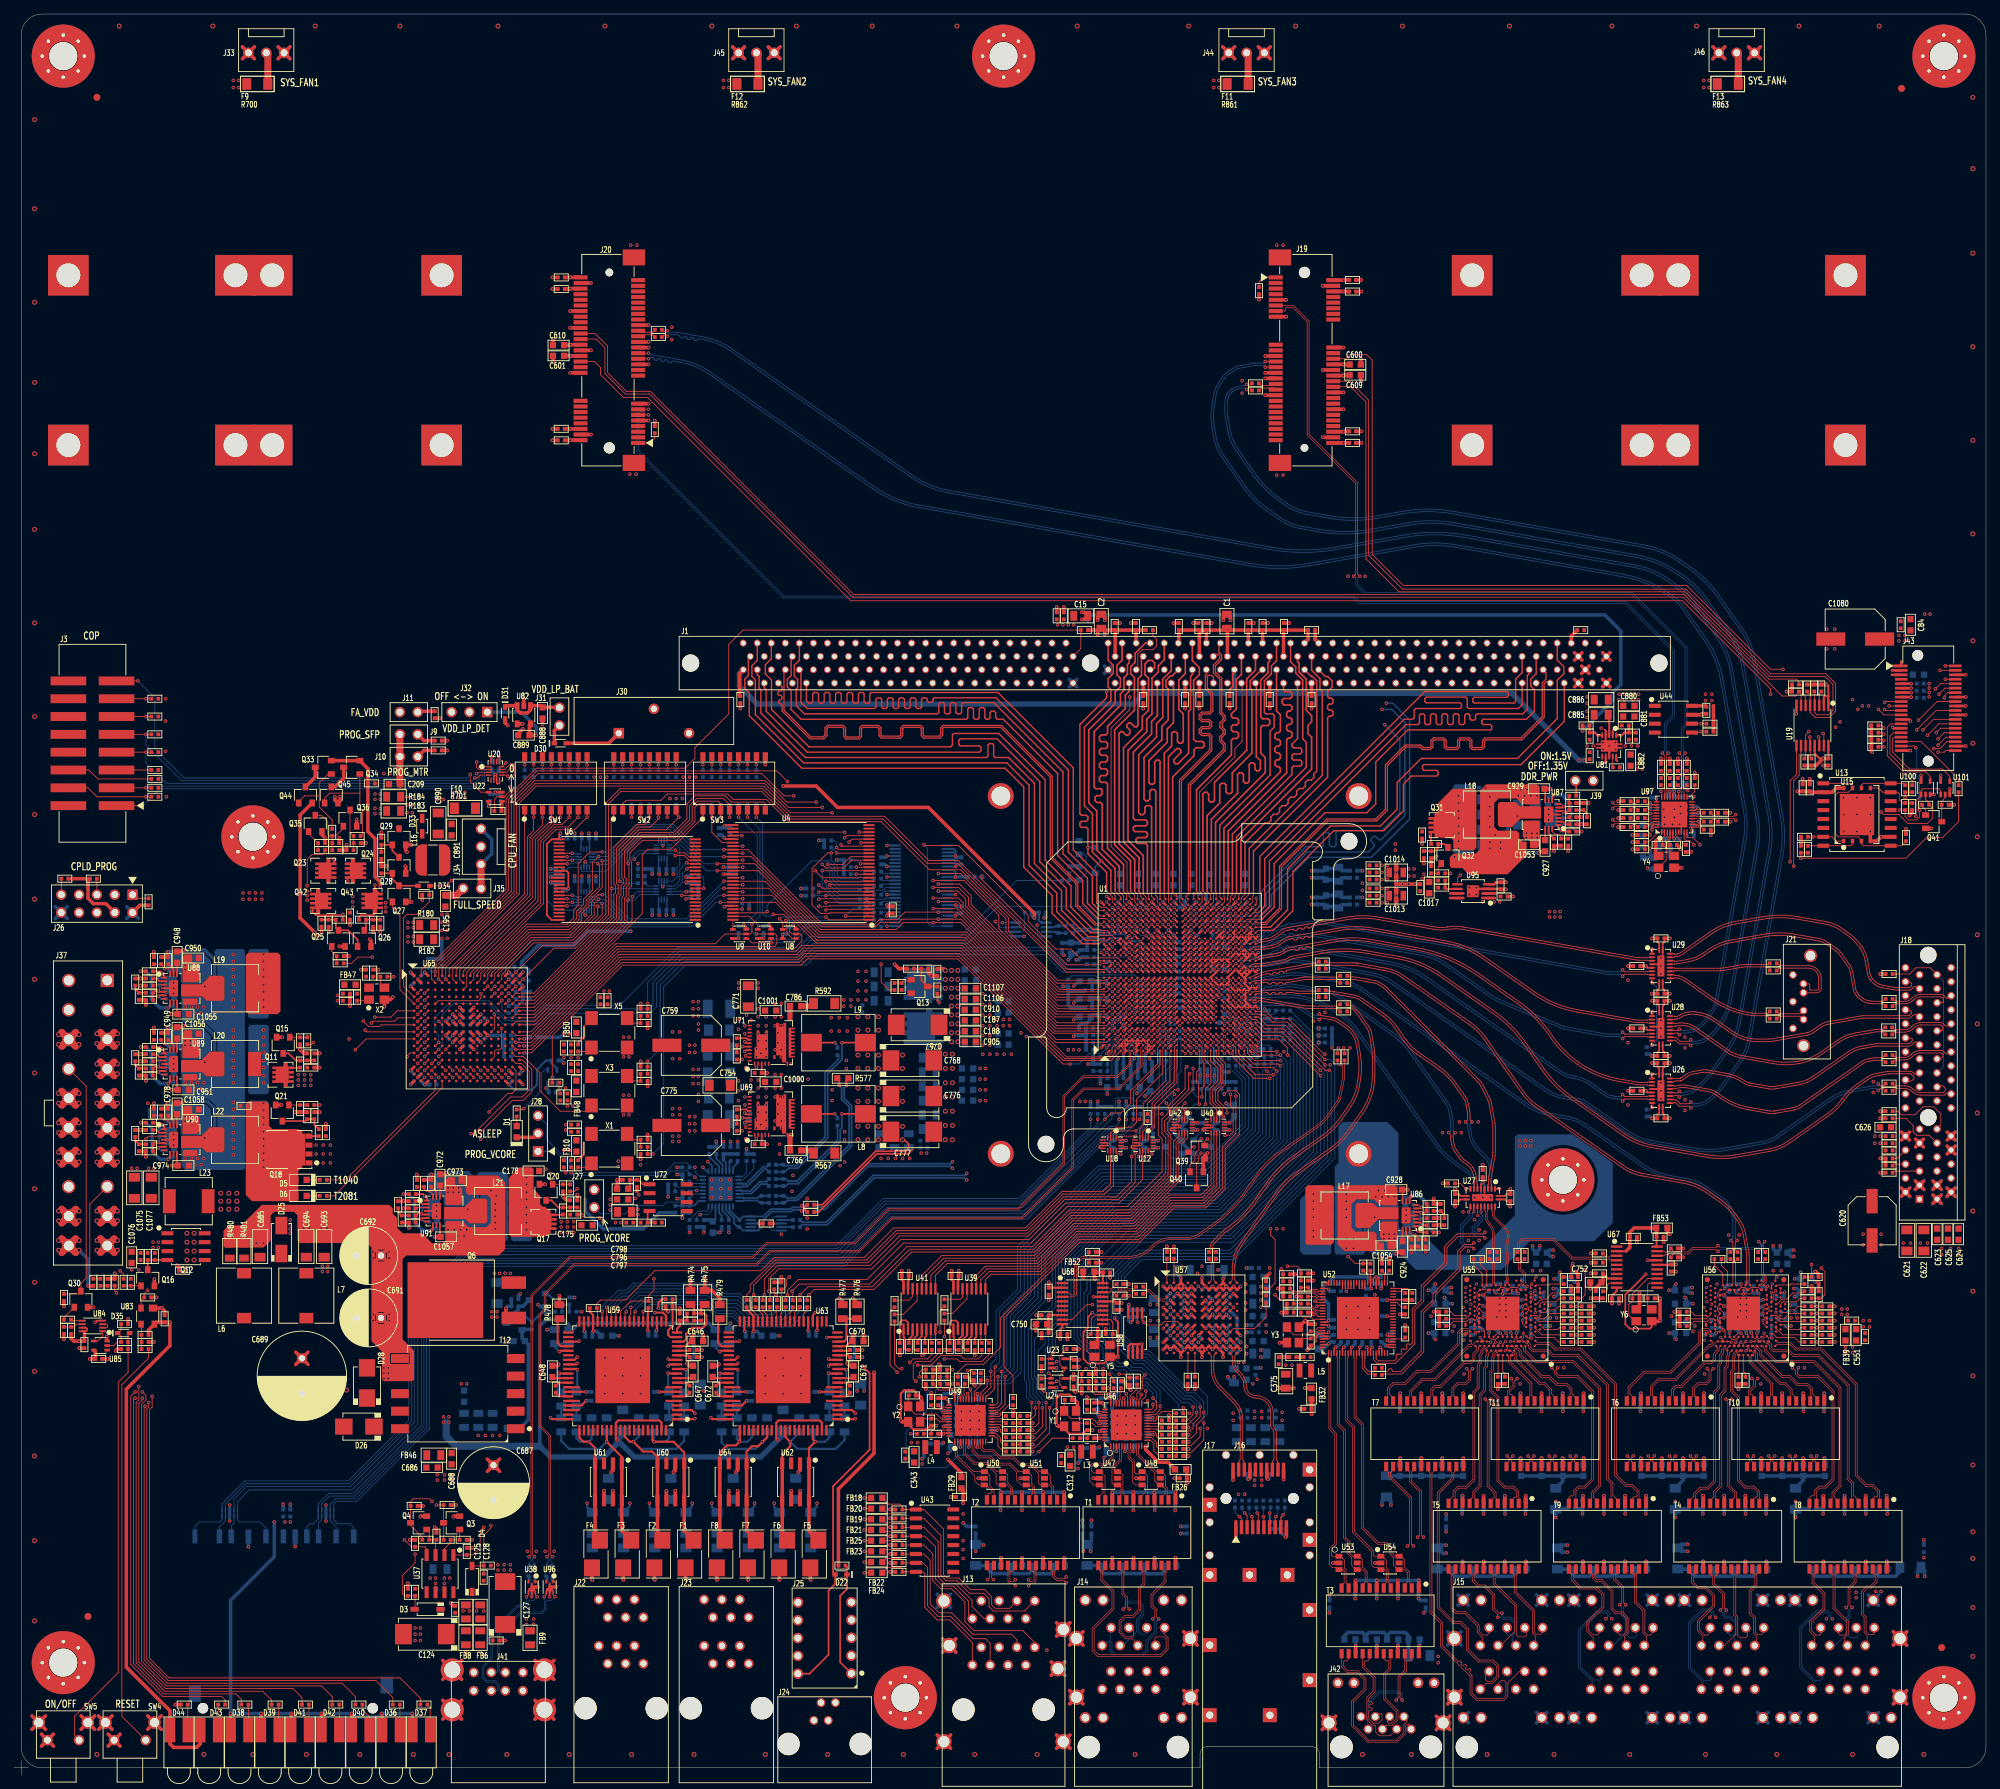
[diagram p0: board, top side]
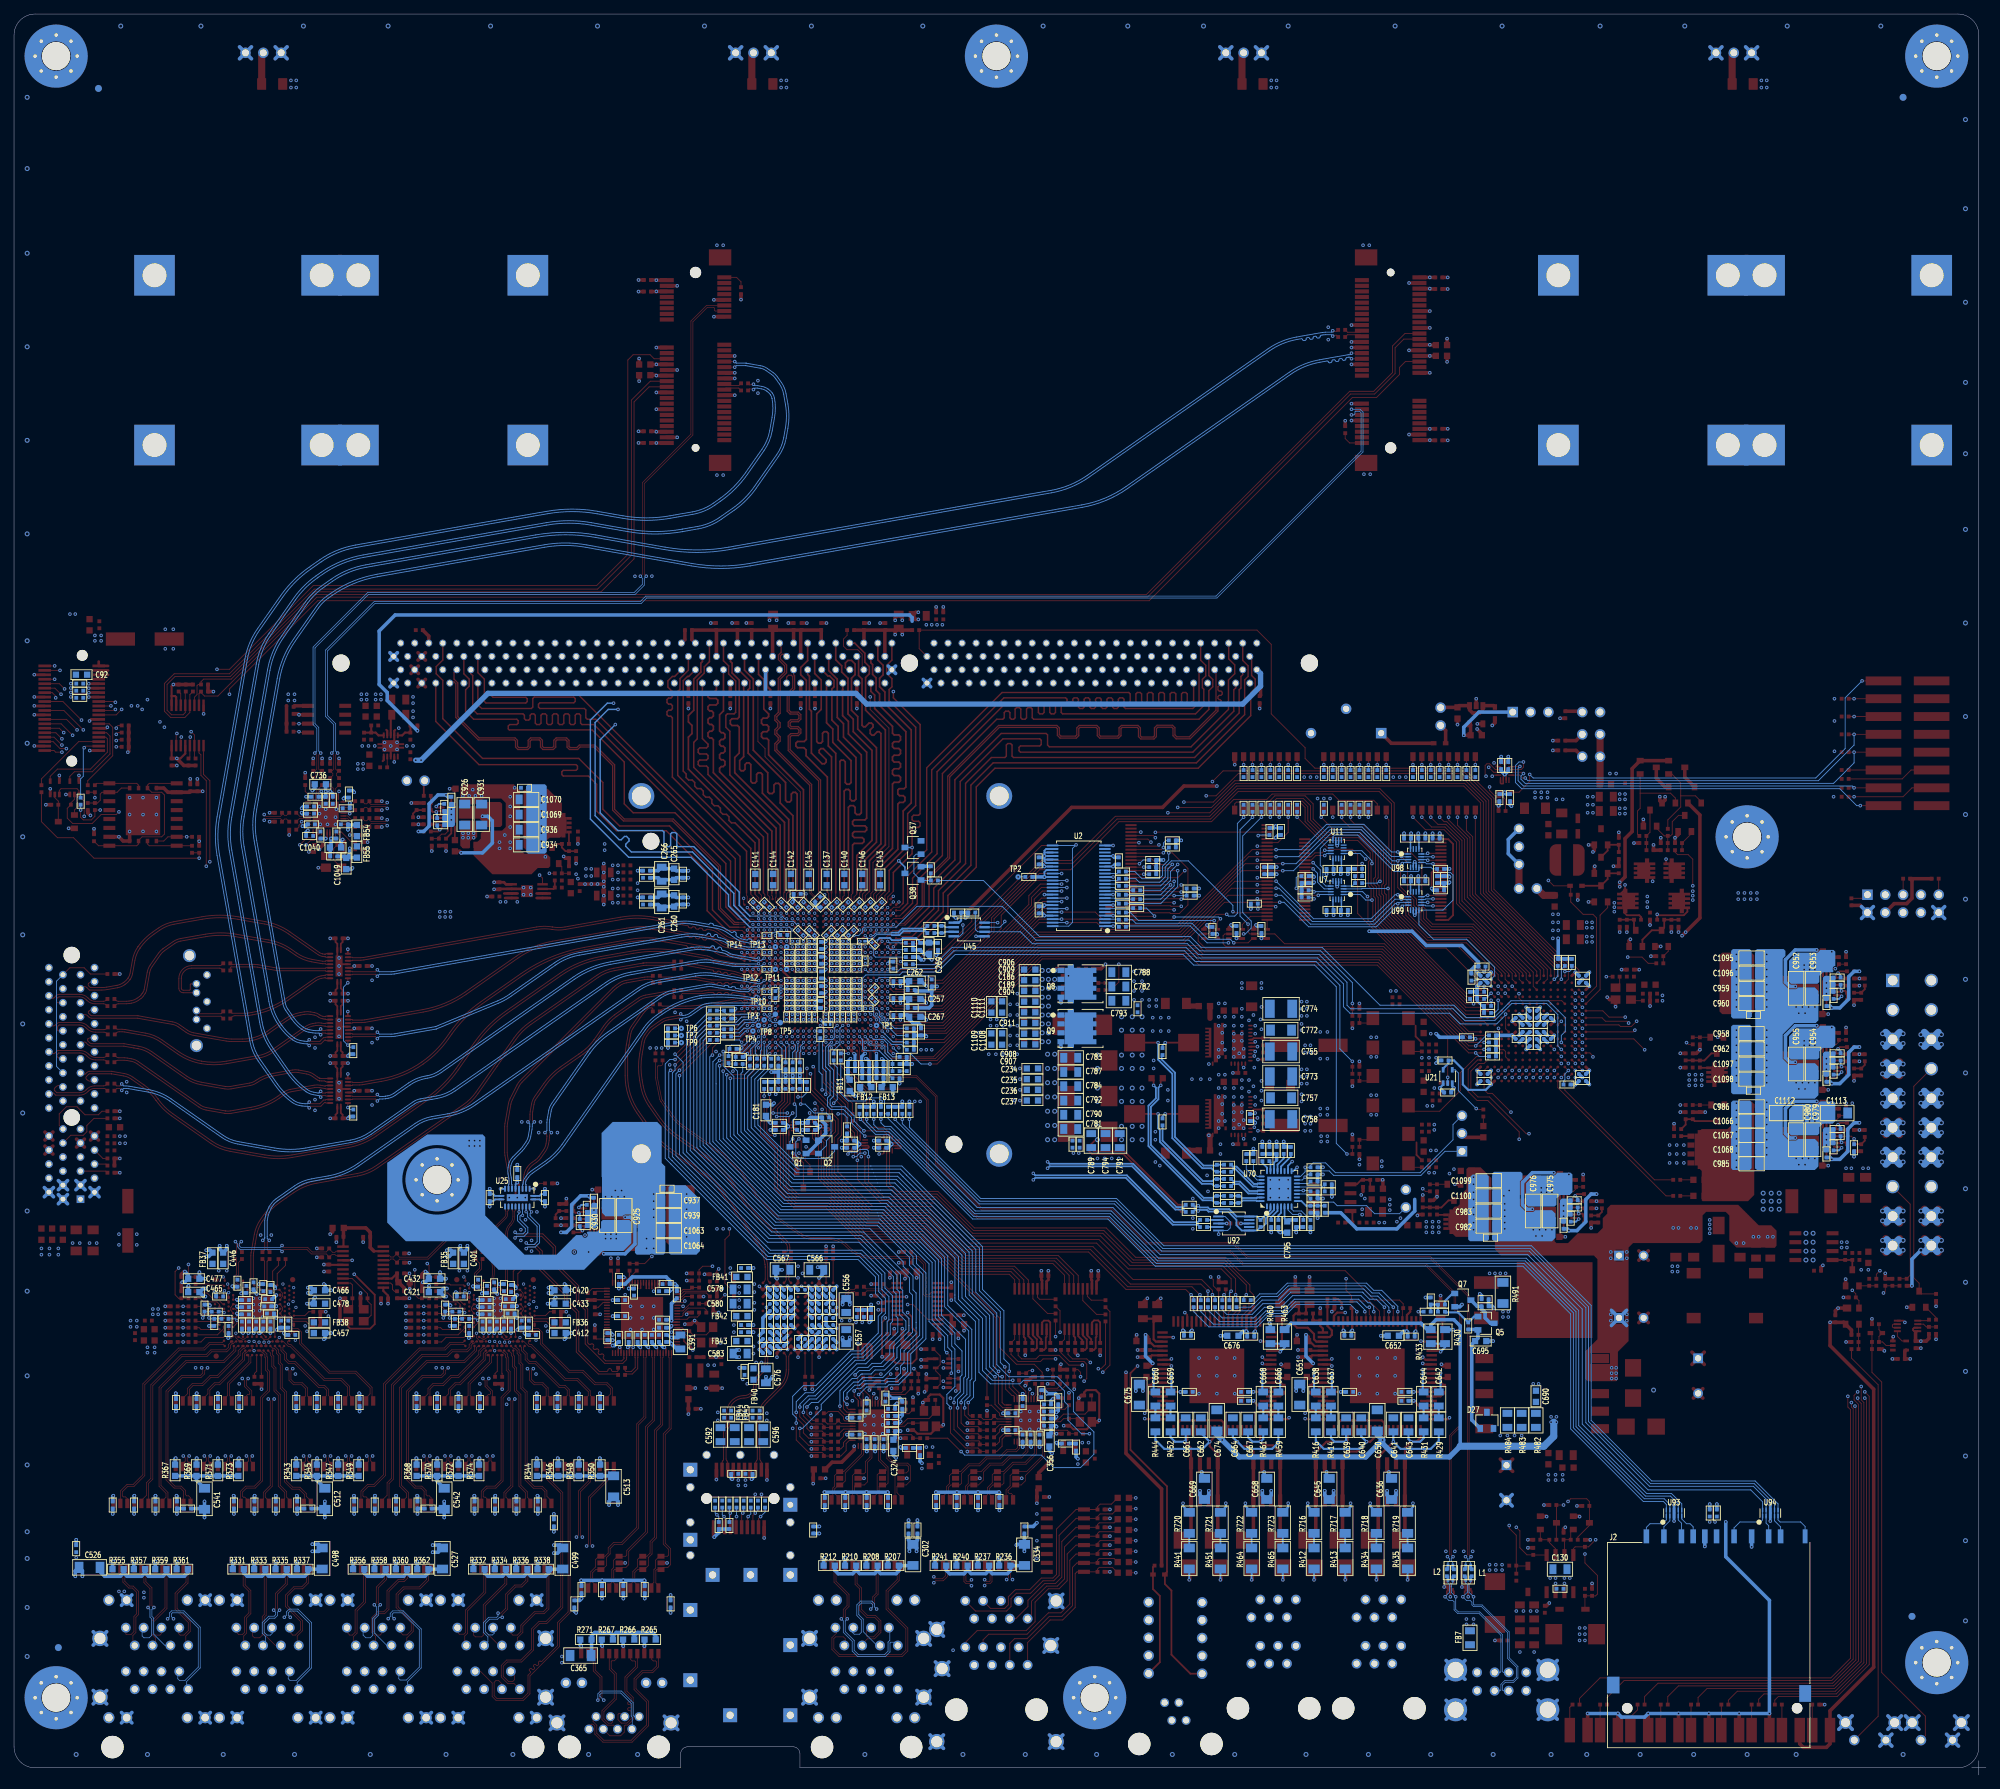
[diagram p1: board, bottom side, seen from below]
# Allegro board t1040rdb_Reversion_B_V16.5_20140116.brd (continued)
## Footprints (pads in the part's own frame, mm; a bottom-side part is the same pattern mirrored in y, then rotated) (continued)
QFN_P040_D040_B260X180_16
  custom 0.05x0.05 smd: 1(-0.9,0.6) 2(-0.9,0.2) 3(-0.9,-0.2) 4(-0.9,-0.6) 5(-0.6,-1.3) 6(-0.2,-1.3) 7(0.2,-1.3) 8(0.6,-1.3) 9(0.9,-0.6) 10(0.9,-0.2) 11(0.9,0.2) 12(0.9,0.6) 13(0.6,1.3) 14(0.2,1.3) 15(-0.2,1.3) 16(-0.6,1.3)
QFN_P040_D040_B500_40_E370
  custom 0.05x0.05 smd: 1(-2.5,1.8) 2(-2.5,1.4) 3(-2.5,1) 4(-2.5,0.6) 5(-2.5,0.2) 6(-2.5,-0.2) 7(-2.5,-0.6) 8(-2.5,-1) 9(-2.5,-1.4) 10(-2.5,-1.8) 11(-1.8,-2.5) 12(-1.4,-2.5) 13(-1,-2.5) 14(-0.6,-2.5) 15(-0.2,-2.5) 16(0.2,-2.5) 17(0.6,-2.5) 18(1,-2.5) 19(1.4,-2.5) 20(1.8,-2.5) 21(2.5,-1.8) 22(2.5,-1.4) 23(2.5,-1) 24(2.5,-0.6) 25(2.5,-0.2) 26(2.5,0.2) 27(2.5,0.6) 28(2.5,1) 29(2.5,1.4) 30(2.5,1.8) 31(1.8,2.5) 32(1.4,2.5) 33(1,2.5) 34(0.6,2.5) 35(0.2,2.5) 36(-0.2,2.5) 37(-0.6,2.5) 38(-1,2.5) 39(-1.4,2.5) 40(-1.8,2.5)
  rect 3.7x3.7 smd: 41(0,0)
QFN_P040_D040_B600_48_E440
  custom 0.05x0.05 smd: 1(-3,2.2) 2(-3,1.8) 3(-3,1.4) 4(-3,1) 5(-3,0.6) 6(-3,0.2) 7(-3,-0.2) 8(-3,-0.6) 9(-3,-1) 10(-3,-1.4) 11(-3,-1.8) 12(-3,-2.2) 13(-2.2,-3) 14(-1.8,-3) 15(-1.4,-3) 16(-1,-3) 17(-0.6,-3) 18(-0.2,-3) 19(0.2,-3) 20(0.6,-3) 21(1,-3) 22(1.4,-3) 23(1.8,-3) 24(2.2,-3) 25(3,-2.2) 26(3,-1.8) 27(3,-1.4) 28(3,-1) 29(3,-0.6) 30(3,-0.2) 31(3,0.2) 32(3,0.6) 33(3,1) 34(3,1.4) 35(3,1.8) 36(3,2.2) 37(2.2,3) 38(1.8,3) 39(1.4,3) 40(1,3) 41(0.6,3) 42(0.2,3) 43(-0.2,3) 44(-0.6,3) 45(-1,3) 46(-1.4,3) 47(-1.8,3) 48(-2.2,3)
  rect 4.4x4.4 smd: 49(0,0)
QFN_P040_D040_B1000_88_E600
  custom 0.05x0.05 smd: 1(-5,4.2) 2(-5,3.8) 3(-5,3.4) 4(-5,3) 5(-5,2.6) 6(-5,2.2) 7(-5,1.8) 8(-5,1.4) 9(-5,1) 10(-5,0.6) 11(-5,0.2) 12(-5,-0.2) 13(-5,-0.6) 14(-5,-1) 15(-5,-1.4) 16(-5,-1.8) 17(-5,-2.2) 18(-5,-2.6) 19(-5,-3) 20(-5,-3.4) 21(-5,-3.8) 22(-5,-4.2) 23(-4.2,-5) 24(-3.8,-5) 25(-3.4,-5) 26(-3,-5) 27(-2.6,-5) 28(-2.2,-5) 29(-1.8,-5) 30(-1.4,-5) 31(-1,-5) 32(-0.6,-5) 33(-0.2,-5) 34(0.2,-5) 35(0.6,-5) 36(1,-5) 37(1.4,-5) 38(1.8,-5) 39(2.2,-5) 40(2.6,-5) 41(3,-5) 42(3.4,-5) 43(3.8,-5) 44(4.2,-5) 45(5,-4.2) 46(5,-3.8) 47(5,-3.4) 48(5,-3) 49(5,-2.6) 50(5,-2.2) 51(5,-1.8) 52(5,-1.4) 53(5,-1) 54(5,-0.6) 55(5,-0.2) 56(5,0.2) 57(5,0.6) 58(5,1) 59(5,1.4) 60(5,1.8) 61(5,2.2) 62(5,2.6) 63(5,3) 64(5,3.4) 65(5,3.8) 66(5,4.2) 67(4.2,5) 68(3.8,5) 69(3.4,5) 70(3,5) 71(2.6,5) 72(2.2,5) 73(1.8,5) 74(1.4,5) 75(1,5) 76(0.6,5) 77(0.2,5) 78(-0.2,5) 79(-0.6,5) 80(-1,5) 81(-1.4,5) 82(-1.8,5) 83(-2.2,5) 84(-2.6,5) 85(-3,5) 86(-3.4,5) 87(-3.8,5) 88(-4.2,5)
  rect 6x6 smd: 89(0,0)
QFN_P050_D040_B450X250_20_E3X1
  custom 0.07x0.07 smd: 1(-0.25,2.25) 2(-1.25,1.75) 3(-1.25,1.25) 4(-1.25,0.75) 5(-1.25,0.25) 6(-1.25,-0.25) 7(-1.25,-0.75) 8(-1.25,-1.25) 9(-1.25,-1.75) 10(-0.25,-2.25) 11(0.25,-2.25) 12(1.25,-1.75) 13(1.25,-1.25) 14(1.25,-0.75) 15(1.25,-0.25) 16(1.25,0.25) 17(1.25,0.75) 18(1.25,1.25) 19(1.25,1.75) 20(0.25,2.25)
  rect 1x3 smd: 21(0,0)
QFN_P050_D040_B500_32_E345
  custom 0.07x0.07 smd: 1(-2.5,1.75) 2(-2.5,1.25) 3(-2.5,0.75) 4(-2.5,0.25) 5(-2.5,-0.25) 6(-2.5,-0.75) 7(-2.5,-1.25) 8(-2.5,-1.75) 9(-1.75,-2.5) 10(-1.25,-2.5) 11(-0.75,-2.5) 12(-0.25,-2.5) 13(0.25,-2.5) 14(0.75,-2.5) 15(1.25,-2.5) 16(1.75,-2.5) 17(2.5,-1.75) 18(2.5,-1.25) 19(2.5,-0.75) 20(2.5,-0.25) 21(2.5,0.25) 22(2.5,0.75) 23(2.5,1.25) 24(2.5,1.75) 25(1.75,2.5) 26(1.25,2.5) 27(0.75,2.5) 28(0.25,2.5) 29(-0.25,2.5) 30(-0.75,2.5) 31(-1.25,2.5) 32(-1.75,2.5)
  rect 3.45x3.45 smd: 33(0,0)
QFN_SUPIRBUCK_4X5
  custom 0.07x0.07 smd: 1(-1.5,-2.5) 2(-1,-2.5) 3(-0.5,-2.5) 4(0,-2.5) 5(0.5,-2.5) 6(1,-2.5) 7(1.5,-2.5) 8(2,-1.65) 9(2,-1.15) 10(2,-0.65) 14(-2,-0.65) 15(-2,-1.15) 16(-2,-1.65)
  rect 0.92x2.07 smd: 11(1.9,1.205)
  rect 1.74x2.94 smd: 12(0.29,1.39)
  rect 1.49x2.07 smd: 13(-1.615,1.205)
  custom 0.33x0.33 smd: 17(0,-1.15)
QFN_VSC8514
  rect 4.8x4.8 smd: 139(0.325,-0.65)
  round 0.76 smd: A1(-5.45,5.45) A4(-5.45,-5.45) A5(5.45,-5.45) A6(5.45,5.45)
  round 0.35 smd: A2(-5.626,-1.3) A3(-5.626,-1.95) A8(0.325,5.301) A9(-0.325,5.301) B1(-4.976,1.625) B2(-4.976,0.975) B3(-4.976,-0.325) B4(-4.976,-0.975) B5(-4.976,-1.625) B6(-4.976,-2.925) B8(-4.976,-4.225) B9(5.626,-3.575) B10(5.626,-2.925) B11(5.627,-0.975) B12(5.627,-0.325) B15(2.6,4.651) B16(1.95,4.651) B17(1.3,4.651) B20(-1.3,4.651) C1(-4.326,3.25) C2(-4.326,1.95) C4(-4.326,0.65) C5(-4.326,0) C6(-4.326,-1.3) C7(-4.326,-1.95) C8(-4.326,-2.6) C9(-4.326,-3.25) C10(-4.327,-4.55) C11(-4.225,-5.302) C12(-2.275,-5.302) C13(-1.625,-5.302) C14(4.976,-4.55) C15(4.976,-3.9) C16(4.976,-3.25) C17(4.976,-2.6) C18(4.976,-1.3) C19(4.976,-0.65) C20(4.976,0.65) C21(4.976,1.95) C22(4.976,2.6) C23(4.976,3.25) C24(4.225,4.001) C25(3.575,4.001) C26(2.925,4.001) C27(2.275,4.001) C30(0.325,4.001) C34(-2.275,4.001) C35(-2.925,4.001) C36(-4.225,4.001) D1(-3.676,2.275) D2(-3.676,1.625) D3(-3.676,0.975) D4(-3.676,0.325) D5(-3.676,-0.325) D6(-3.676,-0.975) D7(-3.676,-1.625) D10(-3.676,-4.225) D11(-2.6,-4.652) D12(-1.95,-4.652) D13(-0.65,-4.652) D14(0,-4.652) D15(1.3,-4.652) D16(1.95,-4.652) D17(2.6,-4.652) D18(3.25,-4.652) D19(4.327,-4.225) D20(4.327,-3.575) D22(4.327,-2.275) D23(4.327,-1.625) D24(4.327,-0.975) D25(4.327,-0.325) D26(4.327,0.325) D28(4.327,1.625) D29(3.9,3.351) D31(2.6,3.351) D32(-1.3,3.351) D34(-2.6,3.351) E1(-3.027,2.6) E2(-3.027,1.3) E5(-3.026,-0.65) E6(-3.026,-1.3) E7(-3.026,-1.95) E8(-3.026,-2.6) E9(-3.026,-3.25) E10(-2.925,-4.002) E12(-1.625,-4.002) E13(-0.975,-4.002) E15(0.325,-4.002) E17(1.625,-4.002) E19(3.575,-4.002) E21(3.676,-2.6) E22(3.676,-1.95) E23(3.676,-1.3) E24(3.676,-0.65) E25(3.676,0) E27(3.676,1.3) E28(3.676,1.95) E29(2.925,2.702) E30(2.275,2.702) E31(1.625,2.702) E32(0.975,2.702) E33(0.325,2.702) E34(-0.325,2.702) E35(-0.975,2.702) E36(-1.625,2.702) E37(-2.275,2.702)
  oval 0.5x0.35 smd: A7(0.975,5.301) A10(-0.975,5.301) B19(-0.65,4.651) C28(1.625,4.001) C29(0.975,4.001) C31(-0.325,4.001) C32(-0.975,4.001) C33(-1.625,4.001) D35(-3.25,3.351) E11(-2.275,-4.002) E14(-0.325,-4.002) E16(0.975,-4.002)
  oval 0.35x0.5 smd: B7(-4.976,-3.575) C3(-4.326,1.3) D8(-3.676,-2.275) D9(-3.676,-2.925) D21(4.327,-2.925) E3(-3.027,0.65) E4(-3.027,0) E20(3.676,-3.25)
  oval 0.35x0.65 smd: B13(5.627,0.975) B14(5.627,2.275) D27(4.327,0.975) E26(3.676,0.65)
  oval 0.65x0.35 smd: B18(0.65,4.651) D30(3.25,3.351) D33(-1.95,3.351) E18(2.275,-4.002)
QFP_P065_80_E780
  rect 1.5x0.35 smd: 1(-7.75,6.175) 2(-7.75,5.525) 3(-7.75,4.875) 4(-7.75,4.225) 5(-7.75,3.575) 6(-7.75,2.925) 7(-7.75,2.275) 8(-7.75,1.625) 9(-7.75,0.975) 10(-7.75,0.325) 11(-7.75,-0.325) 12(-7.75,-0.975) 13(-7.75,-1.625) 14(-7.75,-2.275) 15(-7.75,-2.925) 16(-7.75,-3.575) 17(-7.75,-4.225) 18(-7.75,-4.875) 19(-7.75,-5.525) 20(-7.75,-6.175) 41(7.75,-6.175) 42(7.75,-5.525) 43(7.75,-4.875) 44(7.75,-4.225) 45(7.75,-3.575) 46(7.75,-2.925) 47(7.75,-2.275) 48(7.75,-1.625) 49(7.75,-0.975) 50(7.75,-0.325) 51(7.75,0.325) 52(7.75,0.975) 53(7.75,1.625) 54(7.75,2.275) 55(7.75,2.925) 56(7.75,3.575) 57(7.75,4.225) 58(7.75,4.875) 59(7.75,5.525) 60(7.75,6.175)
  rect 0.35x1.5 smd: 21(-6.175,-7.75) 22(-5.525,-7.75) 23(-4.875,-7.75) 24(-4.225,-7.75) 25(-3.575,-7.75) 26(-2.925,-7.75) 27(-2.275,-7.75) 28(-1.625,-7.75) 29(-0.975,-7.75) 30(-0.325,-7.75) 31(0.325,-7.75) 32(0.975,-7.75) 33(1.625,-7.75) 34(2.275,-7.75) 35(2.925,-7.75) 36(3.575,-7.75) 37(4.225,-7.75) 38(4.875,-7.75) 39(5.525,-7.75) 40(6.175,-7.75) 61(6.175,7.75) 62(5.525,7.75) 63(4.875,7.75) 64(4.225,7.75) 65(3.575,7.75) 66(2.925,7.75) 67(2.275,7.75) 68(1.625,7.75) 69(0.975,7.75) 70(0.325,7.75) 71(-0.325,7.75) 72(-0.975,7.75) 73(-1.625,7.75) 74(-2.275,7.75) 75(-2.925,7.75) 76(-3.575,7.75) 77(-4.225,7.75) 78(-4.875,7.75) 79(-5.525,7.75) 80(-6.175,7.75)
  rect 7.8x7.8 smd: 81(0,0)
RELAY_TQ2
  round 1.5 hole 1: 1(-3.81,5.04) 2(-3.81,2.5) 3(-3.81,-0.04) 4(-3.81,-2.58) 5(-3.81,-5.12) 6(3.81,-5.08) 7(3.81,-2.54) 8(3.81,0) 9(3.81,2.54) 10(3.81,5.08)
SC70_5
  rect 0.4x0.8 smd: 1(-0.65,-0.95) 2(0,-0.95) 3(0.65,-0.95) 4(0.65,0.95) 5(-0.65,0.95)
SMA
  rect 2.5x1.7 smd: 1(-2,0) 2(2,0)
SMB
  rect 2.5x2.3 smd: 1(-2.15,0) 2(2.15,0)
SO_8
  rect 1.7x0.6 smd: 1(-2.65,1.905) 2(-2.65,0.635) 3(-2.65,-0.635) 4(-2.65,-1.905) 5(2.65,-1.905) 6(2.65,-0.635) 7(2.65,0.635) 8(2.65,1.905)
SO_8_FL
  rect 0.75x1 smd: 1(-1.905,-2.795) 2(-0.635,-2.795) 3(0.635,-2.795) 4(1.905,-2.795)
  custom 1.132x1.132 smd: 5(0,0)
SO_16
  rect 1.7x0.6 smd: 1(-2.65,4.445) 2(-2.65,3.175) 3(-2.65,1.905) 4(-2.65,0.635) 5(-2.65,-0.635) 6(-2.65,-1.905) 7(-2.65,-3.175) 8(-2.65,-4.445) 9(2.65,-4.445) 10(2.65,-3.175) 11(2.65,-1.905) 12(2.65,-0.635) 13(2.65,0.635) 14(2.65,1.905) 15(2.65,3.175) 16(2.65,4.445)
SO_16L
  rect 1.7x0.6 smd: 1(-4.8,4.445) 2(-4.8,3.175) 3(-4.8,1.905) 4(-4.8,0.635) 5(-4.8,-0.635) 6(-4.8,-1.905) 7(-4.8,-3.175) 8(-4.8,-4.445) 9(4.8,-4.445) 10(4.8,-3.175) 11(4.8,-1.905) 12(4.8,-0.635) 13(4.8,0.635) 14(4.8,1.905) 15(4.8,3.175) 16(4.8,4.445)
SOD123
  rect 1.2x0.7 smd: 1(-1.85,0) 2(1.85,0)
SOD323
  rect 1.35x0.65 smd: 1(-1.1,0) 2(1.1,0)
SOD523
  rect 0.8x0.6 smd: 1(-0.85,0) 2(0.85,0)
SOT23
  rect 0.8x1 smd: 1(-0.95,-1.15) 2(0.95,-1.15) 3(0,1.15)
SOT23_5
  rect 0.7x1 smd: 1(-0.95,-1.3) 2(0,-1.3) 3(0.95,-1.3) 4(0.95,1.3) 5(-0.95,1.3)
SOT23_6
  rect 0.7x1 smd: 1(-0.95,-1.3) 2(0,-1.3) 3(0.95,-1.3) 4(0.95,1.3) 5(0,1.3) 6(-0.95,1.3)
SOT143
  rect 1.2x1 smd: 1(-0.75,-1.15)
  rect 0.8x1 smd: 2(0.95,-1.15) 3(0.95,1.15) 4(-0.95,1.15)
TO263
  rect 1.8x3.5 smd: 1(-2.54,-6.7) 2(2.5,-6.7)
  rect 10.8x10.8 smd: 3(0,3.05)
TP
  round 0.8 smd: 1(0,0)
TSOP1_48
  rect 1.6x0.28 smd: 1(-9.7,5.75) 2(-9.7,5.25) 3(-9.7,4.75) 4(-9.7,4.25) 5(-9.7,3.75) 6(-9.7,3.25) 7(-9.7,2.75) 8(-9.7,2.25) 9(-9.7,1.75) 10(-9.7,1.25) 11(-9.7,0.75) 12(-9.7,0.25) 13(-9.7,-0.25) 14(-9.7,-0.75) 15(-9.7,-1.25) 16(-9.7,-1.75) 17(-9.7,-2.25) 18(-9.7,-2.75) 19(-9.7,-3.25) 20(-9.7,-3.75) 21(-9.7,-4.25) 22(-9.7,-4.75) 23(-9.7,-5.25) 24(-9.7,-5.75) 25(9.7,-5.75) 26(9.7,-5.25) 27(9.7,-4.75) 28(9.7,-4.25) 29(9.7,-3.75) 30(9.7,-3.25) 31(9.7,-2.75) 32(9.7,-2.25) 33(9.7,-1.75) 34(9.7,-1.25) 35(9.7,-0.75) 36(9.7,-0.25) 37(9.7,0.25) 38(9.7,0.75) 39(9.7,1.25) 40(9.7,1.75) 41(9.7,2.25) 42(9.7,2.75) 43(9.7,3.25) 44(9.7,3.75) 45(9.7,4.25) 46(9.7,4.75) 47(9.7,5.25) 48(9.7,5.75)
TSOP1_56
  rect 1.6x0.28 smd: 1(-9.7,6.75) 2(-9.7,6.25) 3(-9.7,5.75) 4(-9.7,5.25) 5(-9.7,4.75) 6(-9.7,4.25) 7(-9.7,3.75) 8(-9.7,3.25) 9(-9.7,2.75) 10(-9.7,2.25) 11(-9.7,1.75) 12(-9.7,1.25) 13(-9.7,0.75) 14(-9.7,0.25) 15(-9.7,-0.25) 16(-9.7,-0.75) 17(-9.7,-1.25) 18(-9.7,-1.75) 19(-9.7,-2.25) 20(-9.7,-2.75) 21(-9.7,-3.25) 22(-9.7,-3.75) 23(-9.7,-4.25) 24(-9.7,-4.75) 25(-9.7,-5.25) 26(-9.7,-5.75) 27(-9.7,-6.25) 28(-9.7,-6.75) 29(9.7,-6.75) 30(9.7,-6.25) 31(9.7,-5.75) 32(9.7,-5.25) 33(9.7,-4.75) 34(9.7,-4.25) 35(9.7,-3.75) 36(9.7,-3.25) 37(9.7,-2.75) 38(9.7,-2.25) 39(9.7,-1.75) 40(9.7,-1.25) 41(9.7,-0.75) 42(9.7,-0.25) 43(9.7,0.25) 44(9.7,0.75) 45(9.7,1.25) 46(9.7,1.75) 47(9.7,2.25) 48(9.7,2.75) 49(9.7,3.25) 50(9.7,3.75) 51(9.7,4.25) 52(9.7,4.75) 53(9.7,5.25) 54(9.7,5.75) 55(9.7,6.25) 56(9.7,6.75)
TSSOP_8
  rect 1.65x0.35 smd: 1(-2.875,0.975) 2(-2.875,0.325) 3(-2.875,-0.325) 4(-2.875,-0.975) 5(2.875,-0.975) 6(2.875,-0.325) 7(2.875,0.325) 8(2.875,0.975)
TSSOP_16
  rect 1.65x0.35 smd: 1(-2.875,2.275) 2(-2.875,1.625) 3(-2.875,0.975) 4(-2.875,0.325) 5(-2.875,-0.325) 6(-2.875,-0.975) 7(-2.875,-1.625) 8(-2.875,-2.275) 9(2.875,-2.275) 10(2.875,-1.625) 11(2.875,-0.975) 12(2.875,-0.325) 13(2.875,0.325) 14(2.875,0.975) 15(2.875,1.625) 16(2.875,2.275)
TSSOP_20
  rect 1.65x0.35 smd: 1(-2.875,2.925) 2(-2.875,2.275) 3(-2.875,1.625) 4(-2.875,0.975) 5(-2.875,0.325) 6(-2.875,-0.325) 7(-2.875,-0.975) 8(-2.875,-1.625) 9(-2.875,-2.275) 10(-2.875,-2.925) 11(2.875,-2.925) 12(2.875,-2.275) 13(2.875,-1.625) 14(2.875,-0.975) 15(2.875,-0.325) 16(2.875,0.325) 17(2.875,0.975) 18(2.875,1.625) 19(2.875,2.275) 20(2.875,2.925)
TSSOP_48W
  rect 1.65x0.28 smd: 1(-3.725,5.75) 2(-3.725,5.25) 3(-3.725,4.75) 4(-3.725,4.25) 5(-3.725,3.75) 6(-3.725,3.25) 7(-3.725,2.75) 8(-3.725,2.25) 9(-3.725,1.75) 10(-3.725,1.25) 11(-3.725,0.75) 12(-3.725,0.25) 13(-3.725,-0.25) 14(-3.725,-0.75) 15(-3.725,-1.25) 16(-3.725,-1.75) 17(-3.725,-2.25) 18(-3.725,-2.75) 19(-3.725,-3.25) 20(-3.725,-3.75) 21(-3.725,-4.25) 22(-3.725,-4.75) 23(-3.725,-5.25) 24(-3.725,-5.75) 25(3.725,-5.75) 26(3.725,-5.25) 27(3.725,-4.75) 28(3.725,-4.25) 29(3.725,-3.75) 30(3.725,-3.25) 31(3.725,-2.75) 32(3.725,-2.25) 33(3.725,-1.75) 34(3.725,-1.25) 35(3.725,-0.75) 36(3.725,-0.25) 37(3.725,0.25) 38(3.725,0.75) 39(3.725,1.25) 40(3.725,1.75) 41(3.725,2.25) 42(3.725,2.75) 43(3.725,3.25) 44(3.725,3.75) 45(3.725,4.25) 46(3.725,4.75) 47(3.725,5.25) 48(3.725,5.75)
TVS_LLP75_6L
  rect 0.55x0.25 smd: 1(-0.775,0.5) 3(-0.775,-0.5) 4(0.775,-0.5) 5(0.775,0) 6(0.775,0.5)
  custom 0.25x0.25 smd: 2(0,0)
TVS_SLP2710P8
  rect 0.2x0.675 smd: 1(-1.1,-0.438) 2(-0.6,-0.438) 3(0.6,-0.438) 4(1.1,-0.438) 5(1.1,0.438) 6(0.6,0.438) 7(-0.6,0.438) 8(-1.1,0.438)
  rect 0.4x1.55 smd: 9(0,0)
U8
  rect 1x0.28 smd: 1(-1.45,0.75) 2(-1.45,0.25) 3(-1.45,-0.25) 4(-1.45,-0.75) 5(1.45,-0.75) 6(1.45,-0.25) 7(1.45,0.25) 8(1.45,0.75)
U8_FL
  rect 0.4x0.76 smd: 1(-0.975,-1.52) 2(-0.325,-1.52) 3(0.325,-1.52) 4(0.975,-1.52)
  custom 0.588x0.588 smd: 5(0,0)
unnamed
  round 2.4 hole 2.4 unplated: (-19.05,24.13) (24.13,-19.05)
WSON_8
  rect 0.65x0.5 smd: 1(-3.775,1.905) 2(-3.775,0.635) 3(-3.775,-0.635) 4(-3.775,-1.905) 5(3.775,-1.905) 6(3.775,-0.635) 7(3.775,0.635) 8(3.775,1.905)
  rect 5.9x4.9 smd: 9(0,0)
XFMR_C8140
  rect 2.54x1.3 smd: 1(-8.25,5) 2(-8.25,2.5) 3(-8.25,0) 4(-8.25,-2.5) 5(-8.25,-5) 6(8.25,-5) 7(8.25,-2.5) 8(8.25,0) 9(8.25,2.5) 10(8.25,5)

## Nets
1V0: C420.1 C421.1 C422.1 C423.1 C424.1 C425.1 C465.1 C466.1 C467.1 C468.1 C469.1 C470.1 C556.1 C557.1 C558.1 C559.1 C560.1 C561.1 C562.1 C563.1 C903.1 C933.1 C935.1 C937.1 C939.1 C1020.1 C1021.1 C1063.1 C1064.1 C1083.1 C1086.1 C1088.1 C1089.1 C1090.1 C1091.1 FB35.1 FB37.1 FB42.1 FB43.1 L17.2 R738.2 U55.E5(VDD1#E5) U55.E7(VDD1#E7) U55.E10(VDD1#E10) U55.E13(VDD1#E13) U55.E15(VDD1#E15) U55.E17(VDD1#E17) U55.E19(VDD1#E19) U55.E21(VDD1#E21) U55.E23(VDD1#E23) U55.E25(VDD1#E25) U56.E5(VDD1#E5) U56.E7(VDD1#E7) U56.E10(VDD1#E10) U56.E13(VDD1#E13) U56.E15(VDD1#E15) U56.E17(VDD1#E17) U56.E19(VDD1#E19) U56.E21(VDD1#E21) U56.E23(VDD1#E23) U56.E25(VDD1#E25) U57.C3(RX2VDD#C3) U57.D6(DIGVDD#D6) U57.E4(TX2VDD#E4) U57.E5(TX2VDD#E5) U57.F6(DIGVDD#F6) U57.F7(DIGVDD#F7) U57.G4(RX2VDD#G4) U57.G8(RX2VDD#G8) U57.H6(RX2VDD#H6) U57.J1(TX2VDD#J1) U57.K3(RX2VDD#K3)
1V0_FA_VL: C222.1 J11.1 R179.2 U1.G18(FA_VL)
1V0_LP: C256.1 C889.1 J32.1 U1.P6(VDD_LP) U82.5(VOUT)
1V0_USB_SVDD: C138.1 C147.1 C148.1 C149.1 FB11.1 U1.K9(USB_SVDD1) U1.K10(USB_SVDD2)
1V0_XG_RX: C583.1 C584.1 C585.1 C587.1 C588.1 C589.1 C902.1 FB43.2 U57.C11(RX1VDD#C11) U57.G5(RX1VDD#G5) U57.G9(RX1VDD#G9) U57.H7(RX1VDD#H7) U57.J10(RX1VDD#J10) U57.K9(RX1VDD#K9)
1V0_XG_TX: C580.1 C581.1 C582.1 C901.1 FB42.2 U57.E8(TX1VDD#E8) U57.E9(TX1VDD#E9) U57.J7(TX1VDD#J7)
1V0A_QSG1: C401.1 C402.1 C403.1 C404.1 C406.1 C407.1 C1082.1 FB35.2 U55.E1(VDD1A#E1) U55.E11(VDD1A#E11) U55.E14(VDD1A#E14) U55.E16(VDD1A#E16) U55.E28(VDD1A#E28) U55.E30(VDD1A#E30) U55.E32(VDD1A#E32) U55.E34(VDD1A#E34) U55.E36(VDD1A#E36)
1V0A_QSG2: C446.1 C447.1 C448.1 C449.1 C450.1 C451.1 C1085.1 FB37.2 U56.E1(VDD1A#E1) U56.E11(VDD1A#E11) U56.E14(VDD1A#E14) U56.E16(VDD1A#E16) U56.E28(VDD1A#E28) U56.E30(VDD1A#E30) U56.E32(VDD1A#E32) U56.E34(VDD1A#E34) U56.E36(VDD1A#E36)
1V0S: C1013.2 C1017.1 C1079.1 R806.2 U95.7(OUT#7) U95.8(OUT#8)
1V5: C609.1 C610.1 C611.1 C612.1 C613.1 C614.1 C959.1 C960.1 C961.1 C964.1 C1095.1 C1096.1 J19.6(1.5V#6) J19.28(1.5V#28) J19.48(1.5V#48) J20.6(1.5V#6) J20.28(1.5V#28) J20.48(1.5V#48) L19.2 R753.2
1V05_EC1_AVDD: C343.1 C344.1 C353.1 C354.1 C355.1 L4.2 R826.2 U49.3(AVDD10#3) U49.9(AVDD10#9) U49.40(AVDD10#40)
1V05_EC1_DVDD: C348.1 C349.1 R826.1 U49.28(DVDD10#28) U49.36(DVDD10#36)
1V05_EC2_AVDD: C312.1 C313.1 C321.1 C322.1 C323.1 L3.2 R824.2 U46.3(AVDD10#3) U46.9(AVDD10#9) U46.40(AVDD10#40)
1V05_EC2_DVDD: C316.1 C317.1 R824.1 U46.28(DVDD10#28) U46.36(DVDD10#36)
1V05_SG_AVDD: C375.1 C376.1 C384.1 C385.1 C386.1 C388.1 C389.1 C390.1 L5.2 R828.2 U52.3(AVDD10#3) U52.9(AVDD10#9) U52.12(AVDD10#12) U52.16(AVDD10#16) U52.23(AVDD10#23) U52.24(REGV15) U52.79(AVDD10#79)
1V05_SG_DVDD: C377.1 C378.1 R828.1 U52.47(DVDD10#47) U52.66(DVDD10#66)
1V8: C566.1 C567.1 C568.1 C569.1 C570.1 C571.1 C586.1 C1018.1 C1019.1 C1092.1 C1093.1 C1094.1 FB40.1 FB41.1 Q11.1 Q11.2 Q11.3 Q44.2(S) R133.1 R134.1 R182.1 R380.2 R381.2 R382.1 R385.1 R387.2 R388.1 R389.2 R656.2 U57.C4(BV1P8RX#C4) U57.C5(BV1P8RX#C5) U57.D7(V2P5#D7) U57.G2(V2P5#G2) U57.H11(V2P5#H11) U57.J4(BV1P8#J4) U57.J5(BV1P8#J5) U58.8(VCC)
1V8_0641_VDD: C1049.1 C1050.1 C1051.1 FB55.2 R839.1 R841.1 U97.16(VDD1.8#16) U97.31(VDD1.8#31)
1V8_0641_VDDA: C736.1 C737.1 R841.2 U97.26(VDDA1.8)
1V8_0641_VDDIO: C1044.1 C1045.1 C1046.1 C1047.1 C1048.1 C1052.1 FB54.1 U97.5(VDDREF1.8) U97.12(VDDIO#12) U97.17(VDDIO#17) U97.27(VDDIO#27) U97.32(VDDIO#32) U97.39(VDDIO#39)
1V8_0641_VDDXTAL: C1040.1 C1041.1 R839.2 U97.4(VDDXTAL1.8)
1V8_MTR: C208.1 J10.1 R178.2 U1.F11(PROG_MTR)
1V8_SFP: C192.1 J9.1 R177.2 U1.F12(PROG_SFP)
1V8_SLP: C698.1 C699.1 C700.1 C735.1 C958.1 C962.1 C963.1 C965.1 C1015.1 C1097.1 C1098.1 C1101.1 FB54.2 FB55.1 L20.2 Q11.5 R184.1 R533.1 R757.2 R829.1 R834.1 R843.1 R844.1 U65.H8(VCCINT#H8) U65.H10(VCCINT#H10) U65.J7(VCCINT#J7) U65.J9(VCCINT#J9) U95.1(IN#1) U95.2(IN#2) U97.11(VDDDIG1.8)
1V8_USB_OVDD: C170.1 C171.1 C172.1 C173.1 C174.1 FB13.1 U1.J9(USB_OVDD1) U1.J10(USB_OVDD2)
1V8_XG_AV: C576.1 C577.1 C899.1 FB40.2 U57.J8(AV1P8#J8) U57.J9(AV1P8#J9)
1V8_XG_RX: C578.1 C579.1 C900.1 FB41.2 U57.C8(AV1P8RX#C8) U57.C9(AV1P8RX#C9)
1V35: C1014.1 Q31.1 Q31.2 Q31.3 R189.2 R192.2 R782.2
1V35_SLP: C1.1 C2.1 C3.1 C4.1 C5.1 C6.1 C7.1 C8.1 C9.1 C10.1 C11.1 C12.1 C13.1 C14.1 C137.1 C139.1 C140.1 C141.1 C142.1 C143.1 C144.1 C145.1 C146.1 C150.1 C151.1 C152.1 C153.1 C154.1 C155.1 C156.1 C157.1 C163.1 C164.1 C165.1 C166.1 C167.1 C168.1 C169.1 C880.1 C881.1 C934.1 C936.1 C940.1 C941.1 C998.1 C999.1 C1069.1 C1070.1 J1.51(VDD#51) J1.54(VDD#54) J1.57(VDD#57) J1.60(VDD#60) J1.62(VDD#62) J1.65(VDD#65) J1.66(VDD#66) J1.69(VDD#69) J1.72(VDD#72) J1.75(VDD#75) J1.78(VDD#78) J1.170(VDD#170) J1.173(VDD#173) J1.176(VDD#176) J1.179(VDD#179) J1.182(VDD#182) J1.183(VDD#183) J1.186(VDD#186) J1.189(VDD#189) J1.191(VDD#191) J1.194(VDD#194) J1.197(VDD#197) L18.2 Q31.5 R1.1 R2.1 R4.1 R695.2 R736.2 U1.AA27(G1VDD17) U1.AD27(G1VDD18) U1.AF27(G1VDD19) U1.D27(G1VDD01) U1.F27(G1VDD02) U1.H27(G1VDD03) U1.K21(G1VDD04) U1.K27(G1VDD05) U1.L21(G1VDD06) U1.M21(G1VDD07) U1.M27(G1VDD08) U1.N21(G1VDD09) U1.P21(G1VDD10) U1.P27(G1VDD11) U1.R21(G1VDD12) U1.T21(G1VDD13) U1.U21(G1VDD14) U1.U27(G1VDD15) U1.W27(G1VDD16) U81.2(VLDOIN)
2V5: C175.1 C176.1 C177.1 C314.1 C315.1 C398.1 C399.1 C432.1 C433.1 C434.1 C435.1 C436.1 C437.1 C477.1 C478.1 C479.1 C480.1 C481.1 C482.1 C549.1 C1084.1 C1087.1 FB36.2 FB38.2 FB39.1 Q17.1 Q17.2 Q17.3 Q43.1 Q43.2 Q43.3 R138.2 R229.2 R230.2 R231.2 R269.1 R270.1 R272.1 R293.2 R294.2 R295.2 R296.1 R314.2 R315.2 R316.2 R317.1 R672.2 R855.2 R856.2 U1.V8(LVDD1) U1.W8(LVDD2) U46.15(DVDD33#15) U46.21(DVDD33#21) U52.34(DVDD33#34) U52.40(DVDD33#40) U55.E3(VDD25#E3) U55.E4(VDD25#E4) U55.E6(VDD25#E6) U55.E8(VDD25#E8) U55.E9(VDDMDIO) U55.E12(VDD25#E12) U55.E18(VDD25#E18) U55.E20(VDD25#E20) U55.E22(VDD25#E22) U55.E24(VDD25#E24) U55.E26(VDD25#E26) U56.E3(VDD25#E3) U56.E4(VDD25#E4) U56.E6(VDD25#E6) U56.E8(VDD25#E8) U56.E9(VDDMDIO) U56.E12(VDD25#E12) U56.E18(VDD25#E18) U56.E20(VDD25#E20) U56.E22(VDD25#E22) U56.E24(VDD25#E24) U56.E26(VDD25#E26)
2V5_LED: C551.1 C552.1 FB39.2 J15.A9 J15.A11 J15.B9 J15.B11 J15.C9 J15.C11 J15.D9 J15.D11 J15.E9 J15.E11 J15.F9 J15.F11 J15.G9 J15.G11 J15.H9(G9) J15.H11(G11)
2V5_SLP: C57.1 C58.1 C178.1 C179.1 C180.1 C346.1 C347.1 C982.1 C983.1 C984.1 C988.1 C1099.1 C1100.1 L21.2 Q17.5 R75.2 R76.2 R77.2 R78.2 R131.1 R132.1 R258.2 R259.2 R260.2 R774.2 U1.T8(L1VDD1) U1.U8(L1VDD2) U23.5(VCC) U24.5(VCC) U49.15(DVDD33#15) U49.21(DVDD33#21)
2V5A_QSG1: C412.1 C413.1 C414.1 C415.1 C416.1 FB36.1 U55.E27(VDD25A#E27) U55.E29(VDD25A#E29) U55.E31(VDD25A#E31) U55.E33(VDD25A#E33) U55.E35(VDD25A#E35) U55.E37(VDD25A#E37)
2V5A_QSG2: C457.1 C458.1 C459.1 C461.1 C462.1 FB38.1 U56.E27(VDD25A#E27) U56.E29(VDD25A#E29) U56.E31(VDD25A#E31) U56.E33(VDD25A#E33) U56.E35(VDD25A#E35) U56.E37(VDD25A#E37)
3V3: C20.1 C27.1 C28.1 C29.1 C33.1 C34.1 C36.1 C37.1 C38.1 C39.1 C41.1 C43.1 C48.1 C49.1 C51.1 C69.1 C70.1 C71.1 C72.1 C73.1 C74.1 C75.1 C76.1 C77.1 C78.1 C79.1 C80.1 C81.1 C82.1 C83.1 C92.1 C93.1 C94.1 C272.1 C281.1 C283.1 C286.1 C293.1 C295.1 C319.1 C320.1 C324.1 C325.1 C326.1 C381.1 C382.1 C383.1 C391.1 C392.1 C393.1 C590.1 C591.1 C594.1 C595.1 C600.1 C601.1 C602.1 C603.1 C604.1 C605.1 C626.1 C627.1 C628.1 C629.1 C652.1 C653.1 C654.1 C655.1 C656.1 C657.1 C676.1 C677.1 C678.1 C679.1 C680.1 C681.1 C742.1 C743.1 C744.1 C745.1 C1025.1 C1060.1 C1062.1 C1072.1 C1074.1 C1081.1 D31.2 D36.2 D37.2 D38.2 D39.2 D40.2 D41.2 D42.2 FB26.1 FB32.1 FB44.1 FB45.1 FB52.1 FB53.1 J1.117(SA0) J1.236(VDDSPD) J2.4(VDD) J18.A9(+3V3#A9) J18.A10(+3V3#A10) J18.B8(+3V3#B8) J18.B10(+3V3AUX) J19.2(3.3V#2) J19.24(3.3VAUX) J19.52(3.3V#52) J20.2(3.3V#2) J20.24(3.3VAUX) J20.52(3.3V#52) J43.10 J43.12 J43.14 J43.16 Q18.1 Q18.2 Q18.3 Q39.1(G) Q40.1(G) Q42.1 Q42.2 Q42.3 Q45.2(S) R45.2 R46.2 R48.2 R51.2 R54.2 R55.2 R56.2 R57.2 R90.2 R91.2 R99.1 R107.1 R108.2 R109.2 R110.1 R111.1 R112.1 R113.1 R114.1 R142.1 R143.1 R180.1 R204.2 R234.2 R235.2 R276.2 R277.1 R279.1 R282.1 R390.2 R391.2 R392.2 R393.2 R396.2 R397.2 R398.2 R399.2 R402.2 R403.2 R404.2 R405.2 R406.2 R407.2 R408.2 R409.2 R410.2 R411.2 R420.2 R428.2 R442.2 R468.2 R540.1 R549.1 R550.1 R673.2 R822.1 R823.1 R827.1 R845.1 R847.1 R849.1 R850.1 R851.1 R852.1 R853.2 R854.1 R857.2 R858.2 R859.1 U4.43(VCC) U6.12(VCC#12) U6.37(VCC#37) U7.13(VCCB) U11.13(VCCB) U12.13(VCCB) U13.2(VCC) U15.8(VCC) U18.13(VCCB) U19.1(A0) U19.2(A1) U19.13(A2) U19.16(VDD) U20.16(VCCA) U22.5(VCC) U25.1(VDD#1) U25.6(VDD#6) U25.10(VDD#10) U26.1(VDD#1) U26.6(VDD#6) U26.10(VDD#10) U27.1(VDD#1) U27.6(VDD#6) U27.10(VDD#10) U28.1(VDD#1) U28.6(VDD#6) U28.10(VDD#10) U29.1(VDD#1) U29.6(VDD#6) U29.10(VDD#10) U39.16(VCC) U40.13(VCCB) U41.16(VCC) U42.13(VCCB) U44.8(VCC) U45.1(VDD) U46.6(AVDD33#6) U46.37(DVDD33#37) U46.41(AVDD33#41) U46.44(VDDREG#44) U46.45(VDDREG#45) U52.6(AVDD33#6) U52.25(AVDD33#25) U52.51(DVDD33#51) U52.67(DVDD33#67) U52.80(AVDD33#80) U52.84(VDDREG#84) U52.85(VDDREG#85) U59.7(AVDD#7) U59.25(DVDD#25) U59.37(DVDD#37) U59.54(AVDD#54) U59.57(AVDD#57) U63.7(AVDD#7) U63.25(DVDD#25) U63.37(DVDD#37) U63.54(AVDD#54) U63.57(AVDD#57) U67.10(VCC#10) U67.16(VCC#16) U68.10(VCC#10) U68.16(VCC#16) U98.13(VCCB) U99.13(VCCB) U100.5(VCC) U101.5(VCC)
3V3_OSC_CPLD: C703.1 C704.1 FB47.2 R494.1 X2.4(VDD)
3V3_PGOOD: R771.2 U65.K1(IO_B1_K1) U90.3(PGOOD)
3V3_SFPP_VDDR: C592.1 C593.1 FB44.2 J16.15(VDDR)
3V3_SFPP_VDDT: C596.1 C597.1 FB45.2 J16.16(VDDT)
3V3_SLP: C54.1 C350.1 C351.1 C356.1 C357.1 C358.1 C701.1 C702.1 C705.1 C706.1 C707.1 C708.1 C709.1 C710.1 C882.1 C985.1 C986.1 C987.1 C989.1 C997.1 C1002.1 C1016.1 C1066.1 C1067.1 C1068.1 C1102.1 C1103.1 D5.2 D6.2 D43.2 D44.2 FB12.2 FB29.1 FB47.1 J26.4 L22.2 Q18.5 R155.2 R156.2 R158.2 R159.2 R183.1 R185.2 R252.1 R262.2 R264.2 R497.1 R498.1 R559.2 R563.1 R564.1 R569.1 R570.1 R573.1 R574.1 R595.2 R697.2 R703.2 R704.2 R705.2 R771.1 R772.2 R825.1 U21.5(VCC) U49.6(AVDD33#6) U49.37(DVDD33#37) U49.41(AVDD33#41) U49.44(VDDREG#44) U49.45(VDDREG#45) U65.C1(VCCIO1#C1) U65.H6(VCCIO1#H6) U65.J6(VCCIO1#J6) U65.L8(VCCIO1#L8) U65.L9(VCCIO1#L9) U65.P1(VCCIO1#P1) U65.T3(VCCIO1#T3) U65.T14(VCCIO1#T14) U81.7(EN) U81.10(VIN) U83.4(VCC) U92.8(VDD) U95.4(BIAS)
3V3_USB_HVDD: C158.1 C159.1 C160.1 C161.1 C162.1 FB12.1 U1.J8(USB_HVDD1) U1.K8(USB_HVDD2)
3V3A_843002A: C750.1 C751.1 R549.2 U68.8(VCCA)
3V3A_843002B: C752.1 C753.1 R550.2 U67.8(VCCA)
3V3O_843002A: C746.1 C747.1 FB52.2 U68.2(VCCO#2) U68.20(VCCO#20)
3V3O_843002B: C748.1 C749.1 FB53.2 U67.2(VCCO#2) U67.20(VCCO#20)
5V0_SB: C897.1 C898.1 J37.9(+5VSB) R710.2 R711.2 R715.1 U84.7(P\R\E\) U84.8(VCC) U85.5(VCC)
5V0_SLP: C130.1 C131.1 C925.1 C926.1 C928.2 C929.2 C930.1 C931.1 C950.2 C951.2 C952.1 C953.1 C954.1 C955.1 C973.2 C974.2 C975.1 C976.1 C979.1 C980.1 C1053.2 C1054.2 C1055.2 C1056.2 C1057.2 C1058.2 C1112.1 C1113.1 J37.4(+5VDC#4) J37.6(+5VDC#6) J37.19(+5VDC#19) J37.20(+5VDC#20) R706.2 R727.1 R728.1 R730.1 R732.1 R734.1 R737.1 R739.1 R746.1 R747.1 R750.1 R752.1 R754.1 R756.1 R764.1 R765.1 R768.1 R770.1 R773.1 U37.7(IN) U86.10(VCC) U86.13(VIN) U87.10(VCC) U87.13(VIN) U88.10(VCC) U88.13(VIN) U89.10(VCC) U89.13(VIN) U90.10(VCC) U90.13(VIN) U91.10(VCC) U91.13(VIN)
5V0_USB1: C127.1 C128.1 C129.1 D4.1 FB6.2 R164.2 U37.8(OUTA)
5V0_USB2: C124.1 C125.1 C126.1 D3.1 FB8.2 R163.2 U37.5(OUTB)
7V0_DRV: C756.2 C769.2 C797.1 R558.1 R598.2 R727.2 U69.3(VCC) U69.27(B\B\R\K\) U71.3(VCC) U71.27(B\B\R\K\) U72.3(OUT)
12V: C84.1 C85.1 C620.1 C621.1 C622.1 C623.1 C624.1 C625.1 C686.1 C1080.1 F9.1 F11.1 F12.1 F13.1 FB46.1 J18.A2(+12V#A2) J18.A3(+12V#A3) J18.B1(+12V#B1) J18.B2(+12V#B2) J18.B3(+12V#B3) J43.2 J43.4 J43.6 Q12.5 Q12.6 Q12.7 Q12.8 R700.1 R861.1 R862.1 R863.1 R870.2
12V_POTS: C687.1 C688.1 C695.1 D27.1 D27.2 FB46.2 Q5.2(E) R482.2 R483.2 R484.2 R485.2 T12.1
12V_SLP: C796.1 C874.1 C1075.1 C1076.1 C1077.1 C1078.1 F10.1 J37.10(+12VDC) L23.2 Q12.1 Q12.2 Q12.3 R557.2 R597.1 R660.1 R662.1 R663.1 R678.1 R679.1 R690.1 R691.2 R701.1 R784.1 R818.1 R819.2 U72.2(IN)
12VF_SLP: C754.1 C755.1 C757.1 C758.1 C759.1 C771.1 C772.1 C773.1 C774.1 C775.1 C1000.1 C1001.1 L23.1 U69.18(VIN#18) U69.20(VIN#20) U69.21(VIN#21) U69.22(VIN#22) U69.23(VIN#23) U71.18(VIN#18) U71.20(VIN#20) U71.21(VIN#21) U71.22(VIN#22) U71.23(VIN#23)
-5VDC: J37.18(-5VDC)
-12VDC: J37.12(-12VDC)
AGND_SD1_PLL1: C259.2 C260.2 C261.2 R190.1 U1.AA16(AGND_SD1_PLL1)
AGND_SD1_PLL2: C264.2 C265.2 C266.2 R193.1 U1.AA20(AGND_SD1_PLL2)
AVDD_CGA1: C257.1 C258.1 R188.2 U1.G11(AVDD_CGA1)
AVDD_CGA2: C262.1 C263.1 R191.2 U1.G12(AVDD_CGA2)
AVDD_DDR1: C269.1 C270.1 R195.2 U1.E20(AVDD_D1)
AVDD_PLAT: C267.1 C268.1 R194.2 U1.G10(AVDD_PLAT)
AVDD_SD1_PLL1: C259.1 C260.1 C261.1 R189.1 U1.AB16(AVDD_SD1_PLL1)
AVDD_SD1_PLL2: C264.1 C265.1 C266.1 R192.1 U1.AB20(AVDD_SD1_PLL2)
DVDD: C181.1 C182.1 C183.1 C280.1 C282.1 C1028.1 Q1.1(G) Q2.1(G) Q23.1 Q23.2 Q23.3 Q24.1 Q24.2 Q24.3 R80.2 R86.2 R87.2 R88.2 R89.2 R92.2 R93.2 R95.2 R97.2 R687.2 U1.N8(DVDD1) U1.P8(DVDD2) U1.R8(DVDD3) U40.16(VCCA) U42.16(VCCA)
GND: C1.2 C2.2 C3.2 C4.2 C5.2 C6.2 C7.2 C8.2 C9.2 C10.2 C11.2 C12.2 C13.2 C14.2 C15.2 C16.2 C17.2 C18.2 C19.2 C20.2 C21.2 C22.2 C23.2 C24.2 C25.2 C26.2 C27.2 C28.2 C29.2 C30.2 C31.2 C32.2 C33.2 C34.2 C35.2 C36.2 C37.2 C38.2 C39.2 C40.2 C41.2 C42.2 C43.2 C48.2 C49.2 C50.2 C51.2 C52.2 C53.2 C54.2 C55.1 C56.2 C57.2 C58.2 C69.2 C70.2 C71.2 C72.2 C73.2 C74.2 C75.2 C76.2 C77.2 C78.2 C79.2 C80.2 C81.2 C82.2 C83.2 C84.2 C85.2 C92.2 C93.2 C94.2 C124.2 C125.2 C126.2 C127.2 C128.2 C129.2 C130.2 C131.2 C132.2 C133.2 C134.2 C135.2 C136.2 C137.2 C138.2 C139.2 C140.2 C141.2 C142.2 C143.2 C144.2 C145.2 C146.2 C147.2 C148.2 C149.2 C150.2 C151.2 C152.2 C153.2 C154.2 C155.2 C156.2 C157.2 C158.2 C159.2 C160.2 C161.2 C162.2 C163.2 C164.2 C165.2 C166.2 C167.2 C168.2 C169.2 C170.2 C171.2 C172.2 C173.2 C174.2 C175.2 C176.2 C177.2 C178.2 C179.2 C180.2 C181.2 C182.2 C183.2 C184.2 C185.2 C186.2 C187.2 C188.2 C189.2 C192.2 C195.2 C196.2 C197.2 C198.2 C199.2 C200.2 C201.2 C202.2 C203.2 C204.2 C205.2 C206.2 C207.2 C208.2 C209.2 C210.2 C211.2 C212.2 C213.2 C214.2 C215.2 C216.2 C217.2 C218.2 C219.2 C220.2 C222.2 C223.2 C224.2 C225.2 C226.2 C227.2 C228.2 C229.2 C230.2 C232.2 C234.2 C235.2 C236.2 C237.2 C238.2 C239.2 C240.2 C241.2 C242.2 C243.2 C244.2 C245.2 C246.2 C247.2 C248.2 C249.2 C250.2 C251.2 C252.2 C253.2 C254.2 C255.2 C256.2 C257.2 C258.2 C262.2 C263.2 C267.2 C268.2 C269.2 C270.2 C272.2 C273.2 C275.2 C276.2 C277.2 C278.2 C279.2 C280.2 C281.2 C282.2 C283.2 C286.2 C287.2 C288.2 C289.2 C290.2 C291.2 C292.2 C293.2 C295.2 C296.1 C297.2 C298.1 C299.1 C300.1 C301.1 C303.2 C304.2 C305.2 C306.1 C307.2 C308.2 C309.2 C310.1 C312.2 C313.2 C314.2 C315.2 C316.2 C317.2 C319.2 C320.2 C321.2 C322.2 C323.2 C324.2 C325.2 C326.2 C328.1 C329.2 C330.1 C331.1 C332.1 C333.1 C335.2 C336.1 C337.2 C338.2 C339.2 C340.2 C341.2 C342.1 C343.2 C344.2 C346.2 C347.2 C348.2 C349.2 C350.2 C351.2 C353.2 C354.2 C355.2 C356.2 C357.2 C358.2 C360.1 C361.2 C362.1 C363.1 C364.1 C368.1 C369.2 C370.2 C371.1 C372.2 C373.2 C374.2 C375.2 C376.2 C377.2 C378.2 C381.2 C382.2 C383.2 C384.2 C385.2 C386.2 C388.2 C389.2 C390.2 C391.2 C392.2 C393.2 C398.2 C399.2 C401.2 C402.2 C403.2 C404.2 C406.2 C407.2 C412.2 C413.2 C414.2 C415.2 C416.2 C420.2 C421.2 C422.2 C423.2 C424.2 C425.2 C432.2 C433.2 C434.2 C435.2 C436.2 C437.2 C440.2 C446.2 C447.2 C448.2 C449.2 C450.2 C451.2 C457.2 C458.2 C459.2 C461.2 C462.2 C465.2 C466.2 C467.2 C468.2 C469.2 C470.2 C477.2 C478.2 C479.2 C480.2 C481.2 C482.2 C485.2 C490.1 C491.1 C492.1 C493.1 C494.1 C495.1 C496.1 C497.1 C500.1 C501.1 C502.1 C503.1 C504.1 C505.1 C506.1 C507.1 C508.1 C509.1 C510.1 C511.1 C514.1 C515.1 C516.1 C517.1 C518.1 C519.1 C520.1 C521.1 C522.1 C523.1 C524.1 C525.1 C528.1 C529.1 C530.1 C531.1 C532.1 C533.1 C534.1 C535.1 C536.1 C537.1 C538.1 C539.1 C540.1 C543.1 C544.1 C545.1 C546.1 C547.1 C548.1 C549.2 C550.1 C551.2 C552.2 C553.1 C556.2 C557.2 C558.2 C559.2 C560.2 C561.2 C562.2 C563.2 C564.1 C565.1 C566.2 C567.2 C568.2 C569.2 C570.2 C571.2 C572.2 C573.2 C576.2 C577.2 C578.2 C579.2 C580.2 C581.2 C582.2 C583.2 C584.2 C585.2 C586.2 C587.2 C588.2 C589.2 C590.2 C591.2 C592.2 C593.2 C594.2 C595.2 C596.2 C597.2 C600.2 C601.2 C602.2 C603.2 C604.2 C605.2 C609.2 C610.2 C611.2 C612.2 C613.2 C614.2 C620.2 C621.2 C622.2 C623.2 C624.2 C625.2 C626.2 C627.2 C628.2 C629.2 C636.2 C639.2 C640.1 C641.2 C643.1 C645.2 C646.1 C649.2 C650.2 C651.2 C652.2 C653.2 C654.2 C655.2 C656.2 C657.2 C658.2 C661.2 C662.1 C664.2 C667.1 C669.2 C670.1 C673.2 C674.2 C675.2 C676.2 C677.2 C678.2 C679.2 C680.2 C681.2 C684.2 C685.2 C686.2 C687.2 C688.2 C691.1 C692.1 C693.2 C694.2 C695.2 C697.2 C698.2 C699.2 C700.2 C701.2 C702.2 C703.2 C704.2 C705.2 C706.2 C707.2 C708.2 C709.2 C710.2 C711.2 C712.2 C713.2 C714.2 C715.2 C716.2 C718.2 C720.2 C721.2 C722.2 C723.2 C728.2 C729.2 C730.2 C731.2 C732.2 C733.2 C734.2 C735.2 C736.2 C737.2 C738.2 C739.2 C740.2 C741.2 C742.2 C743.2 C744.2 C745.2 C746.2 C747.2 C748.2 C749.2 C750.2 C751.2 C752.2 C753.2 C754.2 C755.2 C756.1 C757.2 C758.2 C759.2 C760.2 C761.2 C762.2 C767.2 C768.2 C769.1 C770.1 C771.2 C772.2 C773.2 C774.2 C775.2 C776.2 C777.2 C781.2 C782.2 C783.2 C784.2 C787.2 C788.2 C789.2 C790.2 C791.2 C792.2 C793.2 C794.2 C795.2 C796.2 C797.2 C798.1 C871.1 C873.1 C875.1 C876.1 C878.1 C879.2 C880.2 C881.2 C882.2 C883.2 C884.2 C885.2 C886.2 C887.2 C888.2 C889.2 C892.2 C893.2 C894.2 C895.2 C896.2 C897.2 C898.2 C899.2 C900.2 C901.2 C902.2 C903.2 C904.2 C905.2 C906.2 C907.2 C908.2 C909.2 C910.2 C911.2 C912.2 C913.2 C914.2 C915.2 C916.2 C917.2 C918.2 C919.2 C920.2 C921.2 C922.2 C923.2 C925.2 C926.2 C928.1 C929.1 C930.2 C931.2 C932.1 C933.2 C934.2 C936.2 C937.2 C938.1 C939.2 C940.2 C944.2 C945.2 C946.2 C947.2 C950.1 C951.1 C952.2 C953.2 C954.2 C955.2 C956.1 C957.1 C958.2 C959.2 C960.2 C961.2 C962.2 C963.2 C968.2 C969.2 C970.2 C971.2 C973.1 C974.1 C975.2 C976.2 C977.1 C979.2 C980.2 C981.1 C982.2 C983.2 C984.2 C985.2 C986.2 C987.2 C992.2 C993.2 C994.2 C995.2 C996.1 C997.2 C998.2 C999.2 C1000.2 C1001.2 C1002.2 C1003.2 C1004.2 C1005.2 C1006.2 C1007.2 C1008.2 C1009.2 C1010.2 C1011.2 C1012.2 C1013.3 C1013.4 C1014.3 C1014.4 C1015.2 C1016.2 C1017.2 C1018.2 C1019.2 C1020.2 C1021.2 C1023.1 C1024.2 C1025.2 C1026.2 C1027.2 C1028.2 C1029.2 C1030.2 C1031.2 C1032.2 C1033.2 C1034.2 C1035.2 C1036.2 C1037.2 C1038.2 C1039.2 C1040.2 C1041.2 C1044.2 C1045.2 C1046.2 C1047.2 C1048.2 C1049.2 C1050.2 C1051.2 C1052.2 C1053.1 C1054.1 C1055.1 C1056.1 C1057.1 C1058.1 C1059.2 C1060.2 C1061.2 C1062.2 C1063.2 C1064.2 C1066.2 C1067.2 C1068.2 C1069.2 C1070.2 C1071.2 C1072.2 C1073.2 C1074.2 C1075.2 C1076.2 C1077.2 C1078.2 C1079.2 C1080.2 C1081.2 C1082.2 C1083.2 C1084.2 C1085.2 C1086.2 C1087.2 C1088.2 C1089.2 C1090.2 C1091.2 C1092.2 C1093.2 C1094.2 C1095.2 C1096.2 C1097.2 C1098.2 C1099.2 C1100.2 C1101.2 C1102.2 C1103.2 C1104.2 C1105.2 C1106.2 C1107.2 C1108.2 C1109.2 C1110.2 C1111.2 C1112.2 C1113.2 D1.1 FB7.2 FB9.2 J1.2(VSS#2) J1.5(VSS#5) J1.8(VSS#8) J1.11(VSS#11) J1.14(VSS#14) J1.17(VSS#17) J1.20(VSS#20) J1.23(VSS#23) J1.26(VSS#26) J1.29(VSS#29) J1.32(VSS#32) J1.35(VSS#35) J1.38(VSS#38) J1.41(VSS#41) J1.44(VSS#44) J1.47(VSS#47) J1.80(VSS#80) J1.83(VSS#83) J1.86(VSS#86) J1.89(VSS#89) J1.92(VSS#92) J1.95(VSS#95) J1.98(VSS#98) J1.101(VSS#101) J1.104(VSS#104) J1.107(VSS#107) J1.110(VSS#110) J1.113(VSS#113) J1.116(VSS#116) J1.119(SA2) J1.121(VSS#121) J1.124(VSS#124) J1.127(VSS#127) J1.130(VSS#130) J1.133(VSS#133) J1.136(VSS#136) J1.139(VSS#139) J1.142(VSS#142) J1.145(VSS#145) J1.148(VSS#148) J1.151(VSS#151) J1.154(VSS#154) J1.157(VSS#157) J1.160(VSS#160) J1.163(VSS#163) J1.166(VSS#166) J1.199(VSS#199) J1.202(VSS#202) J1.205(VSS#205) J1.208(VSS#208) J1.211(VSS#211) J1.214(VSS#214) J1.217(VSS#217) J1.220(VSS#220) J1.223(VSS#223) J1.226(VSS#226) J1.229(VSS#229) J1.232(VSS#232) J1.235(VSS#235) J1.237(SA1) J1.239(VSS#239) J2.3(VSS#3) J2.6(VSS#6) J2.12(COM1) J2.13(COM2) J3.12 J3.16 J13.A4 J13.A5 J13.B4 J13.B5 J14.A10 J14.B12 J16.1(TGND#1) J16.10(RGND#10) J16.11(RGND#11) J16.14(RGND#14) J16.17(TGND#17) J16.20(TGND#20) J18.A1(P\R\S\N\T\1\) J18.A4(GND#A4) J18.A12(GND#A12) J18.A15(GND#A15) J18.A18(GND#A18) J18.A20(GND#A20) J18.A23(GND#A23) J18.A24(GND#A24) J18.A27(GND#A27) J18.A28(GND#A28) J18.A31(GND#A31) J18.B4(GND#B4) J18.B7(GND#B7) J18.B13(GND#B13) J18.B16(GND#B16) J18.B18(GND#B18) J18.B21(GND#B21) J18.B22(GND#B22) J18.B25(GND#B25) J18.B26(GND#B26) J18.B29(GND#B29) J18.B32(GND#B32) J19.4(GND#4) J19.9(GND#9) J19.15(GND#15) J19.18(GND#18) J19.21(GND#21) J19.26(GND#26) J19.27(GND#27) J19.29(GND#29) J19.34(GND#34) J19.35(GND#35) J19.40(GND#40) J19.50(GND#50) J19.53(MS1) J19.54(MS2) J20.4(GND#4) J20.9(GND#9) J20.15(GND#15) J20.18(GND#18) J20.21(GND#21) J20.26(GND#26) J20.27(GND#27) J20.29(GND#29) J20.34(GND#34) J20.35(GND#35) J20.40(GND#40) J20.50(GND#50) J20.53(MS1) J20.54(MS2) J21.1(GND#1) J21.4(GND#4) J21.7(GND#7) J21.8(MH1) J21.9(MH2) J26.2 J26.10 J27.2 J28.2 J30.2 J32.3 J33.1 J33.3 J35.2 J37.3(COM#3) J37.5(COM#5) J37.7(COM#7) J37.13(COM#13) J37.15(COM#15) J37.16(COM#16) J37.17(COM#17) J39.2 J43.5 J43.15 J43.19 J43.23 J43.26 J43.30 J43.37 J43.40 J44.1 J44.3 J45.1 J45.3 J46.1 J46.3 M2.1 M2.2 M2.3 M2.4 M3.1 M4.1 M5.1 M6.1 M7.1 M8.1 M9.1 M10.1 M11.1 M12.1 M13.1 M14.1 M15.1 M16.1 M17.1 M18.1 Q3.2(S) Q4.2(S) Q7.2(S) Q13.2(S) Q15.2(S) Q16.2(S) Q20.2(S) Q21.2(S) Q25.2(S) Q26.2(S) Q27.2(S) Q28.2(S) Q29.2(S) Q30.2(E) Q32.2(S) Q35.2(S) Q36.2(S) Q37.2(S) Q38.2(S) Q41.2(S) R3.1 R13.1 R17.2 R19.2 R21.2 R23.2 R25.2 R27.2 R29.2 R31.2 R33.2 R34.2 R35.2 R36.2 R37.2 R38.2 R39.2 R40.2 R52.2 R104.1 R105.1 R106.1 R123.1 R124.2 R135.1 R136.1 R137.1 R141.1 R161.1 R162.1 R165.1 R166.1 R171.1 R172.1 R173.1 R176.1 R177.1 R178.1 R179.1 R190.2 R193.2 R227.1 R228.2 R232.2 R233.2 R256.1 R257.2 R261.2 R263.2 R268.1 R273.1 R278.2 R285.1 R286.1 R297.1 R302.1 R303.1 R320.1 R323.1 R324.1 R379.2 R383.2 R384.2 R400.2 R401.2 R438.1 R469.1 R480.1 R481.1 R487.1 R491.1 R493.1 R496.1 R499.2 R500.2 R501.2 R503.2 R505.2 R507.2 R509.2 R513.1 R518.1 R519.2 R523.2 R524.1 R527.2 R528.1 R534.2 R535.1 R538.1 R541.1 R542.1 R543.1 R544.1 R545.1 R546.1 R547.1 R548.1 R556.1 R560.1 R567.1 R568.1 R575.1 R581.2 R582.2 R588.2 R589.2 R592.1 R593.1 R594.1 R596.1 R599.1 R654.1 R656.1 R667.1 R669.1 R671.1 R672.1 R673.1 R684.1 R685.1 R687.1 R693.1 R696.1 R699.1 R708.1 R712.1 R742.1 R743.1 R744.1 R745.1 R760.1 R761.1 R762.1 R763.1 R778.1 R779.1 R780.1 R781.1 R782.1 R786.1 R807.1 R809.1 R810.1 R811.2 R812.2 R814.1 R815.1 R821.1 R831.1 R835.2 R838.2 R842.1 R846.2 R848.2 R870.1 SW3.9 SW4.1 SW4.3 SW4.4 SW5.1 SW5.3 SW5.4 T12.7 U1.A2(GND001) U1.A20(GND002) U1.A27(GND003) U1.AA11(GND148) U1.AA13(S1GND05) U1.AA15(S1GND06) U1.AA17(S1GND07) U1.AA19(S1GND08) U1.AA21(S1GND09) U1.AA24(GND149) U1.AB2(GND150) U1.AB5(GND151) U1.AB7(GND152) U1.AB13(S1GND10) U1.AB17(S1GND11) U1.AB21(S1GND12) U1.AB22(GND153) U1.AB26(GND154) U1.AC1(EC1_COL) U1.AC2(EC1_RX_ER) U1.AC10(X1GND01) U1.AC11(X1GND02) U1.AC13(X1GND03) U1.AC14(X1GND04) U1.AC16(X1GND05) U1.AC17(X1GND06) U1.AC19(X1GND07) U1.AC20(X1GND08) U1.AC24(GND155) U1.AC26(GND156) U1.AD4(GND157) U1.AD6(GND158) U1.AD9(X1GND09) U1.AD12(X1GND10) U1.AD15(X1GND11) U1.AD18(X1GND12) U1.AD21(X1GND13) U1.AD22(GND159) U1.AE2(GND160) U1.AE9(X1GND14) U1.AE12(X1GND15) U1.AE15(X1GND16) U1.AE18(X1GND17) U1.AE21(X1GND18) U1.AE24(GND161) U1.AE26(GND162) U1.AF9(GND163) U1.AF10(S1GND13) U1.AF11(S1GND14) U1.AF12(S1GND15) U1.AF13(S1GND16) U1.AF14(S1GND17) U1.AF15(S1GND18) U1.AF16(S1GND19) U1.AF17(S1GND20) U1.AF18(S1GND21) U1.AF19(S1GND22) U1.AF20(S1GND23) U1.AF21(GND164) U1.AG1(GND165) U1.AG4(GND166) U1.AG6(GND167) U1.AG9(S1GND24) U1.AG12(S1GND25) U1.AG15(S1GND26) U1.AG18(S1GND27) U1.AG21(S1GND28) U1.AG22(GND168) U1.AG23(GND169) U1.AG26(GND170) U1.AH2(GND171) U1.AH9(S1GND29) U1.AH12(S1GND30) U1.AH15(S1GND31) U1.AH18(S1GND32) U1.AH21(S1GND33) U1.B1(GND004) U1.B4(GND005) U1.B7(GND006) U1.B10(GND007) U1.B13(GND008) U1.B16(GND009) U1.B19(GND010) U1.B23(GND011) U1.B25(GND012) U1.B28(GND013) U1.C22(GND014) U1.C26(GND015) U1.D2(GND016) U1.D20(GND017) U1.D21(GND018) U1.D24(GND019) U1.E1(USB_AGND01) U1.E2(USB_AGND02) U1.E3(USB_AGND03) U1.E5(GND020) U1.E7(GND021) U1.E10(GND022) U1.E13(GND023) U1.E16(GND024) U1.E19(GND025) U1.E22(GND026) U1.E26(GND027) U1.F3(USB_AGND04) U1.F15(GND028) U1.F24(GND029) U1.G1(USB_AGND05) U1.G2(USB_AGND06) U1.G3(USB_AGND07) U1.G5(USB_AGND08) U1.G7(GND030) U1.G13(GND031) U1.G16(GND032) U1.G22(GND033) U1.G26(GND034) U1.H3(USB_AGND09) U1.H7(GND035) U1.H8(GND036) U1.H9(GND037) U1.H10(GND038) U1.H11(GND039) U1.H12(GND040) U1.H13(GND041) U1.H14(GND042) U1.H15(GND043) U1.H16(GND044) U1.H17(GND045) U1.H18(GND046) U1.H19(GND047) U1.H20(GND048) U1.H24(GND049) U1.J1(USB_AGND10) U1.J2(USB_AGND11) U1.J3(USB_AGND12) U1.J7(GND050) U1.J22(GND051) U1.J26(GND052) U1.K2(GND053) U1.K5(GND054) U1.K6(GND055) U1.K7(GND056) U1.K12(GND057) U1.K14(GND058) U1.K16(GND059) U1.K18(GND060) U1.K20(GND061) U1.K24(GND062) U1.L7(GND063) U1.L9(GND064) U1.L11(GND065) U1.L13(GND066) U1.L15(GND067) U1.L17(GND068) U1.L19(GND069) U1.L22(GND070) U1.L26(GND071) U1.M7(GND072) U1.M10(GND073) U1.M12(GND074) U1.M14(GND075) U1.M16(GND076) U1.M18(GND077) U1.M20(GND078) U1.M24(GND079) U1.N2(GND080) U1.N5(GND081) U1.N7(GND082) U1.N9(GND083) U1.N11(GND084) U1.N13(GND085) U1.N15(GND086) U1.N17(GND087) U1.N19(GND088) U1.N22(GND089) U1.N26(GND090) U1.P7(GND091) U1.P10(GND092) U1.P12(GND093) U1.P14(GND094) U1.P16(GND095) U1.P18(GND096) U1.P20(GND097) U1.P24(GND098) U1.R7(GND099) U1.R9(GND100) U1.R11(GND101) U1.R13(GND102) U1.R15(GND103) U1.R17(GND104) U1.R19(GND105) U1.R22(GND106) U1.R26(GND107) U1.T2(GND108) U1.T5(GND109) U1.T7(GND110) U1.T10(GND111) U1.T12(GND112) U1.T14(GND113) U1.T16(GND114) U1.T18(GND115) U1.T20(GND116) U1.T22(GND117) U1.T26(GND118) U1.U7(GND119) U1.U9(GND120) U1.U11(GND121) U1.U13(GND122) U1.U15(GND123) U1.U17(GND124) U1.U19(GND125) U1.U24(GND126) U1.V7(GND127) U1.V10(GND128) U1.V12(GND129) U1.V14(GND130) U1.V16(GND131) U1.V18(GND132) U1.V20(GND133) U1.V22(GND134) U1.V26(GND135) U1.W2(GND136) U1.W5(GND137) U1.W7(GND138) U1.W9(GND139) U1.W11(GND140) U1.W13(GND141) U1.W24(GND142) U1.Y7(GND143) U1.Y10(GND144) U1.Y12(GND145) U1.Y14(S1GND01) U1.Y16(S1GND02) U1.Y17(S1GND03) U1.Y18(S1GND04) U1.Y22(GND146) U1.Y26(GND147) U2.1(O\E\1\) U2.4(GND#4) U2.10(GND#10) U2.15(GND#15) U2.21(GND#21) U2.24(O\E\2\) U2.26(2D8) U2.27(2D7) U2.28(GND#28) U2.29(2D6) U2.30(2D5) U2.32(2D4) U2.34(GND#34) U2.39(GND#39) U2.45(GND#45) U4.33(GND#33) U4.52(GND#52) U6.13(GND#13) U6.36(GND#36) U7.6(GND#6) U7.7(GND#7) U8.3(GND) U9.3(GND) U10.3(GND) U11.6(GND#6) U11.7(GND#7) U12.6(GND#6) U12.7(GND#7) U12.8(O\E\) U13.10(GND) U15.4(GND) U15.9(EPAD) U18.6(GND#6) U18.7(GND#7) U18.8(O\E\) U19.8(VSS) U20.6(GND#6) U20.7(GND#7) U20.8(O\E\) U21.3(GND) U22.3(GND) U23.3(GND) U24.3(GND) U25.5(GND#5) U25.9(SEL) U25.11(GND#11) U25.20(GND#20) U25.21(EPAD) U26.2(PD) U26.5(GND#5) U26.11(GND#11) U26.20(GND#20) U26.21(EPAD) U27.2(PD) U27.5(GND#5) U27.11(GND#11) U27.20(GND#20) U27.21(EPAD) U28.2(PD) U28.5(GND#5) U28.11(GND#11) U28.20(GND#20) U28.21(EPAD) U29.2(PD) U29.5(GND#5) U29.11(GND#11) U29.20(GND#20) U29.21(EPAD) U37.6(GND) U38.1 U38.2 U39.15(GND) U40.6(GND#6) U40.7(GND#7) U40.8(O\E\) U41.15(GND) U42.6(GND#6) U42.7(GND#7) U42.8(O\E\) U43.9 U43.10 U43.11 U43.12 U43.13 U43.14 U43.15 U43.16 U44.1(A0) U44.2(A1) U44.3(A2) U44.4(GND) U44.7(WP) U45.5(GND) U46.47(GND) U46.49(EPAD) U47.2 U48.2 U49.47(GND) U49.49(EPAD) U50.2 U51.2 U52.15(AGND#15) U52.19(AGND#19) U52.20(AGND#20) U52.27(AGND#27) U52.48(GTX_CLK) U52.49(TXEN/TXCTL) U52.50(TXD0) U52.53(TXD1) U52.54(TXD2) U52.55(TXD3) U52.57(TXD4) U52.58(TXD5) U52.59(TXD6) U52.60(TXD7) U52.61(TXER) U52.83(GND#83) U52.87(GND#87) U52.89(EPAD) U53.2 U54.2 U55.139(VSS_CASE) U55.B7(REFCLK_SEL1) U55.B8(REFCLK_SEL0) U55.D9(VSS/EFUSE) U56.139(VSS_CASE) U56.B7(REFCLK_SEL1) U56.B8(REFCLK_SEL0) U56.D9(VSS/EFUSE) U57.A3(DIGVSS#A3) U57.A6(DIGVSS#A6) U57.A9(DIGVSS#A9) U57.B1(TX2VSS#B1) U57.B2(TX2VSS#B2) U57.B3(RX2VSS#B3) U57.B4(RX2VSS#B4) U57.B5(RX2VSS#B5) U57.B7(TX1VSS#B7) U57.B8(TX1VSS#B8) U57.B9(RX1VSS#B9) U57.B10(RX1VSS#B10) U57.B11(RX1VSS#B11) U57.D2(TX2VSS#D2) U57.D4(RX2VSS#D4) U57.D5(RX2VSS#D5) U57.D8(RX1VSS#D8) U57.D9(RX1VSS#D9) U57.E1(TX2VSS#E1) U57.E6(DIGVSS#E6) U57.E7(DIGVSS#E7) U57.F4(RX2VSS#F4) U57.F5(RX2VSS#F5) U57.F8(RX1VSS#F8) U57.F9(RX1VSS#F9) U57.G6(RX2VSS#G6) U57.G7(TX1VSS#G7) U57.H4(TX2VSS#H4) U57.H5(TX2VSS#H5) U57.H8(TX1VSS#H8) U57.H9(RX1VSS#H9) U57.K1(TX2VSS#K1) U57.K2(TX2VSS#K2) U57.K4(RX2VSS#K4) U57.K5(RX2VSS#K5) U57.K6(TX1VSS#K6) U57.K7(TX1VSS#K7) U57.K8(TX1VSS#K8) U57.K10(RX1VSS#K10) U57.K11(RX1VSS#K11) U57.L3(RX2VSS#L3) U57.L6(TX1VSS#L6) U57.L9(RX1VSS#L9) U58.1(A0) U58.2(A1) U58.3(A2) U58.4(GND) U58.7(WP) U59.5(BGND1) U59.8(AGND#8) U59.23(DGND#23) U59.39(DGND#39) U59.43(SWISZ) U59.53(AGND#53) U59.56(AGND#56) U59.58(BGND2) U59.81(EPAD) U60.6 U60.7 U61.6 U61.7 U62.6 U62.7 U63.5(BGND1) U63.8(AGND#8) U63.19(SWISY) U63.23(DGND#23) U63.39(DGND#39) U63.43(SWISZ) U63.53(AGND#53) U63.56(AGND#56) U63.58(BGND2) U63.81(EPAD) U64.6 U64.7 U65.A1(GNDIO#A1) U65.A16(GNDIO#A16) U65.B2(GNDIO#B2) U65.B15(GNDIO#B15) U65.G7(GNDIO#G7) U65.G8(GNDIO#G8) U65.G9(GNDIO#G9) U65.G10(GNDIO#G10) U65.H7(GNDINT#H7) U65.H9(GNDINT#H9) U65.J8(GNDINT#J8) U65.J10(GNDINT#J10) U65.K7(GNDIO#K7) U65.K8(GNDIO#K8) U65.K9(GNDIO#K9) U65.K10(GNDIO#K10) U65.R2(GNDIO#R2) U65.R15(GNDIO#R15) U65.T1(GNDIO#T1) U65.T16(GNDIO#T16) U67.17(VEE) U68.17(VEE) U69.1(CSIN-) U69.2(CSIN+) U69.4(PGND#4) U69.16(PGND#16) U69.28(LGND) U69.29(REFIN) U69.31(TGND) U70.33(EPAD) U71.1(CSIN-) U71.2(CSIN+) U71.4(PGND#4) U71.16(PGND#16) U71.28(LGND) U71.29(REFIN) U71.31(TGND) U72.5(GND#5) U72.6(GND#6) U72.7(GND#7) U72.8(GND#8) U81.4(PGND) U81.8(GND) U81.11(PAD) U82.2(GND) U82.4(NC) U83.1(GND) U84.4(GND) U85.3(GND) U86.4(GND#4) U86.11(PGND) U86.17(GND#17) U87.4(GND#4) U87.11(PGND) U87.17(GND#17) U88.4(GND#4) U88.11(PGND) U88.17(GND#17) U89.4(GND#4) U89.11(PGND) U89.17(GND#17) U90.4(GND#4) U90.11(PGND) U90.17(GND#17) U91.4(GND#4) U91.11(PGND) U91.17(GND#17) U92.3(GND) U93.9 U94.9 U95.3(GND) U95.9(EPAD) U96.1 U96.2 U97.8(GNDDIG) U97.41(EPAD) U98.6(GND#6) U98.7(GND#7) U99.6(GND#6) U99.7(GND#7) U100.3(GND) U101.3(GND) X1.2(GND) X2.2(GND) X3.2(GND) X5.2(GND) Y1.2 Y1.4 Y2.2 Y2.4 Y3.2 Y3.4 Y4.2 Y4.4 Y5.2 Y5.4 Y6.2 Y6.4 Z105.1 Z105.2 Z105.3 Z105.4 Z105.5 Z105.6 Z105.7 Z105.8 Z106.1 Z106.2 Z106.3 Z106.4 Z106.5 Z106.6 Z106.7 Z106.8 Z109.1 Z109.2 Z109.3 Z109.4 Z109.5 Z109.6 Z109.7 Z109.8 Z110.1 Z110.2 Z110.3 Z110.4 Z110.5 Z110.6 Z110.7 Z110.8 Z111.1 Z111.2 Z111.3 Z111.4 Z111.5 Z111.6 Z111.7 Z111.8 Z112.1 Z112.2 Z112.3 Z112.4 Z112.5 Z112.6 Z112.7 Z112.8
SVDD: C242.1 C243.1 C244.1 C245.1 C246.1 C247.1 C248.1 C1013.1 C1027.1 R139.1 U1.W15(S1VDD1) U1.W16(S1VDD2) U1.W17(S1VDD3) U1.W18(S1VDD4) U1.W19(S1VDD5) U1.W20(S1VDD6) U1.Y13(S1VDD7)
VBATH: C636.1 C645.1 C651.1 C658.1 C669.1 C675.1 D25.2 R430.1 R460.1 U59.1(VBM1) U59.3(VBH) U59.60(VBM2) U60.2 U61.2 U62.2 U63.1(VBM1) U63.3(VBH) U63.60(VBM2) U64.2
VBATL: C650.1 C674.1 C693.1 C694.1 L7.2 R433.1 R463.1 U59.69(VBL2) U59.79(VBL1) U63.69(VBL2) U63.79(VBL1)
VDD_EN: U65.N5(IO_B1_N5) U95.5(EN)
VDD_EN_N: R665.1 U65.N12(IO_B1_N12)
ASLEEP: R101.1 U1.B2(ASLEEP) U21.2(A)
BOOT_FLASH_SEL: R502.2 SW3.4 U65.F15(IO_B2_F15)
CFG_VBANK0: R504.2 SW3.5 U10.2(I1) U65.J16(IO_B2_J16)
CFG_VBANK1: R506.2 SW3.6 U9.2(I1) U65.H16(IO_B2_H16)
CFG_VBANK2: R508.2 SW3.7 U8.2(I1) U65.J15(IO_B2_J15)
CKE_ISO_EN: R830.1 U65.L4(IO_B1_L4)
CKSTP_OUT_N: R102.1 U1.F18(CKSTP_OUT_B) U22.2(A)
COP_CKSTP_OUT_N: J3.15 U22.4(O)
COP_HRESET_N: J3.13 R107.2 U65.G1(IO_B1_G1)
COP_SRESET_N: J3.11 R110.2 U65.H1(IO_B1_H1)
COP_TCK: J3.7 R113.2 U20.3(A3)
COP_TDI: J3.3 R111.2 U20.1(A1)
COP_TDO: J3.1 U20.2(A2)
COP_TMS: J3.9 R114.2 U20.4(A4)
COP_TRST_N: J3.4 R109.1 U65.J1(IO_B1_J1)
CPLD_INT1_N: R69.1 U1.F7(IRQ00) U65.E13(IO_B2_E13)
CPLD_INT2_N: R70.1 U1.D3(IRQ01) U65.E14(IO_B2_E14)
CPLD_REFCLK: R495.2 U65.H5(GCLK0P)
CPLD_TCK: J26.1 R496.2 U65.P3(TCK)
CPLD_TDI: J26.9 R498.2 U65.L6(TDI)
CPLD_TDO: J26.3 U65.M5(TDO)
CPLD_TMS: J26.5 R497.2 U65.N4(TMS)
DDR_DQ0: J1.3(DQ0) U1.C21(D1_MDQ00)
DDR_DQ1: J1.4(DQ1) U1.A22(D1_MDQ01)
DDR_DQ2: J1.9(DQ2) U1.A26(D1_MDQ02)
DDR_DQ3: J1.10(DQ3) U1.B26(D1_MDQ03)
DDR_DQ4: J1.122(DQ4) U1.B21(D1_MDQ04)
DDR_DQ5: J1.123(DQ5) U1.A21(D1_MDQ05)
DDR_DQ6: J1.128(DQ6) U1.B24(D1_MDQ06)
DDR_DQ7: J1.129(DQ7) U1.A25(D1_MDQ07)
DDR_DQ8: J1.12(DQ8) U1.C23(D1_MDQ08)
DDR_DQ9: J1.13(DQ9) U1.C24(D1_MDQ09)
DDR_DQ10: J1.18(DQ10) U1.F25(D1_MDQ10)
DDR_DQ11: J1.19(DQ11) U1.F26(D1_MDQ11)
DDR_DQ12: J1.131(DQ12) U1.D22(D1_MDQ12)
DDR_DQ13: J1.132(DQ13) U1.D23(D1_MDQ13)
DDR_DQ14: J1.137(DQ14) U1.B27(D1_MDQ14)
DDR_DQ15: J1.138(DQ15) U1.E25(D1_MDQ15)
DDR_DQ16: J1.21(DQ16) U1.E23(D1_MDQ16)
DDR_DQ17: J1.22(DQ17) U1.E24(D1_MDQ17)
DDR_DQ18: J1.27(DQ18) U1.J23(D1_MDQ18)
DDR_DQ19: J1.28(DQ19) U1.K23(D1_MDQ19)
DDR_DQ20: J1.140(DQ20) U1.F22(D1_MDQ20)
DDR_DQ21: J1.141(DQ21) U1.H22(D1_MDQ21)
DDR_DQ22: J1.146(DQ22) U1.H23(D1_MDQ22)
DDR_DQ23: J1.147(DQ23) U1.J24(D1_MDQ23)
DDR_DQ24: J1.30(DQ24) U1.H26(D1_MDQ24)
DDR_DQ25: J1.31(DQ25) U1.J25(D1_MDQ25)
DDR_DQ26: J1.36(DQ26) U1.P26(D1_MDQ26)
DDR_DQ27: J1.37(DQ27) U1.N25(D1_MDQ27)
DDR_DQ28: J1.149(DQ28) U1.G25(D1_MDQ28)
DDR_DQ29: J1.150(DQ29) U1.H25(D1_MDQ29)
DDR_DQ30: J1.155(DQ30) U1.M26(D1_MDQ30)
DDR_DQ31: J1.156(DQ31) U1.M25(D1_MDQ31)
DDR_DQ32: J1.81(DQ32) U1.T25(D1_MDQ32)
DDR_DQ33: J1.82(DQ33) U1.U25(D1_MDQ33)
DDR_DQ34: J1.87(DQ34) U1.AA26(D1_MDQ34)
DDR_DQ35: J1.88(DQ35) U1.AA25(D1_MDQ35)
DDR_DQ36: J1.200(DQ36) U1.P25(D1_MDQ36)
DDR_DQ37: J1.201(DQ37) U1.R25(D1_MDQ37)
DDR_DQ38: J1.206(DQ38) U1.W26(D1_MDQ38)
DDR_DQ39: J1.207(DQ39) U1.Y25(D1_MDQ39)
DDR_DQ40: J1.90(DQ40) U1.V24(D1_MDQ40)
DDR_DQ41: J1.91(DQ41) U1.W23(D1_MDQ41)
DDR_DQ42: J1.96(DQ42) U1.AA22(D1_MDQ42)
DDR_DQ43: J1.97(DQ43) U1.AC22(D1_MDQ43)
DDR_DQ44: J1.209(DQ44) U1.W22(D1_MDQ44)
DDR_DQ45: J1.210(DQ45) U1.V23(D1_MDQ45)
DDR_DQ46: J1.215(DQ46) U1.AB24(D1_MDQ46)
DDR_DQ47: J1.216(DQ47) U1.AB23(D1_MDQ47)
DDR_DQ48: J1.99(DQ48) U1.AD26(D1_MDQ48)
DDR_DQ49: J1.100(DQ49) U1.AD25(D1_MDQ49)
DDR_DQ50: J1.105(DQ50) U1.AD23(D1_MDQ50)
DDR_DQ51: J1.106(DQ51) U1.AE22(D1_MDQ51)
DDR_DQ52: J1.218(DQ52) U1.AB25(D1_MDQ52)
DDR_DQ53: J1.219(DQ53) U1.AC25(D1_MDQ53)
DDR_DQ54: J1.224(DQ54) U1.AC23(D1_MDQ54)
DDR_DQ55: J1.225(DQ55) U1.AE23(D1_MDQ55)
DDR_DQ56: J1.108(DQ56) U1.AG25(D1_MDQ56)
DDR_DQ57: J1.109(DQ57) U1.AH25(D1_MDQ57)
DDR_DQ58: J1.114(DQ58) U1.AH22(D1_MDQ58)
DDR_DQ59: J1.115(DQ59) U1.AF22(D1_MDQ59)
DDR_DQ60: J1.227(DQ60) U1.AF26(D1_MDQ60)
DDR_DQ61: J1.228(DQ61) U1.AH26(D1_MDQ61)
DDR_DQ62: J1.233(DQ62) U1.AH23(D1_MDQ62)
DDR_DQ63: J1.234(DQ63) U1.AF23(D1_MDQ63)
DDR_ECC0: J1.39(CB0) U1.L24(D1_MECC0)
DDR_ECC1: J1.40(CB1) U1.N23(D1_MECC1)
DDR_ECC2: J1.45(CB2) U1.T23(D1_MECC2)
DDR_ECC3: J1.46(CB3) U1.U23(D1_MECC3)
DDR_ECC4: J1.158(CB4) U1.L23(D1_MECC4)
DDR_ECC5: J1.159(CB5) U1.M23(D1_MECC5)
DDR_ECC6: J1.164(CB6) U1.R24(D1_MECC6)
DDR_ECC7: J1.165(CB7) U1.T24(D1_MECC7)
DDR_MA0: J1.188(A0) U1.V28(D1_MA00)
DDR_MA1: J1.181(A1) U1.N28(D1_MA01)
DDR_MA2: J1.61(A2) U1.N27(D1_MA02)
DDR_MA3: J1.180(A3) U1.M28(D1_MA03)
DDR_MA4: J1.59(A4) U1.L27(D1_MA04)
DDR_MA5: J1.58(A5) U1.L28(D1_MA05)
DDR_MA6: J1.178(A6) U1.K28(D1_MA06)
DDR_MA7: J1.56(A7) U1.J28(D1_MA07)
DDR_MA8: J1.177(A8) U1.J27(D1_MA08)
DDR_MA9: J1.175(A9) U1.G27(D1_MA09)
DDR_MA10: J1.70(A10/AP) U1.Y27(D1_MA10)
DDR_MA11: J1.55(A11) U1.H28(D1_MA11)
DDR_MA12: J1.174(A12/B\C\) U1.G28(D1_MA12)
DDR_MA13: J1.196(A13) U1.AE28(D1_MA13)
DDR_MA14: J1.172(A14) U1.E27(D1_MA14)
DDR_MA15: J1.171(A15) U1.D28(D1_MA15)
DDR_MAPAR_ERR: J1.53(E\R\R\O\U\T\/NC) R4.2 U1.F28(D1_MAPAR_ERR_B)
DDR_MAPAR_OUT: J1.68(PARIN/NC) U1.V27(D1_MAPAR_OUT)
DDR_MBA0: J1.71(BA0) U1.Y28(D1_MBA0)
DDR_MBA1: J1.190(BA1) U1.W28(D1_MBA1)
DDR_MBA2: J1.52(BA2) U1.E28(D1_MBA2)
DDR_MCAS_N: J1.74(C\A\S\) U1.AC28(D1_MCAS_B)
DDR_MCK0_N: J1.185(C\K\0\) U1.T28(D1_MCK0_B)
DDR_MCK0_P: J1.184(CK0) U1.T27(D1_MCK0)
DDR_MCK1_N: J1.64(C\K\1\) U1.R28(D1_MCK1_B)
DDR_MCK1_P: J1.63(CK1) U1.R27(D1_MCK1)
DDR_MCKE0: J1.50(CKE0) Q37.3(D) U1.C27(D1_MCKE0)
DDR_MCKE1: J1.169(CKE1) Q38.3(D) U1.C28(D1_MCKE1)
DDR_MCS0_N: J1.193(S\0\) U1.AB28(D1_MCS0_B)
DDR_MCS1_N: J1.76(S\1\) U1.AC27(D1_MCS1_B)
DDR_MCS2_N: J1.79(S\2\/NC) U1.AG27(D1_MCS2_B)
DDR_MCS3_N: J1.198(S\3\/NC) U1.AF28(D1_MCS3_B)
DDR_MDM0: J1.125(DM0/DQS9) U1.B22(D1_MDM0)
DDR_MDM1: J1.134(DM1/DQS10) U1.C25(D1_MDM1)
DDR_MDM2: J1.143(DM2/DQS11) U1.F23(D1_MDM2)
DDR_MDM3: J1.152(DM3/DQS12) U1.K26(D1_MDM3)
DDR_MDM4: J1.203(DM4/DQS13) U1.U26(D1_MDM4)
DDR_MDM5: J1.212(DM5/DQS14) U1.Y24(D1_MDM5)
DDR_MDM6: J1.221(DM6/DQS15) U1.AD24(D1_MDM6)
DDR_MDM7: J1.230(DM7/DQS16) U1.AF24(D1_MDM7)
DDR_MDM8: J1.161(DM8/DQS17) U1.N24(D1_MDM8)
DDR_MDQS0_N: J1.6(D\Q\S\0\) U1.A23(D1_MDQS0_B)
DDR_MDQS0_P: J1.7(DQS0) U1.A24(D1_MDQS0)
DDR_MDQS1_N: J1.15(D\Q\S\1\) U1.D25(D1_MDQS1_B)
DDR_MDQS1_P: J1.16(DQS1) U1.D26(D1_MDQS1)
DDR_MDQS2_N: J1.24(D\Q\S\2\) U1.G23(D1_MDQS2_B)
DDR_MDQS2_P: J1.25(DQS2) U1.G24(D1_MDQS2)
DDR_MDQS3_N: J1.33(D\Q\S\3\) U1.K25(D1_MDQS3_B)
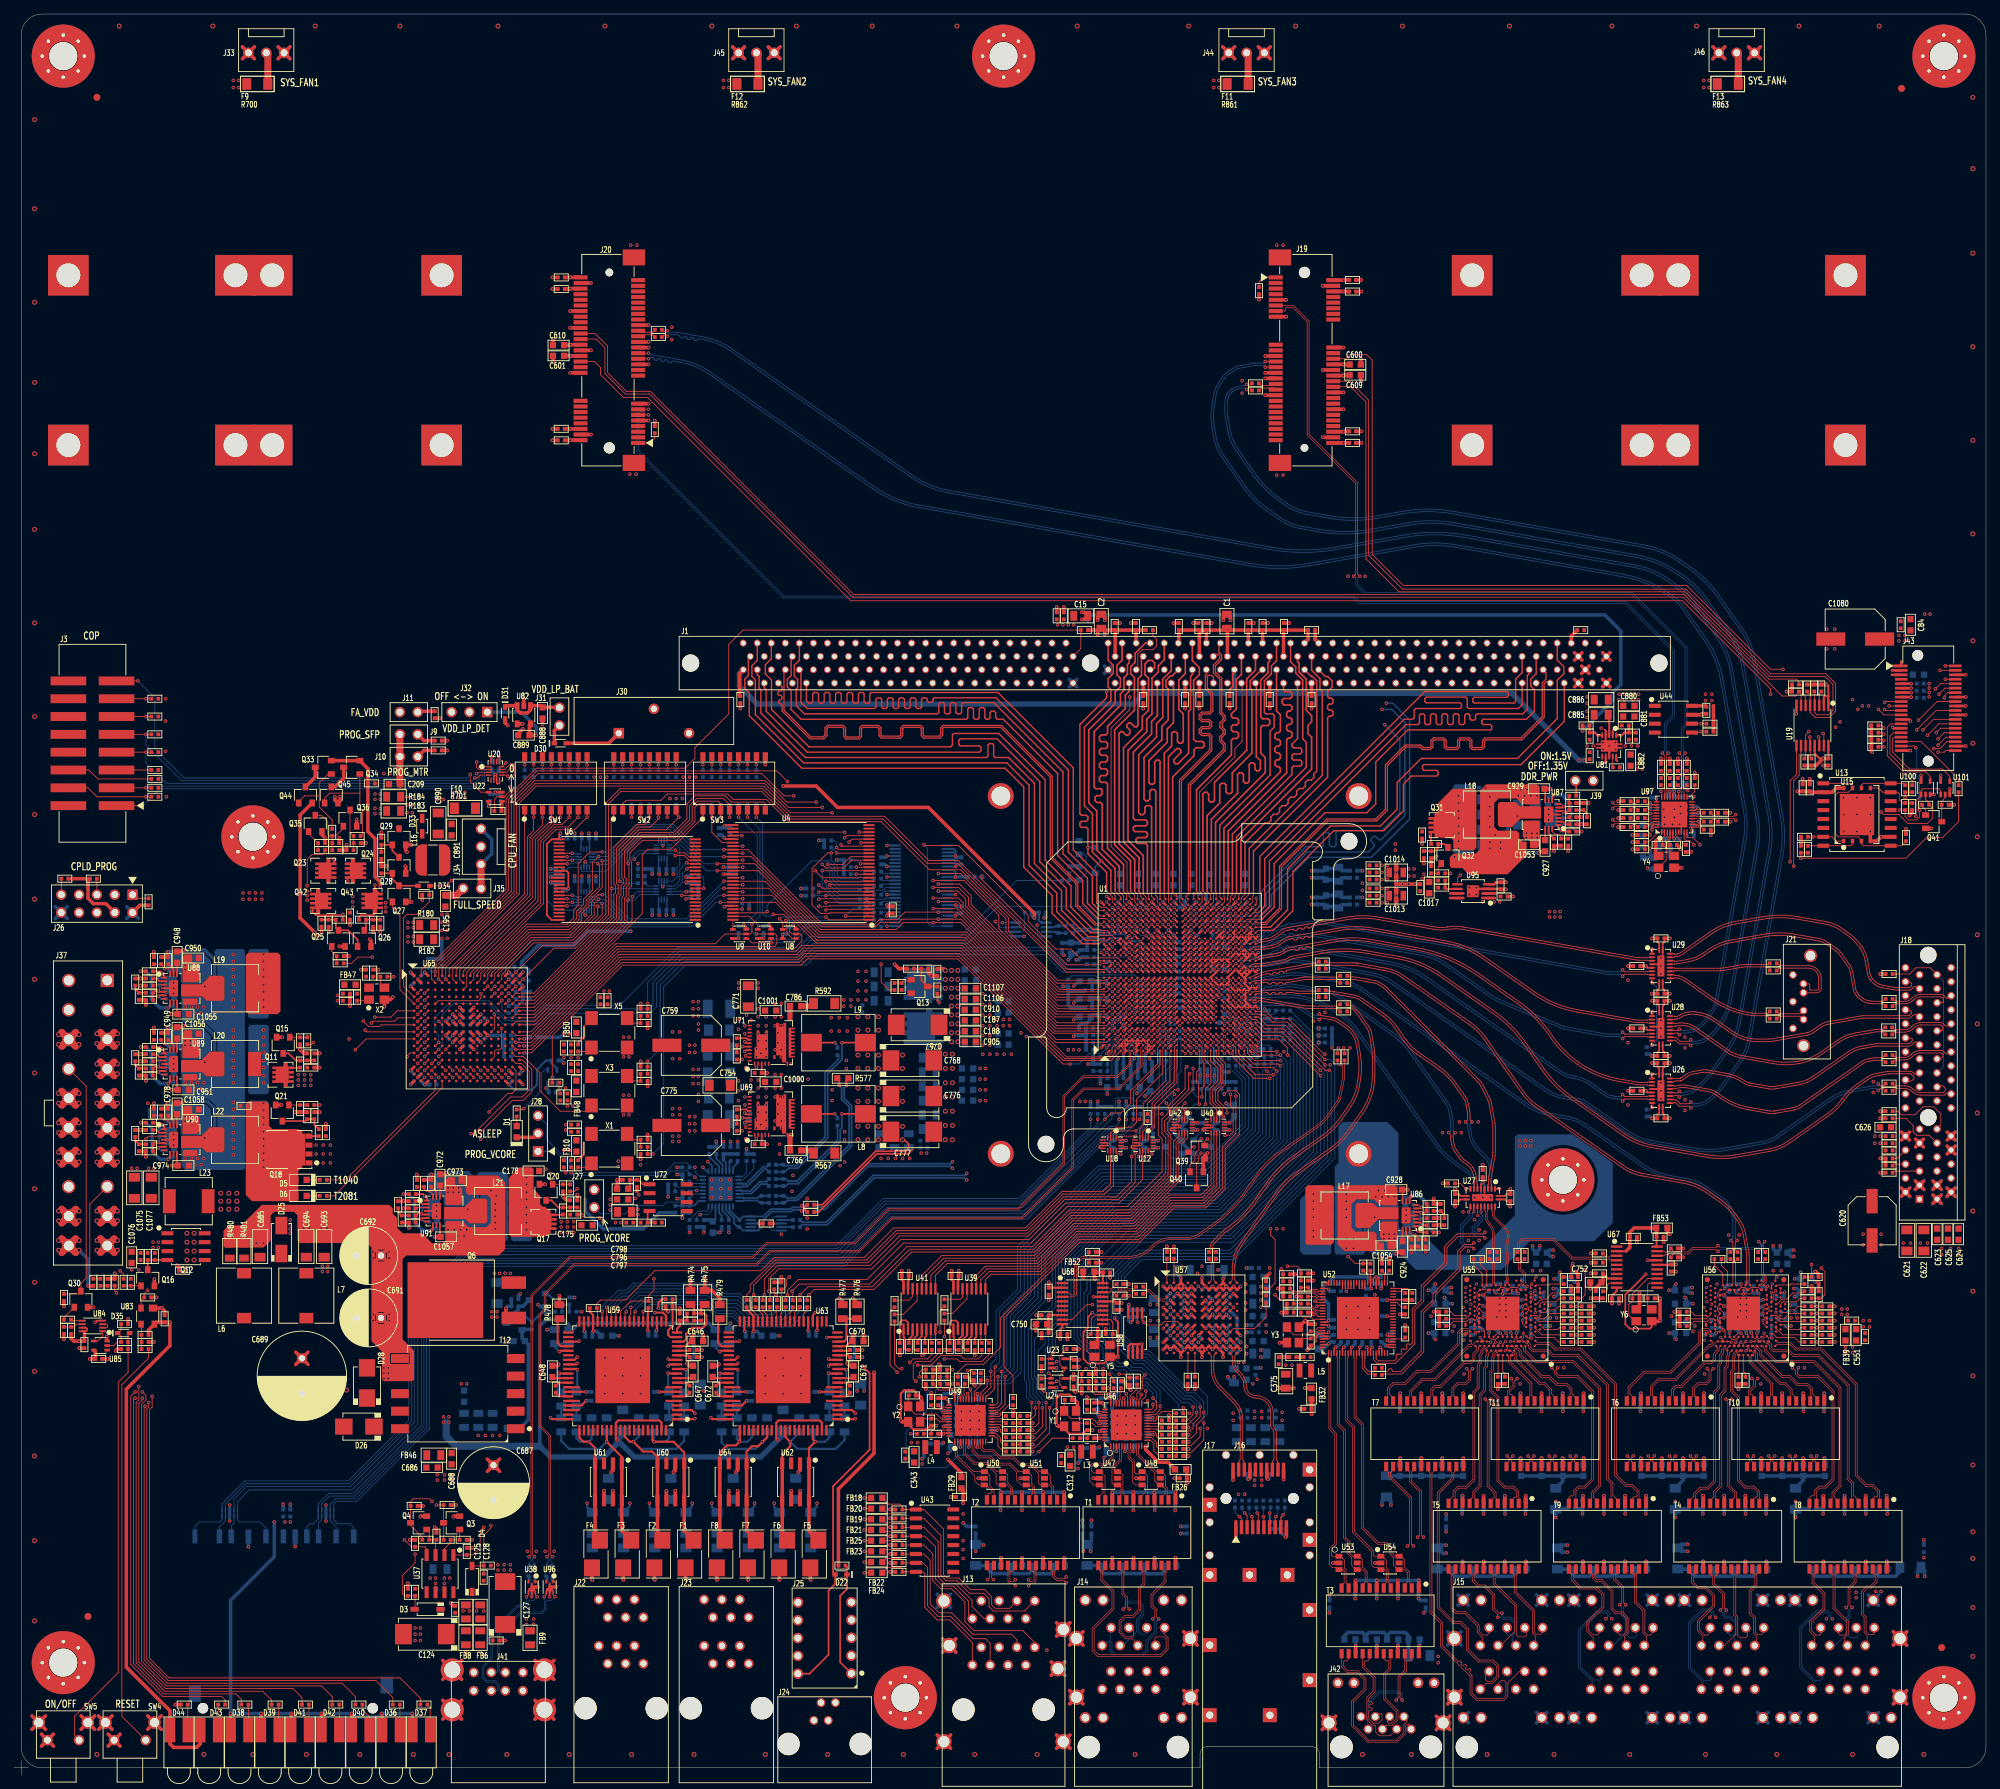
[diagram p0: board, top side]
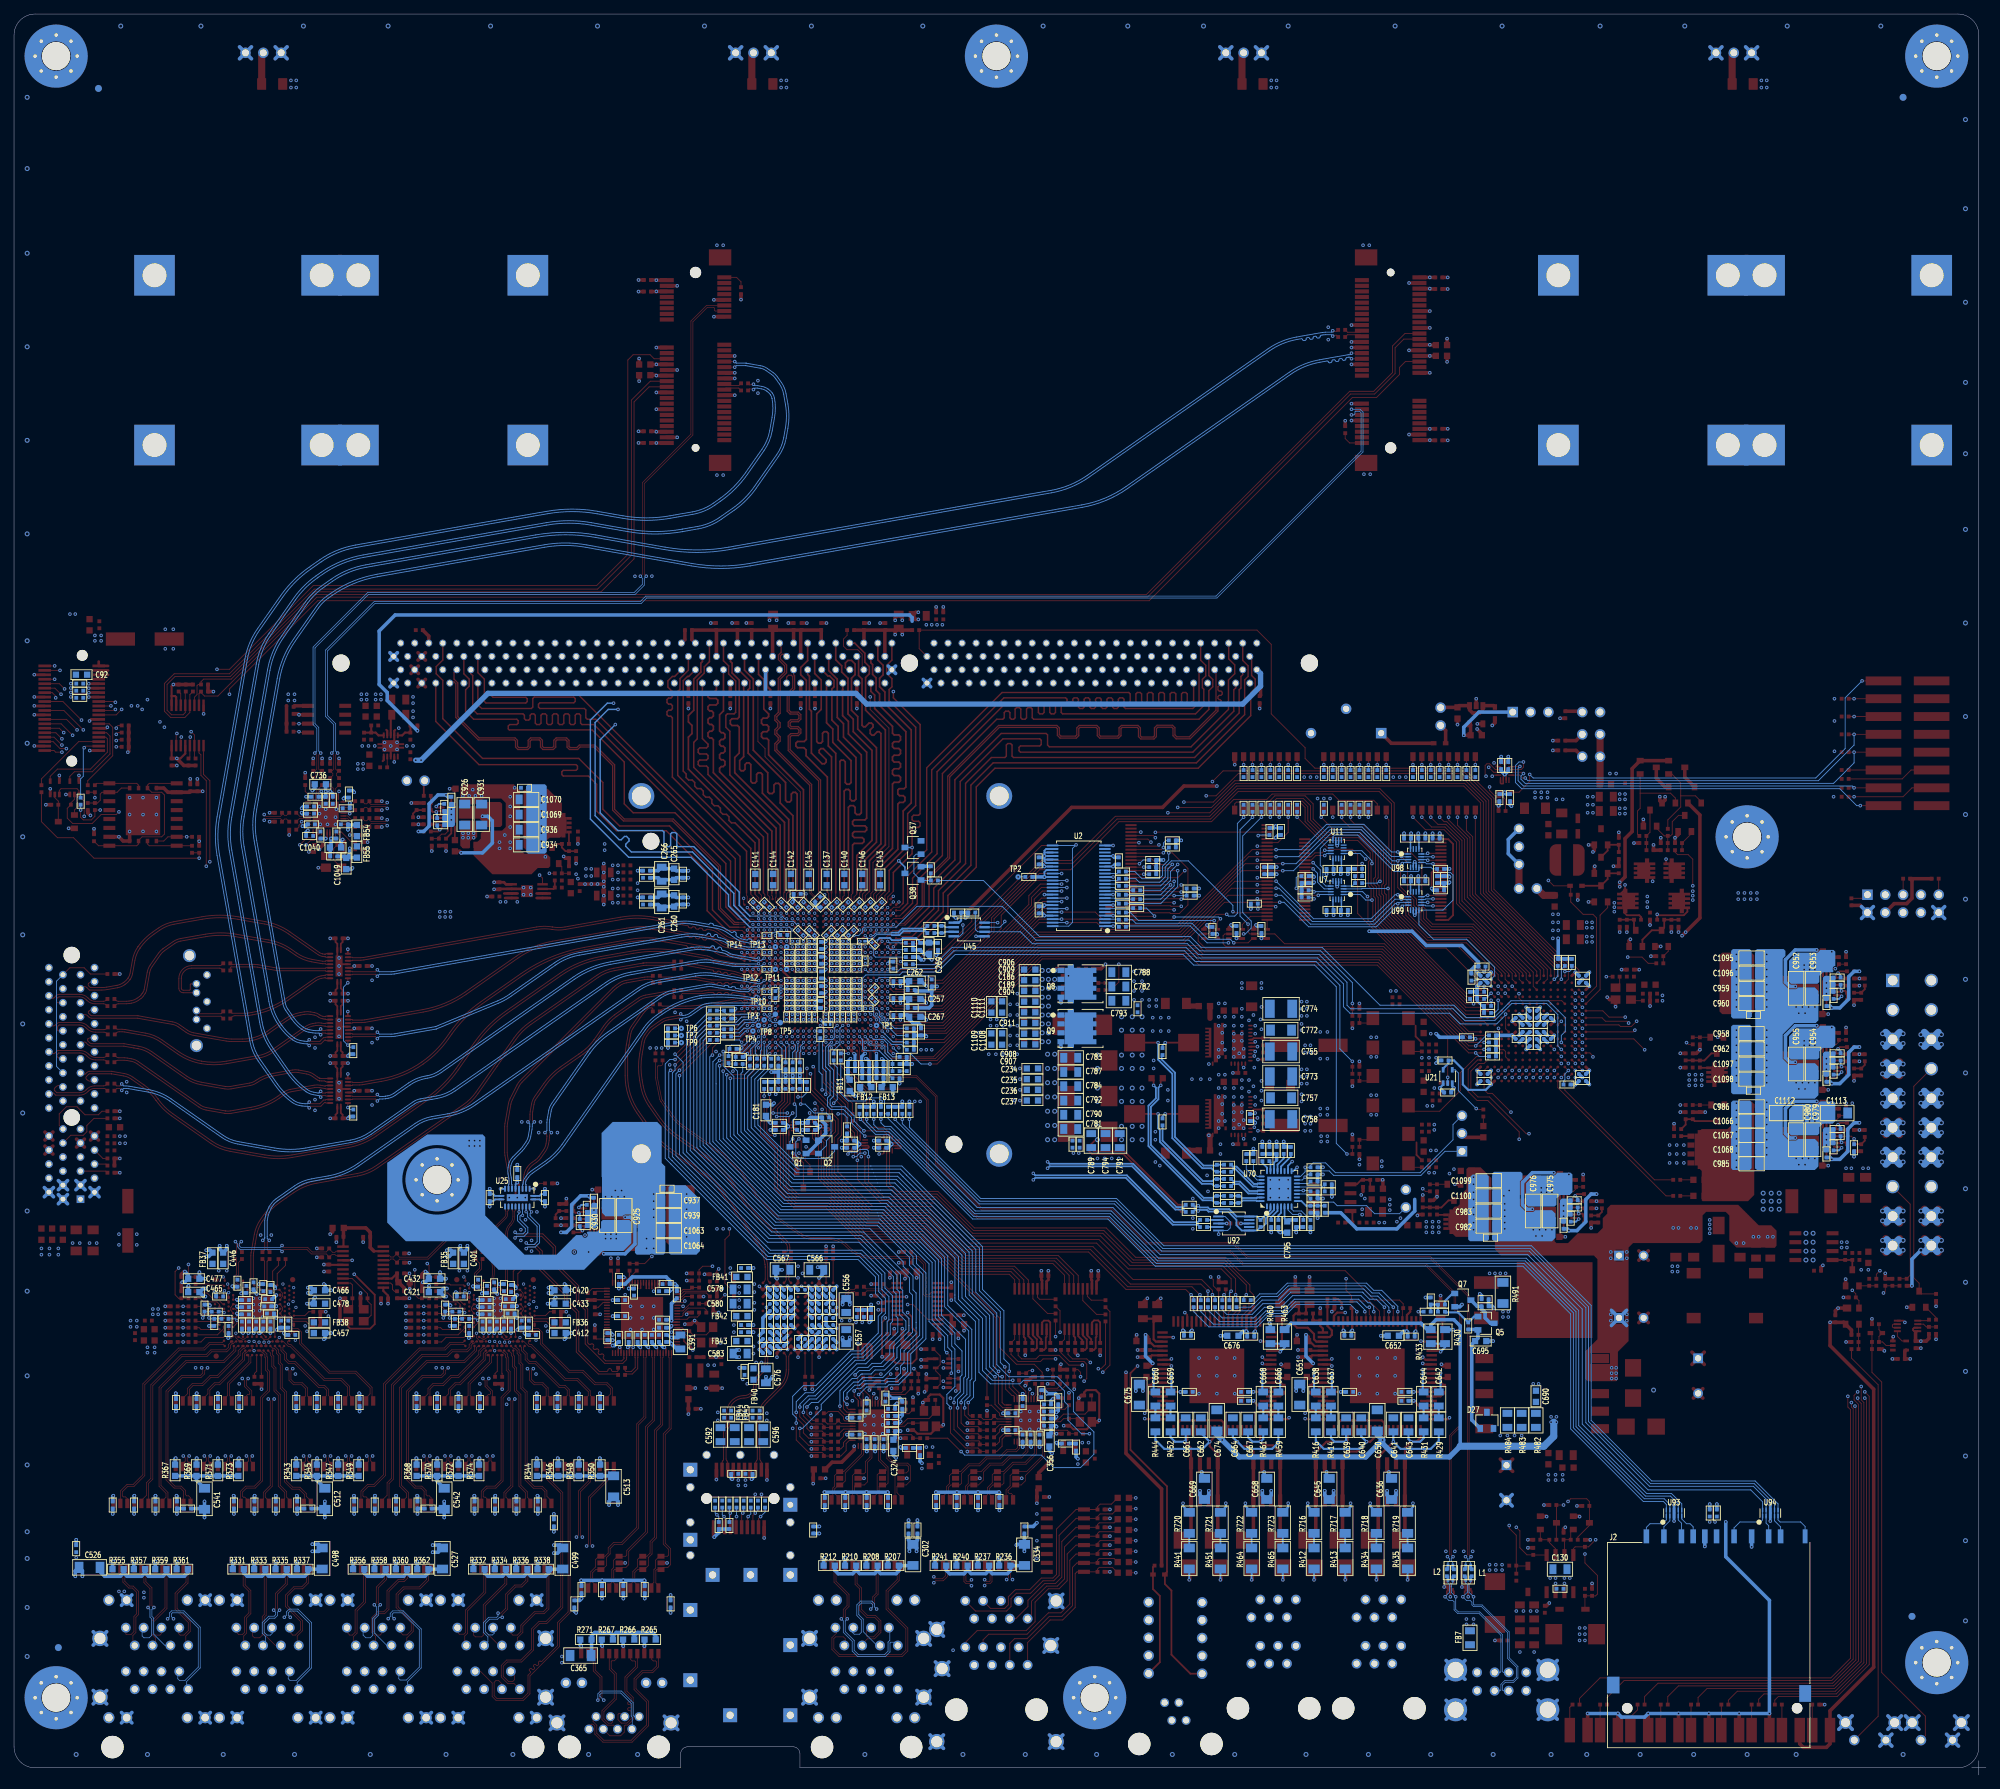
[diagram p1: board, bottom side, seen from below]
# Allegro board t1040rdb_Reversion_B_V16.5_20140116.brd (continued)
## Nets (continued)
DDR_MDQS3_P: J1.34(DQS3) U1.L25(D1_MDQS3)
DDR_MDQS4_N: J1.84(D\Q\S\4\) U1.V25(D1_MDQS4_B)
DDR_MDQS4_P: J1.85(DQS4) U1.W25(D1_MDQS4)
DDR_MDQS5_N: J1.93(D\Q\S\5\) U1.Y23(D1_MDQS5_B)
DDR_MDQS5_P: J1.94(DQS5) U1.AA23(D1_MDQS5)
DDR_MDQS6_N: J1.102(D\Q\S\6\) U1.AF25(D1_MDQS6_B)
DDR_MDQS6_P: J1.103(DQS6) U1.AE25(D1_MDQS6)
DDR_MDQS7_N: J1.111(D\Q\S\7\) U1.AH24(D1_MDQS7_B)
DDR_MDQS7_P: J1.112(DQS7) U1.AG24(D1_MDQS7)
DDR_MDQS8_N: J1.42(D\Q\S\8\) U1.P23(D1_MDQS8_B)
DDR_MDQS8_P: J1.43(DQS8) U1.R23(D1_MDQS8)
DDR_MODT0: J1.195(ODT0) U1.AD28(D1_MODT0)
DDR_MODT1: J1.77(ODT1) U1.AE27(D1_MODT1)
DDR_MRAS_N: J1.192(R\A\S\) U1.AA28(D1_MRAS_B)
DDR_MWE_N: J1.73(W\E\) U1.AB27(D1_MWE_B)
DDR_REFCLK: R517.2 R518.2 U1.J21(DDRCLK)
DDR_RST_N: J1.168(R\E\S\E\T\) R2.2 U65.A2(IO_B2_A2)
DDRPWR_EN_N: R785.1 U65.R4(IO_B1_R4)
DIFSYSCLK_OE_N: R844.2 U65.N15(IO_B2_N15) U97.38(O\E\5\)
EARTH: C302.2 C306.2 C310.2 C334.2 C336.2 C342.2 C365.2 C368.2 C371.2 C498.1 C499.1 C512.1 C513.1 C526.1 C527.1 C541.1 C542.1 C544.2 C545.2 C548.2 C550.2 C553.2 J13.17 J13.18 J13.19 J13.20 J13.21 J13.22 J14.25 J14.26 J14.27 J14.28 J15.97 J15.98 J15.99 J15.100 J17.1(MH1) J17.2(MH2) J17.3(MH3) J17.4(MH4) J17.5(MH5) J17.6(MH6) J17.7(MH7) J17.8(MH8) J17.9(MH9) J17.10(MH10) J17.11(MH11) J17.12(MH12) J17.13(MH13) J17.14(MH14) J17.15(MH15) J17.16(MH16) J17.17(MH17) J17.18(MH18) J17.20(MH20) J41.9 J41.10 J41.11 J41.12 J42.13 J42.14 Z107.1 Z107.2 Z107.3 Z107.4 Z107.5 Z107.6 Z107.7 Z107.8 Z108.1 Z108.2 Z108.3 Z108.4 Z108.5 Z108.6 Z108.7 Z108.8
EC1_GTXCLK: R127.1 U49.22(TXC)
EC1_INT_N: R75.1 R250.2 U1.AB4(IRQ06)
EC1_LED0: R247.1 R262.1 U49.34(LED0/PHY_AD0)
EC1_LED1: R248.1 R263.1 U49.35(LED1/PHY_AD1)
EC1_MDI0_N: T2.11 U49.2(MDI-[0]) U50.1
EC1_MDI0_P: T2.12 U49.1(MDI+[0]) U50.3
EC1_MDI1_N: T2.8 U49.5(MDI-[1]) U50.6
EC1_MDI1_P: T2.9 U49.4(MDI+[1]) U50.4
EC1_MDI2_N: T2.5 U49.8(MDI-[2]) U51.1
EC1_MDI2_P: T2.6 U49.7(MDI+[2]) U51.3
EC1_MDI3_N: T2.2 U49.11(MDI-[3]) U51.6
EC1_MDI3_P: T2.3 U49.10(MDI+[3]) U51.4
EC1_MDX0_N: J14.B2 T2.14
EC1_MDX0_P: J14.B1 T2.13
EC1_MDX1_N: J14.B6 T2.17
EC1_MDX1_P: J14.B3 T2.16
EC1_MDX2_N: J14.B5 T2.20
EC1_MDX2_P: J14.B4 T2.19
EC1_MDX3_N: J14.B8 T2.23
EC1_MDX3_P: J14.B7 T2.22
EC1_PME_N: R76.1 R251.2 U1.AD5(IRQ07)
EC1_REFCLK: R246.2 U1.AG3(EC1_GTX_CLK125)
EC1_RST_N: R249.1 R252.2 U65.H3(IO_B1_H3)
EC1_RXCLK: R238.1 U1.AD1(EC1_RX_CLK)
EC1_RXCTL: R245.1 R261.1 U1.AG2(EC1_RX_CTL)
EC1_RXD0: R239.1 R257.1 U1.AF2(EC1_RXD0)
EC1_RXD1: R242.1 R258.1 U1.AF1(EC1_RXD1)
EC1_RXD2: R243.1 R259.1 U1.AE1(EC1_RXD2)
EC1_RXD3: R244.1 R260.1 U1.AD2(EC1_RXD3)
EC1_RXDLY: R264.1 U49.32(LED2/RXDLY)
EC1_TXCTL: R125.1 U49.27(TXCTL)
EC1_TXD0: R115.1 U49.23(TXD0)
EC1_TXD1: R116.1 U49.24(TXD1)
EC1_TXD2: R119.1 U49.25(TXD2)
EC1_TXD3: R121.1 U49.26(TXD3)
EC2_GTXCLK: R128.2 U46.22(TXC)
EC2_INT_N: R79.1 R221.2 U1.L4(IRQ10)
EC2_LED0: R218.1 R233.1 U46.34(LED0/PHY_AD0)
EC2_LED1: R219.1 R234.1 U46.35(LED1/PHY_AD1)
EC2_MDI0_N: T1.11 U46.2(MDI-[0]) U47.1
EC2_MDI0_P: T1.12 U46.1(MDI+[0]) U47.3
EC2_MDI1_N: T1.8 U46.5(MDI-[1]) U47.6
EC2_MDI1_P: T1.9 U46.4(MDI+[1]) U47.4
EC2_MDI2_N: T1.5 U46.8(MDI-[2]) U48.1
EC2_MDI2_P: T1.6 U46.7(MDI+[2]) U48.3
EC2_MDI3_N: T1.2 U46.11(MDI-[3]) U48.6
EC2_MDI3_P: T1.3 U46.10(MDI+[3]) U48.4
EC2_MDX0_N: J14.A2 T1.14
EC2_MDX0_P: J14.A1 T1.13
EC2_MDX1_N: J14.A6 T1.17
EC2_MDX1_P: J14.A3 T1.16
EC2_MDX2_N: J14.A5 T1.20
EC2_MDX2_P: J14.A4 T1.19
EC2_MDX3_N: J14.A8 T1.23
EC2_MDX3_P: J14.A7 T1.22
EC2_PME_N: R80.1 R222.2 U1.U3(IRQ11)
EC2_REFCLK: R217.2 U1.AC6(EC2_GTX_CLK125)
EC2_RST_N: R220.1 R823.2 U65.J2(IO_B1_J2)
EC2_RXCLK: R211.1 U1.AH5(EC2_RX_CLK)
EC2_RXCTL: R216.1 R232.1 U1.AG8(EC2_RX_CTL)
EC2_RXD0: R209.1 R228.1 U1.AH8(EC2_RXD0)
EC2_RXD1: R213.1 R229.1 U1.AG7(EC2_RXD1)
EC2_RXD2: R214.1 R230.1 U1.AH7(EC2_RXD2)
EC2_RXD3: R215.1 R231.1 U1.AH6(EC2_RXD3)
EC2_RXDLY: R235.1 U46.32(LED2/RXDLY)
EC2_TXCTL: R126.2 U46.27(TXCTL)
EC2_TXD0: R117.2 U46.23(TXD0)
EC2_TXD1: R118.2 U46.24(TXD1)
EC2_TXD2: R120.2 U46.25(TXD2)
EC2_TXD3: R122.2 U46.26(TXD3)
EMI1_MDC: U23.2(B) U46.30(MDC) U52.72(MDC) U55.C11(MDC) U56.C11(MDC)
EMI1_MDC_SLP: R129.1 R132.2 U23.1(A) U49.30(MDC)
EMI1_MDIO: U24.2(B) U46.31(MDIO) U52.73(MDIO) U55.D10(MDIO) U56.D10(MDIO)
EMI1_MDIO_SLP: R131.2 U1.AH4(EMI1_MDIO) U24.1(A) U49.31(MDIO)
EMI2_MDC: R130.2 R134.2 U57.G1(MDC)
EMI2_MDIO: R133.2 U1.M6(EMI2_MDIO) U57.F1(MDIO)
EVDD: C185.1 Q33.2(S) Q34.2(S) R60.2 R62.2 R63.2 R64.2 R67.2 R68.2 R815.2 U1.L8(EVDD1)
EVDD_SEL: R820.1 U65.F1(IO_B1_F1)
EVT_BRD_ISO: R81.1 U1.A3(IRQ_OUT_B) U65.K16(IO_B2_K16)
EVT_PWR_EN: R85.1 U1.C1(EVT2_B) U65.L15(IO_B2_L15)
EVT_PWR_OK: R813.1 U1.C2(EVT3_B) U65.L16(IO_B2_L16)
FAN_PWM: Q27.1(G) U65.E1(IO_B1_E1)
FXO_LED: R470.1 U65.F3(IO_B1_F3)
FXO_RING: J24.2 J25.2
FXO_TIP: J24.3 J25.9
FXS1_LED: R439.1 U65.E2(IO_B1_E2)
FXS2_LED: R440.1 U65.D3(IO_B1_D3)
FXS3_LED: R471.1 U65.F2(IO_B1_F2)
FXS4_LED: R472.1 U65.E3(IO_B1_E3)
FXS_RING: J23.A3 J25.3
FXS_TIP: J23.A4 J25.8
GPIO_CKE_ISO: R78.1 U1.AC5(IRQ09) U65.P13(IO_B1_P13)
HRESET_N: R96.2 U1.E8(HRESET_B) U65.D14(IO_B2_D14)
I2C1_SCL: J1.118(SCL) Q1.3(D) Q39.2(S) R91.1 U44.6(SCL) U45.8(SCLK)
I2C1_SCL_SLP: J28.3 Q39.3(D) R570.2 U70.16(SM_CLK) U97.9(SCLK_3.3)
I2C1_SDA: J1.238(SDA) Q2.3(D) Q40.2(S) R90.1 U44.5(SDA) U45.7(SDATA)
I2C1_SDA_SLP: J28.1 Q40.3(D) R569.2 U70.15(SM_DIO) U97.10(SDATA_3.3)
I2C2_MPEX1_SCL: J19.30(SMB_CLK) R398.1 U19.5(SC0)
I2C2_MPEX1_SDA: J19.32(SMB_DATA) R404.1 U19.4(SD0)
I2C2_MPEX2_SCL: J20.30(SMB_CLK) R409.1 U19.7(SC1)
I2C2_MPEX2_SDA: J20.32(SMB_DATA) R410.1 U19.6(SD1)
I2C2_PEX_SCL: J18.B5(SMCLK) R406.1 U19.12(SC3)
I2C2_PEX_SDA: J18.B6(SMDAT) R407.1 U19.11(SD3)
I2C2_SFPP_SCL: J16.5(MOD_DEF(1)/SCL) R392.1 U19.10(SC2)
I2C2_SFPP_SDA: J16.4(MOD_DEF(2)/SDA) R391.1 U19.9(SD2)
IFC_A5: R14.2 U10.1(I0)
IFC_A6: R15.2 U9.1(I0)
IFC_A7: R16.2 U8.1(I0)
IFC_A8: R18.2 U4.2(A22)
IFC_A9: R20.2 U4.15(A21)
IFC_A10: R22.2 U4.12(A20)
IFC_A11: R24.2 U4.11(A19)
IFC_A12: R26.2 U4.18(A18)
IFC_A13: R28.2 U4.19(A17)
IFC_A14: R30.2 U4.54(A16)
IFC_A15: R32.2 U4.3(A15)
IFC_A16: R797.2 SW2.5 U1.C5(IFC_A16) U4.4(A14) U65.D16(IO_B2_D16)
IFC_A17: R798.2 SW2.6 U1.C6(IFC_A17) U4.5(A13) U65.E15(IO_B2_E15)
IFC_A18: R799.2 SW2.3 U1.D7(IFC_A18) U4.6(A12)
IFC_A19: R800.2 SW2.4 U1.C7(IFC_A19) U4.7(A11)
IFC_A20: R13.2 R864.2 U1.D8(IFC_A20) U4.8(A10)
IFC_A21: SW2.7 U1.C8(IFC_A21) U4.9(A9)
IFC_A22: U1.D9(IFC_A22) U4.10(A8)
IFC_A23: R810.2 U1.C9(IFC_A23) U4.20(A7)
IFC_A24: R809.2 U1.D10(IFC_A24) U4.21(A6)
IFC_A25: U1.C10(IFC_A25) U4.22(A5)
IFC_A26: U1.E11(IFC_A26) U4.23(A4)
IFC_A27: U1.C11(IFC_A27) U4.24(A3) U65.C13(IO_B2_C13)
IFC_A28: U1.D11(IFC_A28) U4.25(A2) U65.C12(IO_B2_C12)
IFC_A29: U1.C12(IFC_A29) U4.26(A1) U65.C11(IO_B2_C11)
IFC_A30: U1.D12(IFC_A30) U4.31(A0) U65.D12(IO_B2_D12)
IFC_A31: U1.E12(IFC_A31) U65.A5(IO_B2_A5)
IFC_AD0: U1.A4(IFC_AD00) U4.51(DQ15/A-1) U65.A13(IO_B2_A13) U99.4(A4)
IFC_AD1: U1.B5(IFC_AD01) U4.49(DQ14) U65.B13(IO_B2_B13) U99.3(A3)
IFC_AD2: U1.A5(IFC_AD02) U4.47(DQ13) U65.B12(IO_B2_B12) U99.2(A2)
IFC_AD3: U1.B6(IFC_AD03) U4.45(DQ12) U65.A12(IO_B2_A12) U99.1(A1)
IFC_AD4: U1.A6(IFC_AD04) U4.42(DQ11) U65.A11(IO_B2_A11) U98.4(A4)
IFC_AD5: U1.A7(IFC_AD05) U2.47(1D1) U4.40(DQ10) U65.B11(IO_B2_B11) U98.3(A3)
IFC_AD6: U1.B8(IFC_AD06) U2.46(1D2) U4.38(DQ9) U65.B10(IO_B2_B10) U98.2(A2)
IFC_AD7: U1.A8(IFC_AD07) U2.44(1D3) U4.36(DQ8) U65.A10(IO_B2_A10) U98.1(A1)
IFC_AD8: SW1.1 U1.B9(IFC_AD08) U2.43(1D4) U4.50(DQ7) U65.A6(IO_B2_A6)
IFC_AD9: SW1.2 U1.A9(IFC_AD09) U2.41(1D5) U4.48(DQ6) U65.B7(IO_B2_B7)
IFC_AD10: SW1.3 U1.A10(IFC_AD10) U2.40(1D6) U4.46(DQ5) U65.A7(IO_B2_A7)
IFC_AD11: SW1.4 U1.B11(IFC_AD11) U2.38(1D7) U4.44(DQ4) U65.B8(IO_B2_B8)
IFC_AD12: SW1.5 U1.A11(IFC_AD12) U2.37(1D8) U4.41(DQ3) U65.A8(IO_B2_A8)
IFC_AD13: SW1.6 U1.B12(IFC_AD13) U2.36(2D1) U4.39(DQ2) U65.C8(IO_B2_C8)
IFC_AD14: SW1.7 U1.A12(IFC_AD14) U2.35(2D2) U4.37(DQ1) U65.A9(IO_B2_A9)
IFC_AD15: SW1.8 U1.A13(IFC_AD15) U2.33(2D3) U4.35(DQ0) U65.B9(IO_B2_B9)
IFC_AVD: R49.1 R801.1 SW2.8 U1.D17(IFC_AVD) U2.25(LE2) U2.48(LE1)
IFC_CLE: SW2.1 U1.F16(IFC_CLE) U7.3(A3) U65.D15(IO_B2_D15)
IFC_CLK: R12.2 U65.J12(GCLK2P)
IFC_CS0_N: R11.1 U1.C13(IFC_CS0_B) U65.B6(IO_B2_B6)
IFC_CS1_N: R10.1 U1.E15(IFC_CS1_B) U65.B5(IO_B2_B5)
IFC_CS2_N: R9.1 U1.D16(IFC_CS2_B) U65.A4(IO_B2_A4)
IFC_LATCH_N: R808.2 U7.8(O\E\) U11.8(O\E\) U65.B14(IO_B2_B14) U98.8(O\E\) U99.8(O\E\)
IFC_NDWE_N: U1.D14(IFC_NDDDR_CLK) U11.1(A1)
IFC_OE_N: R803.1 SW3.2 U1.D15(IFC_OE_B) U4.34(O\E\) U7.1(A1) U65.G15(IO_B2_G15)
IFC_PAR1: R50.1 R812.1 U1.C14(IFC_PAR1)
IFC_RB0_N: R7.1 U1.B15(IFC_RB0_B) U65.A15(IO_B2_A15)
IFC_RB1_N: R6.1 U1.A15(IFC_RB1_B) U65.B16(IO_B2_B16)
IFC_TE: SW2.2 U1.B14(IFC_TE)
IFC_VA5: U4.55(A25) U10.4(O)
IFC_VA6: U4.56(A24) U9.4(O)
IFC_VA7: U4.1(A23) U8.4(O)
IFC_WE_N: R804.1 SW3.1 U1.D13(IFC_WE0_B) U4.13(W\E\) U65.H15(IO_B2_H15)
IFC_WP_N: R802.1 SW3.3 U1.F17(IFC_WP0_B) U11.2(A2) U65.F16(IO_B2_F16)
IO_B1: U65.B1(IO_B2_B1)
IO_B3: U65.B3(IO_B2_B3)
IO_C4: U65.C4(IO_B2_C4)
IO_C5: U65.C5(IO_B2_C5)
IO_C6: U65.C6(IO_B2_C6)
IO_C7: U65.C7(IO_B2_C7)
IO_C9: U65.C9(IO_B2_C9)
IO_C10: U65.C10(IO_B2_C10)
IO_D4: U65.D4(IO_B2_D4)
IO_D5: U65.D5(IO_B2_D5)
IO_D11: U65.D11(IO_B2_D11)
IO_F13: U65.F13(IO_B2_F13)
IO_F14: U65.F14(IO_B2_F14)
IO_G14: U65.G14(IO_B2_G14)
IO_H14: U65.H14(IO_B2_H14)
IO_J14: U65.J14(IO_B2_J14)
IO_K14: U65.K14(IO_B2_K14)
IO_L1: U65.L1(IO_B1_L1)
IO_L13: U65.L13(IO_B2_L13)
IO_L14: U65.L14(IO_B2_L14)
IO_M13: U65.M13(IO_B2_M13)
IO_M14: U65.M14(IO_B2_M14)
IO_N1: U65.N1(IO_B1_N1)
IO_N13: U65.N13(IO_B2_N13)
IO_N14: U65.N14(IO_B2_N14)
IO_P14: U65.P14(IO_B2_P14)
IO_R1: U65.R1(IO_B1_R1)
IO_R16: U65.R16(IO_B1_R16)
IO_T6: U65.T6(IO_B1_T6)
IO_T7: U65.T7(IO_B1_T7)
IO_T8: U65.T8(IO_B1_T8)
IO_T9: U65.T9(IO_B1_T9)
IO_T10: U65.T10(IO_B1_T10)
IO_T11: U65.T11(IO_B1_T11)
IO_T12: U65.T12(IO_B1_T12)
IO_T13: U65.T13(IO_B1_T13)
IO_T15: U65.T15(IO_B1_T15)
IOPWR_EN: C938.2 C956.2 R670.1 R732.2 R750.2 U65.R8(IO_B1_R8) U86.16(EN) U88.16(EN)
IOPWR_EN_N: R666.1 R681.1 R682.1 U65.P10(IO_B1_P10)
JTAG_TCK: U1.E18(TCK) U20.10(B3)
JTAG_TDI: U1.A18(TDI) U20.12(B1)
JTAG_TDO: U1.C18(TDO) U20.11(B2)
JTAG_TMS: U1.B18(TMS) U20.9(B4)
JTAG_TRST_N: U1.D19(TRST_B) U65.B4(IO_B2_B4)
LED_STATUS: R702.1 U65.D2(IO_B1_D2)
LED_T1040_DET: R186.1 U65.T4(IO_B1_T4)
LED_T2081_DET: R187.1 U65.T5(IO_B1_T5)
LIFELINE: D22.2 J25.10 U63.24(I/O11)
LP_TMPDET_N: J32.2 U1.R6(LP_TMP_DETECT_B)
MPEX1_REFCLK_N: J19.13(REFCLK+) R526.2 R528.2
MPEX1_REFCLK_P: J19.11(REFCLK-) R524.2 R525.2
MPEX1_RST_N: J19.22(P\E\R\S\T\) U65.T2(IO_B1_T2)
MPEX1_RX_N: J19.23(PERN0) U26.15(C0+)
MPEX1_RX_P: J19.25(PERP0) U26.14(C0-)
MPEX1_TX_N: C599.2 U26.13(C1+)
MPEX1_TX_P: C598.2 U26.12(C1-)
MPEX2_REFCLK_N: J20.13(REFCLK+) R532.2 R534.1
MPEX2_REFCLK_P: J20.11(REFCLK-) R527.1 R530.2
MPEX2_RST_N: J20.22(P\E\R\S\T\) U65.R3(IO_B1_R3)
MPEX2_RX_N: J20.23(PERN0) U28.15(C0+)
MPEX2_RX_P: J20.25(PERP0) U28.14(C0-)
MPEX2_TX_N: C631.2 U28.13(C1+)
MPEX2_TX_P: C630.2 U28.12(C1-)
MVREF: C18.1 C19.1 C21.1 C22.1 C883.1 J1.1(VREFDQ) J1.67(VREFCA) U1.F20(D1_MVREF) U81.6(REFOUT)
NAND_CS_N: U7.2(A2) U65.G16(IO_B2_G16)
NAND_IO0: U6.29(IO0) U98.12(B1)
NAND_IO1: U6.30(IO1) U98.11(B2)
NAND_IO2: U6.31(IO2) U98.10(B3)
NAND_IO3: U6.32(IO3) U98.9(B4)
NAND_IO4: U6.41(IO4) U99.12(B1)
NAND_IO5: U6.42(IO5) U99.11(B2)
NAND_IO6: U6.43(IO6) U99.10(B3)
NAND_IO7: U6.44(IO7) U99.9(B4)
NAND_RB_N: R48.1 U6.7(R/B\1\) U65.E4(IO_B1_E4)
NOR_CS_N: R43.1 U4.32(C\E\) U65.D13(IO_B2_D13)
NOR_RST_N: R47.1 U4.14(R\E\S\E\T\) U65.C14(IO_B2_C14)
OVDD: C23.1 C24.1 C25.1 C26.1 C30.1 C31.1 C32.1 C35.1 C40.1 C42.1 C50.1 C53.1 C184.1 C195.1 C196.1 C197.1 C198.1 C199.1 C232.1 C729.1 C730.1 C1011.1 C1012.1 C1059.1 C1061.1 C1071.1 C1073.1 FB50.1 R5.2 R6.2 R7.2 R9.2 R10.2 R11.2 R41.2 R42.2 R43.2 R44.2 R47.2 R65.2 R66.2 R79.2 R81.2 R82.2 R102.2 R180.2 R182.2 R188.1 R191.1 R502.1 R504.1 R506.1 R508.1 R797.1 R798.1 R799.1 R800.1 R801.2 R802.2 R803.2 R804.2 R808.1 R864.1 U1.G9(TH_VDD) U1.J14(OVDD1) U1.J15(OVDD2) U1.J16(OVDD3) U1.J17(OVDD4) U1.J18(OVDD5) U1.J19(OVDD6) U1.M8(CVDD1) U2.7(VCC#7) U2.18(VCC#18) U2.31(VCC#31) U2.42(VCC#42) U4.29(VIO) U7.16(VCCA) U8.5(VCC) U9.5(VCC) U10.5(VCC) U11.16(VCCA) U12.16(VCCA) U18.16(VCCA) U20.13(VCCB) U22.1(VCC1) U98.16(VCCA) U99.16(VCCA)
OVDD_OSC_DDR: C731.1 C732.1 FB50.2 R516.1 X5.4(VDD)
OVDD_OSC_SYS: C722.1 C723.1 FB48.2 X3.4(VDD)
OVDD_OSC_USB: C135.1 C136.1 FB10.2 R174.1 X1.4(VDD)
OVDD_SLP: C52.1 C133.1 C134.1 C209.1 C210.1 C211.1 C220.1 C711.1 C712.1 C713.1 C714.1 C715.1 C716.1 C720.1 C721.1 C1104.1 C1105.1 FB10.1 FB13.2 FB48.1 J9.2 J10.2 R69.2 R70.2 R71.2 R72.2 R73.2 R74.2 R83.2 R84.2 R85.2 R94.1 R96.1 R98.1 R101.2 R183.2 R184.2 R194.1 R195.1 R813.2 U1.J11(O1VDD1) U1.J12(O1VDD2) U1.J13(O1VDD3) U21.1(VCC1) U65.A3(VCCIO2#A3) U65.A14(VCCIO2#A14) U65.C16(VCCIO2#C16) U65.F8(VCCIO2#F8) U65.F9(VCCIO2#F9) U65.H11(VCCIO2#H11) U65.J11(VCCIO2#J11) U65.P16(VCCIO2#P16)
PEX2_SEL_N: R142.2 U26.9(SEL) U65.P6(IO_B1_P6)
PEX4_SEL_N: R143.2 U28.9(SEL) U29.9(SEL) U65.R6(IO_B1_R6)
PEX_PRS_N: J18.B17(P\R\S\N\T\2\_X1) J18.B31(P\R\S\N\T\2\_X4) R405.1 U65.P5(IO_B1_P5)
PEX_REFCLK_N: J18.A14(REFCLK-) R521.2 R523.1
PEX_REFCLK_P: J18.A13(REFCLK+) R519.1 R520.2
PEX_RST_N: J18.A11(P\E\R\S\T\) U65.R5(IO_B1_R5)
PEX_RX0_N: J18.A17(PERN0) U1.AG16(SD1_RX4_N)
PEX_RX0_P: J18.A16(PERP0) U1.AH16(SD1_RX4_P)
PEX_RX1_N: J18.A22(PERN1) U26.19(B0+)
PEX_RX1_P: J18.A21(PERP1) U26.18(B0-)
PEX_RX2_N: J18.A26(PERN2) U28.19(B0+)
PEX_RX2_P: J18.A25(PERP2) U28.18(B0-)
PEX_RX3_N: J18.A30(PERN3) U29.19(B0+)
PEX_RX3_P: J18.A29(PERP3) U29.18(B0-)
PEX_TX0_N: C607.2 U1.AE16(SD1_TX4_N)
PEX_TX0_P: C606.2 U1.AD16(SD1_TX4_P)
PEX_TX1_N: C615.2 U26.17(B1+)
PEX_TX1_P: C608.2 U26.16(B1-)
PEX_TX2_N: C617.2 U28.17(B1+)
PEX_TX2_P: C616.2 U28.16(B1-)
PEX_TX3_N: C619.2 U29.17(B1+)
PEX_TX3_P: C618.2 U29.16(B1-)
PEXCLK_OE_N: R843.2 U65.N16(IO_B2_N16) U97.13(O\E\0\) U97.24(O\E\2\) U97.30(O\E\3\) U97.35(O\E\4\)
PORESET_N: R94.2 U1.F13(PORESET_B) U65.C15(IO_B2_C15)
POTS1_RING: F2.2 J22.A3 R413.2
POTS1_TIP: F1.2 J22.A4 R412.2
POTS2_RING: F4.2 J22.B3 R435.2
POTS2_TIP: F3.2 J22.B4 R434.2
POTS3_RING: F6.2 J25.4 R451.2
POTS3_TIP: F5.2 J25.7 R441.2
POTS4_RING: F8.2 J23.B3 R465.2
POTS4_TIP: F7.2 J23.B4 R464.2
POTS_RST_N: R426.1 R455.1 R857.1
POTS_SWCMP: C683.1 C684.1 R473.1 U59.20(SWCMPY)
POTS_SWIS: C697.1 R488.2 U59.19(SWISY)
POTS_SWOUT: R489.1 U59.21(SWOUTY)
POTS_TDM_CLK: R100.1 R417.1 R445.1
POTS_TDM_FS: R418.1 R446.1 U1.U5(DMA1_DACK0_B)
POTS_TDM_RXD: R422.1 R448.1 U1.V5(DMA2_DREQ0_B)
POTS_TDM_TXD: R421.1 R447.1 U1.P5(DMA1_DREQ0_B)
POTSA_INT_N: R428.1 U59.31(I\N\T\/S2) U65.H2(IO_B1_H2)
POTSA_SPI_CS_N: R420.1 U18.10(B3) U59.36(C\S\/PG)
POTSA_SWVSY: C682.2 C683.2 R474.1 R475.1 U59.18(SWVSY)
POTSA_SWVSZ: R478.1 U59.44(SWVSZ)
POTSB_INT_N: R858.1 U63.31(I\N\T\/S2) U65.K3(IO_B1_K3)
POTSB_SPI_CS_N: R442.1 U18.11(B2) U63.36(C\S\/PG)
POTSB_SWVSY: R476.1 R477.1 U63.18(SWVSY)
POTSB_SWVSZ: R479.1 U63.44(SWVSZ)
PROC_SPI_CLK: R59.2 U12.3(A3)
PROC_SPI_CS0_N: U1.M1(SPI_CS0_B) U12.4(A4)
PROC_SPI_CS1_N: U1.M2(SPI_CS1_B) U18.3(A3)
PROC_SPI_CS2_N: U1.M3(SPI_CS2_B) U18.2(A2)
PROC_SPI_CS3_N: U1.N3(SPI_CS3_B) U18.1(A1)
PROC_SPI_MISO: U1.P1(SPI_MISO) U12.1(A1)
PROC_SPI_MOSI: U1.P2(SPI_MOSI) U12.2(A2)
PROC_UART1_CTS_N: U1.Y2(UART1_CTS_B) U40.1(A1)
PROC_UART1_RTS_N: U1.Y1(UART1_RTS_B) U40.2(A2)
PROC_UART1_RXD: U1.AA1(UART1_SIN) U40.4(A4)
PROC_UART1_TXD: U1.AA2(UART1_SOUT) U40.3(A3)
PROC_UART2_CTS_N: U1.Y4(UART2_CTS_B) U42.1(A1)
PROC_UART2_RTS_N: U1.V4(UART2_RTS_B) U42.2(A2)
PROC_UART2_RXD: U1.W4(UART2_SIN) U42.4(A4)
PROC_UART2_TXD: U1.AA4(UART2_SOUT) U42.3(A3)
PWR_EN_N: J37.14(P\S\_\O\N\) Q30.3(C) R710.1
PWR_GOOD: C894.1 R709.1 R712.2 U65.C2(IO_B1_C2)
PWR_RST_N: R708.2 U65.C3(IO_B1_C3) U83.2(R\E\S\E\T\)
QSG1_INT_N: R291.2 R855.1 U65.N2(IO_B1_N2)
QSG1_LED0: R340.1 U55.C3(LED0_PHY1)
QSG1_LED1: R342.1 U55.B2(LED1_PHY1)
QSG1_MDI0_N: T5.3 U55.B17(P1_D0N)
QSG1_MDI0_P: T5.2 U55.B18(P1_D0P)
QSG1_MDI1_N: T5.6 U55.C28(P1_D1N)
QSG1_MDI1_P: T5.5 U55.C29(P1_D1P)
QSG1_MDI2_N: T5.9 U55.B15(P1_D2N)
QSG1_MDI2_P: T5.8 U55.B16(P1_D2P)
QSG1_MDI3_N: T5.12 U55.C26(P1_D3N)
QSG1_MDI3_P: T5.11 U55.C27(P1_D3P)
QSG1_MDX0_N: J15.A2 T5.22
QSG1_MDX0_P: J15.A1 T5.23
QSG1_MDX1_N: J15.A6 T5.19
QSG1_MDX1_P: J15.A3 T5.20
QSG1_MDX2_N: J15.A5 T5.16
QSG1_MDX2_P: J15.A4 T5.17
QSG1_MDX3_N: J15.A8 T5.13
QSG1_MDX3_P: J15.A7 T5.14
QSG1_REFCLK_N: C411.1 R548.2 U67.3(Q0)
QSG1_REFCLK_P: C410.1 R547.2 U67.4(Q\0\)
QSG1_RST_N: R292.1 R296.2 U65.M3(IO_B1_M3)
QSG2_INT_N: R312.2 R856.1 U65.P2(IO_B1_P2)
QSG2_LED0: R352.1 U55.E2(LED0_PHY0)
QSG2_LED1: R354.1 U55.D1(LED1_PHY0)
QSG2_MDI0_N: T7.3 U55.D30(P0_D0N)
QSG2_MDI0_P: T7.2 U55.D31(P0_D0P)
QSG2_MDI1_N: T7.6 U55.C24(P0_D1N)
QSG2_MDI1_P: T7.5 U55.C25(P0_D1P)
QSG2_MDI2_N: T7.9 U55.C23(P0_D2N)
QSG2_MDI2_P: T7.8 U55.D29(P0_D2P)
QSG2_MDI3_N: T7.12 U55.C21(P0_D3N)
QSG2_MDI3_P: T7.11 U55.C22(P0_D3P)
QSG2_MDX0_N: J15.B2 T7.22
QSG2_MDX0_P: J15.B1 T7.23
QSG2_MDX1_N: J15.B6 T7.19
QSG2_MDX1_P: J15.B3 T7.20
QSG2_MDX2_N: J15.B5 T7.16
QSG2_MDX2_P: J15.B4 T7.17
QSG2_MDX3_N: J15.B8 T7.13
QSG2_MDX3_P: J15.B7 T7.14
QSG2_REFCLK_N: C456.1 R546.2 U67.19(Q1)
QSG2_REFCLK_P: C455.1 R545.2 U67.18(Q\1\)
QSG2_RST_N: R313.1 R317.2 U65.N3(IO_B1_N3)
QSG3_LED0: R364.1 U55.B4(LED0_PHY3)
QSG3_LED1: R366.1 U55.C6(LED1_PHY3)
QSG3_MDI0_N: T9.3 U55.C36(P3_D0N)
QSG3_MDI0_P: T9.2 U55.C1(P3_D0P)
QSG3_MDI1_N: T9.6 U55.D34(P3_D1N)
QSG3_MDI1_P: T9.5 U55.D35(P3_D1P)
QSG3_MDI2_N: T9.9 U55.C34(P3_D2N)
QSG3_MDI2_P: T9.8 U55.C35(P3_D2P)
QSG3_MDI3_N: T9.12 U55.D32(P3_D3N)
QSG3_MDI3_P: T9.11 U55.D33(P3_D3P)
QSG3_MDX0_N: J15.C2 T9.22
QSG3_MDX0_P: J15.C1 T9.23
QSG3_MDX1_N: J15.C6 T9.19
QSG3_MDX1_P: J15.C3 T9.20
QSG3_MDX2_N: J15.C5 T9.16
QSG3_MDX2_P: J15.C4 T9.17
QSG3_MDX3_N: J15.C8 T9.13
QSG3_MDX3_P: J15.C7 T9.14
QSG4_LED0: R375.1 U55.C5(LED0_PHY2)
QSG4_LED1: R376.1 U55.D5(LED1_PHY2)
QSG4_MDI0_N: T11.3 U55.C32(P2_D0N)
QSG4_MDI0_P: T11.2 U55.C33(P2_D0P)
QSG4_MDI1_N: T11.6 U55.B19(P2_D1N)
QSG4_MDI1_P: T11.5 U55.B20(P2_D1P)
QSG4_MDI2_N: T11.9 U55.A9(P2_D2N)
QSG4_MDI2_P: T11.8 U55.A10(P2_D2P)
QSG4_MDI3_N: T11.12 U55.C30(P2_D3N)
QSG4_MDI3_P: T11.11 U55.C31(P2_D3P)
QSG4_MDX0_N: J15.D2 T11.22
QSG4_MDX0_P: J15.D1 T11.23
QSG4_MDX1_N: J15.D6 T11.19
QSG4_MDX1_P: J15.D3 T11.20
QSG4_MDX2_N: J15.D5 T11.16
QSG4_MDX2_P: J15.D4 T11.17
QSG4_MDX3_N: J15.D8 T11.13
QSG4_MDX3_P: J15.D7 T11.14
QSG5_LED0: R339.1 U56.C3(LED0_PHY1)
QSG5_LED1: R341.1 U56.B2(LED1_PHY1)
QSG5_MDI0_N: T4.3 U56.B17(P1_D0N)
QSG5_MDI0_P: T4.2 U56.B18(P1_D0P)
QSG5_MDI1_N: T4.6 U56.C28(P1_D1N)
QSG5_MDI1_P: T4.5 U56.C29(P1_D1P)
QSG5_MDI2_N: T4.9 U56.B15(P1_D2N)
QSG5_MDI2_P: T4.8 U56.B16(P1_D2P)
QSG5_MDI3_N: T4.12 U56.C26(P1_D3N)
QSG5_MDI3_P: T4.11 U56.C27(P1_D3P)
QSG5_MDX0_N: J15.E2 T4.22
QSG5_MDX0_P: J15.E1 T4.23
QSG5_MDX1_N: J15.E6 T4.19
QSG5_MDX1_P: J15.E3 T4.20
QSG5_MDX2_N: J15.E5 T4.16
QSG5_MDX2_P: J15.E4 T4.17
QSG5_MDX3_N: J15.E8 T4.13
QSG5_MDX3_P: J15.E7 T4.14
QSG6_LED0: R351.1 U56.E2(LED0_PHY0)
QSG6_LED1: R353.1 U56.D1(LED1_PHY0)
QSG6_MDI0_N: T6.3 U56.D30(P0_D0N)
QSG6_MDI0_P: T6.2 U56.D31(P0_D0P)
QSG6_MDI1_N: T6.6 U56.C24(P0_D1N)
QSG6_MDI1_P: T6.5 U56.C25(P0_D1P)
QSG6_MDI2_N: T6.9 U56.C23(P0_D2N)
QSG6_MDI2_P: T6.8 U56.D29(P0_D2P)
QSG6_MDI3_N: T6.12 U56.C21(P0_D3N)
QSG6_MDI3_P: T6.11 U56.C22(P0_D3P)
QSG6_MDX0_N: J15.F2 T6.22
QSG6_MDX0_P: J15.F1 T6.23
QSG6_MDX1_N: J15.F6 T6.19
QSG6_MDX1_P: J15.F3 T6.20
QSG6_MDX2_N: J15.F5 T6.16
QSG6_MDX2_P: J15.F4 T6.17
QSG6_MDX3_N: J15.F8 T6.13
QSG6_MDX3_P: J15.F7 T6.14
QSG7_LED0: R363.1 U56.B4(LED0_PHY3)
QSG7_LED1: R365.1 U56.C6(LED1_PHY3)
QSG7_MDI0_N: T8.3 U56.C36(P3_D0N)
QSG7_MDI0_P: T8.2 U56.C1(P3_D0P)
QSG7_MDI1_N: T8.6 U56.D34(P3_D1N)
QSG7_MDI1_P: T8.5 U56.D35(P3_D1P)
QSG7_MDI2_N: T8.9 U56.C34(P3_D2N)
QSG7_MDI2_P: T8.8 U56.C35(P3_D2P)
QSG7_MDI3_N: T8.12 U56.D32(P3_D3N)
QSG7_MDI3_P: T8.11 U56.D33(P3_D3P)
QSG7_MDX0_N: J15.G2 T8.22
QSG7_MDX0_P: J15.G1 T8.23
QSG7_MDX1_N: J15.G6 T8.19
QSG7_MDX1_P: J15.G3 T8.20
QSG7_MDX2_N: J15.G5 T8.16
QSG7_MDX2_P: J15.G4 T8.17
QSG7_MDX3_N: J15.G8 T8.13
QSG7_MDX3_P: J15.G7 T8.14
QSG8_LED0: R377.1 U56.C5(LED0_PHY2)
QSG8_LED1: R378.1 U56.D5(LED1_PHY2)
QSG8_MDI0_N: T10.3 U56.C32(P2_D0N)
QSG8_MDI0_P: T10.2 U56.C33(P2_D0P)
QSG8_MDI1_N: T10.6 U56.B19(P2_D1N)
QSG8_MDI1_P: T10.5 U56.B20(P2_D1P)
QSG8_MDI2_N: T10.9 U56.A9(P2_D2N)
QSG8_MDI2_P: T10.8 U56.A10(P2_D2P)
QSG8_MDI3_N: T10.12 U56.C30(P2_D3N)
QSG8_MDI3_P: T10.11 U56.C31(P2_D3P)
QSG8_MDX0_N: J15.H2(G2) T10.22
QSG8_MDX0_P: J15.H1(G1) T10.23
QSG8_MDX1_N: J15.H6(G6) T10.19
QSG8_MDX1_P: J15.H3(G3) T10.20
QSG8_MDX2_N: J15.H5(G5) T10.16
QSG8_MDX2_P: J15.H4(G4) T10.17
QSG8_MDX3_N: J15.H8(G8) T10.13
QSG8_MDX3_P: J15.H7(G7) T10.14
QSGMII1_RX_N: U27.19(B0+) U55.D13(QSGMII0_RXN)
QSGMII1_RX_P: U27.18(B0-) U55.D14(QSGMII0_RXP)
QSGMII1_TX_N: C405.1 U27.17(B1+)
QSGMII1_TX_P: C400.1 U27.16(B1-)
QSGMII2_RX_N: C66.1 U56.D13(QSGMII0_RXN)
QSGMII2_RX_P: C62.1 U56.D14(QSGMII0_RXP)
QSGMII2_TX_N: C454.1 U1.AE14(SD1_TX3_N)
QSGMII2_TX_P: C445.1 U1.AD14(SD1_TX3_P)
RESET_REQ_N: R98.2 U1.B3(RESET_REQ_B) U65.K15(IO_B2_K15)
RS232_CTS1: C276.1 FB21.2 J13.A8 U43.4
RS232_CTS2: C289.1 FB25.2 J13.B8 U43.5
RS232_RTS1: C277.1 FB20.2 J13.A1 U43.2
RS232_RTS2: C290.1 FB24.2 J13.B1 U43.8
RS232_RXD1: C278.1 FB19.2 J13.A6 U43.3
RS232_RXD2: C291.1 FB23.2 J13.B6 U43.6
RS232_TXD1: C279.1 FB18.2 J13.A3 U43.1
RS232_TXD2: C292.1 FB22.2 J13.B3 U43.7
SATA_RX_N: C634.1 U29.15(C0+)
SATA_RX_P: C635.1 U29.14(C0-)
SATA_TX_N: C633.1 U29.13(C1+)
SATA_TX_P: C632.1 U29.12(C1-)
SD_REFCLK1_N: C68.1 R543.2 U68.4(Q\0\)
SD_REFCLK1_P: C67.1 R544.2 U68.3(Q0)
SD_REFCLK1_SEL: U65.M1(IO_B1_M1) U68.9(F_SEL0)
SD_REFCLK2_N: R537.2 R538.2 U1.AA18(SD1_REF_CLK2_N)
SD_REFCLK2_P: R535.2 R536.2 U1.AB18(SD1_REF_CLK2_P)
SD_RX1_N: C64.1 U25.8(A1-)
SD_RX1_P: C63.1 U25.7(A1+)
SD_RX2_N: C61.1 U27.3(A0+)
SD_RX2_P: C65.1 U27.4(A0-)
SD_RX5_N: U1.AG17(SD1_RX5_N) U26.3(A0+)
SD_RX5_P: U1.AH17(SD1_RX5_P) U26.4(A0-)
SD_RX6_N: U1.AG19(SD1_RX6_N) U28.3(A0+)
SD_RX6_P: U1.AH19(SD1_RX6_P) U28.4(A0-)
SD_RX7_N: U1.AG20(SD1_RX7_N) U29.3(A0+)
SD_RX7_P: U1.AH20(SD1_RX7_P) U29.4(A0-)
SD_TX1_N: U1.AE11(SD1_TX1_N) U25.4(A0-)
SD_TX1_P: U1.AD11(SD1_TX1_P) U25.3(A0+)
SD_TX2_N: U1.AE13(SD1_TX2_N) U27.7(A1+)
SD_TX2_P: U1.AD13(SD1_TX2_P) U27.8(A1-)
SD_TX5_N: U1.AE17(SD1_TX5_N) U26.7(A1+)
SD_TX5_P: U1.AD17(SD1_TX5_P) U26.8(A1-)
SD_TX6_N: U1.AE19(SD1_TX6_N) U28.7(A1+)
SD_TX6_P: U1.AD19(SD1_TX6_P) U28.8(A1-)
SD_TX7_N: U1.AE20(SD1_TX7_N) U29.7(A1+)
SD_TX7_P: U1.AD20(SD1_TX7_P) U29.8(A1-)
SDHC_CD_N: J2.10(I\N\S\E\R\T\) R66.1 U1.L5(SDHC_CD_B) U93.4 U93.5
SDHC_CLK: J2.5(CLK/SCLK) R61.2 R68.1 U94.1 U94.8
SDHC_CMD: J2.2(CMD/DIN) R67.1 U1.K3(SDHC_CMD) U93.3 U93.6
SDHC_DAT0: J2.7(D0/DOUT) R60.1 U1.L2(SDHC_DAT0) U94.2 U94.7
SDHC_DAT1: J2.8(D1/RSV) R62.1 U1.K4(SDHC_DAT1) U94.3 U94.6
SDHC_DAT2: J2.9(D2/RSV) R63.1 U1.L3(SDHC_DAT2) U93.1 U93.8
SDHC_DAT3: J2.1(D3/C\S\) R64.1 U1.L1(SDHC_DAT3) U93.2 U93.7
SDHC_VS: R72.1 U1.D1(IRQ03) U65.M16(IO_B2_M16)
SDHC_WP: J2.11(P\R\O\T\E\C\T\) R65.1 U1.M5(SDHC_WP) U94.4 U94.5
SENSEGND: R554.2 U1.G20(SENSEGND)
SENSEGNDC: R555.1 U1.AB10(SENSEGNDC)
SENSEVDD: R552.2 U1.G19(SENSEVDD)
SENSEVDD_EN: U65.P7(IO_B1_P7) U92.1(IN1) U92.5(IN2)
SENSEVDDC: R553.1 U1.AB9(SENSEVDDC)
SFPP_DET_N: J16.6(MOD_DEF(0)/DET) R393.1 U65.L2(IO_B1_L2)
SFPP_RX_N: J16.12(RX_DAT-) U57.L11(RX1_DINN)
SFPP_RX_P: J16.13(RX_DAT+) U57.L10(RX1_DINP)
SFPP_RXLOS: J16.8(RX_LOS) R390.1 U65.L3(IO_B1_L3)
SFPP_TX_N: J16.19(TX_DAT-) U57.L7(TX1_DOUTN)
SFPP_TX_P: J16.18(TX_DAT+) U57.L8(TX1_DOUTP)
SFPP_TXDIS: J16.3(TX_DIS) R396.1 U65.K2(IO_B1_K2)
SFPP_TXFAIL: J16.2(TX_FAULT) R397.1 U65.J3(IO_B1_J3)
SG_INT_N: R281.2 R854.2 U65.M2(IO_B1_M2)
SG_LED0: R274.1 R279.2 U52.68(LED0/PHY_AD0)
SG_LED1: R275.1 R277.2 U52.69(LED1/PHY_AD1)
SG_MDI0_N: T3.11 U52.2(MDIN0) U53.1
SG_MDI0_P: T3.12 U52.1(MDIP0) U53.3
SG_MDI1_N: T3.8 U52.5(MDIN1) U53.6
SG_MDI1_P: T3.9 U52.4(MDIP1) U53.4
SG_MDI2_N: T3.5 U52.8(MDIN2) U54.1
SG_MDI2_P: T3.6 U52.7(MDIP2) U54.3
SG_MDI3_N: T3.2 U52.11(MDIN3) U54.6
SG_MDI3_P: T3.3 U52.10(MDIP3) U54.4
SG_MDX0_N: J42.2 T3.14
SG_MDX0_P: J42.1 T3.13
SG_MDX1_N: J42.6 T3.17
SG_MDX1_P: J42.3 T3.16
SG_MDX2_N: J42.5 T3.20
SG_MDX2_P: J42.4 T3.19
SG_MDX3_N: J42.8 T3.23
SG_MDX3_P: J42.7 T3.22
SG_RST_N: R280.1 R282.2 U65.R7(IO_B1_R7)
SGMII_RX_N: U25.16(B1-) U27.15(C0+) U52.18(HSON)
SGMII_RX_P: U25.17(B1+) U27.14(C0-) U52.17(HSOP)
SGMII_TX_N: C367.2 U25.18(B0-) U27.13(C1+)
SGMII_TX_P: C366.2 U25.19(B0+) U27.12(C1-)
SPI_CLK: R425.1 R450.1 R865.1 R867.2 U12.10(B3)
SPI_CS3_N: U18.12(B1) U100.1(I0) U101.1(I0)
SPI_CS3_SEL: R860.1 U65.P9(IO_B1_P9) U100.2(I1)
SPI_MISO: R54.1 R58.1 R419.1 R449.1 R868.2 U12.12(B1)
SPI_MOSI: R423.1 R453.1 R866.1 R869.2 U12.11(B2)
SYS_REFCLK: R511.2 R513.2 U1.G15(SYSCLK)
SYS_REFCLK_N: R837.2 R838.1 U1.F14(DIFF_SYSCLK_B)
SYS_REFCLK_P: R835.1 R836.2 U1.G14(DIFF_SYSCLK)
SYSCLK_OE: U65.M15(IO_B2_M15) X3.1(OE)
T2081_DET_N: R185.1 U1.AH27(DEV_DET) U65.P4(IO_B1_P4)
T2081_EN: R141.2 R692.1 U25.2(PD) U27.9(SEL) U65.R9(IO_B1_R9)
TDMA_RCK_CLK8_12: J43.21 U1.M4(CLK12)
TDMA_RQ: J43.3 U1.R2(TDMA_RQ)
TDMA_RSYNC: J43.11 U1.U1(TDMA_RSYNC)
TDMA_RXD: J43.13 U1.U2(TDMA_RXD)
TDMA_TCK_CLK9: J43.17 U1.P4(CLK09)
TDMA_TSYNC: J43.9 U1.R1(TDMA_TSYNC)
TDMA_TXD: J43.7 U1.T1(TDMA_TXD)
TDMB_RCK_CLK10: J43.29 U1.P3(CLK10)
TDMB_RQ: J43.24 U1.R4(TDMB_RQ)
TDMB_RSYNC: J43.18 U1.T3(TDMB_RSYNC)
TDMB_RXD: J43.1 U1.U4(TDMB_RXD)
TDMB_TCK_CLK11: J43.39 U1.N4(CLK11)
TDMB_TSYNC: J43.22 U1.R3(TDMB_TSYNC)
TDMB_TXD: J43.20 U1.T4(TDMB_TXD)
TDMR1_INT_N: J43.31 R850.2 U65.R12(IO_B1_R12)
TDMR2_INT_N: J43.33 R851.2 U65.P11(IO_B1_P11)
TDMR_PRS_N: J43.27 R849.2 U65.P12(IO_B1_P12)
TDMR_RST_N: J43.35 R852.2 U65.R11(IO_B1_R11)
TDMR_SLP_N: J43.25 U65.R13(IO_B1_R13)
TDMR_SPI_CS0_N: J43.32 U100.4(O)
TDMR_SPI_CS1_N: J43.34 U101.4(O)
TEMP_DIODE_N: R206.1 U1.G21(TD1_CATHODE)
TEMP_DIODE_P: R205.1 U1.E21(TD1_ANODE)
TEST_SEL_N: R83.1 SW3.8 U1.G8(TEST_SEL_B) U65.E16(IO_B2_E16)
THERM_ALERT_N: R853.1 U45.6(A\L\E\R\T\/T\H\E\R\M\2\) U65.M4(IO_B1_M4)
THERM_FAULT_N: D34.1 R204.1 U45.4(T\H\E\R\M\) U65.D1(IO_B1_D1)
UART1_CTS_N: U39.9(R2-OUT) U40.12(B1)
UART1_RTS_N: U39.10(T2-IN) U40.11(B2)
UART1_RXD: U39.12(R1-OUT) U40.9(B4)
UART1_TXD: U39.11(T1-IN) U40.10(B3)
UART2_CTS_N: U41.9(R2-OUT) U42.12(B1)
UART2_RTS_N: U41.10(T2-IN) U42.11(B2)
UART2_RXD: U41.12(R1-OUT) U42.9(B4)
UART2_TXD: U41.11(T1-IN) U42.10(B3)
USB1_DM: J41.6 L1.3 R168.2 U38.4
USB1_DP: J41.7 L1.2 R167.2 U38.6
USB1_FLG_N: Q3.1(G) R157.2 R159.1 U37.2(FLGA)
USB1_PWREN: R162.2 U1.F6(USB1_DRVVBUS) U37.1(CTLA)
USB1_VBUS: FB6.1 J41.5 U38.5
USB1_VBUSCLMP: D4.2 R164.1 R166.2 U1.E4(USB1_VBUSCLMP)
USB2_DM: J41.2 L2.3 R170.2 U96.4
USB2_DP: J41.3 L2.2 R169.2 U96.6
USB2_FLG_N: Q4.1(G) R158.1 R160.2 U37.3(FLGB)
USB2_PWREN: R161.2 U1.J5(USB2_DRVVBUS) U37.4(CTLB)
USB2_VBUS: FB8.1 J41.1 U96.5
USB2_VBUSCLMP: D3.2 R163.1 R165.2 U1.J4(USB2_VBUSCLMP)
USB_REFCLK: R175.2 R176.2 U1.F8(USBCLK)
VBH: C685.1 D25.1 L6.2 R480.2 R481.2
VBH1: D26.1 T12.10
VBH2: C689.2 D26.2 L6.1 R475.2 R477.2 R478.2 R479.2
VBL1: D28.1 T12.8
VBL2: C689.1 C691.2 C692.2 D28.2 L7.1 R474.2 R476.2
VCORE: C186.1 C187.1 C188.1 C189.1 C200.1 C201.1 C202.1 C203.1 C204.1 C205.1 C206.1 C207.1 C212.1 C213.1 C214.1 C215.1 C216.1 C217.1 C218.1 C219.1 C223.1 C224.1 C225.1 C226.1 C227.1 C228.1 C229.1 C230.1 C767.1 C904.1 C905.1 C906.1 C907.1 C908.1 C909.1 C910.1 C911.1 C912.1 C913.1 C914.1 C915.1 C1003.1 C1004.1 C1005.1 C1006.1 C1007.1 C1008.1 C1009.1 C1010.1 C1029.1 C1030.1 C1031.1 C1032.1 C1033.1 C1034.1 C1035.1 C1036.1 C1106.1 C1107.1 C1108.1 C1109.1 C1110.1 C1111.1 J11.2 Q8.1 Q8.2 Q8.3 Q9.1 Q9.2 Q9.3 R654.2 U1.K15(VDD01) U1.K17(VDD02) U1.K19(VDD03) U1.L12(VDD04) U1.L14(VDD05) U1.L16(VDD06) U1.L18(VDD07) U1.L20(VDD08) U1.M9(VDD09) U1.M13(VDD10) U1.M15(VDD11) U1.M17(VDD12) U1.M19(VDD13) U1.N12(VDD14) U1.N14(VDD15) U1.N16(VDD16) U1.N18(VDD17) U1.N20(VDD18) U1.P9(VDD19) U1.P11(VDD20) U1.P13(VDD21) U1.P15(VDD22) U1.P17(VDD23) U1.P19(VDD24) U1.R12(VDD25) U1.R14(VDD26) U1.R16(VDD27) U1.R18(VDD28) U1.R20(VDD29) U1.T9(VDD30) U1.T13(VDD31) U1.T15(VDD32) U1.T17(VDD33) U1.T19(VDD34) U1.U14(VDD35) U1.U16(VDD36) U1.U18(VDD37) U1.U20(VDD38) U1.V9(VDD39) U1.V13(VDD40) U1.V15(VDD41) U1.V17(VDD42) U1.V19(VDD43) U1.W14(VDD44) U1.Y8(VDD45) U1.Y9(VDD46) U1.Y11(VDD47)
VCORE_EN: R564.2 U65.R14(IO_B1_R14) U70.12(EN1)
VCORE_HOT_N: J27.1 R574.2 U65.P8(IO_B1_P8) U70.11(V\R\H\O\T\_\I\C\R\I\T\)
VCORE_IRTN1A: R566.1 U70.30(IRTN1A)
VCORE_IRTN1B: R591.1 U70.28(IRTN1B)
VCORE_ISEN1A: R565.1 U70.29(ISEN1A)
VCORE_ISEN1B: R590.1 U70.27(ISEN1B)
VCORE_PGOOD: R563.2 U65.R10(IO_B1_R10) U70.7(PGOOD1)
VCORE_PWM1A: U69.26(PWM) U70.17(PWM1A)
VCORE_PWM1B: U70.18(PWM1B) U71.26(PWM)
VCORE_SLP: C234.1 C235.1 C236.1 C237.1 C238.1 C239.1 C240.1 C241.1 C765.2 C768.1 C776.1 C777.1 C781.1 C782.1 C783.1 C784.1 C785.2 C787.1 C788.1 C789.1 C790.1 C791.1 C792.1 C793.1 C794.1 C916.1 C917.1 C918.1 C919.1 C920.1 C921.1 C922.1 C923.1 C1037.1 C1038.1 C1039.1 FB11.2 L8.2 L9.2 Q8.5 Q9.5 R551.1 R566.2 R591.2 U1.K11(VDDC01) U1.K13(VDDC02) U1.L10(VDDC03) U1.M11(VDDC04) U1.N10(VDDC05) U1.R10(VDDC06) U1.T11(VDDC07) U1.U10(VDDC08) U1.U12(VDDC09) U1.V11(VDDC10) U1.W10(VDDC11) U1.W12(VDDC12)
VCORE_SW1: C763.1 C766.1 L8.1 R562.1 U69.6(SW#6) U69.7(SW#7)
VCORE_SW2: C779.1 C786.1 L9.1 R586.1 U71.6(SW#6) U71.7(SW#7)
VCORE_VCC: C760.1 C762.1 R559.1 U70.22(VCC)
VCORE_VRTN1: C764.2 R555.2 R556.2 U70.3(VRTN1) U92.6(D2)
VCORE_VSEN1: C764.1 R551.2 R553.2 U70.2(VSEN1) U92.10(D1)
VTT: C15.1 C16.1 C17.1 C885.1 C886.1 J1.48(VTT/NC#48) J1.49(VTT/NC#49) J1.120(VTT#120) J1.240(VTT#240) R694.2 U81.3(VO)
XFI_RX_N: C60.1 U57.A11(XRX1_DOUTN)
XFI_RX_P: C59.1 U57.A10(XRX1_DOUTP)
XFI_TX_N: C555.1 U1.AE10(SD1_TX0_N)
XFI_TX_P: C554.1 U1.AD10(SD1_TX0_P)
XG_LED0: R394.1 U65.G3(IO_B1_G3)
XG_LED1: R395.1 U65.G2(IO_B1_G2)
XG_REFCLK_N: C575.1 R541.2 U68.18(Q\1\)
XG_REFCLK_P: C574.1 R542.2 U68.19(Q1)
XG_RST_N: R386.1 R388.2 U65.P15(IO_B2_P15)
XVDD: C249.1 C250.1 C251.1 C252.1 C253.1 C254.1 C255.1 C1014.2 C1026.1 R140.1 U1.AC9(X1VDD1) U1.AC12(X1VDD2) U1.AC15(X1VDD3) U1.AC18(X1VDD4) U1.AC21(X1VDD5)
N16747459: R1.2 U1.U28(D1_MDIC1)
N16747463: R3.2 U1.P28(D1_MDIC0)
N16800565: R42.1 U4.53(B\Y\T\E\)
N16800570: R41.1 U4.16(W\P\/ACC)
N16800621: R44.1 U4.17(RDY/B\U\S\Y\)
N16807910: R51.1 U6.34(DNU34/VCCQ) U6.39(DNU39/VCCQ)
N16808071: R52.1 U6.25(DNU25/VSSQ) U6.48(DNU48/VSSQ)
N16809639: R46.1 U6.10(C\E\2\)
N16810401: R45.1 U6.9(C\E\1\) U7.11(B2)
N16811518: U6.17(ALE) U7.9(B4)
N16821274: R12.1 U1.A17(IFC_CLK0)
N16821816: R5.1 U1.E14(IFC_PERR_B)
N16848026: R422.2 U59.28(DXA/DU)
N16848521: R423.2 U59.34(DIN/S1)
N16848537: R426.2 U59.32(R\S\T\)
N16848601: R419.2 U59.35(DOUT)
N16849665: R436.2 U59.9(RTV1)
N16849667: R436.1 U59.6(RSN1)
N16849681: C648.2 U59.51(IHL2)
N16849691: C646.2 C647.1 C648.1 U59.17(VREF)
N16849695: C647.2 U59.10(IHL1)
N16849815: R437.1 U59.52(RTV2)
N16849817: R437.2 U59.55(RSN2)
N16849836: R438.2 U59.16(IREF)
N16849860: C649.1 U59.15(LFC1)
N16850380: C639.1 F1.1 R414.2 U59.77(TIPD1) U60.1 U60.8
N16850382: C640.2 F2.1 R416.2 U59.71(RINGD1) U60.4 U60.5
N16850384: R716.1 U59.13(TDC1)
N16850386: R717.1 U59.14(RDC1)
N16850446: C637.2 R414.1
N16850448: C637.1 U59.11(TAC1)
N16850461: C638.1 U59.12(RAC1)
N16850463: C638.2 R416.1
N16850577: C641.1 F3.1 R429.2 U59.67(TIPD2) U61.1 U61.8
N16850645: C643.2 F4.1 R431.2 U59.61(RINGD2) U61.4 U61.5
N16850749: C642.1 U59.50(TAC2)
N16850755: C644.1 U59.49(RAC2)
N16850778: R718.1 U59.47(RDC2)
N16850798: R719.1 U59.48(TDC2)
N16851731: C696.2 R489.2 R490.1 R493.2
N16851789: C690.2 Q6.3(D) T12.4
N16851797: Q6.2(S) R488.1 R491.2
N16852263: C690.1 D27.3 R482.1 R483.1 R484.1
N16859448: R430.2 R433.2 U59.45(XB)
N16861709: R421.2 U59.29(DRA/DD)
N16861730: R418.2 U59.26(FS/FSC)
N16862179: Q7.1(G) R490.2
N16862407: Q5.3(C) Q7.3(D) R486.1
N16862426: C696.1 Q5.1(B) R485.1
N16862837: Q6.1(G) R486.2 R487.2
N16864329: R58.2 U13.8(SO) U15.2(SO)
N16864338: R55.1 R866.2 U13.15(SI) U15.5(SI)
N16864354: R865.2 U13.16(SCK) U15.6(SCK)
N16864366: R56.1 U12.9(B4) U13.7(C\S\) U15.1(C\S\)
N16864378: R57.1 U13.1(H\O\L\D\) U13.9(W\P\) U15.3(W\P\) U15.7(H\O\L\D\)
N16869850: C300.2 R211.2 U46.19(RXC)
N16869910: R209.2 U46.14(RXD0/SELRGV)
N16869938: R213.2 U46.16(RXD1/TXDLY)
N16869959: R214.2 U46.17(RXD2/AN0)
N16869976: R215.2 U46.18(RXD3/AN1)
N16869978: R216.2 U46.13(RXCTL/PHY_AD2)
N16870294: R207.1 T1.15
N16870296: C302.1 R207.2 R208.2 R210.2 R212.2
N16870306: R208.1 T1.18
N16870310: R210.1 T1.21
N16870330: R212.1 T1.24
N16870380: C296.2 C298.2 C299.2 C301.2 T1.1 T1.4 T1.7 T1.10
N16870828: C297.1 FB26.2 J14.A11
N16870844: C307.1 J14.A12 R219.2
N16870890: C308.1 J14.A9 R218.2
N16871038: R221.1 U46.20(I\N\T\)
N16873302: C304.1 U46.42(CKXTAL1) Y1.1
N16873318: C305.1 U46.43(CKXTAL2) Y1.3
N16873350: R220.2 U46.29(P\H\Y\R\S\T\)
N16874872: C303.1 R217.1 U46.46(CLK125)
N16877780: R222.1 U46.33(P\M\E\)
N16879465: L3.1 R224.1 U46.48(REG_OUT)
N16880733: R822.2 U46.38(ENSWREG)
N16880820: C309.1 R224.2
N16890207: R227.2 U46.39(RSET)
N16891950: R265.1 T3.15
N16891952: C365.1 R265.2 R266.2 R267.2 R271.2
N16891962: R266.1 T3.18
N16891966: R267.1 T3.21
N16891978: R271.1 T3.24
N16892036: C360.2 C362.2 C363.2 C364.2 T3.1 T3.4 T3.7 T3.10
N16892171: C361.1 FB32.2 J42.9 J42.11
N16892215: C370.1 J42.10 R274.2
N16892219: C369.1 J42.12 R275.2
N16892768: R269.2 U52.43(RXD7/AN0)
N16892846: R270.2 U52.44(RXER/AN1)
N16894213: R272.2 U52.46(CRS/MII1)
N16894217: R273.2 U52.45(COL/MII0)
N16894418: R281.1 U52.75(I\N\T\)
N16899326: C366.1 U52.13(HSIP)
N16899338: C367.1 U52.14(HSIN)
N16900249: R276.1 U52.70(LED2/MDI0)
N16900569: R278.1 U52.71(LED3/MDI1)
N16900702: C372.1 U52.81(CKXTAL1) Y3.1
N16900720: C373.1 U52.82(CKXTAL2) Y3.3
N16900769: R280.2 U52.52(P\H\Y\R\S\T\)
N16902304: R827.2 U52.77(ENSWREG)
N16902556: R286.2 U52.26(REXT)
N16903120: R285.2 U52.78(RSET)
N16909680: L5.1 R284.1 U52.88(REG_OUT)
N16909742: C374.1 R284.2
N16927443: R268.2 U52.39(RXD4/SELRGV)
N16930193: C555.2 U57.A8(XTX1_DINN)
N16930196: C554.2 U57.A7(XTX1_DINP)
N16936676: C574.2 U57.C1(REFCLKP)
N16936678: C575.2 U57.D1(REFCLKN)
N16941914: R379.1 U57.F2(MADDR1)
N16941931: R380.1 U57.E2(MADDR2)
N16941947: R381.1 U57.H2(MADDR3)
N16941963: R383.1 U57.F3(MADDR4)
N16943000: R384.1 U57.B6(MICROSEL)
N16943224: R387.1 U57.E10(MDIOSEL)
N16943474: R382.2 U57.H3(SCL) U58.6(SCL)
N16943477: R385.2 U57.G3(SDA) U58.5(SDA)
N16948831: R386.2 U57.H10(R\E\S\E\T\)
N16948977: R389.1 U57.J6(IO_VDD_SEL)
N16949711: C572.1 U57.L4(RX2_DINP)
N16949714: C573.1 U57.L5(RX2_DINN)
N16950393: C564.2 U57.A1(XTX2_DINP)
N16950396: C565.2 U57.A2(XTX2_DINN)
N16956674: J16.7(RS0) R845.2 R846.1
N16956686: J16.9(RS1) R847.2 R848.1
N16973728: L4.1 R253.1 U49.48(REG_OUT)
N16973810: R825.2 U49.38(ENSWREG)
N16973842: C341.1 R253.2
N16974061: C331.2 R238.2 U49.19(RXC)
N16974094: R239.2 U49.14(RXD0/SELRGV)
N16974110: R242.2 U49.16(RXD1/TXDLY)
N16974123: R243.2 U49.17(RXD2/AN0)
N16974136: R244.2 U49.18(RXD3/AN1)
N16974138: R245.2 U49.13(RXCTL/PHY_AD2)
N16974225: R236.1 T2.15
N16974227: C334.1 R236.2 R237.2 R240.2 R241.2
N16974244: R237.1 T2.18
N16974248: R240.1 T2.21
N16974260: R241.1 T2.24
N16974322: C328.2 C330.2 C332.2 C333.2 T2.1 T2.4 T2.7 T2.10
N16974528: C329.1 FB29.2 J14.B9
N16974538: C337.1 J14.B11 R248.2
N16974572: C338.1 J14.B10 R247.2
N16974631: R250.1 U49.20(I\N\T\)
N16974829: C339.1 U49.42(CKXTAL1) Y2.1
N16974847: C340.1 U49.43(CKXTAL2) Y2.3
N16974885: R249.2 U49.29(P\H\Y\R\S\T\)
N16975047: C335.1 R246.1 U49.46(CLK125)
N16975158: R251.1 U49.33(P\M\E\)
N16975193: R256.2 U49.39(RSET)
N16980127: J18.B11(W\A\K\E\) R408.1
N16980167: J18.A8(JTAG5_TMS) R403.1
N16980179: J18.B9(JTAG1_T\R\S\T\) R400.1
N16980191: J18.A5(JTAG2_TCK) R401.1
N16980203: J18.A6(JTAG3_TDI) R402.1
N16980532: C607.1 J18.B15(PETN0)
N16980534: C606.1 J18.B14(PETP0)
N16981083: C608.1 J18.B19(PETP1)
N16981085: C615.1 J18.B20(PETN1)
N16981142: C616.1 J18.B23(PETP2)
N16981144: C617.1 J18.B24(PETN2)
N16981213: C618.1 J18.B27(PETP3)
N16981215: C619.1 J18.B28(PETN3)
N16984231: C598.1 J19.33(PETP0)
N16984233: C599.1 J19.31(PETN0)
N16985354: C630.1 J20.33(PETP0)
N16985356: C631.1 J20.31(PETN0)
N17013042: L1.1 R167.1 U1.F1(USB1_UDP)
N17013078: L1.4 R168.1 U1.F2(USB1_UDM)
N17013302: R172.2 U1.H4(USB2_UID)
N17013307: R173.2 U1.F4(USB1_UID)
N17013374: C1022.1 R171.2 U1.G4(USB_IBIAS_REXT)
N17020476: L2.1 R169.1 U1.H1(USB2_UDP)
N17020482: L2.4 R170.1 U1.H2(USB2_UDM)
N17021052: FB9.1 J41.4
N17021059: FB7.1 J41.8
N17021121: Q3.3(D) R156.1 R157.1 U1.F5(USB1_PWRFAULT)
N17021131: Q4.3(D) R155.1 R160.1 U1.H5(USB2_PWRFAULT)
N17033690: C132.1 R175.1 X1.3(OUT)
N17033815: R174.2 X1.1(OE)
N17040696: R59.1 U1.N1(SPI_CLK)
N17040868: R61.1 U1.K1(SDHC_CLK)
N17055310: C273.1 U39.2(V+)
N17055339: C275.1 U39.6(V-)
N17055373: C271.2 U39.1(C1+)
N17055376: C271.1 U39.3(C1-)
N17055394: C274.2 U39.4(C2+)
N17055396: C274.1 U39.5(C2-)
N17055419: R196.1 U39.14(T1-OUT)
N17055422: R197.1 U39.13(R1-IN)
N17055459: R199.1 U39.8(R2-IN)
N17055461: R198.1 U39.7(T2-OUT)
N17055495: FB18.1 R196.2
N17055507: FB19.1 R197.2
N17055527: FB20.1 R198.2
N17055529: FB21.1 R199.2
N17056698: C287.1 U41.2(V+)
N17056714: C288.1 U41.6(V-)
N17056740: C285.2 U41.1(C1+)
N17056750: C285.1 U41.3(C1-)
N17056764: C284.2 U41.4(C2+)
N17056766: C284.1 U41.5(C2-)
N17056776: R200.1 U41.14(T1-OUT)
N17056778: R201.1 U41.13(R1-IN)
N17056796: R203.1 U41.8(R2-IN)
N17056798: R202.1 U41.7(T2-OUT)
N17056816: FB22.1 R200.2
N17056834: FB23.1 R201.2
N17056844: FB24.1 R202.2
N17056846: FB25.1 R203.2
N17059126: R117.1 U1.AE7(EC2_TXD0)
N17059132: R118.1 U1.AF7(EC2_TXD1)
N17059135: R120.1 U1.AF6(EC2_TXD2)
N17059138: R122.1 U1.AG5(EC2_TXD3)
N17059149: R124.1 R126.1 U1.AF8(EC2_TX_CTL)
N17059152: C56.1 R128.1 U1.AE8(EC2_GTX_CLK)
N17059643: R130.1 U1.L6(EMI2_MDC)
N17059732: R121.2 U1.AC3(EC1_TXD3)
N17059733: R116.2 U1.AE4(EC1_TXD1)
N17059734: R119.2 U1.AD3(EC1_TXD2)
N17059735: R115.2 U1.AE3(EC1_TXD0)
N17059985: R123.2 R125.2 U1.AF4(EC1_TX_CTL)
N17060054: C55.2 R127.2 U1.AF3(EC1_GTX_CLK)
N17060498: R129.2 U1.AH3(EMI1_MDC)
N17072443: R106.2 TP2.1(TP) U1.B17(RTC)
N17081807: C59.2 U1.AH10(SD1_RX0_P)
N17081810: C60.2 U1.AG10(SD1_RX0_N)
N17081955: C63.2 U1.AH11(SD1_RX1_P)
N17081957: C64.2 U1.AG11(SD1_RX1_N)
N17082045: C61.2 U1.AG13(SD1_RX2_N)
N17082047: C65.2 U1.AH13(SD1_RX2_P)
N17082121: C62.2 U1.AH14(SD1_RX3_P)
N17082123: C66.2 U1.AG14(SD1_RX3_N)
N17082319: R140.2 U1.Y20(SD1_IMP_CAL_TX)
N17082346: R139.2 U1.AA12(SD1_IMP_CAL_RX)
N17093364: R137.2 TP9.1(TP) U1.AE5(TSEC_1588_TRIG_IN2)
N17093369: R136.2 TP7.1(TP) U1.AB6(TSEC_1588_TRIG_IN1)
N17093378: R135.2 TP6.1(TP) U1.AC8(TSEC_1588_CLK_IN)
N17109189: R92.1 U1.V2(IIC3_SCL)
N17109201: R93.1 U1.W3(IIC3_SDA)
N17109221: R95.1 U1.AA3(IIC4_SCL)
N17109223: R97.1 U1.AB3(IIC4_SDA)
N17109289: Q1.2(S) R89.1 U1.W1(IIC1_SCL)
N17109292: Q2.2(S) R88.1 U1.V1(IIC1_SDA)
N17109295: R87.1 U1.V3(IIC2_SCL) U19.14(SCL)
N17109336: R86.1 U1.Y3(IIC2_SDA) U19.15(SDA)
N17111815: J19.1(W\A\K\E\) R399.1
N17112169: J20.1(W\A\K\E\) R411.1
N17112712: R99.2 U19.3(R\E\S\E\T\)
N17112758: R104.2 U1.C20(FA_ANALOG_G_V)
N17112821: R105.2 U1.B20(FA_ANALOG_PIN)
N17112937: R84.1 U1.F9(SCAN_MODE_B)
N17170143: C718.1 R511.1 X3.3(OUT)
N17232338: C728.1 R517.1 X5.3(OUT)
N17232433: R516.2 X5.1(OE)
N17233442: R71.1 U1.E9(IRQ02)
N17233455: R73.1 U1.D4(IRQ04)
N17257020: T12.2 T12.3
N17259940: C682.1 R473.2
N17270978: R74.1 U1.D5(IRQ05)
N17271002: R77.1 U1.AB1(IRQ08)
N17271631: R82.1 U1.F19(TMP_DETECT_B)
N17285538: C733.1 U97.2(X1_25) Y4.1
N17285647: C734.1 U97.3(X2) Y4.3
N17321001: R103.1 U21.4(O)
N17321019: D1.2 R103.2
N17399246: C893.1 R705.1 R707.2 U83.3(M\R\)
N17399288: R707.1 SW4.2
N17400346: D35.2 R711.1 R714.1 SW5.2
N17401317: U84.1(CLK) U85.4(O)
N17401544: C895.1 D35.1 R714.2 U85.2(I)
N17403382: C890.2 C891.2 J34.1 J34.3 J35.1 L16.2
N17403388: C890.1 C891.1 D33.1 F10.2 J34.2 R701.2
N17423481: J3.5 R112.2
N17423546: J3.6 R108.1
N17447445: C642.2 R429.1
N17447447: C644.2 R431.1
N17448817: R448.2 U63.28(DXA/DU)
N17448821: R453.2 U63.34(DIN/S1)
N17448825: R455.2 U63.32(R\S\T\)
N17448833: R449.2 U63.35(DOUT)
N17448841: R466.2 U63.9(RTV1)
N17448842: R466.1 U63.6(RSN1)
N17448845: C672.2 U63.51(IHL2)
N17448846: C670.2 C671.1 C672.1 U63.17(VREF)
N17448848: C671.2 U63.10(IHL1)
N17448854: R467.1 U63.52(RTV2)
N17448855: R467.2 U63.55(RSN2)
N17448859: R469.2 U63.16(IREF)
N17448862: C673.1 U63.15(LFC1)
N17448864: C661.1 F5.1 R452.2 U62.1 U62.8 U63.77(TIPD1)
N17448865: C662.2 F6.1 R444.2 U62.4 U62.5 U63.71(RINGD1)
N17448866: R720.1 U63.13(TDC1)
N17448867: R721.1 U63.14(RDC1)
N17448868: C659.2 R452.1
N17448869: C659.1 U63.11(TAC1)
N17448871: C660.1 U63.12(RAC1)
N17448872: C660.2 R444.1
N17448897: C664.1 F7.1 R459.2 U63.67(TIPD2) U64.1 U64.8
N17448901: C667.2 F8.1 R461.2 U63.61(RINGD2) U64.4 U64.5
N17448912: C666.1 U63.50(TAC2)
N17448913: C668.1 U63.49(RAC2)
N17448914: R722.1 U63.47(RDC2)
N17448915: R723.1 U63.48(TDC2)
N17449042: R460.2 R463.2 U63.45(XB)
N17449050: R447.2 U63.29(DRA/DD)
N17449051: R446.2 U63.26(FS/FSC)
N17449052: C666.2 R459.1
N17449053: C668.2 R461.1
N17451420: D22.1 J25.1 R468.1
N17481068: R100.2 U1.R5(DMA1_DDONE0_B)
N17523688: U84.2(D) U84.3(Q\)
N17523697: R713.1 U84.5(Q)
N17523706: C896.1 R715.2 U84.6(C\L\R\)
N17523733: D33.2 L16.1 Q29.3(D)
N17524661: C892.1 Q28.3(D) Q29.1(G) R704.1
N17525004: D34.2 Q27.3(D) Q28.1(G) R703.1
N17540556: R417.2 U59.30(PCLK/DCL)
N17540577: R425.2 U59.33(DCLK/S0)
N17540598: R445.2 U63.30(PCLK/DCL)
N17540619: R450.2 U63.33(DCLK/S0)
N17582904: R332.1 T5.24
N17582906: C499.2 R332.2 R334.2 R336.2 R338.2
N17582916: R334.1 T5.21
N17582920: R336.1 T5.18
N17582932: R338.1 T5.15
N17584869: R291.1 U55.C10(MDINT)
N17602850: C490.2 T5.1
N17602860: C493.2 T5.4
N17602866: C495.2 T5.7
N17602896: C497.2 T5.10
N17604579: R302.2 U55.C7(J\T\A\G\_\T\R\S\T\)
N17629033: R294.1 U55.B12(PHYADD3)
N17629034: R295.1 U55.D26(PHYADD4)
N17629035: R293.1 U55.C19(PHYADD2)
N17629369: R292.2 U55.B5(R\E\S\E\T\)
N17629454: R297.2 U55.D8(COMA_MODE)
N17629729: C440.1 U55.A7(REF_FILT)
N17629871: R303.2 U55.A8(REF_REXT)
N17632317: R344.1 T7.24
N17632319: C513.2 R344.2 R346.2 R348.2 R350.2
N17632321: R346.1 T7.21
N17632325: R348.1 T7.18
N17632337: R350.1 T7.15
N17632390: C505.2 T7.1
N17632398: C507.2 T7.4
N17632406: C509.2 T7.7
N17632436: C511.2 T7.10
N17632726: C527.2 R356.2 R358.2 R360.2 R362.2
N17632728: R356.1 T9.24
N17632740: R360.1 T9.18
N17632744: R358.1 T9.21
N17632760: R362.1 T9.15
N17632797: C521.2 T9.4
N17632805: C519.2 T9.1
N17632821: C523.2 T9.7
N17632853: C525.2 T9.10
N17633242: R368.1 T11.24
N17633244: C542.2 R368.2 R370.2 R372.2 R374.2
N17633254: R370.1 T11.21
N17633258: R372.1 T11.18
N17633270: R374.1 T11.15
N17633303: C535.2 T11.4
N17633315: C533.2 T11.1
N17633335: C537.2 T11.7
N17633357: C539.2 T11.10
N17639917: C485.1 U56.A7(REF_FILT)
N17639934: R324.2 U56.A8(REF_REXT)
N17639958: R725.2 U56.D18(SEDES_REXT_1)
N17639964: R725.1 U56.D17(SEDES_REXT_0)
N17639984: R323.2 U56.C7(J\T\A\G\_\T\R\S\T\)
N17640717: R312.1 U56.C10(MDINT)
N17640929: R315.1 U56.B12(PHYADD3)
N17640931: R316.1 U56.D26(PHYADD4)
N17640933: R314.1 U56.C19(PHYADD2)
N17640965: R313.2 U56.B5(R\E\S\E\T\)
N17640979: R320.2 U56.D8(COMA_MODE)
N17694594: U6.16(CLE) U7.10(B3)
N17694666: U6.8(R\E\) U7.12(B1)
N17694695: U6.18(W\E\) U11.12(B1)
N17694723: U6.19(W\P\) U11.11(B2)
N17736577: R17.1 SW1.16
N17736598: R19.1 SW1.15
N17736619: R21.1 SW1.14
N17736629: R23.1 SW1.13
N17736659: R25.1 SW1.12
N17736669: R27.1 SW1.11
N17736681: R29.1 SW1.10
N17736695: R31.1 SW1.9
N17736739: R33.1 SW2.16
N17736751: R34.1 SW2.15
N17736763: R35.1 SW2.14
N17736781: R36.1 SW2.13
N17736801: R39.1 SW2.11
N17736803: R37.1 SW2.12
N17736817: R38.1 SW2.10
N17736835: R40.1 SW2.9
N17775417: C501.2 J15.A12 R342.2
N17775429: C503.2 J15.A10 R340.2
N17779755: C515.2 J15.B12 R354.2
N17779761: C517.2 J15.B10 R352.2
N17780053: C529.2 J15.C12 R366.2
N17780059: C531.2 J15.C10 R364.2
N17780366: C540.2 J15.D12 R376.2
N17780372: C543.2 J15.D10 R375.2
N17787749: C546.2 J15.H12(G12) R378.2
N17787773: C547.2 J15.H10(G10) R377.2
N17787818: C498.2 R331.2 R333.2 R335.2 R337.2
N17787822: C512.2 R343.2 R345.2 R347.2 R349.2
N17787848: C526.2 R355.2 R357.2 R359.2 R361.2
N17787852: C541.2 R367.2 R369.2 R371.2 R373.2
N17787943: R331.1 T4.24
N17787947: R333.1 T4.21
N17787951: R335.1 T4.18
N17787955: R337.1 T4.15
N17787993: C491.2 T4.1
N17788013: C492.2 T4.4
N17788019: C494.2 T4.7
N17788035: C496.2 T4.10
N17788175: R343.1 T6.24
N17788179: R345.1 T6.21
N17788183: R347.1 T6.18
N17788187: R349.1 T6.15
N17788233: C504.2 T6.1
N17788241: C506.2 T6.4
N17788251: C508.2 T6.7
N17788275: C510.2 T6.10
N17788409: R357.1 T8.21
N17788413: R355.1 T8.24
N17788425: R361.1 T8.15
N17788429: R359.1 T8.18
N17788459: C520.2 T8.4
N17788477: C518.2 T8.1
N17788487: C522.2 T8.7
N17788519: C524.2 T8.10
N17788647: R367.1 T10.24
N17788651: R369.1 T10.21
N17788663: R371.1 T10.18
N17788667: R373.1 T10.15
N17788695: C534.2 T10.4
N17788701: C532.2 T10.1
N17788725: C536.2 T10.7
N17788759: C538.2 T10.10
N17788879: C500.2 J15.E12 R341.2
N17788889: C502.2 J15.E10 R339.2
N17788969: C514.2 J15.F12 R353.2
N17788975: C516.2 J15.F10 R351.2
N17789051: C528.2 J15.G12 R365.2
N17789057: C530.2 J15.G10 R363.2
N17823659: C411.2 U55.D12(REFCLK_N)
N17823662: C410.2 U55.D11(REFCLK_P)
N17824163: C456.2 U56.D12(REFCLK_N)
N17824166: C455.2 U56.D11(REFCLK_P)
N18271716: Q15.1(G) R666.2 R669.2
N18271718: C873.2 Q15.3(D) R659.2 R662.2
N18271794: Q11.4 R659.1
N18272048: Q13.1(G) R665.2 R667.2
N18272050: C871.2 Q13.3(D) R657.2 R660.2
N18272126: Q8.4 Q9.4 R657.1
N18272820: C875.2 Q20.3(D) R675.2 R678.2
N18272822: Q20.1(G) R681.2 R684.2
N18272905: Q17.4 R675.1
N18273179: Q21.1(G) R682.2 R685.2
N18273181: C876.2 Q21.3(D) R676.2 R679.2
N18273262: Q18.4 R676.1
N18273767: Q16.1(G) R670.2 R671.2
N18273907: C874.2 Q12.4 Q16.3(D) R663.2
N18275087: C887.1 R695.1 R696.2 U81.1(REFIN)
N18275123: C884.1 R694.1 U81.5(VOSNS)
N18275169: R697.1 U81.9(PGOOD)
N18287015: R138.1 U23.4(C) U24.4(C)
N18382428: R499.1 SW3.16
N18382505: R500.1 SW3.15
N18382570: R501.1 SW3.14
N18382580: R503.1 SW3.13
N18382664: R507.1 SW3.11
N18382676: R509.1 SW3.10
N18562864: Q30.1(B) R713.2
N18563122: J37.8(PWR_OK) R706.1 R709.2
N18564716: C878.2 Q25.3(D) Q26.1(G) R688.2 R690.2
N18564718: Q25.1(G) R692.2 R693.2
N18564801: Q23.4 Q42.4 R688.1
N18564847: Q23.5 Q42.5
N18565254: C888.1 D31.1 J31.2 U82.1(VIN) U82.3(EN)
N18565311: D30.1 J31.1
N18565323: D30.2 J30.1
N18566414: C879.1 Q26.3(D) R689.1 R691.1
N18566880: Q24.4 Q43.4 R689.2
N18586245: C294.2 R205.2 U45.2(D+)
N18586247: C294.1 R206.2 U45.3(D-)
N18629376: C405.2 U55.D15(QSGMII0_TXN)
N18629379: C400.2 U55.D16(QSGMII0_TXP)
N18629428: C454.2 U56.D15(QSGMII0_TXN)
N18629431: C445.2 U56.D16(QSGMII0_TXP)
N18629823: C633.2 J21.3(TX_N)
N18629826: C632.2 J21.2(TX_P)
N18629885: C634.2 J21.5(RX_N)
N18629888: C635.2 J21.6(RX_P)
N18635664: D40.1 R470.2
N18636077: D41.1 R471.2
N18636082: D42.1 R472.2
N18636371: D38.1 R439.2
N18636375: D39.1 R440.2
N18648944: D36.1 R394.2
N18648948: D37.1 R395.2
N18669250: C761.1 R557.1 R560.2 U70.9(VINSEN)
N18669461: R568.2 U70.8(EN2)
N18669908: R573.2 U70.14(SM_ALERT)
N18671161: C770.2 R575.2 U70.13(ADDR_PROT)
N18671661: C778.1 R576.2 U70.31(RCSP1)
N18671664: C778.2 R580.2 U70.32(RCSM1)
N18671728: R577.1 R578.1 R580.1
N18671731: R576.1 R577.2 R578.2
N18672102: R594.2 U70.4(RRES)
N18672710: C795.1 R595.1 U70.6(V18A)
N18673934: R581.1 U70.25(ISEN2)
N18674032: R582.1 U70.26(IRTN2)
N18675394: R561.1 U69.24(BOOST)
N18676216: C763.2 R561.2
N18677032: C765.1 R562.2 R565.2
N18677238: R558.2 U69.25(P\H\S\F\L\T\) U71.25(P\H\S\F\L\T\)
N18679447: R579.1 U71.24(BOOST)
N18679579: C779.2 R579.2
N18679604: C785.1 R586.2 R590.2
N18708218: R588.1 U70.21(VSEN2)
N18708230: R589.1 U70.20(VRTN2)
N18709569: R593.2 U70.5(TSEN)
N18711479: R598.1 R599.2 U72.4(ADJ)
N19126530: R505.1 SW3.12
N19163046: R495.1 X2.3(OUT)
N19163064: R494.2 X2.1(OE)
N19211889: C766.2 R567.2
N19212054: C786.2 R592.2
N19214297: C798.2 R596.2 R597.2 U72.1(EN)
N19293526: D5.1 R186.2
N19295120: D6.1 R187.2
N19535162: R441.1 R720.2
N19535165: R451.1 R721.2
N19535242: R465.1 R723.2
N19535245: R464.1 R722.2
N19535322: R412.1 R716.2
N19535325: R413.1 R717.2
N19535364: R435.1 R719.2
N19535367: R434.1 R718.2
N19620774: C68.2 U1.AA14(SD1_REF_CLK1_N)
N19620777: C67.2 U1.AB14(SD1_REF_CLK1_P)
N19623883: C996.2 Q32.3(D) R783.2 R784.2
N19623885: Q32.1(G) R785.2 R786.2
N19623968: Q31.4 R783.1
N19644915: C927.2 L18.1 R731.2 R735.1 U87.12(PHASE)
N19644936: C941.2 C943.2 R735.2
N19644956: C943.1 R736.1 R745.2 R787.2 U87.5(FB)
N19644972: R739.2 U87.3(PGOOD)
N19644986: C932.2 R734.2 U87.16(EN)
N19645019: C946.1 R741.1 U87.8(3VCBP)
N19645035: R741.2 R743.2 U87.1(FCCM)
N19645080: C947.1 U87.6(SS)
N19645160: R728.2 U87.15(FF)
N19645192: C927.1 U87.14(BOOT)
N19645200: R731.1 U87.2(ISET)
N19646811: C949.2 L20.1 R749.2 R755.1 U89.12(PHASE)
N19646830: C965.2 C967.2 R755.2
N19646848: C967.1 R757.1 R763.2 U89.5(FB)
N19646866: R749.1 U89.2(ISET)
N19646870: R756.2 U89.3(PGOOD)
N19646891: C957.2 R754.2 U89.16(EN)
N19646930: C970.1 R759.1 U89.8(3VCBP)
N19646940: R759.2 R761.2 U89.1(FCCM)
N19646995: C971.1 U89.6(SS)
N19647070: R747.2 U89.15(FF)
N19647102: C949.1 U89.14(BOOT)
N19648273: C978.2 L22.1 R767.2 R775.1 U90.12(PHASE)
N19648275: C989.2 C991.2 R775.2
N19648310: C991.1 R772.1 R781.2 U90.5(FB)
N19648328: R767.1 U90.2(ISET)
N19648366: C981.2 R770.2 U90.16(EN)
N19648414: C994.1 R777.1 U90.8(3VCBP)
N19648420: R777.2 R779.2 U90.1(FCCM)
N19648465: C995.1 U90.6(SS)
N19648544: R765.2 U90.15(FF)
N19648572: C978.1 U90.14(BOOT)
N19650144: C972.2 L21.1 R766.2 R769.1 U91.12(PHASE)
N19650163: C988.2 C990.2 R769.2
N19650181: C990.1 R774.1 R780.2 U91.5(FB)
N19650199: R766.1 U91.2(ISET)
N19650212: R773.2 U91.3(PGOOD)
N19650233: C977.2 R768.2 U91.16(EN)
N19650272: C992.1 R776.1 U91.8(3VCBP)
N19650282: R776.2 R778.2 U91.1(FCCM)
N19650331: C993.1 U91.6(SS)
N19650402: R764.2 U91.15(FF)
N19650430: C972.1 U91.14(BOOT)
N19651609: C948.2 L19.1 R748.2 R751.1 U88.12(PHASE)
N19651628: C964.2 C966.2 R751.2
N19651646: C966.1 R753.1 R762.2 U88.5(FB)
N19651664: R748.1 U88.2(ISET)
N19651683: R752.2 U88.3(PGOOD)
N19651731: C968.1 R758.1 U88.8(3VCBP)
N19651747: R758.2 R760.2 U88.1(FCCM)
N19651788: C969.1 U88.6(SS)
N19651863: R746.2 U88.15(FF)
N19651895: C948.1 U88.14(BOOT)
N19653096: C924.2 L17.1 R729.2 R733.1 U86.12(PHASE)
N19653107: C935.2 C942.2 R733.2
N19653133: C942.1 R738.1 R744.2 U86.5(FB)
N19653151: R729.1 U86.2(ISET)
N19653170: R737.2 U86.3(PGOOD)
N19653218: C944.1 R740.1 U86.8(3VCBP)
N19653234: R740.2 R742.2 U86.1(FCCM)
N19653275: C945.1 U86.6(SS)
N19653350: R730.2 U86.15(FF)
N19653382: C924.1 U86.14(BOOT)
N19673378: R726.1 U70.24(RCSP2)
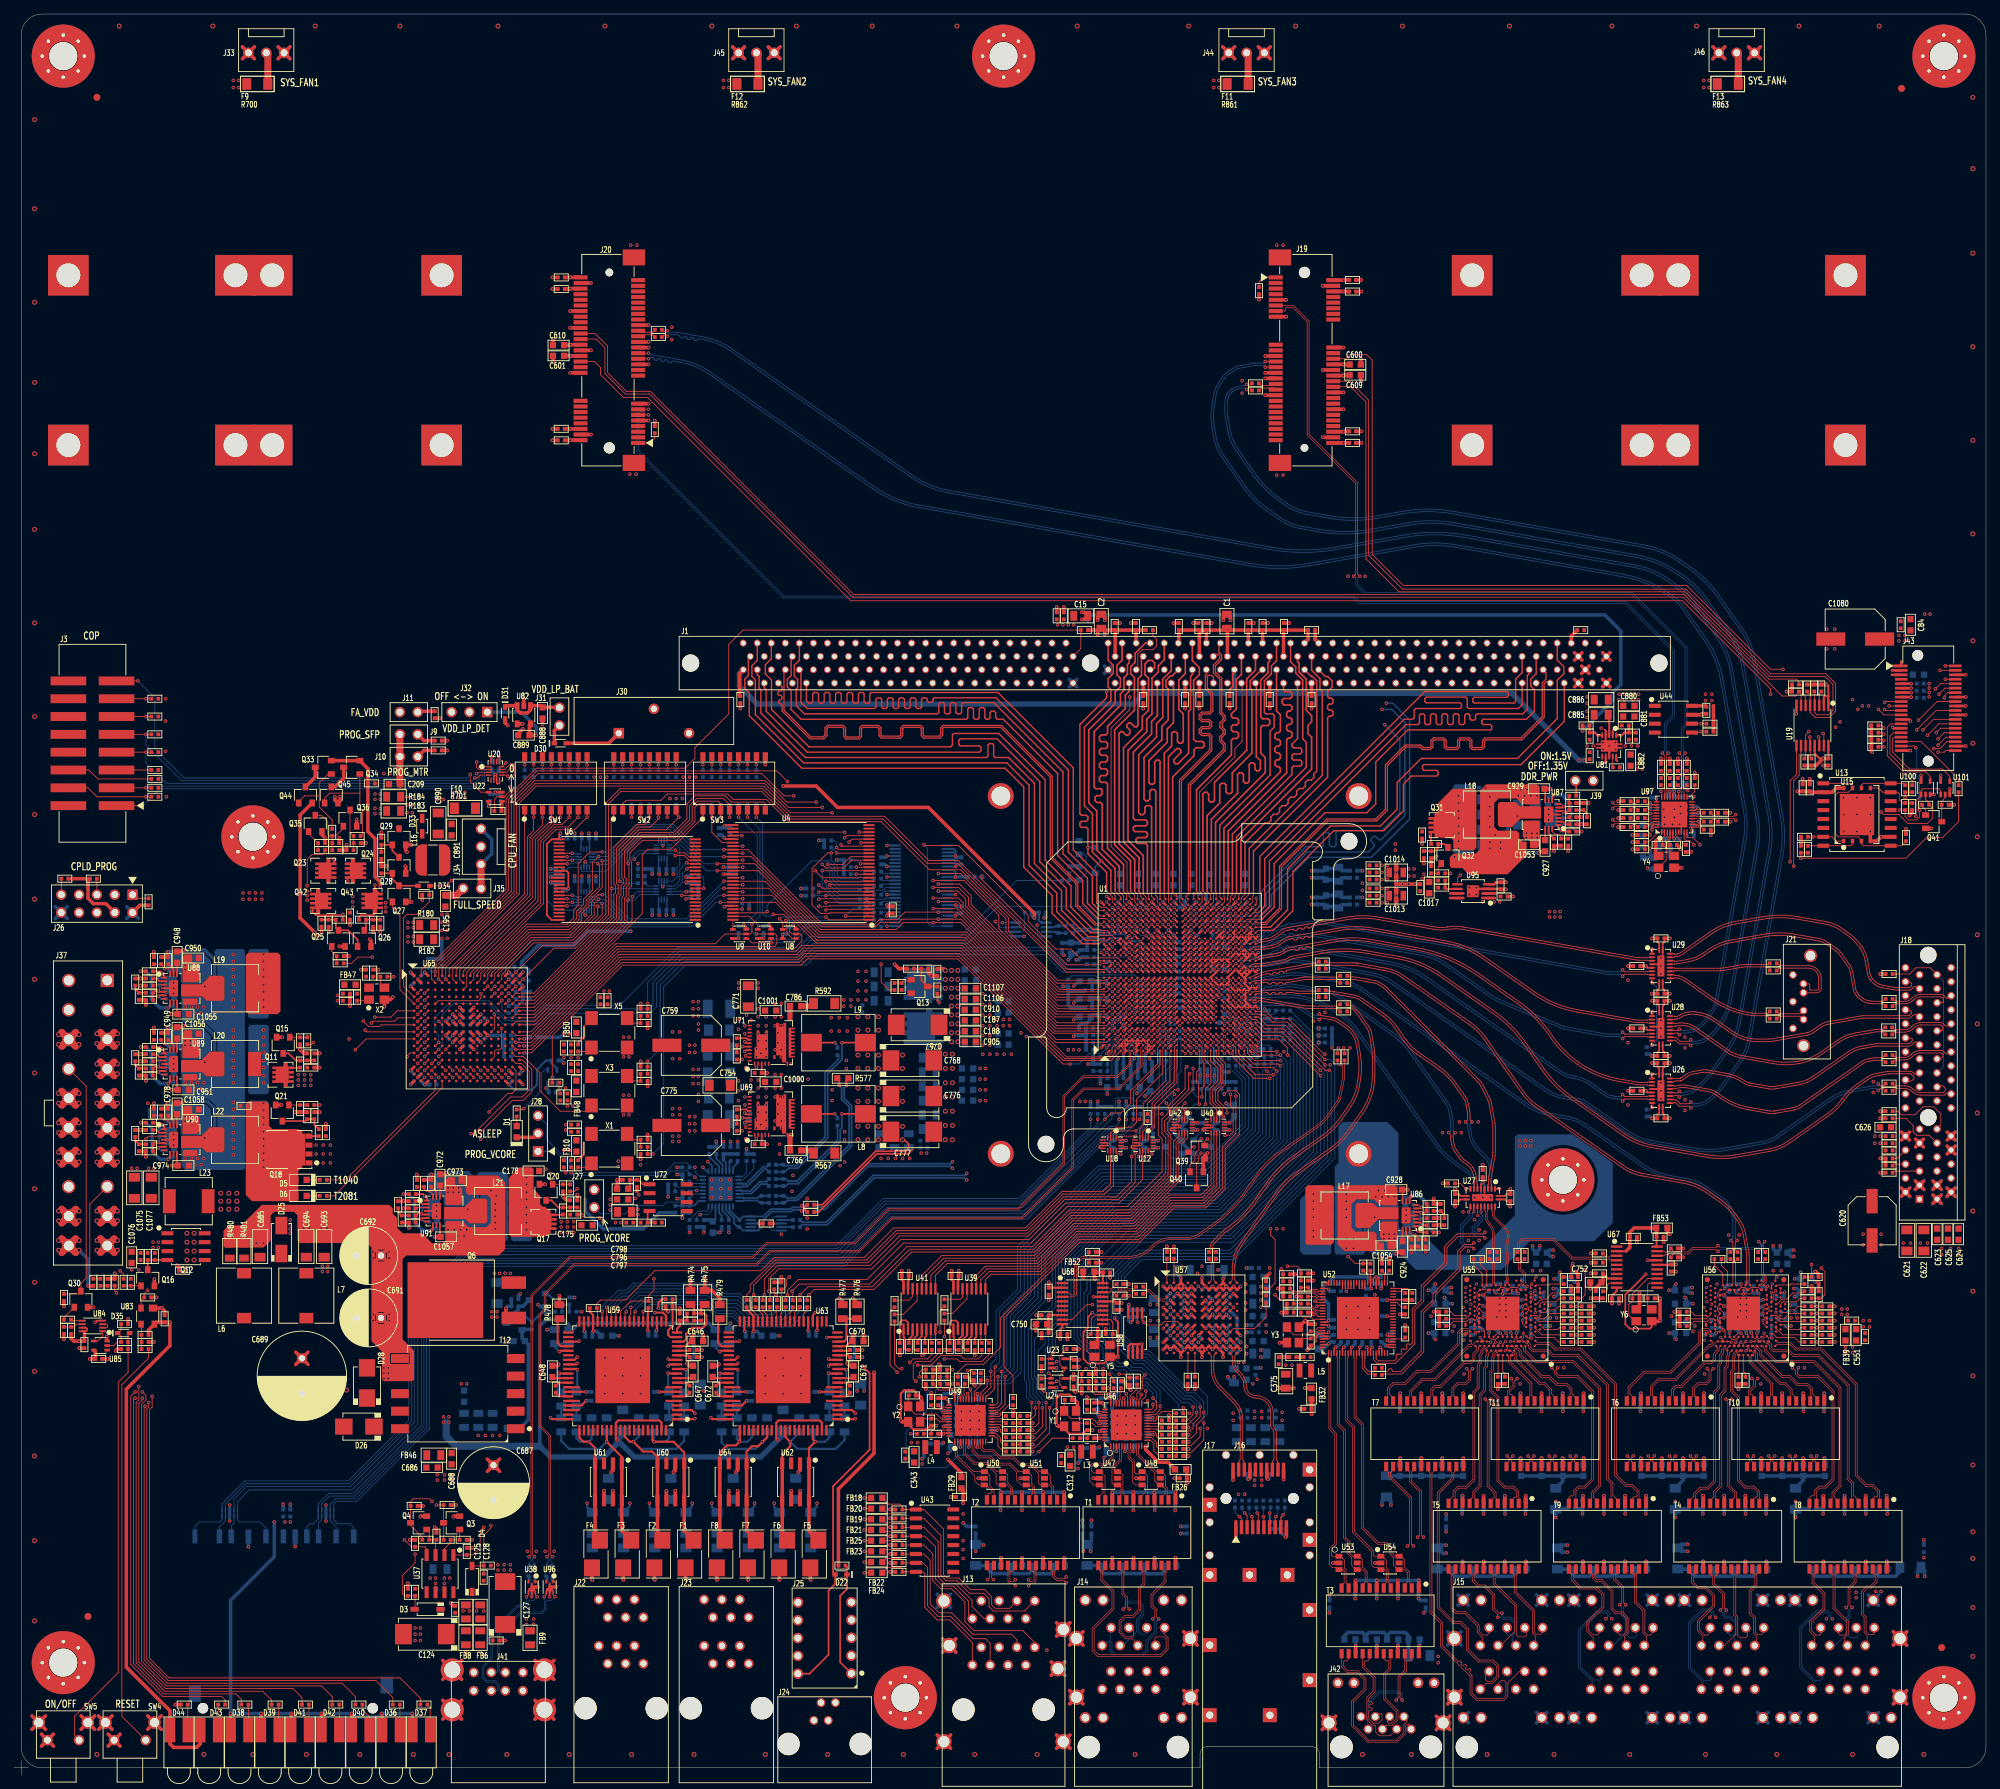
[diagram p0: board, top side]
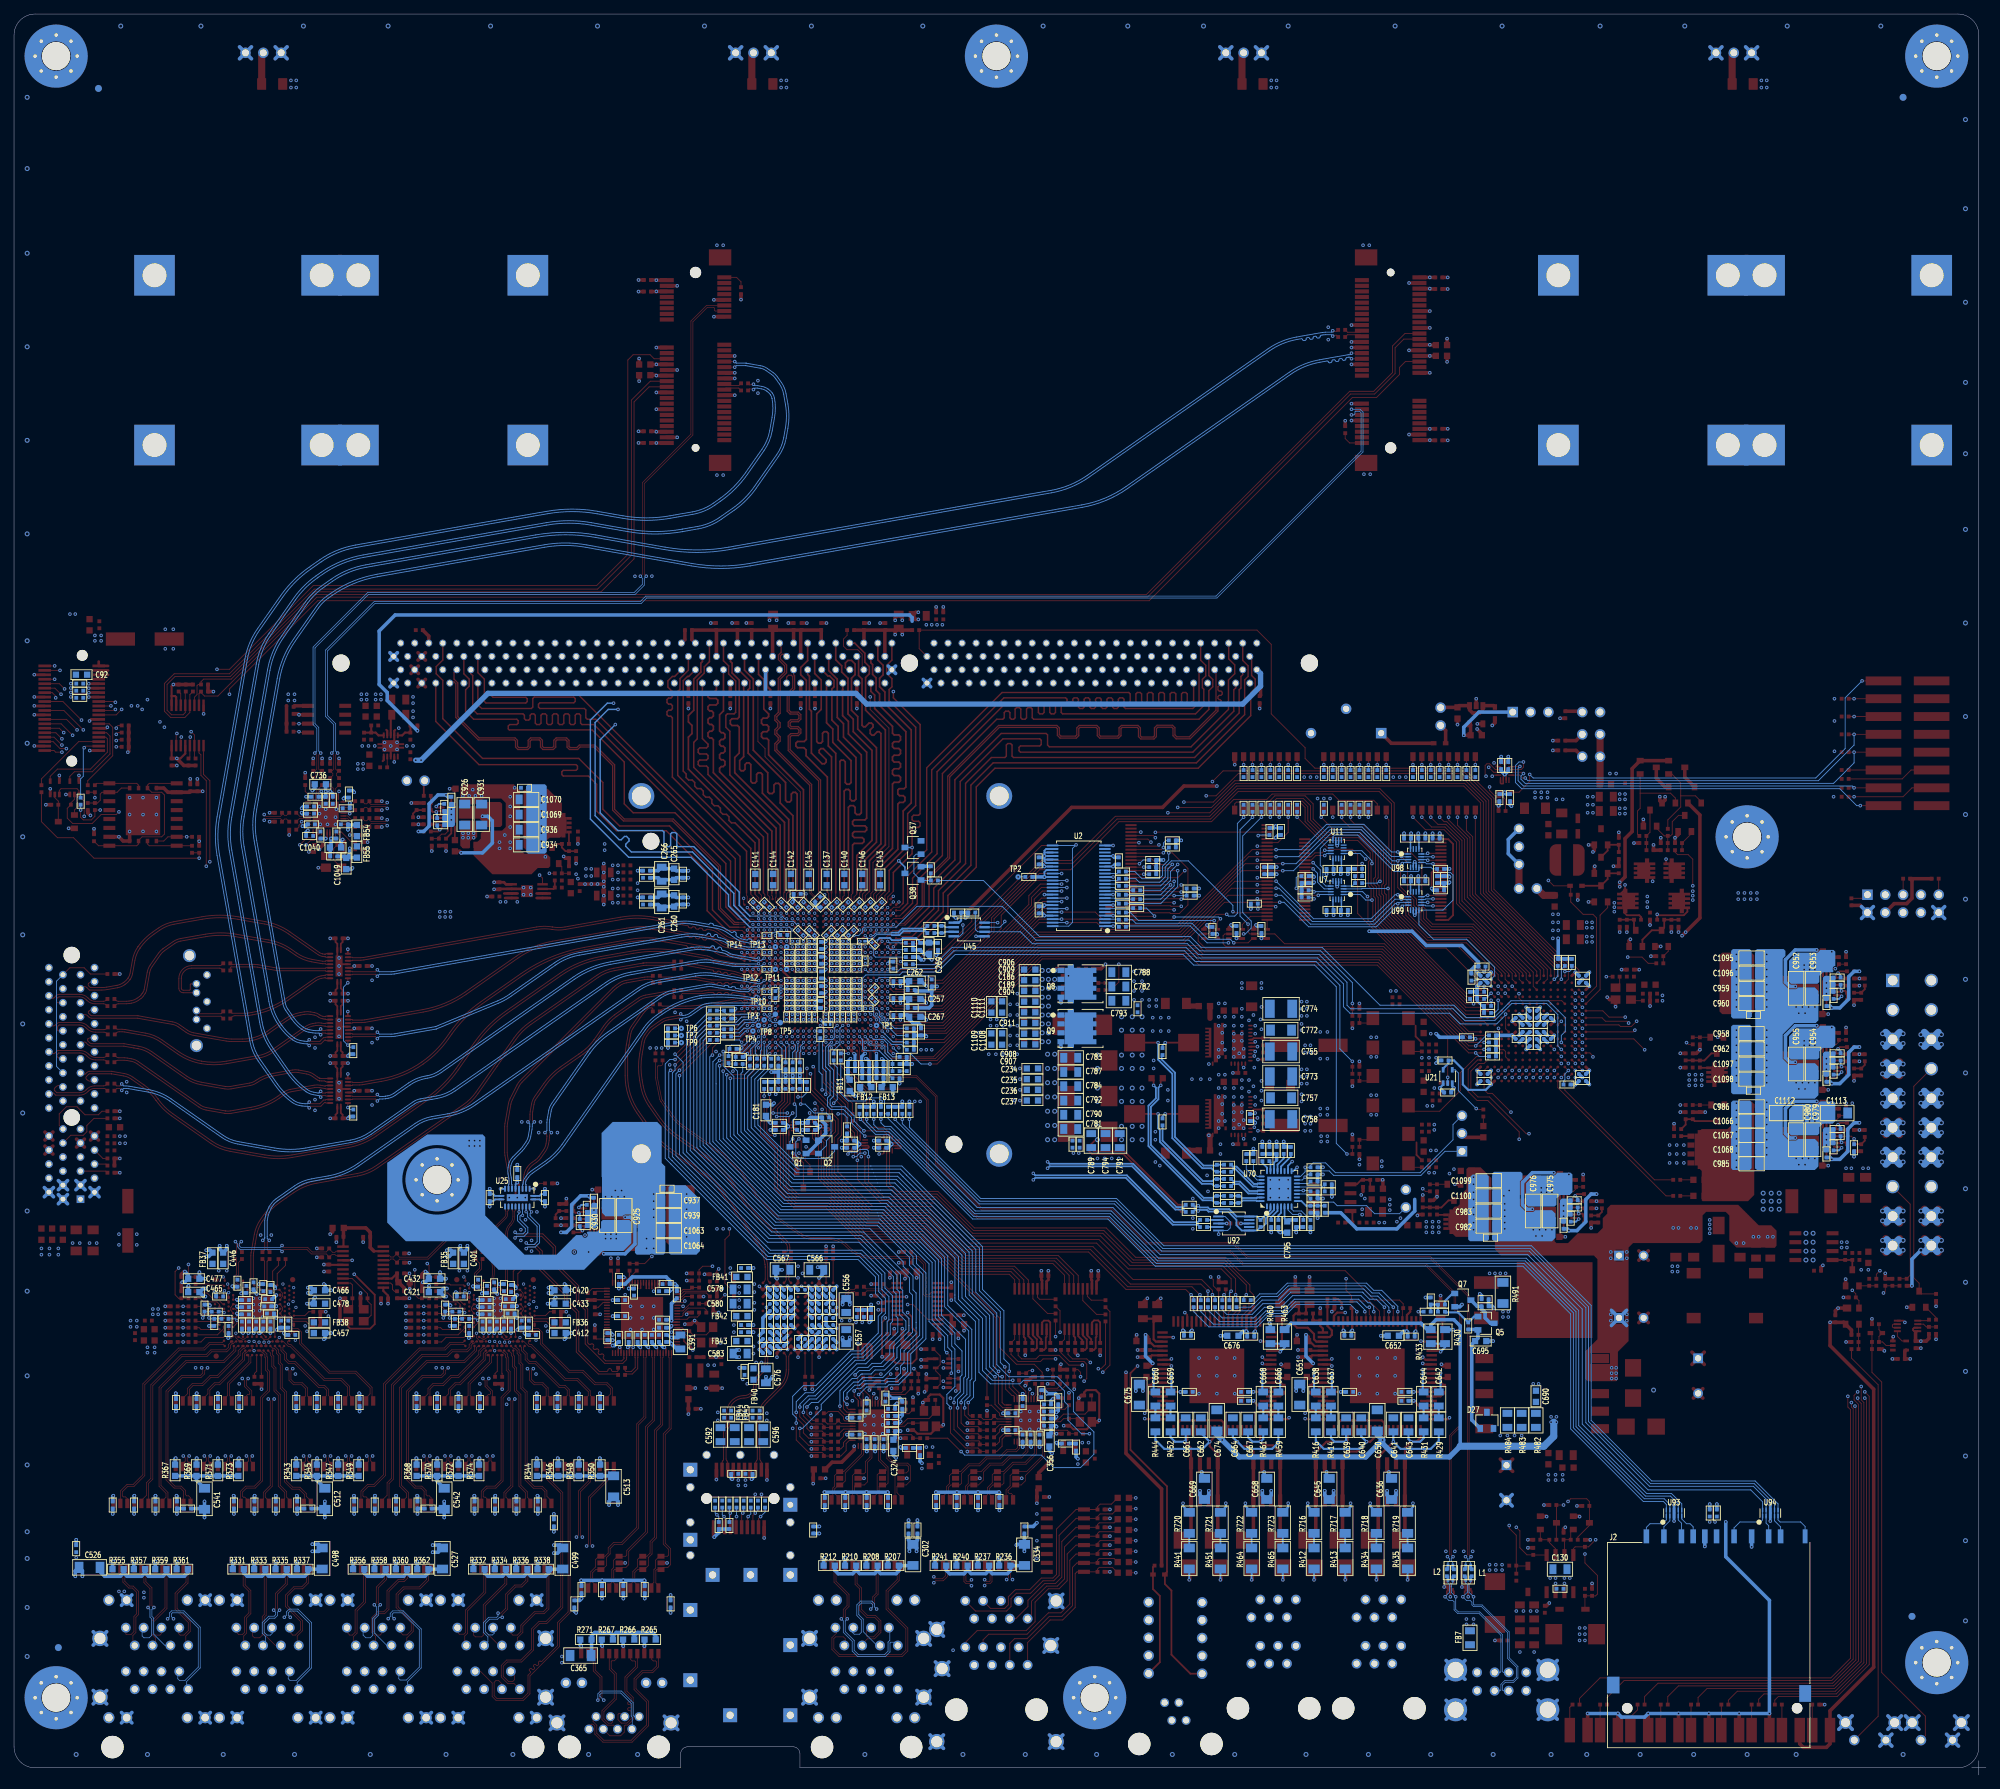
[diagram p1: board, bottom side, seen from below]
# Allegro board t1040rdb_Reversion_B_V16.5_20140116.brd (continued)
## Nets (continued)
N19673381: R726.2 U70.23(RCSM2)
N19675149: R724.2 U55.D18(SEDES_REXT_1)
N19675151: R724.1 U55.D17(SEDES_REXT_0)
N19825990: J39.1 R787.1
N20075552: R552.1 U92.2(S1A)
N20075564: R554.1 U92.4(S2A)
N20366563: R806.1 R807.2 U95.6(FB/ADJ)
N20473911: R811.1 U1.C15(IFC_PAR0)
N20516568: TP1.1(TP) U1.E6(CLK_OUT)
N20517420: TP3.1(TP) U1.AD7(TSEC_1588_CLK_OUT)
N20517422: TP4.1(TP) U1.AF5(TSEC_1588_ALARM_OUT1)
N20517434: TP5.1(TP) U1.AC7(TSEC_1588_ALARM_OUT2)
N20517436: TP8.1(TP) U1.AE6(TSEC_1588_PULSE_OUT1)
N20517448: TP10.1(TP) U1.AD8(TSEC_1588_PULSE_OUT2)
N20553507: Q37.1(G) Q38.1(G) R830.2 R831.2
N20559490: Q35.1(G) R820.2 R821.2
N20559492: C1023.2 Q35.3(D) Q36.1(G) R816.2 R818.2
N20559589: Q33.1(G) Q44.1(G) R816.1
N20559634: Q33.3(D) Q44.3(D)
N20559669: C1024.1 Q36.3(D) R817.1 R819.1
N20559724: Q34.1(G) Q45.1(G) R817.2
N20562248: TP11.1(TP) U1.Y15(SD1_PLL1_TPA)
N20562257: TP12.1(TP) U1.AB15(SD1_PLL1_TPD)
N20562271: TP13.1(TP) U1.Y19(SD1_PLL2_TPA)
N20562273: TP14.1(TP) U1.AB19(SD1_PLL2_TPD)
N20562350: C1022.2 R814.2
N20977401: C739.1 U68.13(XTAL_IN) Y5.1
N20977407: C738.1 U68.12(XTAL_OUT) Y5.3
N20978279: C740.1 U67.13(XTAL_IN) Y6.1
N20978303: C741.1 U67.12(XTAL_OUT) Y6.3
N20978493: R540.2 U67.9(F_SEL0)
N20980151: R829.2 R842.2 U97.1(SS_EN_TRI)
N20982998: R834.2 U97.6(SADR/REF1.8)
N21105612: R525.1 U97.22(DIF2)
N21105614: R526.1 U97.23(D\I\F\2\)
N21105620: R530.1 U97.28(DIF3)
N21105622: R532.1 U97.29(D\I\F\3\)
N21105628: R536.1 U97.33(DIF4)
N21105630: R537.1 U97.34(D\I\F\4\)
N21105856: R837.1 U97.37(D\I\F\5\)
N21105862: R836.1 U97.36(DIF5)
N21227087: J37.1(+3.3VDC#1)
N21227093: J37.2(+3.3VDC#2)
N21227121: J37.11(+3.3VDC#11)
N21754633: J43.28 R867.1
N21754692: J43.36 R868.1
N21754708: J43.38 R869.1
N21824193: Q41.1(G) R860.2
N21824406: Q41.3(D) R859.2 U101.2(I1)
N22254280: R520.1 U97.14(DIF0)
N22254282: R521.1 U97.15(D\I\F\0\)
N22255501: R533.2 U97.21(O\E\1\)
N22257590: R14.1 U2.2(1Q1)
N22257592: R15.1 U2.3(1Q2)
N22257594: R16.1 U2.5(1Q3)
N22258098: R20.1 U2.8(1Q5)
N22258100: R22.1 U2.9(1Q6)
N22258102: R24.1 U2.11(1Q7)
N22258104: R26.1 U2.12(1Q8)
N22258216: R18.1 U2.6(1Q4)
N22258634: R28.1 U2.13(2Q1)
N22258636: R30.1 U2.14(2Q2)
N22258638: R32.1 U2.16(2Q3)
N22360230: F9.2 J33.2 R700.2
N22360382: F11.2 J44.2 R861.2
N22360534: F12.2 J45.2 R862.2
N22361017: F13.2 J46.2 R863.2
N22361656: D43.1 R702.2
N22361689: D44.1 R699.2
N22440478: Q34.3(D) Q45.3(D)
N22476599: R49.2 R50.2 U7.4(A4)
N22787926: Q24.5 Q43.5

Pads without a net: J1 126 135 144 153 162 167 187 204 213 222 231; J3 2 8 10 14; J13 A2 A7 B2 B7; J17 19; J18 A7 A19 A32 B12 B30; J19 3 5 7 8 10 12 14 16 17 19 20 36 37 38 39 41 42 43 44 45 46 47 49 51; J20 3 5 7 8 10 12 14 16 17 19 20 36 37 38 39 41 42 43 44 45 46 47 49 51; J22 A1 A2 A5 A6 B1 B2 B5 B6; J23 A1 A2 A5 A6 B1 B2 B5 B6; J24 1 4; J25 5 6; J26 6 7 8; J43 8; T12 5 6 9; U1 A14 A16 A19 AA5 AA6 AA7 AA8 AA9 AA10 AB8 AB11 AB12 AC4 AG28 C3 C4 C16 C17 C19 D6 D18 E17 F10 F21 G6 G17 H6 H21 J6 J20 K22 M22 N6 P22 T6 U6 U22 V6 V21 W6 W21 Y5 Y6 Y21; U2 17 19 20 22 23; U4 27 28 30; U6 1 2 3 4 5 6 11 14 15 20 21 22 23 24 26 27 28 33 35 38 40 45 46 47; U7 5 14 15; U11 3 4 5 9 10 14 15; U12 5 14 15; U13 3 4 5 6 11 12 13 14; U18 4 5 9 14 15; U20 5 14 15; U25 12 13 14 15; U38 3; U40 5 14 15; U42 5 14 15; U46 12; U47 5; U48 5; U49 12; U50 5; U51 5; U52 21 22 28 29 30 31 32 33 35 36 37 38 41 42 56 62 63 64 65 74 76 86; U53 5; U54 5; U55 A1 A2 A3 A4 A5 A6 B1 B3 B6 B9 B10 B11 B13 B14 C2 C4 C8 C9 C12 C13 C14 C15 C16 C17 C18 C20 D2 D3 D4 D6 D7 D19 D20 D21 D22 D23 D24 D25 D27 D28; U56 A1 A2 A3 A4 A5 A6 B1 B3 B6 B9 B10 B11 B13 B14 C2 C4 C8 C9 C12 C13 C14 C15 C16 C17 C18 C20 D2 D3 D4 D6 D7 D19 D20 D21 D22 D23 D24 D25 D27 D28; U57 A4 A5 C2 C6 C7 C10 D3 D10 D11 E3 E11 F10 F11 G10 G11 H1 J2 J3 J11 L1 L2; U59 2 4 22 24 27 38 40 41 42 46 59 62 63 64 65 66 68 70 72 73 74 75 76 78 80; U60 3; U61 3; U62 3; U63 2 4 20 21 22 27 38 40 41 42 46 59 62 63 64 65 66 68 70 72 73 74 75 76 78 80; U64 3; U65 D6 D7 D8 D9 D10 E5 E6 E7 E8 E9 E10 E11 E12 F4 F5 F6 F7 F10 F11 F12 G4 G5 G6 G11 G12 G13 H4 H12 H13 J4 J5 J13 K4 K5 K6 K11 K12 K13 L5 L7 L10 L11 L12 M6 M7 M8 M9 M10 M11 M12 N6 N7 N8 N9 N10 N11; U67 1 5 6 7 11 14 15; U68 1 5 6 7 11 14 15; U69 5 30 32; U70 1 10 19; U71 5 30 32; U85 1; U86 7 9; U87 7 9; U88 7 9; U89 7 9; U90 7 9; U91 7 9; U92 7 9; U96 3; U97 7 18 19 20 25 40; U98 5 14 15; U99 5 14 15; Z97 1; Z98 1; Z99 1; Z100 1; Z101 1; Z102 1; Z103 1; Z104 1

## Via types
v1: diameter 0.508, hole 0.254, TOP to BOTTOM, 2856 vias
v2: diameter 0.457, hole 0.254, TOP to BOTTOM, 703 vias
v3: diameter 0.711, hole 0.406, TOP to BOTTOM, 218 vias

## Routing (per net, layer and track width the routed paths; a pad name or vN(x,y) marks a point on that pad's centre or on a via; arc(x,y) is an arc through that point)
1V0: length 61.1
  TOP w0.102: U55.E21 208.49,68.2 208.47,68.28 208.46,68.38 208.48,68.68 U55.E19 ; U56.E19 242.77,68.68 242.75,68.38 242.76,68.28 242.78,68.2 U56.E21
  TOP w0.127: v1(246.43,68.58) 247.47,68.58 247.74,68.84 U56.E13 ; v1(246.43,68.58) 246.44,68.59 U56.E15 ; v1(246.43,68.58) 245.39,68.58 245.14,68.83 U56.E17 ; v2(249.25,66.8) 249.55,67.1 U56.E7 250.13,66.61 250.13,66.28 U56.E5 ; U55.E10 215.4,69.45 v2(215.62,69.67) ; v2(249.91,69.67) 249.69,69.45 U56.E10 ; v1(212.14,68.58) 213.18,68.58 213.45,68.84 U55.E13 ; v1(212.14,68.58) 212.15,68.59 U55.E15 ; v1(212.14,68.58) 211.1,68.58 210.85,68.83 U55.E17 ; v2(209.52,69.34) 209.34,69.15 U55.E19 ; U55.E23 209.35,65.9 v2(209.35,65.15) U55.E25 ; v2(214.96,66.8) 215.26,67.1 U55.E7 215.84,66.61 215.84,66.28 U55.E5 ; U56.E25 v2(243.64,65.15) 243.64,65.9 U56.E23 ; v2(243.81,69.34) 243.63,69.15 U56.E19
  TOP w0.381: U57.E4 v1(166.79,66.65) ; U57.D6 v1(169.79,67.65) ; U57.C3 v1(165.79,68.65) ; U57.E5 v1(167.79,66.65) ; U57.F7 v1(170.79,65.65) ; U57.G4 v1(166.79,63.65) ; U57.H6 v1(168.79,62.65) ; U57.K3 165.79,61.65 v1(165.79,61.65) ; U57.F6 v1(169.79,65.65) ; U57.J1 v1(163.79,61.65) ; U57.G8 v1(171.79,63.65)
  TOP w0.508: C935.1 202.31,81.4 R738.2 v1(202.3,82.16)
  BOTTOM w0.508: v1(171.79,63.65) 172.29,64.15 C562.1 ; v2(243.81,69.34) 243.81,69.54 244.12,69.84 C467.1 ; v2(243.64,65.15) 243.97,65.49 C468.1 ; v1(212.14,68.58) 212.6,69.04 C422.1 ; v1(165.79,68.65) 165.29,68.15 C1091.1 ; C423.1 209.68,65.49 v2(209.35,65.15) ; C558.1 171.29,65.15 v1(170.79,65.65) ; v1(219.33,69.34) 219.8,69.34 C421.1 220.31,68.8 219.71,68.2 v1(219.46,68.2) ; v1(166.79,66.65) 166.29,66.15 C1089.1 ; C1090.1 167.29,66.15 v1(167.79,66.65) ; v1(253.62,74.8) 253.07,74.8 FB37.1 253.28,73.91 v1(253.62,73.91) ; C560.1 v1(165.79,61.65) ; v1(239.14,68.71) 238.67,68.71 C466.1 238.67,69.47 v1(239.14,69.47) ; v1(253.75,68.2) 254,68.2 254.6,68.8 C465.1 254.09,69.34 v1(253.62,69.34) ; C559.1 v1(163.79,61.65) ; v1(169.79,65.65) 170.29,65.15 C903.1 ; v2(249.25,66.8) 249.12,66.68 C1086.1 ; v1(219.33,73.91) 218.99,73.91 FB35.1 218.78,74.8 v1(219.33,74.8) ; C469.1 246.89,69.04 v1(246.43,68.58) ; C563.1 v1(168.79,62.65) ; C424.1 209.83,69.84 209.52,69.54 v2(209.52,69.34) ; v2(249.91,69.67) 249.84,69.6 C470.1 ; C561.1 170.29,67.15 v1(169.79,67.65) ; C1083.1 215.55,69.6 v2(215.62,69.67) ; v1(204.85,68.71) 204.38,68.71 C420.1 204.38,69.47 v1(204.85,69.47) ; C1088.1 v1(166.79,63.65) ; C425.1 214.83,66.68 v2(214.96,66.8)
  vias: v1(161.92,64.77) v1(163.07,64.77) v1(178.44,64.14) v1(178.44,63.12) v1(185.17,82.8) v1(185.17,81.79) v1(185.17,80.65) v1(185.17,79.5) v1(185.17,77.6) v1(185.17,76.71)
1V0_FA_VL: length 119.3
  TOP w0.305: U1.G18 v2(159.72,116.45)
  TOP w0.508: R179.2 57.65,151.63 J11.1
  L3SIG w0.508: J11.1 59.31,149.73 68.96,149.73 71.5,147.19 112.65,147.19 124.08,135.76 133.48,135.76 137.92,131.32 141.73,131.32 154.3,118.75 154.3,117.03 154.75,116.59 158.33,116.59
1V0_LP: length 118.2
  TOP w0.305: U1.P6 166.11,107.64 v2(166.12,107.64)
  TOP w0.508: v1(74.42,148.21) C889.1 73.44,149.68 U82.5
  L6SIG w0.457: v2(166.12,107.64) 166.12,118.85
  L6SIG w0.508: 155.91,118.95 151.18,118.95 138.43,131.7 135.89,131.7 122.68,144.91 77.72,144.91 v1(74.42,148.21)
  BOTTOM w0.305: C256.1 165.42,106.94 v2(166.12,107.64)
  BOTTOM w0.508: v1(74.42,148.21) 74.42,149.35 72.26,151.51 J32.1
1V0_USB_SVDD: length 4.4
  TOP w0.305: U1.K10 v2(162.12,110.05) ; U1.K9 v2(162.12,109.25)
  BOTTOM w0.457: C149.1 162.17,101.73 v2(161.8,102.11)
  BOTTOM w0.508: C149.1 C138.1 162.17,99.34 FB11.1
1V0_XG_RX: length 8.5
  TOP w0.381: U57.K9 v1(172.79,60.65) ; U57.G5 v1(167.79,63.65) ; U57.G9 v1(172.79,63.65) ; U57.J10 v1(173.79,61.65) ; U57.H7 v1(170.79,62.65) ; U57.C11 v1(173.79,68.65)
  BOTTOM w0.508: C589.1 173.29,64.15 v1(172.79,63.65) ; C587.1 v1(173.79,61.65) ; v1(172.79,60.65) 173.29,61.15 C584.1 ; C588.1 v1(167.79,63.65) ; C902.1 171.29,62.15 v1(170.79,62.65) ; C585.1 v1(173.79,68.65)
  vias: v1(175.64,61.09) v1(175.64,60.07)
1V0_XG_TX: length 4.2
  TOP w0.381: U57.E8 v1(171.79,66.65) ; U57.E9 v1(172.79,66.65) ; U57.J7 v1(170.79,61.65)
  BOTTOM w0.508: v1(170.79,61.65) 171.29,61.15 C901.1 ; C581.1 172.29,66.15 v1(172.79,66.65) ; C582.1 v1(171.79,66.65)
  vias: v1(175.51,67.31) v1(175.51,66.29)
1V0A_QSG1: length 13.2
  TOP w0.127: U55.E11 214.27,69.49 213.28,69.49 U55.E14 212.32,69.49 211.84,69.49 ; U55.E32 211.15,62.1 210.54,62.1 U55.E30 v2(210.2,63) ; v2(214.1,62.99) 214.1,62.97 U55.E36 ; v2(208.28,62.99) 208.49,63.2 U55.E28 ; U55.E1 215.77,62.28 v2(216.2,62.28) ; U55.E34 212.8,62.77 v2(212.57,62.99) ; v2(211.84,69.98) 211.84,69.49 ; 211.84,69.49 U55.E16
  BOTTOM w0.508: v2(210.2,63) 210.19,63.01 C404.1 ; v2(216.2,62.28) 216.15,62.33 C406.1 ; C1082.1 208.03,62.74 v2(208.28,62.99) ; C403.1 214.25,63.14 v2(214.1,62.99) ; v2(211.84,69.98) 211.83,69.97 C402.1 ; v2(212.57,62.99) 212.57,63.28 C407.1
  vias: v1(216.41,71.88) v1(217.55,71.88)
1V0A_QSG2: length 13.2
  TOP w0.127: v2(244.49,63) U56.E30 244.83,62.1 245.44,62.1 U56.E32 ; U56.E28 242.78,63.2 v2(242.57,62.99) ; v2(246.13,69.98) 246.13,69.49 ; 246.13,69.49 246.61,69.49 U56.E14 247.57,69.49 248.56,69.49 U56.E11 ; 246.13,69.49 U56.E16 ; v2(250.49,62.28) 250.06,62.28 U56.E1 ; U56.E34 247.09,62.77 v2(246.86,62.99) ; v2(248.39,62.99) 248.39,62.97 U56.E36
  BOTTOM w0.508: v2(248.39,62.99) 248.54,63.14 C448.1 ; C451.1 244.47,63.01 v2(244.49,63) ; v2(242.57,62.99) 242.32,62.74 C1085.1 ; v2(246.13,69.98) 246.12,69.97 C447.1 ; v2(250.49,62.28) 250.44,62.33 C449.1 ; C450.1 246.86,63.28 v2(246.86,62.99)
  vias: v1(250.7,71.88) v1(251.84,71.88)
1V0S: length 3.8
  TOP w0.381: 204.64,125.01 U95.8 206.54,125.01 ; 204.65,125.66 U95.7 206.55,125.66
1V5: length 33.7
  TOP w0.508: C611.1 189.5,211.45 v1(189.48,211.48) J19.6 ; C964.1 18.8,110.5 R753.2 v1(18.8,109.74) ; C609.1 189.54,199.53 v1(189.48,199.48) J19.28 ; J20.28 v1(79.25,203.88) 79.2,203.82 C610.1 ; C614.1 79.23,191.9 v1(79.25,191.88) J20.6 ; J19.48 v1(189.48,191.48) 189.53,191.53 C612.1 ; C613.1 79.2,211.82 v1(79.25,211.88) J20.48
  L3SIG w0.508: v1(35.56,109.47) 34.8,108.71 30.23,108.71 28.45,110.49 21.72,110.49 20.96,109.74 v1(18.8,109.74)
  vias: v1(35.56,116.97) v1(35.56,115.95) v1(35.56,114.81) v1(35.56,113.79) v1(35.56,112.65) v1(35.56,111.63) v1(35.56,110.49)
1V05_EC1_AVDD: length 6.1
  TOP w0.203: v1(132.46,51.69) 132.6,51.55 U49.40 ; U49.9 v1(137.27,46.75) ; U49.3 v1(134.87,46.75)
  BOTTOM w0.508: v1(134.87,46.75) 134.87,46.76 C354.1 ; C355.1 132.59,51.82 v1(132.46,51.69) 132.21,51.94 R826.2 ; v1(137.27,46.75) 137.29,46.77 C353.1
  vias: v1(127.89,47.37) v1(128.78,47.37)
1V05_EC1_DVDD: length 9.5
  TOP w0.203: v1(133.86,54.36) 134.07,54.14 U49.36 ; U49.28 v1(137.27,54.34)
  L3SIG w0.508: v1(133.86,54.36) 134.62,53.59 136.52,53.59 v1(137.27,54.34)
  BOTTOM w0.508: v1(137.27,54.34) 137.29,54.32 C348.1 ; C349.1 134.23,54.86 133.86,54.48 v1(133.86,54.36) 132.57,54.36 132.21,54 R826.1
1V05_EC2_AVDD: length 6.1
  TOP w0.203: U46.40 154.83,50.91 v1(154.69,51.05) ; U46.9 v1(159.5,46.12) ; U46.3 v1(157.1,46.12)
  BOTTOM w0.508: C322.1 154.81,51.18 v1(154.69,51.05) 154.43,51.31 R824.2 ; C323.1 157.1,46.12 v1(157.1,46.12) ; C321.1 159.51,46.13 v1(159.5,46.12)
  vias: v1(150.11,46.74) v1(151,46.74)
1V05_EC2_DVDD: length 9.5
  TOP w0.203: U46.36 156.3,53.51 v1(156.08,53.72) ; U46.28 v1(159.5,53.7)
  L3SIG w0.508: v1(156.08,53.72) 156.84,52.96 158.75,52.96 v1(159.5,53.7)
  BOTTOM w0.508: C317.1 159.51,53.69 v1(159.5,53.7) ; C316.1 156.49,54.22 156.08,53.82 v1(156.08,53.72) 154.79,53.72 154.43,53.36 R824.1
1V05_SG_AVDD: length 15.5
  TOP w0.203: v1(187.32,64.77) 187.11,64.55 U52.79 ; v1(190.63,60.96) 190.52,60.85 U52.9 ; U52.24 195.84,61.35 v1(195.71,61.21) 195.97,60.95 U52.23 ; U52.16 193.32,60.73 v1(193.55,60.96) ; v1(188.34,60.96) 188.12,60.73 U52.3 ; v1(191.77,60.96) 191.72,60.91 U52.12
  BOTTOM w0.508: v1(195.71,61.21) 195.45,61.21 194.94,61.73 C388.1 ; C390.1 193.42,61.09 v1(193.55,60.96) ; v1(191.77,60.96) 192.15,61.34 C389.1 ; C385.1 191.13,61.47 v1(190.63,60.96) ; v1(188.34,60.96) 188.47,60.96 189.1,61.59 C384.1 ; R828.2 187.32,67.19 v1(187.32,64.77) 187.45,64.9 C386.1
  vias: v1(181.23,58.42) v1(182.12,58.42)
1V05_SG_DVDD: length 12.3
  TOP w0.203: U52.47 194.92,69.44 v1(194.82,69.34) ; v1(186.82,69.98) 186.99,70.15 U52.66
  BOTTOM w0.508: R828.1 186.56,69.72 v1(186.82,69.98) C377.1 187.59,70.49 188.09,70.99 192.91,70.99 193.92,69.98 C378.1 v1(194.82,69.34)
1V8: length 58
  TOP w0.305: v1(158.88,67.06) 158.79,66.97 U58.8
  TOP w0.381: U57.H11 v1(174.79,62.65) ; U57.J5 v1(167.79,61.65) ; U57.D7 v1(170.79,67.65) ; U57.C4 v1(166.79,68.65) ; U57.C5 v1(167.79,68.65) ; U57.J4 v1(166.79,61.65) ; U57.G2 v1(164.79,63.65)
  TOP w0.508: Q44.2 40.77,136.84 40.77,122.17 v1(42.8,120.14) v1(43.31,119.63) ; v1(178.94,71.5) 178.44,70.99 R388.1
  L6SIG w0.508: v1(42.8,120.14) v1(43.31,119.63) 43.81,119.13 48.77,119.13 49.78,118.11 55.5,118.11 v1(56.13,118.75)
  BOTTOM w0.203: R380.2 C568.1
  BOTTOM w0.508: v1(170.79,67.65) 170.29,68.15 C1094.1 ; R133.1 R134.1 165.29,64.15 v1(164.79,63.65) 164.29,63.15 R381.2 ; v1(167.79,68.65) 167.29,68.15 C1093.1 ; v1(166.79,61.65) 166.29,62.15 C569.1 ; C568.1 v1(164.79,68.65) ; C1092.1 166.29,68.15 v1(166.79,68.65) ; R387.2 174.29,65.15 C570.1 174.29,63.15 v1(174.79,62.65) ; R385.1 R382.1 C586.1 v1(158.88,67.06) ; C571.1 167.29,62.15 v1(167.79,61.65) 168.29,61.15 R389.2
  vias: v1(40.51,99.82) v1(40.51,99.06) v1(40.51,98.3) v1(41.4,99.82) v1(41.4,99.06) v1(41.4,98.3) v1(42.29,99.82) v1(42.29,99.06) v1(42.29,98.3) v1(56.13,119.51) v1(56.9,119.51) v1(56.9,118.75) v1(168.66,71.5) v1(169.29,72.52) v1(176.53,55.75) v1(177.16,56.39) v1(178.94,72.26)
1V8_0641_VDD: length 8.3
  TOP w0.203: U97.31 234.1,139.12 234.06,139.16 v1(234.06,139.19) ; U97.16 239.98,137.11 v1(240.03,137.16)
  BOTTOM w0.508: R839.1 233.9,130.94 C1049.1 233.63,130.77 ; 233.63,130.77 233.17,131.23 v1(233.17,132.08) ; 233.63,130.77 FB55.2 ; v1(234.06,139.19) 233.93,139.33 C1051.1 ; C1050.1 239.9,137.03 v1(240.03,137.16) ; R841.1 v1(239.39,139.45)
1V8_0641_VDDA: length 3.7
  TOP w0.203: v1(236.6,140.21) 236.6,140.08 236.4,139.88 U97.26
  BOTTOM w0.508: R841.2 236.61,139.45 C737.1 v1(236.6,140.21) 236.6,141.19 C736.1
1V8_0641_VDDIO: length 12.4
  TOP w0.203: v1(235.97,140.21) 236,140.17 U97.27 ; v1(239.9,135.25) 239.65,135.51 U97.12 ; v1(240.03,137.79) 239.9,137.79 239.61,137.51 U97.17 ; v1(233.43,134.74) 233.43,135.25 233.68,135.51 U97.39 ; U97.32 233.42,138.31 v1(233.17,138.56) ; U97.5 236.4,133.68 v1(236.6,133.48)
  BOTTOM w0.508: C1048.1 239.27,135.51 239.52,135.25 v1(239.9,135.25) ; v1(236.6,133.48) 236.61,133.48 C1052.1 ; C1044.1 239.78,138.05 v1(240.03,137.79) ; C1045.1 235.58,139.83 v1(235.97,140.21) ; v1(233.43,134.74) 233.43,134.75 C1047.1 233.34,135.42 FB54.1 ; v1(233.17,138.56) 233.18,138.55 C1046.1
1V8_0641_VDDXTAL: length 4.4
  TOP w0.203: v1(235.84,133.48) 236,133.64 U97.4
  BOTTOM w0.508: C1041.1 235.83,133.48 v1(235.84,133.48) 235.84,132.37 C1040.1 235.96,132.16 R839.2
1V8_MTR: length 119.2
  TOP w0.305: U1.F11 v2(158.92,110.85)
  TOP w0.508: R178.2 58.42,146.05 J10.1
  L3SIG w0.508: J10.1 59.18,146.81 68.83,146.81 70.74,144.91 111.89,144.91 123.32,133.48 132.72,133.48 137.16,129.03 140.97,129.03 152.02,117.98 152.02,115.57 154.05,113.54 154.05,112.01 154.94,111.12 155.32,111.12
  BOTTOM w0.305: v2(158.92,110.85) 158.74,110.67 C208.1
1V8_SFP: length 117.6
  TOP w0.305: U1.F12 v2(158.92,111.65)
  TOP w0.508: J9.1 58.42,147.45 R177.2
  L3SIG w0.508: 155.32,113.03 155.32,113.28 152.78,115.82 152.78,118.24 141.22,129.79 137.41,129.79 132.97,134.24 123.57,134.24 112.14,145.67 70.99,145.67 68.45,148.21 57.66,148.21 J9.1
  BOTTOM w0.305: v2(158.92,111.65) 158.74,111.82 C192.1
1V8_SLP: length 34.3
  TOP w0.203: U97.11 239.1,134.66 v1(239.14,134.62)
  TOP w0.381: 209.26,125.01 U95.1 211.03,125.01 ; U65.H10 v1(66.52,107.43) ; U65.J9 v1(65.52,105.43) ; 209.25,125.66 U95.2 211.15,125.66 ; U65.J7 v1(62.52,105.43) ; U65.H8 v1(63.52,107.43)
  TOP w0.508: R844.1 v1(230.63,133.98) ; v1(18.8,98.94) R757.2 18.8,99.7 C965.1 ; R533.1 v1(239.52,142.88) ; R834.1 v1(239.01,131.58) ; R843.1 v1(241.8,133.99) ; R829.1 v1(230.63,132.97)
  L3SIG w0.508: v1(35.56,98.68) 34.8,97.92 29.84,97.92 28.19,99.57 21.46,99.57 20.84,98.94 v1(18.8,98.94)
  BOTTOM w0.508: C735.1 239.39,134.37 v1(239.14,134.62) ; U65.J9 v1(65.52,105.43) ; U65.H10 v1(66.52,107.43) ; U65.J7 v1(62.52,105.43) ; U65.H8 v1(63.52,107.43)
  vias: v1(35.56,106.17) v1(35.56,105.16) v1(35.56,104.01) v1(35.56,103) v1(35.56,101.85) v1(35.56,100.84) v1(35.56,99.7) v1(51.43,139.83) v1(51.43,139.06) v1(52.2,139.83) v1(52.2,139.06) v1(209.3,124.46) v1(210.95,124.46) v1(211.71,124.46)
1V8_USB_OVDD: length 5.4
  TOP w0.305: U1.J10 v2(161.32,110.05) ; U1.J9 v2(161.32,109.25)
  BOTTOM w0.457: v2(157.35,102.11) 157.11,101.86 C172.1
  BOTTOM w0.508: FB13.1 157.11,98.33 C174.1 C173.1 C172.1
1V8_XG_AV: length 2.8
  TOP w0.381: U57.J9 v1(172.79,61.65) ; U57.J8 v1(171.79,61.65)
  BOTTOM w0.508: C899.1 173.29,62.15 v1(172.79,61.65) ; C577.1 172.29,62.15 v1(171.79,61.65)
  vias: v1(174.5,58.8) v1(175.26,58.8)
1V8_XG_RX: length 2.8
  TOP w0.381: U57.C9 v1(172.79,68.65) ; U57.C8 v1(171.79,68.65)
  BOTTOM w0.508: C579.1 v1(172.79,68.65) ; C900.1 171.29,68.15 v1(171.79,68.65)
  vias: v1(175.51,69.98) v1(175.51,68.83)
1V35:
  vias: v1(198.75,129.16) v1(198.75,128.14) v1(199.52,129.16) v1(199.52,128.14)
1V35_SLP: length 211.3
  TOP w0.305: U1.T21 v2(167.72,119.65) ; U1.N21 v2(164.52,119.65) ; U1.F27 v2(158.92,124.45) ; U1.D27 v2(157.32,124.45) ; U1.L21 v2(162.92,119.65) ; U1.W27 v2(170.12,124.45) ; U1.U27 v2(168.52,124.45) ; U1.H27 v2(160.52,124.45) ; U81.2 227.83,148.84 227.97,148.97 ; U1.K21 v2(162.12,119.65) ; U1.AD27 v2(174.12,124.45) ; U1.M21 v2(163.72,119.65) ; U1.R21 v2(166.92,119.65) ; U1.U21 v2(168.52,119.65) ; U1.AF27 v2(175.72,124.45) ; U1.P27 v2(165.32,124.45) ; U1.P21 v2(165.32,119.65) ; U1.K27 v2(162.12,124.45) ; U1.M27 v2(163.72,124.45) ; U1.AA27 v2(171.72,124.45)
  TOP w0.508: C7.1 159.9,163.19 R4.1 ; C7.1 C12.1 ; C7.1 159.89,161.37 J1.173 ; 172.92,163.4 J1.186 ; 172.92,163.4 173.11,163.2 C998.1 ; 172.92,163.4 C1.1 172.58,163.2 C8.1 ; C13.1 184.91,155.64 J1.78 ; R2.1 154.67,163.19 ; 154.67,163.19 154.43,162.96 v1(154.43,162.56) ; 154.67,163.19 C2.1 155.2,163.2 ; C12.1 156.92,163.13 J1.170 ; C12.1 155.2,163.2 ; J1.191 177.93,161.36 C4.1 ; J1.62 168.91,155.64 C10.1 ; C14.1 178.94,155.62 J1.72 ; 155.2,163.2 155.45,162.96 v1(155.45,162.56) ; C8.1 C5.1 ; C8.1 169.93,161.36 J1.183 ; J1.197 184.41,161.84 C999.1 180.98,163.19 C6.1 ; J1.194 180.92,163.14 C6.1 ; C5.1 168.92,163.07 J1.182 ; C5.1 C11.1 165.99,161.42 J1.179 ; R736.2 222.63,138.55 C941.1 v1(224.4,138.55) ; J1.60 166.88,155.61 C9.1 ; C3.1 160.91,155.64 J1.54 ; C998.1 C4.1 ; C998.1 175.89,161.37 J1.189 ; C4.1 C6.1
  L4PWR w0.508: 163.39,157.02 J1.57 ; J1.57 163.39,158.08 ; J1.57 164.45,157.02 ; J1.57 164.45,158.08 ; J1.60 167.45,155.12 ; J1.60 166.39,155.12 ; J1.60 166.39,156.18 ; J1.60 167.45,156.18 ; J1.186 173.45,159.98 ; J1.186 172.39,159.98 ; J1.186 173.45,158.92 ; J1.186 172.39,158.92 ; J1.66 173.45,156.18 ; J1.66 172.39,155.12 ; J1.66 173.45,155.12 ; J1.66 172.39,156.18 ; J1.62 169.45,155.12 ; J1.62 169.45,156.18 ; J1.62 168.39,156.18 ; J1.62 168.39,155.12 ; 156.39,159.98 J1.170 ; J1.170 157.45,158.92 ; J1.170 156.39,158.92 ; J1.170 157.45,159.98 ; J1.194 181.45,158.92 ; J1.194 180.39,158.92 ; J1.194 181.45,159.98 ; J1.194 180.39,159.98 ; J1.197 184.45,161.88 ; J1.197 183.39,161.88 ; J1.197 183.39,160.82 ; J1.197 184.45,160.82 ; 160.39,156.18 J1.54 ; J1.54 161.45,155.12 ; J1.54 161.45,156.18 ; J1.54 160.39,155.12 ; J1.51 158.45,158.08 ; J1.51 158.45,157.02 ; J1.51 157.39,158.08 ; J1.51 157.39,157.02 ; 159.39,161.88 J1.173 ; J1.173 159.39,160.82 ; J1.173 160.45,161.88 ; J1.173 160.45,160.82 ; J1.176 163.45,158.92 ; J1.176 163.45,159.98 ; J1.176 162.39,158.92 ; J1.176 162.39,159.98 ; 169.39,161.88 J1.183 ; J1.183 169.39,160.82 ; J1.183 170.45,161.88 ; J1.183 170.45,160.82 ; 181.39,157.02 J1.75 ; J1.75 182.45,158.08 ; J1.75 181.39,158.08 ; J1.75 182.45,157.02 ; 171.39,158.08 J1.65 ; J1.65 171.39,157.02 ; J1.65 172.45,158.08 ; J1.65 172.45,157.02 ; 178.39,155.12 J1.72 ; J1.72 179.45,155.12 ; J1.72 179.45,156.18 ; J1.72 178.39,156.18 ; 168.39,158.92 J1.182 ; J1.182 168.39,159.98 ; J1.182 169.45,159.98 ; J1.182 169.45,158.92 ; J1.179 166.45,161.88 ; J1.179 165.39,161.88 ; J1.179 166.45,160.82 ; J1.179 165.39,160.82 ; J1.189 176.45,160.82 ; J1.189 175.39,161.88 ; J1.189 176.45,161.88 ; J1.189 175.39,160.82 ; 177.39,160.82 J1.191 ; J1.191 178.45,160.82 ; J1.191 177.39,161.88 ; J1.191 178.45,161.88 ; J1.78 185.45,156.18 ; J1.78 184.39,155.12 ; J1.78 184.39,156.18 ; J1.78 185.45,155.12 ; 175.39,158.08 J1.69 ; J1.69 176.45,157.02 ; J1.69 176.45,158.08 ; J1.69 175.39,157.02
  L5PWR w0.508: 162.39,159.98 J1.176 ; J1.176 162.39,158.92 ; J1.176 163.45,159.98 ; J1.176 163.45,158.92 ; J1.179 166.45,161.88 ; J1.179 166.45,160.82 ; J1.179 165.39,160.82 ; J1.179 165.39,161.88 ; J1.62 169.45,155.12 ; J1.62 168.39,156.18 ; J1.62 168.39,155.12 ; J1.62 169.45,156.18 ; J1.72 179.45,155.12 ; J1.72 179.45,156.18 ; J1.72 178.39,155.12 ; J1.72 178.39,156.18 ; 172.39,156.18 J1.66 ; J1.66 173.45,155.12 ; J1.66 173.45,156.18 ; J1.66 172.39,155.12 ; J1.189 176.45,161.88 ; J1.189 175.39,161.88 ; J1.189 175.39,160.82 ; J1.189 176.45,160.82 ; 157.39,158.08 J1.51 ; J1.51 157.39,157.02 ; J1.51 158.45,158.08 ; J1.51 158.45,157.02 ; 177.39,161.88 J1.191 ; J1.191 177.39,160.82 ; J1.191 178.45,160.82 ; J1.191 178.45,161.88 ; J1.183 170.45,161.88 ; J1.183 169.39,161.88 ; J1.183 170.45,160.82 ; J1.183 169.39,160.82 ; 181.39,157.02 J1.75 ; J1.75 182.45,158.08 ; J1.75 181.39,158.08 ; J1.75 182.45,157.02 ; J1.197 184.45,161.88 ; J1.197 184.45,160.82 ; J1.197 183.39,160.82 ; J1.197 183.39,161.88 ; 175.39,158.08 J1.69 ; J1.69 176.45,157.02 ; J1.69 175.39,157.02 ; J1.69 176.45,158.08 ; 168.39,159.98 J1.182 ; J1.182 169.45,158.92 ; J1.182 168.39,158.92 ; J1.182 169.45,159.98 ; 166.39,156.18 J1.60 ; J1.60 167.45,156.18 ; J1.60 166.39,155.12 ; J1.60 167.45,155.12 ; 171.39,158.08 J1.65 ; J1.65 172.45,158.08 ; J1.65 172.45,157.02 ; J1.65 171.39,157.02 ; 180.39,159.98 J1.194 ; J1.194 181.45,158.92 ; J1.194 181.45,159.98 ; J1.194 180.39,158.92 ; 159.39,160.82 J1.173 ; J1.173 159.39,161.88 ; J1.173 160.45,161.88 ; J1.173 160.45,160.82 ; 160.39,156.18 J1.54 ; J1.54 160.39,155.12 ; J1.54 161.45,155.12 ; J1.54 161.45,156.18 ; 172.39,159.98 J1.186 ; J1.186 173.45,158.92 ; J1.186 173.45,159.98 ; J1.186 172.39,158.92 ; J1.57 164.45,157.02 ; J1.57 163.39,158.08 ; J1.57 164.45,158.08 ; J1.57 163.39,157.02 ; 156.39,159.98 J1.170 ; J1.170 157.45,159.98 ; J1.170 157.45,158.92 ; J1.170 156.39,158.92 ; J1.78 185.45,155.12 ; J1.78 184.39,156.18 ; J1.78 184.39,155.12 ; J1.78 185.45,156.18
  BOTTOM w0.457: v2(170.12,124.45) 169.92,124.64 R1.1
  vias: v1(205.87,139.57) v1(205.87,138.56) v1(205.87,137.41) v1(205.87,136.4) v1(205.87,135.25) v1(205.87,134.24) v1(205.87,133.1) v1(205.87,132.08) v1(228.73,154.05) v1(228.73,153.29) v1(229.49,154.05) v1(229.49,153.29)
2V5: length 56.5
  TOP w0.127: U56.E3 U56.E4 249.53,65.15 249.25,65.43 v2(249.25,65.79) 249.25,66.17 249.53,66.45 U56.E6 ; U55.E6 215.24,66.45 214.96,66.17 v2(214.96,65.79) 214.96,65.43 215.24,65.15 U55.E4 U55.E3 ; v2(248.64,68.63) 248.39,68.89 U56.E12 ; v2(214.96,67.77) 214.98,67.75 U55.E8 U55.E9 ; U56.E9 U56.E8 249.27,67.75 v2(249.25,67.77) ; U55.E26 208.46,65.01 208.46,65.29 U55.E24 208.46,66.31 208.46,66.59 U55.E22 209.07,67.1 v2(209.35,66.83) ; v2(214.35,68.63) 214.1,68.89 U55.E12 ; v2(243.64,66.83) 243.36,67.1 U56.E22 242.75,66.59 242.75,66.31 U56.E24 242.75,65.29 242.75,65.01 U56.E26 ; U56.E18 244.39,69.15 v1(243.64,68.4) 243.64,68.4 U56.E20 ; U55.E18 210.1,69.15 v1(209.35,68.4) 209.35,68.4 U55.E20
  TOP w0.203: v1(195.71,67.69) 195.77,67.75 U52.40 198.19,67.75 R269.1 ; v1(195.71,65.41) 195.76,65.35 U52.34 ; v1(162.31,48.51) 162.3,48.51 U46.15 ; U46.21 v1(162.29,50.91)
  TOP w0.305: U1.V8 v2(169.32,108.45) ; U1.W8 v2(170.12,108.45)
  TOP w0.508: v1(236.6,66.04) R315.2 R314.2 R316.2 ; v1(222.76,70.23) 222.88,70.1 R296.1 ; R231.2 v1(167.39,49.53) ; R295.2 R293.2 R294.2 v1(202.31,66.04) ; R138.2 v1(151.76,60.71) ; R317.1 257.18,70.1 v1(257.05,70.23) ; R856.2 257.17,71.36 256.78,71.76 v1(256.67,71.76) ; R230.2 v1(167.39,48.51) ; v1(222.38,71.76) 222.49,71.76 222.88,71.36 R855.2 ; R270.1 R269.1 ; R229.2 v1(167.39,47.5) ; R272.1 v1(194.94,73.66)
  BOTTOM w0.508: C1087.1 249.17,67.69 v2(249.25,67.77) ; C479.1 244.23,67.82 v1(243.64,68.4) ; C314.1 v1(162.31,48.51) ; v1(209.35,68.4) 209.94,67.82 C435.1 ; C398.1 v1(195.71,67.69) ; C315.1 162.27,50.93 v1(162.29,50.91) ; v2(214.96,67.77) 214.88,67.69 C436.1 ; v2(243.64,66.83) 243.66,66.8 C480.1 ; v2(214.96,65.79) 214.83,65.66 C434.1 ; C482.1 248.56,68.71 v2(248.64,68.63) ; C399.1 v1(195.71,65.41) ; C481.1 249.12,65.66 v2(249.25,65.79) ; v1(222.38,71.76) 221.91,71.29 C432.1 222.42,70.23 v1(222.76,70.23) ; v1(256.67,71.76) 256.2,71.29 C477.1 256.71,70.23 v1(257.05,70.23) ; v2(209.35,66.83) 209.37,66.8 C437.1 ; v2(214.35,68.63) 214.27,68.71 C1084.1
  vias: v1(52.96,124.33) v1(52.96,123.7) v1(52.96,123.06) v1(77.98,78.87) v1(77.98,78.11) v1(77.98,77.34) v1(78.87,78.87) v1(78.87,78.11) v1(78.87,77.34) v1(79.76,78.87) v1(79.76,78.11) v1(79.76,77.34) v1(179.96,77.85) v1(180.85,77.85) v1(201.93,65.41) v1(236.22,65.41) v1(260.48,66.42) v1(260.48,65.66) v1(261.24,66.42) v1(261.24,65.66)
2V5_LED: length 69.3
  L3SIG w0.508: J15.G11 265.7,24.18 ; J15.G11 264.22,25.67 ; J15.G11 264.22,24.18 ; J15.G11 265.7,25.67
  BOTTOM w0.508: J15.A9 207.27,25.67 ; J15.A9 205.79,24.18 ; J15.A9 205.79,25.67 ; J15.A9 207.27,24.18 ; J15.F9 238.77,8.91 ; J15.F9 237.29,7.42 ; J15.F9 238.77,7.42 ; J15.F9 237.29,8.91 ; J15.H11 265.7,8.91 ; J15.H11 264.22,8.91 ; J15.H11 265.7,7.42 ; J15.H11 264.22,7.42 ; 221.54,8.91 J15.D9 ; J15.D9 223.02,7.42 ; J15.D9 221.54,7.42 ; J15.D9 223.02,8.91 ; 237.29,25.67 J15.E9 ; J15.E9 237.29,24.18 ; J15.E9 238.77,25.67 ; J15.E9 238.77,24.18 ; J15.G11 265.7,24.18 ; J15.G11 264.22,25.67 ; J15.G11 265.7,25.67 ; J15.G11 264.22,24.18 ; 248.47,25.67 J15.E11 ; J15.E11 249.95,25.67 ; J15.E11 248.47,24.18 ; J15.E11 249.95,24.18 ; 216.97,25.67 J15.A11 ; J15.A11 218.45,25.67 ; J15.A11 216.97,24.18 ; J15.A11 218.45,24.18 ; 221.54,24.18 J15.C9 ; J15.C9 223.02,24.18 ; J15.C9 221.54,25.67 ; J15.C9 223.02,25.67 ; J15.H9 254.52,8.91 ; J15.H9 253.04,7.42 ; J15.H9 253.04,8.91 ; J15.H9 254.52,7.42 ; 232.72,24.18 J15.C11 ; J15.C11 234.2,24.18 ; J15.C11 234.2,25.67 ; J15.C11 232.72,25.67 ; 253.04,24.18 J15.G9 ; J15.G9 253.04,25.67 ; J15.G9 254.52,24.18 ; J15.G9 254.52,25.67 ; J15.B11 218.45,8.91 ; J15.B11 218.45,7.42 ; J15.B11 216.97,7.42 ; J15.B11 216.97,8.91 ; 248.47,8.91 J15.F11 ; J15.F11 249.95,7.42 ; J15.F11 248.47,7.42 ; J15.F11 249.95,8.91 ; J15.D11 234.2,8.91 ; J15.D11 232.72,8.91 ; J15.D11 232.72,7.42 ; J15.D11 234.2,7.42 ; 207.27,7.42 J15.B9 207.27,8.91
  vias: v1(260.99,60.96) v1(260.99,60.2) v1(262,60.96) v1(262,60.2) v1(262.51,26.03) v1(262.51,25.27) v1(265.3,26.16) v1(266.06,26.16)
2V5_SLP: length 38.1
  TOP w0.203: U49.21 v1(140.06,51.55) ; v1(140.08,49.15) 140.08,49.15 U49.15
  TOP w0.305: U1.T8 v2(167.72,108.45) ; U1.U8 v2(168.52,108.45)
  TOP w0.381: U24.5 150.85,56.53 C57.1 ; U23.5 150.85,59.32 C58.1
  TOP w0.508: v1(56.27,77.99) R774.2 56.26,78.75 C988.1 ; C58.1 v1(151.76,59.17) ; R131.1 146.43,55.12 v1(146.81,54.74) ; R132.1 v1(146.43,57.53) ; R258.2 v1(145.16,48.13) ; R259.2 v1(145.16,49.15) ; C57.1 v1(151,57.15) ; R260.2 v1(145.16,50.16)
  L3SIG w0.508: v1(73.03,77.72) 71.25,75.95 58.31,75.95 v1(56.27,77.99)
  BOTTOM w0.508: R77.2 172.08,100.2 ; 172.08,100.2 v1(173.1,100.2) ; 172.08,100.2 R75.2 R78.2 R76.2 ; C346.1 140.05,51.56 v1(140.06,51.55) ; C347.1 v1(140.08,49.15)
  vias: v1(73.03,85.22) v1(73.03,84.2) v1(73.03,83.06) v1(73.03,82.04) v1(73.03,80.9) v1(73.03,79.88) v1(73.03,78.74)
2V5A_QSG1: length 9.1
  TOP w0.102: U55.E35 213.96,62.12 214.11,62.12 214.2,62.13 U55.E37
  TOP w0.127: U55.E35 213.45,62.88 v2(213.33,62.99) ; U55.E33 212.15,62.66 v2(211.81,62.99) 211.39,62.99 U55.E31 ; U55.E27 208.89,63.85 v2(209.3,63.45) 209.55,63.2 U55.E29
  BOTTOM w0.508: v2(209.3,63.45) 208.98,63.76 C416.1 C413.1 ; v2(213.33,62.99) 213.23,63.09 C414.1 ; v2(211.81,62.99) 211.71,62.99 211.2,63.5 C415.1
  vias: v1(204.98,63.25) v1(205.23,64.01)
2V5A_QSG2: length 9.1
  TOP w0.102: U56.E35 248.25,62.12 248.4,62.12 248.49,62.13 U56.E37
  TOP w0.127: U56.E35 247.74,62.88 v2(247.62,62.99) ; U56.E33 246.44,62.66 v2(246.1,62.99) 245.68,62.99 U56.E31 ; U56.E27 243.18,63.85 v2(243.59,63.45) 243.84,63.2 U56.E29
  BOTTOM w0.508: C459.1 247.52,63.09 v2(247.62,62.99) ; C458.1 245.49,63.5 246,62.99 v2(246.1,62.99) ; C462.1 C461.1 243.27,63.76 v2(243.59,63.45)
  vias: v1(239.27,63.25) v1(239.52,64.01)
3V3: length 420
  TOP w0.203: U20.16 67.98,145.07 v1(68.07,145.16) ; U52.25 195.93,61.75 v1(195.71,61.98) ; v1(187.32,64.01) 187.18,64.15 U52.80 ; U18.13 158.4,89.32 v1(158.5,89.41) ; U52.6 189.32,60.79 v1(189.48,60.96) ; U42.13 168.56,91.86 v1(168.66,91.95) ; v1(155.19,52.96) 155.5,52.66 U46.37 ; v1(154.69,50.42) 154.78,50.51 U46.41 ; U40.13 173.14,91.86 v1(173.23,91.95) ; v1(187.32,69.22) 187.19,69.35 U52.67 ; v1(193.42,69.34) 193.32,69.45 U52.51 193.32,71.87 R282.1 ; v1(163.07,89.41) 162.98,89.32 U12.13 ; U52.85 187.12,62.15 v1(187.32,62.36) 187.13,62.55 U52.84 ; U46.6 v1(158.3,46.12) ; U46.45 154.8,48.91 v1(154.69,49.02) 154.98,49.31 U46.44
  TOP w0.254: U26.1 234.45,100.71 234.2,100.96 C72.1 ; C81.1 234.2,118.74 234.45,118.49 U29.1 ; U29.10 234.45,112.15 234.2,111.89 C82.1 ; U29.6 232.79,115.07 v1(232.54,115.32) ; U26.6 232.79,97.29 v1(232.54,97.54) ; C76.1 212.72,82.8 212.47,82.55 U27.1 ; C75.1 205.87,82.8 206.13,82.55 U27.10 ; U6.12 95.89,127.39 v1(95.76,127.25) ; v1(209.3,84.45) 209.05,84.21 U27.6 ; C78.1 234.2,103 234.45,103.26 U28.10 ; v1(232.54,106.43) 232.79,106.18 U28.6 ; U4.43 101.25,128.4 101.24,128.4 v1(101.09,128.4) ; U6.37 76.59,127.39 v1(76.45,127.25) ; C74.1 234.2,94.11 234.45,94.37 U26.10 ; U28.1 234.45,109.6 234.2,109.85 C80.1
  TOP w0.305: U68.10 149.4,63.8 149.11,63.51 C743.1 ; U19.16 258.56,144.91 C48.1 ; U19.1 258.56,153.8 ; 258.56,153.8 258.06,153.8 257.91,153.64 U19.2 ; 258.56,153.8 258.56,155.19 v1(258.31,155.44) ; v1(104.39,53.34) 103.72,52.67 U63.57 ; U59.7 91.96,54.62 v1(91.95,54.61) ; C744.1 227.72,68.33 228.39,69.01 U67.10 ; C745.1 236.04,72.72 U67.16 ; v1(82.55,63.25) 82.52,63.28 U59.37 82.52,65.57 82.05,66.03 R420.2 ; U59.57 80.86,52.67 v1(81.53,53.34) ; U63.25 113.18,63.39 v1(113.16,63.37) ; U59.54 81.52,54.62 v1(81.53,54.61) ; U19.13 256.61,145.6 257.31,144.9 v1(257.82,144.9) ; v1(90.3,63.37) 90.32,63.39 U59.25 90.32,66.45 R428.2 ; v1(114.81,54.61) 114.82,54.62 U63.7 ; R442.2 104.39,66.42 105.38,65.44 U63.37 105.38,63.28 v1(105.41,63.25) ; v1(104.39,54.61) 104.38,54.62 U63.54 ; U68.16 156.89,67.51 C742.1
  TOP w0.381: U100.5 v1(271.77,142.48) ; U101.5 v1(274.56,142.48) ; U41.16 126.76,70.35 126.5,70.6 C286.1 ; J43.12 v1(270.36,154.92) ; C272.1 133.6,71.11 133.6,70.61 133.87,70.35 U39.16 ; J43.10 v1(270.36,155.55) ; J43.16 v1(270.36,153.65) ; J43.14 v1(270.36,154.28) ; U22.5 v1(67.63,138.11)
  TOP w0.508: R402.2 R403.2 v1(265.94,87.88) ; 242.19,152.4 242.18,152.39 R91.2 R90.2 ; C743.1 v1(149.11,62.11) ; FB53.1 235.62,77.43 v1(235.97,77.09) ; J20.2 v1(79.25,190.28) 79.22,190.25 C604.1 ; v1(264.8,145.8) 264.68,145.92 R852.1 R851.1 R850.1 R849.1 ; R56.2 254.64,133.1 v1(254.63,133.1) R54.2 ; Q40.1 169.48,87.62 Q39.1 169.68,88.27 v1(170.05,88.65) ; 270.98,90.64 J18.A9 ; J18.A9 272.11,90.64 ; J18.A9 270.98,89.51 ; J18.A9 272.11,89.51 ; C745.1 v1(236.86,72.76) ; R411.2 v1(91.31,193.04) ; D39.2 v1(35.18,8.76) ; J18.B8 276.61,88.51 ; J18.B8 275.48,88.51 ; J18.B8 276.61,89.64 ; J18.B8 275.48,89.64 ; 268.98,91.64 J18.A10 ; J18.A10 270.11,90.51 ; J18.A10 268.98,90.51 ; J18.A10 270.11,91.64 ; v1(122.56,57.4) 122.56,45.85 117.48,40.77 R468.2 ; R408.2 v1(265.94,94.62) ; v1(258.31,155.44) R99.1 R404.2 R398.2 ; v1(161.29,46.86) 161.29,46.35 163.07,44.58 164.43,44.58 FB26.1 ; J19.24 v1(189.48,201.08) 189.5,201.06 C600.1 ; R57.2 v1(269.62,134.87) ; v1(270.13,136.78) 270.51,137.16 R55.2 ; v1(46.47,139.45) 46.47,138.86 Q45.2 45.72,138.99 v1(45.72,139.45) ; J19.2 v1(189.48,213.08) 189.51,213.11 C603.1 ; J20.24 v1(79.25,202.28) 79.23,202.29 C601.1 ; D40.2 v1(48.13,8.76) ; v1(252.6,154.43) R409.2 R410.2 ; C79.1 v1(232.54,106.43) ; FB32.1 v1(183.93,55.16) ; R549.1 v1(146.44,62.24) ; C48.1 v1(257.82,144.9) 256.82,143.9 R406.2 R407.2 ; C293.1 241.04,152.4 U44.8 ; R235.2 158.12,56.13 158.62,55.63 159,55.63 R823.1 159,54.99 v1(159.13,54.86) ; C72.1 v1(233.43,101.47) ; 52.45,6.39 v1(52.45,8.76) ; R859.1 v1(276.48,138.3) ; 223.39,158.08 J1.117 ; J1.117 223.39,157.02 ; J1.117 224.45,157.02 ; J1.117 224.45,158.08 ; R854.1 R827.1 v1(180.59,65.91) ; D42.2 v1(43.81,8.76) ; D38.2 v1(30.86,8.76) ; FB52.1 152.36,70.9 v1(152.4,70.87) ; J18.B10 276.61,91.64 ; J18.B10 275.48,90.51 ; J18.B10 276.61,90.51 ; J18.B10 275.48,91.64 ; v1(155.19,52.96) 155.07,53.08 R822.1 ; 260.73,140.68 259.68,140.68 259.08,140.08 U13.2 256.04,140.08 C36.1 C37.1 v1(254.13,140.22) ; v1(109.6,140.97) 114.3,140.97 117.35,137.92 130.3,137.92 145.41,122.81 v1(145.41,122.17) ; R204.2 v1(58.17,124.72) ; R276.2 R277.1 v1(180.09,69.34) ; C77.1 v1(209.3,84.45) ; C76.1 v1(213.23,83.57) ; 222.39,158.92 J1.236 ; J1.236 223.45,158.92 ; J1.236 222.39,159.98 ; J1.236 223.45,159.98 ; J20.52 v1(79.25,213.48) 79.25,213.47 C605.1 ; C74.1 v1(233.43,93.6) ; C73.1 v1(232.54,97.54) ; D37.2 v1(56.77,8.76) ; C272.1 v1(133.61,71.87) ; R279.1 v1(185.16,70.48) ; v1(70.36,149.61) 69.98,149.99 D31.2 ; R857.2 R858.2 v1(109.35,70.99) ; C75.1 v1(205.36,83.57) ; R540.1 R550.1 v1(224.67,67.95) ; D41.2 v1(39.5,8.76) ; C83.1 v1(232.54,115.32) ; R234.2 v1(152.15,54.36) ; C81.1 v1(233.43,119.25) ; C286.1 v1(126.5,71.87) ; C742.1 v1(157.85,67.3) ; C80.1 v1(233.43,110.36) ; C602.1 189.48,189.88 v1(189.48,189.88) J19.52 ; C744.1 v1(227.72,67.19) ; R399.2 v1(177.42,210.31) ; C78.1 v1(233.43,102.49) ; R405.2 v1(265.94,114.17) ; C82.1 v1(233.43,111.38)
  L4PWR w0.508: J18.A10 270.11,91.64 ; J18.A10 268.98,90.51 ; J18.A10 268.98,91.64 ; J18.A10 270.11,90.51 ; J18.B10 276.61,91.64 ; J18.B10 275.48,91.64 ; J18.B10 276.61,90.51 ; J18.B10 275.48,90.51 ; J18.A9 272.11,89.51 ; J18.A9 270.98,90.64 ; J18.A9 272.11,90.64 ; J18.A9 270.98,89.51 ; 275.48,89.64 J18.B8 ; J18.B8 276.61,88.51 ; J18.B8 275.48,88.51 ; J18.B8 276.61,89.64
  BOTTOM w0.203: U7.13 93.06,123.4 C1062.1 ; U98.13 80.81,133.39 C1074.1 ; U11.13 93.06,129.24 C1060.1 ; U99.13 80.81,127.3 C1072.1
  BOTTOM w0.254: U27.1 212.47,82.55 212.72,82.8 C76.1 ; U27.10 206.13,82.55 205.87,82.8 C75.1 ; U25.6 209.55,84.21 v1(209.3,84.45)
  BOTTOM w0.305: U45.1 146.35,121.5 146.06,121.79 C295.1
  BOTTOM w0.381: C393.1 187.82,62.73 187.44,62.36 v1(187.32,62.36)
  BOTTOM w0.508: v1(67.63,138.11) 67.82,138.3 C51.1 ; C27.1 76.57,127.13 v1(76.45,127.25) ; C27.1 C29.1 ; C27.1 77.22,127.13 R51.2 ; C319.1 154.94,50.16 v1(154.69,50.42) ; C381.1 187.58,63.75 v1(187.32,64.01) ; C652.1 83.02,63.25 v1(82.55,63.25) 82.42,63.11 C654.1 ; C656.1 v1(81.53,54.61) ; v1(158.3,46.12) 158.37,46.19 C326.1 ; C677.1 113.29,63.24 v1(113.16,63.37) ; C391.1 186.42,62.36 v1(187.32,62.36) ; C43.1 v1(158.5,89.41) ; R143.1 233.16,102.75 v1(233.43,102.49) ; C49.1 v1(68.07,145.16) ; C320.1 155.46,52.7 v1(155.19,52.96) ; C679.1 v1(114.81,54.61) ; C655.1 v1(81.53,53.34) ; C681.1 v1(104.39,54.61) ; C392.1 190.12,61.59 v1(189.48,60.96) ; v1(193.42,69.34) 193.41,69.33 C383.1 ; C281.1 v1(173.23,91.95) ; C382.1 187.58,68.96 v1(187.32,69.22) ; C680.1 v1(104.39,53.34) ; C1060.1 v1(92.97,128.4) ; v1(145.41,122.17) 145.03,122.56 R853.2 C295.1 ; R48.2 R45.2 97.53,127.13 R46.2 C28.1 95.88,127.13 v1(95.76,127.25) ; v1(154.69,49.02) C325.1 155.46,48.04 C324.1 ; C653.1 90.43,63.24 v1(90.3,63.37) ; v1(101.09,128.4) 101.1,128.4 C34.1 C33.1 ; C1074.1 v1(80.89,134.23) ; C1072.1 v1(80.89,128.14) ; C77.1 v1(209.3,84.45) ; C283.1 v1(168.66,91.95) ; v1(56.77,8.76) v1(52.45,8.76) 51.94,8.25 48.64,8.25 v1(48.13,8.76) v1(43.81,8.76) v1(39.5,8.76) v1(35.18,8.76) v1(30.86,8.76) 30.86,24.89 37.08,31.12 v1(37.08,36.07) ; C41.1 v1(163.07,89.41) ; C1062.1 v1(92.97,122.56) ; C678.1 105.28,63.11 v1(105.41,63.25) 105.88,63.25 C676.1 ; C76.1 v1(213.23,83.57) ; v1(195.71,61.98) 195.71,61.98 C1025.1 ; R142.1 233.16,93.86 v1(233.43,93.6) ; C657.1 v1(91.95,54.61) ; C75.1 v1(205.36,83.57)
  vias: v1(21.59,153.42) v1(21.59,150.24) v1(21.59,145.92) v1(21.72,139.45) v1(32.64,125.73) v1(32.64,124.84) v1(33.53,125.73) v1(33.53,124.84) v1(34.42,125.73) v1(34.42,124.84) v1(35.31,125.73) v1(35.31,124.84) v1(38.61,36.07) v1(39.37,36.07) v1(41.78,125.98) v1(41.78,125.35) v1(41.78,124.71) v1(43.05,89.79) v1(43.05,88.52) v1(43.05,87.25) v1(44.07,89.79) v1(44.07,88.52) v1(44.07,87.25) v1(45.09,89.79) v1(45.09,88.52) v1(45.09,87.25) v1(56.13,121.54) v1(56.13,120.78) v1(56.9,121.54) v1(56.9,120.78) v1(62.48,140.08) v1(62.48,139.32) v1(63.37,140.08) v1(63.37,139.32) v1(64.26,140.08) v1(64.26,139.32) v1(174.5,40) v1(175.39,40) v1(176.78,51.82) v1(176.78,50.93) v1(177.8,51.82) v1(177.8,50.93) v1(241.05,154.05) v1(241.05,153.16) v1(241.94,154.05) v1(241.94,153.16)
3V3_PGOOD: length 52
  TOP w0.127: U65.K1 50.19,104.93 v1(48.64,103.38) ; U90.3 19.17,91.05 v1(18.8,90.68)
  L3SIG w0.102: v1(18.8,90.68) 20.83,90.68 22.23,89.28 27.43,89.28 30.35,92.2 36.7,92.2 39.37,94.87 39.37,100.33 41.27,102.23 44.51,102.23 45.66,103.38 v1(48.64,103.38)
  BOTTOM w0.127: R771.2 v1(18.8,90.68)
3V3_SFPP_VDDR:
  vias: v1(177.8,42.04) v1(177.8,41.27)
3V3_SFPP_VDDT:
  vias: v1(176.78,42.04) v1(176.78,41.27)
3V3_SLP: length 176.4
  TOP w0.203: v1(132.46,51.05) 132.55,51.15 U49.41 ; U49.6 v1(136.07,46.75) ; U49.44 132.75,49.95 v1(132.46,49.66) 132.57,49.55 U49.45 ; U49.37 133.27,53.29 v1(132.97,53.59)
  TOP w0.305: 228.47,144.53 228.33,144.67 U81.10 ; U81.7 v1(226.83,144.41)
  TOP w0.381: U65.H6 v1(61.52,107.43) ; U65.L8 v1(63.52,103.43) ; U65.L9 v1(65.52,103.43) ; U65.P1 v1(56.52,100.43) ; U65.T14 v1(70.52,98.43) ; U65.C1 v1(56.52,112.43) ; C1016.1 211.83,127.25 211.2,127.25 210.91,126.96 U95.4 ; U65.T3 v1(58.52,98.43) ; U65.J6 v1(61.52,105.43)
  TOP w0.508: v1(18.8,88.14) 18.8,88.15 R772.2 R771.1 C989.1 ; v1(59.94,35.31) 60.2,35.05 R158.2 ; D43.2 26.54,4.44 26.04,3.94 22.73,3.94 22.23,4.45 D44.2 22.23,9.14 16,15.37 16,54.99 22.22,61.21 v1(22.22,64.52) C1002.1 20.27,64.52 U83.4 19.17,63.42 R705.2 ; R155.2 v1(58.29,38.35) ; v1(53.09,129.54) 53.08,129.53 R703.2 R704.2 ; R264.2 135.9,56.76 136.4,56.26 136.77,56.26 R252.1 136.78,55.63 v1(136.91,55.5) ; R156.2 v1(62.99,38.48) ; v1(133.1,44.96) 135,43.05 FB29.1 ; R498.1 R497.1 10.54,127.5 10.54,124.97 11.3,124.21 13.08,124.21 J26.4 ; v1(132.97,53.59) 132.85,53.71 R825.1 ; C1016.1 212.59,127.25 v1(212.6,127.25) ; D6.2 D5.2 40.09,88.3 Q18.5 ; C997.1 v1(106.17,78.61) ; R159.2 v1(65.28,33.53) ; R262.2 v1(133.73,55.75)
  L3SIG w0.508: v1(18.8,88.14) 20.83,88.14 21.34,88.65 29.08,88.65 30.1,87.63 v1(35.56,87.63)
  L4PWR w0.508: 13.64,122.23 J26.4 ; J26.4 13.64,123.64 ; J26.4 15.06,122.23 ; J26.4 15.06,123.64
  BOTTOM w0.254: U92.8 v1(106.17,78.61)
  BOTTOM w0.305: U21.5 77.36,100.7 76.59,101.46 C54.1 75.82,101.85 74.55,100.58 74.55,98.43 73.79,97.66 71.28,97.66 v1(70.52,98.43)
  BOTTOM w0.508: C1102.1 64.01,103.92 v1(63.52,103.43) ; C350.1 132.72,50.8 v1(132.46,51.05) ; v1(136.07,46.75) 136.14,46.82 C358.1 ; v1(98.3,77.34) R595.2 R563.1 ; R564.1 R574.1 v1(94.49,82.17) ; R559.2 v1(103.12,90.3) ; R570.1 v1(94.49,86.61) ; v1(56.52,100.43) 57.01,99.93 C707.1 ; v1(132.46,49.66) 132.59,49.78 C357.1 133.23,48.67 C356.1 ; v1(70.52,98.43) 71.01,98.92 C710.1 ; R771.1 v1(18.8,88.14) ; FB12.2 160.44,97.57 v1(160.02,97.16) ; v1(56.52,112.43) 57.01,112.92 C705.1 ; R185.2 58.52,98.42 v1(58.52,98.43) 58.02,98.92 C708.1 ; C1103.1 65.02,103.92 v1(65.52,103.43) ; C351.1 133.23,53.33 v1(132.97,53.59) ; v1(61.52,105.43) 62.01,104.93 C709.1 ; v1(94.49,85.6) R569.1 R573.1 ; C706.1 62.01,107.92 v1(61.52,107.43)
  vias: v1(35.56,95.76) v1(35.56,94.74) v1(35.56,93.73) v1(35.56,92.71) v1(35.56,91.69) v1(35.56,90.68) v1(35.56,89.66) v1(35.56,88.65) v1(35.56,86.61) v1(46.1,111.12) v1(46.1,110.36) v1(51.43,137.79) v1(51.43,137.03) v1(52.2,137.79) v1(52.2,137.03) v1(231.27,144.14) v1(231.27,143.38) v1(232.03,144.14) v1(232.03,143.38)
3V3_USB_HVDD: length 5.6
  TOP w0.305: U1.K8 v2(162.12,108.45) ; U1.J8 v2(161.32,108.45)
  BOTTOM w0.457: v2(159.64,102.11) 159.51,102.11 159.14,101.73 C160.1
  BOTTOM w0.508: FB12.1 159.14,98.34 C161.1 C162.1 C160.1
3V3A_843002A: length 4.7
  TOP w0.305: U68.8 147.47,65.56 C751.1
  TOP w0.508: R549.2 147.44,64.05 C750.1 147.44,64.47 C751.1
3V3A_843002B: length 5.2
  TOP w0.305: U67.8 227.17,70.76 C753.1
  TOP w0.508: R550.2 225.42,69.43 C752.1 226.43,70.44 C753.1
3V3O_843002A: length 13.7
  TOP w0.305: C746.1 155.15,71.57 U68.20 ; U68.2 147.45,69.46 C747.1
  TOP w0.508: C747.1 v1(147.45,70.23) ; C746.1 154.09,71.63 FB52.2 153.96,70.83 v1(154.05,70.74)
  L6SIG w0.508: v1(147.45,70.23) 147.72,69.95 153.27,69.95 v1(154.05,70.74)
3V3O_843002B: length 11
  TOP w0.305: U67.2 229.73,74.67 229.74,74.68 ; U67.20 234.07,75.39 C748.1
  TOP w0.508: 229.74,74.68 230.26,75.19 C749.1 230.26,77.35 230.89,77.98 FB53.2 234.07,77.93 C748.1
5V0_SB: length 20
  TOP w0.254: U84.8 9.78,63.26 ; 9.78,63.26 10.23,63.26 10.39,63.41 10.39,63.6 10.23,63.76 U84.7 ; 9.78,63.26 10.03,63
  TOP w0.508: R710.2 v1(7.11,66.8) ; 10.03,63 C898.1 v1(9.28,61.84) 8.52,61.84 8.13,62.23 R715.1 ; v1(10.79,59.31) C897.1 11.56,60.37 U85.5 ; R711.2 14.73,60.71 v1(14.48,60.45)
  TOP w1.016: 12.3,80.65 J37.9 ; J37.9 12.3,78.67 ; J37.9 14.28,80.65 ; J37.9 14.28,78.67
  BOTTOM w1.016: J37.9 14.14,78.81 ; J37.9 12.44,80.51 ; J37.9 14.14,80.51 ; J37.9 12.44,78.81
  vias: v3(11.81,80.39) v3(11.81,78.99) v3(14.73,80.39) v3(14.73,78.99)
5V0_SLP: length 116.4
  TOP w0.254: C974.2 23.23,86.97 U90.10 ; U88.10 23.23,108.56 C1055.2 ; C1057.2 60.69,76.81 U91.10 ; U86.10 197.88,83.34 C928.2 ; C951.2 23.23,97.77 U89.10 ; C929.2 218.2,140.49 U87.10
  TOP w0.508: v1(219.46,131.7) R728.1 R734.1 ; v1(59.94,76.71) C1057.2 ; R756.1 v1(18.03,101.73) ; R770.1 R765.1 v1(21.97,95.76) ; R737.1 v1(203.07,79.38) ; v1(199.14,74.55) R730.1 R732.1 ; R706.2 v1(10.55,69.73) ; R754.1 R747.1 v1(21.97,106.55) ; R773.1 v1(55.5,80.77) ; v1(218.95,140.59) C929.2 ; R768.1 R764.1 v1(59.44,85.6) ; R752.1 v1(18.03,112.52) ; v1(21.97,117.35) R746.1 R750.1 ; v1(22.48,97.66) C951.2 ; R739.1 v1(223.39,136.52) ; v1(198.63,83.44) C928.2 ; v1(22.48,108.46) C1055.2 ; v1(22.48,86.87) C974.2
  TOP w1.016: 12.3,93.25 J37.6 ; J37.6 14.28,91.27 ; J37.6 14.28,93.25 ; J37.6 12.3,91.27 ; J37.20 8.78,76.45 ; J37.20 8.78,74.47 ; J37.20 6.8,76.45 ; J37.20 6.8,74.47 ; 6.8,78.67 J37.19 ; J37.19 8.78,78.67 ; J37.19 8.78,80.65 ; J37.19 6.8,80.65 ; 12.3,99.67 J37.4 ; J37.4 14.28,99.67 ; J37.4 12.3,101.65 ; J37.4 14.28,101.65
  L5PWR w1.016: 6.94,78.81 J37.19 ; J37.19 6.94,80.51 ; J37.19 8.64,78.81 ; J37.19 8.64,80.51 ; J37.6 14.14,91.41 ; J37.6 12.44,91.41 ; J37.6 12.44,93.11 ; J37.6 14.14,93.11 ; 12.44,101.51 J37.4 ; J37.4 14.14,99.81 ; J37.4 12.44,99.81 ; J37.4 14.14,101.51 ; 6.94,74.61 J37.20 ; J37.20 6.94,76.31 ; J37.20 8.64,74.61 ; J37.20 8.64,76.31
  L6SIG w1.016: J37.20 8.64,76.31 ; J37.20 6.94,74.61 ; J37.20 8.64,74.61 ; J37.20 6.94,76.31 ; J37.6 14.14,93.11 ; J37.6 12.44,93.11 ; J37.6 14.14,91.41 ; J37.6 12.44,91.41 ; J37.4 14.14,101.51 ; J37.4 12.44,101.51 ; J37.4 14.14,99.81 ; J37.4 12.44,99.81 ; 6.94,80.51 J37.19 ; J37.19 8.64,78.81 ; J37.19 8.64,80.51 ; J37.19 6.94,78.81
  BOTTOM w0.508: v1(10.55,69.73) 10.55,73.53 v3(9.27,74.8)
  BOTTOM w1.016: J37.4 14.14,99.81 ; J37.4 12.44,99.81 ; J37.4 14.14,101.51 ; J37.4 12.44,101.51 ; J37.20 8.64,74.61 ; J37.20 6.94,74.61 ; J37.20 8.64,76.31 ; J37.20 6.94,76.31 ; 6.94,80.51 J37.19 ; J37.19 8.64,80.51 ; J37.19 6.94,78.81 ; J37.19 8.64,78.81 ; 12.44,93.11 J37.6 ; J37.6 14.14,91.41 ; J37.6 14.14,93.11 ; J37.6 12.44,91.41
  vias: v1(24.38,115.44) v1(24.38,114.81) v1(24.38,104.65) v1(24.38,104.01) v1(24.38,93.85) v1(24.38,93.22) v1(25.15,115.44) v1(25.15,114.81) v1(25.15,104.65) v1(25.15,104.01) v1(25.15,93.85) v1(25.15,93.22) v1(25.91,115.44) v1(25.91,114.81) v1(25.91,104.65) v1(25.91,104.01) v1(25.91,93.85) v1(25.91,93.22) v1(61.34,28.07) v1(61.34,27.3) v1(61.85,83.69) v1(61.85,83.06) v1(62.1,28.07) v1(62.61,83.69) v1(62.61,83.06) v1(63.37,83.69) v1(63.37,83.06) v1(85.73,78.74) v1(86.49,78.74) v1(195.2,77.09) v1(195.2,76.45) v1(195.96,77.09) v1(195.96,76.45) v1(196.72,77.09) v1(196.72,76.45) v1(214.63,90.42) v1(214.63,89.66) v1(215.39,90.42) v1(215.39,89.66) v1(215.52,134.24) v1(215.52,133.6) v1(216.15,90.42) v1(216.15,89.66) v1(216.28,134.24) v1(216.28,133.6) v1(217.04,134.24) v1(217.04,133.6) v1(218.82,123.06) v1(218.82,122.3) v1(219.58,123.06) v1(219.58,122.3) v1(220.34,123.06) v1(220.34,122.3) v3(6.35,80.39) v3(6.35,78.99) v3(6.35,76.2) v3(6.35,74.8) v3(9.27,80.39) v3(9.27,78.99) v3(9.27,76.2) v3(11.81,101.35) v3(11.81,99.95) v3(11.81,92.96) v3(11.81,91.57) v3(14.73,101.35) v3(14.73,99.95) v3(14.73,92.96) v3(14.73,91.57)
7V0_DRV: length 6.6
  TOP w0.254: U69.27 104.34,93.16 v1(104.14,92.96) ; U71.27 104.34,103.32 v1(104.14,103.12) ; C769.2 106.55,89.92 U69.3 ; U71.3 106.55,100.08 C756.2
  TOP w0.508: C756.2 v1(107.32,100.08) ; C769.2 v1(107.32,89.92)
  BOTTOM w0.508: v1(104.14,92.96) 104.4,93.23 R558.1
  vias: v1(88.9,80.65) v1(88.9,79.88)
12V: length 39.2
  TOP w0.381: J43.6 267.61,156.82 ; 267.61,158.09 J43.2 268.95,158.71 ; J43.4 267.61,157.46
  TOP w0.508: 275.48,82.51 J18.B2 ; J18.B2 276.61,83.64 ; J18.B2 275.48,83.64 ; J18.B2 276.61,82.51 ; 273.48,81.51 J18.B1 ; J18.B1 274.61,81.51 ; J18.B1 273.48,82.64 ; J18.B1 274.61,82.64 ; J18.A2 270.11,82.51 ; J18.A2 268.98,83.64 ; J18.A2 270.11,83.64 ; J18.A2 268.98,82.51 ; J18.A3 272.11,83.51 ; J18.A3 270.98,83.51 ; J18.A3 272.11,84.64 ; J18.A3 270.98,84.64 ; 273.48,84.64 J18.B3 ; J18.B3 273.48,83.51 ; J18.B3 274.61,84.64 ; J18.B3 274.61,83.51
  BOTTOM w0.508: J18.B1 274.7,81.42 ; J18.B1 273.39,81.42 ; J18.B1 273.39,82.73 ; J18.B1 274.7,82.73 ; 273.39,83.42 J18.B3 ; J18.B3 274.7,83.42 ; J18.B3 274.7,84.73 ; J18.B3 273.39,84.73 ; J18.A2 270.2,82.42 ; J18.A2 268.89,83.73 ; J18.A2 270.2,83.73 ; J18.A2 268.89,82.42 ; 275.39,83.73 J18.B2 ; J18.B2 275.39,82.42 ; J18.B2 276.7,82.42 ; J18.B2 276.7,83.73 ; J18.A3 272.2,84.73 ; J18.A3 270.89,84.73 ; J18.A3 272.2,83.42 ; J18.A3 270.89,83.42
  vias: v1(31.24,241.55) v1(31.24,240.54) v1(32,241.55) v1(32,240.54) v1(101.09,241.55) v1(101.09,240.54) v1(101.85,241.55) v1(101.85,240.54) v1(170.94,241.55) v1(170.94,240.54) v1(171.7,241.55) v1(171.7,240.54) v1(240.79,241.55) v1(240.79,240.54) v1(241.55,241.55) v1(241.55,240.54) v1(268.61,162.43) v1(268.61,161.67) v1(269.49,162.43) v1(269.49,161.67) v3(24.64,77.22) v3(24.64,75.95) v3(24.64,74.68) v3(24.64,73.41) v3(25.65,77.22) v3(25.65,75.95) v3(25.65,74.68) v3(25.65,73.41)
12V_POTS: length 21.3
  TOP w0.508: C687.1 69.2,45.03 ; C687.1 67.45,45.03 ; C687.1 67.45,43.28 ; C687.1 69.2,43.28
  BOTTOM w0.508: D27.1 73.28,50.6 73.28,61.38 C695.1 72.4,62.26 Q5.2 72.47,63.51 R485.2
  vias: v1(66.17,48.39) v1(67.18,48.39) v1(68.2,48.39) v1(69.22,48.39)
12V_SLP: length 390.9
  TOP w0.508: R662.1 43.55,102.86 v1(43.56,102.87) ; R678.1 v1(80.26,82.68) ; v1(125.48,115.57) 126.11,114.94 R660.1 ; v1(47.38,132.58) R819.2 R818.1 ; R691.2 v1(52.2,120.14) ; R690.1 v1(43.81,120.14) ; R679.1 43.55,94.48 v1(43.56,94.49) ; R784.1 v1(200.91,129.92) ; R597.1 88.77,83.19
  TOP w1.016: J37.10 14.28,74.47 ; J37.10 12.3,76.45 ; J37.10 12.3,74.47 ; J37.10 14.28,76.45
  L6SIG w0.508: v1(125.48,115.57) 123.83,113.92 79.76,113.92 71.5,105.66 68.96,105.66 68.2,106.43 64.9,106.43 64.39,106.93 64.39,113.03 58.93,118.49 58.93,121.92 57.66,123.19 55.5,123.19 53.21,125.48 50.93,125.48 47.38,129.02 v1(47.38,132.58) 47.38,149.74 60.71,163.07 153.54,163.07 153.92,163.45 225.93,163.45 227.97,161.42 227.97,153.42 224.54,149.99 217.42,149.99 208.41,140.97 208.41,132.72 205.61,129.92 v1(200.91,129.92)
  BOTTOM w0.508: R557.2 91.96,80.14 89.66,77.85 83.95,77.85 81.41,80.39 81.41,82.04
  BOTTOM w1.016: J37.10 14.14,74.61 ; J37.10 12.44,74.61 ; J37.10 12.44,76.31 ; J37.10 14.14,76.31
  vias: v1(19.81,75.95) v1(19.81,75.18) v1(20.57,75.95) v1(20.57,75.18) v1(60.32,139.06) v1(61.21,139.06) v1(88.52,82.17) v1(89.03,82.68) v3(11.81,76.2) v3(11.81,74.8) v3(14.73,76.2) v3(14.73,74.8)
12VF_SLP:
  vias: v1(103.25,109.47) v1(103.25,106.3) v1(103.25,98.93) v1(103.25,97.54) v1(103.25,96.14) v1(103.38,107.7) v1(104.14,106.81) v1(104.14,105.66) v1(104.14,96.65) v1(104.14,95.5) v1(104.39,108.33) v1(104.39,98.17) v1(105.03,107.57) v1(105.03,99.06) v1(105.03,97.41) v1(106.05,109.22) v1(106.05,108.08) v1(106.05,106.81) v1(106.05,105.66) v1(106.05,104.65) v1(106.05,99.06) v1(106.05,97.92) v1(106.05,96.65) v1(106.05,95.5) v1(106.05,94.49) v1(107.19,108.08) v1(107.19,106.81) v1(107.19,105.66) v1(107.19,104.65) v1(107.19,97.92) v1(107.19,96.65) v1(107.19,95.5) v1(107.19,94.49) v3(29.46,82.93) v3(29.46,81.79) v3(29.46,80.65) v3(30.61,82.93) v3(30.61,81.79) v3(30.61,80.65) v3(31.75,82.93) v3(31.75,81.79) v3(31.75,80.65)
AGND_SD1_PLL1: length 6.4
  TOP w0.305: U1.AA16 v2(171.72,115.65)
  BOTTOM w0.508: v1(184.92,125.09) C259.2 186.64,125.09 C260.2 188.52,125.39 C261.2 189.21,125.09 R190.1
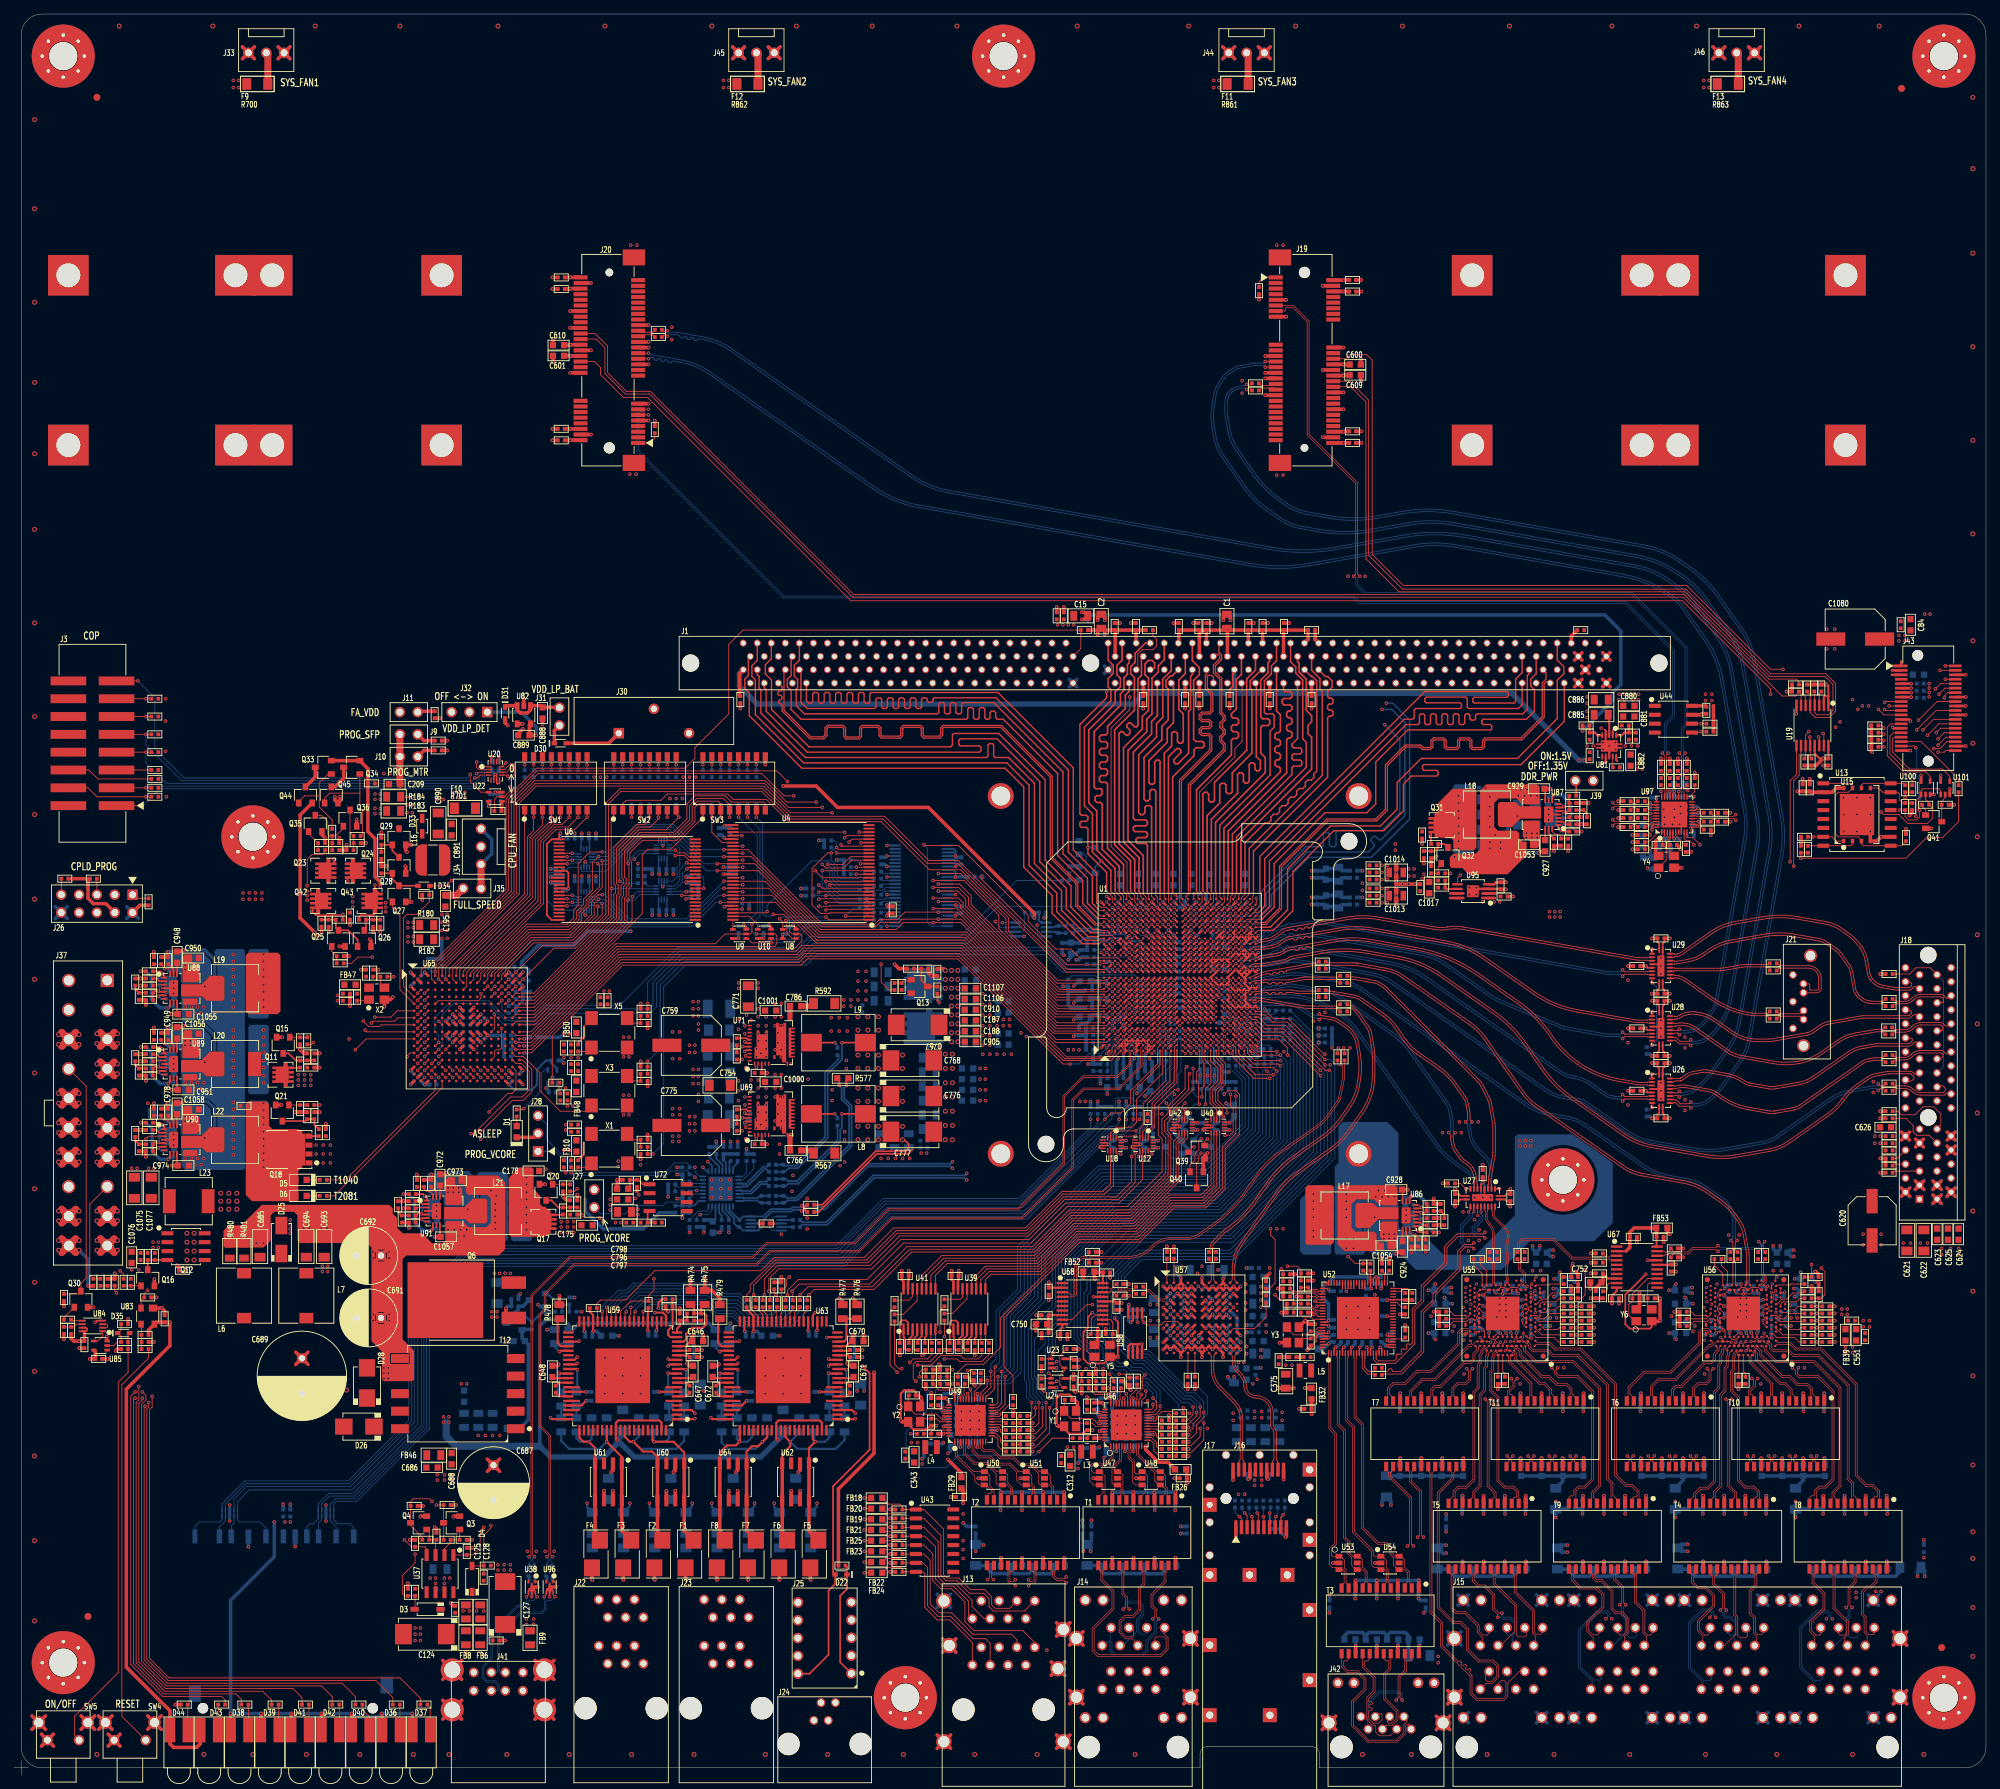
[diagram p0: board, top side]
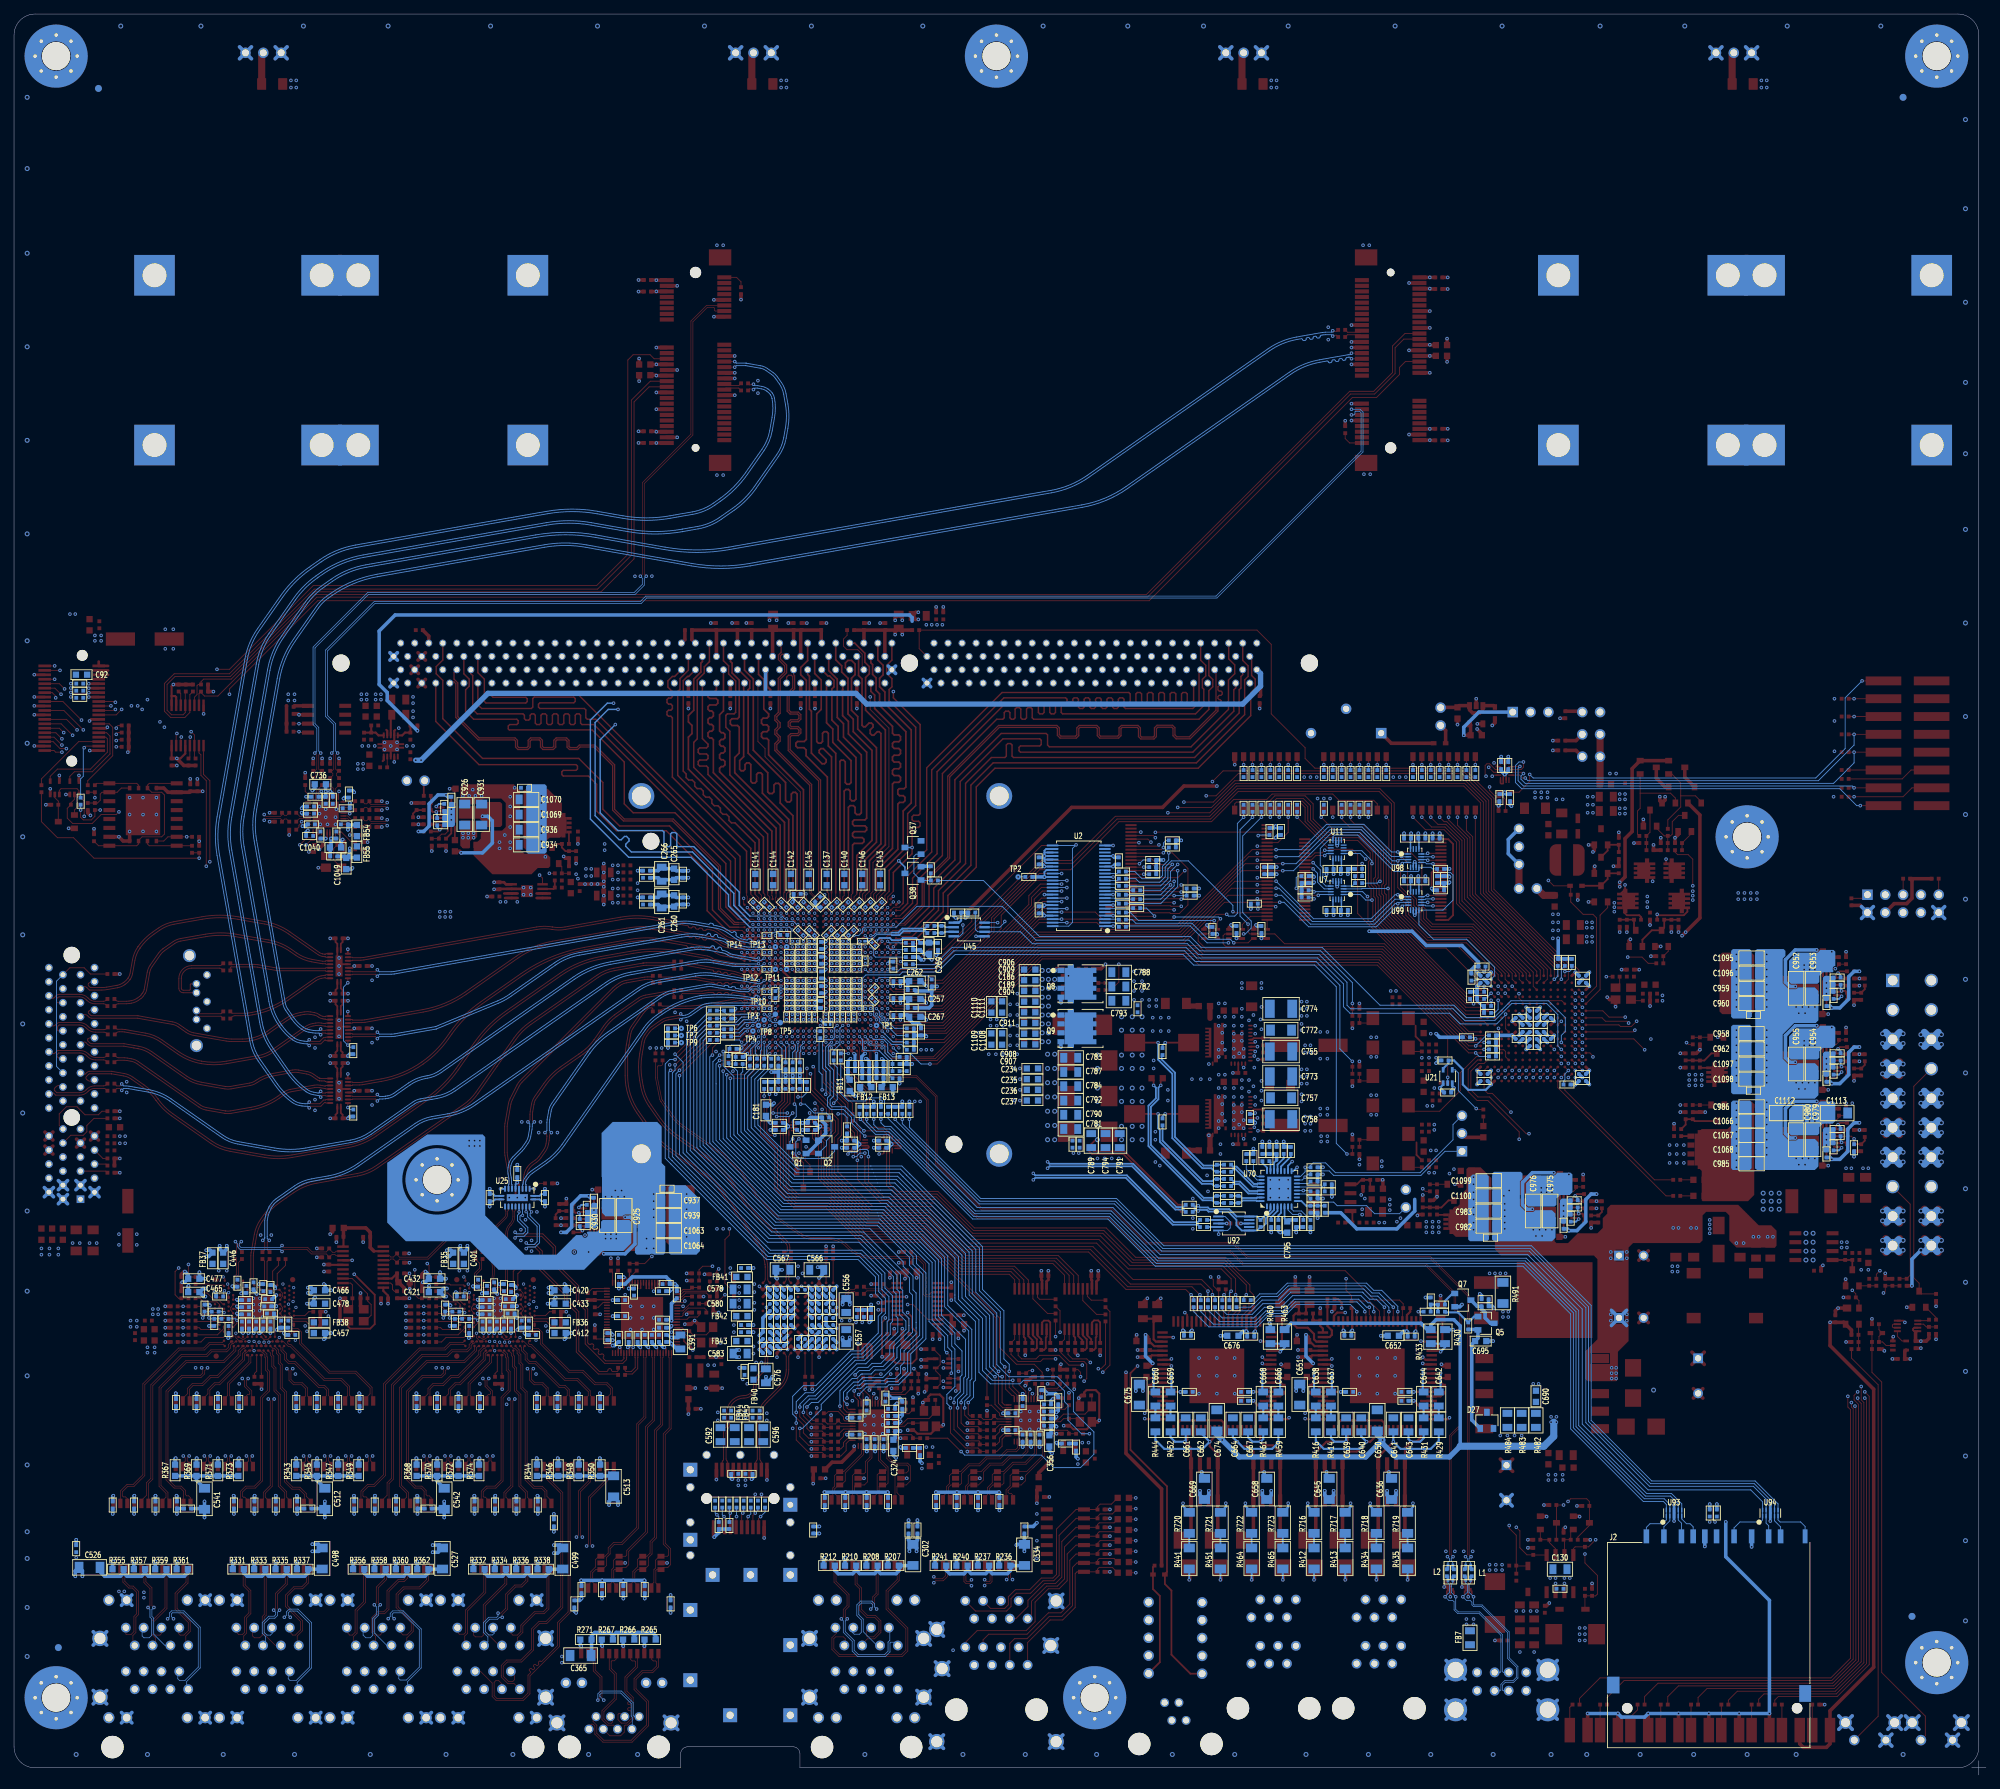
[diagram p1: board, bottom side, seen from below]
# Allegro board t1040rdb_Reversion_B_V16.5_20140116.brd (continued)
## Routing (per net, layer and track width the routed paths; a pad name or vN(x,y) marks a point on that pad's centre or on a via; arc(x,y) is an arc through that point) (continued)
AGND_SD1_PLL2: length 6.4
  TOP w0.305: U1.AA20 v2(171.72,118.85)
  BOTTOM w0.508: R193.1 189.21,128.91 C266.2 188.52,129.2 C265.2 186.64,128.9 C264.2 v1(184.92,128.9)
AVDD_CGA1: length 3.9
  TOP w0.305: U1.G11 v2(159.72,110.85)
  BOTTOM w0.457: C258.1 154.69,110.06 v2(154.71,110.04)
  BOTTOM w0.508: C258.1 153.58,110.74 C257.1 153.66,110.41 R188.2
AVDD_CGA2: length 3.9
  TOP w0.305: U1.G12 v2(159.72,111.65)
  BOTTOM w0.457: v2(154.71,112.44) 154.69,112.46 C263.1
  BOTTOM w0.508: R191.2 153.66,112.95 C262.1 C263.1
AVDD_DDR1: length 10.2
  TOP w0.305: U1.E20 v2(158.12,118.85)
  BOTTOM w0.254: v2(158.12,118.85) 157.66,119.3 156.21,119.3 155.91,119 154.69,119 154.38,119.3 152.45,119.3 151.89,118.75 C270.1
  BOTTOM w0.508: C270.1 150.67,118.61 C269.1 150.58,118.61 R195.2
AVDD_PLAT: length 5.4
  TOP w0.305: U1.G10 v2(159.72,110.05)
  BOTTOM w0.457: C268.1 154.69,107.65 v2(154.71,107.64)
  BOTTOM w0.508: C268.1 153.71,108.33 C267.1 153.45,107.73 152.91,107.19 152.15,107.19 151.76,106.81 R194.2
AVDD_SD1_PLL1: length 6.4
  TOP w0.305: U1.AB16 v2(172.52,115.65)
  BOTTOM w0.508: v1(184.92,124.09) C259.1 186.64,124.09 C260.1 188.52,123.79 C261.1 189.21,124.08 R189.1
AVDD_SD1_PLL2: length 6.4
  TOP w0.305: U1.AB20 v2(172.52,118.85)
  BOTTOM w0.508: v1(184.92,127.9) C264.1 186.64,127.9 C265.1 188.52,127.6 C266.1 189.21,127.89 R192.1
DVDD: length 22.4
  TOP w0.203: U40.16 173.14,93.06 v1(173.23,92.96) ; v1(168.66,92.96) 168.56,93.06 U42.16
  TOP w0.305: U1.P8 v2(165.32,108.45) ; U1.N8 v2(164.52,108.45) ; U1.R8 v2(166.92,108.45)
  BOTTOM w0.508: R92.2 R87.2 v1(169.04,99.7) R80.2 ; R97.2 v1(171.07,99.7) R95.2 ; C280.1 v1(173.23,92.96) 173.86,93.6 C181.1 ; R86.2 v1(170.05,99.7) R93.2 ; R89.2 168.66,92.96 v1(168.66,92.96) C282.1 167.89,93.35 167.51,93.73 R88.2 165.83,93.7 165.83,93.19 165.35,92.71 165.35,91.44 166.31,90.48 Q2.1 166.38,90.16 167.95,88.59 Q1.1
  vias: v1(48.26,125.22) v1(48.26,124.46) v1(48.26,123.7)
GND: length 2583.3
  TOP w0.127: v2(252.35,68.83) 252.24,68.73 U56.B7 U56.B8 ; U56.D9 v2(250.44,68.76) ; U55.D9 v2(216.15,68.76) ; v2(218.06,68.83) 217.95,68.73 U55.B7 U55.B8
  TOP w0.203: U18.8 154.76,89.32 154.64,89.43 154.64,89.6 154.76,89.72 U18.7 155.76,89.72 v1(155.96,89.92) 155.76,90.12 U18.6 ; U52.27 195.89,62.55 v1(195.71,62.74) ; U12.6 160.33,90.12 v1(160.53,89.92) 160.33,89.72 U12.7 159.33,89.72 159.21,89.6 159.21,89.43 159.33,89.32 U12.8 ; U52.48 194.52,70.79 194.37,70.93 v1(194.12,70.93) ; U42.8 164.92,91.86 164.8,91.97 164.8,92.14 164.92,92.26 U42.7 165.92,92.26 v1(166.12,92.46) 165.92,92.66 U42.6 ; 190.5,69.34 190.52,69.36 U52.58 ; v1(187.32,63.12) 187.16,62.95 U52.83 186.01,62.95 185.55,62.48 185.55,61.84 184.93,61.22 C373.2 ; U40.6 170.49,92.66 v1(170.69,92.46) 170.49,92.26 U40.7 169.49,92.26 169.37,92.14 169.37,91.97 169.49,91.86 U40.8 ; U52.53 192.52,69.36 192.53,69.34 ; v1(194.12,70.93) U52.49 194.12,69.41 194.18,69.34 ; v1(194.12,70.93) 193.87,70.93 193.72,70.78 U52.50 ; U52.54 192.12,69.38 192.15,69.34 ; v1(187.32,61.47) 187.21,61.35 U52.87 ; U52.60 189.72,69.36 189.74,69.34 ; U49.47 132.57,48.75 v1(132.46,48.64) ; 191.77,69.34 191.72,69.4 U52.55 ; U52.15 192.92,60.83 v1(192.79,60.96) ; 189.36,69.34 189.32,69.38 U52.61 ; 190.12,69.34 190.12,69.35 U52.59 ; U52.57 190.92,69.38 190.88,69.34 ; U46.47 154.79,48.11 v1(154.69,48.01) ; U52.20 194.92,60.73 v1(194.69,60.96) 194.52,60.78 U52.19 ; U97.41 237.6,135.91 U97.8 ; U20.6 68.38,142.42 v1(68.58,142.62) 68.78,142.42 U20.7 68.78,141.35 68.83,141.3 69.09,141.3 69.18,141.39 U20.8
  TOP w0.254: U27.11 206.13,82.05 205.87,81.8 C75.2 ; v1(234.7,115.32) 234.45,115.57 U29.5 ; C74.2 235.2,94.11 234.95,94.37 U26.11 ; U29.11 234.95,112.15 235.2,111.89 C82.2 ; U27.20 212.47,82.05 212.72,81.8 C76.2 ; v1(11.56,64.52) 11.8,64.76 U84.4 ; U89.4 U89.17 ; v1(234.7,107.57) 234.95,107.82 U28.20 234.95,109.6 235.2,109.85 C80.2 ; U96.1 77.04,27.57 77.22,27.39 v1(77.22,26.8) ; U27.2 v1(211.69,83.55) ; Y5.2 156.17,59.52 155.32,58.67 153.03,58.67 152.4,59.31 152.4,63.12 153.03,63.75 153.03,65.28 v1(153.67,65.91) ; C72.2 235.2,100.96 234.95,100.71 U26.20 234.95,98.93 v1(234.7,98.68) ; U28.11 234.95,103.26 235.2,103 C78.2 ; U28.2 v1(233.45,108.82) ; R556.1 114.68,80.26 122.94,88.52 127.38,88.52 128.02,89.15 ; v1(232.54,71.37) 229.62,68.45 229.62,64.26 230.25,63.63 233.13,63.63 233.38,63.88 Y6.2 ; U28.5 234.45,106.68 v1(234.7,106.43) ; C81.2 235.2,118.74 234.95,118.49 U29.20 234.95,116.71 v1(234.7,116.46) ; v1(157.31,59.6) 157.31,64.56 156.84,65.02 v1(156.84,65.15) ; U87.4 U87.17 ; U27.5 209.55,82.55 v1(209.3,82.3) ; v1(76.45,128.02) 76.59,127.88 U6.36 ; U4.33 101.42,133.4 v1(101.22,133.6) ; U90.4 U90.17 ; U29.2 v1(233.45,117.71) ; U38.1 74.5,27.57 74.68,27.39 v1(74.68,26.8) ; U4.52 101.36,123.9 v1(101.22,123.77) ; v1(95.76,128.02) 95.89,127.88 U6.13 ; U91.4 U91.17 ; U86.4 U86.17 ; v1(234.7,97.54) 234.45,97.79 U26.5 ; U88.4 U88.17 ; U26.2 v1(233.45,99.93)
  TOP w0.305: U1.AH2 v2(177.32,103.65) ; U59.53 80.49,55.27 80.52,55.24 ; 175.71,110.05 U1.AF10 175.51,110.64 175.51,111.05 U1.AF11 v2(175.72,111.65) ; 175.71,110.05 U1.AG9 ; 175.71,110.05 175.32,109.66 U1.AF9 ; U1.K7 v2(162.12,107.65) ; U1.M18 v2(163.72,117.25) ; U63.23 114.48,63.42 v1(114.43,63.37) ; U1.J2 v2(162.12,103.65) ; U1.J2 v2(161.32,104.45) ; U1.J2 v2(161.32,103.65) U1.J1 ; v2(162.12,103.65) U1.J1 ; v2(162.12,103.65) U1.K2 ; 174.9,114.06 174.93,114.06 U1.AF15 ; 174.9,114.06 U1.AE15 ; 174.9,114.06 U1.AF14 ; U1.H7 v2(160.52,107.65) ; U63.43 103.3,61.77 v1(103.38,61.85) ; U81.8 v1(227.33,146.69) 226.83,147.19 U81.4 226.83,148.84 226.69,148.97 ; U1.T14 v2(167.72,113.25) ; v1(81.28,63.25) 81.22,63.31 U59.39 ; U1.AG12 U1.AF13 175.5,113.03 175.5,113.46 U1.AF14 ; U1.AG12 v2(176.52,112.45) U1.AH12 v2(177.32,112.45) ; U1.AG12 v2(175.72,111.65) ; U1.J26 v2(161.32,123.65) ; U1.AF9 v2(174.92,109.25) U1.AE9 v2(174.12,109.25) U1.AD9 v2(173.32,110.05) U1.AC10 v2(173.32,110.85) U1.AC11 ; U1.AF9 v2(175.72,109.25) U1.AG9 ; U1.N22 v2(164.52,120.45) ; U1.K5 v2(162.12,106.05) ; U1.AC17 v2(172.52,116.45) U1.AB17 v2(171.72,116.45) U1.AA17 ; U1.AC17 v2(173.32,115.65) U1.AC16 ; U1.AC17 v2(173.32,116.45) U1.AD18 v2(174.12,117.25) U1.AE18 v2(174.92,117.25) ; U1.AC1 v2(173.32,102.85) ; U1.G2 v2(159.72,103.65) U1.G1 v2(159.72,102.85) ; U1.G2 v2(160.52,104.45) ; U1.G2 v2(159.72,104.45) ; U1.V18 v2(169.32,117.25) ; v2(174.12,119.65) U1.AE21 v2(174.92,119.65) U1.AF21 ; v2(174.12,119.65) U1.AD22 v2(174.12,120.45) ; v2(174.12,119.65) U1.AD21 v2(173.32,118.85) U1.AC20 ; U1.C26 v2(156.52,123.65) ; v2(161.32,104.45) U1.J3 ; v2(161.32,104.45) U1.H3 v2(160.52,104.45) ; U1.U7 v2(168.52,107.65) ; U1.B10 v2(155.72,110.05) ; v2(172.52,120.45) U1.AB22 171.7,119.63 ; U1.E19 v2(158.12,118.05) ; U1.U24 v2(168.52,122.05) ; U63.56 103.36,53.32 103.38,53.34 ; U1.D24 v2(157.32,122.05) ; U1.B28 v2(155.72,125.25) ; U1.N17 v2(164.52,116.45) ; U1.AA17 v2(170.92,115.65) ; U1.AA17 v2(170.92,116.45) U1.Y17 v2(170.92,115.65) ; U1.V26 v2(169.32,123.65) ; U1.U11 v2(168.52,110.85) ; U1.G13 v2(159.72,112.45) ; v2(159.72,104.45) U1.G3 v2(160.52,104.45) ; v2(159.72,104.45) U1.F3 v2(158.92,104.45) ; U1.E13 v2(158.12,112.45) ; U63.5 115.84,53.32 115.82,53.34 ; v2(170.92,115.65) U1.Y16 ; U59.23 91.62,63.42 v1(91.57,63.37) ; C305.2 152.79,49.16 152.27,48.64 150.37,48.64 149.65,49.36 Y1.2 ; U1.AC2 v2(173.32,103.65) ; U1.E26 v2(158.12,123.65) ; U1.AE15 v2(174.92,114.85) U1.AF16 v2(175.72,114.85) ; U1.AE15 v2(174.12,114.85) U1.AD15 U1.AC14 v2(173.32,113.25) U1.AC13 ; U1.AG4 v2(176.52,105.25) ; U1.AF15 175.69,114.07 175.74,114.07 ; U1.AF15 v2(175.72,114.85) ; U1.L26 v2(162.92,123.65) ; U1.J22 v2(161.32,120.45) ; U1.L7 v2(162.92,107.65) ; v2(175.72,111.65) U1.AF12 v2(174.92,111.65) U1.AE12 v2(174.12,111.65) U1.AD12 v2(173.32,112.45) U1.AC13 ; v2(158.92,104.45) U1.E3 v2(158.12,104.45) ; v2(158.92,104.45) U1.E2 ; U1.AE2 v2(174.92,103.65) ; U1.E16 v2(158.12,115.65) ; U1.AC19 v2(173.32,118.05) ; U1.L9 v2(162.92,109.25) ; U1.AG9 v2(176.52,109.25) U1.AH9 v2(177.32,109.25) ; U1.B13 v2(155.72,112.45) ; U1.L15 v2(162.92,114.85) ; v1(159.13,64.52) 159.44,64.83 U58.7 ; U1.B19 v2(155.72,118.05) U1.A20 ; U1.K16 v2(162.12,115.65) ; U1.H10 v2(160.52,110.05) ; U1.J1 v2(161.32,102.85) ; U1.R15 v2(166.92,114.85) ; U1.AF21 v2(175.72,119.65) ; U1.AF21 175.69,118.87 175.69,118.82 ; v2(175.72,119.65) U1.AG22 ; v2(175.72,119.65) U1.AG21 ; U1.AA19 v2(171.72,118.05) ; U1.AC13 v2(172.52,112.45) U1.AB13 v2(171.72,112.45) U1.AA13 v2(170.92,113.25) U1.Y14 U1.AA15 v2(171.72,114.85) ; U1.P24 v2(165.32,122.05) ; U1.AA24 v2(171.72,122.05) ; U1.T7 v2(167.72,107.65) ; U1.Y10 v2(170.92,110.05) ; C339.2 128.52,54.53 128.19,54.86 126.87,54.86 126.37,54.36 v1(126.37,50.55) ; U1.AG22 v2(176.52,120.45) U1.AG23 ; U1.AG22 v2(176.52,119.65) ; U1.D2 v2(158.12,104.45) ; U1.D2 v2(157.32,103.65) ; U1.D2 v2(158.12,103.65) ; v2(158.12,104.45) U1.E2 ; U1.E22 v2(158.12,120.45) ; 159.47,61.43 159.44,61.4 U58.2 ; 159.47,61.43 160.12,61.43 ; 159.47,61.43 159.09,61.43 158.79,61.13 U58.1 ; 175.75,116.48 175.68,116.48 U1.AF18 ; 175.75,116.48 U1.AG18 ; 175.75,116.48 U1.AF17 ; Y2.2 127.42,50 128.14,49.28 130.05,49.28 130.56,49.79 C340.2 ; C304.2 150.74,53.9 150.41,54.23 149.1,54.23 148.59,53.72 v1(148.59,49.91) ; U1.AG15 v2(175.72,114.85) ; U1.AG15 175.74,114.07 ; U1.AG15 v2(176.52,114.85) U1.AH15 v2(177.32,114.85) ; v1(115.82,62.36) 115.89,62.42 U63.19 ; U1.K18 v2(162.12,117.25) ; U1.W2 v2(170.12,103.65) ; U1.K20 v2(162.12,118.85) ; U1.B1 v2(155.72,102.85) ; U1.AG21 v2(176.52,119.65) ; U1.AG21 175.69,118.82 ; v2(176.52,119.65) U1.AH21 v2(177.32,119.65) ; U63.8 115.85,55.27 115.82,55.24 ; v1(104.14,63.25) 104.08,63.31 U63.39 ; U1.L19 v2(162.92,118.05) ; U1.W7 v2(170.12,107.65) ; U1.AG18 v2(175.72,117.25) ; U1.AG18 v2(176.52,117.25) U1.AH18 v2(177.32,117.25) ; v2(175.72,117.25) U1.AF19 v2(174.92,117.25) ; v2(175.72,117.25) U1.AF18 ; U1.N7 v2(164.52,107.65) ; U1.U9 v2(168.52,109.25) ; U1.C22 v2(156.52,120.45) ; U1.P14 v2(165.32,113.25) ; U59.56 80.5,53.32 80.52,53.34 ; U1.AD6 v2(174.12,106.85) ; U1.R22 v2(166.92,120.45) ; U1.G16 v2(159.72,115.65) ; U1.T16 v2(167.72,115.65) ; U1.F15 v2(158.92,114.85) ; 171.7,119.63 171.73,119.63 U1.AB21 v2(172.52,119.65) ; 171.7,119.63 U1.AA21 ; U1.AE24 v2(174.92,122.05) ; U1.N11 v2(164.52,110.85) ; U1.E2 v2(158.12,103.65) ; v2(158.12,103.65) U1.E1 v2(158.12,102.85) ; U1.AB26 v2(172.52,123.65) ; U1.N26 v2(164.52,123.65) ; U1.P16 v2(165.32,115.65) ; U1.B7 v2(155.72,107.65) ; U1.R19 v2(166.92,118.05) ; U1.W13 v2(170.12,112.45) ; U1.B16 v2(156.52,115.65) ; U1.H16 v2(160.52,115.65) ; U1.K14 v2(162.12,113.25) ; U1.R7 v2(166.92,107.65) ; U1.V10 v2(169.32,110.05) ; U1.Y12 v2(170.92,111.65) ; U58.4 v1(160.74,61.43) 160.12,61.43 ; U1.AF20 175.69,118.82 ; U1.U17 v2(168.52,116.45) ; U1.L22 v2(162.92,120.45) ; U1.V7 v2(169.32,107.65) ; U19.8 254.01,151.27 v1(254,151.26) ; U1.H19 v2(160.52,118.05) ; 175.74,114.07 U1.AF14 ; U1.M10 v2(163.72,110.05) ; U1.G5 v2(159.72,106.05) ; U1.N15 v2(164.52,114.85) ; U1.M7 v2(163.72,107.65) ; U1.E5 v2(158.12,106.05) ; U1.W9 v2(170.12,109.25) ; U1.H14 v2(160.52,113.25) ; U1.M20 v2(163.72,118.85) ; U1.AG6 v2(176.52,106.85) ; 92.96,55.24 92.99,55.27 U59.8 ; U1.K12 v2(162.12,111.65) ; U1.AF18 v2(174.92,117.25) ; U1.H17 v2(160.52,116.45) ; v1(80.52,61.85) 80.44,61.77 U59.43 ; U1.U13 v2(168.52,112.45) ; U1.L17 v2(162.92,116.45) ; 103.38,55.24 103.35,55.27 U63.53 ; 80.52,52.07 80.47,52.02 U59.58 ; U1.G26 v2(159.72,123.65) ; U1.B4 v2(155.72,105.25) ; U67.17 v1(232.83,73.37) ; U1.H15 v2(160.52,114.85) ; U1.P18 v2(165.32,117.25) ; U1.M12 v2(163.72,111.65) ; U1.E10 v2(158.12,110.05) ; U1.AG26 v2(176.52,123.65) ; U1.M14 v2(163.72,113.25) ; U1.A2 v2(154.92,103.65) ; U1.H20 v2(160.52,118.85) ; U1.H13 v2(160.52,112.45) ; U68.17 v1(153.84,68.16) ; U1.AA11 v2(171.72,110.85) ; U1.N13 v2(164.52,112.45) ; U1.W5 v2(170.12,106.05) ; U1.AC26 v2(173.32,123.65) ; 160.12,61.43 160.09,61.4 U58.3 ; U1.V14 v2(169.32,113.25) ; U1.E7 v2(158.12,107.65) ; U1.Y18 v2(170.92,117.25) ; U1.P10 v2(165.32,110.05) ; U1.Y26 v2(170.92,123.65) ; U1.L11 v2(162.92,110.85) ; U1.T22 v2(167.72,120.45) ; U1.D20 v2(157.32,118.85) U1.D21 ; U1.V20 v2(169.32,118.85) ; U1.R26 v2(166.92,123.65) ; U1.A27 v2(154.92,124.45) ; 103.38,52.07 103.33,52.02 U63.58 ; U1.Y7 v2(170.92,107.65) ; U1.L13 v2(162.92,112.45) ; U1.H9 v2(160.52,109.25) ; U1.AD4 v2(174.12,105.25) ; U1.J7 v2(161.32,107.65) ; 92.96,53.34 92.98,53.32 U59.5 ; U1.B25 v2(155.72,122.85) ; U1.U15 v2(168.52,114.85) ; U1.T20 v2(167.72,118.85) ; U1.P12 v2(165.32,111.65) ; U1.W24 v2(170.12,122.05) ; U1.T5 v2(167.72,106.05) ; U1.N2 v2(164.52,103.65) ; U1.N5 v2(164.52,106.05) ; U1.M16 v2(163.72,115.65) ; U1.R11 v2(166.92,110.85) ; U1.T12 v2(167.72,111.65) ; U1.M24 v2(163.72,122.05) ; U1.H12 v2(160.52,111.65) ; U1.AC24 v2(173.32,122.05) ; U1.V22 v2(169.32,120.45) ; U1.U19 v2(168.52,118.05) ; U1.R9 v2(166.92,109.25) ; U1.V16 v2(169.32,115.65) ; U1.H24 v2(160.52,122.05) ; U1.V12 v2(169.32,111.65) ; U1.H8 v2(160.52,108.45) ; U1.H11 v2(160.52,110.85) ; U1.AB5 v2(172.52,106.05) ; U1.R13 v2(166.92,112.45) ; U1.T10 v2(167.72,110.05) ; U1.N19 v2(164.52,118.05) ; U1.AE26 v2(174.92,123.65) ; U1.AB2 v2(172.52,103.65) ; U1.P7 v2(165.32,107.65) ; U1.B23 v2(155.72,121.25) ; U1.T26 v2(167.72,123.65) ; U1.T18 v2(167.72,117.25) ; U1.F24 v2(158.92,122.05) ; U1.G22 v2(159.72,120.45) ; U1.H18 v2(160.52,117.25) ; U1.K24 v2(162.12,122.05) ; U1.Y22 v2(170.92,120.45) ; U1.P20 v2(165.32,118.85) ; U1.AB7 v2(172.52,107.65) ; U1.T2 v2(167.72,103.65) ; U1.G7 v2(159.72,107.65) ; U1.R17 v2(166.92,116.45) ; U1.AG1 v2(176.52,102.85) ; U1.W11 v2(170.12,110.85) ; U1.N9 v2(164.52,109.25) ; U1.K6 v2(162.12,106.85)
  TOP w0.381: U65.K8 v1(63.52,104.43) ; v1(165.79,69.65) U57.B3 v1(166.79,69.65) ; v1(165.79,69.65) U57.A3 ; v1(165.79,69.65) U57.B2 v1(164.79,69.65) U57.B1 v1(163.79,69.65) ; v1(172.29,59.55) 172.29,60.15 U57.L9 v1(171.79,60.65) U57.K8 v1(170.79,60.65) U57.K7 v1(169.79,60.65) ; U65.K9 v1(65.52,104.43) ; U65.B2 v1(57.52,113.43) ; U57.H4 v1(166.79,62.65) ; U57.D2 v1(164.79,67.65) ; U57.H5 v1(167.79,62.65) ; U57.L3 v1(165.79,60.65) U57.K2 v1(164.79,60.65) U57.K1 v1(163.79,60.65) ; U57.L3 v1(166.79,60.65) U57.K4 v1(167.79,60.65) U57.K5 v1(168.79,60.65) ; U57.L3 166.29,60.15 v1(166.29,59.55) ; U57.A3 v1(166.79,69.65) ; U57.A3 166.29,70.15 v1(166.29,70.86) ; U65.T1 v1(56.52,98.43) ; U65.K10 v1(66.52,104.43) ; v1(13.21,62.48) 13.27,62.42 U85.3 ; v1(171.79,69.65) U57.B8 v1(170.79,69.65) U57.B7 v1(169.79,69.65) U57.A6 v1(169.29,70.86) ; v1(171.79,69.65) U57.A9 ; v1(171.79,69.65) U57.B9 v1(172.79,69.65) ; v1(68.58,140.08) 68.59,140.1 U22.3 ; v1(174.79,60.65) U57.K11 v1(173.79,60.65) U57.K10 ; C1016.2 211.77,126.31 U95.3 208.59,126.31 v1(208.41,126.49) ; U57.L6 v1(168.79,60.65) ; U57.L6 v1(169.29,59.55) ; U57.L6 v1(169.79,60.65) ; v1(168.79,60.65) U57.K6 v1(169.79,60.65) ; v1(172.79,69.65) U57.A9 ; v1(172.79,69.65) U57.B10 v1(173.79,69.65) U57.B11 v1(174.79,69.65) ; U57.D9 v1(172.79,67.65) ; J43.37 278.11,146.66 v1(278.13,146.69) ; U65.A1 v1(56.52,114.43) ; U57.E6 v1(169.79,66.65) ; U10.3 107.88,120.84 v1(107.57,121.16) ; U57.H9 v1(172.79,62.65) ; U57.E1 v1(163.79,66.65) ; J43.40 v1(270.23,146.03) ; U57.A9 172.29,70.15 v1(172.29,70.76) ; v1(278.13,151.13) 278.11,151.11 J43.23 ; U57.D4 v1(166.79,67.65) ; v1(104.01,121.16) 104.33,120.84 U9.3 ; U23.3 v1(148.58,58.02) ; C272.2 134.61,70.6 134.52,70.51 U39.15 ; v1(278.13,156.84) 278.11,156.82 J43.5 ; v1(166.79,69.65) U57.B4 v1(167.79,69.65) U57.B5 ; U57.G7 v1(170.79,63.65) ; U57.F9 v1(172.79,65.65) ; v1(270.26,150.24) 270.02,150.47 J43.26 ; U57.G6 v1(169.79,63.65) ; U57.H8 v1(171.79,62.65) ; U65.A16 v1(72.52,114.43) ; U65.G7 v1(62.52,108.43) ; U24.3 v1(148.58,55.23) ; U65.K7 v1(62.52,104.43) ; U65.J10 v1(66.52,105.43) ; C286.2 127.5,70.6 127.41,70.51 U41.15 ; U57.E7 v1(170.79,66.65) ; J43.30 267.86,149.2 v1(267.72,149.35) ; U65.G10 v1(66.52,108.43) ; U65.R15 v1(70.52,100.42) ; U57.D8 v1(171.79,67.65) ; U101.3 v1(275.86,140.57) ; v1(278.13,152.4) 278.11,152.38 J43.19 ; U65.B15 v1(71.52,113.43) ; U65.R2 v1(57.52,99.43) ; U65.G8 v1(63.52,108.43) ; v1(111,121.16) 111.44,120.72 U8.3 ; U65.H9 v1(65.52,107.43) ; U65.T16 v1(72.52,98.43) ; U57.D5 v1(167.79,67.65) ; U65.H7 v1(62.52,107.43) ; U57.F8 v1(171.79,65.65) ; U65.J8 v1(63.52,105.43) ; U65.G9 v1(65.52,108.43) ; U100.3 v1(273.62,139.77) ; U57.F4 v1(166.79,65.65) ; U57.F5 v1(167.79,65.65) ; J43.15 278.11,153.65 v1(278.13,153.67)
  TOP w0.508: v1(56.64,124.46) 56.63,124.45 Q27.2 ; J1.116 223.45,155.12 ; J1.116 223.45,156.18 ; J1.116 222.39,155.12 ; J1.116 222.39,156.18 ; SW5.4 11.47,6.51 ; SW5.4 11.47,8.42 ; SW5.4 9.56,8.42 ; SW5.4 9.56,6.51 ; Q36.2 v1(48.83,136.21) ; v1(46.35,118.11) 46.36,118.1 Q25.2 ; J44.3 173.95,244.64 ; J44.3 172.25,244.64 ; J44.3 172.25,246.34 ; J44.3 173.95,246.34 ; C565.1 v1(165.29,75.36) ; R669.1 v1(40.77,103.38) 41.28,102.86 C873.1 ; v1(152.15,164.72) 152.51,164.72 C15.2 152.51,165.73 v1(152.15,165.73) ; C19.2 v1(103.51,152.02) ; Q3.2 62.67,36.89 v1(62.61,36.83) ; Q20.2 v1(75.68,84.21) ; v1(178.69,42.16) 178.52,42.33 J16.14 ; R821.1 v1(44.32,133.6) 43.88,134.04 Q35.2 ; R273.1 v1(195.96,73.66) ; 13.42,5.82 SW4.1 ; SW4.1 15.12,4.12 ; SW4.1 15.12,5.82 ; SW4.1 13.42,4.12 ; R672.1 80.9,79.88 v1(81.03,79.76) ; C999.2 185.41,161.85 J1.199 ; C744.2 v1(228.72,67.19) ; J20.34 v1(79.25,206.28) ; C876.1 40.78,94.48 R685.1 40.01,94.5 v1(40,94.49) ; J44.1 179.03,244.64 ; J44.1 179.03,246.34 ; J44.1 177.33,246.34 ; J44.1 177.33,244.64 ; 107.48,244.64 J45.1 ; J45.1 109.18,244.64 ; J45.1 109.18,246.34 ; J45.1 107.48,246.34 ; C23.2 124.71,122.82 v1(124.39,122.5) ; C502.1 v1(259.46,62.74) ; R547.1 v1(224.66,73.03) ; C293.2 240.55,151.26 v1(240.41,151.13) U44.7 ; R535.1 v1(228.6,138.81) ; C337.2 C338.2 131.96,58.41 v1(131.83,58.55) ; R496.1 17.91,123.96 J26.2 ; J20.27 v1(90.42,203.48) ; 12.06,6.51 SW4.3 ; SW4.3 13.97,8.42 ; SW4.3 13.97,6.51 ; SW4.3 12.06,8.42 ; R842.1 v1(230.63,131.95) ; R178.1 v1(61.72,146.05) ; C752.2 v1(224.62,69.3) ; v1(14.35,71.5) C894.2 R712.1 ; J20.35 v1(90.42,206.68) ; U62.6 v1(110.74,40.51) ; U48.2 v1(159.89,42.29) ; J33.3 34.25,246.34 ; J33.3 34.25,244.64 ; J33.3 32.55,244.64 ; J33.3 32.55,246.34 ; 37.63,244.64 J33.1 ; J33.1 37.63,246.34 ; J33.1 39.33,246.34 ; J33.1 39.33,244.64 ; C335.2 v1(132.46,48.64) ; v1(56.63,132.58) Q29.2 55.81,131.77 v1(56.01,131.57) ; v1(154.19,57.9) C308.2 C307.2 ; C742.2 v1(157.85,66.3) ; R870.1 23.5,72.38 v1(23.24,72.64) ; C80.2 v1(235.97,110.36) ; C746.2 v1(156.2,70.87) ; C530.1 v1(259.46,66.8) ; C272.2 v1(134.61,71.87) ; C72.2 v1(235.97,101.47) ; C704.2 v1(51.94,114.8) ; Q16.2 v1(20,70.68) ; C892.2 v1(52.32,134.37) ; C277.2 v1(124.84,36.58) ; C1024.2 v1(50.16,132.84) ; C702.2 C701.2 v1(47.87,109.61) ; C691.1 53.17,64.27 ; C691.1 53.17,66.03 ; C691.1 51.42,64.27 ; C691.1 51.42,66.03 ; R165.1 v1(56.13,27.3) ; C340.2 v1(131.44,49.79) ; SW4.4 20.97,6.51 ; SW4.4 19.06,6.51 ; SW4.4 19.06,8.42 ; SW4.4 20.97,8.42 ; 102.4,246.34 J45.3 ; J45.3 102.4,244.64 ; J45.3 104.1,244.64 ; J45.3 104.1,246.34 ; C75.2 v1(205.36,81.03) ; v1(50.67,119.13) 50.86,118.94 Q26.2 ; J46.1 248.88,244.64 ; J46.1 247.18,246.34 ; J46.1 248.88,246.34 ; J46.1 247.18,244.64 ; R179.1 v1(60.7,150.63) ; C692.1 53.17,73.16 ; C692.1 53.17,74.92 ; C692.1 51.42,74.92 ; C692.1 51.42,73.16 ; J19.29 v1(178.31,199.08) ; v1(55.75,129.54) 55.81,129.48 Q28.2 ; C613.2 v1(76.71,211.82) ; J19.50 v1(186.51,190.68) ; C10.2 v1(168.91,152.02) ; C741.2 v1(234.57,67.95) v1(234.57,64.77) 234.48,64.68 Y6.2 ; C76.2 v1(213.23,81.03) ; R233.2 v1(155.96,55.12) ; Y4.4 233.93,131.45 233.93,132.58 C733.2 233.94,133.1 v1(234.19,133.35) ; C73.2 v1(230,97.54) ; C36.2 v1(255.91,141.99) ; 242.1,246.34 J46.3 ; J46.3 242.1,244.64 ; J46.3 243.8,246.34 ; J46.3 243.8,244.64 ; C572.2 v1(167.26,54.99) ; C82.2 v1(235.97,111.38) ; J16.20 v1(173.72,42.05) ; v1(173.35,164.59) 173.35,164.96 C1.2 172.34,164.96 v1(172.34,164.59) ; Y2.2 126.58,50.33 v1(126.37,50.55) ; C747.2 v1(147.45,67.69) ; SW5.3 4.47,8.42 ; SW5.3 2.56,8.42 ; SW5.3 4.47,6.51 ; SW5.3 2.56,6.51 ; R541.1 v1(158.88,68.33) ; v1(182.39,55.13) C375.2 v1(180.1,55.13) ; C1002.2 21.46,66.17 v1(21.08,66.55) 21.07,66.56 U83.1 ; SW5.1 5.62,4.12 ; SW5.1 5.62,5.82 ; SW5.1 3.92,4.12 ; SW5.1 3.92,5.82 ; v1(98.17,62.74) 98.21,62.7 C646.1 ; C276.2 v1(124.84,34.04) ; R303.1 C440.2 v1(211.45,54.99) ; R286.1 v1(198.25,64.14) ; R513.1 v1(89.29,101.72) ; C292.2 v1(124.84,30.23) ; C612.2 v1(192.02,191.53) ; R161.1 v1(56.4,33.52) ; C500.1 v1(259.46,63.75) ; C893.2 v1(19.94,61.72) ; v1(151.26,54.61) 151,54.86 C57.2 ; v1(176.66,164.21) 176.65,164.2 C998.2 ; R323.1 v1(256.15,69.72) ; C604.2 v1(76.71,190.25) ; C291.2 v1(124.84,31.5) ; C600.2 v1(191.94,201.91) ; R699.1 v1(22.99,10.03) ; C609.2 v1(191.94,198.68) ; C515.1 v1(225.17,61.72) ; R177.1 v1(61.72,147.45) ; Y2.4 129.29,52.7 v1(129.29,53.72) 128.91,54.1 C339.2 ; Y1.2 148.8,49.7 v1(148.59,49.91) ; C540.1 v1(225.17,65.79) ; C305.2 v1(153.66,49.16) ; C132.2 v1(90.29,91.31) ; C370.2 v1(185.17,71.5) ; J16.10 181.32,34 v1(181.23,33.91) ; v1(235.08,75.95) 235.07,75.95 C748.2 ; R438.1 v1(98.04,60.58) ; C895.2 v1(16.25,65.02) ; R684.1 v1(78.23,82.42) 78.75,81.91 C875.1 ; C1079.2 v1(199.64,126.99) 196.98,126.99 196.98,127 ; v1(245.75,54.99) C485.2 R324.1 ; J20.40 v1(79.25,208.68) ; v1(52.79,109.52) X2.2 53.63,110.53 v1(53.98,110.87) ; C20.2 221.92,162.35 J1.235 ; R538.1 v1(228.6,137.54) ; U38.2 v1(74.68,26.8) ; v1(196.98,129.92) C1014.4 v1(196.98,128.65) C1014.3 v1(196.98,127.38) 196.98,127 ; v1(89.28,87.76) 89.29,87.76 R176.1 ; C11.2 v1(165.23,164.2) ; C878.1 v1(44.83,120.14) ; 67.65,39.83 C687.2 ; C687.2 69,39.83 ; C687.2 67.65,38.48 ; C687.2 69,38.48 ; C8.2 v1(170.68,164.2) ; C81.2 v1(235.97,119.25) ; C997.2 v1(108.2,78.61) ; v1(231.64,68.7) C740.2 231.64,66.84 Y6.4 ; C304.2 151.13,53.47 v1(151.51,53.09) 151.51,52.07 Y1.4 ; C14.2 v1(178.94,152.02) ; v1(184.28,60.58) 184.78,61.09 C373.2 ; v1(121.03,62.74) 121.07,62.7 C670.1 ; C718.2 v1(90.29,98.18) ; C1016.2 v1(212.61,126.25) ; J19.21 v1(178.31,202.28) ; U96.2 v1(77.22,26.8) ; J19.4 v1(186.51,212.28) ; C750.2 v1(145.63,63.33) ; v1(185.42,64.26) 185.41,64.25 C372.2 184.54,64.25 v1(184.02,64.77) 184.02,64.77 Y3.4 ; R524.1 v1(238.38,144.91) ; U53.2 v1(187.96,30.23) ; C48.2 v1(257.82,143.9) ; C602.2 v1(192.02,189.88) ; v1(185.17,65.66) 184.91,65.91 R285.1 ; R141.1 v1(203.58,84.33) ; v1(129.41,59.82) 129.79,60.2 C288.2 ; C601.2 v1(76.8,201.44) ; J20.18 v1(79.25,199.88) ; C753.2 v1(224.66,71.5) ; C16.2 v1(149.61,166.5) ; C898.2 v1(9.28,60.84) ; C673.2 v1(120.9,59.56) ; Y4.2 v1(237.66,129.33) ; C297.2 v1(165.35,42.29) ; C531.1 v1(225.17,66.8) ; C5.2 v1(168.03,164.2) ; C879.2 v1(51.18,120.14) ; C376.2 180.97,59.56 v1(180.97,59.56) C374.2 ; J19.34 v1(189.48,197.08) ; C300.1 v1(164.58,51.3) ; R786.1 C996.1 202.45,130.69 v1(202.69,130.94) ; 130.75,113.93 v1(130.74,113.92) ; 130.75,113.93 R654.1 ; 130.75,113.93 130.29,114.38 C871.1 ; C514.1 v1(259.46,61.72) ; J20.4 v1(82.22,191.08) ; J19.40 v1(189.48,194.68) ; C956.1 v1(19.94,117.35) ; SW3.9 v1(107.06,144.02) ; R546.1 v1(237.87,75.06) ; R596.1 v1(85.98,84.84) 85.94,84.8 C798.1 ; J28.2 74.13,90.89 D1.1 ; R708.1 v1(20.32,68.07) ; R542.1 v1(158.88,69.98) ; R548.1 v1(224.71,74.35) ; C684.2 v1(94.87,66.55) ; C977.1 v1(57.4,85.6) ; C331.1 v1(142.36,51.94) ; U82.4 v1(72.49,149.83) ; C603.2 v1(192.02,213.11) ; 196.98,127 v1(196.98,126.62) C1013.3 v1(196.98,125.35) C1013.4 v1(196.98,124.08) ; U64.6 v1(101.85,40.51) ; C74.2 v1(235.97,93.6) ; C18.2 v1(173.23,152.02) ; J19.9 v1(181.28,210.28) ; v1(174.12,33.78) 174.12,33.79 J16.1 ; J20.29 v1(90.42,204.28) ; C77.2 v1(209.3,87) ; Q4.2 57.97,36.89 v1(57.91,36.83) ; R232.2 v1(167.39,45.47) ; U64.7 v1(103.12,40.51) ; v1(65.28,32.38) 65.27,32.38 R162.1 ; R228.2 v1(167.39,46.48) ; C78.2 v1(235.97,102.49) ; U82.2 v1(72.64,153.42) ; U47.2 v1(153.8,42.29) ; C932.1 v1(221.49,131.7) ; R527.2 v1(235.97,144.91) ; U50.2 v1(137.41,42.29) ; Q41.2 v1(273.24,134.94) ; C697.2 92.84,66.41 v1(93.22,66.04) ; C546.1 v1(259.46,65.79) ; R693.1 v1(47.75,116.71) ; C896.2 v1(7.11,62.1) ; C369.2 v1(182.63,71.37) ; C3.2 v1(160.91,152.02) ; U62.7 v1(112.01,40.51) ; R534.2 v1(234.7,144.91) ; R544.1 v1(154.94,74.55) ; U60.7 v1(94.23,40.51) ; J19.18 v1(189.48,203.48) ; C889.2 71.84,148.42 v1(72.52,149.1) ; R302.1 v1(221.86,69.72) ; R268.1 v1(197.49,65.67) ; C745.2 v1(236.85,71.76) ; C938.1 v1(201.17,74.55) ; J19.35 v1(178.31,196.68) ; C83.2 v1(230,115.32) ; R256.1 v1(130.68,54.48) ; J20.21 v1(90.42,201.08) ; C610.2 v1(76.8,204.75) ; J19.26 v1(186.51,200.28) ; C273.2 132.6,60.59 v1(132.59,60.58) ; R673.1 v1(44.45,92.84) ; C611.2 v1(192.02,211.45) ; Q32.2 v1(205.29,130.88) ; C503.1 v1(225.17,62.74) ; R528.1 v1(237.11,144.91) ; R401.2 v1(265.94,85.85) ; J20.15 v1(90.42,195.48) ; R523.2 v1(244.6,137.16) ; C7.2 v1(159.14,164.2) ; J20.50 v1(82.22,212.68) ; C6.2 v1(181.73,164.2) ; C543.1 v1(225.17,64.77) ; C547.1 v1(259.46,64.77) ; U60.6 v1(92.96,40.51) ; C303.2 v1(154.69,48.01) ; C751.2 v1(145.67,65.53) ; J19.15 v1(181.28,207.88) ; R257.2 v1(145.16,47.12) ; C1023.1 v1(46.35,133.6) ; U61.7 v1(85.34,40.51) ; J20.26 v1(82.22,203.08) ; J20.9 v1(90.42,193.08) ; C290.2 v1(124.84,28.96) ; R261.2 v1(145.16,46.1) ; Y5.4 154.42,61.76 C739.2 v1(154.42,63.62) ; C129.2 v1(69.98,19.18) ; R545.1 v1(237.87,73.79) ; C888.2 v1(75.31,149.73) ; C126.2 62.62,24.12 v1(62.23,24.51) ; J19.27 v1(178.31,199.88) ; R782.1 v1(200.66,132.72) ; C605.2 v1(76.71,213.47) ; C501.1 v1(225.17,63.75) ; C58.2 v1(151.76,58.17) ; C286.2 v1(127.5,71.87) ; Y5.2 v1(157.31,59.6) ; U54.2 v1(193.93,30.23) ; v1(155.45,164.59) 155.45,164.96 C2.2 154.43,164.96 v1(154.43,164.59) ; 267.44,133.73 v1(266.06,133.73) 265.47,133.13 U15.4 v1(264.54,134.49) ; C728.2 v1(90.29,106.43) ; R838.2 v1(228.6,135.13) ; C79.2 v1(230,106.43) ; C329.2 v1(133.48,39.62) ; R835.2 v1(228.6,136.4) ; v1(180.34,61.59) 180.38,61.64 Y3.2 ; C573.2 v1(168.27,54.99) ; R469.1 v1(120.9,60.58) ; C734.2 237.49,132.07 v1(237.49,131.95) ; C278.2 v1(124.84,35.31) ; R263.2 v1(129.93,55) ; C738.2 v1(155.58,63.62) ; R656.1 v1(43.56,100.84) ; R400.2 v1(265.94,93.6) ; C1015.2 v1(213.61,125.22) ; Q15.2 v1(38.22,105.16) ; C37.2 v1(254.89,141.99) ; C564.1 v1(164.29,75.36) ; R278.2 v1(182.75,68.2) ; R543.1 v1(154.94,73.03) ; v1(178.69,164.21) 178.68,164.2 C4.2 ; R519.2 v1(244.6,135.89) ; C743.2 v1(150.11,62.11) ; R227.1 v1(152.91,53.85) ; C981.1 v1(19.94,95.76) ; Q21.2 v1(38.09,95.51) ; R687.1 v1(47.88,121.16) ; C897.2 v1(13.34,59.31) ; C9.2 v1(166.88,152.02) ; C749.2 v1(231.26,75.95) ; U61.6 v1(84.07,40.51) ; C275.2 v1(136.91,59.82) ; C614.2 v1(76.71,191.9) ; v1(175.89,42.16) 176.12,42.39 J16.17 ; U51.2 v1(143.38,42.29) ; C957.1 v1(19.94,106.55) ; C649.2 v1(98.04,59.56) ; C287.2 v1(126.24,59.82) ; C361.2 v1(183.13,52.2) ; C13.2 v1(184.91,152.02) ; Q30.2 v1(11.3,66.67) ; C17.2 v1(148.59,166.5) ; J16.11 v1(180.92,42.11) ; C289.2 v1(124.84,32.77) ; C703.2 v1(49.41,114.8) ; R518.1 v1(89.29,109.97) ; C279.2 v1(124.84,37.85) ; C12.2 v1(157.6,164.2)
  TOP w1.016: 12.3,97.45 J37.5 ; J37.5 14.28,95.47 ; J37.5 12.3,95.47 ; J37.5 14.28,97.45 ; 6.8,93.25 J37.16 ; J37.16 6.8,91.27 ; J37.16 8.78,93.25 ; J37.16 8.78,91.27 ; 12.3,105.85 J37.3 ; J37.3 12.3,103.87 ; J37.3 14.28,103.87 ; J37.3 14.28,105.85 ; 6.8,95.47 J37.15 ; J37.15 8.78,95.47 ; J37.15 8.78,97.45 ; J37.15 6.8,97.45 ; 6.8,103.87 J37.13 ; J37.13 6.8,105.85 ; J37.13 8.78,105.85 ; J37.13 8.78,103.87 ; J37.7 14.28,89.05 ; J37.7 12.3,87.07 ; J37.7 12.3,89.05 ; J37.7 14.28,87.07 ; 6.8,87.07 J37.17 ; J37.17 8.78,87.07 ; J37.17 8.78,89.05 ; J37.17 6.8,89.05 ; J35.2 63.03,125.39 C195.2
  L2GND w0.508: 219.39,158.08 J1.113 ; J1.113 220.45,157.02 ; J1.113 219.39,157.02 ; J1.113 220.45,158.08 ; 118.39,159.98 J1.136 ; J1.136 119.45,158.92 ; J1.136 119.45,159.98 ; J1.136 118.39,158.92 ; 136.39,159.98 J1.154 ; J1.154 136.39,158.92 ; J1.154 137.45,158.92 ; J1.154 137.45,159.98 ; J1.133 116.45,161.88 ; J1.133 115.39,161.88 ; J1.133 115.39,160.82 ; J1.133 116.45,160.82 ; 206.39,159.98 J1.220 ; J1.220 207.45,159.98 ; J1.220 206.39,158.92 ; J1.220 207.45,158.92 ; J30.2 91.89,151.27 ; J30.2 91.89,152.68 ; J30.2 90.48,152.68 ; J30.2 90.48,151.27 ; J1.157 140.45,160.82 ; J1.157 140.45,161.88 ; J1.157 139.39,161.88 ; J1.157 139.39,160.82 ; 275.48,109.64 J18.B26 ; J18.B26 275.48,108.51 ; J18.B26 276.61,109.64 ; J18.B26 276.61,108.51 ; 106.39,158.92 J1.124 ; J1.124 107.45,159.98 ; J1.124 106.39,159.98 ; J1.124 107.45,158.92 ; 6.02,122.23 J26.10 ; J26.10 6.02,123.64 ; J26.10 7.44,122.23 ; J26.10 7.44,123.64 ; 254.18,103.13 J21.8 ; J21.8 254.18,104.8 ; J21.8 255.85,104.8 ; J21.8 255.85,103.13 ; 275.48,85.64 J18.B4 ; J18.B4 275.48,84.51 ; J18.B4 276.61,85.64 ; J18.B4 276.61,84.51 ; J21.7 254.08,114.61 ; J21.7 252.95,113.48 ; J21.7 252.95,114.61 ; J21.7 254.08,113.48 ; SW4.4 20.83,6.65 ; SW4.4 19.2,6.65 ; SW4.4 20.83,8.28 ; SW4.4 19.2,8.28 ; 13.56,4.26 SW4.1 ; SW4.1 14.97,5.67 ; SW4.1 13.56,5.67 ; SW4.1 14.97,4.26 ; J45.3 103.96,246.2 ; J45.3 103.96,244.78 ; J45.3 102.54,246.2 ; J45.3 102.54,244.78 ; 222.39,156.18 J1.116 ; J1.116 222.39,155.12 ; J1.116 223.45,155.12 ; J1.116 223.45,156.18 ; J21.9 256.85,115.96 ; J21.9 256.85,117.63 ; J21.9 255.18,117.63 ; J21.9 255.18,115.96 ; 139.71,25.5 J13.A5 ; J13.A5 141.05,24.15 ; J13.A5 139.71,24.15 ; J13.A5 141.05,25.5 ; 127.39,160.82 J1.145 ; J1.145 128.45,161.88 ; J1.145 128.45,160.82 ; J1.145 127.39,161.88 ; 189.39,157.02 J1.83 ; J1.83 190.45,157.02 ; J1.83 189.39,158.08 ; J1.83 190.45,158.08 ; 273.48,96.64 J18.B13 ; J18.B13 273.48,95.51 ; J18.B13 274.61,95.51 ; J18.B13 274.61,96.64 ; 119.39,158.08 J1.17 ; J1.17 120.45,157.02 ; J1.17 119.39,157.02 ; J1.17 120.45,158.08 ; J1.205 192.45,160.82 ; J1.205 192.45,161.88 ; J1.205 191.39,160.82 ; J1.205 191.39,161.88 ; J33.1 39.19,246.2 ; J33.1 39.19,244.78 ; J33.1 37.77,244.78 ; J33.1 37.77,246.2 ; J13.A4 142.32,22.96 ; J13.A4 140.98,22.96 ; J13.A4 140.98,21.61 ; J13.A4 142.32,21.61 ; 116.39,156.18 J1.14 ; J1.14 116.39,155.12 ; J1.14 117.45,156.18 ; J1.14 117.45,155.12 ; J18.B7 274.61,88.64 ; J18.B7 274.61,87.51 ; J18.B7 273.48,88.64 ; J18.B7 273.48,87.51 ; J18.B25 274.61,107.51 ; J18.B25 274.61,108.64 ; J18.B25 273.48,107.51 ; J18.B25 273.48,108.64 ; C691.1 53.17,64.27 ; C691.1 51.42,66.03 ; C691.1 51.42,64.27 ; C691.1 53.17,66.03 ; J1.142 125.45,159.98 ; J1.142 124.39,159.98 ; J1.142 124.39,158.92 ; J1.142 125.45,158.92 ; 133.39,161.88 J1.151 ; J1.151 134.45,160.82 ; J1.151 134.45,161.88 ; J1.151 133.39,160.82 ; 107.62,246.2 J45.1 ; J45.1 107.62,244.78 ; J45.1 109.04,244.78 ; J45.1 109.04,246.2 ; J18.B21 274.61,103.51 ; J18.B21 273.48,104.64 ; J18.B21 274.61,104.64 ; J18.B21 273.48,103.51 ; 148.39,159.98 J1.166 ; J1.166 148.39,158.92 ; J1.166 149.45,158.92 ; J1.166 149.45,159.98 ; 268.98,100.51 J18.A18 ; J18.A18 270.11,101.64 ; J18.A18 268.98,101.64 ; J18.A18 270.11,100.51 ; J1.29 132.45,157.02 ; J1.29 132.45,158.08 ; J1.29 131.39,158.08 ; J1.29 131.39,157.02 ; 247.32,246.2 J46.1 ; J46.1 248.74,246.2 ; J46.1 247.32,244.78 ; J46.1 248.74,244.78 ; 103.39,160.82 J1.121 ; J1.121 104.45,161.88 ; J1.121 103.39,161.88 ; J1.121 104.45,160.82 ; J44.3 173.81,246.2 ; J44.3 173.81,244.78 ; J44.3 172.39,244.78 ; J44.3 172.39,246.2 ; J1.92 199.45,156.18 ; J1.92 199.45,155.12 ; J1.92 198.39,155.12 ; J1.92 198.39,156.18 ; 275.48,98.51 J18.B16 ; J18.B16 276.61,99.64 ; J18.B16 276.61,98.51 ; J18.B16 275.48,99.64 ; J18.B29 274.61,112.64 ; J18.B29 273.48,112.64 ; J18.B29 274.61,111.51 ; J18.B29 273.48,111.51 ; 130.39,158.92 J1.148 ; J1.148 131.45,158.92 ; J1.148 131.45,159.98 ; J1.148 130.39,159.98 ; 109.39,160.82 J1.127 ; J1.127 109.39,161.88 ; J1.127 110.45,161.88 ; J1.127 110.45,160.82 ; 107.39,158.08 J1.5 ; J1.5 108.45,157.02 ; J1.5 107.39,157.02 ; J1.5 108.45,158.08 ; J13.B5 142.32,14.99 ; J13.B5 140.98,14.99 ; J13.B5 142.32,16.34 ; J13.B5 140.98,16.34 ; 140.39,156.18 J1.38 ; J1.38 141.45,155.12 ; J1.38 141.45,156.18 ; J1.38 140.39,155.12 ; 268.98,85.64 J18.A4 ; J18.A4 270.11,85.64 ; J18.A4 268.98,84.51 ; J18.A4 270.11,84.51 ; 9.7,8.28 SW5.4 ; SW5.4 9.7,6.65 ; SW5.4 11.33,6.65 ; SW5.4 11.33,8.28 ; 270.98,105.51 J18.A23 ; J18.A23 270.98,106.64 ; J18.A23 272.11,105.51 ; J18.A23 272.11,106.64 ; J1.107 214.45,158.08 ; J1.107 213.39,158.08 ; J1.107 213.39,157.02 ; J1.107 214.45,157.02 ; 32.69,244.78 J33.3 ; J33.3 34.11,244.78 ; J33.3 34.11,246.2 ; J33.3 32.69,246.2 ; J1.208 195.45,159.98 ; J1.208 194.39,158.92 ; J1.208 194.39,159.98 ; J1.208 195.45,158.92 ; J1.26 129.45,155.12 ; J1.26 129.45,156.18 ; J1.26 128.39,155.12 ; J1.26 128.39,156.18 ; J44.1 178.89,244.78 ; J44.1 177.47,246.2 ; J44.1 177.47,244.78 ; J44.1 178.89,246.2 ; J18.A27 272.11,109.51 ; J18.A27 270.98,110.64 ; J18.A27 272.11,110.64 ; J18.A27 270.98,109.51 ; 121.39,161.88 J1.139 ; J1.139 121.39,160.82 ; J1.139 122.45,161.88 ; J1.139 122.45,160.82 ; 195.39,158.08 J1.89 ; J1.89 196.45,157.02 ; J1.89 195.39,157.02 ; J1.89 196.45,158.08 ; J18.A15 272.11,97.51 ; J18.A15 272.11,98.64 ; J18.A15 270.98,98.64 ; J18.A15 270.98,97.51 ; J1.202 189.45,158.92 ; J1.202 188.39,159.98 ; J1.202 189.45,159.98 ; J1.202 188.39,158.92 ; J21.1 254.08,105.86 ; J21.1 254.08,106.99 ; J21.1 252.95,105.86 ; J21.1 252.95,106.99 ; 252.95,109.67 J21.4 ; J21.4 254.08,110.8 ; J21.4 254.08,109.67 ; J21.4 252.95,110.8 ; 192.39,155.12 J1.86 ; J1.86 193.45,155.12 ; J1.86 193.45,156.18 ; J1.86 192.39,156.18 ; 112.39,158.92 J1.130 ; J1.130 113.45,159.98 ; J1.130 112.39,159.98 ; J1.130 113.45,158.92 ; 185.39,161.88 J1.199 ; J1.199 185.39,160.82 ; J1.199 186.45,161.88 ; J1.199 186.45,160.82 ; J46.3 243.66,246.2 ; J46.3 242.24,244.78 ; J46.3 243.66,244.78 ; J46.3 242.24,246.2 ; J1.2 105.45,156.18 ; J1.2 105.45,155.12 ; J1.2 104.39,155.12 ; J1.2 104.39,156.18 ; J1.104 211.45,156.18 ; J1.104 210.39,155.12 ; J1.104 210.39,156.18 ; J1.104 211.45,155.12 ; J1.101 208.45,157.02 ; J1.101 207.39,157.02 ; J1.101 207.39,158.08 ; J1.101 208.45,158.08 ; C692.1 53.17,74.92 ; C692.1 53.17,73.16 ; C692.1 51.42,73.16 ; C692.1 51.42,74.92 ; 218.39,158.92 J1.232 ; J1.232 218.39,159.98 ; J1.232 219.45,158.92 ; J1.232 219.45,159.98 ; J1.35 138.45,157.02 ; J1.35 137.39,157.02 ; J1.35 138.45,158.08 ; J1.35 137.39,158.08 ; 73.97,92.15 J28.2 ; J28.2 73.97,90.73 ; J28.2 75.38,92.15 ; J28.2 75.38,90.73 ; J1.237 224.45,161.88 ; J1.237 224.45,160.82 ; J1.237 223.39,161.88 ; J1.237 223.39,160.82 ; J13.B4 141.05,18.88 ; J13.B4 139.71,17.53 ; J13.B4 139.71,18.88 ; J13.B4 141.05,17.53 ; 149.39,158.08 J1.47 ; J1.47 150.45,158.08 ; J1.47 150.45,157.02 ; J1.47 149.39,157.02 ; J1.163 146.45,161.88 ; J1.163 145.39,160.82 ; J1.163 145.39,161.88 ; J1.163 146.45,160.82 ; J39.2 225.75,141.02 ; J39.2 224.34,142.44 ; J39.2 224.34,141.02 ; J39.2 225.75,142.44 ; J1.23 126.45,157.02 ; J1.23 125.39,157.02 ; J1.23 126.45,158.08 ; J1.23 125.39,158.08 ; 113.39,158.08 J1.11 ; J1.11 114.45,157.02 ; J1.11 113.39,157.02 ; J1.11 114.45,158.08 ; J1.8 111.45,156.18 ; J1.8 110.39,155.12 ; J1.8 110.39,156.18 ; J1.8 111.45,155.12 ; 268.98,95.64 J18.A12 ; J18.A12 270.11,94.51 ; J18.A12 268.98,94.51 ; J18.A12 270.11,95.64 ; J1.98 205.45,156.18 ; J1.98 205.45,155.12 ; J1.98 204.39,155.12 ; J1.98 204.39,156.18 ; 201.39,157.02 J1.95 ; J1.95 202.45,158.08 ; J1.95 201.39,158.08 ; J1.95 202.45,157.02 ; J18.B32 276.61,114.51 ; J18.B32 275.48,114.51 ; J18.B32 276.61,115.64 ; J18.B32 275.48,115.64 ; 275.48,101.64 J18.B18 ; J18.B18 276.61,101.64 ; J18.B18 276.61,100.51 ; J18.B18 275.48,100.51 ; 16.18,123.64 J26.2 ; J26.2 17.6,123.64 ; J26.2 16.18,122.23 ; J26.2 17.6,122.23 ; J1.44 147.45,155.12 ; J1.44 147.45,156.18 ; J1.44 146.39,155.12 ; J1.44 146.39,156.18 ; 142.39,159.98 J1.160 ; J1.160 142.39,158.92 ; J1.160 143.45,159.98 ; J1.160 143.45,158.92 ; 212.39,158.92 J1.226 ; J1.226 213.45,158.92 ; J1.226 212.39,159.98 ; J1.226 213.45,159.98 ; J1.229 216.45,160.82 ; J1.229 216.45,161.88 ; J1.229 215.39,161.88 ; J1.229 215.39,160.82 ; C687.2 69,39.83 ; C687.2 67.65,39.83 ; C687.2 67.65,38.48 ; C687.2 69,38.48 ; 134.39,155.12 J1.32 ; J1.32 135.45,156.18 ; J1.32 134.39,156.18 ; J1.32 135.45,155.12 ; J1.214 201.45,158.92 ; J1.214 200.39,158.92 ; J1.214 201.45,159.98 ; J1.214 200.39,159.98 ; SW5.1 5.47,4.26 ; SW5.1 5.47,5.67 ; SW5.1 4.06,4.26 ; SW5.1 4.06,5.67 ; J1.41 144.45,157.02 ; J1.41 143.39,157.02 ; J1.41 144.45,158.08 ; J1.41 143.39,158.08 ; J1.20 123.45,156.18 ; J1.20 123.45,155.12 ; J1.20 122.39,156.18 ; J1.20 122.39,155.12 ; J1.80 187.45,156.18 ; J1.80 186.39,155.12 ; J1.80 186.39,156.18 ; J1.80 187.45,155.12 ; 268.98,111.64 J18.A28 ; J18.A28 270.11,111.64 ; J18.A28 268.98,110.51 ; J18.A28 270.11,110.51 ; 197.39,161.88 J1.211 ; J1.211 198.45,161.88 ; J1.211 198.45,160.82 ; J1.211 197.39,160.82 ; J1.235 222.45,160.82 ; J1.235 222.45,161.88 ; J1.235 221.39,160.82 ; J1.235 221.39,161.88 ; 63.3,127.07 J35.2 ; J35.2 64.72,127.07 ; J35.2 63.3,125.66 ; J35.2 64.72,125.66 ; 81.97,82.73 J27.2 ; J27.2 83.38,82.73 ; J27.2 83.38,84.15 ; J27.2 81.97,84.15 ; 225.39,157.02 J1.119 ; J1.119 226.45,158.08 ; J1.119 226.45,157.02 ; J1.119 225.39,158.08 ; 268.98,107.64 J18.A24 ; J18.A24 270.11,107.64 ; J18.A24 270.11,106.51 ; J18.A24 268.98,106.51 ; 270.82,82.8 J18.A1 ; J18.A1 272.27,82.8 ; J18.A1 272.27,81.35 ; J18.A1 270.82,81.35 ; J1.239 226.45,161.88 ; J1.239 225.39,160.82 ; J1.239 226.45,160.82 ; J1.239 225.39,161.88 ; SW4.3 13.83,8.28 ; SW4.3 12.2,8.28 ; SW4.3 12.2,6.65 ; SW4.3 13.83,6.65 ; 62.36,151.51 63.06,150.8 ; 62.36,151.51 63.06,152.22 ; 62.36,151.51 61.65,152.22 ; 62.36,151.51 61.65,150.8 ; J1.223 210.45,160.82 ; J1.223 210.45,161.88 ; J1.223 209.39,160.82 ; J1.223 209.39,161.88 ; 275.48,104.51 J18.B22 ; J18.B22 276.61,105.64 ; J18.B22 275.48,105.64 ; J18.B22 276.61,104.51 ; 268.98,103.64 J18.A20 ; J18.A20 270.11,103.64 ; J18.A20 268.98,102.51 ; J18.A20 270.11,102.51 ; 216.39,155.12 J1.110 ; J1.110 216.39,156.18 ; J1.110 217.45,156.18 ; J1.110 217.45,155.12 ; 2.7,8.28 SW5.3 ; SW5.3 4.33,8.28 ; SW5.3 4.33,6.65 ; SW5.3 2.7,6.65 ; 270.98,114.64 J18.A31 ; J18.A31 270.98,113.51 ; J18.A31 272.11,113.51 ; J18.A31 272.11,114.64 ; J1.217 204.45,161.88 ; J1.217 203.39,161.88 ; J1.217 203.39,160.82 ; J1.217 204.45,160.82
  L2GND w1.016: J37.15 8.64,95.61 ; J37.15 6.94,95.61 ; J37.15 8.64,97.31 ; J37.15 6.94,97.31 ; 6.94,93.11 J37.16 ; J37.16 8.64,91.41 ; J37.16 6.94,91.41 ; J37.16 8.64,93.11 ; 6.94,87.21 J37.17 ; J37.17 8.64,87.21 ; J37.17 6.94,88.91 ; J37.17 8.64,88.91 ; 12.44,97.31 J37.5 ; J37.5 12.44,95.61 ; J37.5 14.14,97.31 ; J37.5 14.14,95.61 ; J37.7 14.14,87.21 ; J37.7 12.44,87.21 ; J37.7 12.44,88.91 ; J37.7 14.14,88.91 ; J37.3 14.14,104.01 ; J37.3 12.44,105.71 ; J37.3 12.44,104.01 ; J37.3 14.14,105.71 ; 6.94,105.71 J37.13 ; J37.13 8.64,104.01 ; J37.13 8.64,105.71 ; J37.13 6.94,104.01
  L3SIG w0.508: J33.3 34.11,244.78 ; J33.3 34.11,246.2 ; J33.3 32.69,244.78 ; J33.3 32.69,246.2 ; 177.47,246.2 J44.1 ; J44.1 178.89,246.2 ; J44.1 178.89,244.78 ; J44.1 177.47,244.78 ; J45.3 103.96,246.2 ; J45.3 102.54,244.78 ; J45.3 102.54,246.2 ; J45.3 103.96,244.78 ; 242.24,246.2 J46.3 ; J46.3 242.24,244.78 ; J46.3 243.66,244.78 ; J46.3 243.66,246.2 ; v1(147.19,17.78) 149.48,17.78 151,16.26 151,14.48 153.42,12.06 153.42,10.92 154.56,9.78 164.76,9.78 J14.B12 ; 247.32,246.2 J46.1 ; J46.1 248.74,246.2 ; J46.1 248.74,244.78 ; J46.1 247.32,244.78 ; J44.3 173.81,244.78 ; J44.3 172.39,246.2 ; J44.3 173.81,246.2 ; J44.3 172.39,244.78 ; 107.62,244.78 J45.1 ; J45.1 109.04,246.2 ; J45.1 109.04,244.78 ; J45.1 107.62,246.2 ; 37.77,244.78 J33.1 ; J33.1 39.19,246.2 ; J33.1 39.19,244.78 ; J33.1 37.77,246.2
  L4PWR w0.508: 140.98,22.96 J13.A4 ; J13.A4 142.32,22.96 ; J13.A4 140.98,21.61 ; J13.A4 142.32,21.61 ; SW5.1 5.47,4.26 ; SW5.1 4.06,5.67 ; SW5.1 4.06,4.26 ; SW5.1 5.47,5.67 ; J26.10 7.44,123.64 ; J26.10 6.02,122.23 ; J26.10 7.44,122.23 ; J26.10 6.02,123.64 ; 177.47,244.78 J44.1 ; J44.1 177.47,246.2 ; J44.1 178.89,246.2 ; J44.1 178.89,244.78 ; 140.98,16.34 J13.B5 ; J13.B5 142.32,14.99 ; J13.B5 140.98,14.99 ; J13.B5 142.32,16.34 ; 12.2,8.28 SW4.3 ; SW4.3 13.83,8.28 ; SW4.3 12.2,6.65 ; SW4.3 13.83,6.65 ; SW5.3 4.33,6.65 ; SW5.3 2.7,8.28 ; SW5.3 4.33,8.28 ; SW5.3 2.7,6.65 ; J33.1 39.19,244.78 ; J33.1 37.77,244.78 ; J33.1 37.77,246.2 ; J33.1 39.19,246.2 ; SW5.4 11.33,8.28 ; SW5.4 9.7,6.65 ; SW5.4 9.7,8.28 ; SW5.4 11.33,6.65 ; 141.05,24.15 J13.A5 139.71,24.15 ; 172.39,244.78 J44.3 ; J44.3 173.81,244.78 ; J44.3 173.81,246.2 ; J44.3 172.39,246.2 ; SW4.4 20.83,6.65 ; SW4.4 19.2,6.65 ; SW4.4 20.83,8.28 ; SW4.4 19.2,8.28 ; J45.1 109.04,246.2 ; J45.1 107.62,244.78 ; J45.1 109.04,244.78 ; J45.1 107.62,246.2 ; J46.3 243.66,246.2 ; J46.3 243.66,244.78 ; J46.3 242.24,244.78 ; J46.3 242.24,246.2 ; SW4.1 14.97,4.26 ; SW4.1 13.56,4.26 ; SW4.1 14.97,5.67 ; SW4.1 13.56,5.67 ; 32.69,244.78 J33.3 ; J33.3 32.69,246.2 ; J33.3 34.11,244.78 ; J33.3 34.11,246.2 ; 102.54,246.2 J45.3 ; J45.3 103.96,244.78 ; J45.3 102.54,244.78 ; J45.3 103.96,246.2 ; J46.1 248.74,246.2 ; J46.1 247.32,246.2 ; J46.1 247.32,244.78 ; J46.1 248.74,244.78 ; J13.B4 141.05,17.53 ; J13.B4 139.71,17.53 ; J13.B4 141.05,18.88 ; J13.B4 139.71,18.88
  L4PWR w1.016: 12.19,87.59 J37.7 12.16,88.06 ; J37.15 8.64,97.31 ; J37.15 6.94,97.31 ; J37.15 8.64,95.61 ; J37.15 6.94,95.61 ; 6.94,105.71 J37.13 ; J37.13 8.64,104.01 ; J37.13 8.64,105.71 ; J37.13 6.94,104.01 ; 6.94,91.41 J37.16 ; J37.16 8.64,93.11 ; J37.16 6.94,93.11 ; J37.16 8.64,91.41 ; J37.17 8.64,88.91 ; J37.17 8.64,87.21 ; J37.17 6.94,87.21 ; J37.17 6.94,88.91 ; 12.16,104.86 J37.3 12.19,104.39 ; 12.19,95.99 J37.5 12.16,96.46
  L5PWR w0.508: 16.18,122.23 J26.2 ; J26.2 17.6,123.64 ; J26.2 17.6,122.23 ; J26.2 16.18,123.64 ; J18.A18 270.11,101.64 ; J18.A18 270.11,100.51 ; J18.A18 268.98,100.51 ; J18.A18 268.98,101.64 ; 270.82,82.8 J18.A1 ; J18.A1 270.82,81.35 ; J18.A1 272.27,82.8 ; J18.A1 272.27,81.35 ; 2.7,6.65 SW5.3 ; SW5.3 2.7,8.28 ; SW5.3 4.33,8.28 ; SW5.3 4.33,6.65 ; J46.1 248.74,246.2 ; J46.1 247.32,246.2 ; J46.1 247.32,244.78 ; J46.1 248.74,244.78 ; J18.A12 270.11,95.64 ; J18.A12 268.98,94.51 ; J18.A12 268.98,95.64 ; J18.A12 270.11,94.51 ; 4.06,5.67 SW5.1 ; SW5.1 5.47,5.67 ; SW5.1 4.06,4.26 ; SW5.1 5.47,4.26 ; J13.A5 141.05,25.5 ; J13.A5 139.71,24.15 ; J13.A5 141.05,24.15 ; J13.A5 139.71,25.5 ; 12.2,8.28 SW4.3 ; SW4.3 12.2,6.65 ; SW4.3 13.83,6.65 ; SW4.3 13.83,8.28 ; 139.71,18.88 J13.B4 ; J13.B4 139.71,17.53 ; J13.B4 141.05,17.53 ; J13.B4 141.05,18.88 ; 270.98,105.51 J18.A23 ; J18.A23 272.11,105.51 ; J18.A23 272.11,106.64 ; J18.A23 270.98,106.64 ; J18.A28 270.11,111.64 ; J18.A28 268.98,110.51 ; J18.A28 268.98,111.64 ; J18.A28 270.11,110.51 ; J45.3 103.96,246.2 ; J45.3 102.54,246.2 ; J45.3 102.54,244.78 ; J45.3 103.96,244.78 ; 140.98,16.34 J13.B5 ; J13.B5 142.32,16.34 ; J13.B5 140.98,14.99 ; J13.B5 142.32,14.99 ; J18.B25 274.61,108.64 ; J18.B25 273.48,107.51 ; J18.B25 273.48,108.64 ; J18.B25 274.61,107.51 ; 275.48,115.64 J18.B32 ; J18.B32 276.61,115.64 ; J18.B32 275.48,114.51 ; J18.B32 276.61,114.51 ; J21.9 256.85,115.96 ; J21.9 255.18,115.96 ; J21.9 255.18,117.63 ; J21.9 256.85,117.63 ; J21.8 255.85,103.13 ; J21.8 255.85,104.8 ; J21.8 254.18,103.13 ; J21.8 254.18,104.8 ; J44.3 173.81,246.2 ; J44.3 172.39,246.2 ; J44.3 173.81,244.78 ; J44.3 172.39,244.78 ; SW4.4 20.83,6.65 ; SW4.4 19.2,8.28 ; SW4.4 19.2,6.65 ; SW4.4 20.83,8.28 ; SW5.4 11.33,6.65 ; SW5.4 9.7,6.65 ; SW5.4 9.7,8.28 ; SW5.4 11.33,8.28 ; 252.95,109.67 J21.4 ; J21.4 254.08,110.8 ; J21.4 254.08,109.67 ; J21.4 252.95,110.8 ; J26.10 7.44,122.23 ; J26.10 6.02,123.64 ; J26.10 7.44,123.64 ; J26.10 6.02,122.23 ; C687.2 69,38.48 ; C687.2 67.65,39.83 ; C687.2 67.65,38.48 ; 252.95,114.61 J21.7 ; J21.7 254.08,113.48 ; J21.7 252.95,113.48 ; J21.7 254.08,114.61 ; 140.98,22.96 J13.A4 ; J13.A4 140.98,21.61 ; J13.A4 142.32,22.96 ; J13.A4 142.32,21.61 ; 268.98,102.51 J18.A20 ; J18.A20 270.11,103.64 ; J18.A20 268.98,103.64 ; J18.A20 270.11,102.51 ; J18.B7 274.61,88.64 ; J18.B7 273.48,87.51 ; J18.B7 273.48,88.64 ; J18.B7 274.61,87.51 ; 275.48,85.64 J18.B4 ; J18.B4 276.61,84.51 ; J18.B4 276.61,85.64 ; J18.B4 275.48,84.51 ; J18.B22 276.61,104.51 ; J18.B22 275.48,105.64 ; J18.B22 276.61,105.64 ; J18.B22 275.48,104.51 ; 273.48,103.51 J18.B21 ; J18.B21 274.61,104.64 ; J18.B21 273.48,104.64 ; J18.B21 274.61,103.51 ; 252.95,106.99 J21.1 ; J21.1 254.08,105.86 ; J21.1 252.95,105.86 ; J21.1 254.08,106.99 ; 275.48,98.51 J18.B16 ; J18.B16 276.61,98.51 ; J18.B16 275.48,99.64 ; J18.B16 276.61,99.64 ; 37.77,244.78 J33.1 ; J33.1 39.19,244.78 ; J33.1 37.77,246.2 ; J33.1 39.19,246.2 ; 51.42,64.27 C691.1 53.17,64.27 ; 107.62,244.78 J45.1 ; J45.1 109.04,246.2 ; J45.1 109.04,244.78 ; J45.1 107.62,246.2 ; 270.98,109.51 J18.A27 ; J18.A27 272.11,110.64 ; J18.A27 270.98,110.64 ; J18.A27 272.11,109.51 ; J18.B18 276.61,100.51 ; J18.B18 275.48,100.51 ; J18.B18 275.48,101.64 ; J18.B18 276.61,101.64 ; 275.48,109.64 J18.B26 ; J18.B26 275.48,108.51 ; J18.B26 276.61,109.64 ; J18.B26 276.61,108.51 ; 13.56,5.67 SW4.1 ; SW4.1 14.97,5.67 ; SW4.1 14.97,4.26 ; SW4.1 13.56,4.26 ; 273.48,111.51 J18.B29 ; J18.B29 273.48,112.64 ; J18.B29 274.61,111.51 ; J18.B29 274.61,112.64 ; 32.69,244.78 J33.3 ; J33.3 34.11,244.78 ; J33.3 32.69,246.2 ; J33.3 34.11,246.2 ; J18.A4 270.11,85.64 ; J18.A4 270.11,84.51 ; J18.A4 268.98,84.51 ; J18.A4 268.98,85.64 ; 270.98,113.51 J18.A31 ; J18.A31 272.11,113.51 ; J18.A31 270.98,114.64 ; J18.A31 272.11,114.64 ; 242.24,246.2 J46.3 ; J46.3 242.24,244.78 ; J46.3 243.66,246.2 ; J46.3 243.66,244.78 ; 268.98,107.64 J18.A24 ; J18.A24 270.11,106.51 ; J18.A24 270.11,107.64 ; J18.A24 268.98,106.51 ; J18.B13 274.61,95.51 ; J18.B13 274.61,96.64 ; J18.B13 273.48,95.51 ; J18.B13 273.48,96.64 ; J44.1 178.89,246.2 ; J44.1 177.47,246.2 ; J44.1 178.89,244.78 ; J44.1 177.47,244.78 ; J18.A15 272.11,98.64 ; J18.A15 272.11,97.51 ; J18.A15 270.98,98.64 ; J18.A15 270.98,97.51
  L6SIG w0.508: J46.1 248.74,246.2 ; J46.1 247.32,246.2 ; J46.1 247.32,244.78 ; J46.1 248.74,244.78 ; 177.47,246.2 J44.1 ; J44.1 178.89,246.2 ; J44.1 177.47,244.78 ; J44.1 178.89,244.78 ; J33.1 39.19,246.2 ; J33.1 37.77,246.2 ; J33.1 39.19,244.78 ; J33.1 37.77,244.78 ; 107.62,246.2 J45.1 ; J45.1 107.62,244.78 ; J45.1 109.04,244.78 ; J45.1 109.04,246.2 ; J14.A10 153.92,26.2 153.92,29.59 154.3,29.97 154.3,35.56 v1(153.54,36.32) ; 102.54,246.2 J45.3 ; J45.3 102.54,244.78 ; J45.3 103.96,246.2 ; J45.3 103.96,244.78 ; 172.39,244.78 J44.3 ; J44.3 173.81,246.2 ; J44.3 172.39,246.2 ; J44.3 173.81,244.78 ; 32.69,246.2 J33.3 ; J33.3 32.69,244.78 ; J33.3 34.11,246.2 ; J33.3 34.11,244.78 ; J46.3 243.66,246.2 ; J46.3 242.24,244.78 ; J46.3 243.66,244.78 ; J46.3 242.24,246.2
  L7GND w0.508: J1.104 211.45,155.12 ; J1.104 210.39,155.12 ; J1.104 211.45,156.18 ; J1.104 210.39,156.18 ; 252.95,113.48 J21.7 ; J21.7 254.08,113.48 ; J21.7 252.95,114.61 ; J21.7 254.08,114.61 ; C691.1 53.17,64.27 ; C691.1 53.17,66.03 ; C691.1 51.42,64.27 ; C691.1 51.42,66.03 ; 252.95,105.86 J21.1 ; J21.1 254.08,105.86 ; J21.1 252.95,106.99 ; J21.1 254.08,106.99 ; J1.211 198.45,160.82 ; J1.211 197.39,160.82 ; J1.211 198.45,161.88 ; J1.211 197.39,161.88 ; 172.39,244.78 J44.3 ; J44.3 173.81,246.2 ; J44.3 172.39,246.2 ; J44.3 173.81,244.78 ; 149.39,157.02 J1.47 ; J1.47 149.39,158.08 ; J1.47 150.45,157.02 ; J1.47 150.45,158.08 ; J21.9 256.85,115.96 ; J21.9 255.18,117.63 ; J21.9 256.85,117.63 ; J21.9 255.18,115.96 ; 118.39,158.92 J1.136 ; J1.136 118.39,159.98 ; J1.136 119.45,158.92 ; J1.136 119.45,159.98 ; 200.39,158.92 J1.214 ; J1.214 200.39,159.98 ; J1.214 201.45,159.98 ; J1.214 201.45,158.92 ; 32.69,244.78 J33.3 ; J33.3 32.69,246.2 ; J33.3 34.11,246.2 ; J33.3 34.11,244.78 ; J18.A31 272.11,114.64 ; J18.A31 270.98,114.64 ; J18.A31 272.11,113.51 ; J18.A31 270.98,113.51 ; 62.36,151.51 63.06,150.8 ; 62.36,151.51 63.06,152.22 ; 62.36,151.51 61.65,150.8 ; 62.36,151.51 61.65,152.22 ; 268.98,110.51 J18.A28 ; J18.A28 270.11,110.51 ; J18.A28 268.98,111.64 ; J18.A28 270.11,111.64 ; J1.124 107.45,158.92 ; J1.124 107.45,159.98 ; J1.124 106.39,158.92 ; J1.124 106.39,159.98 ; J26.2 17.6,123.64 ; J26.2 17.6,122.23 ; J26.2 16.18,122.23 ; J26.2 16.18,123.64 ; 216.39,156.18 J1.110 ; J1.110 217.45,155.12 ; J1.110 217.45,156.18 ; J1.110 216.39,155.12 ; J1.139 122.45,160.82 ; J1.139 122.45,161.88 ; J1.139 121.39,160.82 ; J1.139 121.39,161.88 ; 139.39,160.82 J1.157 ; J1.157 140.45,160.82 ; J1.157 139.39,161.88 ; J1.157 140.45,161.88 ; 136.39,158.92 J1.154 ; J1.154 137.45,158.92 ; J1.154 136.39,159.98 ; J1.154 137.45,159.98 ; 186.39,155.12 J1.80 ; J1.80 186.39,156.18 ; J1.80 187.45,155.12 ; J1.80 187.45,156.18 ; J1.232 219.45,159.98 ; J1.232 219.45,158.92 ; J1.232 218.39,158.92 ; J1.232 218.39,159.98 ; 268.98,85.64 J18.A4 ; J18.A4 268.98,84.51 ; J18.A4 270.11,84.51 ; J18.A4 270.11,85.64 ; J1.2 105.45,155.12 ; J1.2 104.39,155.12 ; J1.2 104.39,156.18 ; J1.2 105.45,156.18 ; 109.39,160.82 J1.127 ; J1.127 109.39,161.88 ; J1.127 110.45,161.88 ; J1.127 110.45,160.82 ; J1.116 223.45,155.12 ; J1.116 222.39,155.12 ; J1.116 222.39,156.18 ; J1.116 223.45,156.18 ; J1.148 131.45,159.98 ; J1.148 130.39,158.92 ; J1.148 131.45,158.92 ; J1.148 130.39,159.98 ; J1.235 222.45,160.82 ; J1.235 221.39,161.88 ; J1.235 221.39,160.82 ; J1.235 222.45,161.88 ; J18.A23 272.11,106.64 ; J18.A23 270.98,105.51 ; J18.A23 272.11,105.51 ; J18.A23 270.98,106.64 ; J1.101 208.45,157.02 ; J1.101 208.45,158.08 ; J1.101 207.39,157.02 ; J1.101 207.39,158.08 ; J1.163 146.45,161.88 ; J1.163 145.39,160.82 ; J1.163 146.45,160.82 ; J1.163 145.39,161.88 ; J1.86 193.45,155.12 ; J1.86 193.45,156.18 ; J1.86 192.39,156.18 ; J1.86 192.39,155.12 ; 209.39,161.88 J1.223 ; J1.223 210.45,160.82 ; J1.223 210.45,161.88 ; J1.223 209.39,160.82 ; J18.A15 272.11,97.51 ; J18.A15 272.11,98.64 ; J18.A15 270.98,98.64 ; J18.A15 270.98,97.51 ; J1.95 202.45,158.08 ; J1.95 201.39,158.08 ; J1.95 202.45,157.02 ; J1.95 201.39,157.02 ; J1.35 138.45,157.02 ; J1.35 137.39,157.02 ; J1.35 138.45,158.08 ; J1.35 137.39,158.08 ; 116.39,155.12 J1.14 ; J1.14 117.45,156.18 ; J1.14 116.39,156.18 ; J1.14 117.45,155.12 ; 206.39,159.98 J1.220 ; J1.220 207.45,159.98 ; J1.220 207.45,158.92 ; J1.220 206.39,158.92 ; 140.98,16.34 J13.B5 ; J13.B5 142.32,14.99 ; J13.B5 142.32,16.34 ; J13.B5 140.98,14.99 ; 102.54,246.2 J45.3 ; J45.3 102.54,244.78 ; J45.3 103.96,244.78 ; J45.3 103.96,246.2 ; J18.A12 270.11,95.64 ; J18.A12 270.11,94.51 ; J18.A12 268.98,94.51 ; J18.A12 268.98,95.64 ; 103.39,160.82 J1.121 ; J1.121 103.39,161.88 ; J1.121 104.45,160.82 ; J1.121 104.45,161.88 ; J1.130 113.45,158.92 ; J1.130 113.45,159.98 ; J1.130 112.39,159.98 ; J1.130 112.39,158.92 ; J1.133 116.45,160.82 ; J1.133 116.45,161.88 ; J1.133 115.39,160.82 ; J1.133 115.39,161.88 ; J1.199 186.45,161.88 ; J1.199 185.39,160.82 ; J1.199 185.39,161.88 ; J1.199 186.45,160.82 ; J46.1 248.74,244.78 ; J46.1 248.74,246.2 ; J46.1 247.32,244.78 ; J46.1 247.32,246.2 ; J1.23 126.45,157.02 ; J1.23 125.39,158.08 ; J1.23 125.39,157.02 ; J1.23 126.45,158.08 ; 19.2,8.28 SW4.4 ; SW4.4 20.83,6.65 ; SW4.4 19.2,6.65 ; SW4.4 20.83,8.28 ; 275.48,85.64 J18.B4 ; J18.B4 275.48,84.51 ; J18.B4 276.61,85.64 ; J18.B4 276.61,84.51 ; J18.A24 270.11,106.51 ; J18.A24 268.98,107.64 ; J18.A24 270.11,107.64 ; J18.A24 268.98,106.51 ; 242.24,244.78 J46.3 ; J46.3 242.24,246.2 ; J46.3 243.66,246.2 ; J46.3 243.66,244.78 ; J28.2 75.38,92.15 ; J28.2 73.97,92.15 ; J28.2 75.38,90.73 ; J28.2 73.97,90.73 ; J18.A20 270.11,103.64 ; J18.A20 270.11,102.51 ; J18.A20 268.98,102.51 ; J18.A20 268.98,103.64 ; J1.20 123.45,156.18 ; J1.20 123.45,155.12 ; J1.20 122.39,156.18 ; J1.20 122.39,155.12 ; J21.4 254.08,110.8 ; J21.4 252.95,110.8 ; J21.4 254.08,109.67 ; J21.4 252.95,109.67 ; J18.B7 274.61,87.51 ; J18.B7 273.48,87.51 ; J18.B7 273.48,88.64 ; J18.B7 274.61,88.64 ; J1.113 220.45,157.02 ; J1.113 219.39,158.08 ; J1.113 219.39,157.02 ; J1.113 220.45,158.08 ; 275.48,105.64 J18.B22 ; J18.B22 275.48,104.51 ; J18.B22 276.61,105.64 ; J18.B22 276.61,104.51 ; 188.39,158.92 J1.202 ; J1.202 189.45,158.92 ; J1.202 188.39,159.98 ; J1.202 189.45,159.98 ; J1.89 196.45,157.02 ; J1.89 195.39,157.02 ; J1.89 195.39,158.08 ; J1.89 196.45,158.08 ; J1.166 149.45,158.92 ; J1.166 149.45,159.98 ; J1.166 148.39,158.92 ; J1.166 148.39,159.98 ; J1.205 192.45,161.88 ; J1.205 191.39,160.82 ; J1.205 192.45,160.82 ; J1.205 191.39,161.88 ; 189.39,157.02 J1.83 ; J1.83 189.39,158.08 ; J1.83 190.45,157.02 ; J1.83 190.45,158.08 ; 273.48,107.51 J18.B25 ; J18.B25 274.61,107.51 ; J18.B25 273.48,108.64 ; J18.B25 274.61,108.64 ; J18.B26 276.61,108.51 ; J18.B26 275.48,108.51 ; J18.B26 276.61,109.64 ; J18.B26 275.48,109.64 ; 204.39,156.18 J1.98 ; J1.98 204.39,155.12 ; J1.98 205.45,156.18 ; J1.98 205.45,155.12 ; 270.82,81.35 J18.A1 ; J18.A1 272.27,81.35 ; J18.A1 272.27,82.8 ; J18.A1 270.82,82.8 ; 140.39,155.12 J1.38 ; J1.38 140.39,156.18 ; J1.38 141.45,155.12 ; J1.38 141.45,156.18 ; J18.B29 274.61,111.51 ; J18.B29 273.48,112.64 ; J18.B29 273.48,111.51 ; J18.B29 274.61,112.64 ; 9.7,8.28 SW5.4 ; SW5.4 11.33,8.28 ; SW5.4 11.33,6.65 ; SW5.4 9.7,6.65 ; 177.47,246.2 J44.1 ; J44.1 178.89,244.78 ; J44.1 177.47,244.78 ; J44.1 178.89,246.2 ; 194.39,159.98 J1.208 ; J1.208 194.39,158.92 ; J1.208 195.45,159.98 ; J1.208 195.45,158.92 ; 119.39,158.08 J1.17 ; J1.17 120.45,157.02 ; J1.17 120.45,158.08 ; J1.17 119.39,157.02 ; 124.39,159.98 J1.142 ; J1.142 125.45,158.92 ; J1.142 124.39,158.92 ; J1.142 125.45,159.98 ; J33.1 39.19,246.2 ; J33.1 37.77,246.2 ; J33.1 37.77,244.78 ; J33.1 39.19,244.78 ; 224.34,141.02 J39.2 ; J39.2 225.75,142.44 ; J39.2 225.75,141.02 ; J39.2 224.34,142.44 ; 225.39,161.88 J1.239 ; J1.239 225.39,160.82 ; J1.239 226.45,160.82 ; J1.239 226.45,161.88 ; J1.92 199.45,155.12 ; J1.92 198.39,155.12 ; J1.92 199.45,156.18 ; J1.92 198.39,156.18 ; 128.39,155.12 J1.26 ; J1.26 128.39,156.18 ; J1.26 129.45,155.12 ; J1.26 129.45,156.18 ; 275.48,99.64 J18.B16 ; J18.B16 276.61,99.64 ; J18.B16 275.48,98.51 ; J18.B16 276.61,98.51 ; 273.48,104.64 J18.B21 ; J18.B21 273.48,103.51 ; J18.B21 274.61,104.64 ; J18.B21 274.61,103.51 ; 6.02,123.64 J26.10 ; J26.10 6.02,122.23 ; J26.10 7.44,122.23 ; J26.10 7.44,123.64 ; J30.2 91.89,151.27 ; J30.2 90.48,151.27 ; J30.2 90.48,152.68 ; J30.2 91.89,152.68 ; J1.119 226.45,157.02 ; J1.119 226.45,158.08 ; J1.119 225.39,157.02 ; J1.119 225.39,158.08 ; 2.7,6.65 SW5.3 ; SW5.3 4.33,8.28 ; SW5.3 2.7,8.28 ; SW5.3 4.33,6.65 ; 63.3,125.66 J35.2 ; J35.2 64.72,127.07 ; J35.2 63.3,127.07 ; J35.2 64.72,125.66 ; 81.97,84.15 J27.2 ; J27.2 83.38,84.15 ; J27.2 83.38,82.73 ; J27.2 81.97,82.73 ; 4.06,5.67 SW5.1 ; SW5.1 5.47,4.26 ; SW5.1 5.47,5.67 ; SW5.1 4.06,4.26 ; 51.42,74.92 C692.1 ; C692.1 53.17,74.92 ; C692.1 51.42,73.16 ; C692.1 53.17,73.16 ; J1.107 214.45,158.08 ; J1.107 213.39,158.08 ; J1.107 214.45,157.02 ; J1.107 213.39,157.02 ; C687.2 69,38.48 ; C687.2 69,39.83 ; C687.2 67.65,38.48 ; C687.2 67.65,39.83 ; J18.A18 270.11,100.51 ; J18.A18 270.11,101.64 ; J18.A18 268.98,100.51 ; J18.A18 268.98,101.64 ; J1.11 114.45,157.02 ; J1.11 113.39,158.08 ; J1.11 114.45,158.08 ; J1.11 113.39,157.02 ; 275.48,115.64 J18.B32 ; J18.B32 275.48,114.51 ; J18.B32 276.61,115.64 ; J18.B32 276.61,114.51 ; J1.32 135.45,156.18 ; J1.32 134.39,156.18 ; J1.32 134.39,155.12 ; J1.32 135.45,155.12 ; 131.39,157.02 J1.29 ; J1.29 131.39,158.08 ; J1.29 132.45,158.08 ; J1.29 132.45,157.02 ; J1.5 108.45,158.08 ; J1.5 108.45,157.02 ; J1.5 107.39,158.08 ; J1.5 107.39,157.02 ; 139.71,25.5 J13.A5 ; J13.A5 141.05,25.5 ; J13.A5 141.05,24.15 ; J13.A5 139.71,24.15 ; 133.39,160.82 J1.151 ; J1.151 133.39,161.88 ; J1.151 134.45,160.82 ; J1.151 134.45,161.88 ; J1.145 128.45,161.88 ; J1.145 127.39,160.82 ; J1.145 127.39,161.88 ; J1.145 128.45,160.82 ; 13.56,4.26 SW4.1 ; SW4.1 13.56,5.67 ; SW4.1 14.97,4.26 ; SW4.1 14.97,5.67 ; 146.39,155.12 J1.44 ; J1.44 147.45,155.12 ; J1.44 146.39,156.18 ; J1.44 147.45,156.18 ; 275.48,100.51 J18.B18 ; J18.B18 275.48,101.64 ; J18.B18 276.61,100.51 ; J18.B18 276.61,101.64 ; J13.A4 142.32,22.96 ; J13.A4 140.98,21.61 ; J13.A4 142.32,21.61 ; J13.A4 140.98,22.96 ; 270.98,110.64 J18.A27 ; J18.A27 272.11,110.64 ; J18.A27 270.98,109.51 ; J18.A27 272.11,109.51 ; J18.B13 274.61,96.64 ; J18.B13 273.48,96.64 ; J18.B13 273.48,95.51 ; J18.B13 274.61,95.51 ; 139.71,18.88 J13.B4 ; J13.B4 141.05,18.88 ; J13.B4 139.71,17.53 ; J13.B4 141.05,17.53 ; 110.39,156.18 J1.8 ; J1.8 110.39,155.12 ; J1.8 111.45,155.12 ; J1.8 111.45,156.18 ; 143.39,158.08 J1.41 ; J1.41 144.45,157.02 ; J1.41 144.45,158.08 ; J1.41 143.39,157.02 ; J1.229 216.45,161.88 ; J1.229 216.45,160.82 ; J1.229 215.39,160.82 ; J1.229 215.39,161.88 ; J1.217 204.45,160.82 ; J1.217 203.39,160.82 ; J1.217 204.45,161.88 ; J1.217 203.39,161.88 ; J45.1 109.04,244.78 ; J45.1 109.04,246.2 ; J45.1 107.62,246.2 ; J45.1 107.62,244.78 ; 212.39,158.92 J1.226 ; J1.226 213.45,158.92 ; J1.226 212.39,159.98 ; J1.226 213.45,159.98 ; 142.39,158.92 J1.160 ; J1.160 143.45,159.98 ; J1.160 143.45,158.92 ; J1.160 142.39,159.98 ; 254.18,104.8 J21.8 ; J21.8 254.18,103.13 ; J21.8 255.85,103.13 ; J21.8 255.85,104.8 ; SW4.3 13.83,8.28 ; SW4.3 12.2,8.28 ; SW4.3 12.2,6.65 ; SW4.3 13.83,6.65 ; 223.39,160.82 J1.237 ; J1.237 223.39,161.88 ; J1.237 224.45,161.88 ; J1.237 224.45,160.82
  L7GND w1.016: 12.44,97.31 J37.5 ; J37.5 12.44,95.61 ; J37.5 14.14,97.31 ; J37.5 14.14,95.61 ; 6.94,87.21 J37.17 ; J37.17 8.64,87.21 ; J37.17 8.64,88.91 ; J37.17 6.94,88.91 ; 6.94,93.11 J37.16 ; J37.16 8.64,91.41 ; J37.16 6.94,91.41 ; J37.16 8.64,93.11 ; J37.7 14.14,87.21 ; J37.7 14.14,88.91 ; J37.7 12.44,88.91 ; J37.7 12.44,87.21 ; 6.94,105.71 J37.13 ; J37.13 8.64,105.71 ; J37.13 6.94,104.01 ; J37.13 8.64,104.01 ; J37.3 14.14,104.01 ; J37.3 12.44,104.01 ; J37.3 14.14,105.71 ; J37.3 12.44,105.71 ; J37.15 8.64,95.61 ; J37.15 6.94,95.61 ; J37.15 6.94,97.31 ; J37.15 8.64,97.31
  BOTTOM w0.203: U11.6 92.26,132.66 v1(92.46,132.46) 92.66,132.66 U11.7 ; U7.6 92.26,126.82 v1(92.46,126.62) 92.66,126.82 U7.7 ; U99.7 81.21,122.75 v1(81.41,122.56) 81.61,122.75 U99.6 ; U98.7 81.21,129.98 v1(81.41,130.17) 81.61,129.98 U98.6
  BOTTOM w0.254: 134.18,131.44 v1(134.18,131) ; 134.18,131.44 134.13,131.5 U2.27 ; 134.18,131.44 134.18,131.76 133.94,132 U2.26 ; v1(134.18,131) U2.28 ; v1(134.18,131) 134.18,130.56 ; U27.2 v1(211.69,83.55) ; C75.2 205.87,81.8 206.13,82.05 U27.11 ; 134.18,130.56 134.18,130.24 133.93,130 U2.30 ; 134.18,130.56 134.12,130.5 U2.29 ; v1(209.3,82.3) 209.05,82.55 U25.5 ; U2.45 v1(134.18,122.5) ; U27.20 212.47,82.05 212.72,81.8 C76.2 ; U2.32 133.89,129 134.18,128.71 v1(134.18,128) U2.34 ; U2.10 v1(124.39,125.5) ; U2.1 v1(124.39,121) ; U2.24 v1(124.39,132.5) ; U2.4 v1(124.39,122.5) ; U2.21 v1(124.39,131) ; U2.39 v1(134.18,125.5) ; U92.3 v1(108.2,78.61) ; U2.15 v1(124.39,128)
  BOTTOM w0.305: C256.2 164.72,107.45 v2(164.52,107.65) ; U21.3 76.06,98.16 v1(75.82,97.92) ; v2(158.12,112.45) 158.3,112.26 C192.2 ; C208.2 158.3,110.23 v2(158.12,110.05) ; C22.2 158.3,118.23 v2(158.12,118.05) ; U45.5 v1(143.93,119.55)
  BOTTOM w0.381: v1(30.73,36.2) U94.9 v1(30.73,38.48) ; v1(44.45,38.48) U93.9 v1(44.45,36.2)
  BOTTOM w0.457: v2(151,112.44) 151.72,113.16 C262.2 ; C56.2 v2(178.18,107.82) ; C238.2 166.82,109.34 v2(166.92,109.25) ; C257.2 151.58,110.62 v2(151,110.04) ; C258.2 155.69,110.07 v2(155.72,110.05) ; C55.1 177,102.36 v2(176.52,102.85) ; C912.2 165.32,115.65 v2(165.32,115.65) ; C913.2 165.41,118.75 v2(165.32,118.85) ; R3.1 166.85,123.71 v2(166.92,123.65) 166.12,123.65 C169.2 ; C172.2 158.11,102.84 v2(158.12,102.85) ; v2(161.32,102.85) 161.17,102.7 C149.2 ; v2(165.32,113.25) 165.62,113.55 C915.2 ; R123.1 177.46,103.51 v2(177.32,103.65) ; C914.2 165.52,111.44 v2(165.32,111.65) ; C267.2 151.44,108.08 v2(151,107.64) ; R811.2 156.22,115.94 v2(156.52,115.65) ; v2(159.72,102.85) 159.74,102.82 159.82,102.82 160.22,102.41 160.22,101.43 C160.2 ; C263.2 155.69,112.47 v2(155.72,112.45) ; v2(155.72,107.65) 155.69,107.67 C268.2 ; R124.2 178.44,108.97 v2(178.18,109.22)
  BOTTOM w0.508: 51.21,66.23 C691.1 ; C691.1 53.38,66.23 ; C691.1 53.38,64.07 ; C691.1 51.21,64.07 ; C363.1 v1(200.15,25.15) 200.41,24.88 C371.1 ; C35.2 100.83,133.99 v1(101.22,133.6) ; C360.1 v1(197.23,25.15) ; 37.63,244.64 J33.1 ; J33.1 39.33,246.34 ; J33.1 37.63,246.34 ; J33.1 39.33,244.64 ; C544.1 v1(272.16,33.53) ; J46.1 248.88,244.64 ; J46.1 248.88,246.34 ; J46.1 247.18,244.64 ; J46.1 247.18,246.34 ; v1(161.92,62.36) 161.92,61.99 C557.2 162.94,61.99 v1(162.94,62.36) ; v1(71.52,113.43) 71.02,112.93 C1104.2 ; C172.2 C173.2 C174.2 ; C568.2 v1(163.79,69.65) ; C593.2 178.81,42.28 v1(178.69,42.16) ; v1(104.01,121.16) 103.88,121.02 C30.2 ; C902.2 v1(170.79,63.65) 171.29,64.15 C558.2 ; R172.1 v1(154.82,98.56) ; 19.06,8.42 SW4.4 ; SW4.4 20.97,8.42 ; SW4.4 20.97,6.51 ; SW4.4 19.06,6.51 ; C50.2 69.09,143.13 v1(68.58,142.62) 68.07,143.13 C49.2 ; v1(253.75,70.74) C477.2 v1(254.6,71.67) ; C654.2 81.41,63.11 v1(81.28,63.25) ; C1073.2 v1(82.92,134.23) ; C39.2 v1(39.37,38.61) ; C1062.2 v1(93.97,122.56) ; C368.1 v1(187.45,25.65) ; v1(78.36,101.47) 77.98,101.85 C54.2 ; C324.2 155.7,45.59 v1(155.32,45.21) ; 12.06,8.42 SW4.3 ; SW4.3 13.97,6.51 ; SW4.3 13.97,8.42 ; SW4.3 12.06,6.51 ; 102.4,244.64 J45.3 ; J45.3 104.1,244.64 ; J45.3 104.1,246.34 ; J45.3 102.4,246.34 ; C298.1 v1(159.51,37.72) ; J44.3 173.95,246.34 ; J44.3 172.25,244.64 ; J44.3 173.95,244.64 ; J44.3 172.25,246.34 ; v1(220.31,71.67) C432.2 v1(219.46,70.74) ; R846.2 R848.2 180.59,34.54 v1(181.23,33.91) ; v1(166.79,67.65) 166.29,67.15 C1089.2 ; C589.2 173.29,65.15 v1(172.79,65.65) ; 16.04,123.79 J26.2 ; J26.2 17.74,122.09 ; J26.2 16.04,122.09 ; J26.2 17.74,123.79 ; C711.2 64.01,107.93 v1(63.52,108.43) ; C1061.2 v1(90.94,122.56) ; v1(217.42,75.44) 217.42,74.97 C401.2 216.41,74.97 v1(216.41,75.44) ; C75.2 v1(205.36,81.03) ; v1(236.85,62.1) 236.69,62.27 C457.2 v1(235.84,62.99) ; v1(85.34,40.51) 85.34,39.9 C636.2 84.07,39.9 v1(84.07,40.51) ; v1(167.79,67.65) 167.29,67.15 C1090.2 ; C310.1 v1(166.25,35.43) ; C1091.2 165.29,69.15 v1(165.79,69.65) ; C521.1 v1(229.62,37.21) ; C760.2 v1(102.11,90.3) ; C520.1 v1(263.91,37.21) ; J2.6 v1(33.4,32.52) ; R831.1 151.7,129.53 Q38.2 ; v1(90.94,128.4) C1059.2 R812.2 ; C536.1 v1(251.97,51.82) ; v1(107.57,121.16) 107.43,121.02 C32.2 ; C38.2 v1(38.35,38.61) ; v1(159.13,64.52) 158.88,64.77 C586.2 ; v1(250.7,75.44) 250.7,74.97 C446.2 251.71,74.97 v1(251.71,75.44) ; C535.1 v1(220.73,51.82) ; 9.56,6.51 SW5.4 ; SW5.4 9.56,8.42 ; SW5.4 11.47,8.42 ; SW5.4 11.47,6.51 ; C53.2 68.84,139.82 v1(68.58,140.08) 68.32,139.82 C51.2 ; C1021.2 v1(175.64,63.12) ; v1(167.79,60.65) 167.29,61.15 C571.2 ; C494.1 v1(243.71,37.21) ; v1(172.72,95.76) 172.94,95.54 C181.2 ; C529.1 218.94,67.05 v1(218.82,66.93) ; v1(166.79,62.65) 166.29,63.15 C588.2 ; v1(134.18,128) 134.2,128.02 R106.1 ; C652.2 v1(86.23,62.61) ; C712.2 65.02,107.93 v1(65.52,108.43) ; 67.51,39.97 C687.2 ; C687.2 69.14,39.97 ; C687.2 67.51,38.34 ; C687.2 69.14,38.34 ; C330.1 v1(143.64,37.72) ; C328.1 v1(140.59,37.72) ; v1(110.74,40.51) 110.74,39.9 C669.2 112.01,39.9 v1(112.01,40.51) ; 242.1,244.64 J46.3 ; J46.3 242.1,246.34 ; J46.3 243.8,244.64 ; J46.3 243.8,246.34 ; v1(167.79,65.65) 167.29,65.15 C1088.2 ; C537.1 v1(217.68,51.82) ; v1(195.71,62.74) 195.95,62.98 C1025.2 ; C597.2 175.78,42.28 v1(175.89,42.16) ; v1(169.79,69.65) 169.29,69.15 R384.2 ; 3.92,5.82 SW5.1 ; SW5.1 3.92,4.12 ; SW5.1 5.62,5.82 ; SW5.1 5.62,4.12 ; C577.2 172.29,63.15 v1(171.79,62.65) ; C653.2 91.43,63.24 v1(91.57,63.37) ; R193.2 v1(192.15,128.91) ; R379.2 165.29,67.15 v1(164.79,67.65) ; v1(174.79,60.65) 174.29,60.16 C587.2 ; v1(240.66,37.21) C496.1 240.66,37.97 C553.1 ; C585.2 v1(173.79,69.65) ; C1020.2 v1(175.64,64.14) ; v1(202.56,69.98) 202.4,69.81 C420.2 v1(201.55,69.09) ; R589.2 R588.2 v1(100.08,90.3) ; C562.2 172.29,65.15 v1(171.79,65.65) ; 177.33,246.34 J44.1 ; J44.1 177.33,244.64 ; J44.1 179.03,244.64 ; J44.1 179.03,246.34 ; C1092.2 166.29,69.15 v1(166.79,69.65) ; C548.1 v1(204.09,37.21) ; C713.2 v1(70.52,100.42) ; J33.3 34.25,244.64 ; J33.3 32.55,244.64 ; J33.3 34.25,246.34 ; J33.3 32.55,246.34 ; C761.2 R560.1 v1(95.25,79.38) ; C362.1 v1(191.13,25.15) ; v1(104.39,89.28) R581.2 R582.2 ; C708.2 v1(56.52,98.43) ; C545.1 257.8,37.97 C524.1 v1(257.81,37.21) ; J2.3 v1(40.07,32.58) ; SW4.1 15.12,5.82 ; SW4.1 15.12,4.12 ; SW4.1 13.42,5.82 ; SW4.1 13.42,4.12 ; 5.88,123.79 J26.10 ; J26.10 7.58,122.09 ; J26.10 5.88,122.09 ; J26.10 7.58,123.79 ; 153.8,101.35 R814.1 153.04,101.34 v1(153.03,101.35) ; 153.8,101.35 R173.1 ; 153.8,101.35 R171.1 ; C296.1 v1(156.46,37.72) ; C518.1 v1(266.95,37.21) ; v1(166.79,60.65) 166.29,61.15 C569.2 ; C706.2 v1(62.52,108.43) ; v1(92.96,40.51) 92.96,39.9 C645.2 94.23,39.9 v1(94.23,40.51) ; C714.2 v1(66.52,108.43) ; 107.48,246.34 J45.1 ; J45.1 109.18,244.64 ; J45.1 107.48,244.64 ; J45.1 109.18,246.34 ; v1(202.56,62.1) 202.4,62.27 C412.2 v1(201.55,62.99) ; v1(134.18,131) 134.37,130.8 C25.2 ; v1(171.79,60.65) 172.29,61.15 C901.2 ; R493.1 v1(79.88,68.06) ; C1019.2 v1(175.64,72.26) ; v1(236.85,69.98) 236.69,69.81 C466.2 v1(235.84,69.09) ; SW5.3 4.47,6.51 ; SW5.3 2.56,6.51 ; SW5.3 2.56,8.42 ; SW5.3 4.47,8.42 ; v1(253.11,66.93) 253.23,67.05 C528.1 ; R568.1 v1(96.27,77.34) ; v1(232.79,129.29) 232.96,129.12 C1049.2 ; C33.2 C34.2 101.1,129.41 v1(101.09,129.41) ; v1(203.83,68.07) 204,67.91 C433.2 v1(204.98,67.18) ; C29.2 C27.2 76.57,128.14 v1(76.45,128.02) ; v1(194.12,70.93) 194.17,70.99 C378.2 ; C160.2 C162.2 C161.2 ; C1060.2 v1(93.97,128.4) ; C561.2 170.29,66.15 v1(169.79,66.65) ; C709.2 v1(62.52,104.43) ; v1(238.12,68.07) 238.29,67.91 C478.2 v1(239.27,67.18) ; C716.2 v1(66.52,104.43) ; C301.1 v1(165.48,37.72) ; C495.1 v1(209.42,37.21) ; v1(114.43,63.37) 114.29,63.24 C677.2 ; v1(256.15,69.72) 256.2,69.67 C465.2 ; C519.1 v1(232.54,37.21) ; v1(169.79,63.65) 170.29,64.15 C903.2 ; v1(170.79,69.65) 170.29,69.15 C1094.2 170.29,69.15 ; C1074.2 v1(79.89,134.23) ; C532.1 v1(257.94,51.82) ; C52.2 76.21,97.53 v1(75.82,97.92) ; C77.2 v1(209.3,87) ; R104.1 R105.1 151.9,117.6 C270.2 151.34,117.06 C269.2 150.62,116.59 v1(150.24,116.2) ; R594.1 v1(101.85,77.34) ; C342.1 v1(152.27,36.32) ; C533.1 v1(223.65,51.82) ; C336.1 135.77,35.43 v1(135.25,35.94) ; R383.2 v1(165.79,63.65) ; C491.1 v1(249.68,37.21) ; U65.H7 v1(62.52,107.43) ; U65.J8 v1(63.52,105.43) ; C364.1 v1(194.18,25.15) ; C504.1 v1(240.79,51.82) ; C306.1 v1(153.54,36.32) ; C507.1 v1(203.58,51.82) ; C281.2 171.2,91.95 v1(170.69,92.46) 171.2,92.96 C280.2 ; C391.2 186.58,60.72 v1(187.32,61.47) 187.59,61.73 C393.2 ; C76.2 v1(213.23,81.03) ; v1(177.67,60.58) 178.04,60.58 C583.2 178.04,59.56 v1(177.67,59.56) ; C695.2 v1(70.23,61.85) ; C332.1 v1(146.69,37.72) ; C523.1 v1(226.57,37.21) ; C299.1 v1(162.56,37.72) ; v1(165.79,60.65) 165.29,61.15 C560.2 ; R135.1 R136.1 R137.1 v1(187.83,103.64) ; R810.1 R809.1 v1(114.68,133.22) ; v1(63.52,104.43) 64.01,104.92 C1102.2 ; C24.2 124.2,130.8 v1(124.39,131) ; C1018.2 v1(177.67,58.03) ; v1(65.52,104.43) 65.02,104.92 C1103.2 ; C509.1 v1(200.53,51.82) ; C570.2 v1(174.8,61.65) ; v1(172.29,70.76) 172.45,70.91 C567.2 v1(171.58,72.01) ; v2(252.35,68.83) 252.21,68.7 R320.1 ; R297.1 217.92,68.7 v2(218.06,68.83) ; v1(171.79,69.65) 171.29,69.15 C900.2 ; v1(172.79,62.65) 173.29,63.15 C899.2 ; C41.2 161.04,89.41 v1(160.53,89.92) 161.04,90.42 C40.2 ; C1072.2 v1(79.89,128.14) ; C42.2 156.46,90.42 v1(155.96,89.92) 156.46,89.41 C43.2 ; R13.1 v1(112.14,125.35) ; C715.2 v1(56.52,114.43) ; R593.1 100.84,77.6 v1(100.58,77.34) 99.61,77.34 C795.2 ; v1(151.64,44.45) 151.89,44.7 C309.2 ; v1(172.97,56.77) 172.97,56.64 173.72,55.9 C576.2 v1(173.86,56.77) ; C676.2 v1(109.09,62.61) ; C505.1 v1(206.5,51.82) ; v1(134.18,122.5) 134.5,122.82 C26.2 ; v1(103.12,40.51) 103.12,39.9 C658.2 101.85,39.9 v1(101.85,40.51) ; C582.2 v1(171.79,67.65) ; C492.1 v1(246.76,37.21) ; v1(104.14,63.25) 104.27,63.11 C678.2 ; C28.2 95.88,128.14 v1(95.76,128.02) ; v1(98.3,54.74) 98.3,55.22 C651.2 97.28,55.22 v1(97.28,54.74) ; C138.2 C149.2 ; v1(223.52,37.21) C525.1 223.51,37.97 C550.1 ; C516.1 v1(253.23,64.02) ; C282.2 166.38,92.46 v1(166.12,92.46) 166.62,91.95 C283.2 ; C356.2 133.48,46.23 v1(133.1,45.85) ; v1(172.79,67.65) 172.29,67.15 C581.2 ; C579.2 v1(172.79,69.65) ; v1(238.51,140.33) 238.16,140.68 C736.2 ; v1(57.52,99.43) 58.01,99.92 C707.2 ; C584.2 173.29,60.15 v1(173.79,60.65) ; C510.1 v1(231.77,51.82) ; C559.2 v1(163.79,60.65) ; Q7.2 74.99,66.74 v1(74.68,67.06) ; v1(232.54,140.08) 232.78,140.33 C1051.2 ; C31.2 110.74,120.9 v1(111,121.16) ; R190.2 v1(192.15,125.09) ; C770.1 R575.1 93.23,82.43 v1(93.22,82.42) ; v1(161.92,67.06) 161.92,67.42 C556.2 162.94,67.42 v1(162.94,67.06) ; C1105.2 v1(72.52,114.43) ; R487.1 71.87,68.32 v1(72.14,68.58) ; v1(146.81,122.17) 147.06,122.42 C295.2 ; v1(121.16,54.74) 121.16,55.22 C675.2 120.14,55.22 v1(120.14,54.74) ; C534.1 v1(255.02,51.82) ; C506.1 v1(237.87,51.82) ; v1(166.5,72.39) 166.01,72.39 C566.2 165.62,71.52 v1(166.29,70.86) ; U65.J10 v1(66.52,105.43) ; v1(167.79,69.65) 167.29,69.15 C1093.2 ; C341.2 129.67,45.34 v1(129.41,45.09) ; C1040.2 234.4,133.13 v1(234.19,133.35) ; C511.1 v1(197.48,51.82) ; C762.2 v1(101.09,90.3) ; v1(221.86,69.72) 221.91,69.67 C421.2 ; C490.1 v1(215.39,37.21) ; C1071.2 v1(82.92,128.14) ; U65.H9 v1(65.52,107.43) ; C333.1 v1(149.61,37.72) ; v1(168.79,60.65) 169.29,61.15 C563.2 ; v1(57.52,113.43) 58.01,112.93 C705.2 ; C508.1 v1(234.82,51.82) ; R52.2 v1(78.86,134.23) ; C517.1 v1(218.94,64.02) ; C538.1 v1(248.92,51.82) ; C497.1 v1(206.38,37.21) ; C539.1 v1(214.63,51.82) ; C493.1 v1(212.47,37.21) ; C710.2 v1(72.52,98.43) ; C522.1 v1(260.86,37.21)
  BOTTOM w1.016: 12.3,89.05 J37.7 ; J37.7 12.3,87.07 ; J37.7 14.28,89.05 ; J37.7 14.28,87.07 ; J37.15 8.78,95.47 ; J37.15 8.78,97.45 ; J37.15 6.8,97.45 ; J37.15 6.8,95.47 ; J37.3 14.28,103.87 ; J37.3 12.3,103.87 ; J37.3 12.3,105.85 ; J37.3 14.28,105.85 ; 6.8,105.85 J37.13 ; J37.13 6.8,103.87 ; J37.13 8.78,103.87 ; J37.13 8.78,105.85 ; J37.5 14.28,95.47 ; J37.5 12.3,97.45 ; J37.5 14.28,97.45 ; J37.5 12.3,95.47 ; 6.8,87.07 J37.17 ; J37.17 6.8,89.05 ; J37.17 8.78,89.05 ; J37.17 8.78,87.07 ; J37.16 8.78,91.27 ; J37.16 8.78,93.25 ; J37.16 6.8,93.25 ; J37.16 6.8,91.27
  vias: v1(16.76,86.49) v1(16.76,72.01) v1(17.53,86.49) v1(17.78,72.01) v1(19.05,95.76) v1(19.18,86.49) v1(19.94,86.49) v1(22.73,112.9) v1(22.73,112.14) v1(22.73,111.38) v1(22.73,102.11) v1(22.73,101.35) v1(22.73,100.58) v1(22.73,91.31) v1(22.73,90.55) v1(22.73,89.79) v1(24.38,109.47) v1(24.38,98.68) v1(24.38,87.88) v1(25.27,109.47) v1(25.27,98.68) v1(25.27,87.88) v1(25.78,108.59) v1(25.78,97.79) v1(25.78,87) v1(26.16,109.47) v1(26.16,98.68) v1(26.16,87.88) v1(26.67,108.59) v1(26.67,97.79) v1(26.67,87) v1(27.05,109.47) v1(27.05,98.68) v1(27.05,87.88) v1(30.35,76.71) v1(31.12,76.71) v1(31.24,116.97) v1(31.24,115.95) v1(31.24,114.81) v1(31.24,113.79) v1(31.24,112.65) v1(31.24,111.63) v1(31.24,110.49) v1(31.24,109.47) v1(31.24,106.17) v1(31.24,105.16) v1(31.24,104.01) v1(31.24,103) v1(31.24,101.85) v1(31.24,100.84) v1(31.24,99.7) v1(31.24,98.68) v1(31.24,95.89) v1(31.24,94.87) v1(31.24,93.73) v1(31.24,92.71) v1(31.24,91.57) v1(31.24,90.55) v1(31.24,89.41) v1(31.24,88.39) v1(32.38,76.71) v1(33.15,76.71) v1(34.54,75.82) v1(35.56,75.82) v1(41.27,77.98) v1(42.04,77.98) v1(43.81,77.98) v1(44.58,77.98) v1(51.18,74.55) v1(51.18,73.66) v1(51.18,65.66) v1(51.18,64.77) v1(52.7,142.75) v1(52.7,58.04) v1(52.7,57.28) v1(52.7,56.52) v1(53.34,58.04) v1(53.34,57.28) v1(53.34,56.52) v1(53.47,74.55) v1(53.47,73.66) v1(53.47,65.66) v1(53.47,64.77) v1(53.59,142.75) v1(57.15,20.95) v1(57.15,20.07) v1(57.15,19.18) v1(57.91,20.95) v1(57.91,20.07) v1(57.91,19.18) v1(59.31,28.07) v1(60.07,28.07) v1(60.07,27.3) v1(60.2,81.15) v1(60.2,80.39) v1(60.2,79.63) v1(60.32,42.8) v1(60.32,42.04) v1(61.34,42.8) v1(61.34,42.04) v1(61.85,77.72) v1(62.36,42.8) v1(62.36,42.04) v1(62.74,77.72) v1(63.25,76.84) v1(63.63,77.72) v1(64.01,23.37) v1(64.14,76.84) v1(64.52,77.72) v1(64.9,23.37) v1(65.91,23.37) v1(66.93,23.37) v1(67.95,83.31) v1(68.07,66.04) v1(68.07,65.28) v1(68.58,81.41) v1(68.58,80.52) v1(68.58,79.63) v1(68.58,78.74) v1(68.58,77.85) v1(68.71,82.55) v1(68.83,66.04) v1(68.83,65.28) v1(68.96,29.97) v1(68.96,29.21) v1(69.85,29.97) v1(69.85,29.21) v1(70.74,29.97) v1(70.74,29.21) v1(73.03,22.23) v1(73.03,21.46) v1(73.15,31.88) v1(74.04,22.23) v1(74.04,21.46) v1(74.42,31.88) v1(75.69,31.88) v1(75.82,86.36) v1(76.45,85.73) v1(76.96,31.88) v1(78.36,102.23) v1(78.61,92.71) v1(78.61,91.95) v1(78.61,85.85) v1(78.87,95.38) v1(79.38,102.23) v1(79.38,85.85) v1(79.63,95.38) v1(80.39,102.23) v1(82.68,142.24) v1(83.44,79.38) v1(83.57,142.24) v1(83.95,78.87) v1(84.07,111.76) v1(84.2,59.44) v1(84.2,56.9) v1(84.2,54.36) v1(84.45,142.24) v1(84.84,111.76) v1(84.96,82.04) v1(84.96,81.28) v1(84.96,80.52) v1(86.11,87.5) v1(86.11,86.74) v1(86.74,59.44) v1(86.74,56.9) v1(86.74,54.36) v1(86.87,105.16) v1(86.87,102.36) v1(86.87,96.9) v1(86.87,94.11) v1(87.63,105.16) v1(87.63,102.36) v1(87.63,96.9) v1(87.63,94.11) v1(87.76,185.42) v1(87.88,218.06) v1(88.65,185.42) v1(88.77,218.06) v1(89.28,87) v1(89.28,59.44) v1(89.28,56.9) v1(89.28,54.36) v1(93.73,206.38) v1(93.73,204.6) v1(93.85,105.92) v1(93.85,102.11) v1(93.85,95) v1(93.85,94.11) v1(93.85,91.06) v1(93.85,90.3) v1(94.74,91.06) v1(94.74,90.3) v1(94.87,105.92) v1(94.87,102.11) v1(94.87,95) v1(94.87,94.11) v1(95.38,142.24) v1(96.27,142.24) v1(96.27,104.01) v1(96.27,103) v1(96.27,93.85) v1(96.27,92.84) v1(96.27,91.82) v1(96.77,110.24) v1(96.77,109.22) v1(96.77,108.2) v1(96.77,100.58) v1(96.77,99.57) v1(96.77,98.55) v1(97.03,104.01) v1(97.03,103) v1(97.03,93.85) v1(97.03,92.84) v1(97.03,91.82) v1(97.16,142.24) v1(97.54,110.24) v1(97.54,109.22) v1(97.54,108.2) v1(97.54,107.06) v1(97.54,106.17) v1(97.54,100.58) v1(97.54,99.57) v1(97.54,98.55) v1(97.54,97.03) v1(97.54,96.01) v1(99.44,84.84) v1(99.44,83.57) v1(99.44,82.3) v1(100.71,84.84) v1(100.71,83.57) v1(100.71,82.3) v1(101.98,84.84) v1(101.98,83.57) v1(101.98,82.3) v1(103.25,112.9) v1(103.25,112.14) v1(104.27,102.49) v1(104.27,100.84) v1(104.27,92.33) v1(104.27,90.68) v1(105.79,103.51) v1(105.79,102.36) v1(105.79,100.84) v1(105.79,93.34) v1(105.79,92.2) v1(105.79,90.68) v1(106.05,112.9) v1(106.05,112.14) v1(106.43,102.87) v1(106.43,92.71) v1(107.06,59.44) v1(107.06,56.9) v1(107.06,54.36) v1(107.19,103.51) v1(107.19,102.36) v1(107.19,93.34) v1(107.19,92.2) v1(108.46,109.98) v1(108.46,108.08) v1(108.46,106.81) v1(108.46,103.38) v1(108.46,99.82) v1(108.46,97.92) v1(108.46,96.65) v1(108.46,93.22) v1(108.84,105.79) v1(108.84,104.39) v1(108.84,95.63) v1(108.84,94.23) v1(109.09,89.92) v1(109.09,88.52) v1(109.35,109.98) v1(109.35,108.08) v1(109.35,106.81) v1(109.35,103.38) v1(109.35,102.36) v1(109.35,99.82) v1(109.35,97.92) v1(109.35,96.65) v1(109.35,93.22) v1(109.35,92.2) v1(109.6,59.44) v1(109.6,56.9) v1(109.6,54.36) v1(110.62,99.19) v1(110.87,83.19) v1(111,85.47) v1(111.89,99.19) v1(112.14,59.44) v1(112.14,56.9) v1(112.14,54.36) v1(113.03,82.17) v1(113.03,79.38) v1(113.03,77.85) v1(113.16,99.19) v1(116.46,107.95) v1(116.46,106.05) v1(116.59,97.66) v1(116.59,96.14) v1(117.6,107.95) v1(117.6,106.05) v1(117.73,86.87) v1(118.24,110.49) v1(118.24,109.6) v1(118.36,91.69) v1(118.36,90.55) v1(118.36,87.38) v1(118.62,101.85) v1(118.62,100.71) v1(118.75,107.95) v1(118.75,106.05) v1(119.25,110.49) v1(119.25,109.6) v1(120.27,114.55) v1(120.27,113.16) v1(120.27,111.76) v1(120.27,110.49) v1(121.41,114.55) v1(121.41,113.16) v1(121.41,111.76) v1(121.41,110.49) v1(123.57,87.88) v1(124.59,87.88) v1(125.6,87.88) v1(126.62,87.88) v1(127.64,87.88) v1(129.29,88.65) v1(129.41,44.32) v1(130.05,88.65) v1(135,51.82) v1(135,50.55) v1(135,49.28) v1(135.25,37.21) v1(135.25,33.4) v1(135.25,32.13) v1(135.25,30.86) v1(136.27,51.82) v1(136.27,50.55) v1(136.27,49.28) v1(137.54,51.82) v1(137.54,50.55) v1(137.54,49.28) v1(138.05,111.38) v1(138.05,109.86) v1(138.05,108.33) v1(138.05,106.81) v1(138.05,105.41) v1(138.05,104.01) v1(138.05,102.74) v1(139.06,109.86) v1(139.06,108.33) v1(139.06,106.81) v1(139.06,105.41) v1(139.06,104.01) v1(139.06,102.74) v1(140.08,102.74) v1(141.1,102.74) v1(142.11,102.74) v1(147.57,53.72) v1(151.64,43.69) v1(157.23,51.18) v1(157.23,49.91) v1(157.23,48.64) v1(158.5,51.18) v1(158.5,49.91) v1(158.5,48.64) v1(159.77,51.18) v1(159.77,49.91) v1(159.77,48.64) v1(161.54,53.34) v1(167.51,51.56) v1(170.05,49.4) v1(173.74,51.56) v1(173.74,50.55) v1(175.01,198.75) v1(175.01,196.98) v1(177.67,69.6) v1(177.67,68.71) v1(177.67,67.69) v1(177.67,66.68) v1(178.56,100.33) v1(179.96,218.06) v1(179.96,185.29) v1(180.72,51.69) v1(180.72,50.55) v1(180.85,218.06) v1(180.85,185.29) v1(180.97,103.12) v1(185.17,107.44) v1(186.82,108.71) v1(187.58,101.22) v1(189.86,82.8) v1(189.86,81.79) v1(189.86,80.65) v1(189.86,79.5) v1(189.86,76.45) v1(189.86,75.06) v1(189.86,68.96) v1(189.86,66.8) v1(189.86,65.15) v1(189.86,63.5) v1(190.12,170.89) v1(190.37,103.63) v1(190.88,76.45) v1(190.88,75.06) v1(191.52,66.8) v1(191.52,65.15) v1(191.52,63.5) v1(192.15,127.13) v1(192.15,126.11) v1(192.53,170.87) v1(193.17,66.8) v1(193.17,65.15) v1(193.17,63.5) v1(193.93,68.45) v1(194.06,82.42) v1(194.44,83.31) v1(194.94,82.42) v1(195.33,83.31) v1(195.83,82.42) v1(196.72,82.42) v1(196.85,132.72) v1(196.85,131.83) v1(197.87,127) v1(198.37,80.52) v1(198.37,79.76) v1(198.37,78.99) v1(198.75,127) v1(200.66,127.76) v1(200.91,128.4) v1(203.58,91.57) v1(205.99,93.09) v1(206.25,91.57) v1(206.5,80.26) v1(206.63,57.15) v1(207.26,76.2) v1(207.26,74.68) v1(207.39,126.49) v1(207.39,125.48) v1(208.15,82.3) v1(208.13,79.15) v1(208.41,125.48) v1(208.66,93.09) v1(208.79,77.72) v1(208.79,76.2) v1(209.68,140.72) v1(210.31,139.45) v1(210.31,138.05) v1(210.31,136.65) v1(210.31,135.13) v1(210.31,132.97) v1(210.31,132.08) v1(210.44,82.3) v1(210.82,52.83) v1(211.07,133.98) v1(211.84,132.97) v1(211.84,132.08) v1(214.38,139.57) v1(214.63,55.75) v1(214.76,140.46) v1(215.26,139.57) v1(215.65,140.46) v1(216.15,139.57) v1(217.04,139.57) v1(218.69,137.67) v1(218.69,136.91) v1(218.69,136.14) v1(220.85,58.04) v1(224.16,153.67) v1(224.16,152.78) v1(224.16,151.64) v1(224.16,150.75) v1(224.16,146.69) v1(225.04,146.69) v1(226.19,149.22) v1(226.44,147.19) v1(226.44,146.18) v1(228.22,147.19) v1(228.22,146.18) v1(229.62,146.69) v1(230,113.28) v1(230,104.39) v1(230,95.5) v1(230.5,146.69) v1(230.76,154.05) v1(230.76,153.29) v1(231.39,146.69) v1(231.52,154.05) v1(231.52,153.29) v1(234.7,114.17) v1(234.7,105.28) v1(234.7,96.39) v1(235.08,137.67) v1(235.2,136.52) v1(235.2,135.51) v1(236.35,135.51) v1(236.6,137.67) v1(236.6,136.52) v1(237.36,135.51) v1(237.49,138.05) v1(237.49,137.03) v1(238.12,105.16) v1(238.12,103.63) v1(238.12,96.27) v1(238.12,94.74) v1(240.92,57.15) v1(244.35,76.96) v1(245.87,76.96) v1(248.92,55.75) v1(255.14,58.04) v1(258.32,163.32) v1(258.32,160.53) v1(259.46,163.32) v1(259.46,160.53) v1(260.73,139.32) v1(260.73,136.91) v1(260.73,134.49) v1(262.64,139.32) v1(262.64,136.91) v1(262.64,134.49) v1(263.53,77.09) v1(263.53,75.57) v1(263.53,64.77) v1(263.53,63.88) v1(264.41,64.77) v1(264.41,63.88) v1(264.54,139.32) v1(264.54,136.91) v1(264.96,98.82) v1(264.96,97.29) v1(265.18,91.06) v1(265.18,90.04) v1(265.94,91.06) v1(265.94,90.04) v1(266.06,77.09) v1(266.06,75.57) v1(269.24,75.82) v1(270.26,75.82) v1(271.65,75.82) v1(272.29,165.48) v1(272.67,75.82) v1(272.92,155.57) v1(272.92,154.94) v1(272.92,154.3) v1(272.92,153.67) v1(273.05,165.48) v1(274.7,75.06) v1(274.7,74.17) v1(275.97,75.06) v1(275.97,74.17) v1(277.11,75.06) v1(277.11,74.17) v2(158.91,109.24) v2(162.91,110.04) v2(206.55,66.65) v2(206.63,61.98) v2(206.88,69.47) v2(206.96,67.49) v2(207.62,67.11) v2(208.41,69.98) v2(211.33,65.28) v2(211.71,67.95) v2(211.71,67.06) v2(211.71,66.17) v2(212.6,67.95) v2(212.6,67.06) v2(212.6,66.17) v2(212.6,65.28) v2(240.84,66.65) v2(240.92,61.98) v2(241.17,69.47) v2(241.25,67.49) v2(241.91,67.11) v2(242.7,69.98) v2(245.62,65.28) v2(246,67.95) v2(246,67.06) v2(246,66.17) v2(246.89,67.95) v2(246.89,67.06) v2(246.89,66.17) v2(246.89,65.28) v3(2.92,235.97) v3(2.92,223.27) v3(2.92,209.93) v3(2.92,198.5) v3(2.92,188.34) v3(2.92,177.55) v3(2.92,164.21) v3(2.92,150.88) v3(2.92,136.91) v3(2.92,124.84) v3(2.92,113.41) v3(2.92,100.08) v3(2.92,83.57) v3(2.92,70.23) v3(2.92,57.53) v3(2.92,45.47) v3(2.92,33.4) v3(2.92,21.97) v3(6.35,105.54) v3(6.35,104.14) v3(6.35,97.16) v3(6.35,95.76) v3(6.35,92.96) v3(6.35,91.57) v3(6.35,88.77) v3(6.35,87.38) v3(9.27,105.54) v3(9.27,104.14) v3(9.27,97.16) v3(9.27,95.76) v3(9.27,92.96) v3(9.27,91.57) v3(9.27,88.77) v3(9.27,87.38) v3(11.81,105.66) v3(11.81,104.27) v3(11.81,97.16) v3(11.81,95.76) v3(11.81,88.77) v3(11.81,87.38) v3(11.81,2.92) v3(14.73,105.66) v3(14.73,104.27) v3(14.73,97.16) v3(14.73,95.76) v3(14.73,88.77) v3(14.73,87.38) v3(14.99,249.3) v3(27.05,2.92) v3(28.32,249.3) v3(34.04,2.92) v3(41.66,2.92) v3(42.93,249.3) v3(49.28,2.92) v3(54.99,249.3) v3(56.9,2.92) v3(68.96,249.3) v3(84.2,249.3) v3(99.44,249.3) v3(111.51,249.3) v3(122.3,249.3) v3(132.72,102.74) v3(132.72,100.71) v3(132.72,98.68) v3(132.72,96.65) v3(132.72,94.62) v3(132.72,92.58) v3(132.72,90.55) v3(133.73,102.74) v3(133.73,100.71) v3(133.73,98.68) v3(133.73,96.65) v3(133.73,94.62) v3(133.73,92.58) v3(133.73,90.55) v3(134.37,249.3) v3(151.51,249.3) v3(167.39,249.3) v3(182.63,249.3) v3(197.87,249.3) v3(213.11,249.3) v3(227.71,249.3) v3(239.78,249.3) v3(254.38,249.3) v3(265.81,249.3) v3(279.15,239.14) v3(279.15,228.98) v3(279.15,216.92) v3(279.15,203.58) v3(279.15,190.25) v3(279.15,176.91) v3(279.15,161.67) v3(279.15,147.07) v3(279.15,80.39) v3(279.15,68.96) v3(279.15,56.9) v3(279.15,44.2) v3(279.15,34.67) v3(279.78,133.73) v3(279.78,119.76) v3(279.78,107.06) v3(279.78,94.36)
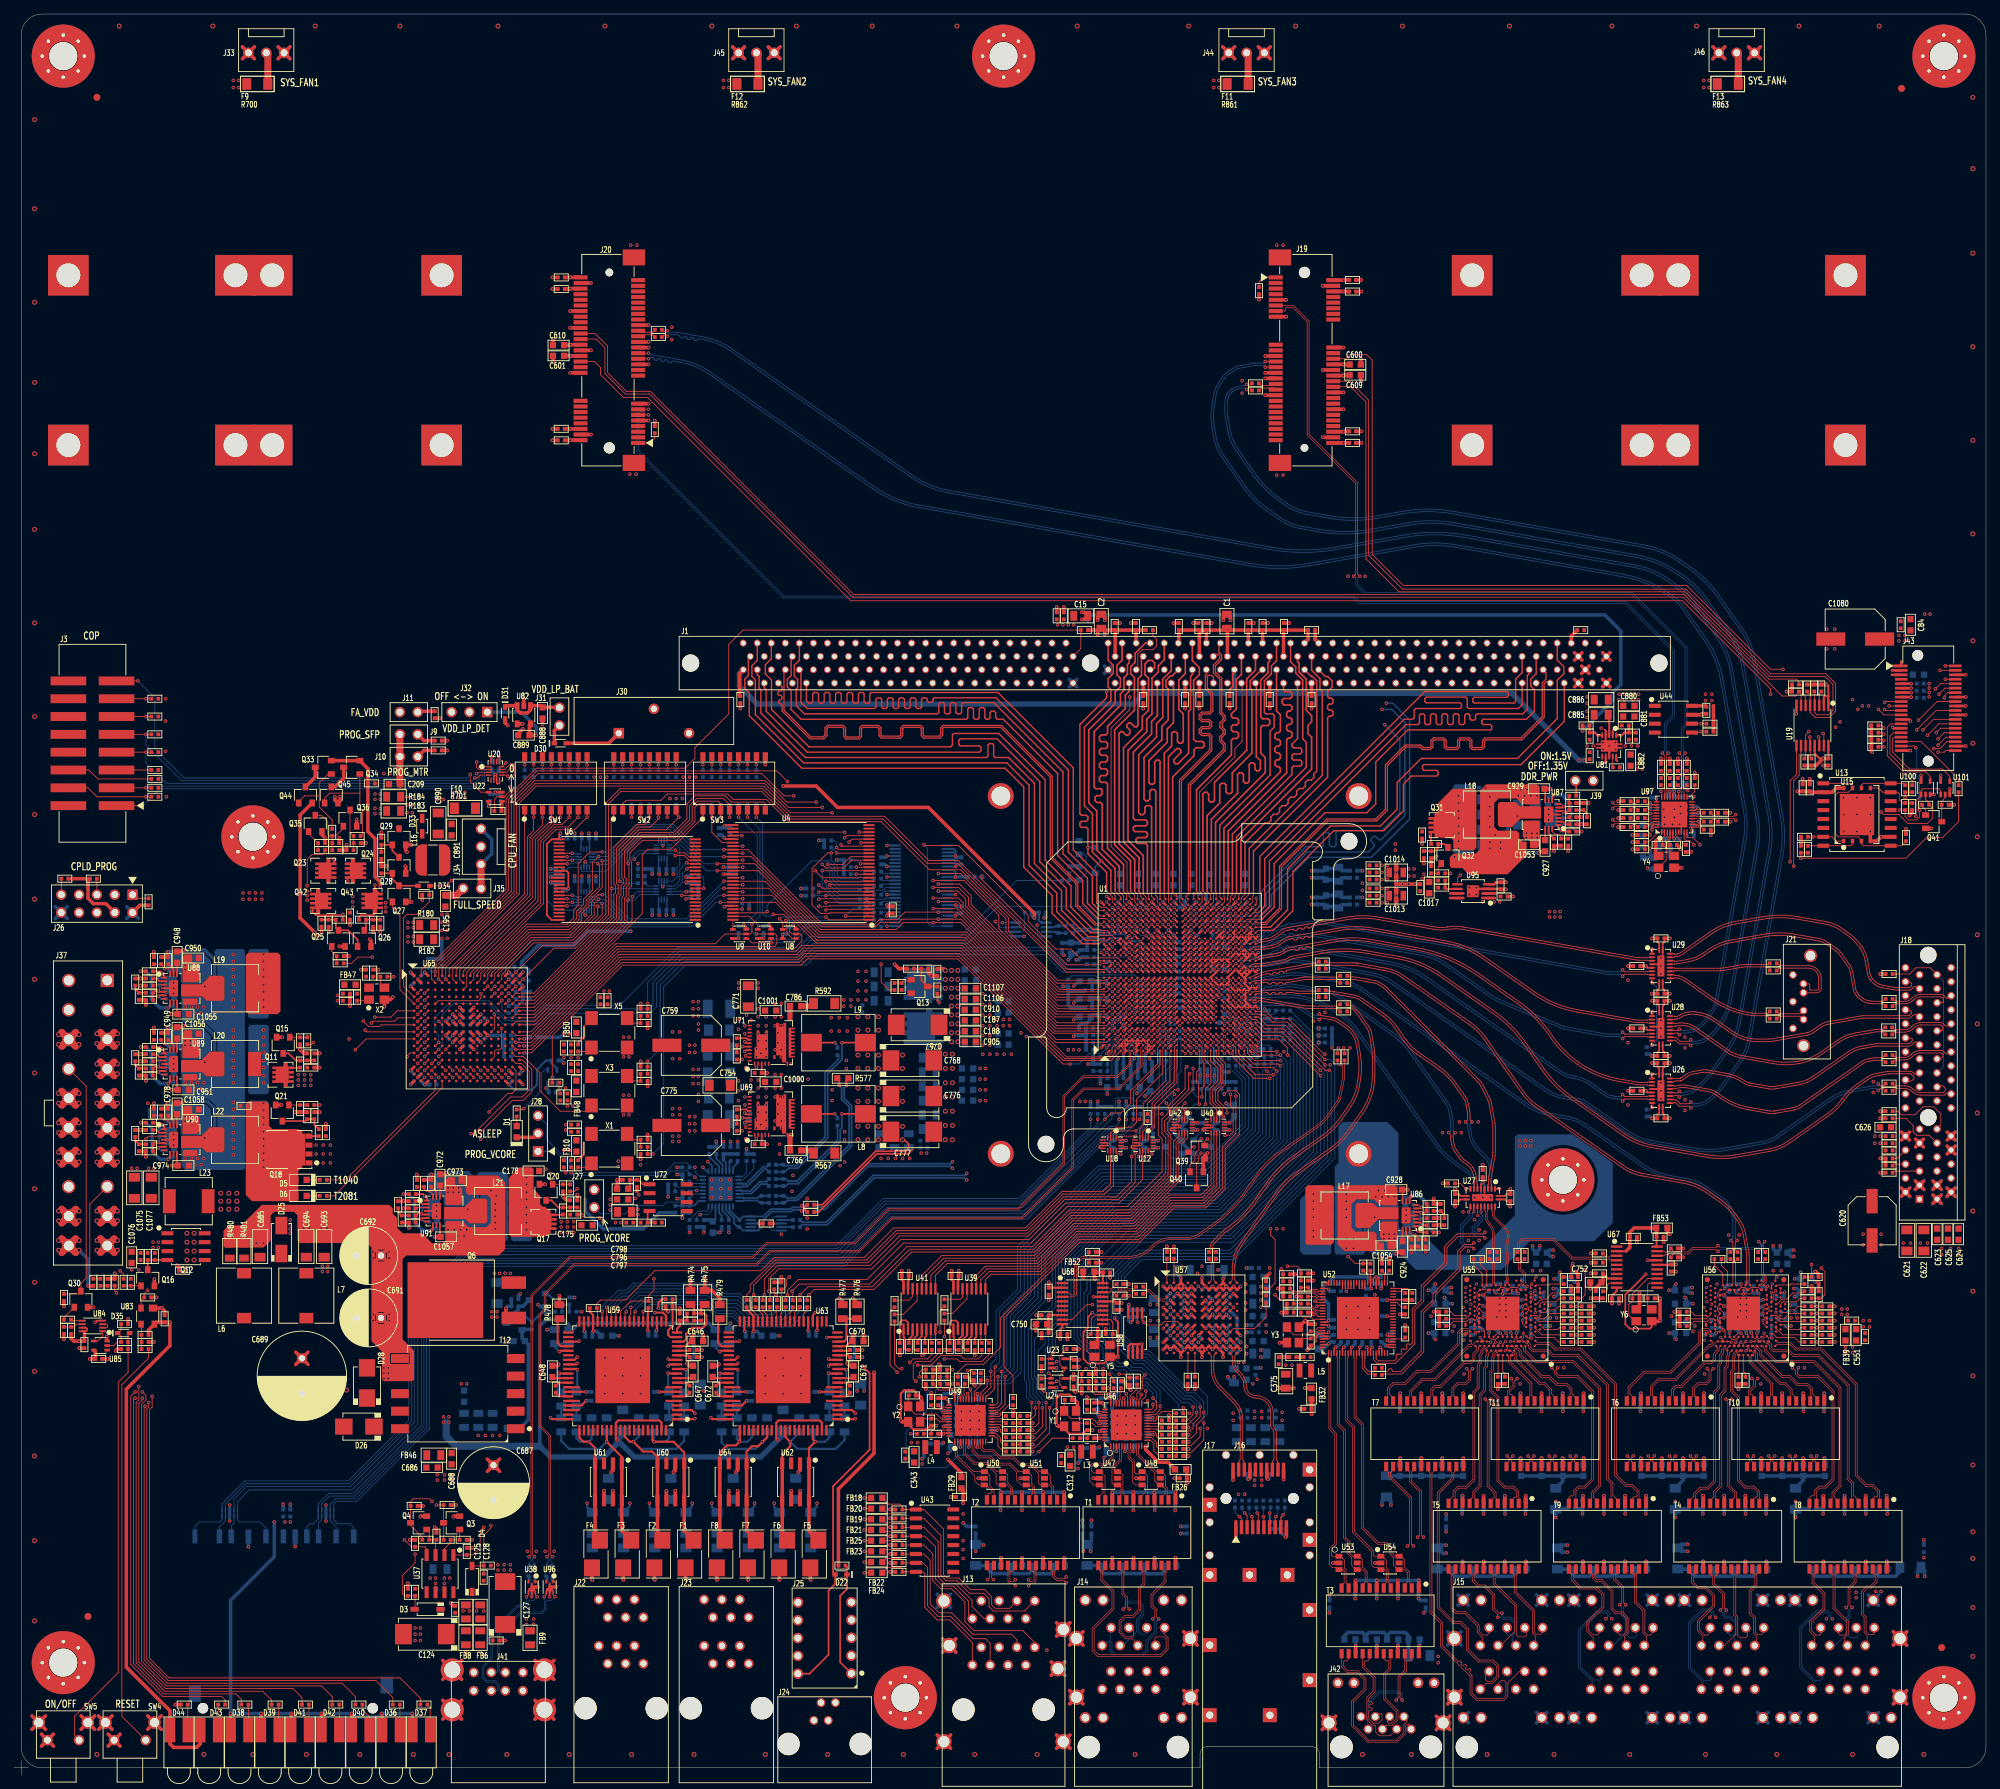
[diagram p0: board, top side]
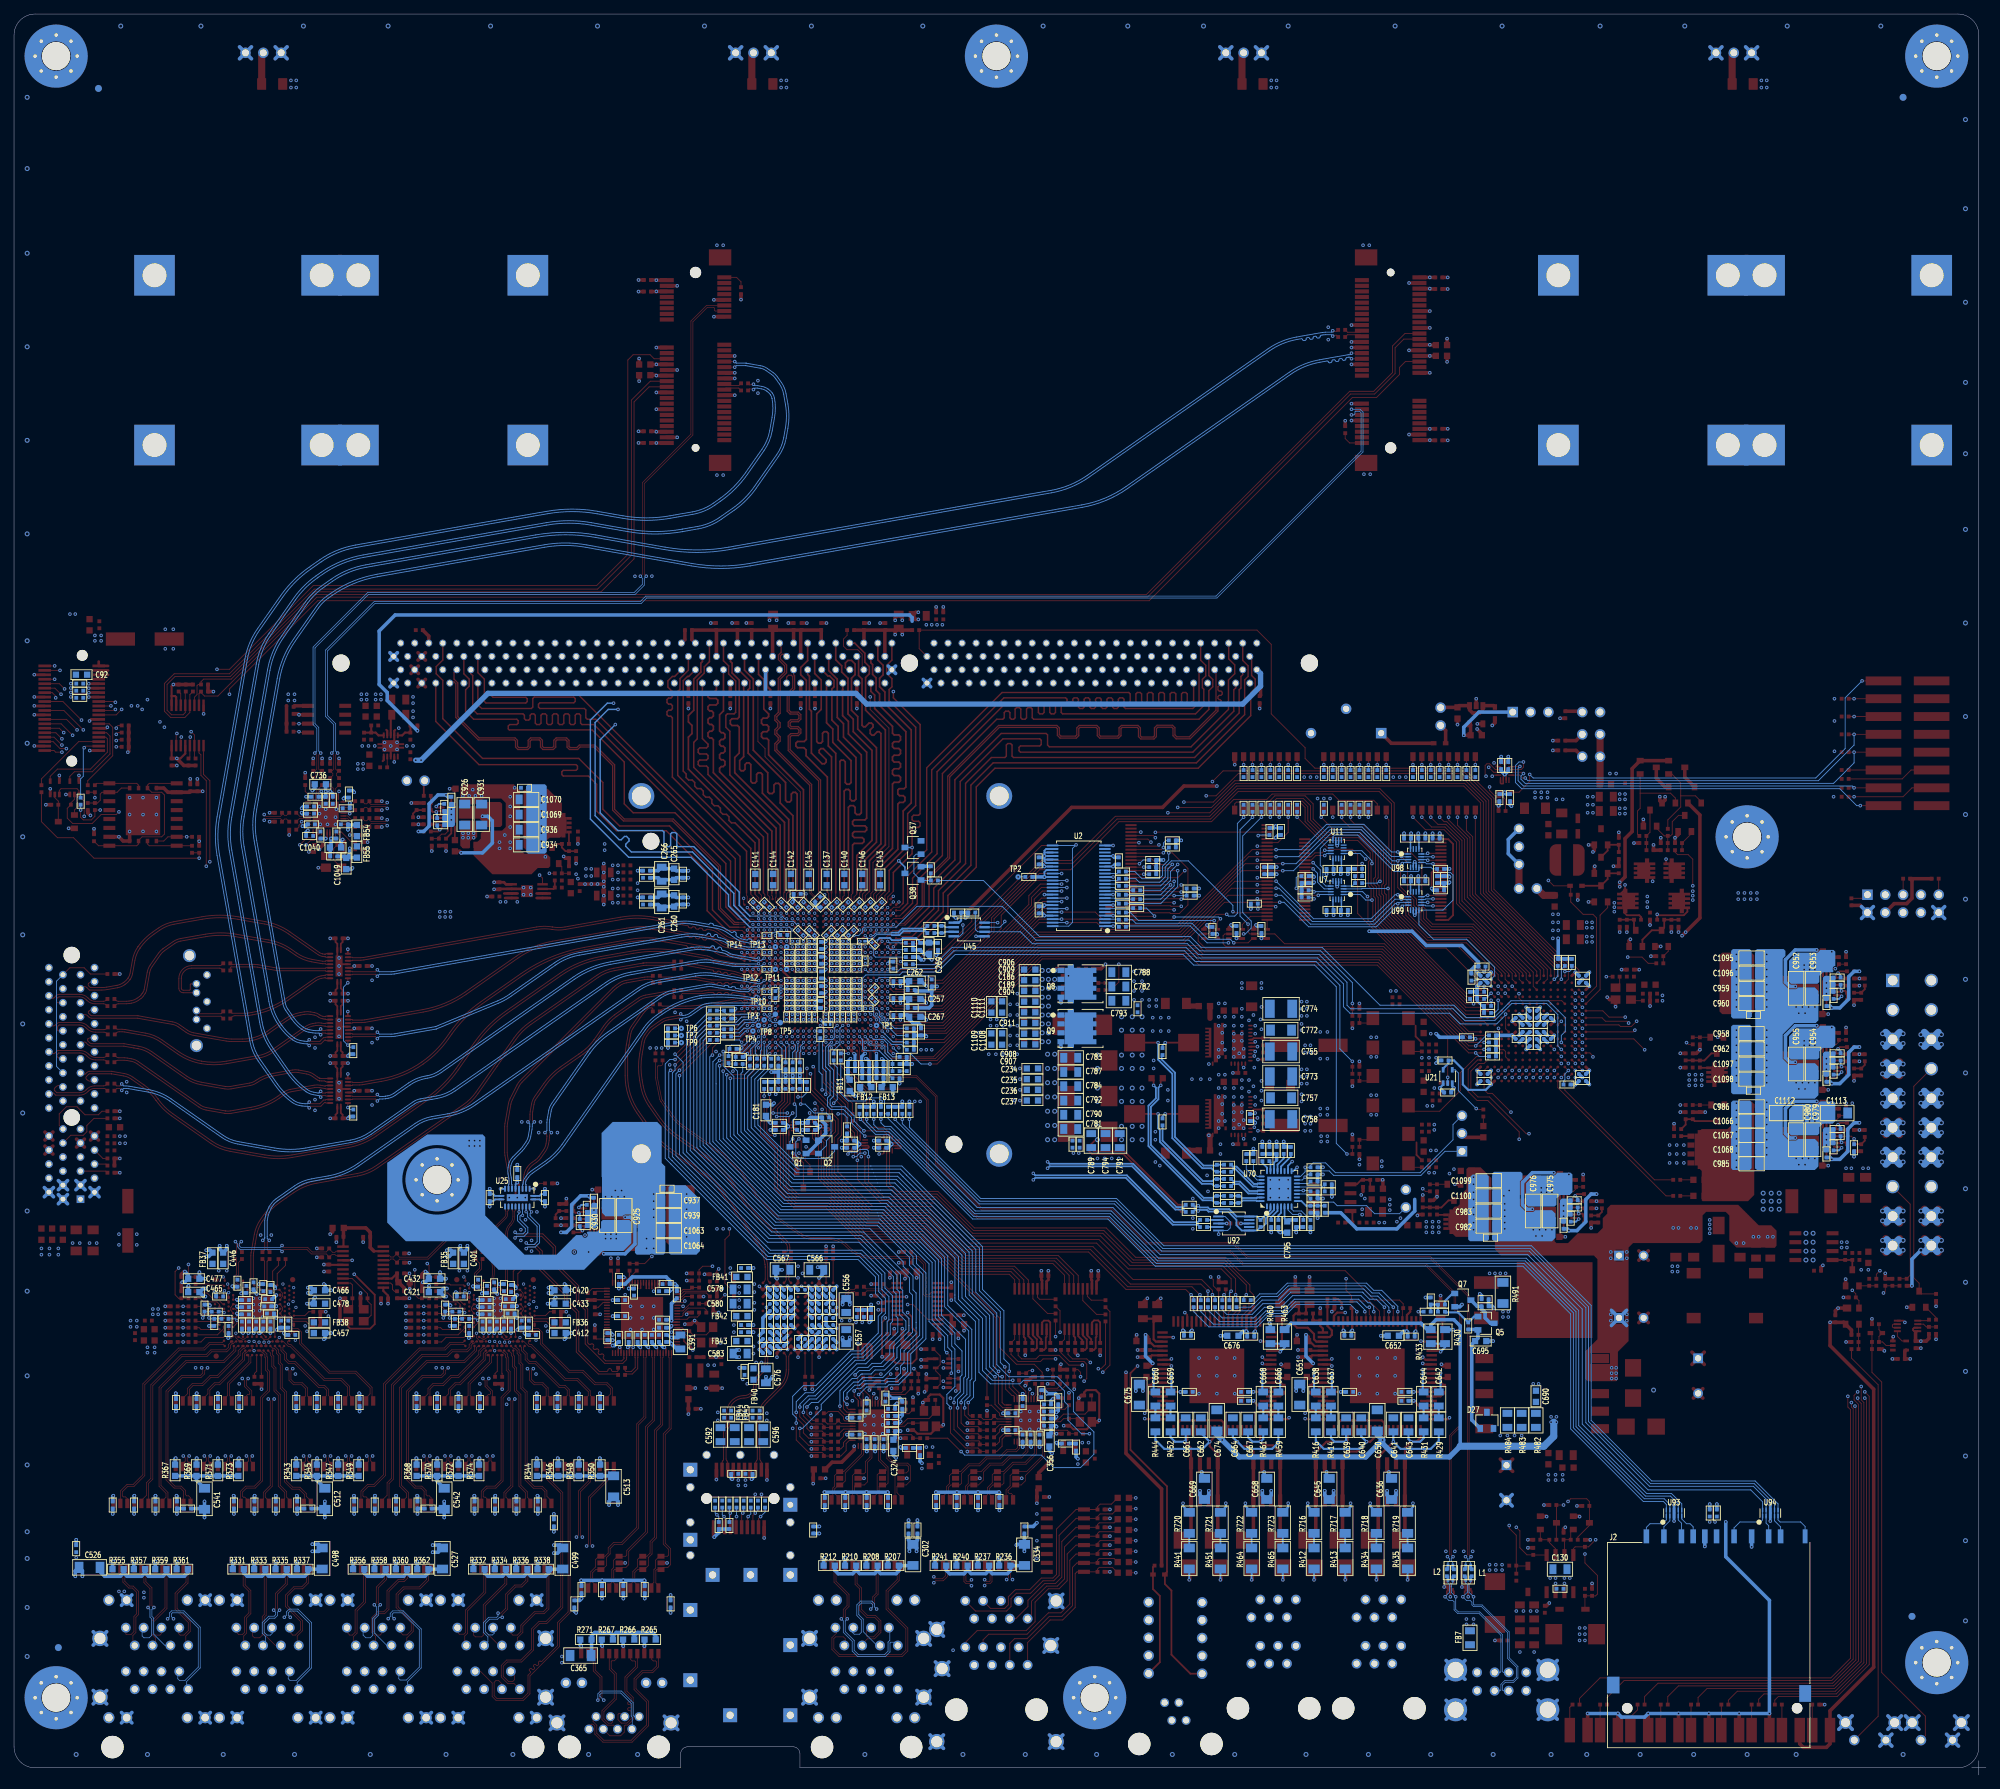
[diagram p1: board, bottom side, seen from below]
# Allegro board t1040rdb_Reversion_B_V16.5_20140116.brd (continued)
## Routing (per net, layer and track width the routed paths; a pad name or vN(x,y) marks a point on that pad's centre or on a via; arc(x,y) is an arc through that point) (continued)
DDR_MA11: length 39.5
  TOP w0.127: 160.31,125.93 160.51,125.73 160.51,125.25 U1.H28
  TOP w0.241: 160.31,125.93 160.31,130.77 158.11,132.97 158.11,146.43 160.78,149.1 160.78,150.88 161.67,151.76 161.67,156.34 161.16,156.84 161.16,158.37 161.67,158.88 162.18,158.88 162.54,158.51 162.54,157.84 162.25,157.55 J1.55
DDR_MA12: length 40.2
  TOP w0.127: U1.G28 160.12,125.55 159.71,125.96
  TOP w0.241: 159.71,125.96 159.71,130.48 157.48,132.72 157.48,148.46 157.73,148.72 157.99,148.72 158.5,148.21 158.75,148.21 159,148.46 159,148.97 158.6,149.37 158.6,149.71 158.83,149.94 159.17,149.94 159.7,149.42 159.96,149.42 160.17,149.63 160.17,156.23 160.66,156.73 160.66,159.19 J1.174
DDR_MA13: length 40.2
  TOP w0.127: U1.AE28 174.52,125.41 174.84,125.73
  TOP w0.241: 174.84,125.73 174.84,133.31 184.91,143.38 184.91,147.94 184.4,148.45 184.4,149.61 184.91,150.11 184.91,151 184.15,151.76 184.15,156.21 183.13,157.23 183.13,158.5 182.92,158.71 J1.196
DDR_MA14: length 41.3
  TOP w0.127: U1.E27 158.11,124.45 158.11,125.35 157.51,125.96
  TOP w0.241: J1.172 158.92,158.53 158.66,158.28 158.66,156.89 158.17,156.39 158.17,154.61 157.67,154.11 157.67,152.46 153.92,148.72 153.92,140.83 154.17,140.59 154.88,140.59 155.07,140.4 155.07,139.84 154.83,139.6 154.29,139.6 154.05,139.36 154.05,138.87 154.29,138.63 154.83,138.63 155.07,138.39 155.07,131.95 157.51,129.51 157.51,125.96
DDR_MA15: length 40.8
  TOP w0.127: 156.91,125.96 157.72,125.15 U1.D28
  TOP w0.241: J1.171 157.92,158.93 157.17,158.18 157.17,156.82 157.66,156.32 157.66,155.12 156.91,154.37 156.91,152.72 153.16,148.97 153.16,138.56 154.3,137.41 154.3,131.83 156.91,129.22 156.91,125.96
DDR_MAPAR_ERR: length 43.4
  TOP w0.127: v1(159,153.67) 159,151.89 156.34,149.22 156.34,132.33 158.61,130.06 158.61,125.96 158.91,125.65 158.91,125.25 U1.F28 ; R4.2 162.3,162.44 162.81,161.92 162.81,160.91 162.31,160.4 160.78,160.4 160.15,159.77 160.15,157.78 J1.53
  L6SIG w0.102: J1.53 159.92,154.58 v1(159,153.67)
DDR_MAPAR_OUT: length 34.5
  TOP w0.127: U1.V27 169.32,124.45 169.32,125.65 168.96,126.01 168.96,140.13 173.99,145.16 173.99,146.3 175.01,147.32 175.01,155.56 J1.68
DDR_MBA0: length 39.8
  TOP w0.127: U1.Y28 170.52,125.43 170.02,125.93
  TOP w0.241: 170.02,125.93 170.02,136.74 171.83,138.56 171.83,141.11 172.07,141.35 172.48,141.35 172.72,141.11 172.72,140.14 172.96,139.9 173.37,139.9 173.61,140.14 173.61,142.88 176.4,145.67 176.4,154.69 176.17,154.92 176.17,155.96 177.76,157.55 J1.71
DDR_MBA1: length 41
  TOP w0.127: 169.42,126.03 169.72,125.73 U1.W28
  TOP w0.241: 169.42,126.03 169.42,139.83 169.66,140.07 170,140.07 170.24,139.83 170.24,138.94 170.49,138.69 170.83,138.69 171.07,138.93 171.07,141.48 175.66,146.07 175.66,156.23 176.92,157.49 J1.190
DDR_MBA2: length 40.1
  TOP w0.127: 158.11,125.96 158.52,125.55 U1.E28
  TOP w0.241: J1.52 158.92,154.47 158.37,153.92 158.37,152.02 155.83,149.48 155.83,148.5 155.59,148.25 154.93,148.25 154.69,148.01 154.69,147.53 154.93,147.29 155.59,147.29 155.83,147.05 155.83,146.56 155.59,146.32 154.93,146.32 154.69,146.08 154.69,145.6 154.93,145.36 155.59,145.36 155.83,145.12 155.83,144.63 155.59,144.39 154.93,144.39 154.69,144.15 154.69,143.67 154.93,143.43 155.59,143.43 155.83,143.19 155.83,142.7 155.59,142.46 154.93,142.46 154.69,142.22 154.69,141.74 154.93,141.5 155.59,141.5 155.83,141.26 155.83,132.08 158.11,129.8 158.11,125.96
DDR_MCAS_N: length 39.8
  TOP w0.127: 173.02,125.73 173.02,125.35 172.92,125.25 U1.AC28
  TOP w0.241: 173.02,125.73 173.02,134.54 181.36,142.88 181.36,147.57 181.6,147.82 181.88,147.82 182.12,148.06 182.12,148.54 181.88,148.78 181.6,148.78 181.36,149.02 181.36,149.5 181.6,149.75 181.88,149.75 182.12,149.99 182.12,150.47 181.88,150.71 181.6,150.71 181.36,150.95 181.36,151.43 181.6,151.68 181.88,151.68 182.12,151.92 182.12,152.29 181.88,152.53 180.97,152.53 180.72,152.78 180.72,153.21 180.96,153.45 181.88,153.45 182.12,153.69 182.12,154.17 181.88,154.41 181.16,154.41 180.92,154.66 J1.74
DDR_MCK0_N: length 40.8
  TOP w0.102: 167.63,126.09 167.63,126.06 167.59,126.02 167.59,125.68 167.13,125.22 167.13,125.03 U1.T28
  TOP w0.178: 167.63,126.09 167.63,141.07 172.59,146.04 172.59,147.01 172.11,147.49 172.11,147.88 172.59,148.36 172.59,148.99 172.19,149.4 172.19,149.94 172.59,150.35 172.59,150.97 172.11,151.45 172.11,156.31 171.2,157.23 171.2,158.1 172.08,158.99 172.08,159.64 171.7,160.02 171.7,161.13 J1.185
DDR_MCK0_P: length 40.8
  TOP w0.102: 167.35,126.09 167.35,126.06 167.39,126.02 167.39,125.76 166.93,125.31 166.93,124.43 U1.T27
  TOP w0.178: 167.35,126.09 167.35,141.19 172.31,146.15 172.31,146.89 171.83,147.37 171.83,148 172.31,148.48 172.31,148.87 171.83,149.36 171.83,149.98 172.31,150.46 172.31,150.85 171.83,151.34 171.83,156.2 170.92,157.11 170.92,158.22 171.81,159.11 171.81,159.52 171.58,159.75 171.22,159.75 J1.184
DDR_MCK1_N: length 40.8
  TOP w0.102: U1.R28 166.32,125.04 166.32,125.9 166.36,125.94 166.36,125.96
  TOP w0.178: 166.36,125.96 166.36,141.71 170.69,146.04 170.69,148.1 170.35,148.44 169.37,148.44 169.16,148.64 169.16,148.95 169.37,149.15 170.35,149.15 170.69,149.49 170.69,150.08 170.35,150.42 169.37,150.42 169.16,150.62 169.16,151.03 169.37,151.23 170.42,151.23 170.84,151.65 170.84,154.15 170.05,154.94 170.05,156.58 170.24,156.76 170.65,156.76 170.92,156.49 J1.64
DDR_MCK1_P: length 40.8
  TOP w0.102: U1.R27 166.12,124.45 166.12,125.9 166.08,125.94 166.08,125.96
  TOP w0.178: 166.08,125.96 166.08,141.82 170.41,146.15 170.41,147.98 170.23,148.16 169.25,148.16 168.88,148.52 168.88,149.06 169.25,149.43 170.23,149.43 170.41,149.61 170.41,149.96 170.23,150.14 169.25,150.14 168.88,150.51 168.88,151.14 169.25,151.51 170.31,151.51 170.56,151.76 170.56,154.04 169.77,154.82 169.77,156.69 169.92,156.84 J1.63
DDR_MCKE0: length 39
  TOP w0.127: 155.71,125.96 156.51,125.15 156.51,124.45 U1.C27
  TOP w0.216: v1(155.7,154.43) 155.7,153.54 151.89,149.73 151.89,137.02 152.11,136.81 152.82,136.81 153.03,136.59 153.03,136.16 152.82,135.94 152.11,135.94 151.89,135.73 151.89,135.29 152.11,135.08 152.82,135.08 153.03,134.86 v1(153.03,132.21) 153.03,131.32 155.71,128.64 155.71,125.96
  L6SIG w0.216: v1(155.7,154.43) J1.50
  BOTTOM w0.216: Q37.3 v1(153.03,132.21)
DDR_MCKE1: length 42.8
  TOP w0.127: 156.31,125.96 156.92,125.35 U1.C28
  TOP w0.216: J1.169 155.92,158.92 156.65,158.18 156.65,157.02 155.91,156.28 155.91,155.11 156.31,154.71 156.31,153.13 152.53,149.35 152.53,138.18 153.67,137.03 153.67,131.57 v1(154.94,130.3) 156.31,128.93 156.31,125.96
  BOTTOM w0.216: Q38.3 154.06,129.42 v1(154.94,130.3)
DDR_MCS0_N: length 41.7
  TOP w0.127: 171.83,125.73 171.83,125.13 U1.AB28
  TOP w0.216: 171.83,125.73 171.83,135.38 179.01,142.56 179.01,148.78 179.58,149.35 179.58,151.04 179.36,151.26 178.4,151.26 178.18,151.47 178.18,155.95 179.18,156.95 179.18,158.1 179.92,158.83 J1.193
DDR_MCS1_N: length 40.3
  TOP w0.127: 173.62,125.73 173.62,125.45 173.32,125.15 173.32,124.45 U1.AC27
  TOP w0.216: 173.62,125.73 173.62,134.12 182.12,142.62 182.12,143.6 182.33,143.81 183.3,143.81 183.51,144.03 183.51,144.46 183.3,144.68 182.33,144.68 182.12,144.89 182.12,145.33 182.33,145.54 183.3,145.54 183.51,145.76 183.51,146.19 183.3,146.41 182.33,146.41 182.12,146.62 182.12,146.94 182.92,147.74 J1.76
DDR_MCS2_N: length 41.4
  TOP w0.127: 176.62,125.73 176.62,125.35 176.53,125.26 176.53,124.46 U1.AG27
  TOP w0.216: 176.62,125.73 176.62,131.67 187.2,142.24 187.2,150.7 187.41,150.92 187.74,150.92 187.96,151.14 187.96,151.57 187.74,151.78 187.41,151.78 187.2,152 187.2,152.43 187.41,152.65 187.74,152.65 187.96,152.86 187.96,153.29 187.74,153.51 187.41,153.51 187.2,153.73 187.2,154.43 187.83,155.07 187.83,155.96 187.2,156.59 186.87,156.59 J1.79
DDR_MCS3_N: length 39.8
  TOP w0.127: 176.02,125.73 176.02,125.55 U1.AF28
  TOP w0.216: 176.02,125.73 176.02,132.08 186.44,142.49 186.44,154.43 186.11,154.76 186.11,156.28 184.92,157.48 J1.198
DDR_MDM0: length 82.4
  TOP w0.127: U1.B22 155.77,120.4 154.94,120.4 154.81,120.52 154.43,120.52
  TOP w0.203: J1.125 107.92,159.1 107.06,158.24 107.06,156.97 107.95,156.08 107.95,151.89 113.28,146.56 133.48,146.56 133.73,146.81 133.73,148.26 133.93,148.46 140.33,148.46 146.94,141.86 146.94,130.43 150.62,126.75 150.62,123.7 153.8,120.52 154.43,120.52
DDR_MDM1: length 69.4
  TOP w0.127: U1.C25 v2(156.52,122.85)
  L3SIG w0.102: v2(156.52,122.85) 156.52,122.88 155.83,123.57 155.07,123.57 154.43,124.21
  L3SIG w0.203: 154.43,124.21 154.18,124.46 154.18,125.6 144.02,135.76 139.95,135.76 137.22,138.49 137.22,141.91 137.02,142.11 124.59,142.11 123.83,142.88 123.83,144.96 123.62,145.16 122.72,145.16 122.52,145.36 122.52,145.83 122.72,146.03 123.73,146.03 123.93,146.24 123.93,146.74 123.73,146.94 121.38,146.94 121.17,147.14 121.17,147.68 121.03,147.83 120.22,147.83 120.02,148.03 120.02,149.4 119.81,149.61 118.11,149.61 116.46,151.26 116.46,154.81 116.19,155.08 116.19,156.32 116.64,156.78 116.64,159.17 J1.134
DDR_MDM2: length 66.7
  TOP w0.127: U1.F23 v2(158.92,121.25)
  L6SIG w0.102: v2(158.92,121.25) 158.66,121.25 158.24,121.66 155.45,121.66 154.94,122.17 154.43,122.17
  L6SIG w0.203: J1.143 125.92,159.06 124.97,158.12 124.97,156.84 124.19,156.06 124.19,150.51 138.3,136.4 146.1,136.4 146.3,136.19 146.3,135.71 146.1,135.51 144.92,135.51 144.78,135.37 144.78,134.76 144.92,134.62 148.84,134.62 150.5,132.97 150.5,131.44 153.03,128.91 153.03,123.57 154.43,122.17
DDR_MDM3: length 56.3
  TOP w0.127: U1.K26 v2(162.12,123.65)
  L3SIG w0.102: v2(162.12,123.65) 161.53,124.23 161.53,125.73
  L3SIG w0.203: 161.53,125.73 161.53,128.07 160.1,129.51 160.1,133.02 155.07,138.05 155.07,140.51 154.86,140.72 154.3,140.72 154.18,140.59 154.18,139.84 153.97,139.64 153.49,139.64 153.29,139.84 153.29,141.99 144.75,150.52 135.74,150.52 135.51,150.75 135.51,152.53 134.62,153.42 134.62,154.69 134.37,154.94 134.37,154.97 134.18,155.16 134.18,156.15 134.92,156.89 J1.152
DDR_MDM4: length 57
  TOP w0.127: U1.U26 v2(168.52,123.65)
  L3SIG w0.102: 169.37,125.73 169.37,125.72 168.62,124.97 168.4,124.97 168.14,124.7 168.14,124.22 168.52,123.84 v2(168.52,123.65)
  L3SIG w0.203: 169.37,125.73 169.37,147.27 171.07,148.97 176.44,148.97 176.64,149.17 176.64,150.48 176.78,150.62 186.31,150.62 189.92,154.23 189.92,156.03 189.1,156.84 189.1,158.24 189.92,159.06 J1.203
DDR_MDM5: length 64.8
  TOP w0.127: U1.Y24 v2(170.92,122.05)
  L6SIG w0.203: J1.212 198.92,156.88 198.19,156.15 198.19,155.25 198.51,154.93 198.51,151.78 196.47,149.73 v1(195.33,149.73)
  BOTTOM w0.127: 176.15,122.43 175.09,122.43 175.08,122.44 173.15,122.44 173.14,122.43 172.69,122.43 172.68,122.44 171.55,122.44 171.16,122.05 v2(170.92,122.05)
  BOTTOM w0.203: 176.15,122.43 177.67,123.95 177.67,125.86 184.15,132.33 186.42,132.33 186.56,132.48 186.56,134.13 186.77,134.34 187.25,134.34 187.45,134.13 187.45,132.54 187.66,132.33 188.19,132.33 188.39,132.54 188.39,134.42 188.6,134.62 194.94,134.62 197.48,137.16 197.48,147.57 v1(195.33,149.73)
DDR_MDM6: length 65
  TOP w0.127: U1.AD24 v2(174.12,122.05)
  L3SIG w0.102: v2(174.12,122.05) 174.5,122.43 174.5,122.97 174.8,123.26 175.08,123.26 175.33,123.52 175.33,124.6 175.57,124.84 175.94,124.84 176.83,125.73
  L3SIG w0.203: J1.221 207.92,159.02 207.01,158.11 207.01,156.97 207.9,156.08 207.9,153.8 205.49,151.38 200.15,151.38 200.01,151.24 200.01,146.29 199.64,145.92 196.85,145.92 196.71,145.78 196.71,144.48 196.5,144.27 191.77,144.27 189.1,141.6 186.31,141.6 186.17,141.46 186.17,140.45 181.86,136.14 181.86,135.38 179.51,133.03 177.99,133.03 176.83,131.87 176.83,125.73
DDR_MDM7: length 72.5
  TOP w0.127: U1.AF24 175.37,121.65 175.71,121.99 177.8,121.99
  TOP w0.203: 177.8,121.99 177.83,121.99 179.58,123.73 179.58,129.92 186.82,137.16 192.79,137.16 194.06,138.43 194.06,144.4 198.63,148.97 210.44,148.97 210.58,149.11 210.58,149.53 210.38,149.73 209.37,149.73 209.17,149.94 209.17,150.29 209.37,150.5 215.52,150.5 216.66,151.64 216.66,154.69 216.15,155.19 216.15,156.21 216.92,156.97 J1.230
DDR_MDM8: length 52.3
  TOP w0.127: U1.N24 v2(164.52,122.05)
  L6SIG w0.102: 164.21,125.73 164.21,125.22 164.94,124.5 164.94,122.46 v2(164.52,122.05)
  L6SIG w0.203: 164.21,125.73 164.21,134.49 162.56,136.14 162.26,136.14 162.05,135.94 162.05,135.49 161.85,135.29 161.38,135.29 142.75,153.92 142.75,154.56 142.19,155.12 142.19,156.03 143.13,156.97 143.13,158.13 143.92,158.92 J1.161
DDR_MDQS0_N: length 82.3
  TOP w0.102: 154.04,121.15 154.05,121.14 155.02,121.14 U1.A23
  TOP w0.178: 154.04,121.15 151.32,123.87 151.32,127.06 147.68,130.71 147.68,142.25 140.6,149.33 132.51,149.33 132.33,149.15 132.33,148.19 131.94,147.8 129.62,147.8 129.28,148.14 129.28,149.15 129.11,149.33 126.82,149.33 126.64,149.15 126.64,148.14 126.3,147.8 123.61,147.8 123.26,148.14 123.26,149.15 123.09,149.33 120.95,149.33 120.78,149.15 120.78,148.02 120.43,147.68 118.56,147.68 118.22,148.02 118.22,149.15 118.02,149.35 116.04,149.35 115.86,149.17 115.86,148.14 115.41,147.7 113.41,147.7 109.45,151.66 109.45,152.51 109.27,152.68 109.14,152.68 108.97,152.86 108.97,153.11 109.14,153.29 109.27,153.29 109.45,153.47 109.45,153.72 109.27,153.9 109.02,153.9 108.84,154.07 108.84,154.33 109.02,154.5 109.27,154.5 109.45,154.68 109.45,155.11 J1.6
DDR_MDQS0_P: length 82.3
  TOP w0.102: U1.A24 155.02,121.35 154.24,121.35 154.2,121.39
  TOP w0.178: 154.2,121.39 151.6,123.99 151.6,127.18 147.95,130.82 147.95,142.37 140.72,149.61 132.4,149.61 132.05,149.26 132.05,148.31 131.83,148.08 129.74,148.08 129.56,148.26 129.56,149.26 129.22,149.61 126.71,149.61 126.37,149.26 126.37,148.26 126.19,148.08 123.72,148.08 123.54,148.26 123.54,149.26 123.2,149.61 120.84,149.61 120.5,149.26 120.5,148.13 120.32,147.95 118.68,147.95 118.5,148.13 118.5,149.26 118.13,149.63 115.92,149.63 115.58,149.29 115.58,148.26 115.3,147.98 113.53,147.98 109.73,151.78 109.73,157.36 J1.7
DDR_MDQS1_N: length 69.3
  TOP w0.127: U1.D25 v2(157.32,122.85)
  L3SIG w0.102: 156.58,124.8 156.58,124.77 156.59,124.76 156.59,124.28 156.9,123.98 156.9,123.26 v2(157.32,122.85)
  L3SIG w0.178: 156.58,124.8 156.58,125.11 154.41,127.28 154.41,127.79 143.64,138.56 143.64,140.51 140.41,143.74 126.07,143.74 125.73,144.08 125.73,148.68 125.55,148.85 123.12,148.85 122.76,149.22 122.76,150.19 123.1,150.53 125.61,150.53 125.79,150.71 125.79,151.39 125.66,151.52 118.97,151.52 118.49,152 118.49,154.81 118.11,155.19 118.11,157.35 J1.15
DDR_MDQS1_P: length 69.4
  TOP w0.127: U1.D26 v2(157.32,123.65)
  L3SIG w0.102: 156.86,124.74 156.79,124.67 156.79,124.37 157.1,124.06 157.1,123.86 v2(157.32,123.65)
  L3SIG w0.178: J1.16 118.92,156.53 119.09,156.7 119.39,156.7 119.76,156.34 119.76,155.19 118.77,154.2 118.77,152.12 119.09,151.8 125.78,151.8 126.07,151.51 126.07,150.59 125.73,150.25 123.21,150.25 123.04,150.07 123.04,149.34 123.24,149.13 125.67,149.13 126.01,148.79 126.01,144.2 126.19,144.02 140.53,144.02 143.92,140.63 143.92,138.67 154.68,127.9 154.68,127.4 156.86,125.22 156.86,124.74
DDR_MDQS2_N: length 66.6
  TOP w0.127: U1.G23 v2(159.72,121.25)
  L6SIG w0.102: 158.8,125.38 158.8,125.36 158.83,125.32 158.83,125.05 158.54,124.75 158.54,122.69 158.76,122.46 159.07,122.46 159.34,122.2 159.34,121.89 159.72,121.51 v2(159.72,121.25)
  L6SIG w0.178: J1.24 127.58,155.65 127.76,155.47 127.76,150.73 130.31,148.18 135.01,148.18 135.14,148.06 135.14,147.09 135.01,146.96 133.74,146.96 133.45,146.67 133.45,145.48 133.79,145.14 136.32,145.14 136.5,144.96 136.5,143.6 136.84,143.26 138.03,143.26 138.37,143.6 138.37,145.36 138.55,145.54 139.62,145.54 139.8,145.36 139.8,143.6 140.14,143.26 141.28,143.26 141.62,143.6 141.62,145.12 141.8,145.3 142.21,145.3 155.82,131.7 155.82,128.54 158.8,125.56 158.8,125.38
DDR_MDQS2_P: length 66.7
  TOP w0.127: U1.G24 v2(159.72,122.05)
  L6SIG w0.102: 159.07,125.38 159.07,125.36 159.04,125.32 159.04,125.05 159.34,124.75 159.34,122.61 159.72,122.22 v2(159.72,122.05)
  L6SIG w0.178: 159.07,125.38 159.07,125.67 156.1,128.65 156.1,131.81 142.33,145.58 141.68,145.58 141.34,145.24 141.34,143.71 141.16,143.54 140.26,143.54 140.08,143.71 140.08,145.48 139.74,145.82 138.43,145.82 138.09,145.48 138.09,143.71 137.91,143.54 136.96,143.54 136.78,143.71 136.78,145.07 136.44,145.41 133.91,145.41 133.73,145.59 133.73,146.56 133.86,146.69 135.13,146.69 135.42,146.97 135.42,148.17 135.13,148.46 130.43,148.46 128.04,150.85 128.04,155.58 127.77,155.86 127.77,157.4 J1.25
DDR_MDQS3_N: length 56.9
  TOP w0.127: U1.K25 v2(162.12,122.85)
  L3SIG w0.102: v2(162.12,122.85) 162.54,123.26 162.54,123.93
  L3SIG w0.178: J1.33 136.14,157.32 136.14,156.57 135.76,156.19 135.76,153.91 136.5,153.17 136.5,151.92 137.2,151.22 145.71,151.22 147.09,149.83 147.58,149.83 148.28,150.54 148.53,150.54 149.28,149.8 149.28,149.54 148.51,148.78 148.51,148.29 149.32,147.48 149.8,147.48 150.57,148.25 150.82,148.25 151.58,147.49 151.58,147.23 150.94,146.59 150.94,146.11 156.21,140.84 156.21,138.45 160.79,133.87 160.79,129.8 162.28,128.31 162.28,125.23 162.69,124.83 162.69,124.08 162.54,123.93
DDR_MDQS3_P: length 56.8
  TOP w0.127: U1.L25 v2(162.92,122.85)
  L3SIG w0.102: v2(162.92,122.85) 163.3,123.23 163.3,123.8 162.97,124.13
  L3SIG w0.178: 162.97,124.13 162.97,124.94 162.56,125.35 162.56,128.43 161.07,129.91 161.07,133.98 156.49,138.57 156.49,140.96 151.22,146.23 151.22,146.48 151.86,147.12 151.86,147.6 150.94,148.53 150.46,148.53 149.69,147.76 149.44,147.76 148.79,148.41 148.79,148.66 149.55,149.43 149.55,149.91 148.65,150.82 148.17,150.82 147.46,150.11 147.21,150.11 145.82,151.5 137.31,151.5 136.78,152.03 136.78,153.29 136.04,154.03 136.04,156.07 136.31,156.34 136.72,156.34 136.92,156.14 J1.34
DDR_MDQS4_N: length 56.6
  TOP w0.127: U1.V25 v2(169.32,122.85)
  L3SIG w0.102: v2(169.32,122.85) 169.32,123.06 168.9,123.48 168.9,123.81 169.22,124.13 169.22,124.69 169.18,124.73 169.18,124.74
  L3SIG w0.178: J1.84 190.92,156.25 191.13,156.46 191.39,156.46 191.74,156.11 191.74,154.66 186.69,149.61 178.27,149.61 177.93,149.26 177.93,147.88 177.75,147.7 174.97,147.7 174.62,147.36 174.62,146.23 174.45,146.05 173.15,146.05 172.97,146.23 172.97,147.36 172.63,147.7 171.18,147.7 170.69,147.21 170.69,137.17 170.14,136.63 170.14,125.82 169.18,124.86 169.18,124.74
DDR_MDQS4_P: length 56.7
  TOP w0.127: U1.W25 v2(170.12,122.85)
  L3SIG w0.102: 169.46,124.74 169.42,124.7 169.42,124.08 169.7,123.8 169.7,123.26 v2(170.12,122.85)
  L3SIG w0.178: J1.85 191.59,157.22 191.59,156.66 192.02,156.22 192.02,154.54 186.81,149.33 178.38,149.33 178.21,149.15 178.21,147.76 177.87,147.42 175.08,147.42 174.9,147.24 174.9,146.11 174.56,145.77 173.04,145.77 172.69,146.11 172.69,147.24 172.52,147.42 171.3,147.42 170.97,147.09 170.97,137.06 170.42,136.51 170.42,125.7 169.46,124.74
DDR_MDQS5_N: length 65.3
  TOP w0.127: U1.Y23 v2(170.92,121.25)
  L6SIG w0.102: 171.56,125.45 171.56,125.43 171.6,125.39 171.6,124.99 171.3,124.69 171.3,121.63 v2(170.92,121.25)
  L6SIG w0.178: 171.56,125.45 171.56,127.36 172.34,128.14 172.34,141.1 180.09,148.84 181.46,148.84 181.64,149.02 181.64,150.41 181.98,150.75 183.71,150.75 184.05,150.41 184.05,149.02 184.23,148.84 185.6,148.84 185.78,149.02 185.78,150.41 186.12,150.75 187.85,150.75 188.19,150.41 188.19,149.02 188.37,148.84 196.98,148.84 199.77,151.64 199.77,156.22 200.02,156.48 200.02,157.44 J1.93
DDR_MDQS5_P: length 65.3
  TOP w0.127: U1.AA23 v2(171.72,121.25)
  L6SIG w0.102: v2(171.72,121.25) 171.72,121.3 172.1,121.68 172.1,124.7 171.8,125 171.8,125.39 171.84,125.43 171.84,125.45
  L6SIG w0.178: J1.94 200.92,156.08 200.6,156.39 200.34,156.39 200.05,156.11 200.05,151.52 197.09,148.56 188.26,148.56 187.91,148.91 187.91,150.29 187.74,150.47 186.24,150.47 186.06,150.29 186.06,148.91 185.72,148.56 184.12,148.56 183.77,148.91 183.77,150.29 183.6,150.47 182.1,150.47 181.92,150.29 181.92,148.91 181.58,148.56 180.2,148.56 172.62,140.98 172.62,128.03 171.84,127.25 171.84,125.45
DDR_MDQS6_N: length 65.3
  TOP w0.127: U1.AF25 v2(175.72,122.85)
  L3SIG w0.102: 177.21,123.61 177.19,123.6 177.19,123.58 176.24,122.63 175.93,122.63 v2(175.72,122.85)
  L3SIG w0.178: 177.21,123.61 177.93,124.33 177.93,129.92 185.19,137.19 186.49,137.19 186.67,137.36 186.67,138.6 187.01,138.94 188.63,138.94 188.98,138.6 188.98,137.36 189.15,137.19 194.07,137.19 194.31,137.43 194.31,142.53 194.65,142.88 198.07,142.88 198.25,143.05 198.25,144.06 198.61,144.42 201.18,144.42 201.4,144.64 201.4,149.67 201.74,150.01 205.77,150.01 209.8,154.05 209.8,156.58 209.54,156.84 209.04,156.84 208.66,156.46 208.66,155.9 J1.102
DDR_MDQS6_P: length 65.3
  TOP w0.127: U1.AE25 v2(174.92,122.85)
  L3SIG w0.102: v2(174.92,122.85) 175.33,122.43 176.32,122.43 177.27,123.37 177.36,123.37
  L3SIG w0.178: 177.36,123.37 178.21,124.22 178.21,129.81 185.31,136.91 186.61,136.91 186.95,137.25 186.95,138.48 187.13,138.66 188.52,138.66 188.7,138.48 188.7,137.25 189.04,136.91 194.18,136.91 194.59,137.31 194.59,142.42 194.77,142.6 198.19,142.6 198.53,142.94 198.53,143.94 198.73,144.14 201.29,144.14 201.68,144.53 201.68,149.56 201.85,149.73 205.88,149.73 210.08,153.94 210.08,156.69 209.92,156.86 J1.103
DDR_MDQS7_N: length 72.4
  TOP w0.102: U1.AH24 177.07,121.49 177.74,121.49 177.77,121.53 177.8,121.53
  TOP w0.178: 177.8,121.53 178.3,121.53 180.34,123.57 180.34,129.54 187.07,136.27 194.06,136.27 195.43,137.64 195.43,143.99 198.25,146.81 200.46,146.81 200.81,146.46 201.75,146.46 201.93,146.63 201.93,147.49 202.27,147.83 203.76,147.83 204.1,147.49 204.1,146.63 204.27,146.46 205.54,146.46 205.71,146.63 205.71,147.49 206.06,147.83 207.41,147.83 207.75,147.49 207.75,146.63 207.92,146.46 209.09,146.46 209.27,146.63 209.27,147.49 209.61,147.83 214.74,147.83 217.78,150.86 217.78,155.68 218.31,156.21 218.31,157.15 J1.111
DDR_MDQS7_P: length 72.5
  TOP w0.102: 177.8,121.25 177.77,121.25 177.74,121.29 176.48,121.29 U1.AG24
  TOP w0.178: J1.112 218.92,155.65 218.74,155.83 218.33,155.83 218.06,155.56 218.06,150.75 214.86,147.55 209.73,147.55 209.55,147.37 209.55,146.52 209.21,146.18 207.81,146.18 207.47,146.52 207.47,147.37 207.29,147.55 206.17,147.55 205.99,147.37 205.99,146.52 205.65,146.18 204.16,146.18 203.82,146.52 203.82,147.37 203.64,147.55 202.39,147.55 202.21,147.37 202.21,146.52 201.87,146.18 200.7,146.18 200.34,146.53 198.36,146.53 195.71,143.88 195.71,137.53 194.17,135.99 187.19,135.99 180.62,129.42 180.62,123.46 178.41,121.25 177.8,121.25
DDR_MDQS8_N: length 52.8
  TOP w0.178: U1.P23 v2(165.32,121.25)
  L6SIG w0.102: 165.99,124.94 165.99,124.83 166.03,124.79 166.03,121.41 165.86,121.25 v2(165.32,121.25)
  L6SIG w0.178: 165.99,124.94 165.99,135.24 159.26,141.97 159.01,141.97 158.36,141.33 157.88,141.33 156.96,142.25 156.96,142.74 157.6,143.38 157.6,143.63 156.97,144.26 156.72,144.26 156.07,143.62 155.58,143.62 154.53,144.67 154.53,145.15 155.18,145.8 155.18,146.05 154.7,146.53 152.72,146.53 152.37,146.87 152.37,148.39 152.2,148.56 150.38,148.56 145.67,153.27 145.67,154.64 145.49,154.81 144.65,154.81 144.14,155.32 144.14,155.69 144.32,155.87 144.69,155.87 J1.42
DDR_MDQS8_P: length 52.8
  TOP w0.178: U1.R23 v2(166.92,121.25)
  L6SIG w0.102: v2(166.92,121.25) 166.4,121.25 166.23,121.41 166.23,124.88 166.27,124.92 166.27,124.94
  L6SIG w0.178: J1.43 145.67,157.3 145.67,155.07 145.95,154.79 145.95,153.39 150.5,148.84 152.31,148.84 152.65,148.5 152.65,146.99 152.83,146.81 154.81,146.81 155.46,146.16 155.46,145.68 154.81,145.03 154.81,144.78 155.69,143.9 155.96,143.9 156.6,144.54 157.08,144.54 157.88,143.75 157.88,143.26 157.24,142.62 157.24,142.37 158,141.61 158.25,141.61 158.89,142.25 159.37,142.25 166.27,135.36 166.27,124.94
DDR_MODT0: length 41.7
  TOP w0.127: 174.22,125.73 174.02,125.53 174.02,125.15 U1.AD28
  TOP w0.216: J1.195 181.92,158.7 182.65,157.96 182.65,157.07 183.65,156.07 183.65,147.69 184.15,147.19 184.15,143.64 174.22,133.71 174.22,125.73
DDR_MODT1: length 40.7
  TOP w0.127: 175.42,125.73 175.42,125.55 174.88,125.01 174.88,124.41 U1.AE27
  TOP w0.216: 175.42,125.73 175.42,132.88 178.26,135.72 178.77,135.72 179.13,136.07 179.13,136.58 179.48,136.94 179.99,136.94 180.35,137.3 180.35,137.8 180.71,138.16 181.21,138.16 181.57,138.52 181.57,139.03 181.93,139.38 182.44,139.38 182.79,139.74 182.79,140.25 183.15,140.61 183.66,140.61 184.01,140.96 184.01,141.47 184.37,141.83 184.88,141.83 185.24,142.18 185.24,142.69 185.65,143.11 185.65,155.98 185.04,156.59 184.87,156.59 J1.77
DDR_MRAS_N: length 40.3
  TOP w0.127: U1.AA28 171.32,125.73 171.22,125.83
  TOP w0.241: J1.192 178.92,158.72 178.69,158.5 178.69,157.1 177.67,156.08 177.67,150.81 177.91,150.56 178.7,150.56 178.94,150.32 178.94,149.84 178.7,149.6 177.91,149.6 177.67,149.36 177.67,145.67 178.31,145.03 178.31,142.88 171.22,135.79 171.22,125.83
DDR_MWE_N: length 40.1
  TOP w0.127: U1.AB27 172.52,124.45 172.52,125.05 172.42,125.15 172.42,125.73
  TOP w0.241: J1.73 179.92,151.68 180.47,151.13 180.47,148.81 180.23,148.57 179.95,148.57 179.7,148.33 179.7,147.85 179.95,147.61 180.23,147.61 180.47,147.37 180.47,146.88 180.23,146.64 179.95,146.64 179.7,146.4 179.7,145.92 179.95,145.68 180.23,145.68 180.47,145.44 180.47,144.95 180.23,144.71 179.95,144.71 179.7,144.47 179.7,143.99 179.95,143.75 180.23,143.75 180.47,143.51 180.47,143 172.42,134.96 172.42,125.73
DDR_REFCLK: length 82.8
  TOP w0.127: R517.2 R518.2 v1(90.29,109.97) ; U1.J21 v2(161.32,119.65)
  BOTTOM w0.127: v1(90.29,109.97) 90.29,112.94 94.83,117.48 112.06,117.48 113.58,119 135.38,119 140.21,123.83 152.33,123.83 155.31,120.85 159.87,120.85 160.12,120.6 160.12,120.17 160.64,119.65 v2(161.32,119.65)
DDR_RST_N: length 133.4
  TOP w0.127: U65.A2 58.02,114.74 58.46,115.19 59.05,115.19 70.12,126.25 70.12,139.21 74.42,143.51 95.63,143.51 97.03,144.91 97.03,146.43 101.85,151.26 101.85,161.16 103.89,163.19 R2.2 152.03,160.56 J1.168
DDRPWR_EN_N: length 394.9
  TOP w0.127: R785.1 v1(204.72,128.52) ; U65.R4 60.02,99.92 v1(60.51,99.42)
  L6SIG w0.102: v1(60.51,99.42) 60.51,98.24 68.96,89.79 68.96,85.22 70.87,83.31 70.87,78.74 72.52,77.09 75.95,77.09 77.22,75.82 93.73,75.82 94.49,75.06 153.22,75.06 154.49,76.33 167.39,76.33 167.77,75.95 182.24,75.95 183.39,74.8 186.44,74.8 189.1,72.14 191.75,72.14 192.51,72.9 210.42,72.9 214.86,77.34 226.31,77.34 228.22,79.25 274.17,79.25 277.75,82.83 277.75,143.38 276.1,145.03 276.1,148.59 272.29,152.4 269.62,152.4 267.46,154.56 260.1,154.56 243.33,137.79 243.33,133.86 239.52,130.05 215.9,130.05 214.88,129.03 205.23,129.03 v1(204.72,128.52)
DIFSYSCLK_OE_N: length 381.3
  TOP w0.127: U65.N15 71.02,101.93 71.52,101.42 72.31,101.42 73.41,100.33 73.41,97.66 72.39,96.65 70.75,96.65 65.52,91.41 v1(65.12,91.41) ; R844.2 v1(233.17,133.98) 233.17,134.24 232.92,134.49 232.92,135.25 233.57,135.91 U97.38
  L6SIG w0.102: v1(65.12,91.41) 65.12,89.19 68.2,86.11 68.2,84.84 70.1,82.93 70.1,78.36 72.14,76.33 75.57,76.33 76.84,75.06 93.34,75.06 94.11,74.3 153.43,74.3 154.19,75.06 155.7,75.06 155.96,74.8 182.25,74.8 183.01,74.04 186.05,74.04 188.72,71.37 192.06,71.37 192.83,72.14 210.73,72.14 215.18,76.58 226.69,76.58 228.6,78.49 274.49,78.49 278.48,82.47 278.48,143.8 276.86,145.41 276.86,152.65 273.43,156.08 260.48,156.08 245.49,141.1 234.31,141.1 232.16,138.94 232.16,135 v1(233.17,133.98)
EARTH: length 693.3
  TOP w0.508: 204.31,10.13 J15.97 ; J15.97 204.31,12.04 ; J15.97 206.22,12.04 ; J15.97 206.22,10.13 ; J14.25 152.34,12.04 ; J14.25 150.43,10.13 ; J14.25 150.43,12.04 ; J14.25 152.34,10.13 ; 166.69,12.04 J14.26 ; J14.26 168.6,12.04 ; J14.26 166.69,10.13 ; J14.26 168.6,10.13 ; 267.82,20.42 J15.100 ; J15.100 269.73,18.51 ; J15.100 267.82,18.51 ; J15.100 269.73,20.42 ; 61.1,7.95 J41.9 ; J41.9 61.1,10.64 ; J41.9 63.79,7.95 ; J41.9 63.79,10.64 ; 186.43,6.47 J42.13 ; J42.13 188.34,6.47 ; J42.13 188.34,8.38 ; J42.13 186.43,8.38 ; 166.69,18.51 J14.28 ; J14.28 168.6,18.51 ; J14.28 166.69,20.42 ; J14.28 168.6,20.42 ; J41.11 63.79,13.63 ; J41.11 61.1,16.32 ; J41.11 63.79,16.32 ; J41.11 61.1,13.63 ; J13.22 150.48,5.7 ; J13.22 148.57,5.7 ; J13.22 148.57,3.79 ; J13.22 150.48,3.79 ; 147.81,16.11 J13.20 ; J13.20 149.72,14.2 ; J13.20 147.81,14.2 ; J13.20 149.72,16.11 ; J13.19 134.23,17.5 ; J13.19 132.32,17.5 ; J13.19 132.32,19.41 ; J13.19 134.23,19.41 ; 267.82,10.13 J15.98 ; J15.98 267.82,12.04 ; J15.98 269.73,12.04 ; J15.98 269.73,10.13 ; J13.21 133.47,5.7 ; J13.21 131.56,3.79 ; J13.21 131.56,5.7 ; J13.21 133.47,3.79 ; 74.24,16.32 J41.12 ; J41.12 76.93,13.63 ; J41.12 74.24,13.63 ; J41.12 76.93,16.32 ; 148.57,21.7 J13.18 ; J13.18 148.57,19.79 ; J13.18 150.48,21.7 ; 74.24,10.64 J41.10 ; J41.10 76.93,10.64 ; J41.10 76.93,7.95 ; J41.10 74.24,7.95 ; J14.27 152.34,20.42 ; J14.27 152.34,18.51 ; J14.27 150.43,18.51 ; J42.14 204.6,6.47 ; J42.14 202.69,8.38 ; J42.14 202.69,6.47 ; J42.14 204.6,8.38
  L2GND w0.508: J42.13 188.34,8.38 ; J42.13 186.43,8.38 ; J42.13 186.43,6.47 ; J42.13 188.34,6.47 ; J41.12 76.93,16.32 ; J41.12 74.24,16.32 ; J41.12 74.24,13.63 ; J41.12 76.93,13.63 ; J14.26 168.6,10.13 ; J14.26 166.69,10.13 ; J14.26 168.6,12.04 ; J14.26 166.69,12.04 ; J41.10 76.93,7.95 ; J41.10 76.93,10.64 ; J41.10 74.24,10.64 ; J41.10 74.24,7.95 ; J42.14 204.6,6.47 ; J42.14 204.6,8.38 ; J42.14 202.69,8.38 ; J42.14 202.69,6.47 ; J13.20 149.72,14.2 ; J13.20 147.81,14.2 ; J13.20 149.72,16.11 ; J13.20 147.81,16.11 ; 61.1,10.64 J41.9 ; J41.9 63.79,10.64 ; J41.9 63.79,7.95 ; J41.9 61.1,7.95 ; J13.19 134.23,17.5 ; J13.19 132.32,19.41 ; J13.19 132.32,17.5 ; J13.19 134.23,19.41 ; 267.82,20.42 J15.100 ; J15.100 267.82,18.51 ; J15.100 269.73,20.42 ; J15.100 269.73,18.51 ; 204.31,10.13 J15.97 ; J15.97 206.22,12.04 ; J15.97 206.22,10.13 ; J15.97 204.31,12.04 ; 131.56,3.79 J13.21 ; J13.21 133.47,5.7 ; J13.21 131.56,5.7 ; J13.21 133.47,3.79 ; 150.43,12.04 J14.25 ; J14.25 152.34,10.13 ; J14.25 152.34,12.04 ; J14.25 150.43,10.13 ; 61.1,16.32 J41.11 ; J41.11 61.1,13.63 ; J41.11 63.79,16.32 ; J41.11 63.79,13.63 ; J15.99 206.22,18.51 ; J15.99 204.31,20.42 ; J15.99 206.22,20.42 ; J15.99 204.31,18.51 ; 166.69,18.51 J14.28 ; J14.28 166.69,20.42 ; J14.28 168.6,20.42 ; J14.28 168.6,18.51 ; 148.57,21.7 J13.18 ; J13.18 148.57,19.79 ; J13.18 150.48,21.7 ; 148.57,5.7 J13.22 ; J13.22 150.48,5.7 ; J13.22 150.48,3.79 ; J13.22 148.57,3.79 ; 267.82,10.13 J15.98 ; J15.98 269.73,12.04 ; J15.98 267.82,12.04 ; J15.98 269.73,10.13 ; J14.27 152.34,20.42 ; J14.27 152.34,18.51 ; J14.27 150.43,18.51
  L4PWR w0.508: 147.81,14.2 J13.20 ; J13.20 149.72,14.2 ; J13.20 147.81,16.11 ; J13.20 149.72,16.11 ; J41.12 76.93,16.32 ; J41.12 74.24,16.32 ; J41.12 74.24,13.63 ; J41.12 76.93,13.63 ; 204.31,12.04 J15.97 ; J15.97 206.22,10.13 ; J15.97 206.22,12.04 ; J15.97 204.31,10.13 ; 131.56,3.79 J13.21 ; J13.21 131.56,5.7 ; J13.21 133.47,3.79 ; J13.21 133.47,5.7 ; J15.98 269.73,10.13 ; J15.98 267.82,12.04 ; J15.98 269.73,12.04 ; J15.98 267.82,10.13 ; J42.13 188.34,6.47 ; J42.13 186.43,8.38 ; J42.13 186.43,6.47 ; J42.13 188.34,8.38 ; J14.27 152.34,18.51 ; J14.27 150.43,18.51 ; J14.27 152.34,20.42 ; 166.69,18.51 J14.28 ; J14.28 166.69,20.42 ; J14.28 168.6,20.42 ; J14.28 168.6,18.51 ; J14.26 168.6,10.13 ; J14.26 166.69,10.13 ; J14.26 168.6,12.04 ; J14.26 166.69,12.04 ; J13.19 134.23,17.5 ; J13.19 134.23,19.41 ; J13.19 132.32,19.41 ; J13.19 132.32,17.5 ; J42.14 204.6,8.38 ; J42.14 202.69,6.47 ; J42.14 202.69,8.38 ; J42.14 204.6,6.47 ; 148.57,5.7 J13.22 ; J13.22 148.57,3.79 ; J13.22 150.48,3.79 ; J13.22 150.48,5.7 ; J15.99 206.22,18.51 ; J15.99 206.22,20.42 ; J15.99 204.31,18.51 ; J15.99 204.31,20.42 ; J13.18 150.48,21.7 ; J13.18 148.57,21.7 ; J13.18 148.57,19.79 ; J41.11 63.79,16.32 ; J41.11 61.1,16.32 ; J41.11 63.79,13.63 ; J41.11 61.1,13.63 ; J14.25 152.34,10.13 ; J14.25 150.43,10.13 ; J14.25 152.34,12.04 ; J14.25 150.43,12.04 ; 61.1,10.64 J41.9 ; J41.9 61.1,7.95 ; J41.9 63.79,10.64 ; J41.9 63.79,7.95 ; 74.24,10.64 J41.10 ; J41.10 76.93,7.95 ; J41.10 76.93,10.64 ; J41.10 74.24,7.95 ; J15.100 269.73,20.42 ; J15.100 269.73,18.51 ; J15.100 267.82,18.51 ; J15.100 267.82,20.42
  L5PWR w0.508: 148.57,5.7 J13.22 ; J13.22 150.48,5.7 ; J13.22 150.48,3.79 ; J13.22 148.57,3.79 ; 186.43,6.47 J42.13 ; J42.13 188.34,6.47 ; J42.13 188.34,8.38 ; J42.13 186.43,8.38 ; 204.31,12.04 J15.97 ; J15.97 204.31,10.13 ; J15.97 206.22,12.04 ; J15.97 206.22,10.13 ; 267.82,12.04 J15.98 ; J15.98 269.73,10.13 ; J15.98 267.82,10.13 ; J15.98 269.73,12.04 ; J15.100 269.73,18.51 ; J15.100 269.73,20.42 ; J15.100 267.82,20.42 ; J15.100 267.82,18.51 ; J14.26 168.6,10.13 ; J14.26 168.6,12.04 ; J14.26 166.69,12.04 ; J14.26 166.69,10.13 ; J14.25 152.34,10.13 ; J14.25 150.43,12.04 ; J14.25 152.34,12.04 ; J14.25 150.43,10.13 ; 74.24,13.63 J41.12 ; J41.12 74.24,16.32 ; J41.12 76.93,13.63 ; J41.12 76.93,16.32 ; 61.1,7.95 J41.9 ; J41.9 63.79,10.64 ; J41.9 63.79,7.95 ; J41.9 61.1,10.64 ; 147.81,14.2 J13.20 ; J13.20 149.72,16.11 ; J13.20 147.81,16.11 ; J13.20 149.72,14.2 ; 74.24,7.95 J41.10 ; J41.10 74.24,10.64 ; J41.10 76.93,10.64 ; J41.10 76.93,7.95 ; J14.28 168.6,18.51 ; J14.28 166.69,20.42 ; J14.28 168.6,20.42 ; J14.28 166.69,18.51 ; 132.32,19.41 J13.19 ; J13.19 134.23,17.5 ; J13.19 132.32,17.5 ; J13.19 134.23,19.41 ; 61.1,13.63 J41.11 ; J41.11 61.1,16.32 ; J41.11 63.79,16.32 ; J41.11 63.79,13.63 ; J13.18 150.48,21.7 ; J13.18 148.57,21.7 ; J13.18 148.57,19.79 ; 202.69,6.47 J42.14 ; J42.14 204.6,6.47 ; J42.14 204.6,8.38 ; J42.14 202.69,8.38 ; 204.31,18.51 J15.99 ; J15.99 206.22,18.51 ; J15.99 206.22,20.42 ; J15.99 204.31,20.42 ; 131.56,5.7 J13.21 ; J13.21 133.47,5.7 ; J13.21 133.47,3.79 ; J13.21 131.56,3.79 ; 150.43,18.51 J14.27 ; J14.27 152.34,20.42 ; J14.27 152.34,18.51
  L7GND w0.508: J42.13 188.34,6.47 ; J42.13 188.34,8.38 ; J42.13 186.43,6.47 ; J42.13 186.43,8.38 ; J14.25 152.34,10.13 ; J14.25 150.43,12.04 ; J14.25 152.34,12.04 ; J14.25 150.43,10.13 ; J14.28 168.6,18.51 ; J14.28 166.69,20.42 ; J14.28 168.6,20.42 ; J14.28 166.69,18.51 ; 204.31,20.42 J15.99 ; J15.99 204.31,18.51 ; J15.99 206.22,20.42 ; J15.99 206.22,18.51 ; 150.43,18.51 J14.27 ; J14.27 152.34,18.51 ; J14.27 152.34,20.42 ; J13.21 133.47,5.7 ; J13.21 133.47,3.79 ; J13.21 131.56,3.79 ; J13.21 131.56,5.7 ; J41.10 76.93,7.95 ; J41.10 76.93,10.64 ; J41.10 74.24,7.95 ; J41.10 74.24,10.64 ; J41.11 63.79,16.32 ; J41.11 63.79,13.63 ; J41.11 61.1,13.63 ; J41.11 61.1,16.32 ; 74.24,13.63 J41.12 ; J41.12 76.93,13.63 ; J41.12 76.93,16.32 ; J41.12 74.24,16.32 ; 166.69,12.04 J14.26 ; J14.26 166.69,10.13 ; J14.26 168.6,12.04 ; J14.26 168.6,10.13 ; 204.31,12.04 J15.97 ; J15.97 204.31,10.13 ; J15.97 206.22,12.04 ; J15.97 206.22,10.13 ; J15.100 269.73,20.42 ; J15.100 267.82,18.51 ; J15.100 269.73,18.51 ; J15.100 267.82,20.42 ; 267.82,12.04 J15.98 ; J15.98 267.82,10.13 ; J15.98 269.73,10.13 ; J15.98 269.73,12.04 ; 147.81,16.11 J13.20 ; J13.20 149.72,14.2 ; J13.20 147.81,14.2 ; J13.20 149.72,16.11 ; 202.69,6.47 J42.14 ; J42.14 204.6,6.47 ; J42.14 204.6,8.38 ; J42.14 202.69,8.38 ; 132.32,19.41 J13.19 ; J13.19 134.23,19.41 ; J13.19 134.23,17.5 ; J13.19 132.32,17.5 ; 148.57,21.7 J13.18 ; J13.18 148.57,19.79 ; J13.18 150.48,21.7 ; 148.57,3.79 J13.22 ; J13.22 150.48,5.7 ; J13.22 148.57,5.7 ; J13.22 150.48,3.79 ; 61.1,10.64 J41.9 ; J41.9 63.79,10.64 ; J41.9 63.79,7.95 ; J41.9 61.1,7.95
  BOTTOM w0.508: C342.2 152.27,33.5 C302.2 ; 204.31,10.13 J15.97 ; J15.97 206.22,10.13 ; J15.97 206.22,12.04 ; J15.97 204.31,12.04 ; 202.69,8.38 J42.14 ; J42.14 202.69,6.47 ; J42.14 204.6,6.47 ; J42.14 204.6,8.38 ; J15.99 206.22,20.42 ; J15.99 206.22,18.51 ; J15.99 204.31,18.51 ; J15.99 204.31,20.42 ; C512.1 v1(236.73,36.7) ; C512.1 236.83,37.97 C553.2 ; C512.1 v1(236.73,38.99) ; J14.26 168.6,10.13 ; J14.26 168.6,12.04 ; J14.26 166.69,12.04 ; J14.26 166.69,10.13 ; C334.2 v1(137.03,31.88) ; C334.2 C336.2 ; C334.2 138.07,32.87 v1(138.18,32.77) ; J14.27 152.34,18.51 ; J14.27 150.43,18.51 ; J14.27 152.34,20.42 ; C541.1 v1(253.87,36.7) ; C541.1 253.98,37.97 C545.2 ; C541.1 v1(253.87,38.99) ; J13.17 133.47,25.76 ; J13.17 133.47,23.85 ; J13.17 131.56,23.85 ; J13.17 131.56,25.76 ; 150.43,10.13 J14.25 ; J14.25 150.43,12.04 ; J14.25 152.34,10.13 ; J14.25 152.34,12.04 ; J15.100 269.73,20.42 ; J15.100 267.82,20.42 ; J15.100 267.82,18.51 ; J15.100 269.73,18.51 ; J15.98 269.73,10.13 ; J15.98 267.82,12.04 ; J15.98 269.73,12.04 ; J15.98 267.82,10.13 ; 61.1,16.32 J41.11 ; J41.11 63.79,13.63 ; J41.11 63.79,16.32 ; J41.11 61.1,13.63 ; C542.1 v1(219.71,38.99) ; C542.1 v1(219.71,36.7) ; C542.1 219.81,37.97 C550.2 ; 148.57,3.79 J13.22 ; J13.22 150.48,3.79 ; J13.22 148.57,5.7 ; J13.22 150.48,5.7 ; 132.32,19.41 J13.19 ; J13.19 132.32,17.5 ; J13.19 134.23,17.5 ; J13.19 134.23,19.41 ; J41.12 76.93,16.32 ; J41.12 76.93,13.63 ; J41.12 74.24,13.63 ; J41.12 74.24,16.32 ; v1(272.29,28.32) 272.29,29.08 271.78,29.59 C526.1 271.27,29.11 v1(271.27,28.32) ; C302.2 152.4,32.36 v1(152.4,31.88) ; C302.2 153.42,32.36 v1(153.42,31.88) ; C302.2 153.54,33.5 C306.2 ; v1(238.51,31.88) 237.59,31.88 C498.1 237.64,32.89 v1(238.51,32.89) ; C368.2 v1(187.45,23.11) ; 166.69,18.51 J14.28 ; J14.28 168.6,18.51 ; J14.28 168.6,20.42 ; J14.28 166.69,20.42 ; v1(204.09,32.77) 203.22,32.77 C499.1 203.56,31.62 v1(204.09,31.62) ; J13.20 149.72,14.2 ; J13.20 149.72,16.11 ; J13.20 147.81,14.2 ; J13.20 147.81,16.11 ; 61.1,10.64 J41.9 ; J41.9 63.79,10.64 ; J41.9 63.79,7.95 ; J41.9 61.1,7.95 ; 186.43,6.47 J42.13 ; J42.13 186.43,8.38 ; J42.13 188.34,8.38 ; J42.13 188.34,6.47 ; v1(196.22,38.48) 196.22,39.01 C513.1 194.94,39.01 v1(194.94,38.48) ; 148.57,21.7 J13.18 ; J13.18 148.57,19.79 ; J13.18 150.48,21.7 ; 74.24,10.64 J41.10 ; J41.10 76.93,7.95 ; J41.10 76.93,10.64 ; J41.10 74.24,7.95 ; 131.56,5.7 J13.21 ; J13.21 133.47,3.79 ; J13.21 133.47,5.7 ; J13.21 131.56,3.79 ; v1(221.36,31.75) 220.58,31.75 C527.1 220.37,32.77 v1(221.36,32.77) ; C548.2 v1(204.09,34.67) ; C310.2 v1(166.25,34.42) ; C371.2 201.17,23.37 v1(200.91,23.11)
  vias: v1(202.95,16.89) v1(202.95,16) v1(272.16,30.99) v3(61.98,2.92) v3(70.23,2.92) v3(79.12,2.92) v3(88.01,2.92) v3(96.9,2.92) v3(107.06,2.92) v3(115.95,2.92) v3(126.75,2.92) v3(136.91,2.92) v3(145.8,2.92) v3(159.77,2.92) v3(192.15,2.92) v3(199.14,2.92) v3(209.93,2.92) v3(219.46,2.92) v3(230.25,2.92) v3(241.05,2.92) v3(251.21,2.92) v3(262,2.92) v3(272.16,2.92) v3(279.15,30.86) v3(279.15,23.88) v3(279.15,16.89)
EC1_GTXCLK: length 74.6
  TOP w0.127: v1(141.22,56.77) 141.22,52.83 140.38,51.99 139.88,51.99 139.84,51.95 U49.22
  BOTTOM w0.127: v1(141.22,56.77) 141.35,56.77 142.49,57.91 142.49,65.29 145.41,68.22 145.41,74.31 145.92,74.82 155.5,84.39 157.92,84.39 170.15,84.39 177.42,91.66 177.42,100.01 177.17,100.25 R127.1
EC1_INT_N: length 78.1
  TOP w0.127: U1.AB4 v2(172.52,105.25) ; v1(172.47,97.03) 172.97,97.54 174.12,97.54 174.62,97.03 174.62,91.31 172.59,89.28 172.59,83.57 169.86,80.84 165.29,80.84 160.4,75.95 151.89,75.95 141.1,65.15 141.1,58.17 142.37,56.9 R250.2
  L3SIG w0.102: v1(172.47,97.03) 172.47,101.98 172.93,102.45 172.93,104.81 172.52,105.23 v2(172.52,105.25)
  BOTTOM w0.127: v1(172.47,97.03) 172.08,97.41 R75.1
EC1_LED0: length 5.5
  TOP w0.127: U49.34 134.87,53.98 134.75,54.1 134.75,54.48 134.11,55.12 132.33,55.12 131.96,55.49 R262.1 R247.1
EC1_LED1: length 6
  TOP w0.127: U49.35 134.47,54.38 133.98,54.86 131.82,54.86 R263.1 R248.1
EC1_MDI0_N: length 11.6
  TOP w0.102: U49.2 134.47,47.07 134.41,47.01 134.41,45.55 136.72,43.24 U50.1 138.5,43.24 139.06,42.67 139.06,41.22 139.64,40.64 T2.11
EC1_MDI0_P: length 11.6
  TOP w0.102: T2.12 138.64,39.87 138.91,40.13 139.19,40.13 139.37,40.31 139.37,40.52 138.55,41.34 U50.3 137.47,41.34 136.9,41.92 136.9,42.66 134.13,45.43 134.13,47.02 134.07,47.08 U49.1
EC1_MDI1_N: length 13
  TOP w0.102: T2.8 142.64,39.6 142.28,39.96 142.28,40.98 141.61,41.65 141.61,42.79 141.16,43.24 U50.6 140.03,43.24 138.7,44.58 136.91,44.58 135.61,45.87 135.61,47.02 135.67,47.08 U49.5
EC1_MDI1_P: length 13.1
  TOP w0.102: T2.9 141.64,39.66 142.01,40.02 142.01,40.86 141.52,41.34 U50.4 140.22,41.34 139.95,41.61 139.95,42.93 138.58,44.3 136.79,44.3 135.33,45.76 135.33,47.02 135.27,47.08 U49.4
EC1_MDI2_N: length 14.8
  TOP w0.102: U49.8 136.87,47.08 136.81,47.02 136.81,46.2 137.54,45.47 139.19,45.47 140.21,44.45 141.99,44.45 143.2,43.24 U51.1 144.47,43.24 145.03,42.67 145.03,41.54 145.41,41.16 145.41,40.13 145.65,39.9 T2.5
EC1_MDI2_P: length 14.9
  TOP w0.102: U49.7 136.47,47.09 136.53,47.03 136.53,46.08 137.43,45.19 139.08,45.19 140.09,44.17 141.87,44.17 142.88,43.17 142.88,42.04 143.57,41.34 U51.3 144.84,41.34 145.14,41.05 145.14,40.11 144.65,39.62 T2.6
EC1_MDI3_N: length 16.1
  TOP w0.102: T2.2 148.65,39.7 148.11,40.23 148.11,41.14 147.7,41.54 147.7,42.67 147.13,43.24 U51.6 146.12,43.24 145.01,44.35 143.5,44.35 142.51,45.34 140.59,45.34 139.58,46.35 138.3,46.35 138.01,46.65 138.01,47.03 138.07,47.09 U49.11
EC1_MDI3_P: length 16.1
  TOP w0.102: T2.3 147.65,39.69 147.83,39.88 147.83,41.02 147.51,41.34 U51.4 146.24,41.34 146,41.58 146,42.96 144.89,44.07 143.38,44.07 142.39,45.06 140.48,45.06 139.46,46.08 138.19,46.08 137.73,46.53 137.73,47.03 137.67,47.09 U49.10
EC1_MDX0_N: length 29.5
  TOP w0.102: v1(139.57,27.85) 139.28,28.13 139.28,29.03 139.64,29.39 T2.14
  L3SIG w0.102: v1(139.57,27.85) 139.28,27.57 139.28,26.97 139.97,26.29 146.69,26.29 148.82,24.16 149.96,24.16 153.8,20.32 153.8,15.24 155.32,13.72 155.7,13.72 156.34,14.36 J14.B2
EC1_MDX0_P: length 29.5
  TOP w0.102: T2.13 138.64,29.39 139.01,29.03 139.01,28.13 v1(138.72,27.85)
  L3SIG w0.102: J14.B1 155.32,12.48 155.32,13.32 153.52,15.12 153.52,20.2 149.85,23.88 148.7,23.88 146.57,26.01 139.85,26.01 139.01,26.86 139.01,27.57 v1(138.72,27.85)
EC1_MDX1_N: length 39.7
  TOP w0.102: v1(142.7,27.84) 142.42,27.56 142.03,27.56 141.92,27.66 141.92,28.93 142.03,29.03 142.28,29.03 142.64,29.39 T2.17
  L3SIG w0.102: J14.B6 161.92,14.26 161.92,13.18 161.82,13.08 161.18,13.08 160.27,13.98 160.27,15.81 160.68,16.22 160.68,16.36 160.54,16.5 160.39,16.5 159.96,16.08 159.82,16.08 159.68,16.22 159.68,16.36 160.1,16.79 160.1,16.93 159.96,17.08 159.82,17.08 159.39,16.65 159.24,16.65 159,16.89 159,19.18 157.73,20.45 157.73,22.1 157.1,22.73 157.1,25.53 155.93,26.7 149.34,26.7 147.33,28.7 143.88,28.7 143.48,28.31 143.48,27.78 143.27,27.56 142.98,27.56 v1(142.7,27.84)
EC1_MDX1_P: length 39.6
  TOP w0.102: v1(142.7,27) 142.42,27.28 141.91,27.28 141.64,27.54 T2.16
  L3SIG w0.102: v1(142.7,27) 142.98,27.28 143.38,27.28 143.76,27.66 143.76,28.19 143.99,28.42 147.22,28.42 149.22,26.42 155.81,26.42 156.82,25.41 156.82,22.62 157.45,21.98 157.45,20.33 158.72,19.06 158.72,16.78 159.99,15.51 159.99,13.87 161.16,12.7 161.16,11.68 160.66,11.18 158.66,11.18 J14.B3
EC1_MDX2_N: length 27.9
  TOP w0.102: T2.20 145.65,27.57 145.38,27.3 144.91,27.3 v1(144.58,26.97)
  L3SIG w0.102: J14.B5 159.3,13.08 158.23,13.08 157.45,13.85 157.45,15.63 156.18,16.9 156.18,19.04 150.08,25.15 148.97,25.15 146.81,27.3 144.91,27.3 v1(144.58,26.97)
EC1_MDX2_P: length 27.9
  TOP w0.102: v1(144.58,27.81) 144.81,27.58 145.26,27.58 145.37,27.69 145.37,28.93 145.26,29.03 145.08,29.03 144.65,29.47 T2.19
  L3SIG w0.102: v1(144.58,27.81) 144.81,27.58 146.93,27.58 149.09,25.43 150.2,25.43 156.46,19.16 156.46,17.02 157.73,15.75 157.73,13.97 158.34,13.36 159.03,13.36 159.26,13.59 159.26,14.39 J14.B4
EC1_MDX3_N: length 29.1
  TOP w0.102: v1(149.94,28.25) 149.66,27.97 148.71,27.97 148.28,28.39 148.28,29.03 148.65,29.39 T2.23
  L3SIG w0.102: J14.B8 163.96,14.1 163.7,13.84 163.19,13.84 162.84,14.2 162.84,16.12 161.57,17.39 161.57,19.17 160.3,20.44 160.3,24.88 157.24,27.94 150.24,27.94 149.94,28.24 v1(149.94,28.25)
EC1_MDX3_P: length 29.2
  TOP w0.102: T2.22 147.65,29.39 148.01,29.03 148.01,28.27 148.59,27.69 149.66,27.69 v1(149.94,27.41)
  L3SIG w0.102: v1(149.94,27.41) 150.19,27.66 157.12,27.66 160.02,24.77 160.02,20.32 161.29,19.05 161.29,17.27 162.56,16 162.56,14.08 162.81,13.83 162.81,12.35 J14.B7
EC1_PME_N: length 76.8
  TOP w0.127: v1(174.12,96.77) 174.12,91.44 172.21,89.54 172.21,83.69 169.67,81.15 165.1,81.15 160.27,76.33 151.76,76.33 140.59,65.15 140.59,60.96 138.18,58.55 135.64,58.55 134.49,57.4 R251.2 ; U1.AD5 v2(174.12,106.05)
  L3SIG w0.102: v1(174.12,96.77) 174.12,99.31 174.5,99.7 174.5,105.66 v2(174.12,106.05)
  BOTTOM w0.127: R76.1 v1(174.12,96.77)
EC1_REFCLK: length 97.1
  TOP w0.127: v1(127.76,48.64) R246.2 ; U1.AG3 176.53,104.43 176.53,103.88 177.28,103.12 v1(179.96,103.12)
  BOTTOM w0.127: v1(127.76,48.64) 128.91,48.64 130.81,50.55 130.81,52.71 131.32,53.21 131.32,54.74 132.84,56.26 137.16,56.26 137.67,55.75 141.86,55.75 143.51,57.4 143.51,64.87 146.43,67.79 146.43,68.21 146.43,73.89 146.94,74.4 146.94,74.4 155.92,83.38 157.5,83.38 170.57,83.38 178.44,91.24 178.44,99.57 179.96,101.09 v1(179.96,103.12)
EC1_RST_N: length 121.2
  TOP w0.127: R249.1 R252.2 136.39,57.66 v1(135.89,57.66) ; v1(58.51,106.43) 59.01,106.93 U65.H3
  L6SIG w0.102: v1(135.89,57.66) 135.89,61.47 127.89,69.47 93.22,69.47 91.41,71.27 74.96,71.27 73.72,72.52 69.47,72.52 65.53,76.45 65.53,80.9 64.39,82.04 64.39,84.2 53.47,95.12 53.47,103.12 56.27,105.93 58.01,105.93 v1(58.51,106.43)
EC1_RXCLK: length 79.5
  TOP w0.127: v1(178.94,99.31) 176.66,99.31 173.72,102.25 U1.AD1 ; R238.1 144.78,51.18 145.03,51.43 v1(145.03,53.09)
  BOTTOM w0.127: v1(178.94,99.31) 178.94,91.03 170.78,82.87 157.28,82.87 156.13,82.87 147.45,74.19 147.45,74.19 146.94,73.68 146.94,68.43 146.94,68.42 146.94,68 146.94,67.58 144.02,64.66 144.02,56.26 144.27,56.01 144.27,53.85 v1(145.03,53.09)
EC1_RXCTL: length 89.4
  TOP w0.127: v1(147.57,52.32) 147.57,48.77 145.41,46.61 143.64,46.61 143.39,46.36 R261.1 R245.1 ; v1(180.47,102.62) 177.3,102.62 176.12,103.8 U1.AG2
  BOTTOM w0.127: v1(147.57,52.32) 147.57,52.45 148.08,52.96 148.08,54.23 146.94,55.37 146.94,60.71 147.38,61.15 147.38,62.81 149.73,65.16 149.73,73.24 157.07,80.58 158.18,80.58 171.73,80.58 181.42,90.27 181.42,101.66 v1(180.47,102.62)
EC1_RXD0: length 88.7
  TOP w0.127: U1.AF2 175.77,103.59 175.77,102.87 176.78,101.85 v1(180.47,101.85) ; R239.1 R257.1 143.39,47.51 143.51,47.62 145.44,47.62 147.07,49.25 v1(147.07,53.09)
  BOTTOM w0.127: v1(180.47,101.85) 180.97,101.35 180.97,98.52 180.97,98.52 180.97,90.46 171.55,81.03 156.89,81.03 149.29,73.42 149.29,65.35 146.94,63 146.94,61.47 145.92,60.45 145.92,57.02 146.18,56.77 146.18,54.61 147.07,53.72 v1(147.07,53.09)
EC1_RXD1: length 86.4
  TOP w0.127: v1(180.47,101.09) 180.21,101.35 176.66,101.35 175.32,102.69 U1.AF1 ; v1(146.56,52.32) 146.56,49.66 145.54,48.64 143.64,48.64 143.39,48.39 R258.1 R242.1
  BOTTOM w0.127: v1(180.47,101.09) 180.47,90.58 171.36,81.47 156.71,81.47 156.45,81.21 148.84,73.61 148.84,65.53 145.41,62.1 145.41,56.84 145.67,56.59 145.67,54.43 146.56,53.54 v1(146.56,52.32)
EC1_RXD2: length 84.8
  TOP w0.127: R243.1 R259.1 143.39,49.41 143.64,49.66 145.54,49.66 146.05,50.16 v1(146.05,53.09) ; U1.AE1 174.52,102.85 176.53,100.84 179.45,100.84 v1(179.96,100.33)
  BOTTOM w0.127: v1(146.05,53.09) 146.05,53.42 145.22,54.24 145.22,56.4 144.97,56.66 144.97,63.31 148.4,66.74 148.4,73.79 156,81.39 156.52,81.92 171.18,81.92 179.96,90.7 v1(179.96,100.33)
EC1_RXD3: length 83.9
  TOP w0.127: v1(145.54,52.32) 145.54,51.31 144.91,50.67 143.64,50.67 143.39,50.43 R260.1 R244.1 ; U1.AD2 173.72,104.03 174.12,103.63 174.12,102.62 176.91,99.82 v1(179.45,99.82)
  BOTTOM w0.127: v1(145.54,52.32) 145.54,52.88 145.54,53.3 144.78,54.06 144.78,56.22 144.53,56.47 144.53,63.5 147.95,66.93 147.95,73.98 156.34,82.36 157.07,82.36 170.99,82.36 179.45,90.82 v1(179.45,99.82)
EC1_RXDLY: length 2.4
  TOP w0.127: R264.1 135.38,55.63 135.38,54.23 135.67,53.94 U49.32
EC1_TXCTL: length 75.7
  TOP w0.127: v1(138.68,56.26) 138.68,55.37 137.79,54.48 137.79,54.24 137.67,54.11 U49.27
  BOTTOM w0.127: R125.1 179.2,101.22 178.82,100.84 178.44,100.84 177.93,100.33 177.93,91.45 170.36,83.88 157.71,83.88 155.71,83.88 146.43,74.61 145.92,74.1 145.92,68 143,65.08 143,57.66 141.6,56.26 v1(138.68,56.26)
EC1_TXD0: length 73.8
  TOP w0.127: v1(140.72,57.53) 140.72,52.96 140.1,52.35 U49.23
  BOTTOM w0.127: v1(140.72,57.53) 141.48,58.29 141.48,65.63 144.46,68.61 144.46,74.71 144.97,75.21 144.97,75.21 155.1,85.34 158.31,85.34 169.76,85.34 176.47,92.05 176.47,99.61 175.13,100.95 R115.1
EC1_TXD1: length 73.5
  TOP w0.127: v1(140.21,56.77) 140.21,53.09 139.87,52.75 U49.24
  BOTTOM w0.127: R116.1 176.15,100.56 176.91,99.8 176.91,91.87 169.94,84.9 158.13,84.9 158.13,84.9 155.28,84.9 145.41,75.03 145.41,75.03 144.91,74.52 144.91,68.43 141.99,65.5 141.99,65.08 141.99,58.17 141.1,57.28 141.09,57.28 140.9,57.09 140.82,57.09 140.72,56.98 140.72,56.9 140.59,56.77 v1(140.21,56.77)
EC1_TXD2: length 72.1
  TOP w0.127: v1(139.83,58.17) 139.7,58.04 139.7,54.99 138.81,54.1 138.6,54.1 138.47,53.98 U49.25
  BOTTOM w0.127: v1(139.83,58.17) 140.46,58.8 140.46,65.2 140.46,66.05 143.45,69.03 143.45,75.13 143.95,75.63 153.82,85.51 154.68,86.36 158.73,86.36 169.33,86.36 175.45,92.48 175.45,99.19 174.12,100.52 R119.1
EC1_TXD3: length 72.2
  TOP w0.127: U49.26 138.07,54.12 139.19,55.24 v1(139.19,57.53)
  BOTTOM w0.127: R121.1 173.1,100.91 175.01,99.01 175.01,92.66 169.15,86.8 158.92,86.8 158.92,86.8 154.49,86.8 153.38,85.69 143.51,75.82 143,75.31 143,69.21 139.95,66.17 139.95,59.31 139.19,58.55 v1(139.19,57.53)
EC2_GTXCLK: length 86.4
  TOP w0.127: U46.22 162.06,51.31 162.11,51.36 162.61,51.36 163.32,52.07 v1(163.32,52.58)
  BOTTOM w0.127: R128.2 182.28,107.82 184.66,105.45 184.66,89.02 173.04,77.41 172.26,77.41 172.25,77.41 159.95,77.41 153.42,70.87 153.42,68.83 152.97,68.39 152.97,64.27 152.97,63.52 152.97,63.52 152.97,63.1 155.19,60.87 155.19,59.48 156.95,57.72 158.31,57.72 158.88,57.15 160.08,57.15 160.27,57.15 160.34,57.09 160.91,56.52 161.58,56.52 163.32,54.77 v1(163.32,52.58)
EC2_INT_N: length 70
  TOP w0.127: U1.L4 v2(162.92,105.25) ; v1(166.62,52.32) 166.62,52.32 R221.2
  L3SIG w0.102: v1(166.62,52.32) 162.56,56.39 156.08,56.39 155.65,56.82 155.65,57.48 156.08,57.91 156.08,68.4 158.37,70.68 158.37,72.14 163.58,77.34 v1(163.58,94.23) 163.19,94.62 163.19,100.58 164.11,101.5 164.11,104.64 163.89,104.87 163.56,104.87 163.18,105.25 v2(162.92,105.25)
  BOTTOM w0.127: R79.1 162.31,93.73 162.81,94.23 v1(163.58,94.23)
EC2_LED0: length 5.5
  TOP w0.127: R218.1 R233.1 154.19,54.86 154.56,54.48 156.34,54.48 156.97,53.85 156.97,53.47 157.1,53.34 U46.34
EC2_LED1: length 6
  TOP w0.127: R219.1 R234.1 154.04,54.23 156.21,54.23 156.7,53.74 U46.35
EC2_MDI0_N: length 11.8
  TOP w0.102: U46.2 156.7,46.43 156.64,46.37 156.64,45.13 155.68,44.17 153.79,44.17 153.57,43.95 153.57,43.34 153.86,43.05 154.47,43.05 U47.1 154.88,43.24 155.47,42.65 155.47,39.27 T1.11
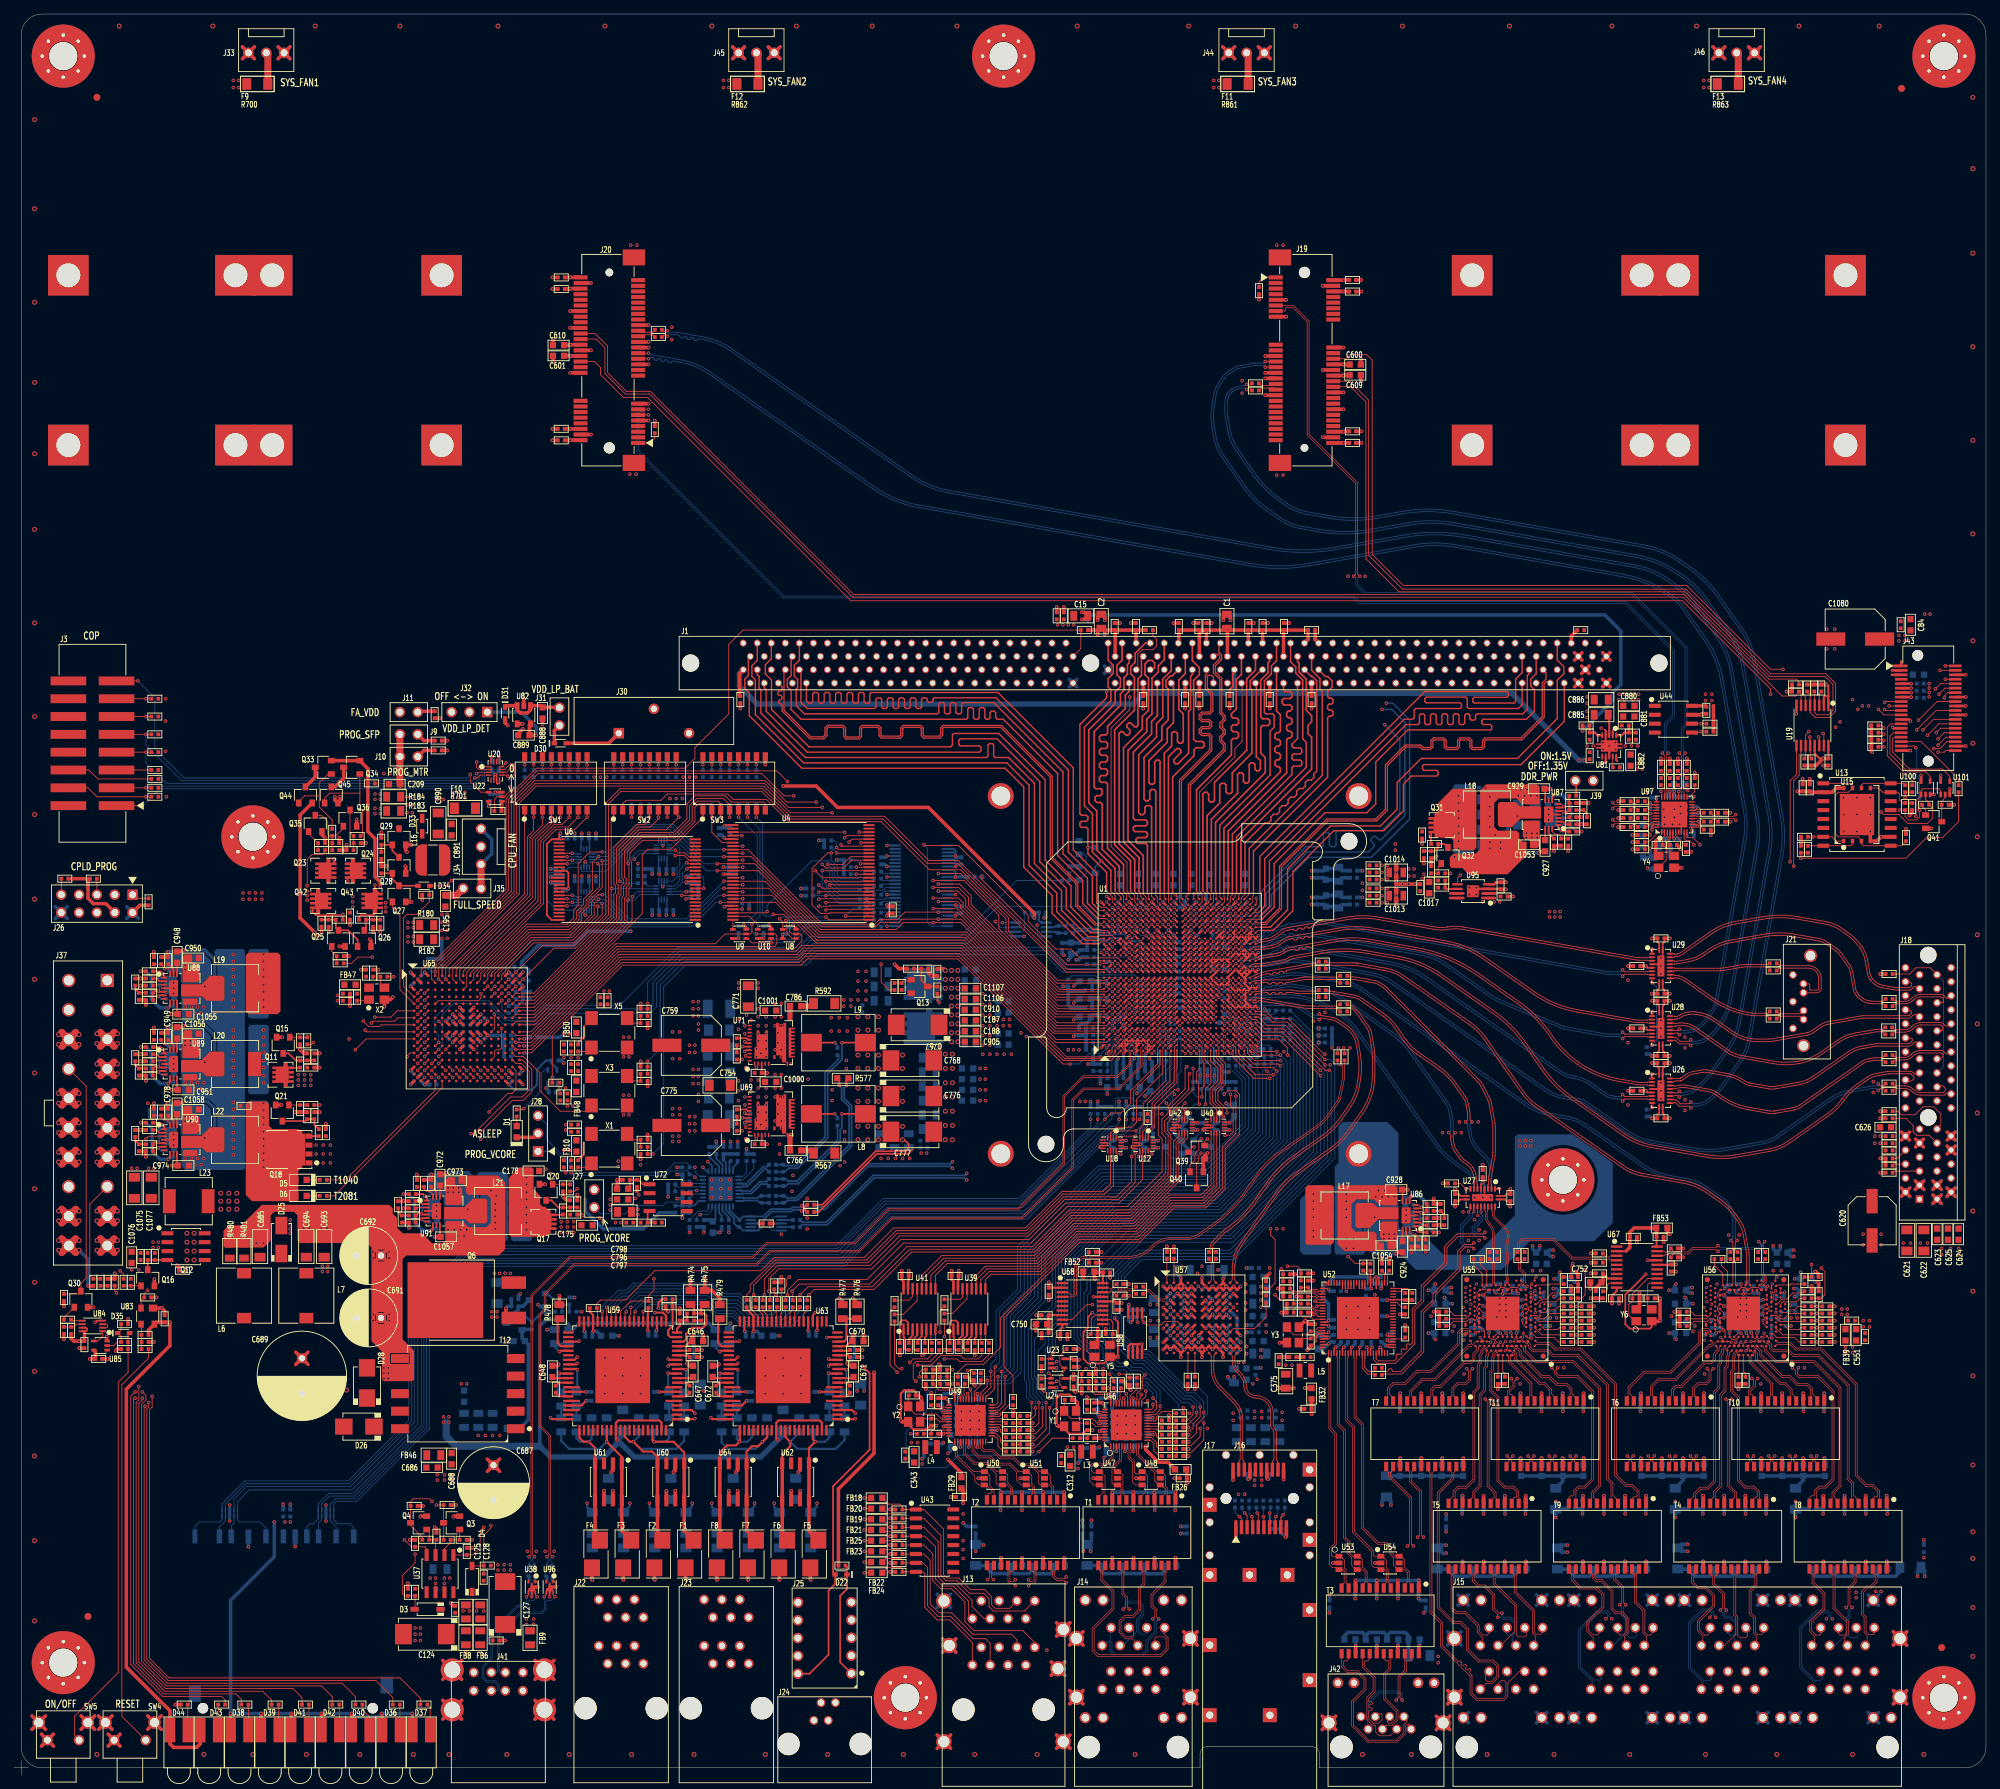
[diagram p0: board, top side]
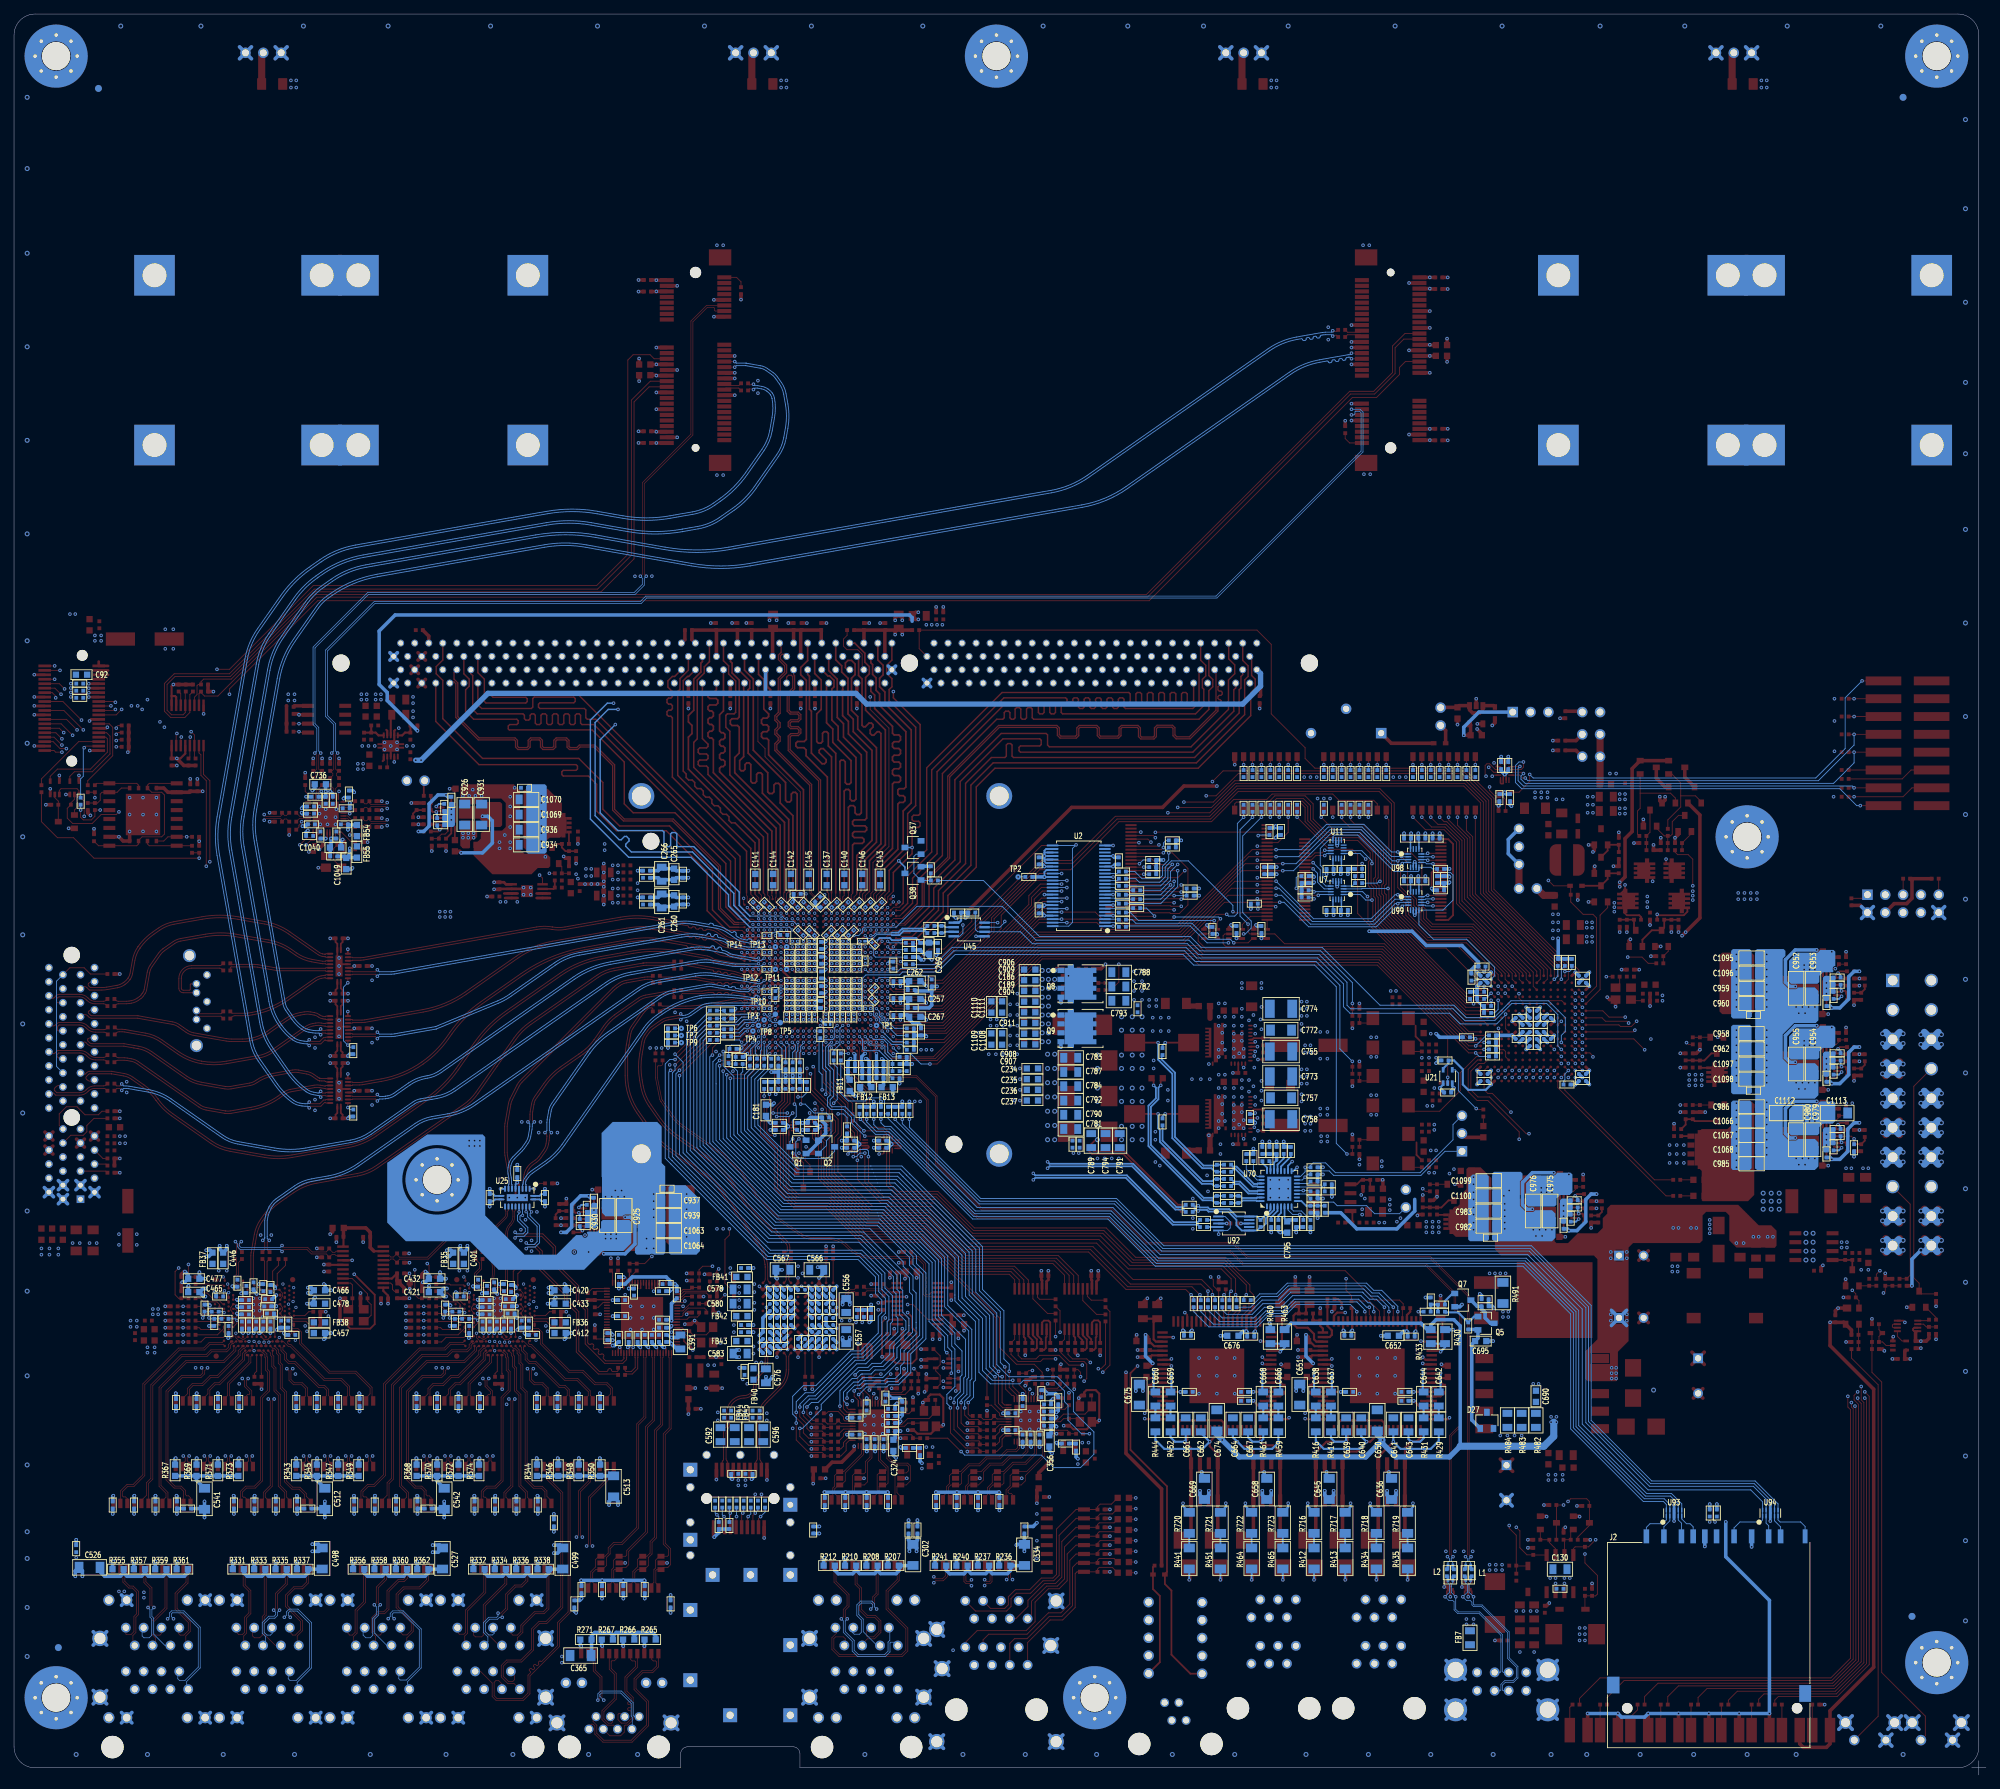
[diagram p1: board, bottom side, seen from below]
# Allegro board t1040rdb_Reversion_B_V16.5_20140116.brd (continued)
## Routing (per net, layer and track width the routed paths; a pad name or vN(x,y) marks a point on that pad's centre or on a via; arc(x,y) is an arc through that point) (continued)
EC2_MDI0_P: length 11.8
  TOP w0.102: T1.12 154.52,39.57 155.19,40.25 155.19,41.15 155,41.34 U47.3 153.86,41.34 153.29,41.91 153.29,44.07 153.67,44.45 155.56,44.45 156.36,45.25 156.36,46.39 156.3,46.45 U46.1
EC2_MDI1_N: length 9.3
  TOP w0.102: T1.8 158.52,39.6 158.01,40.11 158.01,42.77 157.55,43.24 U47.6 156.91,43.24 156.74,43.41 156.74,43.77 157.84,44.87 157.84,46.38 157.9,46.44 U46.5
EC2_MDI1_P: length 9.3
  TOP w0.102: U46.4 157.5,46.44 157.56,46.38 157.56,44.98 156.46,43.89 156.46,41.61 156.73,41.34 U47.4 157.54,41.34 157.73,41.15 157.73,39.75 157.52,39.54 T1.9
EC2_MDI2_N: length 9.8
  TOP w0.102: U46.8 159.1,46.45 159.04,46.39 159.04,45.32 159.66,44.69 159.66,43.15 159.89,42.93 160.44,42.93 U48.1 160.98,43.24 161.52,42.7 T1.5
EC2_MDI2_P: length 9.8
  TOP w0.102: U46.7 158.7,46.46 158.76,46.4 158.76,45.21 159.38,44.58 159.38,41.78 159.83,41.34 U48.3 161.06,41.34 161.24,41.16 161.24,40.34 160.52,39.62 T1.6
EC2_MDI3_N: length 9.9
  TOP w0.102: U46.11 160.3,46.45 160.24,46.39 160.24,45.77 162.77,43.24 U48.6 163.51,43.24 164.09,42.66 164.09,41.15 164.34,40.91 164.34,39.4 T1.2
EC2_MDI3_P: length 9.9
  TOP w0.102: T1.3 163.52,39.57 164.06,40.11 164.06,40.79 163.51,41.34 U48.4 163.13,41.34 162.56,41.91 162.56,43.05 159.96,45.66 159.96,46.39 159.9,46.45 U46.10
EC2_MDX0_N: length 29.2
  TOP w0.102: J14.A2 162.56,18.59 162.56,19.43 162.81,19.69 163.94,19.69 164.19,19.44 164.19,18.01 163.32,17.15 154.57,17.15 153.92,17.79 153.92,20.83 156.74,23.65 156.74,26.26 155.16,27.85 155.16,29.18 155.52,29.54 T1.14
EC2_MDX0_P: length 29.2
  TOP w0.102: J14.A1 163.83,20.86 163.83,20.19 164.47,19.56 164.47,17.89 163.44,16.87 154.46,16.87 153.64,17.68 153.64,20.94 156.46,23.76 156.46,26.15 154.88,27.73 154.88,29.14 154.52,29.5 T1.13
EC2_MDX1_N: length 16.8
  TOP w0.102: v1(158.93,23.65) 158.65,23.93 158.65,25.39 158.16,25.88 158.16,29.13 158.52,29.49 T1.17
  BOTTOM w0.102: J14.A6 158.03,18.46 159.99,20.42 159.99,22.21 160.63,22.85 160.63,24.14 160.26,24.51 158.89,24.51 158.65,24.27 158.65,23.93 v1(158.93,23.65)
EC2_MDX1_P: length 16.9
  TOP w0.102: T1.16 157.52,29.42 157.88,29.06 157.88,25.76 158.37,25.27 158.37,23.93 v1(158.09,23.65)
  BOTTOM w0.102: v1(158.09,23.65) 158.37,23.93 158.37,24.38 158.78,24.79 160.38,24.79 160.91,24.26 160.91,22.73 160.27,22.1 160.27,20.32 160.53,20.07 161.29,20.07 161.54,20.32 161.54,20.87 J14.A3
EC2_MDX2_N: length 15.4
  TOP w0.102: T1.20 161.52,29.44 161.16,29.08 161.16,27.17 160.53,26.54 160.53,23.49 159.49,22.45 158.36,22.45 157.76,21.86 157.76,20.44 158.51,19.69 159.38,19.69 159.51,19.81 159.51,20.64 159.16,21 J14.A5
EC2_MDX2_P: length 15.3
  TOP w0.102: J14.A4 160.15,18.66 159.41,19.41 158.39,19.41 157.48,20.32 157.48,20.55 157.48,21.97 158.24,22.73 159.37,22.73 160.25,23.61 160.25,26.66 160.88,27.29 160.88,29.11 160.52,29.47 T1.19
EC2_MDX3_N: length 22.9
  TOP w0.102: T1.23 164.52,29.39 164.16,29.03 164.16,27.49 162.31,25.64 162.31,24.13 162.84,23.6 162.84,22.53 v1(163.12,22.25)
  BOTTOM w0.102: v1(163.12,22.25) 162.84,21.97 162.84,20.33 161.57,19.06 161.57,17.66 160.77,16.87 156.86,16.87 156.18,17.54 156.18,18.82 156.08,18.92 155.3,18.92 155.07,18.69 J14.A8
EC2_MDX3_P: length 22.8
  TOP w0.102: T1.22 163.52,29.39 163.88,29.03 163.88,27.61 162.03,25.76 162.03,24.01 162.56,23.48 162.56,22.53 v1(162.28,22.25)
  BOTTOM w0.102: J14.A7 156.21,20.86 156.21,19.19 156.46,18.94 156.46,17.65 156.97,17.15 160.66,17.15 161.29,17.78 161.29,19.18 162.56,20.45 162.56,21.97 v1(162.28,22.25)
EC2_PME_N: length 59.1
  TOP w0.127: U1.U3 v2(168.52,104.45) ; R222.2 156.72,56.52 v1(156.08,57.15)
  L3SIG w0.102: v2(168.52,104.45) 168.52,104.28 168.91,103.89 168.91,100.84 168.27,100.2 167.89,100.2 167.64,100.46 167.26,100.46 163.58,96.77 163.58,95 164.08,94.49 164.08,77.34 158.75,72.01 158.75,70.61 156.41,68.28 156.41,57.48 v1(156.08,57.15)
  BOTTOM w0.127: v2(168.52,104.45) 168.52,104.28 168.91,103.89 168.91,103.12 169.04,103 R80.1
EC2_REFCLK: length 122.2
  TOP w0.127: v1(146.05,46.1) 147.95,48.01 R217.2 ; U1.AC6 v2(173.32,106.85)
  BOTTOM w0.127: v2(173.32,106.85) 173.72,106.44 174.28,106.44 174.52,106.2 174.52,103.35 174.62,103.25 174.62,100.73 175.96,99.4 175.96,92.27 169.54,85.85 158.52,85.85 154.89,85.85 154.33,85.29 144.46,75.42 143.95,74.92 143.95,72.44 143.95,68.82 140.97,65.84 140.97,65.41 140.97,58.5 139.24,56.77 132.34,56.77 130.05,54.48 130.05,51.82 127.13,48.89 127.13,45.72 129.03,43.81 132.84,43.81 134.62,45.59 145.54,45.59 v1(146.05,46.1)
EC2_RST_N: length 140
  TOP w0.127: v1(157.48,57.15) 158.24,57.15 158.76,56.63 R823.2 R220.1 ; v1(57.51,105.43) 58.01,105.93 U65.J2
  L6SIG w0.102: v1(157.48,57.15) 157.48,58.17 155.57,60.07 149.22,60.07 148.59,60.71 137.02,60.71 128,69.72 93.34,69.72 91.57,71.5 75.06,71.5 73.79,72.77 69.6,72.77 65.79,76.58 65.79,81.03 64.64,82.17 64.64,84.33 53.72,95.25 53.72,103 56.15,105.43 v1(57.51,105.43)
EC2_RXCLK: length 89.4
  TOP w0.127: v1(186.18,99.7) 180.47,105.41 179.14,105.41 179.14,105.41 177.8,105.41 177.29,105.92 177.29,106.07 U1.AH5 ; R211.1 167.18,50.55 168.02,51.39 v1(168.02,52.45)
  BOTTOM w0.127: v1(168.02,52.45) 167.39,53.09 166.45,53.09 160.92,58.61 159.62,58.61 155.07,63.16 155.07,65.13 155.32,65.39 155.32,68.58 155.7,68.96 155.7,71.04 160.6,75.95 171.65,75.95 173.65,75.95 186.18,88.48 v1(186.18,99.7)
EC2_RXCTL: length 102.6
  TOP w0.127: v1(186.82,101.98) 181.48,107.32 179.32,107.32 178.31,108.33 177.56,108.33 177.43,108.46 176.5,108.46 U1.AG8 ; v1(169.54,50.16) 169.54,47.75 167.77,45.97 165.86,45.97 165.62,45.73 R232.1 R216.1
  BOTTOM w0.127: v1(169.54,50.16) 169.54,50.93 170.05,51.43 170.05,53.98 168.53,55.5 166.75,55.5 161.8,60.45 160.4,60.45 157.86,62.99 157.86,65.41 157.35,65.91 157.35,67.69 158.24,68.58 158.24,70.98 160.73,73.47 172.67,73.47 173.41,73.47 173.41,73.47 173.78,73.47 187.43,87.12 187.43,87.12 188.21,87.91 188.21,101.35 187.58,101.98 v1(186.82,101.98)
EC2_RXD0: length 101.6
  TOP w0.127: U1.AH8 177.67,108.85 177.74,108.78 178.5,108.78 179.45,107.82 181.61,107.82 186.68,102.74 v1(186.82,102.74) ; v1(169.04,49.4) 169.04,48.26 167.77,46.99 165.73,46.99 165.62,46.87 R228.1 R209.1
  BOTTOM w0.127: v1(186.82,102.74) 185.67,101.6 185.67,88.69 173.44,76.45 171.86,76.45 160.39,76.45 155.19,71.25 155.19,70.83 155.19,69.22 154.81,68.83 154.81,65.6 153.92,64.71 153.92,63.49 156.21,61.2 156.21,59.94 157.48,58.67 158.75,58.67 159.32,58.1 160.71,58.1 165.99,52.83 165.99,52.07 168.66,49.4 v1(169.04,49.4)
EC2_RXD1: length 98.5
  TOP w0.127: R213.1 R229.1 165.62,47.76 165.86,48.01 167.77,48.01 168.53,48.77 168.53,49.91 169.54,50.93 v1(169.54,51.69) ; U1.AG7 176.47,107.7 176.95,107.7 178.28,106.36 180.91,106.36 186.82,100.46 v1(187.45,100.46)
  BOTTOM w0.127: v1(187.45,100.46) 187.71,100.2 187.71,88.03 187.25,87.57 187.25,87.57 173.59,73.91 172.86,73.91 160.55,73.91 157.8,71.16 157.8,68.9 156.84,67.94 156.84,65.79 157.35,65.28 157.35,62.87 160.21,60.01 161.61,60.01 167.13,54.48 168.27,54.48 169.54,53.21 v1(169.54,51.69)
EC2_RXD2: length 96.1
  TOP w0.127: v1(186.82,101.22) 181.23,106.81 180.19,106.81 178.56,106.81 177.32,108.05 U1.AH7 ; v1(169.04,52.45) 169.04,51.05 168.02,50.04 168.02,49.4 167.64,49.02 165.86,49.02 165.62,48.78 R230.1 R214.1
  BOTTOM w0.127: v1(186.82,101.22) 186.82,100.46 187.2,100.08 187.2,88.15 187.06,88.01 173.41,74.36 160.37,74.36 157.35,71.35 157.35,69.22 157.29,69.16 157.29,69.15 156.34,68.2 156.34,64.9 156.59,64.65 156.59,62.99 160.02,59.56 161.32,59.56 166.84,54.04 167.83,54.04 169.04,52.83 v1(169.04,52.45)
EC2_RXD3: length 93.5
  TOP w0.127: R215.1 R231.1 165.62,49.79 165.86,50.04 167.39,50.04 168.53,51.18 v1(168.53,51.69) ; v1(186.18,100.46) 180.72,105.92 178.07,105.92 176.92,107.07 U1.AH6
  BOTTOM w0.127: v1(168.53,51.69) 168.53,52.7 167.64,53.59 166.66,53.59 161.13,59.12 159.83,59.12 156.15,62.8 156.15,64.33 155.83,64.64 155.83,68.33 156.91,69.41 156.91,71.53 160.18,74.8 173.23,74.8 173.86,75.44 186.69,88.27 186.69,99.95 v1(186.18,100.46)
EC2_RXDLY: length 2.4
  TOP w0.127: R235.1 157.61,55 157.61,53.59 157.9,53.3 U46.32
EC2_TXCTL: length 83.5
  TOP w0.127: U46.27 159.9,53.48 160.02,53.6 160.02,54.36 160.78,55.12 160.78,56.64 v1(161.16,57.02)
  BOTTOM w0.127: v1(161.16,57.02) 160.53,57.66 159.13,57.66 158.56,58.23 157.16,58.23 155.7,59.69 155.7,61.08 153.48,63.31 153.48,64.06 153.48,65.09 154.37,65.98 154.37,69.09 154.69,69.41 154.69,71.37 160.21,76.9 172.04,76.9 173.25,76.9 185.17,88.81 185.17,105.66 R126.2
EC2_TXD0: length 87.8
  TOP w0.127: U46.23 162.33,51.71 162.81,52.2 162.81,53.21 v1(162.31,53.72)
  BOTTOM w0.127: v1(162.31,53.72) 162.31,54.44 161.19,55.56 160.56,55.56 160.51,55.56 159.94,56.13 159.94,56.13 159.88,56.2 159.68,56.2 157.04,56.2 156.72,56.52 155.45,56.52 154.69,57.28 154.69,58.29 154.18,58.8 154.18,60.45 151.96,62.67 151.96,71.18 153.42,72.64 153.42,73.78 155.59,75.95 157.99,78.36 172.65,78.36 183.71,89.41 183.71,105.05 182.46,106.3 R117.2
EC2_TXD1: length 84.5
  TOP w0.127: U46.24 162.09,52.11 162.31,52.32 v1(162.31,52.83)
  BOTTOM w0.127: v1(162.31,52.83) 162.81,53.34 162.81,54.56 161.37,56.01 160.74,56.01 160.74,56.01 160.7,56.01 160.13,56.58 160.13,56.58 160.06,56.64 159.87,56.64 157.23,56.64 154.69,59.18 154.69,60.66 152.46,62.89 152.46,63.73 152.46,63.73 152.46,64.48 152.46,68.71 152.91,69.15 152.91,71.12 154.3,72.52 154.3,73.15 159.07,77.91 172.47,77.91 172.83,77.91 184.15,89.23 184.15,105.23 182.58,106.81 R118.2
EC2_TXD2: length 82.6
  TOP w0.127: U46.25 160.7,53.38 161.29,53.98 v1(161.29,54.74)
  BOTTOM w0.127: v1(161.29,54.74) 160.91,55.12 160.37,55.12 160.33,55.12 159.76,55.69 159.7,55.75 159.5,55.75 156.84,55.75 156.59,56.01 156.58,56.01 156.52,56.07 155.13,56.07 153.67,57.53 153.67,60.2 151.51,62.36 151.51,71.37 152.91,72.77 152.91,73.9 157.81,78.8 172.47,78.8 183.26,89.6 183.26,104.87 182.34,105.79 R120.2
EC2_TXD3: length 83.4
  TOP w0.127: U46.26 160.3,53.49 160.53,53.72 160.53,54.1 v1(160.66,54.23)
  BOTTOM w0.127: R122.2 182.22,105.28 182.82,104.68 182.82,89.78 172.28,79.25 157.63,79.25 152.4,74.02 152.4,72.9 151.07,71.56 151.07,62.17 153.23,60.01 153.23,57.34 154.94,55.63 156.34,55.63 156.65,55.31 159.32,55.31 159.51,55.31 160.59,54.23 v1(160.66,54.23)
EMI1_MDC: length 127.2
  TOP w0.127: U55.C11 216.7,70.77 v2(216.92,70.99) ; U56.C11 250.99,70.77 v2(251.21,70.99) ; v1(185.42,67.56) 185.63,67.35 U52.72 ; U23.2 148.34,58.67 v1(148.59,58.93) ; U46.30 158.7,53.9 158.5,54.1 v1(158.5,54.36)
  L3SIG w0.102: v1(185.42,67.56) 184.66,66.8 184.66,64.76 184.43,64.54 184.43,62.76 182.98,61.32 181.2,61.32 179.95,60.06 179.95,59.56 177.86,57.46 176.72,57.46 170.31,51.05 166.5,51.05 161.82,55.73 160.13,55.73 159.77,55.37 158.88,55.37 158.5,54.99 v1(158.5,54.36)
  L6SIG w0.102: v1(158.5,54.36) 157.99,54.36 156.88,55.46 156.88,58.13 155.32,59.69 150.5,59.69 149.73,58.93 v1(148.59,58.93) ; v1(185.42,67.56) 185.67,67.82 194.18,67.82 194.95,68.58 203.96,68.58 204.34,68.2 206,68.2 206.15,68.35 208.64,68.35 209.04,67.95 209.93,67.95 211.45,69.47 214,69.47 215.14,70.61 216.53,70.61 v2(216.92,70.99) 217.68,70.23 222,70.23 222.5,69.72 223.39,69.72 223.9,70.23 233.93,70.23 234.57,70.87 247.27,70.87 247.52,70.61 250.82,70.61 v2(251.21,70.99)
EMI1_MDC_SLP: length 85.5
  TOP w0.127: U49.30 136.47,54.54 136.27,54.74 v1(136.27,54.99) ; R132.2 146.45,59.32 U23.1 147.77,59.88 v1(148.08,60.2)
  L6SIG w0.102: v1(148.08,60.2) 147.7,60.2 145.92,58.42 144.91,58.42 143.38,56.9 142.09,56.9 141.43,56.23 141.43,56.21 140.08,54.86 136.4,54.86 v1(136.27,54.99)
  BOTTOM w0.127: R129.1 182.37,104.26 182.37,89.97 172.1,79.69 157.81,79.69 157.44,79.69 150.62,72.87 150.62,64.64 148.4,62.42 148.4,60.52 v1(148.08,60.2)
EMI1_MDIO: length 125.9
  TOP w0.127: v2(216.28,69.98) 216.15,69.84 U55.D10 ; U56.D10 250.44,69.84 v2(250.57,69.98) ; v1(185.67,66.8) 185.82,66.95 U52.73 ; U24.2 148.34,55.88 v1(148.59,56.13) ; U46.31 158.3,53.54 v1(158.11,53.72)
  L3SIG w0.102: v1(185.67,66.8) 185.67,65.28 184.78,64.39 184.78,62.61 183.13,60.96 181.36,60.96 180.31,59.91 180.31,59.4 177.93,57.02 176.91,57.02 170.56,50.67 166.37,50.67 161.67,55.37 160.27,55.37 158.62,53.72 v1(158.11,53.72)
  L6SIG w0.102: v1(185.67,66.8) 186.31,67.44 194.31,67.44 195.07,68.2 203.1,68.2 203.66,67.64 205.94,67.64 206.3,68 208.36,68 208.79,67.56 210.19,67.56 211.71,69.09 214.25,69.09 215.39,70.23 216.03,70.23 v2(216.28,69.98) 216.38,69.88 221.09,69.88 221.68,69.28 223.46,69.28 223.97,69.8 234.01,69.8 234.7,70.48 247.14,70.48 247.4,70.23 250.32,70.23 v2(250.57,69.98) ; v1(158.11,53.72) 156.53,55.31 156.53,57.98 155.83,58.67 150.62,58.67 148.59,56.64 v1(148.59,56.13)
EMI1_MDIO_SLP: length 91.2
  TOP w0.127: U49.31 136.07,54.17 v1(135.89,54.36) ; U1.AH4 177.66,104.9 177.77,104.9 177.77,104.9 179.35,104.9 180.21,104.9 181.48,103.63 v1(181.48,102.62) ; R131.2 146.45,56.53 U24.1 147.77,56.96 v1(147.45,57.28)
  L6SIG w0.102: v1(147.45,57.28) 146.68,56.51 142.23,56.51 140.21,54.48 138.43,54.48 137.79,53.85 136.4,53.85 v1(135.89,54.36)
  BOTTOM w0.127: v1(147.45,57.28) 147.38,57.34 147.38,60.39 147.95,60.96 147.95,62.61 150.18,64.83 150.18,73.06 157.26,80.14 157.99,80.14 171.91,80.14 181.86,90.09 181.86,102.36 181.61,102.62 v1(181.48,102.62)
EMI2_MDC: length 41.5
  TOP w0.127: U57.G1 v1(163.79,63.65)
  L3SIG w0.102: v1(164.21,95.76) 164.47,95.5 164.47,77.09 162.51,75.13 162.51,66.73 163,66.23 163,65.72 163.79,64.94 v1(163.79,63.65)
  BOTTOM w0.127: v1(164.21,95.76) 163.7,96.27 163.7,100.84 164.21,101.35 R130.2 ; R134.2 164.29,64.15 v1(163.79,63.65)
EMI2_MDIO: length 46.3
  TOP w0.127: U1.M6 v2(163.72,106.85) ; U57.F1 v1(163.79,65.65)
  L3SIG w0.102: v1(165.35,97.03) 165.29,96.96 165.29,96.88 164.85,96.43 164.85,76.92 162.94,75.01 162.94,67.82 163.36,67.4 163.36,67.25 163.37,67.24 163.37,66.88 163.36,66.86 163.36,66.08 v1(163.79,65.65)
  BOTTOM w0.127: v2(163.72,106.85) 163.72,106.85 164.12,106.45 164.12,105.08 164.37,104.84 165.48,104.84 165.79,104.53 165.79,100.76 165.29,100.26 165.29,97.09 v1(165.35,97.03) ; v1(163.79,65.65) 164.29,65.15 R133.2
EVDD: length 29.4
  TOP w0.305: U1.L8 v2(162.92,108.45)
  TOP w0.508: Q33.2 Q34.2 50.43,143.44 R815.2 50.43,134.49 51.43,133.48 51.43,128.02 v1(52.2,127.25) v1(52.2,126.62)
  BOTTOM w0.508: R68.2 R60.2 R62.2 v1(154.43,96.01) ; R63.2 R64.2 R67.2 v1(158.5,96.01)
EVDD_SEL: length 38.4
  TOP w0.127: v1(51.41,108.03) 53.71,108.03 54.61,108.93 U65.F1 ; v1(41.78,126.75) 41.78,130.54 42.44,131.19 43.94,131.19 44.32,131.56 R820.1
  L6SIG w0.102: v1(51.41,108.03) 50.72,108.03 50.42,108.33 47.24,108.33 42.16,113.41 42.16,120.52 42.67,121.03 42.67,125.86 v1(41.78,126.75)
EVT_BRD_ISO: length 95.3
  TOP w0.127: U1.A3 151.19,104.85 151.19,104.84 150.82,104.84 150.81,104.85 148.52,104.85 135.13,118.24 112.27,118.24 111.38,117.35 86.11,117.35 73.68,104.93 v1(72.72,104.93) U65.K16
  BOTTOM w0.127: v1(72.72,104.93) 72.95,105.16 R81.1
EVT_PWR_EN: length 99.3
  TOP w0.127: U65.L15 71.52,103.42 v1(71.52,103.42) 73.71,103.42 86.49,116.2 111.76,116.2 112.65,117.09 134.75,117.09 149.73,102.11 156.08,102.11 156.92,102.94 U1.C1
  BOTTOM w0.127: R85.1 v1(71.52,103.42)
EVT_PWR_OK: length 100.4
  TOP w0.127: U1.C2 156.88,104.05 156.46,103.63 156.46,103 155.83,102.36 149.99,102.36 134.87,117.48 112.52,117.48 111.63,116.59 86.36,116.59 73.7,103.93 72.72,103.93 v1(72.72,103.92) 72.72,103.93 U65.L16
  BOTTOM w0.127: v1(72.72,103.92) 71.22,105.43 R813.1
FAN_PWM: length 15.8
  TOP w0.127: Q27.1 53.91,123.63 54.99,122.56 54.99,111.95 U65.E1
FXO_LED: length 145.8
  TOP w0.127: v1(58.51,108.43) 59.01,108.93 U65.F3 ; R470.1 48.65,11.17 46.74,13.08 21.84,13.08 18.54,16.38 18.54,52.45 v1(18.67,52.58)
  L6SIG w0.102: v1(18.67,52.58) 18.67,53.34 19.18,53.85 19.18,55.63 37.41,73.86 37.41,79.96 40.29,82.84 40.29,89.25 41.94,90.9 45.37,90.9 52.45,97.97 52.45,104.14 56.24,107.93 58.01,107.93 v1(58.51,108.43)
FXO_RING: length 13.1
  L3SIG w0.508: J24.2 117,7.78 118.49,9.27 118.49,11.18 117.09,12.57 117.09,16.13 117.98,17.02 J25.2
FXO_TIP: length 8.8
  L3SIG w0.508: J24.3 115.01,15.04 113.07,16.98 J25.9
FXS1_LED: length 132.3
  TOP w0.127: U65.E2 58.01,109.93 v1(57.51,109.43) ; v1(17.27,53.72) 17.02,53.47 17.02,15.88 21.34,11.56 31.62,11.56 32.39,10.79 R439.1
  L6SIG w0.102: v1(57.51,109.43) 55.81,109.43 51.69,105.31 51.69,98.36 45.04,91.7 41.61,91.7 39.49,89.58 39.49,83.17 36.61,80.29 36.61,74.2 18.41,56.01 18.41,55.4 17.78,54.76 17.78,54.23 v1(17.27,53.72)
FXS2_LED: length 137.6
  TOP w0.127: v1(58.51,110.43) 59.01,110.93 U65.D3 ; R440.1 36.71,10.66 35.43,11.94 21.46,11.94 17.4,16 17.4,53.09 17.78,53.47 v1(17.78,55.37)
  L6SIG w0.102: v1(17.78,55.37) 17.78,55.75 36.34,74.31 36.34,80.41 39.22,83.29 39.22,89.69 41.5,91.97 44.93,91.97 51.43,98.48 51.43,105.53 55.83,109.93 58.01,109.93 v1(58.51,110.43)
FXS3_LED: length 138.6
  TOP w0.127: R471.1 41.03,11.04 39.75,12.32 21.59,12.32 17.78,16.13 17.78,52.96 18.29,53.47 v1(18.29,53.72) ; v1(57.51,108.43) 58.01,108.93 U65.F2
  L6SIG w0.102: v1(18.29,53.72) 18.92,54.36 18.92,55.75 37.14,73.97 37.14,80.07 40.03,82.95 40.03,89.36 41.83,91.17 45.26,91.17 52.2,98.1 52.2,104.41 56.21,108.43 v1(57.51,108.43)
FXS4_LED: length 144.7
  TOP w0.127: v1(18.29,54.61) 18.8,54.1 18.8,53.47 18.16,52.83 18.16,16.26 21.72,12.7 43.81,12.7 45.35,11.17 R472.1 ; v1(58.51,109.43) 59.01,109.93 U65.E3
  L6SIG w0.102: v1(58.51,109.43) 58.01,108.93 55.91,108.93 51.94,104.96 51.94,98.23 45.15,91.43 41.72,91.43 39.76,89.47 39.76,83.06 36.88,80.18 36.88,74.09 18.67,55.88 18.67,54.99 v1(18.29,54.61)
FXS_RING: length 19.4
  L3SIG w0.508: J23.A3 103.66,20.95 106.43,20.95 109.09,18.29 114.94,18.29 116.2,19.56 J25.3
FXS_TIP: length 13.1
  L3SIG w0.508: J25.8 109.9,19.52 105.66,23.75 102.14,23.75 J23.A4
GPIO_CKE_ISO: length 146.4
  TOP w0.127: v1(172.59,91.19) 173.23,91.19 173.74,91.69 173.74,95 173.35,95.38 v1(173.35,97.03) ; U1.AC5 v2(173.32,106.05) ; U65.P13 v1(69.52,100.42)
  L3SIG w0.102: v1(173.35,97.03) 173.35,99.44 173.73,99.82 173.73,104.65 173.32,105.07 v2(173.32,106.05)
  L6SIG w0.102: v1(69.52,100.42) 70.02,99.92 70.02,97.49 70.74,96.77 75.44,96.77 77.09,95.12 77.09,88.9 79.12,86.87 83.31,86.87 84.71,85.47 87.12,85.47 90.93,81.66 102.49,81.66 105,84.18 113.69,84.18 118.75,79.12 143.38,79.12 156.51,92.25 160.07,92.25 160.38,91.95 164.59,91.95 168.4,88.14 170.56,88.14 172.59,90.17 v1(172.59,91.19)
  BOTTOM w0.127: v1(173.35,97.03) 173.1,97.28 R78.1
HRESET_N: length 100.4
  TOP w0.127: U65.D14 v1(70.52,111.43) ; U1.E8 v2(158.12,108.45)
  L6SIG w0.102: v1(70.52,111.43) 73.97,111.43 79.5,116.97 125.98,116.97 126.95,116 136.86,116 147.19,105.66 150.65,105.66 150.83,105.85 151.19,105.85 151.38,105.66 155.84,105.66 156.09,105.41 156.84,105.41 157.06,105.63 157.44,105.63 157.7,105.89 157.7,106.97 157.96,107.23 158.24,107.23 158.5,107.49 158.5,108.07 v2(158.12,108.45)
  BOTTOM w0.127: v1(70.52,111.43) 71.32,110.63 R96.2
I2C1_SCL: length 236.3
  TOP w0.127: U44.6 v1(240.41,149.86) R91.1 ; v1(170.05,90.68) 169.68,90.3 Q39.2
  L3SIG w0.102: v1(144.27,105.28) 144.27,117.48 140.84,120.9 v1(140.84,121.5) ; v1(170.05,90.68) 170.56,90.17 186.94,90.17 189.36,92.58 200.53,92.58 230,122.05 230,139.19 232.16,141.35 236.85,141.35 240.92,145.41 240.92,149.35 v1(240.41,149.86) 239.9,150.37 229.36,150.37 224.92,154.81 J1.118
  L6SIG w0.102: v1(170.05,90.68) 169.54,91.19 168.53,91.19 166.24,93.47 161.67,93.47 160.78,94.36 155.73,94.36 154.94,93.57 154.94,92.71 142.75,80.52 131.32,80.52 128.78,83.06 128.78,98.81 131.57,101.6 142.75,101.6 144.27,103.12 v1(144.27,105.28)
  BOTTOM w0.127: U45.8 v1(140.84,121.5) ; Q1.3 170.44,90.29 v1(170.05,90.68)
I2C1_SCL_SLP: length 206
  TOP w0.127: v1(168.15,89.54) 167.98,89.54 167.38,88.93 Q39.3 ; U97.9 238,133.47 238.25,133.22 238.76,133.22 v1(239.39,132.59)
  L3SIG w0.102: v1(168.15,89.54) 168.27,89.66 186.94,89.66 189.48,92.2 200.66,92.2 237.24,128.78 238,128.78 238.38,129.16 238.38,131.95 239.01,132.59 v1(239.39,132.59)
  L6SIG w0.102: v1(168.15,89.54) 164.97,92.71 155.96,92.71 143,79.76 119,79.76 113.92,84.84 103,84.84 102.49,84.33 98.81,84.33 97.03,86.11 v1(97.03,86.61)
  BOTTOM w0.127: U70.16 97.69,85.32 97.03,85.98 v1(97.03,86.61) R570.2 96.26,86.88 95.89,87.25 94.11,87.25 92.71,85.85 80.65,85.85 75.95,90.55 75.95,92.71 J28.3
I2C1_SDA: length 253.7
  TOP w0.127: Q40.2 167.58,86.93 168.27,87.63 168.27,88.52 168.85,89.09 168.85,90.36 v1(169.16,90.68) ; R90.1 v1(240.41,148.72) 240.28,148.59 U44.5
  L3SIG w0.102: J1.238 224.92,156.97 224.16,156.21 224.16,154.94 229.11,149.99 239.14,149.99 v1(240.41,148.72) 240.41,145.54 236.6,141.73 232.03,141.73 229.62,139.32 229.62,122.17 200.41,92.96 189.23,92.96 186.82,90.55 171.07,90.55 170.45,91.17 169.65,91.17 v1(169.16,90.68) ; v1(139.83,121.67) 139.83,121.41 143.89,117.35 143.89,106.17 v1(143.51,105.79)
  L6SIG w0.102: v1(143.51,105.79) 143.51,103 142.49,101.98 131.44,101.98 128.4,98.93 128.4,82.93 131.19,80.14 142.88,80.14 155.7,92.96 156.21,92.96 157.23,93.98 160.66,93.98 161.54,93.09 166.12,93.09 168.53,90.68 v1(169.16,90.68)
  BOTTOM w0.127: Q2.3 164.08,88.91 165.1,87.88 169.16,87.88 169.61,88.33 169.61,90.23 v1(169.16,90.68) ; v1(139.83,121.67) 139.83,121.54 140.52,120.85 U45.7
I2C1_SDA_SLP: length 206.6
  TOP w0.127: v1(240.28,132.59) 239.27,133.6 238.51,133.6 238.4,133.71 U97.10 ; Q40.3 168.53,87.25 168.78,87.5 168.78,88.27 v1(169.16,88.65)
  L3SIG w0.102: v1(169.16,88.65) 169.8,89.28 187.07,89.28 189.61,91.82 200.79,91.82 237.36,128.4 238.25,128.4 239.65,129.79 239.65,131.95 v1(240.28,132.59)
  L6SIG w0.102: v1(97.03,85.22) 98.17,84.07 102.74,84.07 103.12,84.45 113.79,84.45 118.87,79.38 143.13,79.38 156.24,92.48 160.17,92.48 160.32,92.33 164.72,92.33 168.4,88.65 v1(169.16,88.65)
  BOTTOM w0.127: J28.1 77.09,88.9 80.52,85.47 92.96,85.47 93.6,86.11 96.01,86.11 96.26,85.86 R569.2 96.65,85.6 v1(97.03,85.22) 97.43,84.82 U70.15
I2C2_MPEX1_SCL: length 113.8
  TOP w0.127: R398.1 255.96,154 U19.5 255.96,151.46 256.67,150.75 258.7,150.75 259.59,151.64 259.59,155.57 258.19,156.97 250.32,156.97 238.25,169.04 197.87,169.04 193.04,173.86 193.04,195.98 190.34,198.68 J19.30
I2C2_MPEX1_SDA: length 111.6
  TOP w0.127: J19.32 190.51,197.88 192.66,195.72 192.66,173.35 197.36,168.66 238.12,168.66 250.19,156.59 258.06,156.59 259.21,155.45 259.21,151.76 258.57,151.13 256.92,151.13 256.61,151.44 U19.4 256.61,154.37 R404.1
I2C2_MPEX2_SCL: length 199.3
  TOP w0.127: U19.7 254.66,154.14 R409.1 254.37,154.3 253.87,153.8 251.97,153.8 237.87,167.89 119.51,167.89 90.55,196.85 87.12,196.85 84.2,199.77 84.2,203.44 82.96,204.68 J20.30
I2C2_MPEX2_SDA: length 200.4
  TOP w0.127: U19.6 255.31,153.63 254.94,154 254.94,155.27 254.76,155.45 R410.1 254.37,155.84 254,156.21 250.06,156.21 238,168.27 119.63,168.27 90.68,197.23 87.25,197.23 84.58,199.9 84.58,203.69 82.8,205.48 J20.32
I2C2_PEX_SCL: length 91.7
  TOP w0.127: R406.1 255.96,145.1 U19.12 255.96,147.9 v1(255.91,147.95)
  L6SIG w0.102: J18.B5 275.08,87.11 275.08,87.5 275.72,88.14 276.48,88.14 276.99,88.65 276.99,143 275.34,144.65 275.34,148.08 271.78,151.64 269.24,151.64 267.08,153.8 261.75,153.8 v1(255.91,147.95)
I2C2_PEX_SDA: length 90.9
  TOP w0.127: R407.1 255.31,145.07 U19.11 255.31,148.25 v1(255.78,148.72)
  L6SIG w0.102: v1(255.78,148.72) 261.11,154.05 267.21,154.05 269.37,151.89 272.03,151.89 275.62,148.31 275.62,144.75 277.24,143.13 277.24,88.27 J18.B6
I2C2_SFPP_SCL: length 154.4
  TOP w0.127: J16.5 177.32,37.18 v1(177.16,37.34) ; v1(253.62,129.54) 253.62,141.73 254.38,142.49 254.38,145.41 254.66,145.69 U19.10
  L3SIG w0.102: v1(177.16,37.34) 177.16,37.72 181.35,41.91 181.35,42.42 180.85,42.93 180.85,49.02 182.12,50.29 182.12,52.07 184.15,54.1 184.91,54.1 186.69,55.88 186.69,67.95 186.31,68.33 186.31,70.99 187.58,72.26 187.58,78.49 189.23,80.14 190.25,80.14 237.62,127.51 251.59,127.51 v1(253.62,129.54)
  BOTTOM w0.127: v1(177.16,37.34) 177.04,37.46 R392.1
I2C2_SFPP_SDA: length 154.2
  TOP w0.127: J16.4 176.52,36.71 v1(176.4,36.83) ; v1(253.11,130.17) 253.11,141.73 254.01,142.63 U19.9
  L3SIG w0.102: v1(253.11,130.17) 250.82,127.89 237.49,127.89 190.88,81.28 189.89,81.28 187.2,78.59 187.2,72.39 185.93,71.12 185.93,68.2 186.31,67.82 186.31,56.01 184.78,54.48 184.02,54.48 181.74,52.2 181.74,50.42 180.49,49.17 180.49,41.55 176.4,37.46 v1(176.4,36.83)
  BOTTOM w0.127: R391.1 176.02,37.21 v1(176.4,36.83)
IFC_A5: length 16.3
  TOP w0.127: v1(107.95,118.62) 107.88,118.68 U10.1
  BOTTOM w0.127: R14.2 122.44,121.03 113.41,121.03 111,118.62 v1(107.95,118.62)
IFC_A6: length 19.9
  TOP w0.127: U9.1 104.54,119.24 105.16,118.62 v1(107.19,118.62)
  BOTTOM w0.127: R15.2 121.67,121.92 121.16,121.41 113.16,121.41 110.87,119.13 107.7,119.13 v1(107.19,118.62)
IFC_A7: length 16.5
  TOP w0.127: v1(109.98,121.79) 110.13,121.64 110.13,119.99 110.89,119.24 U8.1
  BOTTOM w0.127: v1(109.98,121.79) 120.78,121.79 121.92,122.94 R16.2
IFC_A8: length 5.9
  TOP w0.127: v1(118.49,122.43) 118.52,122.4 U4.2
  BOTTOM w0.127: R18.2 119.63,123.57 v1(118.49,122.43)
IFC_A9: length 17.3
  TOP w0.127: U4.15 115.32,128.9 115.32,128.91 v1(115.19,128.91)
  BOTTOM w0.127: R20.2 117.6,124.21 115.19,126.62 v1(115.19,128.91)
IFC_A10: length 12.4
  TOP w0.127: U4.12 115.72,127.4 v1(115.7,127.38)
  BOTTOM w0.127: v1(115.7,127.38) 115.7,126.75 117.6,124.84 R22.2
IFC_A11: length 12.6
  TOP w0.127: U4.11 116.23,126.9 v1(116.2,126.87)
  BOTTOM w0.127: v1(116.2,126.87) 117.6,125.48 R24.2
IFC_A12: length 14.9
  TOP w0.127: U4.18 119.35,130.4 118.24,129.29 115.7,129.29 v1(115.19,129.79)
  BOTTOM w0.127: R26.2 117.6,126.11 116.2,127.51 116.2,128.78 v1(115.19,129.79)
IFC_A13: length 15
  TOP w0.127: U4.19 119.22,130.9 118.11,129.79 v1(115.95,129.79)
  BOTTOM w0.127: v1(115.95,129.79) 116.59,129.16 116.59,127.76 117.6,126.75 R28.2
IFC_A14: length 26
  TOP w0.127: U4.54 107.15,122.9 v1(107.32,123.06)
  BOTTOM w0.127: v1(107.32,123.06) 107.32,123.95 113.67,130.3 116.08,130.3 116.97,129.41 116.97,128.02 117.73,127.25 120.65,127.25 121.16,127.76 R30.2
IFC_A15: length 26.9
  TOP w0.127: v1(116.46,131.44) 115.95,131.44 113.73,129.22 113.73,124.02 114.94,122.81 116.21,122.81 116.3,122.9 U4.3
  BOTTOM w0.127: v1(116.46,131.44) 116.46,130.43 117.35,129.54 117.35,128.21 117.79,127.76 120.27,127.76 121.29,128.78 R32.2
IFC_A16: length 122.6
  TOP w0.127: SW2.5 v1(90.55,136.52) 90.55,136.14 89.92,135.51 88.77,135.51 85.47,132.21 85.47,126.99 85.73,126.74 85.73,125.74 85.47,125.48 85.47,122.3 74.1,110.93 U65.D16 ; v1(115.7,123.32) 115.78,123.4 U4.4 ; U1.C5 v2(156.52,106.05)
  L6SIG w0.102: v2(156.52,106.05) 156.14,106.43 147.19,106.43 137.16,116.46 127.25,116.46 125.09,118.62 123.06,118.62 118.36,123.32 v1(115.7,123.32) 111.89,123.32 106.3,128.91 103.63,128.91 102.11,130.43 96.53,130.43 90.55,136.41 v1(90.55,136.52)
  BOTTOM w0.127: R797.2 v1(90.55,136.52)
IFC_A17: length 125.2
  TOP w0.127: U4.5 116.2,123.9 116.13,123.83 v1(114.68,123.83) ; U65.E15 71.52,110.43 74.11,110.43 85.85,122.17 85.85,125.35 86.11,125.6 86.11,126.87 85.85,127.13 85.85,132.08 88.9,135.13 90.68,135.13 91.82,136.27 v1(91.82,136.52) SW2.6 ; U1.C6 v2(156.52,106.85)
  L6SIG w0.102: v2(156.52,106.85) 156.35,106.68 147.32,106.68 137.29,116.71 127.38,116.71 125.25,118.85 123.22,118.85 118.24,123.83 v1(114.68,123.83) 111.89,123.83 105.79,129.92 103.63,129.92 102.17,131.38 96.08,131.38 91.82,135.64 v1(91.82,136.52)
  BOTTOM w0.127: R798.2 v1(91.82,136.52)
IFC_A18: length 91.8
  TOP w0.127: v1(115.7,124.33) 115.77,124.4 U4.6 ; SW2.3 v1(88.01,136.52) ; U1.D7 v2(157.32,107.65)
  L6SIG w0.102: v2(157.32,107.65) 157.3,107.65 156.88,107.23 156.36,107.23 156.07,106.93 147.45,106.93 137.41,116.97 127.51,116.97 125.4,119.08 123.37,119.08 118.11,124.33 v1(115.7,124.33) 111.89,124.33 105.28,130.94 103.63,130.94 102.23,132.33 95.63,132.33 92.33,135.64 92.33,136.63 91.92,137.03 90.45,137.03 89.43,136.02 88.52,136.02 v1(88.01,136.52)
  BOTTOM w0.127: R799.2 v1(88.01,136.52)
IFC_A19: length 90.4
  TOP w0.127: U1.C7 v2(156.52,107.65) ; SW2.4 v1(89.28,136.52) ; v1(114.68,124.84) 114.74,124.9 U4.7
  L6SIG w0.102: v2(156.52,107.65) 156.29,107.65 155.83,107.19 147.57,107.19 137.54,117.22 127.64,117.22 125.55,119.3 123.52,119.3 117.98,124.84 v1(114.68,124.84) 111.89,124.84 104.78,131.95 103.51,131.95 102.74,132.72 95.88,132.72 92.66,135.94 92.66,136.83 92.08,137.41 90.17,137.41 v1(89.28,136.52)
  BOTTOM w0.127: R800.2 v1(89.28,136.52)
IFC_A20: length 58.5
  TOP w0.127: U1.D8 v2(157.32,108.45) ; U4.8 115.75,125.4 v1(115.7,125.35)
  L6SIG w0.102: v2(157.32,108.45) 157.32,108.42 156.92,108.03 154.86,108.03 154.85,108.04 154.54,108.04 154.53,108.03 151.19,108.03 151.17,108.05 150.84,108.05 150.82,108.03 147.12,108.03 137.67,117.48 127.76,117.48 125.7,119.53 123.67,119.53 117.86,125.35 v1(115.7,125.35)
  BOTTOM w0.127: v1(115.7,125.35) R13.2 R864.2
IFC_A21: length 84.1
  TOP w0.127: v1(114.68,125.86) 114.72,125.9 U4.9 ; U1.C8 v2(156.52,108.45) ; SW2.7 v1(93.09,136.52)
  L6SIG w0.102: v1(93.09,136.52) 93.09,136.02 96.01,133.1 104.14,133.1 111.38,125.86 v1(114.68,125.86) 117.73,125.86 123.82,119.76 125.86,119.76 127.89,117.73 137.79,117.73 147.08,108.45 v2(156.52,108.45)
IFC_A22: length 58.2
  TOP w0.127: U1.D9 v2(157.32,109.25) ; U4.10 115.15,126.4 v1(114.68,126.87)
  L6SIG w0.102: v1(114.68,126.87) 115.19,126.37 117.6,126.37 123.98,119.99 126.01,119.99 128.02,117.98 137.92,117.98 147.07,108.84 156.91,108.84 v2(157.32,109.25)
IFC_A23: length 57.4
  TOP w0.127: v1(117.22,131.44) 117.26,131.4 U4.20 ; U1.C9 v2(156.52,109.25)
  L6SIG w0.102: v1(117.22,131.44) 117.98,130.68 117.98,126.37 124.13,120.22 126.16,120.22 128.14,118.24 138.05,118.24 147.17,109.12 150.02,109.12 150.04,109.09 156.36,109.09 v2(156.52,109.25)
  BOTTOM w0.127: R810.2 116.46,132.21 v1(117.22,131.44)
IFC_A24: length 59.5
  TOP w0.127: U4.21 117.53,131.9 v1(117.22,132.21) ; U1.D10 v2(157.32,110.05)
  L6SIG w0.102: v1(117.22,132.21) 118.36,131.06 118.36,126.37 124.28,120.45 126.31,120.45 128.27,118.49 138.18,118.49 147.32,109.35 155.96,109.35 156.24,109.63 156.87,109.63 157.29,110.05 v2(157.32,110.05)
  BOTTOM w0.127: v1(117.22,132.21) 117.22,132.84 116.84,133.22 R809.2
IFC_A25: length 56.5
  TOP w0.127: v1(117.86,132.59) 118.04,132.4 U4.22 ; U1.C10 v2(156.52,110.05)
  L6SIG w0.102: v2(156.52,110.05) 156.27,110.05 155.83,109.6 147.45,109.6 138.3,118.75 128.4,118.75 125.6,121.54 123.7,121.54 121.67,123.57 121.67,129.54 120.78,130.43 120.02,130.43 v1(117.86,132.59)
IFC_A26: length 51.6
  TOP w0.127: U4.23 v1(120.71,132.9) ; U1.E11 v2(158.12,110.85)
  L6SIG w0.102: v1(120.71,132.9) 123.57,130.04 123.57,125.09 124.21,124.46 124.59,124.46 129.03,120.02 138.94,120.02 146.93,112.03 149.25,112.03 149.31,111.97 149.67,111.97 149.72,112.03 156.67,112.03 156.81,111.89 157.02,111.89 157.16,112.03 157.47,112.03 157.73,111.77 157.73,111.23 v2(158.12,110.85)
IFC_A27: length 129.4
  TOP w0.127: U4.24 119.43,133.4 v1(119,132.97) ; U1.C11 v2(156.52,110.85) ; U65.C13 v1(69.52,112.43)
  L3SIG w0.102: v1(119,132.97) 118.24,132.97 117.98,133.22 115.57,133.22 115.14,133.65 106.48,133.65 105.99,133.17 93.27,133.17 92.9,133.54 85.92,133.54 82.04,137.41 72.39,137.41 71.12,136.14 71.12,129.79 69.52,128.19 v1(69.52,112.43)
  L6SIG w0.102: v1(119,132.97) 122.43,129.54 122.43,123.7 124.08,122.05 125.86,122.05 128.65,119.25 138.56,119.25 146.96,110.85 v2(156.52,110.85)
IFC_A28: length 132.9
  TOP w0.127: v1(68.52,112.43) 68.02,111.93 U65.C12 ; U1.D11 v2(157.32,110.85) ; U4.25 118.66,133.9 v1(118.36,133.6)
  L3SIG w0.102: v1(68.52,112.43) 68.52,128.21 70.36,130.05 70.36,136.27 72.26,138.18 82.42,138.18 86.11,134.49 104.01,134.49 104.52,133.98 115.32,133.98 115.7,133.6 v1(118.36,133.6)
  L6SIG w0.102: v1(118.36,133.6) 118.36,132.72 120.27,130.81 120.78,130.81 122.05,129.54 122.05,123.57 123.83,121.79 125.73,121.79 128.52,119 138.43,119 146.96,110.47 156.94,110.47 v2(157.32,110.85)
IFC_A29: length 131.5
  TOP w0.127: U1.C12 v2(156.52,111.65) ; U4.26 120.44,134.4 v1(120.44,134.4) ; U65.C11 67.02,111.93 v1(67.52,112.43)
  L3SIG w0.102: v1(120.44,134.4) 119.98,134.4 119.25,135.13 102.11,135.13 101.55,135.69 87.2,135.69 83.95,138.94 72.14,138.94 69.6,136.4 69.6,130.3 67.52,128.22 v1(67.52,112.43)
  L6SIG w0.102: v2(156.52,111.65) 146.93,111.65 138.79,119.79 128.88,119.79 125.51,123.16 125.35,123.32 123.95,123.32 123.19,124.08 123.19,129.79 120.14,132.84 120.14,134.1 v1(120.44,134.4)
IFC_A30: length 146.3
  TOP w0.127: U1.D12 v2(157.32,111.65) ; v1(118.36,134.37) 118.33,134.4 U4.31 ; U65.D12 v1(68.52,111.43)
  L3SIG w0.102: v1(118.36,134.37) 104.65,134.37 104.19,134.82 86.24,134.82 82.5,138.56 72.14,138.56 69.98,136.4 69.98,130.17 68.09,128.29 68.09,111.86 v1(68.52,111.43)
  L6SIG w0.102: v2(157.32,111.65) 156.92,111.25 146.94,111.25 138.68,119.51 128.78,119.51 125.28,123 123.76,123 122.81,123.95 122.81,129.79 118.36,134.24 v1(118.36,134.37)
IFC_A31: length 135.6
  TOP w0.127: v1(115.19,137.92) 110.36,137.92 106.93,141.35 74.3,141.35 71.63,138.68 71.63,125.73 61.02,115.12 U65.A5 ; U1.E12 v2(158.12,111.65)
  L6SIG w0.102: v1(115.19,137.92) 115.7,138.43 120.65,138.43 125.98,133.1 125.98,124.59 129.54,121.03 139.45,121.03 146.81,113.67 156.64,113.67 156.9,113.4 156.9,113.1 157.14,112.87 157.52,112.87 157.73,112.65 157.73,112.27 158.12,111.89 v2(158.12,111.65)
IFC_AD0: length 102.7
  TOP w0.127: v1(83.19,123.83) 83.19,122.56 79.63,119 73.79,119 69.02,114.23 U65.A13 ; v1(100.64,124.4) U4.51 108.52,124.4 114.3,118.62 135.25,118.62 148.15,105.73 155.23,105.73 U1.A4
  BOTTOM w0.127: U99.4 83.02,123.99 v1(83.19,123.83) 83.31,123.7 84.07,123.7 86.87,120.9 96.52,120.9 100.02,124.4 v1(100.64,124.4)
IFC_AD1: length 105.7
  TOP w0.127: U1.B5 155.71,106.05 148.34,106.05 135.38,119 114.43,119 108.02,125.4 U4.49 v1(101.17,125.4) ; U65.B13 69.52,113.43 69.52,114.1 74.04,118.62 79.76,118.62 83.82,122.68 v1(83.82,124.21)
  BOTTOM w0.127: U99.3 83.64,124.39 v1(83.82,124.21) 84.2,124.21 87.12,121.29 96.27,121.29 100.38,125.4 v1(101.17,125.4)
IFC_AD2: length 106.2
  TOP w0.127: v1(83.31,124.84) 82.68,124.21 82.68,122.56 79.5,119.38 73.66,119.38 68.52,114.24 68.52,113.43 U65.B12 ; v1(101.17,126.4) U4.47 107.53,126.4 114.55,119.38 135.51,119.38 148.44,106.45 U1.A5
  BOTTOM w0.127: v1(101.17,126.4) 100.75,126.4 96.01,121.67 87.38,121.67 84.2,124.84 v1(83.31,124.84) 83.26,124.79 U99.2
IFC_AD3: length 108.1
  TOP w0.127: v1(83.82,125.48) 83.31,125.48 82.3,124.46 82.3,122.68 79.38,119.76 73.53,119.76 68.02,114.24 U65.A12 ; U1.B6 155.68,106.81 148.59,106.81 135.64,119.76 114.68,119.76 107.04,127.4 U4.45 v1(101.17,127.4)
  BOTTOM w0.127: U99.1 82.9,125.19 83.19,125.48 v1(83.82,125.48) 84.2,125.48 87.63,122.05 95.81,122.05 v1(101.17,127.4)
IFC_AD4: length 112.6
  TOP w0.127: v1(83.19,129.92) 83.44,129.67 83.44,126.62 81.53,124.71 81.53,123.95 80.52,122.94 80.52,121.92 79.12,120.52 73.28,120.52 67.02,114.26 U65.A11 ; U1.A6 155.29,107.22 148.68,107.22 135.76,120.14 114.81,120.14 106.05,128.9 U4.42 v1(100.21,128.9)
  BOTTOM w0.127: U98.4 83.02,130.08 v1(83.19,129.92) 83.31,129.79 84.71,129.79 89.28,134.37 93.22,134.37 98.68,128.9 v1(100.21,128.9)
IFC_AD5: length 116.6
  TOP w0.127: U65.B11 67.52,113.43 67.52,114.25 73.41,120.14 79.25,120.14 80.9,121.79 80.9,122.81 81.92,123.83 81.92,124.59 83.82,126.49 v1(83.82,130.3) ; U1.A7 155.3,108.06 148.35,108.06 134.92,121.5 v1(130.98,121.5) 126.7,121.5 125.73,120.52 114.94,120.52 105.56,129.9 U4.40 v1(100.21,129.9)
  BOTTOM w0.127: v1(100.21,129.9) 98.32,129.9 93.47,134.75 89.03,134.75 84.59,130.3 v1(83.82,130.3) 83.64,130.48 U98.3 ; U2.47 v1(130.98,121.5)
IFC_AD6: length 117.6
  TOP w0.127: U1.B8 155.73,108.46 148.46,108.46 134.93,122 v1(131.73,122) 126.57,122 126.11,121.54 123.44,121.54 122.81,120.9 115.06,120.9 105.07,130.9 U4.38 v1(101.17,130.9) ; U65.B10 66.52,113.43 66.52,114.27 73.15,120.9 78.99,120.9 80.14,122.05 80.14,123.06 81.15,124.08 81.15,124.84 82.42,126.11 82.42,130.05 v1(83.31,130.94)
  BOTTOM w0.127: v1(101.17,130.9) 97.95,130.9 93.73,135.13 88.91,135.13 84.72,130.94 v1(83.31,130.94) 83.26,130.88 U98.2 ; U2.46 v1(131.73,122)
IFC_AD7: length 118
  TOP w0.127: v1(101.17,131.9) U4.36 104.57,131.9 115.19,121.29 122.68,121.29 123.32,121.92 125.86,121.92 126.93,123 v1(131.73,123) 134.45,123 148.6,108.85 U1.A8 ; U65.A10 66.02,114.28 73.03,121.29 78.87,121.29 79.76,122.17 79.76,123.32 80.39,123.95 80.39,129.92 82.04,131.57 v1(83.82,131.57)
  BOTTOM w0.127: U98.1 82.9,131.28 83.19,131.57 v1(83.82,131.57) 84.71,131.57 88.65,135.51 93.98,135.51 97.59,131.9 v1(101.17,131.9) ; U2.44 v1(131.73,123)
IFC_AD8: length 129
  TOP w0.127: v1(130.98,123.5) 134.44,123.5 148.72,109.22 155.69,109.22 U1.B9 ; U4.50 v1(103.84,124.9) ; U65.A6 62.02,114.85 72.77,125.6 v1(72.77,136.52) SW1.1
  L3SIG w0.102: v1(130.98,123.5) 118.44,123.5 118.11,123.83 115.29,123.83 114.86,123.39 114.18,123.39 112.67,124.9 v1(103.84,124.9) 97.47,124.9 96.9,124.33 94.74,124.33 93.34,125.73 87.61,125.73 87.23,125.35 84.96,125.35 83.69,126.62 80.01,126.62 72.77,133.86 v1(72.77,136.52)
  BOTTOM w0.127: U2.43 v1(130.98,123.5)
IFC_AD9: length 128
  TOP w0.127: SW1.2 v1(74.04,136.52) 74.04,134.62 73.15,133.73 73.15,125.48 62.51,114.84 62.51,113.43 U65.B7 ; v1(131.73,124.5) 134.46,124.5 134.87,124.08 134.87,123.57 148.82,109.62 155.29,109.62 U1.A9 ; U4.48 v1(103.84,125.9)
  L3SIG w0.102: v1(131.73,124.5) 118.45,124.5 118.11,124.84 115.44,124.84 114.94,124.33 114.43,124.33 112.86,125.9 v1(103.84,125.9) 97.11,125.9 96.65,126.37 94.49,126.37 94.17,126.05 87.44,126.05 87.12,125.73 85.24,125.73 83.96,127.01 80.12,127.01 74.04,133.1 v1(74.04,136.52)
  BOTTOM w0.127: U2.41 v1(131.73,124.5)
IFC_AD10: length 126.2
  TOP w0.127: U4.46 v1(103.84,126.9) ; v1(130.98,125) 134.59,125 135.25,124.33 135.25,123.7 148.49,110.46 155.3,110.46 U1.A10 ; SW1.3 v1(75.31,136.52) 75.31,135.38 73.53,133.6 73.53,125.35 63.02,114.83 U65.A7
  L3SIG w0.102: v1(130.98,125) 119.1,125 118.24,125.86 115.44,125.86 114.94,125.35 114.3,125.35 112.75,126.9 v1(103.84,126.9) 96.55,126.9 96.39,126.75 93.22,126.75 92.91,127.05 88.21,127.05 86.61,128.65 79.25,128.65 75.31,132.59 v1(75.31,136.52)
  BOTTOM w0.127: U2.40 v1(130.98,125)
IFC_AD11: length 125.4
  TOP w0.127: U4.44 v1(103.84,127.9) ; U65.B8 63.52,113.43 63.52,114.74 73.91,125.14 73.91,133.48 76.58,136.14 v1(76.58,136.52) SW1.4 ; U1.B11 155.74,110.87 148.59,110.87 135.64,123.83 135.64,124.84 134.48,126 v1(131.73,126)
  L3SIG w0.102: v1(131.73,126) 118.86,126 118.49,126.37 114.43,126.37 113.41,127.38 112.78,127.38 112.26,127.9 v1(103.84,127.9) 102.91,128.83 100.91,128.83 100.55,128.47 95.22,128.47 94.66,129.03 83.31,129.03 80.52,131.83 79.12,131.83 76.58,134.37 v1(76.58,136.52)
  BOTTOM w0.127: U2.38 v1(131.73,126)
IFC_AD12: length 123.6
  TOP w0.127: U65.A8 64.02,114.56 74.3,124.84 74.3,133.35 76.84,135.89 77.22,135.89 v1(77.85,136.52) SW1.5 ; U1.A11 148.72,111.25 136.02,123.95 136.02,125.09 134.62,126.5 v1(130.98,126.5) ; U4.41 v1(103.84,129.4)
  L3SIG w0.102: v1(130.98,126.5) 118.99,126.5 117.68,127.81 112.85,127.81 111.26,129.4 v1(103.84,129.4) 102.12,129.4 101.68,129.84 100.91,129.84 100.48,129.41 96.52,129.41 96.34,129.59 95.38,129.59 95.2,129.41 87.25,129.41 84.43,132.23 79.6,132.23 78.36,133.48 78.36,134.87 77.85,135.38 v1(77.85,136.52)
  BOTTOM w0.127: U2.37 v1(130.98,126.5)
IFC_AD13: length 125.3
  TOP w0.127: U1.B12 155.7,111.63 148.84,111.63 136.4,124.08 136.4,125.35 134.75,127 v1(131.73,127) ; SW1.6 v1(79.12,136.52) 78.11,135.51 76.96,135.51 74.68,133.22 74.68,124.59 64.52,114.43 64.52,112.43 U65.C8 ; U4.39 v1(103.84,130.4)
  L3SIG w0.102: v1(131.73,127) 119.13,127 117.98,128.14 113.28,128.14 111.03,130.4 v1(103.84,130.4) 96.27,130.4 96.11,130.56 95.38,130.56 95,130.17 89.64,130.17 88.83,130.99 86.18,130.99 84.45,132.72 80.39,132.72 79.38,133.73 79.38,136.27 v1(79.12,136.52)
  BOTTOM w0.127: U2.36 v1(131.73,127)
IFC_AD14: length 123.1
  TOP w0.127: U65.A9 65.02,114.29 75.06,124.33 75.06,133.1 77.09,135.13 78.99,135.13 v1(80.39,136.52) SW1.7 ; v1(130.98,127.5) 135.39,127.5 140.33,122.56 140.33,120.65 149.03,111.96 155.23,111.96 U1.A12 ; U4.37 v1(103.84,131.4)
  L3SIG w0.102: v1(80.39,136.52) 80.39,133.73 81.03,133.1 84.58,133.1 86.21,131.47 93.07,131.47 93.9,130.63 94.69,130.63 95.46,131.4 v1(103.84,131.4) 110.66,131.4 113.59,128.47 118.29,128.47 119.26,127.5 v1(130.98,127.5)
  BOTTOM w0.127: U2.35 v1(130.98,127.5)
IFC_AD15: length 121.2
  TOP w0.127: U65.B9 65.52,113.43 65.52,114.28 75.44,124.21 75.44,132.97 77.22,134.75 79.88,134.75 v1(81.66,136.52) 81.66,137.54 ; U1.A13 155.3,112.86 148.63,112.86 141.35,120.14 141.35,122.05 134.9,128.5 v1(131.73,128.5) ; U4.35 v1(103.84,132.4)
  L3SIG w0.102: v1(131.73,128.5) 121.13,128.5 120.52,127.89 119.38,127.89 117.93,129.34 113.36,129.34 110.3,132.4 v1(103.84,132.4) 93.16,132.4 92.71,131.95 86.23,131.95 v1(81.66,136.52)
  BOTTOM w0.127: U2.33 v1(131.73,128.5)
IFC_AVD: length 113.3
  TOP w0.127: v1(129.67,132.59) 129.76,132.5 134.58,132.5 144.53,122.56 144.53,121.67 148.46,117.73 150.62,117.73 151.89,116.46 157.3,116.46 U1.D17 ; v1(86.36,127.38) 86.23,127.51 86.23,131.95 89.03,134.75 92.96,134.75 v1(94.74,136.52) 94.36,136.91 SW2.8
  L6SIG w0.102: v1(129.67,132.59) 129.67,132.97 121.54,141.1 111.12,141.1 109.54,139.51 97.73,139.51 v1(94.74,136.52)
  BOTTOM w0.127: U2.48 130.72,121 130.17,121.54 130.17,132.08 129.76,132.5 ; 129.76,132.5 v1(129.67,132.59) ; 129.76,132.5 U2.25 ; v1(94.74,136.52) 94.36,136.91 R801.1 ; R49.1 86.74,127.13 86.49,127.38 v1(86.36,127.38)
IFC_CLE: length 134.7
  TOP w0.127: U1.F16 v2(158.92,115.65) ; SW2.1 v1(85.47,136.52) 85.09,136.14 85.09,126.49 v1(85.22,126.37) 85.09,126.24 85.09,122.43 74.09,111.43 71.52,111.43 U65.D15
  L6SIG w0.102: v2(158.92,115.65) 158.5,115.23 156.25,115.23 155.7,114.68 147.32,114.68 141.86,120.14 141.86,121.92 140.08,123.7 135.09,123.7 134.2,124.59 133.73,124.59 132.84,125.48 131.32,125.48 130.3,126.49 130.3,128.27 127.51,131.06 127.51,133.6 121.16,139.95 112.27,139.95 110.62,138.3 102.62,138.3 101.22,136.91 101.22,136.27 101.04,136.09 100.51,136.09 98.93,137.67 96.65,137.67 95,136.02 94.49,136.02 94.23,136.27 94.23,137.16 92.84,138.56 87.5,138.56 v1(85.47,136.52)
  BOTTOM w0.127: U7.3 88.95,126.31 88.9,126.37 v1(85.22,126.37)
IFC_CLK: length 95.3
  TOP w0.127: v1(68.45,108.46) 68.45,106.37 68.02,105.93 U65.J12
  BOTTOM w0.127: R12.2 152.5,115.57 152.44,115.51 149.8,115.51 147.32,117.98 114,117.98 112.48,116.46 95.25,116.46 91.57,112.78 91.57,109.52 90.63,108.59 76.45,108.59 74.93,107.06 69.72,107.06 68.45,108.33 v1(68.45,108.46)
IFC_CS0_N: length 135
  TOP w0.127: U65.B6 62.02,112.93 v1(61.51,113.43) 61.51,115.13 72.01,125.63 72.01,138.56 74.42,140.97 106.81,140.97 110.62,137.16 v1(116.59,137.16) ; U1.C13 v2(156.52,112.45)
  L6SIG w0.102: v2(156.52,112.45) 156.29,112.45 155.83,112.9 146.43,112.9 139.06,120.27 129.16,120.27 124.84,124.59 124.84,132.72 120.4,137.16 v1(116.59,137.16)
  BOTTOM w0.127: R11.1 61.01,113.87 61.45,113.43 v1(61.51,113.43)
IFC_CS1_N: length 139.9
  TOP w0.127: U65.B5 61.02,112.93 v1(60.51,113.43) 60.51,115.12 71.25,125.86 71.25,138.81 74.17,141.73 107.06,141.73 110.11,138.68 v1(114.3,138.68) ; U1.E15 v2(158.12,114.85)
  L6SIG w0.102: v1(114.3,138.68) 114.81,139.19 120.9,139.19 126.75,133.35 126.75,124.84 128.52,123.06 131.18,123.06 131.69,123.57 133.35,123.57 133.76,123.16 139.86,123.16 141.35,121.67 141.35,119.89 147.06,114.17 157.44,114.17 v2(158.12,114.85)
  BOTTOM w0.127: v1(60.51,113.43) 60.51,114.83 R10.1
IFC_CS2_N: length 135.6
  TOP w0.127: U1.D16 v2(157.32,115.65) ; v1(111.12,139.57) 109.73,139.57 106.55,142.75 74.68,142.75 70.87,138.94 70.87,125.98 60.01,115.13 v1(60.01,114.53) 60.02,114.53 U65.A4
  L6SIG w0.102: v2(157.32,115.65) 156.91,116.05 156.31,116.05 155.19,114.94 147.45,114.94 142.11,120.27 142.11,122.05 140.21,123.95 135.25,123.95 134.24,124.97 133.86,124.97 133.48,125.35 133.48,126.49 132.33,127.64 131.57,127.64 127.89,131.32 127.89,133.73 121.29,140.33 111.89,140.33 v1(111.12,139.57)
  BOTTOM w0.127: R9.1 59.01,114.86 59.34,114.53 v1(60.01,114.53)
IFC_LATCH_N: length 56.2
  TOP w0.127: U65.B14 v1(70.52,113.43)
  BOTTOM w0.127: v1(70.52,113.43) 70.02,113.93 70.02,115.13 74.02,119.14 78.75,119.14 80.81,121.19 U99.8 77.37,123.29 75.95,124.71 75.95,128.27 76.33,128.65 77.98,128.65 78.22,128.9 R808.2 78.87,129.16 79.09,129.38 U98.8 80.81,128.91 80.93,128.78 84.33,128.78 89.54,133.98 92.84,133.98 93.06,133.77 U11.8 93.7,133.25 94.87,132.08 94.87,129.67 94.49,129.29 94.49,128.02 93.88,127.41 U7.8
IFC_NDWE_N: length 103.3
  TOP w0.127: U1.D14 v2(157.32,113.25)
  L6SIG w0.102: v1(88.39,130.56) 87.12,131.83 87.12,136.91 88.39,138.18 92.71,138.18 93.85,137.03 93.85,136.27 94.49,135.64 95.12,135.64 96.77,137.29 98.43,137.29 98.93,136.78 98.93,136.27 100.46,134.75 101.47,134.75 102.49,135.76 102.49,137.03 103,137.54 113.92,137.54 115.19,138.81 120.78,138.81 126.37,133.22 126.37,124.71 128.65,122.43 132.04,122.43 133.19,121.29 139.57,121.29 146.91,113.94 156.82,113.94 157.32,113.45 v2(157.32,113.25)
  BOTTOM w0.127: v1(88.39,130.56) 89.19,131.35 U11.1
IFC_OE_N: length 136.1
  TOP w0.127: U65.G15 71.52,108.43 74.14,108.43 87.38,121.67 87.38,124.59 v1(87.5,124.71) 87.63,124.84 87.63,126.37 88.01,126.75 88.01,130.17 87.76,130.43 87.76,131.44 89.54,133.22 94.36,133.22 97.03,135.89 97.03,137.92 97.54,138.43 99.19,138.43 99.44,138.18 SW3.2 v1(99.44,136.52) 99.44,134.37 100.91,132.9 U4.34 ; U1.D15 v2(157.32,114.85)
  L6SIG w0.102: v2(157.32,114.85) 157.32,114.77 156.97,114.43 147.19,114.43 141.6,120.02 141.6,121.79 139.95,123.44 133.98,123.44 133.48,123.95 131.32,123.95 130.3,124.97 130.3,125.86 127.13,129.03 127.13,133.48 121.03,139.57 112.39,139.57 110.74,137.92 102.74,137.92 101.47,136.65 101.47,136.02 101.22,135.76 100.2,135.76 v1(99.44,136.52)
  BOTTOM w0.127: v1(87.5,124.71) 88.39,124.71 89.19,125.51 U7.1 ; R803.1 v1(99.44,136.52)
IFC_PAR1: length 100.3
  TOP w0.127: U1.C14 v2(156.52,113.25)
  L6SIG w0.102: v1(88.9,129.92) 88.9,130.81 87.5,132.21 87.5,136.78 88.52,137.79 92.58,137.79 93.52,136.86 93.52,136.09 94.36,135.25 95.25,135.25 96.95,136.96 98.35,136.96 98.7,136.6 98.7,135.99 100.33,134.37 101.6,134.37 102.74,135.51 102.74,136.78 103.12,137.16 115.06,137.16 115.95,138.05 120.52,138.05 125.6,132.97 125.6,124.59 129.41,120.78 139.32,120.78 146.69,113.41 156.35,113.41 v2(156.52,113.25)
  BOTTOM w0.127: v1(88.9,129.92) 88.9,129.67 88.91,129.66 R812.1 R50.1
IFC_RB0_N: length 117.2
  TOP w0.127: U1.B15 155.75,114.81 150.11,114.81 134.56,130.36 130.37,130.36 124.08,136.65 110.62,136.65 106.68,140.59 86.36,140.59 84.33,138.56 84.33,122.68 79.88,118.24 75.33,118.24 v1(71.52,114.43) U65.A15
  BOTTOM w0.127: R7.1 71.32,114.63 v1(71.52,114.43)
IFC_RB1_N: length 115.5
  TOP w0.127: U65.B16 v1(72.52,113.43) 76.95,117.86 80.01,117.86 84.71,122.56 84.71,138.43 86.49,140.21 106.55,140.21 110.49,136.27 123.83,136.27 130.14,129.96 134.46,129.96 149.97,114.45 U1.A15
  BOTTOM w0.127: R6.1 72.72,113.23 v1(72.52,113.43)
IFC_TE: length 83.1
  TOP w0.127: U1.B14 155.75,113.28 148.72,113.28 141.73,120.27 141.73,122.17 134.87,129.03 130.43,129.03 123.57,135.89 110.36,135.89 107.19,139.06 102.49,139.06 101.73,139.83 93.09,139.83 92.2,138.94 87.25,138.94 86.74,138.43 86.74,137.54
IFC_VA5: length 4.7
  TOP w0.127: U4.55 104.8,122.4 105.98,121.22 U10.4
IFC_VA6: length 1.4
  TOP w0.127: U4.56 102.44,120.55 U9.4
IFC_VA7: length 14.7
  TOP w0.127: U8.4 109.54,121.6 v1(109.09,122.05) ; v1(115.7,122.3) 116.1,121.9 U4.1
  BOTTOM w0.127: v1(109.09,122.05) 109.35,122.3 v1(115.7,122.3)
IFC_WE_N: length 140.3
  TOP w0.127: SW3.1 v1(98.17,136.52) 93.6,131.95 90.3,131.95 89.54,131.19 89.54,122.81 74.15,107.43 71.52,107.43 U65.H15 ; U4.13 115.18,127.9 v1(114.17,128.91) ; U1.D13 v2(157.32,112.45)
  L6SIG w0.102: v2(157.32,112.45) 157.17,112.45 156.79,112.83 156.29,112.83 155.96,113.16 146.54,113.16 139.17,120.55 129.26,120.55 125.22,124.59 125.22,132.84 120.4,137.67 116.08,137.67 114.17,135.76 v1(114.17,128.91) 108.84,128.91 104.27,133.47 103.13,133.47 102.57,134.04 100.15,134.04 98.17,136.02 v1(98.17,136.52)
  BOTTOM w0.127: R804.1 v1(98.17,136.52)
IFC_WP_N: length 130.2
  TOP w0.127: U65.F16 74.13,108.93 87,121.79 87,124.97 87.25,125.22 87.25,126.51 87.63,126.89 87.63,129.79 v1(87.5,129.92) 87.38,130.05 87.38,131.57 89.41,133.6 94.23,133.6 96.65,136.02 96.65,138.05 97.41,138.81 100.33,138.81 100.71,138.43 SW3.3 v1(100.71,136.52) ; U1.F17 v2(158.92,116.45)
  L6SIG w0.102: v2(158.92,116.45) 158.52,116.45 158.33,116.26 156.13,116.26 155.07,115.19 147.57,115.19 142.37,120.4 142.37,122.2 140.36,124.21 136.27,124.21 132.46,128.02 131.57,128.02 128.27,131.32 128.27,133.86 121.41,140.72 111.28,140.72 109.24,138.68 102.49,138.68 100.71,136.91 v1(100.71,136.52)
  BOTTOM w0.127: R802.1 v1(100.71,136.52) ; v1(87.5,129.92) 87.5,130.3 88.95,131.75 U11.2
IOPWR_EN: length 265.3
  TOP w0.127: R670.1 15.62,71.37 v1(15.11,71.88) ; C938.2 R732.2 200.15,76.45 v1(199.64,76.96) 199.26,76.96 198.88,77.34 U86.16 ; v1(64.52,99.42) 64.02,99.92 U65.R8 ; C956.2 R750.2 20.95,115.44 v1(21.46,114.94) 21.97,114.94 22.23,114.68 U88.16
  L3SIG w0.102: v1(21.46,114.94) 22.1,114.3 38.86,114.3 47.75,105.41 v1(47.75,104.9) 48.26,104.9 53.17,99.99 63.95,99.99 v1(64.52,99.42)
  L6SIG w0.102: v1(64.52,99.42) 64.52,98.43 71.25,91.69 71.25,88.01 74.68,84.58 74.68,83.44 77.47,80.65 81.41,80.65 83.95,78.11 102.74,78.11 103,77.85 110.24,77.85 111,77.09 152.4,77.09 153.67,78.36 186.82,78.36 189.61,75.57 197.74,75.57 199.14,76.96 v1(199.64,76.96) ; v1(47.75,104.9) 47.75,96.27 45.34,93.85 41.91,93.85 38.23,90.17 38.23,83.82 32.77,78.36 29.72,78.36 26.92,75.57 26.92,73.15 25.78,72.01 18.92,72.01 18.29,71.37 16.13,71.37 15.62,71.88 v1(15.11,71.88)
IOPWR_EN_N: length 65
  TOP w0.127: R681.1 79.89,83.19 v1(80.26,83.57) ; R666.1 42.43,104.15 v1(42.67,104.39) ; U65.P10 66.02,100.92 v1(66.52,100.42) ; R682.1 v1(43.56,95.5)
  L3SIG w0.102: v1(66.52,100.42) 66.02,99.92 66.02,99.16 65.77,98.92 53.86,98.92 48.39,104.39 v1(42.67,104.39)
  L6SIG w0.102: v1(66.52,100.42) 67.02,99.92 67.02,97.96 72.52,92.46 72.52,88.77 77.72,83.57 v1(80.26,83.57) ; v1(43.56,95.5) 44.2,96.14 44.2,103.51 43.31,104.39 v1(42.67,104.39)
JTAG_TCK: length 104
  TOP w0.127: U20.10 70.16,142.93 v1(70.87,143.64) ; U1.E18 v2(158.12,117.25)
  L6SIG w0.102: v2(158.12,117.25) 157.7,117.66 152.29,117.66 151.97,117.98 150.62,117.98 150.24,118.36 147.7,118.36 144.53,121.54 144.53,123.19 137.29,130.43 133.35,130.43 132.08,131.7 132.08,133.6 122.5,143.19 98.99,143.19 97.16,141.35 73.66,141.35 71.37,143.64 v1(70.87,143.64)
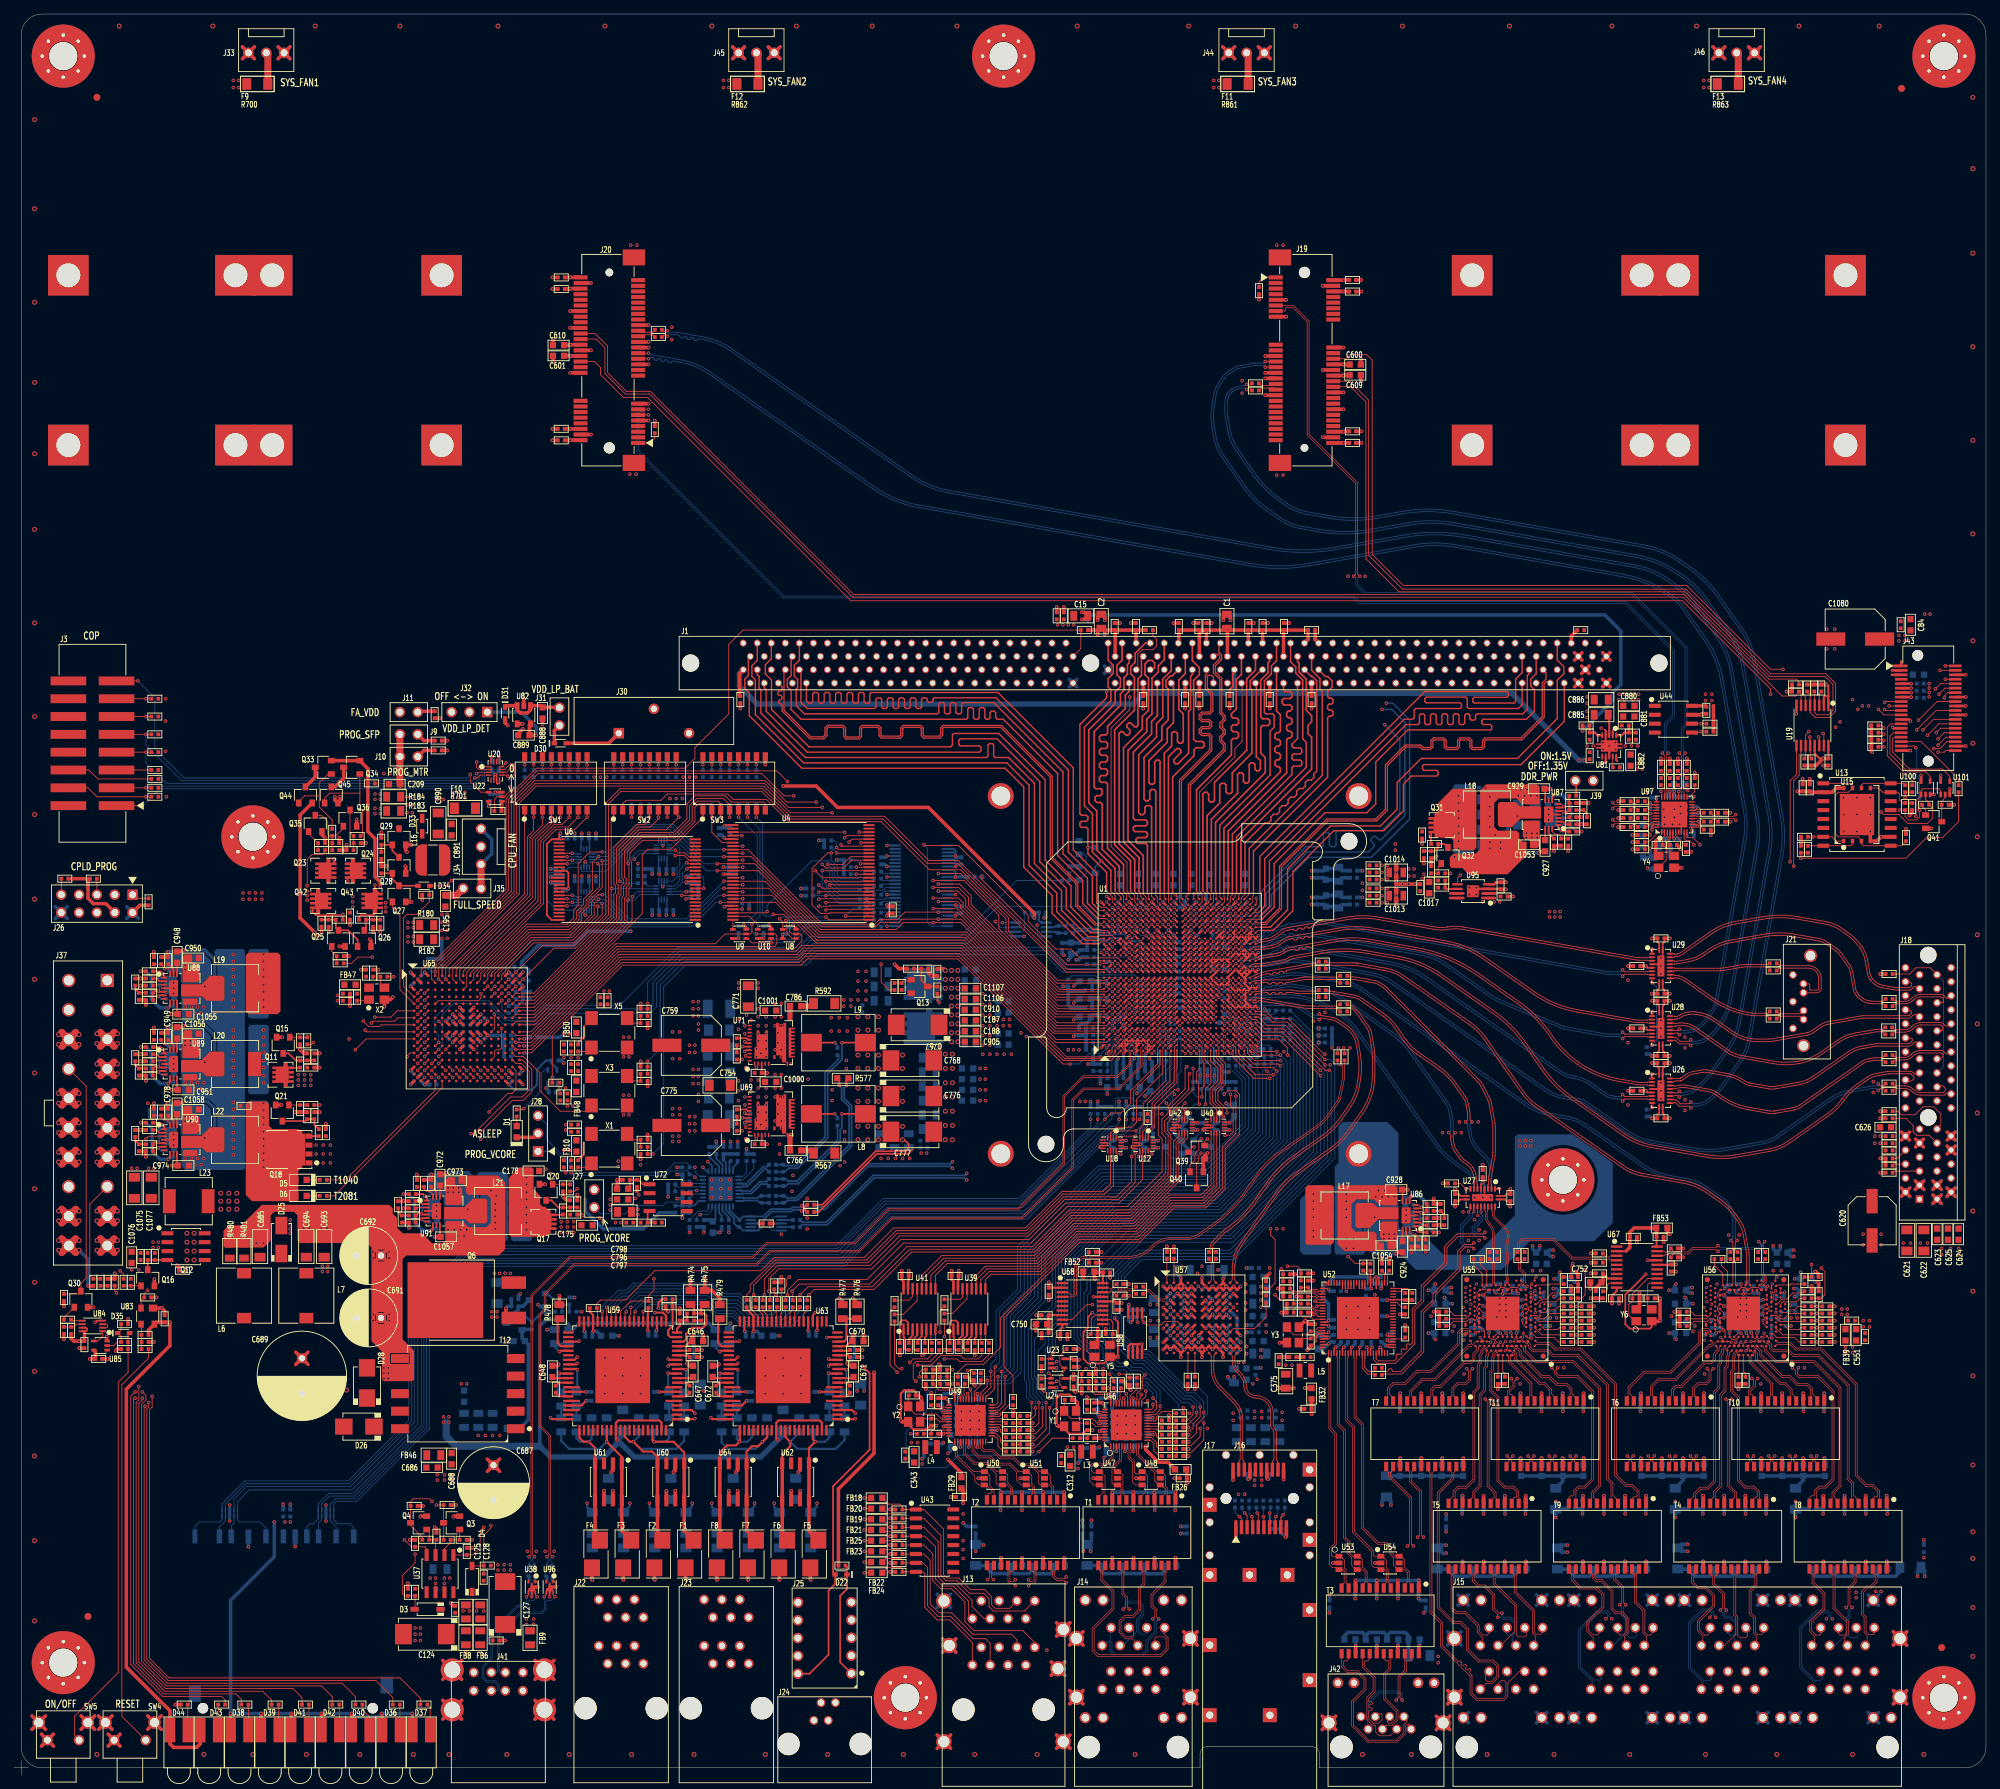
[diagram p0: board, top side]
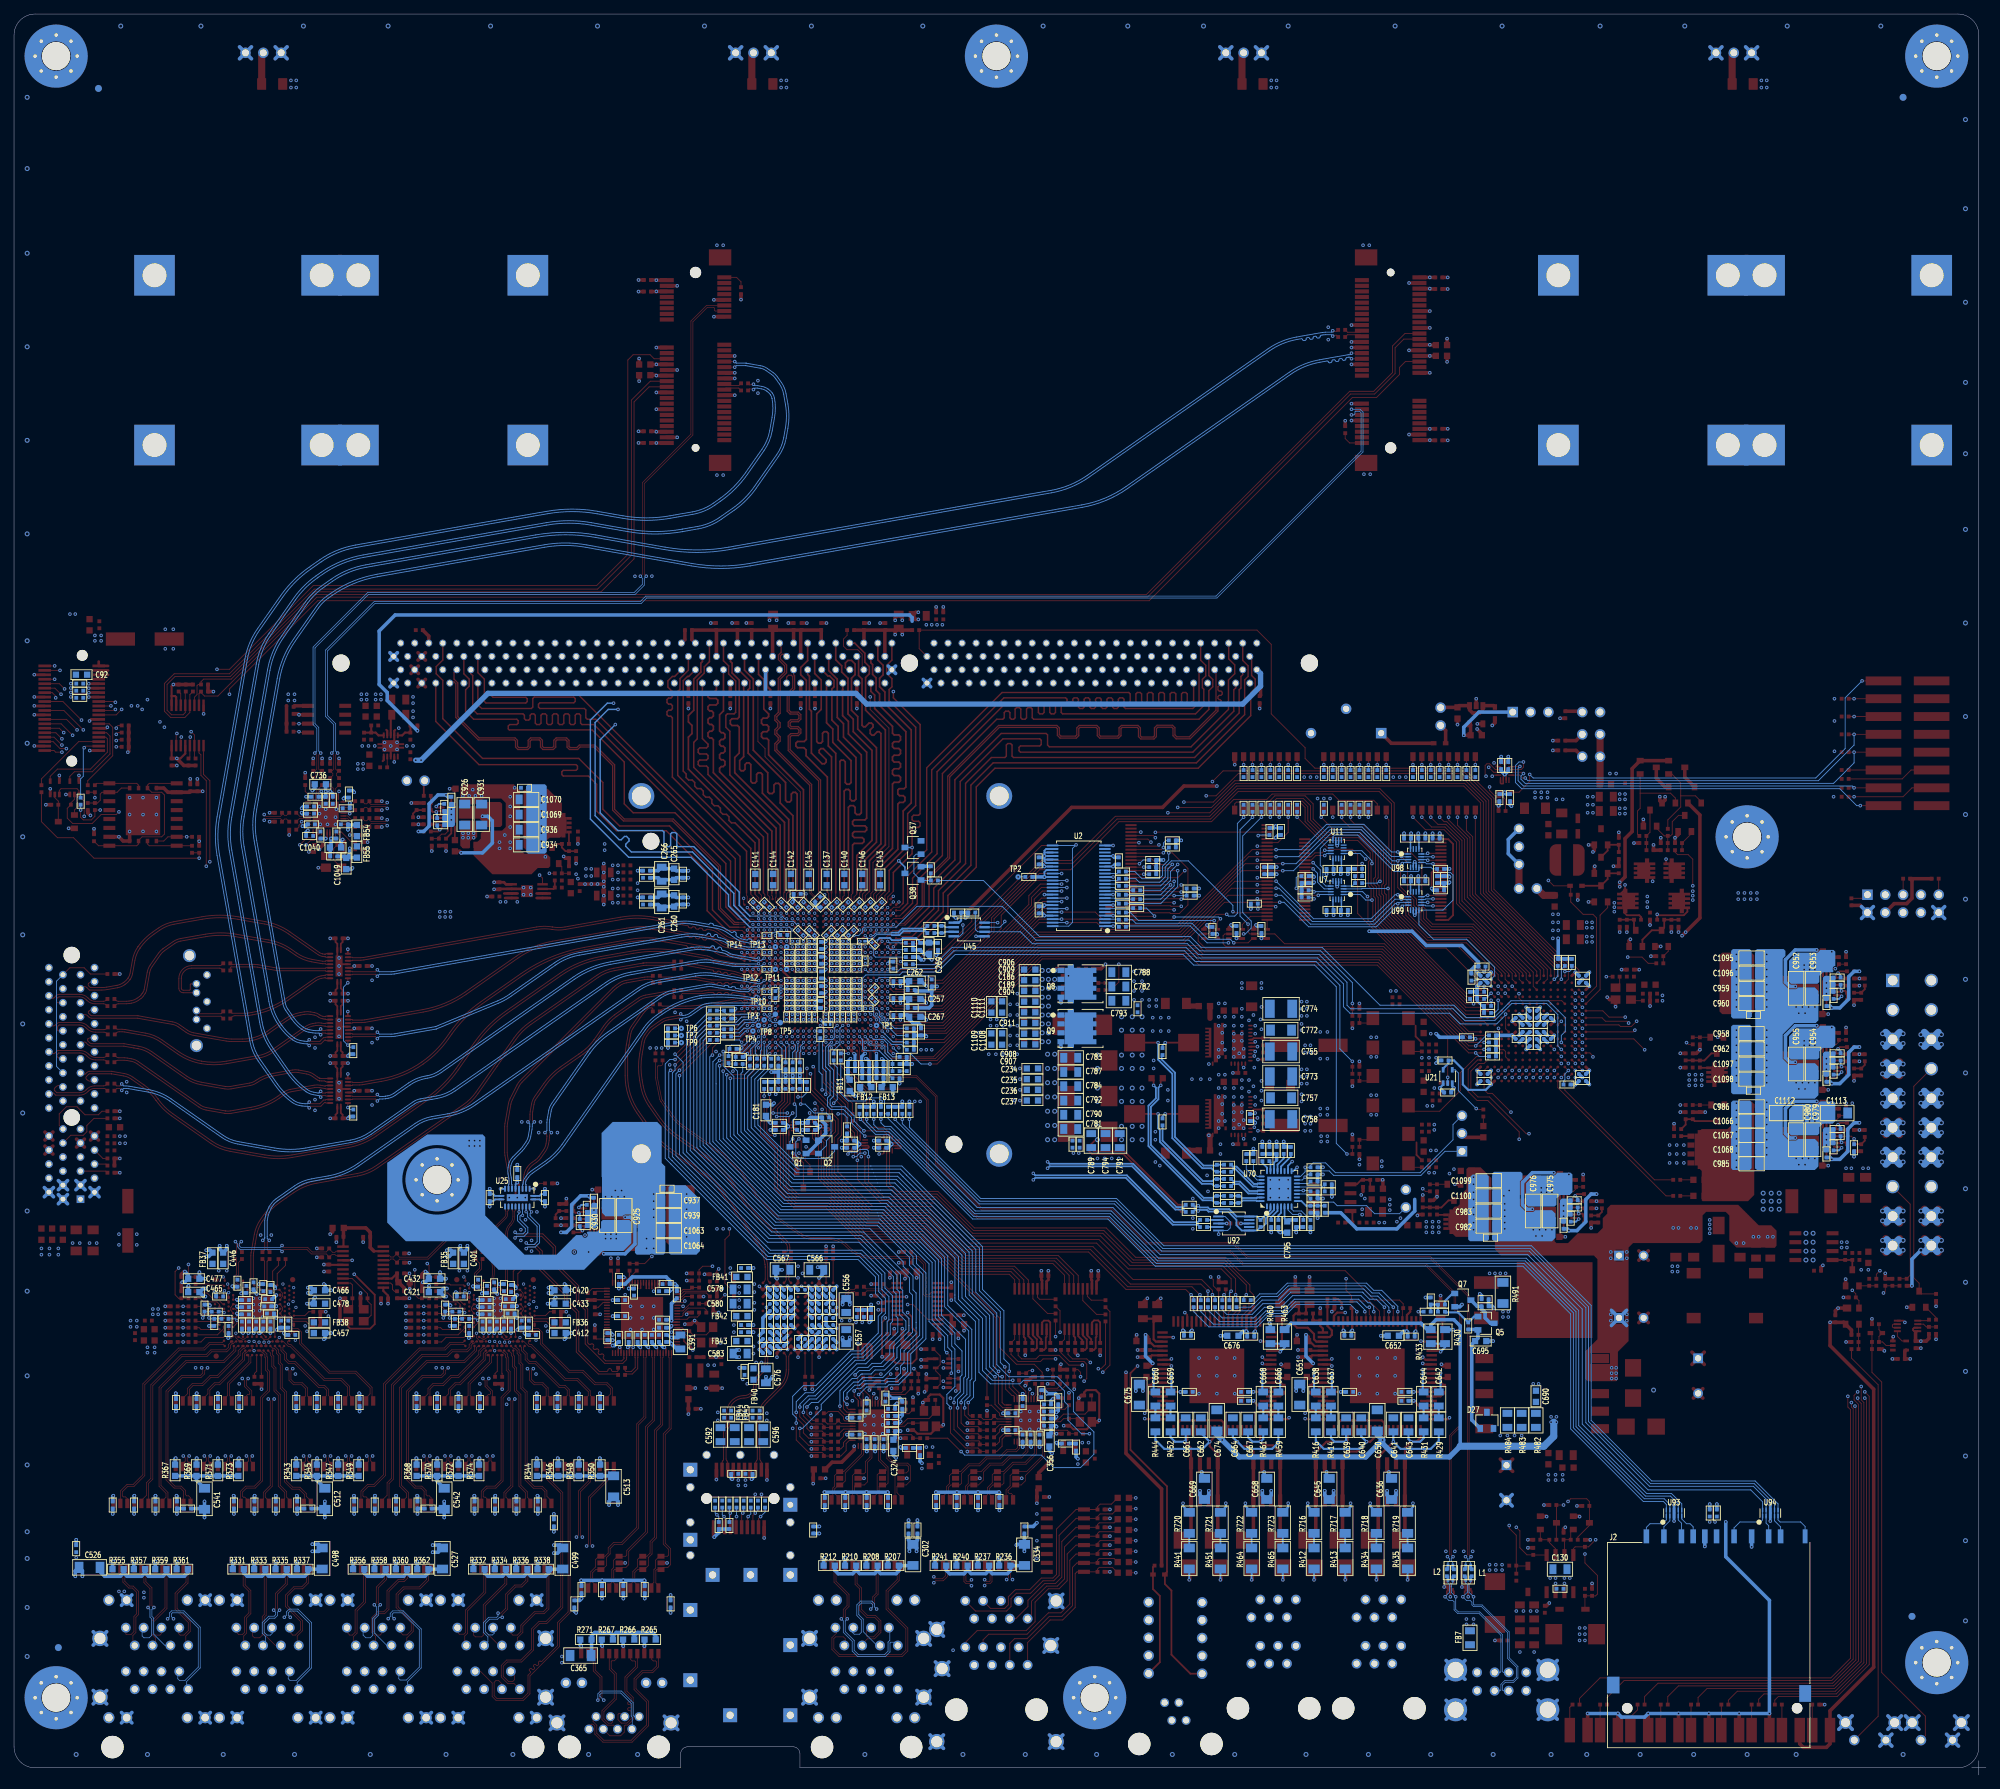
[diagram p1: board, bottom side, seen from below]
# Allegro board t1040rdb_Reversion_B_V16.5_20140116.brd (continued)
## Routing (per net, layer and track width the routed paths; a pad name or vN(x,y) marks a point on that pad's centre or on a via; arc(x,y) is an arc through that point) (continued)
JTAG_TDI: length 101.3
  TOP w0.127: U1.A18 v2(154.92,117.25) ; U20.12 69.56,143.73 v1(70.1,144.27)
  L6SIG w0.102: v2(154.92,117.25) 152.25,117.25 151.83,117.67 150.56,117.67 150.11,118.11 147.57,118.11 144.27,121.41 144.27,123.06 137.29,130.05 133.22,130.05 131.7,131.57 131.7,133.48 122.36,142.81 99.25,142.81 97.54,141.1 73.53,141.1 71.42,143.21 70.54,143.21 70.1,143.64 v1(70.1,144.27)
JTAG_TDO: length 104.2
  TOP w0.127: v1(71.25,142.37) 71.37,142.49 71.37,143.89 71.12,144.14 70.75,144.14 69.93,143.33 U20.11 ; U1.C18 v2(156.52,117.25)
  L6SIG w0.102: v1(71.25,142.37) 73.03,140.59 97.79,140.59 99.26,142.06 122.1,142.06 130.94,133.22 130.94,130.94 133.35,128.52 134.37,128.52 137.92,124.97 141.6,124.97 143.76,122.81 143.76,121.16 147.32,117.6 149.86,117.6 150.46,117 151.73,117 152.15,116.59 155.6,116.59 156.26,117.25 v2(156.52,117.25)
JTAG_TMS: length 101.6
  TOP w0.127: v1(70.36,142.37) 70.36,142.4 70.23,142.53 U20.9 ; U1.B18 v2(155.72,117.25)
  L6SIG w0.102: v1(70.36,142.37) 70.48,142.37 70.99,142.87 71.37,142.87 73.41,140.84 97.66,140.84 99.26,142.44 122.23,142.44 131.32,133.35 131.32,131.19 133.6,128.91 134.49,128.91 138.18,125.22 141.73,125.22 144.02,122.94 144.02,121.29 147.45,117.86 149.99,117.86 150.5,117.35 151.77,117.35 152.28,116.84 155.31,116.84 v2(155.72,117.25)
JTAG_TRST_N: length 133.9
  TOP w0.127: v2(157.31,117.25) 157.32,117.25 U1.D19 ; v1(110.24,141.6) 108.71,143.13 74.51,143.13 70.48,139.11 70.48,126.11 59.51,115.14 59.51,113.43 60.02,112.93 U65.B4
  L6SIG w0.102: v2(157.31,117.25) 156.77,116.71 156.01,116.71 155.63,116.33 152.02,116.33 151.67,116.68 150.4,116.68 149.73,117.35 147.19,117.35 143.51,121.03 143.51,122.68 141.48,124.71 136.65,124.71 130.56,130.81 130.56,133.1 121.92,141.73 110.36,141.73 v1(110.24,141.6)
LED_STATUS: length 131.4
  TOP w0.127: v1(57.51,110.43) 58.01,110.93 U65.D2 ; v1(17.27,54.61) 16.64,53.98 16.64,15.75 21.21,11.18 29.59,11.18 30.09,10.68 R702.1
  L6SIG w0.102: v1(17.27,54.61) 17.27,55.63 36.07,74.42 36.07,80.52 38.99,83.44 38.99,89.79 41.4,92.2 44.83,92.2 51.18,98.55 51.18,105.6 56.01,110.43 v1(57.51,110.43)
LED_T1040_DET: length 22.1
  TOP w0.127: U65.T4 60.02,97.61 47.24,84.84 R186.1
LED_T2081_DET: length 23.8
  TOP w0.127: U65.T5 61.02,97.97 45.59,82.55 R187.1
LIFELINE: length 61.8
  TOP w0.254: v1(120.9,58.29) 121.92,57.28 121.92,46.35 116.71,41.15 116.71,28.96 117.01,28.66 D22.2 117.01,27.22 116.08,26.29 116.08,17.15 113.37,14.44 J25.10 ; v1(114.17,65.91) 113.83,65.57 U63.24
  L3SIG w0.254: v1(114.17,65.91) 116.59,63.5 116.59,62.23 120.52,58.29 v1(120.9,58.29)
LP_TMPDET_N: length 128.2
  TOP w0.127: v2(166.12,106.84) 166.12,106.85 U1.R6
  L6SIG w0.102: 64.9,151.51 64.9,149.61 68.58,145.92 69.98,145.92 72.34,143.56 122.63,143.56 135.38,130.81 137.29,130.81 144.78,123.32 144.78,121.92 145.11,121.59 145.98,121.59 148.95,118.62 150.37,118.62 150.52,118.46 160.64,118.46 160.9,118.2 160.9,117.87 161.1,117.66 161.48,117.66 161.74,117.41 161.74,107.49 161.98,107.24 165.72,107.24 v2(166.12,106.84)
MPEX1_REFCLK_N: length 116.7
  TOP w0.102: v1(190.92,170.88) 191.2,171.16 191.2,184.09 184.28,191.01 184.28,207.14 182.22,209.2 181.31,209.2 181.2,209.1 181.2,208.79 181.09,208.68 J19.13 ; R526.2 237.49,142.49 237.49,142.76 R528.2 237.35,143.14 237.59,143.38 237.59,145.39 v1(237.31,145.67)
  BOTTOM w0.102: v1(190.92,170.88) 191.2,170.6 191.2,169.59 192.52,168.27 230.5,168.27 238.12,160.66 238.12,149.86 237.59,149.33 237.59,145.95 v1(237.31,145.67)
MPEX1_REFCLK_P: length 116.8
  TOP w0.102: v1(191.76,170.88) 191.48,171.16 191.48,184.2 184.56,191.12 184.56,207.25 182.33,209.48 J19.11 ; v1(238.15,145.67) 237.87,145.39 237.87,143.38 238.12,143.14 R524.2 238,142.76 238,142.49 R525.2
  BOTTOM w0.102: v1(191.76,170.88) 191.48,170.6 191.48,169.71 192.63,168.55 230.62,168.55 238.4,160.77 238.4,149.74 237.87,149.21 237.87,145.95 v1(238.15,145.67)
MPEX1_RST_N: length 441.8
  TOP w0.127: U65.T2 v1(58.51,99.42) ; J19.22 189.79,201.88 190.37,202.45 192.79,202.45 193.55,201.69 193.55,173.99 197.99,169.54 238.38,169.54 250.32,157.61 v1(252.09,157.61)
  L6SIG w0.102: v1(252.09,157.61) 253.11,156.59 273.69,156.59 277.37,152.91 277.37,145.67 278.93,144.1 278.93,82.21 274.7,77.98 228.85,77.98 226.95,76.07 215.39,76.07 210.94,71.63 193.04,71.63 192.28,70.87 188.47,70.87 185.8,73.53 182.75,73.53 181.99,74.3 159.64,74.3 159.13,73.79 93.85,73.79 93.09,74.55 76.58,74.55 75.31,75.82 71.88,75.82 69.6,78.11 69.6,82.68 67.69,84.58 67.69,85.85 59.01,94.53 59.01,98.92 v1(58.51,99.42)
MPEX1_RX_N: length 173.8
  TOP w0.127: J19.23 v1(178.31,201.48) ; v1(237.32,97.44) 237.09,97.21 236.63,97.21 236.55,97.29 U26.15
  BOTTOM w0.127: v1(178.31,201.48) 178.09,201.25 176.72,201.25 176.69,201.25 176.63,201.24 176.63,201.24 174.62,200.88 arc(174.11,200.73) 173.64,200.48 172.85,199.93 arc(172.51,199.64) 172.23,199.3 171.66,198.49 arc(171.24,197.72) 170.99,196.88 170.73,195.42 arc(170.58,193.7) 170.73,191.97 170.98,190.57 arc(171.38,189.22) 172.05,187.98 175.23,183.44 arc(176.68,181.72) 178.4,180.28 180.25,178.98 arc(181.81,178.13) 183.52,177.63 185.74,177.24 185.74,177.23 arc(189.64,176.89) 193.53,177.23 198.78,178.16 arc(201.95,178.44) 205.12,178.16 231.2,173.56 arc(234.27,172.66) 237.08,171.12 237.77,170.64 arc(239.48,169.21) 240.91,167.5 244.38,162.54 arc(245.5,160.51) 246.15,158.29 249.98,136.52 arc(250.19,134.17) 249.98,131.82 245.66,107.31 arc(245.11,105.4) 244.15,103.66 241.78,100.27 arc(240.6,98.87) 239.2,97.69 239.2,97.69 arc(238.78,97.46) 238.32,97.33 237.68,97.21 237.55,97.21 v1(237.32,97.44)
MPEX1_RX_P: length 173.8
  TOP w0.127: J19.25 v1(178.31,200.68) ; v1(237.32,96.63) 237.09,96.86 236.63,96.86 236.55,96.79 U26.14
  BOTTOM w0.127: v1(237.32,96.63) 237.55,96.86 237.71,96.86 238.38,96.98 arc(238.92,97.13) 239.41,97.4 arc(240.86,98.62) 242.07,100.07 244.44,103.45 arc(245.43,105.26) 246.01,107.25 250.34,131.76 arc(250.55,134.17) 250.34,136.58 246.5,158.35 arc(245.83,160.65) 244.68,162.75 241.2,167.71 arc(239.73,169.46) 237.98,170.93 237.29,171.41 arc(234.41,172.99) 231.26,173.91 205.18,178.51 arc(201.95,178.79) 198.71,178.51 193.47,177.59 arc(189.64,177.25) 185.81,177.58 185.8,177.59 183.58,177.98 arc(181.94,178.45) 180.45,179.27 178.6,180.57 arc(176.93,181.97) 175.53,183.64 172.35,188.19 arc(171.7,189.35) 171.33,190.63 171.08,192.04 arc(170.94,193.7) 171.08,195.36 171.34,196.82 arc(171.57,197.59) 171.95,198.29 172.52,199.1 arc(172.76,199.39) 173.05,199.63 173.84,200.19 arc(174.24,200.41) 174.68,200.53 176.74,200.9 176.75,200.9 178.09,200.9 v1(178.31,200.68)
MPEX1_TX_N: length 169.7
  TOP w0.127: U26.13 236.55,96.29 236.63,96.21 236.91,96.21 237.44,95.68 238.72,95.68 v1(238.95,95.91) ; C599.2 176.21,198.17 175.72,198.17 v1(175.64,198.25)
  BOTTOM w0.127: v1(175.64,198.25) 175.44,198.04 175.06,198.04 174.46,197.94 arc(174,197.8) 173.58,197.57 173.47,197.49 arc(173.18,197.26) 172.94,196.97 172.92,196.94 arc(172.75,196.62) 172.64,196.26 172.64,196.26 arc(172.52,194.86) 172.64,193.46 172.97,191.6 arc(173.4,190.12) 174.14,188.77 176.49,185.42 arc(178.25,183.33) 180.34,181.57 181.17,180.99 arc(182.65,180.18) 184.28,179.7 187.47,179.14 arc(190.88,178.84) 194.3,179.14 197.9,179.78 arc(201.47,180.09) 205.04,179.78 232.31,174.97 arc(234.9,174.21) 237.25,172.92 238.74,171.88 arc(240.92,170.05) 242.75,167.87 246.04,163.17 arc(247.14,161.18) 247.77,159 251.73,136.53 arc(251.97,133.84) 251.73,131.14 247.08,104.75 arc(246.66,103.3) 245.93,101.98 243.49,98.49 arc(242.42,97.21) 241.14,96.14 arc(240.72,95.91) 240.26,95.78 239.91,95.72 arc(239.72,95.69) 239.53,95.68 239.18,95.68 v1(238.95,95.91)
MPEX1_TX_P: length 169.7
  TOP w0.127: C598.2 176.2,197.57 175.73,197.57 v1(175.64,197.48) ; U26.12 236.55,95.79 236.63,95.86 236.76,95.86 237.29,95.33 238.72,95.33 v1(238.95,95.1)
  BOTTOM w0.127: v1(238.95,95.1) 239.18,95.33 239.53,95.33 arc(239.76,95.34) 239.98,95.36 240.32,95.43 arc(240.86,95.58) 241.34,95.85 arc(242.67,96.96) 243.78,98.29 246.22,101.78 arc(246.99,103.16) 247.43,104.68 252.08,131.08 arc(252.32,133.84) 252.08,136.59 248.12,159.06 arc(247.46,161.31) 246.33,163.37 243.04,168.07 arc(241.18,170.3) 238.95,172.17 237.46,173.21 arc(235.03,174.54) 232.38,175.32 205.1,180.13 arc(201.47,180.44) 197.84,180.13 194.23,179.49 arc(190.88,179.2) 187.53,179.49 184.34,180.05 arc(182.79,180.5) 181.37,181.28 180.55,181.86 arc(178.5,183.58) 176.78,185.63 174.43,188.97 arc(173.73,190.26) 173.32,191.66 172.99,193.52 arc(172.88,194.86) 172.99,196.2 172.99,196.2 arc(173.08,196.48) 173.22,196.74 173.24,196.77 arc(173.44,197) 173.67,197.2 173.79,197.28 arc(174.14,197.48) 174.52,197.59 175.09,197.69 175.44,197.69 v1(175.64,197.48)
MPEX2_REFCLK_N: length 187.8
  TOP w0.102: R532.2 235.08,142.49 235.08,142.76 R534.1 234.93,143.14 235.18,143.38 235.18,145.39 v1(234.9,145.67) ; J20.13 v1(90.42,194.68)
  BOTTOM w0.102: v1(234.9,145.67) 235.18,145.95 235.18,149.85 236.35,151.02 236.35,160.22 229.57,167 191.63,167 190.87,167.77 109.6,167.77 88.77,188.59 88.77,194.27 89.18,194.68 v1(90.42,194.68)
MPEX2_REFCLK_P: length 187.7
  TOP w0.102: R530.2 235.58,142.49 235.58,142.76 R527.1 235.7,143.14 235.46,143.38 235.46,145.39 v1(235.74,145.67) ; J20.11 v1(90.42,193.88)
  BOTTOM w0.102: v1(90.42,193.88) 90.07,193.88 89.93,194.02 89.93,194.3 89.83,194.4 89.29,194.4 89.05,194.16 89.05,188.71 109.72,168.05 190.98,168.05 191.74,167.28 229.68,167.28 236.63,160.34 236.63,150.9 235.46,149.73 235.46,145.95 v1(235.74,145.67)
MPEX2_RST_N: length 533.6
  TOP w0.127: U65.R3 59.02,99.92 v1(59.51,99.42) ; v1(250.32,154.05) 250.32,154.81 237.74,167.39 119.25,167.39 90.3,196.34 86.87,196.34 83.57,199.64 83.57,200.64 82.73,201.48 J20.22
  L6SIG w0.102: v1(59.51,99.42) 59.51,94.41 67.95,85.98 67.95,84.71 69.85,82.8 69.85,78.23 72.01,76.07 75.44,76.07 76.71,74.8 93.22,74.8 93.98,74.04 159,74.04 159.51,74.55 182.12,74.55 182.88,73.79 185.93,73.79 188.6,71.12 192.17,71.12 192.93,71.88 210.84,71.88 215.28,76.33 226.82,76.33 228.73,78.23 274.59,78.23 278.7,82.34 278.7,143.95 277.11,145.54 277.11,152.78 273.56,156.34 252.6,156.34 v1(250.32,154.05)
MPEX2_RX_N: length 225.8
  TOP w0.127: U28.15 236.55,106.18 236.63,106.1 237.09,106.1 v1(237.32,106.33) ; J20.23 v1(90.42,201.88)
  BOTTOM w0.127: v1(90.42,201.88) 90.64,202.1 90.81,202.1 arc(90.82,202.1) 90.84,202.1 91.09,202.05 arc(91.19,201.99) 91.21,201.87 arc(91.24,201.75) 91.34,201.69 91.53,201.65 arc(91.65,201.68) 91.72,201.78 arc(91.78,201.88) 91.9,201.91 92.09,201.88 arc(92.19,201.81) 92.22,201.69 arc(92.24,201.57) 92.34,201.51 92.53,201.48 arc(92.65,201.5) 92.72,201.6 arc(92.78,201.71) 92.9,201.73 93.09,201.7 arc(93.19,201.63) 93.22,201.52 arc(93.24,201.4) 93.34,201.33 93.53,201.3 arc(93.65,201.33) 93.72,201.43 arc(93.78,201.53) 93.9,201.56 94.94,201.37 arc(97.1,200.74) 99.07,199.66 122.35,183.36 arc(125.43,181.67) 128.8,180.69 176.11,172.35 arc(180.3,171.98) 184.5,172.35 199.55,175 arc(202.48,175.26) 205.42,175 229.24,170.8 arc(232.62,169.82) 235.7,168.13 236.25,167.74 arc(237,167.11) 237.63,166.36 240.92,161.67 arc(242.33,159.09) 243.16,156.25 246.44,137.66 arc(246.63,135.43) 246.44,133.19 242.36,110.03 arc(242.22,109.57) 241.99,109.16 241.13,107.93 arc(240.52,107.2) 239.8,106.59 239.8,106.59 arc(239.38,106.36) 238.92,106.23 238.39,106.14 arc(238.2,106.11) 238.01,106.1 237.55,106.1 v1(237.32,106.33)
MPEX2_RX_P: length 225.8
  TOP w0.127: v1(237.32,105.52) 237.09,105.75 236.63,105.75 236.55,105.68 U28.14 ; J20.25 v1(90.42,202.68)
  BOTTOM w0.127: v1(90.42,202.68) 90.64,202.45 90.81,202.45 arc(90.86,202.45) 90.9,202.45 95,201.72 arc(97.24,201.07) 99.28,199.95 122.56,183.65 arc(125.56,182) 128.86,181.04 176.17,172.7 arc(180.3,172.34) 184.43,172.7 199.49,175.35 arc(202.48,175.62) 205.48,175.35 229.3,171.15 arc(232.75,170.15) 235.9,168.42 236.46,168.03 arc(237.25,167.36) 237.92,166.57 241.21,161.88 arc(242.66,159.22) 243.51,156.31 246.79,137.72 arc(246.99,135.43) 246.79,133.13 242.71,109.97 arc(242.55,109.44) 242.28,108.95 241.42,107.72 arc(240.78,106.95) 240.01,106.31 240.01,106.31 arc(239.52,106.04) 238.98,105.88 238.45,105.79 arc(238.23,105.76) 238.01,105.75 237.55,105.75 v1(237.32,105.52)
MPEX2_TX_N: length 228.7
  TOP w0.127: v1(238.95,104.8) 238.72,104.57 237.44,104.57 236.91,105.1 236.63,105.1 236.55,105.18 U28.13 ; C631.2 92.58,205.23 92.96,205.23 v1(93.09,205.1)
  BOTTOM w0.127: v1(93.09,205.1) 93.29,205.31 94.12,205.31 arc(94.31,205.3) 94.5,205.27 94.75,205.23 arc(94.85,205.16) 94.88,205.04 94.88,205.04 arc(94.91,204.92) 95.01,204.86 95.19,204.82 arc(95.31,204.85) 95.38,204.95 arc(95.45,205.06) 95.57,205.09 95.75,205.05 arc(95.85,204.99) 95.88,204.87 arc(95.91,204.74) 96.01,204.68 96.19,204.65 arc(96.31,204.67) 96.38,204.78 arc(96.45,204.88) 96.57,204.91 96.75,204.88 arc(96.85,204.81) 96.88,204.69 arc(96.91,204.57) 97.01,204.5 97.19,204.47 arc(97.31,204.5) 97.38,204.6 97.38,204.6 arc(97.45,204.71) 97.57,204.73 98.2,204.62 arc(100.23,204.03) 102.09,203.01 127.85,184.97 arc(130.4,183.58) 133.19,182.76 179.07,174.67 arc(183.69,174.27) 188.31,174.67 198.19,176.42 arc(202.41,176.78) 206.62,176.42 230.83,172.15 arc(233.34,171.42) 235.62,170.16 237.04,169.17 arc(238.21,168.19) 239.19,167.02 242.61,162.13 arc(243.83,159.91) 244.54,157.47 248.23,136.59 arc(248.41,134.45) 248.23,132.31 244.35,110.31 arc(243.85,108.6) 242.99,107.04 242.85,106.84 arc(242.03,105.87) 241.06,105.05 241.06,105.05 arc(240.64,104.82) 240.19,104.69 239.66,104.6 arc(239.51,104.58) 239.36,104.57 239.18,104.57 v1(238.95,104.8)
MPEX2_TX_P: length 228.7
  TOP w0.127: v1(238.95,103.99) 238.72,104.22 237.29,104.22 236.76,104.75 236.63,104.75 236.55,104.68 U28.12 ; v1(93.09,205.87) 93.01,205.78 92.53,205.78 C630.2
  BOTTOM w0.127: v1(93.09,205.87) 93.29,205.66 94.12,205.66 arc(94.34,205.65) 94.56,205.63 98.26,204.97 arc(100.37,204.36) 102.3,203.3 128.05,185.27 arc(130.53,183.91) 133.25,183.11 179.13,175.02 arc(183.69,174.62) 188.25,175.02 198.13,176.77 arc(202.41,177.14) 206.69,176.77 230.9,172.5 arc(233.47,171.75) 235.83,170.45 237.25,169.46 arc(238.46,168.44) 239.48,167.23 242.9,162.34 arc(244.16,160.04) 244.9,157.53 248.58,136.65 arc(248.77,134.45) 248.58,132.25 244.7,110.25 arc(244.18,108.47) 243.28,106.84 243.14,106.64 arc(242.29,105.62) 241.28,104.77 arc(240.79,104.5) 240.25,104.34 239.72,104.25 arc(239.54,104.22) 239.36,104.22 239.18,104.22 v1(238.95,103.99)
MVREF: length 214.4
  TOP w0.305: U1.F20 v2(158.92,118.85) ; C18.1 173.23,154.69 173.7,155.15 173.7,157.33 J1.67
  TOP w0.508: J1.1 103.38,157.01 103.38,153.92 C19.1
  L4PWR w0.381: v2(158.92,118.85) 158.9,118.85 158.24,119.51
  L4PWR w0.508: J1.1 103.76,157.39 103.76,155.19 125.09,133.86 136.27,133.86 150.62,119.51 158.24,119.51
  BOTTOM w0.305: C21.1 158.92,118.85 v2(158.92,118.85) 158.73,118.66 C22.1
  BOTTOM w0.508: 173.99,154.18 173.92,154.25 J1.67
  BOTTOM w0.762: v1(223.77,144.65) v1(223.01,144.65) 213.49,154.18 161.04,154.18 159.51,152.65 105.92,152.65 103.38,155.19 103.38,157.01 J1.1
NAND_CS_N: length 28.9
  TOP w0.127: v1(88.14,125.22) 88.07,125.16 88.07,121.86 74.14,107.93 U65.G16
  BOTTOM w0.127: v1(88.14,125.22) 88.83,125.91 U7.2
NAND_IO0: length 2.9
  TOP w0.127: U6.29 v1(79.55,131.39)
  BOTTOM w0.127: U98.12 79.66,131.28 v1(79.55,131.39)
NAND_IO1: length 2.8
  TOP w0.127: U6.30 v1(78.8,130.88)
  BOTTOM w0.127: v1(78.8,130.88) 78.8,130.88 U98.11
NAND_IO2: length 2.9
  TOP w0.127: U6.31 v1(79.55,130.39)
  BOTTOM w0.127: v1(79.55,130.39) 79.65,130.48 U98.10
NAND_IO3: length 2.9
  TOP w0.127: U6.32 v1(78.8,129.88)
  BOTTOM w0.127: v1(78.8,129.88) 79.72,129.88 79.92,130.08 U98.9
NAND_IO4: length 2.9
  TOP w0.127: U6.41 v1(79.55,125.39)
  BOTTOM w0.127: v1(79.55,125.39) 79.85,125.39 80.05,125.19 U99.12
NAND_IO5: length 2.9
  TOP w0.127: U6.42 v1(78.8,124.88)
  BOTTOM w0.127: v1(78.8,124.88) 79.84,124.88 79.94,124.79 U99.11
NAND_IO6: length 2.8
  TOP w0.127: U6.43 v1(79.55,124.39)
  BOTTOM w0.127: v1(79.55,124.39) 79.56,124.39 U99.10
NAND_IO7: length 2.9
  TOP w0.127: U6.44 v1(78.8,123.88)
  BOTTOM w0.127: v1(78.8,123.88) 79.82,123.88 79.92,123.99 U99.9
NAND_RB_N: length 47.6
  TOP w0.127: v1(66.55,111.38) 66.55,110.74 66.17,110.37 60.45,110.37 60.02,109.93 U65.E4 ; U6.7 v1(95.76,124.88)
  L6SIG w0.102: v1(66.55,111.38) 67.31,111.38 68.07,112.14 68.07,112.65 68.33,112.9 74.68,112.9 79.25,117.48 93.22,117.48 95.76,120.02 v1(95.76,124.88)
  BOTTOM w0.127: v1(95.76,124.88) 95.97,125.09 R48.1
NOR_CS_N: length 64.6
  TOP w0.127: U65.D13 v1(69.52,111.43) ; U4.32 v1(103.72,133.9)
  L3SIG w0.102: v1(103.72,133.9) 103.51,134.11 85.67,134.11 81.98,137.79 72.26,137.79 70.74,136.27 70.74,129.92 69.09,128.27 69.09,111.86 v1(69.52,111.43)
  BOTTOM w0.127: R43.1 103.62,133.99 v1(103.72,133.9)
NOR_RST_N: length 80.3
  TOP w0.127: U65.C14 v1(70.52,112.43) ; v1(120.02,128.4) 120.02,128.4 U4.14
  L3SIG w0.102: v1(70.52,112.43) 69.98,112.97 69.98,128.14 71.5,129.67 71.5,136.02 72.52,137.03 81.79,137.03 85.73,133.1 92.71,133.1 92.96,132.84 113.67,132.84 116.59,129.92 117.86,129.92 119.38,128.4 v1(120.02,128.4)
  BOTTOM w0.127: R47.1 v1(120.02,128.4)
OVDD: length 83.3
  TOP w0.203: v1(158.5,90.42) 158.4,90.52 U18.16 ; v1(69.09,145.16) 69.18,145.07 U20.13 ; U12.16 162.98,90.52 v1(163.07,90.42)
  TOP w0.254: U4.29 101.37,135.4 v1(101.22,135.25)
  TOP w0.305: U1.M8 v2(163.72,108.45) ; U1.J15 v2(161.32,114.85) ; U1.J19 v2(161.32,118.05) ; U1.J18 v2(161.32,117.25) ; U1.G9 v2(159.72,109.25) ; U1.J16 v2(161.32,115.65) ; U1.J17 v2(161.32,116.45) ; U1.J14 v2(161.32,113.25)
  TOP w0.381: U10.5 106.79,119.24 v1(106.81,119.25) ; U22.1 69.54,138.79 69.54,138.25 v1(69.46,138.17) ; U9.5 103.24,119.24 v1(103.25,119.25) ; U8.5 v1(109.54,119.82)
  TOP w0.508: R102.2 v1(69.46,138.17) ; C23.1 124.57,123.82 v1(124.39,124)
  BOTTOM w0.203: U11.16 91.86,129.24 C1059.1 ; C1073.1 82.01,133.39 U98.16 ; C1061.1 91.86,123.4 U7.16 ; C1071.1 82.01,127.3 U99.16
  BOTTOM w0.254: U2.18 v1(124.39,129.5) ; U2.7 v1(124.39,124) ; U2.31 v1(134.18,129.5) ; U2.42 v1(134.18,124)
  BOTTOM w0.508: C32.1 v1(106.81,119.25) ; v1(69.46,138.17) 69.34,138.29 C53.1 ; v1(149.49,112.4) R5.2 150.24,111.76 ; 150.24,111.76 150.24,109.73 150.62,109.35 R188.1 ; 150.24,111.76 152.53,111.76 R191.1 ; v1(91.95,122.56) 91.94,122.56 C1061.1 ; v1(87.88,120.27) 81.79,120.27 79.76,118.24 74.68,118.24 72.32,115.88 R7.2 72.85,115.23 73.36,114.72 73.36,114.27 R6.2 ; C50.1 v1(69.09,145.16) ; C30.1 v1(103.25,119.25) ; v1(124.39,129.5) 124.09,129.8 C24.1 ; R66.2 v1(157.48,96.01) ; v1(60.96,119.25) 60.96,116.39 R11.2 R10.2 R9.2 ; R65.2 v1(153.42,96.01) ; R79.2 162.31,90.43 C40.1 v1(163.07,90.42) ; R42.2 v1(104.77,123.45) ; v1(151.38,116.2) 151.76,116.2 152.15,116.59 R82.2 ; C1073.1 v1(81.92,134.23) ; R864.1 v1(112.14,126.37) ; C42.1 v1(158.5,90.42) ; R47.2 R41.2 R44.2 v1(117.22,130.43) ; C31.1 109.61,119.9 v1(109.54,119.82) ; v1(91.95,128.4) 91.94,128.4 C1059.1 ; v1(134.18,129.5) 134.49,129.8 C25.1 ; R81.2 77.85,105.16 v1(78.36,105.66) ; C26.1 134.36,123.82 v1(134.18,124) ; R43.2 101.48,134.99 v1(101.22,135.25) 100.96,134.99 C35.1 ; C1071.1 v1(81.92,128.14) ; R808.1 v1(76.45,129.16)
  vias: v1(60.96,122.68) v1(60.96,121.54) v1(60.96,120.4) v1(61.72,122.68) v1(61.72,121.54) v1(61.72,120.4) v1(61.72,119.25) v1(79.12,105.66) v1(93.47,139.19) v1(94.36,139.19) v1(95.25,139.19) v1(150.24,103.38) v1(151,103.38) v1(151.76,103.38) v1(151.89,96.01) v1(152.65,96.01)
OVDD_OSC_DDR: length 3
  TOP w0.254: R516.1 80.39,104.39 81.28,105.28 81.28,106.81
OVDD_OSC_USB: length 2.9
  TOP w0.254: 81.15,90.17 81.15,88.39 80.39,87.63 R174.1
OVDD_SLP: length 39.3
  TOP w0.305: U1.J13 v2(161.32,112.45) ; U1.J12 v2(161.32,111.65) ; U1.J11 v2(161.32,110.85)
  TOP w0.381: U65.F8 v1(63.52,109.43) ; U65.F9 v1(65.52,109.43) ; U65.P16 v1(72.52,100.43) ; U65.H11 v1(67.52,107.43) ; U65.A14 v1(70.52,114.43) ; U65.A3 v1(58.52,114.43) ; U65.C16 v1(72.52,112.43) ; U65.J11 v1(67.52,105.43)
  TOP w1.016: J9.2 J10.2 54.99,141.26
  BOTTOM w0.305: v1(77.85,97.92) 77.36,98.41 U21.1 ; R96.1 72.52,110.33 71.82,109.63 R70.2
  BOTTOM w0.508: v1(65.52,109.43) 65.02,108.93 C712.1 ; v1(58.52,114.43) 58.02,113.93 C715.1 ; v1(77.85,97.92) 77.22,97.28 C52.1 ; R94.1 72.52,112.42 v1(72.52,112.43) 72.02,112.92 C1104.1 ; R94.1 R96.1 ; R94.1 R83.2 ; v1(151,105.28) 151.14,105.42 R194.1 152.78,105.42 R84.2 ; v1(67.52,107.43) 67.02,107.92 C714.1 ; R72.2 R85.2 R98.1 R813.2 v1(67.52,105.43) 67.02,104.93 C716.1 ; R84.2 R74.2 R73.2 ; R84.2 R71.2 ; v1(70.52,114.43) 71.01,113.93 C1105.1 ; R69.2 R70.2 ; C713.1 72.02,99.93 v1(72.52,100.43) ; v1(149.61,116.84) 149.35,117.09 R195.1 ; v1(63.52,109.43) 64.01,108.93 C711.1 ; FB13.2 v1(155.79,97.07)
  vias: v1(56.01,139.45) v1(56.01,138.3) v1(56.01,137.16) v1(56.77,139.45) v1(56.77,138.3) v1(56.77,137.16) v1(78.36,89.03) v1(78.61,97.92) v1(79.12,89.03)
PEX2_SEL_N: length 205.3
  TOP w0.127: U65.P6 62.02,100.92 v1(62.51,100.42) ; U26.9 v1(233.45,95.14)
  L6SIG w0.102: v1(62.51,100.42) 63.01,99.92 63.01,97.64 70.23,90.42 70.23,85.78 72.14,83.88 72.14,82.8 72.39,82.55 74.04,82.55 77.22,79.38 79.88,79.38 82.17,77.09 94.36,77.09 95.12,76.33 152.65,76.33 153.92,77.6 168.02,77.6 168.5,77.11 182.98,77.11 184.12,75.97 187.17,75.97 189.74,73.41 191.37,73.41 192.03,74.07 192.78,74.07 193.77,74.07 194.66,74.96 197.25,74.96 198.14,74.07 209.93,74.07 214.48,78.61 225.68,78.61 233.86,86.79 233.86,94.73 v1(233.45,95.14)
  BOTTOM w0.127: v1(233.45,95.14) 233.16,94.86 R142.2
PEX4_SEL_N: length 224.6
  TOP w0.127: U28.9 v1(233.45,104.03) ; U29.9 v1(233.45,112.92) ; U65.R6 62.02,99.92 v1(62.51,99.42)
  L6SIG w0.102: v1(62.51,99.42) 62.51,97.76 69.98,90.3 69.98,85.71 71.88,83.81 71.88,81.92 72.39,81.41 73.15,81.41 77.72,76.84 94.23,76.84 95,76.07 152.72,76.07 153.99,77.34 167.89,77.34 168.35,76.89 182.83,76.89 183.97,75.74 187.02,75.74 189.61,73.15 191.43,73.15 192.12,73.84 192.69,73.84 192.69,73.84 193.87,73.84 194.75,74.73 197.16,74.73 198.05,73.84 210.03,73.84 214.55,78.36 225.81,78.36 234.19,86.74 234.19,103.29 v1(233.45,104.03)
  BOTTOM w0.127: R143.2 233.16,103.75 v1(233.45,104.03) 234.06,104.65 234.06,112.31 v1(233.45,112.92)
PEX_PRS_N: length 273.6
  TOP w0.127: R405.1 270.13,114.17 271.02,115.06 273.06,115.06 J18.B31 ; U65.P5 61.02,100.92 v1(61.51,100.42)
  L6SIG w0.102: v1(61.51,100.42) 62.01,99.92 62.01,97.88 69.72,90.17 69.72,85.6 71.63,83.69 71.63,80.9 72.14,80.39 73.79,80.39 77.6,76.58 94.11,76.58 94.87,75.82 152.91,75.82 154.18,77.09 167.77,77.09 168.2,76.66 182.68,76.66 183.82,75.51 186.87,75.51 189.48,72.9 191.5,72.9 192.22,73.61 192.59,73.61 193.96,73.61 194.67,74.32 196.23,74.32 196.95,73.61 210.12,73.61 214.62,78.11 225.93,78.11 227.84,80.01 268.73,80.01 270.38,81.66 270.38,93.73 272.8,96.14 272.8,98.83 J18.B17
  BOTTOM w0.127: J18.B31 274.96,113.17 274.96,100.99 J18.B17
PEX_REFCLK_N: length 64.7
  TOP w0.102: v1(245.36,136.91) 245.1,136.64 243.06,136.64 242.83,136.87 R523.1 242.45,136.78 242.18,136.78 R521.2
  L3SIG w0.102: v1(245.36,136.91) 245.62,136.65 246.13,136.65 246.79,135.99 246.79,134.23 249.44,131.57 257.3,131.57 264.41,124.46 264.41,97.03 265.18,96.27 270.14,96.27 270.38,96.51 270.38,96.9 270.21,97.08 J18.A14
PEX_REFCLK_P: length 64.6
  TOP w0.102: v1(245.36,136.09) 245.1,136.36 243.06,136.36 242.83,136.13 R519.1 242.45,136.27 242.18,136.27 R520.2
  L3SIG w0.102: J18.A13 271.36,96.27 270.53,96.27 270.26,95.99 265.06,95.99 264.13,96.91 264.13,124.34 257.19,131.29 249.33,131.29 246.51,134.11 246.51,135.88 246.01,136.37 245.64,136.37 v1(245.36,136.09)
PEX_RST_N: length 242.9
  TOP w0.127: v1(61.51,99.42) 61.02,99.92 U65.R5
  L6SIG w0.102: J18.A11 270.64,91.17 270.64,81.53 268.86,79.76 227.97,79.76 226.06,77.85 214.69,77.85 210.22,73.38 196.85,73.38 196.14,74.09 194.77,74.09 194.05,73.38 192.5,73.38 192.31,73.38 191.57,72.64 189.36,72.64 186.72,75.29 183.67,75.29 182.52,76.43 168.05,76.43 167.64,76.84 154.3,76.84 153.03,75.57 94.74,75.57 93.98,76.33 77.47,76.33 74.55,79.25 71.88,79.25 71.37,79.76 71.37,83.57 69.47,85.47 69.47,90.04 61.51,98 v1(61.51,99.42)
PEX_RX0_N: length 109.8
  TOP w0.127: J18.A17 271.42,99.95 arc(271.12,99.82) 270.81,99.95 270.63,100.13 arc(270.44,100.26) 270.22,100.3 267.09,100.3 267.06,100.3 265.34,100 arc(264.68,99.8) 264.07,99.47 262.5,98.37 arc(261.42,97.46) 260.51,96.38 arc(260.5,96.38) 260.5,96.38 260.49,96.36 arc(259.53,95.21) 258.38,94.25 252.78,90.33 arc(251.54,89.65) 250.18,89.25 245.26,88.38 arc(243.33,88.21) 241.41,88.38 233.43,89.79 arc(231.41,90.38) 229.56,91.39 222.12,96.6 arc(219.89,98.48) 218.01,100.72 215.44,104.39 arc(213.41,106.81) 210.98,108.84 203.29,114.23 arc(200.48,115.77) 197.41,116.66 192.79,117.48 arc(189.59,117.76) 186.39,117.48 182.22,116.74 arc(181.89,116.64) 181.58,116.48 181.51,116.42 arc(181.27,116.3) 181.02,116.22 178.08,115.7 arc(177.89,115.68) 177.7,115.67 176.99,115.67 176.53,115.57 U1.AG16
PEX_RX0_P: length 109.7
  TOP w0.127: J18.A16 269.65,98.97 arc(269.75,98.91) 269.86,98.88 270.08,98.88 arc(270.37,98.94) 270.62,99.11 270.7,99.19 arc(270.78,99.37) 270.7,99.56 270.38,99.88 arc(270.3,99.93) 270.22,99.95 267.12,99.95 267.11,99.95 265.41,99.65 arc(264.81,99.47) 264.27,99.18 262.71,98.08 arc(261.67,97.21) 260.8,96.18 arc(260.79,96.16) 260.78,96.15 arc(259.78,94.96) 258.59,93.96 252.98,90.04 arc(251.67,89.32) 250.24,88.9 245.32,88.03 arc(243.33,87.86) 241.35,88.03 233.37,89.44 arc(231.27,90.05) 229.36,91.1 221.92,96.31 arc(219.63,98.23) 217.72,100.51 215.15,104.18 arc(213.15,106.56) 210.78,108.55 203.08,113.94 arc(200.35,115.44) 197.35,116.31 192.72,117.13 arc(189.59,117.4) 186.46,117.13 182.28,116.39 arc(182.02,116.32) 181.79,116.19 181.71,116.13 arc(181.41,115.97) 181.08,115.87 178.14,115.35 arc(177.92,115.33) 177.7,115.32 176.99,115.32 U1.AH16
PEX_RX1_N: length 38.2
  TOP w0.127: J18.A22 270.14,105.08 arc(270.32,105.04) 270.48,104.93 270.49,104.93 arc(270.55,104.77) 270.49,104.62 270.25,104.39 arc(270.09,104.28) 269.91,104.24 265.41,104.24 arc(265.33,104.24) 265.25,104.23 263.88,103.99 263.24,103.87 arc(262.28,103.59) 261.39,103.11 256.38,99.6 arc(255.41,99.06) 254.34,98.75 250.92,98.15 250.91,98.15 arc(250.53,98.12) 250.15,98.15 247.46,98.62 arc(247.01,98.76) 246.59,98.98 arc(245.43,99.62) 244.15,99.99 241.36,100.49 arc(240.92,100.52) 240.48,100.49 239.27,100.27 arc(238.77,100.13) 238.3,99.87 237.78,99.51 237.54,99.35 arc(237.5,99.32) 237.45,99.31 237.42,99.3 arc(237.33,99.29) 237.23,99.29 236.55,99.29 236.55,99.29 U26.19
PEX_RX1_P: length 38.2
  TOP w0.127: U26.18 236.46,98.79 arc(236.55,98.8) 236.62,98.85 236.64,98.87 arc(236.71,98.92) 236.79,98.93 237.23,98.93 arc(237.36,98.94) 237.48,98.95 237.51,98.96 arc(237.63,98.99) 237.74,99.05 237.98,99.22 238.5,99.58 arc(238.9,99.8) 239.34,99.92 240.54,100.14 arc(240.92,100.17) 241.3,100.14 244.09,99.64 arc(245.29,99.29) 246.39,98.69 arc(246.87,98.43) 247.4,98.27 250.09,97.8 arc(250.53,97.76) 250.97,97.8 254.41,98.4 arc(255.54,98.74) 256.58,99.31 261.6,102.82 arc(262.41,103.26) 263.3,103.52 263.39,103.54 263.39,103.54 263.94,103.63 263.94,103.64 265.32,103.88 arc(265.36,103.88) 265.41,103.89 269.91,103.89 arc(270.23,103.95) 270.5,104.13 270.76,104.39 arc(271,104.49) 271.23,104.39 J18.A21
PEX_RX2_N: length 37.5
  TOP w0.127: U28.19 236.55,108.18 236.63,108.1 236.71,108.1 arc(236.75,108.11) 236.79,108.11 237.01,108.15 arc(237.22,108.21) 237.42,108.32 237.54,108.4 arc(237.85,108.57) 238.19,108.67 238.2,108.67 238.78,108.78 arc(239.22,108.82) 239.66,108.78 240.26,108.67 arc(241.36,108.35) 242.37,107.8 244.92,106.01 arc(246.59,105.19) 248.44,104.9 249.99,104.9 arc(250.36,104.92) 250.72,104.97 255.43,105.8 arc(255.89,105.93) 256.3,106.16 256.86,106.55 257.42,106.94 arc(257.9,107.2) 258.43,107.36 263.3,108.22 arc(263.37,108.23) 263.45,108.23 269.93,108.23 arc(270.02,108.25) 270.1,108.3 270.38,108.58 arc(270.44,108.71) 270.38,108.84 270.32,108.9 arc(270.13,109.03) 269.9,109.08 J18.A26
PEX_RX2_P: length 37.6
  TOP w0.127: J18.A25 271.42,108.21 arc(270.96,108.39) 270.51,108.21 270.35,108.05 arc(270.16,107.92) 269.93,107.87 263.45,107.87 arc(263.41,107.87) 263.36,107.87 258.49,107.01 arc(258.04,106.87) 257.62,106.65 256.51,105.87 arc(256.02,105.6) 255.49,105.45 250.78,104.62 arc(250.39,104.56) 249.99,104.55 248.44,104.55 arc(246.49,104.85) 244.71,105.72 242.16,107.51 arc(241.22,108.02) 240.2,108.32 239.6,108.43 arc(239.22,108.46) 238.84,108.43 238.25,108.32 arc(237.99,108.25) 237.74,108.11 237.62,108.03 arc(237.36,107.88) 237.07,107.8 236.85,107.76 arc(236.78,107.75) 236.71,107.75 236.63,107.75 236.55,107.68 U28.18
PEX_RX3_N: length 42.3
  TOP w0.127: J18.A30 269.83,113.08 arc(270.13,113.02) 270.38,112.85 arc(270.46,112.67) 270.38,112.5 270.38,112.49 270.13,112.24 268.5,112.24 arc(268.16,112.26) 267.83,112.3 266.35,112.56 arc(265.89,112.69) 265.47,112.92 265.33,113.03 arc(265.04,113.27) 264.79,113.56 264.76,113.6 arc(264.58,113.94) 264.47,114.3 264.14,116.18 arc(263.86,117.16) 263.36,118.06 arc(263.35,118.08) 263.34,118.09 arc(262.41,119.2) 261.3,120.12 260.46,120.71 arc(259.41,121.29) 258.26,121.62 254.25,122.33 arc(251.67,122.56) 249.09,122.33 245.24,121.65 arc(243.4,121.12) 241.72,120.19 237.47,117.22 arc(237.27,117.11) 237.06,117.05 236.79,117 arc(236.75,117) 236.71,116.99 236.63,116.99 236.55,117.07 U29.19
PEX_RX3_P: length 42.3
  TOP w0.127: J18.A29 271.38,112.24 arc(271.01,112.39) 270.63,112.24 270.28,111.89 268.5,111.89 arc(268.13,111.9) 267.77,111.95 266.28,112.21 arc(265.75,112.37) 265.27,112.63 265.12,112.73 arc(264.78,113.02) 264.5,113.36 264.47,113.4 arc(264.25,113.8) 264.12,114.24 263.79,116.11 arc(263.53,117.03) 263.07,117.86 263.07,117.86 arc(263.06,117.87) 263.05,117.89 arc(262.16,118.94) 261.1,119.83 260.25,120.42 arc(259.27,120.96) 258.2,121.27 254.19,121.98 arc(251.67,122.2) 249.15,121.98 245.3,121.3 arc(243.54,120.79) 241.92,119.9 237.67,116.93 arc(237.41,116.78) 237.12,116.7 236.85,116.65 arc(236.78,116.64) 236.71,116.64 236.63,116.64 236.55,116.57 U29.18
PEX_TX0_N: length 102.4
  TOP w0.127: C607.2 266.38,98.22 265.95,98.22 v1(265.67,98.5) ; U1.AE16 v2(174.92,115.65)
  BOTTOM w0.127: v1(265.67,98.5) 265.38,98.22 265.05,98.22 arc(264.83,98.21) 264.61,98.18 261.82,97.69 arc(260.15,97.2) 258.63,96.37 251.19,91.16 arc(250.19,90.61) 249.09,90.29 243.87,89.37 arc(241.66,89.18) 239.45,89.37 233.07,90.5 arc(231.61,90.92) 230.27,91.65 224.13,95.96 arc(223.64,96.22) 223.11,96.38 221.53,96.66 220.8,96.79 arc(219.52,97.16) 218.35,97.8 196.72,112.94 arc(195.01,113.89) 193.12,114.44 183.68,116.1 arc(182.47,116.21) 181.26,116.1 178.58,115.63 arc(178.39,115.6) 178.2,115.6 174.97,115.6 v2(174.92,115.65)
PEX_TX0_P: length 103.3
  TOP w0.127: v1(265.67,97.58) 265.95,97.87 266.38,97.87 C606.2 ; U1.AD16 v2(174.12,115.65)
  BOTTOM w0.127: v2(174.12,115.65) 174.46,115.4 arc(174.69,115.28) 174.94,115.24 178.2,115.24 arc(178.42,115.25) 178.64,115.28 181.32,115.75 arc(182.47,115.85) 183.62,115.75 193.06,114.09 arc(194.87,113.56) 196.52,112.65 218.15,97.51 arc(219.38,96.83) 220.74,96.44 221.46,96.31 221.47,96.31 223.05,96.03 arc(223.51,95.89) 223.92,95.67 230.07,91.36 arc(231.47,90.59) 233.01,90.15 239.39,89.02 arc(241.66,88.82) 243.94,89.02 249.16,89.94 arc(250.33,90.28) 251.4,90.87 258.83,96.08 arc(260.29,96.88) 261.88,97.34 264.67,97.83 arc(264.86,97.86) 265.05,97.87 265.39,97.87 v1(265.67,97.58)
PEX_TX1_N: length 33.8
  TOP w0.127: C615.2 266.51,102.42 arc(266.31,102.28) 266.07,102.23 265.31,102.23 arc(265.09,102.23) 264.87,102.2 264.3,102.1 arc(263.77,101.94) 263.28,101.67 254.46,95.49 arc(254.04,95.27) 253.58,95.13 250.91,94.66 250.9,94.66 arc(250.52,94.63) 250.15,94.66 247.24,95.17 arc(245.24,95.76) 243.42,96.76 242.62,97.32 arc(242.13,97.58) 241.6,97.74 238.27,98.32 arc(237.83,98.36) 237.39,98.32 236.75,98.21 236.63,98.21 236.55,98.29 U26.17
PEX_TX1_P: length 33.8
  TOP w0.127: C608.2 266.56,101.75 arc(266.41,101.85) 266.24,101.88 265.31,101.88 arc(265.12,101.87) 264.93,101.85 264.36,101.74 arc(263.9,101.61) 263.49,101.38 254.66,95.2 arc(254.18,94.94) 253.65,94.78 250.97,94.31 arc(250.96,94.31) 250.96,94.31 250.96,94.31 arc(250.52,94.27) 250.08,94.31 247.18,94.82 arc(245.11,95.43) 243.21,96.47 242.42,97.02 arc(242,97.25) 241.54,97.39 238.21,97.97 arc(237.83,98.01) 237.45,97.97 236.78,97.86 236.63,97.86 236.55,97.79 U26.16
PEX_TX2_N: length 33.3
  TOP w0.127: C617.2 266.52,106.42 arc(266.38,106.33) 266.22,106.3 265.62,106.3 arc(265.4,106.29) 265.18,106.26 262.26,105.75 arc(261.05,105.39) 259.94,104.78 257.52,103.09 arc(255.97,102.24) 254.28,101.75 254.28,101.75 arc(252.51,101.59) 250.75,101.75 246.16,102.56 arc(245.16,102.85) 244.25,103.35 239.47,106.69 arc(238.99,106.96) 238.46,107.11 238.06,107.18 arc(237.63,107.22) 237.2,107.18 236.75,107.1 236.63,107.1 236.55,107.18 U28.17
PEX_TX2_P: length 33.4
  TOP w0.127: C616.2 266.46,105.76 arc(266.26,105.9) 266.02,105.94 265.62,105.94 arc(265.43,105.94) 265.24,105.91 262.32,105.4 arc(261.18,105.06) 260.14,104.49 257.73,102.8 arc(256.11,101.91) 254.34,101.4 254.34,101.4 arc(252.51,101.24) 250.68,101.4 246.1,102.21 arc(245.02,102.52) 244.04,103.06 239.27,106.4 arc(238.85,106.63) 238.4,106.76 238.03,106.82 arc(237.63,106.86) 237.22,106.82 236.78,106.75 236.63,106.75 236.55,106.68 U28.16
PEX_TX3_N: length 36.8
  TOP w0.127: U29.17 236.55,116.07 236.63,115.99 237.03,115.99 238.54,116.26 arc(239.69,116.6) 240.74,117.17 241.45,117.67 arc(243.02,118.53) 244.74,119.03 249.38,119.85 arc(251.56,120.04) 253.74,119.85 257.32,119.22 arc(257.85,119.06) 258.34,118.8 259.8,117.77 arc(260.14,117.49) 260.42,117.15 261.62,115.44 arc(261.88,114.96) 262.04,114.43 262.47,111.95 arc(262.53,111.77) 262.62,111.6 262.75,111.41 262.92,111.18 arc(263.01,111.07) 263.12,110.98 263.49,110.72 arc(263.89,110.5) 264.32,110.37 264.62,110.32 arc(264.81,110.3) 265,110.29 266.16,110.29 arc(266.36,110.33) 266.53,110.44 C619.2
PEX_TX3_P: length 36.8
  TOP w0.127: U29.16 236.55,115.57 236.63,115.64 237.06,115.64 238.6,115.91 arc(239.83,116.27) 240.95,116.88 241.66,117.38 arc(243.16,118.2) 244.8,118.68 249.44,119.5 arc(251.56,119.69) 253.68,119.5 257.26,118.87 arc(257.71,118.74) 258.13,118.51 259.6,117.48 arc(259.89,117.24) 260.13,116.95 261.33,115.24 arc(261.55,114.82) 261.69,114.37 262.12,111.89 arc(262.2,111.63) 262.33,111.39 262.63,110.97 arc(262.76,110.82) 262.91,110.69 263.28,110.43 arc(263.75,110.17) 264.26,110.02 264.56,109.97 arc(264.78,109.94) 265,109.93 266.16,109.93 arc(266.36,109.89) 266.53,109.77 C618.2
PEXCLK_OE_N: length 382.8
  TOP w0.127: U97.30 234.8,140.1 v1(234.7,140.21) ; U97.24 237.2,140.17 v1(237.24,140.21) ; R843.2 240.41,135.14 240.41,135.38 240.03,135.76 v1(240.03,135.89) 240.01,135.91 U97.13 ; U65.N16 72.44,101.93 73.79,100.58 73.79,97.41 72.52,96.14 70.99,96.14 66.52,91.66 v1(66.52,90.61) ; v1(233.17,137.03) 233.24,137.11 U97.35
  L6SIG w0.102: v1(240.03,135.89) 240.41,135.89 241.17,136.65 241.17,139.32 240.54,139.95 239.14,139.95 238.89,139.7 237.74,139.7 v1(237.24,140.21) ; v1(237.24,140.21) 236.73,140.72 235.2,140.72 v1(234.7,140.21) 233.88,140.21 232.54,138.87 232.54,137.67 v1(233.17,137.03) ; v1(237.24,140.21) 237.87,140.84 245.62,140.84 259.84,155.07 267.72,155.07 269.88,152.91 272.67,152.91 276.61,148.97 276.61,145.29 278.25,143.65 278.25,82.61 274.38,78.74 228.47,78.74 226.57,76.84 215.07,76.84 210.63,72.39 192.72,72.39 191.96,71.63 188.85,71.63 186.18,74.3 183.13,74.3 181.99,75.44 167.51,75.44 167.13,75.82 154.63,75.82 153.36,74.55 94.23,74.55 93.47,75.31 76.96,75.31 75.69,76.58 72.26,76.58 70.36,78.49 70.36,83.06 68.45,84.96 68.45,86.23 66.52,88.17 v1(66.52,90.61)
PORESET_N: length 102.4
  TOP w0.127: U1.F13 v2(158.92,112.45) ; U65.C15 v1(71.52,112.43)
  L6SIG w0.102: v2(158.92,112.45) 158.92,112.43 158.5,112.02 158.5,110.69 158.24,110.43 157.96,110.43 157.73,110.2 157.73,109.41 157.73,109.4 157.73,109.08 157.73,109.08 157.73,107.44 156.9,106.61 156.9,105.89 156.67,105.67 156.34,105.67 155.96,106.05 151.32,106.05 151.28,106.08 150.74,106.08 150.7,106.05 147.19,106.05 137.01,116.23 127.1,116.23 126.11,117.22 79.38,117.22 74.04,111.89 72.06,111.89 v1(71.52,112.43)
  BOTTOM w0.127: R94.2 v1(71.52,112.43)
POTS1_RING: length 10.8
  TOP w0.508: v1(91.31,27.81) 91.25,27.87 F2.2
  L3SIG w0.508: J22.A3 88.31,23.62 89.03,23.62 90.04,24.64 90.04,26.54 v1(91.31,27.81)
  BOTTOM w0.254: R413.2 v1(91.31,27.81)
POTS1_TIP: length 15.1
  TOP w0.508: F1.2 95.7,27.87 v1(95.76,27.81)
  L3SIG w0.508: J22.A4 89.58,28.7 92.46,28.7 93.34,27.81 v1(95.76,27.81)
  BOTTOM w0.254: R412.2 v1(95.76,27.81)
POTS2_RING: length 16.4
  TOP w0.508: v1(82.42,27.81) 82.36,27.87 F4.2
  L3SIG w0.508: J22.B3 85.88,18.89 84.96,19.81 83.57,19.81 80.65,22.73 80.65,26.03 v1(82.42,27.81)
  BOTTOM w0.254: R435.2 v1(82.42,27.81)
POTS2_TIP: length 22.1
  TOP w0.508: v1(86.87,27.81) 86.81,27.87 F3.2
  L3SIG w0.508: J22.B4 87.15,19.28 85.47,20.95 83.95,20.95 81.79,23.11 81.79,25.53 84.07,27.81 v1(86.87,27.81)
  BOTTOM w0.254: R434.2 v1(86.87,27.81)
POTS3_RING: length 15.9
  TOP w0.508: F6.2 109.03,27.87 v1(109.09,27.81)
  L3SIG w0.508: J25.4 116.46,22.1 110.74,27.81 v1(109.09,27.81)
  BOTTOM w0.254: R451.2 v1(109.09,27.81)
POTS3_TIP: length 17.4
  TOP w0.508: v1(113.54,27.81) 113.48,27.87 F5.2
  L3SIG w0.508: J25.7 107.95,25.81 107.95,28.32 108.59,28.96 111.25,28.96 112.4,27.81 v1(113.54,27.81)
  BOTTOM w0.254: R441.2 v1(113.54,27.81)
POTS4_RING: length 19.7
  TOP w0.508: F8.2 100.14,27.87 v1(100.2,27.81)
  L3SIG w0.508: v1(100.2,27.81) 97.16,27.81 95.63,26.29 95.63,22.48 98.3,19.81 100.2,19.81 100.88,19.13 J23.B3
  BOTTOM w0.254: R465.2 v1(100.2,27.81)
POTS4_TIP: length 25.2
  TOP w0.508: F7.2 104.59,27.87 v1(104.65,27.81)
  L3SIG w0.508: J23.B4 102.15,19.52 100.71,20.95 98.81,20.95 96.77,22.99 96.77,25.65 97.66,26.54 101.22,26.54 102.49,27.81 v1(104.65,27.81)
  BOTTOM w0.254: R464.2 v1(104.65,27.81)
POTS_RST_N: length 2.6
  TOP w0.127: R857.1 108.33,68.71 v1(108.59,68.45) 108.71,68.33 R455.1
  BOTTOM w0.127: R426.1 108.84,68.2 v1(108.59,68.45)
POTS_SWCMP: length 3.9
  TOP w0.305: C683.1 R473.1 95.89,64.78 C684.1 94.87,64.01 94.49,63.63 U59.20
POTS_SWIS: length 6.8
  TOP w0.305: U59.19 93.53,62.42 93.22,62.74 93.22,63.37 93.85,64.01 93.85,66.79 C697.1 R488.2
POTS_SWOUT: length 14.4
  TOP w0.305: U59.21 92.92,65.45 92.46,65.91 v1(91.31,65.91)
  L3SIG w0.305: v1(91.31,65.91) 90.68,65.28 81.66,65.28 v1(80.9,66.04)
  BOTTOM w0.305: R489.1 v1(80.9,66.04)
POTS_TDM_CLK: length 83.8
  TOP w0.127: R445.1 109.98,68.2 v1(110.24,68.45) 110.24,69.09 111.76,70.61 121.54,70.61 126.75,75.82 144.91,75.82 150.11,81.03 158.62,81.03 163.61,86.02 163.61,90.65 163.07,91.2 163.07,95.38 165.35,97.66 v1(165.86,97.66)
  BOTTOM w0.127: v1(110.24,68.45) 109.86,68.07 R417.1 ; R100.1 166.3,104.86 166.3,100.26 165.86,99.82 v1(165.86,97.66)
POTS_TDM_FS: length 83.5
  TOP w0.127: R446.1 113.03,68.2 v1(113.28,68.45) 114.05,69.22 122.56,69.22 127.89,74.55 145.41,74.55 150.62,79.76 159.13,79.76 164.85,85.47 164.85,91.31 164.34,91.82 164.34,92.96 165.23,93.85 165.23,94.95 168.02,97.74 v1(168.02,100.71) ; U1.U5 v2(168.52,106.05)
  L3SIG w0.102: v1(168.02,100.71) 168.13,100.82 168.13,105.67 v2(168.52,106.05)
  BOTTOM w0.127: R418.1 112.9,68.07 v1(113.28,68.45)
POTS_TDM_RXD: length 85.6
  TOP w0.127: v1(167.51,99.95) 167.39,99.82 167.39,97.66 164.85,95.12 164.85,94.11 163.96,93.22 163.96,91.69 164.47,91.19 164.47,85.6 159,80.14 150.5,80.14 145.29,74.93 127.64,74.93 122.3,69.6 113.16,69.6 v1(112.01,68.45) R448.1 ; U1.V5 v2(169.32,106.05)
  L3SIG w0.102: v1(167.51,99.95) 167.64,99.82 168.4,99.82 169.29,100.71 169.29,103.89 168.91,104.27 168.91,105.64 v2(169.32,106.05)
  BOTTOM w0.127: v1(112.01,68.45) 111.89,68.33 R422.1
POTS_TDM_TXD: length 86.1
  TOP w0.127: U1.P5 v2(165.32,106.05) ; v1(167.13,100.97) 166.88,100.71 166.88,97.79 164.47,95.38 164.47,94.36 163.58,93.47 163.58,91.41 164.12,90.86 164.12,85.76 158.88,80.52 150.37,80.52 145.16,75.31 127.25,75.31 121.92,69.98 111.89,69.98 v1(110.87,68.96) 111,68.83 R447.1
  L3SIG w0.102: v1(167.13,100.97) 166.5,101.6 166.5,104.87 v2(165.32,106.05)
  BOTTOM w0.127: R421.1 v1(110.87,68.96)
POTSA_INT_N: length 76.1
  TOP w0.127: U59.31 86.42,66.1 87.88,67.56 R428.1 90.42,68.33 91.19,69.09 v1(91.19,70.74) ; U65.H2 58.01,106.93 v1(57.51,106.43)
  L6SIG w0.102: v1(91.19,70.74) 90.93,70.99 74.92,70.99 73.65,72.26 69.34,72.26 65.28,76.33 65.28,80.77 64.13,81.92 64.13,84.08 53.21,95 53.21,103.38 56.26,106.43 v1(57.51,106.43)
POTSA_SPI_CS_N: length 87.6
  TOP w0.127: U18.10 156.26,84.26 155.19,83.19 149.35,83.19 144.14,77.98 125.36,77.98 121.17,73.79 108.33,73.79 106.43,71.88 91.31,71.88 87.12,67.69 83.57,67.69 83.05,67.18 R420.1 83.17,66.43 U59.36
POTSA_SWVSY: length 11.8
  TOP w0.305: C682.2 97.92,66.56 R475.1 ; C682.2 98.37,65.78 98.68,65.47 98.68,64.26 98.17,63.75 96.65,63.75 95.76,62.86 95.76,62.1 95.43,61.77 U59.18 ; C682.2 97.91,65.79 C683.2 96.89,66.57 R474.1
POTSA_SWVSZ: length 5.3
  TOP w0.305: U59.44 77.94,61.12 77.47,61.59 77.47,64.79 R478.1
POTSB_INT_N: length 89.4
  TOP w0.127: U63.31 109.28,65.71 109.35,65.79 R858.1 109.35,69.22 109.6,69.22 110.11,69.72 110.11,70.61 v1(110.49,70.99) ; v1(58.51,104.42) 59.01,104.93 U65.K3
  L6SIG w0.102: v1(58.51,104.42) 58.01,103.92 56.05,103.92 54.48,102.36 54.48,95.63 65.41,84.71 65.41,82.55 66.55,81.41 66.55,76.96 69.98,73.53 74.17,73.53 75.44,72.26 91.95,72.26 92.71,71.5 109.98,71.5 v1(110.49,70.99)
POTSB_SPI_CS_N: length 69
  TOP w0.127: U18.11 156.66,84.02 155.45,82.8 149.48,82.8 144.27,77.6 125.7,77.6 121.51,73.41 108.46,73.41 104.9,69.85 104.9,68.96 104.39,68.45 R442.1 104.4,67.69 104.78,67.69 105.03,67.44 105.03,66.42 106.03,65.42 U63.36
POTSB_SWVSY: length 6.6
  TOP w0.305: R476.1 R477.1 118.62,64.53 118.62,62.1 118.29,61.77 U63.18
POTSB_SWVSZ: length 5.3
  TOP w0.305: R479.1 100.33,64.79 100.33,61.59 100.8,61.12 U63.44
PROC_SPI_CLK: length 2.7
  TOP w0.127: U12.3 160.84,91.75 161.54,92.46 R59.2
PROC_SPI_CS0_N: length 14
  TOP w0.127: U1.M1 164.12,98.95 160.91,95.75 160.91,92.58 160.44,92.11 U12.4
PROC_SPI_CS1_N: length 17.7
  TOP w0.127: U1.M2 163.7,103.63 163.7,100.08 159.96,96.33 159.96,93.03 159.25,92.33 157.1,92.33 156.26,91.49 U18.3
PROC_SPI_CS2_N: length 21.7
  TOP w0.127: U18.2 156.66,91.39 157.1,91.82 v1(159.89,91.82) ; U1.M3 v2(163.72,104.45)
  BOTTOM w0.127: v1(159.89,91.82) 161.29,93.22 161.29,93.98 162.56,95.25 164.46,95.25 164.72,95.5 164.72,96.27 164.21,96.77 164.21,100.46 164.97,101.22 164.97,103.75 164.68,104.04 164.12,104.04 v2(163.72,104.45)
PROC_SPI_CS3_N: length 20.9
  TOP w0.127: U1.N3 v2(164.52,104.45) ; v1(159.77,91.06) 157.61,91.06 157.36,90.82 U18.1
  BOTTOM w0.127: v2(164.52,104.45) 164.67,104.45 165.35,103.76 165.35,100.97 164.72,100.33 164.72,96.9 165.1,96.52 165.1,95.38 164.59,94.87 162.81,94.87 161.67,93.73 161.67,92.96 v1(159.77,91.06)
PROC_SPI_MISO: length 14.1
  TOP w0.127: U1.P1 165.72,98.74 162.56,95.59 162.56,92.33 161.64,91.4 U12.1
PROC_SPI_MOSI: length 15.1
  TOP w0.127: U12.2 161.24,91.51 162.18,92.46 162.18,95.76 165.35,98.93 165.35,103.76 165.64,104.05 U1.P2
PROC_UART1_CTS_N: length 12.1
  TOP w0.127: U1.Y2 170.53,104.05 170.94,103.63 170.94,101.98 171.9,101.02 171.9,98.75 170.81,97.66 170.81,95.89 171.8,94.9 U40.1
PROC_UART1_RTS_N: length 11.2
  TOP w0.127: U40.2 171.4,94.8 170.43,95.76 170.43,97.83 171.54,98.94 171.54,100.75 170.52,101.77 U1.Y1
PROC_UART1_RXD: length 14.4
  TOP w0.127: v1(172.34,93.85) 172.21,93.98 172.21,95 171.2,96.01 171.2,97.54 172.27,98.61 172.27,101.29 171.32,102.24 U1.AA1 ; U40.4 170.6,93.82 v1(170.05,94.36)
  BOTTOM w0.127: v1(170.05,94.36) 170.56,93.85 v1(172.34,93.85)
PROC_UART1_TXD: length 14.3
  TOP w0.127: U40.3 171,94.18 v1(170.81,94.36) ; U1.AA2 171.7,103.66 171.7,102.36 172.63,101.44 172.63,98.46 171.58,97.41 171.58,96.14 172.85,94.87 v1(172.85,94.36)
  BOTTOM w0.127: v1(170.81,94.36) v1(172.85,94.36)
PROC_UART2_CTS_N: length 16.9
  TOP w0.127: U1.Y4 v2(170.92,105.25) ; U42.1 167.22,93.94 v1(167.64,94.36)
  L3SIG w0.102: v1(167.64,94.36) 167.64,94.74 167.06,95.33 166.68,95.33 166.37,95.63 166.37,96.14 168.53,98.3 170.43,98.3 171.5,99.36 171.5,100.28 171.32,100.46 171.32,104.9 170.98,105.25 v2(170.92,105.25)
PROC_UART2_RTS_N: length 17.1
  TOP w0.127: v1(166.88,94.87) 166.82,94.81 U42.2 ; U1.V4 v2(169.32,105.25)
  L3SIG w0.102: v2(169.32,105.25) 169.33,105.25 169.7,104.88 169.7,100.35 169.54,100.2 169.54,99.31 169.29,99.06 168.27,99.06 165.35,96.14 165.35,94.62 165.61,94.36 166.37,94.36 v1(166.88,94.87)
PROC_UART2_RXD: length 15.5
  TOP w0.127: v1(165.86,94.87) 165.86,94.23 166.02,94.07 U42.4 ; U1.W4 v2(170.12,105.25)
  L3SIG w0.102: v2(170.12,105.25) 170.12,105.22 170.53,104.8 170.53,99.41 169.8,98.68 168.4,98.68 165.86,96.14 v1(165.86,94.87)
PROC_UART2_TXD: length 15.9
  TOP w0.127: U1.AA4 v2(171.72,105.25) ; U42.3 166.42,95.3 v1(166.88,95.76)
  L3SIG w0.102: v1(166.88,95.76) 169.04,97.92 170.56,97.92 172.08,99.44 172.08,104.28 172.1,104.29 172.1,104.89 171.74,105.25 v2(171.72,105.25)
PWR_EN_N: length 35.6
  TOP w0.127: J37.14 10.29,98.16 10.29,70.87 9.53,70.1 Q30.3 9.13,68.57 R710.1
PWR_GOOD: length 73.8
  TOP w0.127: v1(14.61,68.71) 14.35,68.96 C894.1 R712.2 R709.1 ; U65.C2 58.01,111.93 v1(57.51,111.43)
  L6SIG w0.102: v1(14.61,68.71) 16.13,68.71 19.18,71.76 25.91,71.76 27.18,73.03 27.18,75.44 29.84,78.11 32.89,78.11 38.48,83.69 38.48,90.04 42.01,93.57 45.44,93.57 50.67,98.81 50.67,105.89 56.21,111.43 v1(57.51,111.43)
PWR_RST_N: length 70.9
  TOP w0.127: v1(58.51,111.43) 59.01,111.93 U65.C3 ; U83.2 18.1,67.62 R708.2 18.55,68.59 v1(19.05,69.09)
  L6SIG w0.102: v1(58.51,111.43) 58.01,110.93 56.11,110.93 50.93,105.75 50.93,98.68 45.59,93.34 42.16,93.34 38.73,89.92 38.73,83.57 33.02,77.85 29.97,77.85 27.43,75.31 27.43,72.9 26.03,71.5 19.81,71.5 19.05,70.74 v1(19.05,69.09)
QSG1_INT_N: length 193.3
  TOP w0.127: U65.N2 58.01,101.93 v1(57.51,101.42) ; R291.2 221.87,70.99 R855.1 221.88,72.65 v1(222.12,72.9)
  L6SIG w0.102: v1(57.51,101.42) 56.72,101.42 56.01,100.71 56.01,96.39 66.93,85.47 66.93,83.31 68.07,82.17 68.07,77.72 70.74,75.06 74.93,75.06 76.2,73.79 92.71,73.79 93.47,73.03 135.13,73.03 136.27,71.88 158.37,71.88 160.02,73.53 181.61,73.53 182.37,72.77 185.42,72.77 188.09,70.1 198.2,70.1 199.04,70.94 211.23,70.94 212.93,72.64 221.87,72.64 v1(222.12,72.9)
QSG1_LED0: length 4.6
  TOP w0.127: U55.C3 216.8,63.68 217.74,62.74 R340.1
QSG1_LED1: length 3.8
  TOP w0.127: U55.B2 218.12,63.5 219.96,63.5 220.22,63.75 R342.1
QSG1_MDI0_N: length 24.9
  TOP w0.102: T5.3 213.43,39.19 213.84,39.6 214.05,39.6 214.15,39.7 214.15,40.34 213.6,40.89 212.34,40.89 211.33,41.91 211.33,53.72 210.31,54.74 210.31,57.53 210.59,57.81 210.59,59.56 210.69,59.65 210.69,60.02 U55.B17
QSG1_MDI0_P: length 24.8
  TOP w0.102: U55.B18 211.63,60.5 211.31,60.17 211.24,60.17 210.97,59.91 210.97,59.54 210.87,59.44 210.87,57.7 210.59,57.42 210.59,54.85 211.61,53.84 211.61,42.03 212.46,41.17 213.72,41.17 214.43,40.46 T5.2
QSG1_MDI1_N: length 25
  TOP w0.102: v1(209.65,53.59) 209.93,53.31 209.93,41.15 210.92,40.16 210.92,39.6 210.43,39.11 T5.6
  TOP w0.127: U55.C28 210.85,61.44 v2(211.1,61.7)
  L3SIG w0.102: v1(209.65,53.59) 209.93,53.87 209.93,59.44 210.82,60.32 210.82,61.1 211.1,61.38 v2(211.1,61.7)
QSG1_MDI1_P: length 25.1
  TOP w0.102: v1(210.49,53.59) 210.21,53.31 210.21,41.26 211.2,40.27 211.2,39.37 211.43,39.14 T5.5
  TOP w0.127: U55.C29 211.5,61.38 v2(211.81,61.7)
  L3SIG w0.102: v1(210.49,53.59) 210.21,53.87 210.21,59.32 211.1,60.21 211.1,60.99 v2(211.81,61.7)
QSG1_MDI2_N: length 22.8
  TOP w0.102: T5.9 207.43,39.16 207.87,39.6 207.87,40.38 208.79,41.29 208.79,54.24 209.4,54.85 209.4,58.01 209.71,58.32 209.71,59.72 209.87,59.88 U55.B15
QSG1_MDI2_P: length 22.9
  TOP w0.102: T5.8 208.43,39.09 208.15,39.37 208.15,40.26 209.07,41.17 209.07,54.13 209.68,54.74 209.68,57.9 209.98,58.21 209.98,59.6 210.15,59.77 210.15,60.13 U55.B16
QSG1_MDI3_N: length 25.2
  TOP w0.102: T5.12 204.43,39.08 205.08,39.73 205.08,40.49 205.74,41.15 206.88,41.15 207.9,42.16 207.9,54.62 208.51,55.23 208.51,58.52 208.79,58.8 208.79,59.94 209.04,60.2 209.04,60.59 209.55,61.1 U55.C26
QSG1_MDI3_P: length 25.3
  TOP w0.102: U55.C27 209.87,60.83 209.67,60.83 209.32,60.48 209.32,60.08 209.07,59.83 209.07,58.69 208.79,58.41 208.79,55.12 208.18,54.51 208.18,42.05 207,40.87 205.86,40.87 205.36,40.37 205.36,39.24 205.43,39.17 T5.11
QSG1_MDX0_N: length 12.4
  TOP w0.102: T5.22 213.43,28.88 213.79,28.52 213.79,25.98 216.38,23.39 216.38,20.2 216.79,19.8 216.79,18.68 J15.A2
QSG1_MDX0_P: length 12.3
  TOP w0.102: J15.A1 217.84,20.35 217.55,20.07 216.92,20.07 216.66,20.32 216.66,23.51 214.07,26.1 214.07,28.52 214.43,28.88 T5.23
QSG1_MDX1_N: length 13.5
  TOP w0.102: J15.A6 211.88,18.46 213.87,20.45 213.87,24.13 210.79,27.21 210.79,28.6 210.43,28.96 T5.19
QSG1_MDX1_P: length 13.6
  TOP w0.102: T5.20 211.43,28.93 211.07,28.57 211.07,27.32 214.15,24.25 214.15,19.91 214.38,19.69 215.26,19.69 215.52,19.94 215.52,20.77 J15.A3
QSG1_MDX2_N: length 15.4
  TOP w0.102: v1(211.45,22.47) 211.45,22.87 210.67,23.65 210.67,25.67 209.54,26.8 208.65,26.8 207.79,27.65 207.79,28.56 207.43,28.92 T5.16
  BOTTOM w0.102: v1(211.45,22.47) 211.84,22.47 212.12,22.2 213.24,22.2 213.84,21.6 213.84,20.44 213.36,19.95 212.84,19.95 212.6,20.19 212.6,20.84 J15.A5
QSG1_MDX2_P: length 15.5
  TOP w0.102: T5.17 208.43,28.98 208.07,28.62 208.07,27.77 208.76,27.08 209.65,27.08 210.95,25.78 210.95,23.76 211.64,23.07 v1(212.04,23.07)
  BOTTOM w0.102: v1(212.04,23.07) 212.04,22.67 212.23,22.48 213.36,22.48 214.12,21.72 214.12,20.32 213.49,19.69 213.49,18.99 J15.A4
QSG1_MDX3_N: length 13.8
  TOP w0.102: T5.13 204.43,29 204.79,28.63 204.79,23.67 205.47,22.99 206.76,22.99 208.51,21.23 208.51,20.32 209.3,19.53 209.3,18.81 J15.A8
QSG1_MDX3_P: length 13.9
  TOP w0.102: J15.A7 210.22,20.22 209.93,19.94 209.28,19.94 208.79,20.44 208.79,21.35 206.87,23.27 205.59,23.27 205.07,23.78 205.07,28.67 205.43,29.03 T5.14
QSG1_REFCLK_N: length 17.4
  TOP w0.102: U67.3 227.51,74.02 227.32,73.83 226.95,73.83 R548.2 226.31,74.23 226.31,74.04 226.09,73.81 222.1,73.81 219.43,76.48 214.87,76.48 214.25,75.86 C411.1
QSG1_REFCLK_P: length 17.5
  TOP w0.102: U67.4 227.5,73.37 227.31,73.55 226.96,73.55 R547.2 226.31,73.14 226.31,73.28 226.06,73.53 221.98,73.53 219.31,76.2 214.99,76.2 214.53,75.74 214.53,75.16 214.63,75.05 215,75.05 215.26,74.79 C410.1
QSG1_RST_N: length 200.1
  TOP w0.127: U65.M3 59.01,102.93 v1(58.51,102.42) ; v1(223.9,72.01) 223.9,68.45 223.4,67.95 R296.2 222.88,67.95 R292.1
  L6SIG w0.102: v1(58.51,102.42) 58.01,101.92 56.71,101.92 55.75,100.97 55.75,96.27 66.68,85.34 66.68,83.19 67.82,82.04 67.82,77.6 70.61,74.8 74.8,74.8 76.07,73.53 92.58,73.53 93.34,72.77 135,72.77 136.14,71.63 164.34,71.63 165.99,73.28 181.48,73.28 182.24,72.52 185.29,72.52 187.96,69.85 198.31,69.85 199.17,70.71 206.6,70.71 206.62,70.74 211.35,70.74 213,72.39 223.01,72.39 223.39,72.01 v1(223.9,72.01)
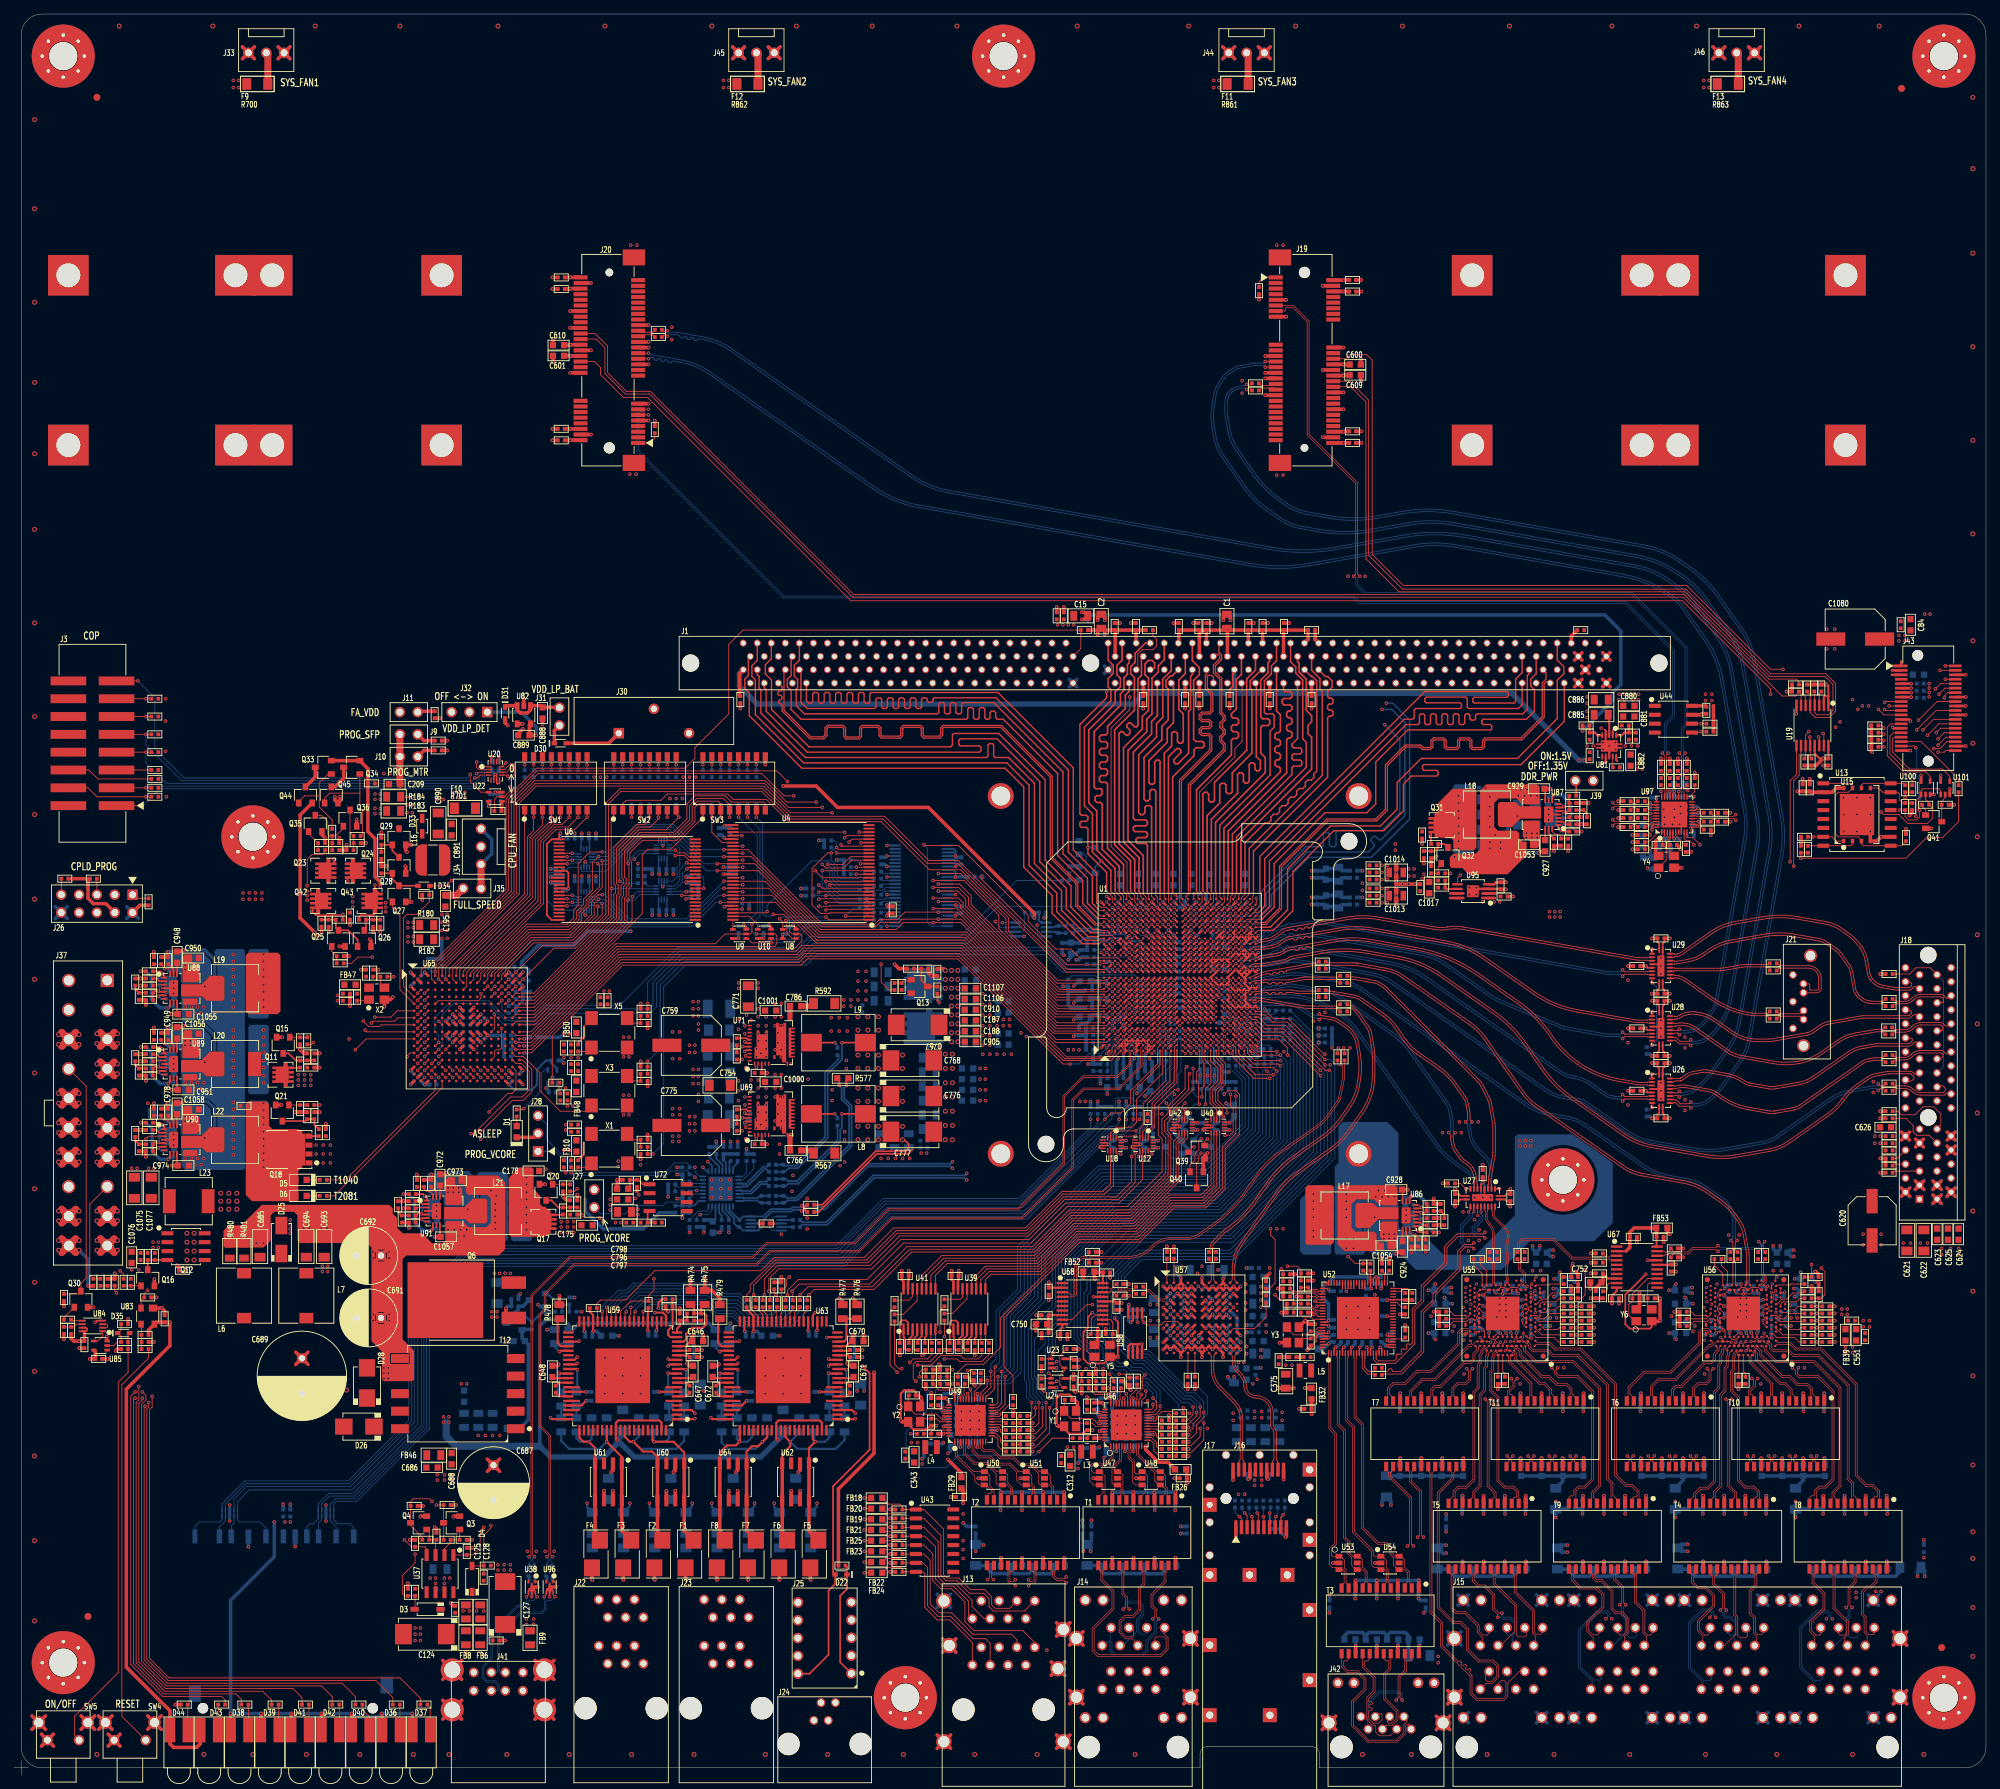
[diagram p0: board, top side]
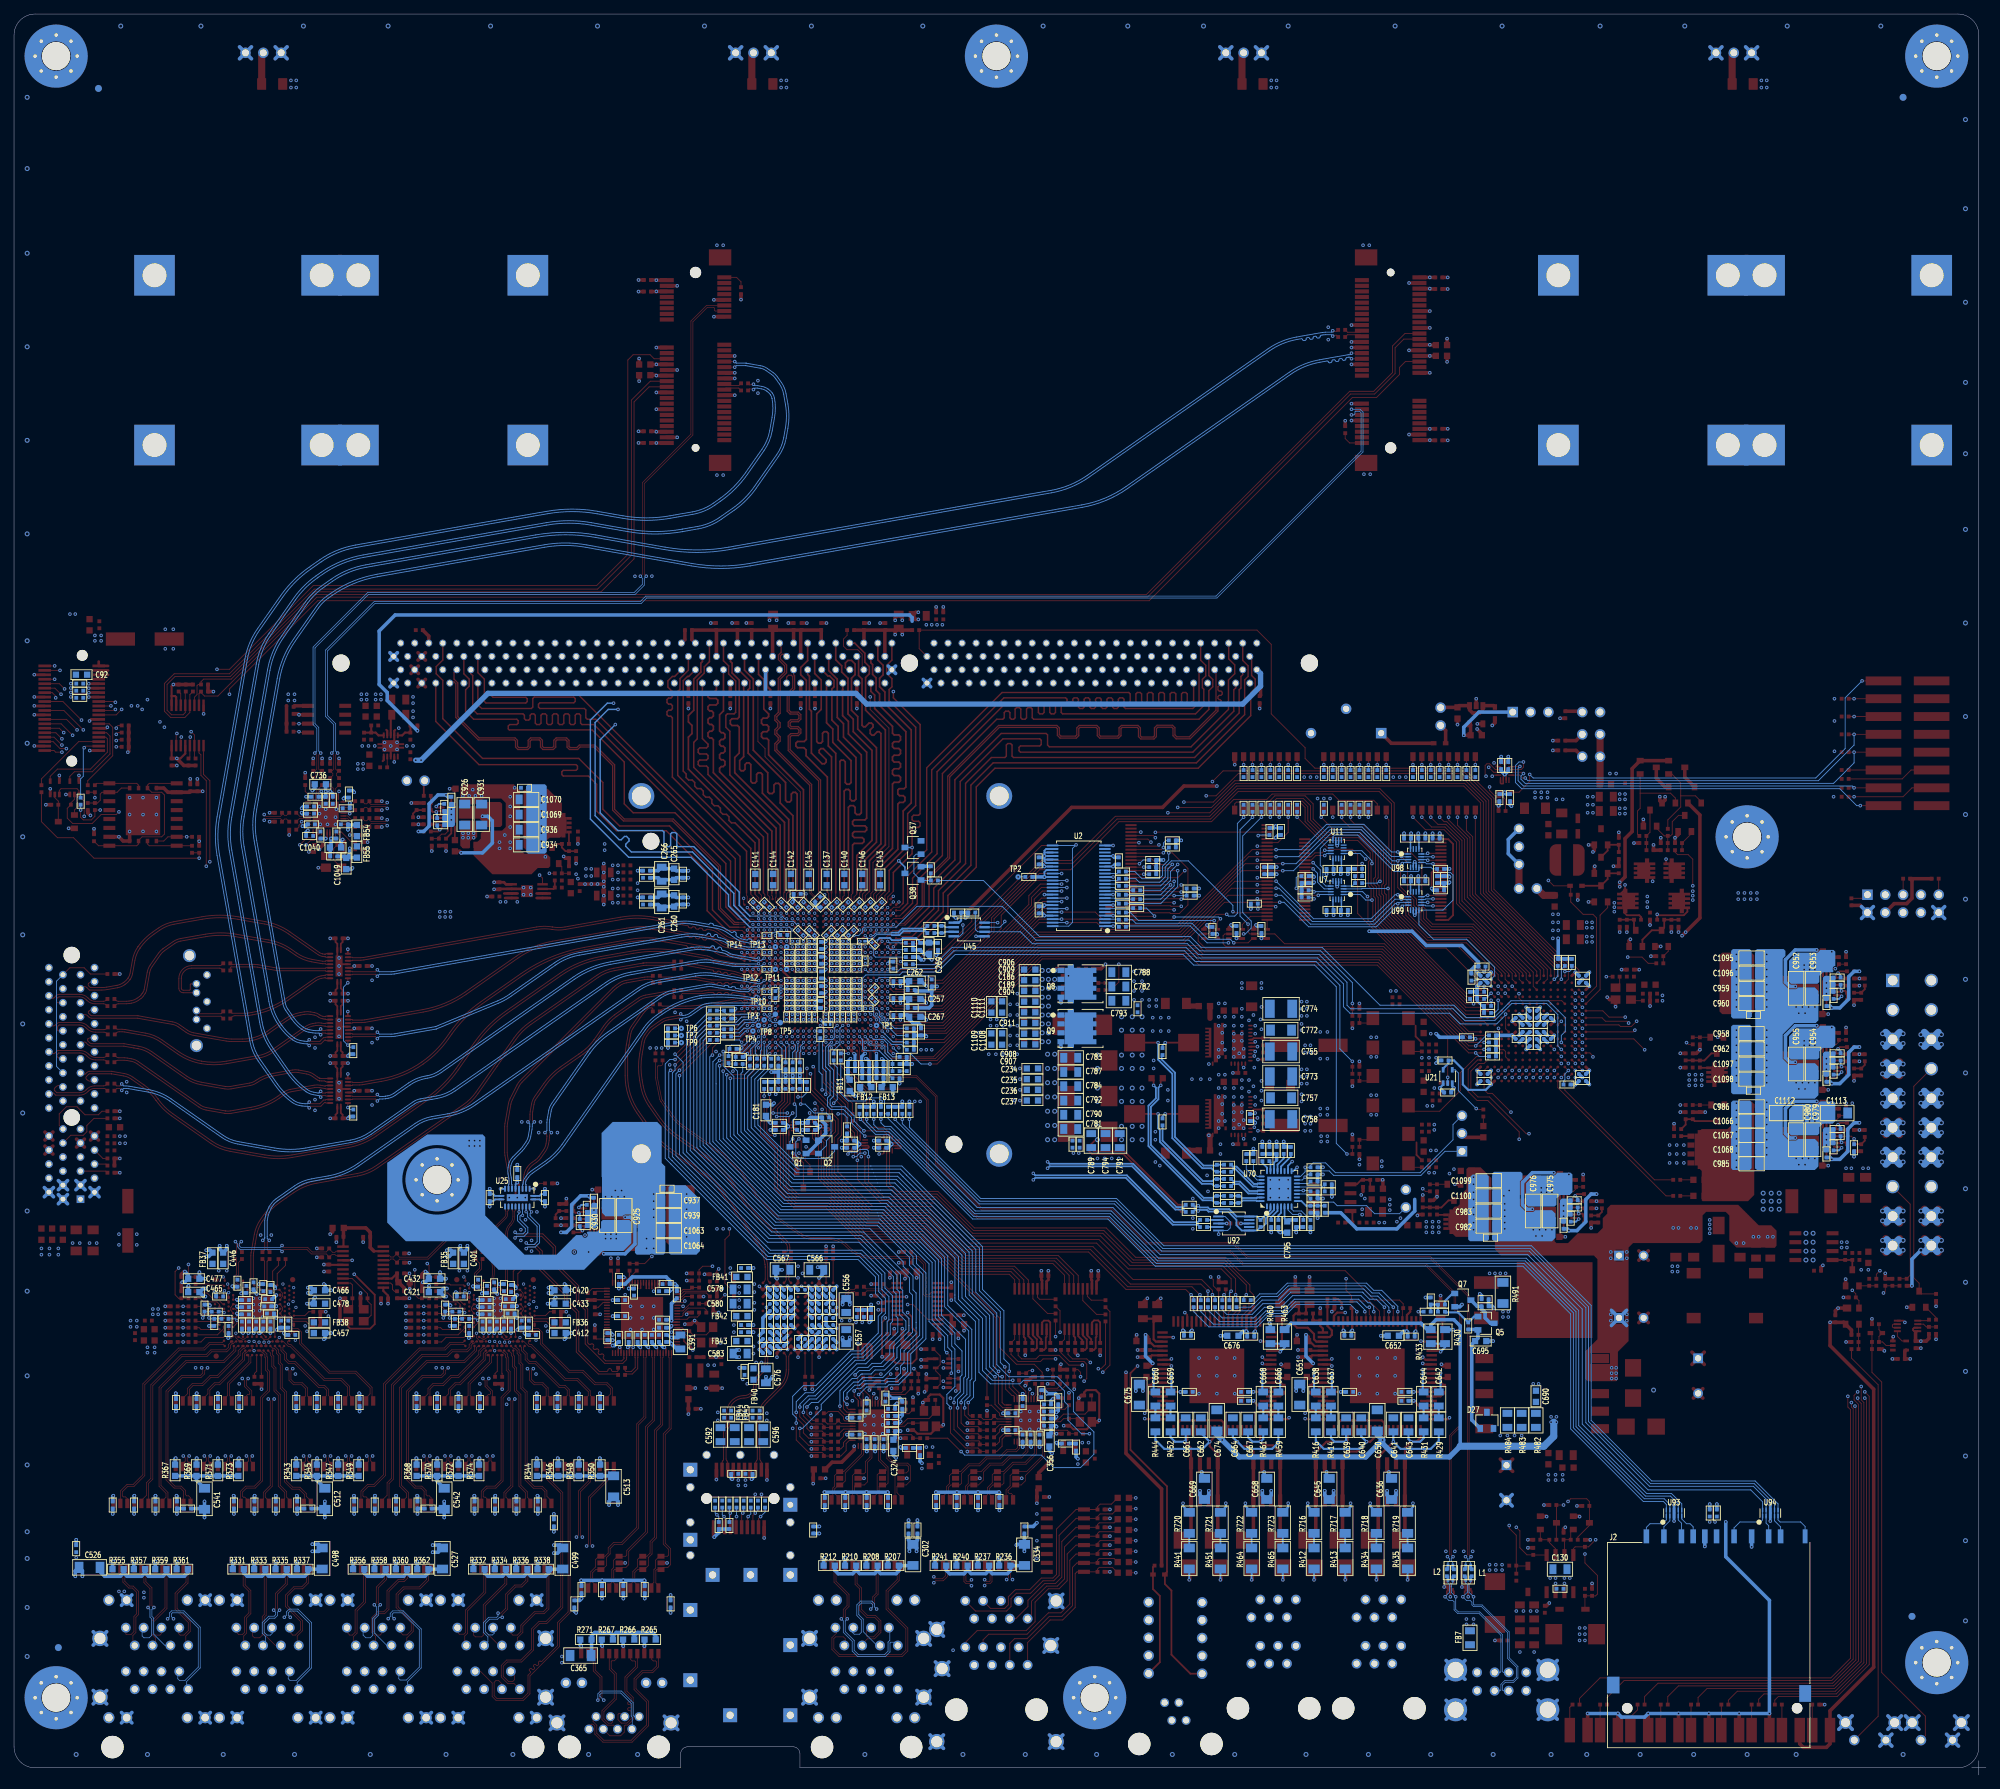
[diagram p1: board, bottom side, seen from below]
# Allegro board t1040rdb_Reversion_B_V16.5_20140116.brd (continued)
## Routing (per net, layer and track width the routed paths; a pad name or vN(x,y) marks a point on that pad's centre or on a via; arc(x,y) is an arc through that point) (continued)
QSG2_INT_N: length 224.3
  TOP w0.127: v1(256.16,72.77) 256.17,72.76 R856.1 256.16,70.99 R312.2 ; U65.P2 v1(57.51,100.42)
  L6SIG w0.102: v1(256.16,72.77) 255.74,73.19 236.64,73.19 235.97,72.52 225.93,72.52 224.79,73.66 221.49,73.66 220.98,73.15 212.79,73.15 211.04,71.4 193.13,71.4 192.34,70.61 188.34,70.61 185.67,73.28 182.64,73.28 181.88,74.04 159.77,74.04 158.11,72.39 136.52,72.39 135.38,73.53 93.73,73.53 92.96,74.3 76.45,74.3 75.18,75.57 71.76,75.57 69.34,77.98 69.34,82.55 67.44,84.45 67.44,85.73 58.01,95.15 58.01,99.92 v1(57.51,100.42)
QSG2_LED0: length 2.5
  TOP w0.127: v2(214.96,64.82) 214.96,64.39 U55.E2
  BOTTOM w0.127: R352.1 215.16,65.02 v2(214.96,64.82)
QSG2_LED1: length 5.2
  TOP w0.127: U55.D1 216.4,62.88 216.92,62.36 219.46,62.36 220.09,61.72 R354.1
QSG2_MDI0_N: length 12.9
  TOP w0.102: v1(207.01,57.91) 207.26,57.66 207.26,56.39 206.78,55.91 205.64,55.91 204.9,55.17 204.9,54.03 204.54,53.66 T7.3
  TOP w0.127: U55.D30 209.22,62.05 v2(208.91,62.36)
  L3SIG w0.102: v2(208.91,62.36) 209.17,62.36 209.3,62.23 209.3,61.98 208.91,61.59 208.91,60.71 207.29,59.08 207.29,58.19 v1(207.01,57.91)
QSG2_MDI0_P: length 12.9
  TOP w0.102: T7.2 205.54,53.67 205.18,54.03 205.18,55.05 205.75,55.63 206.9,55.63 207.54,56.27 207.54,57.6 v1(207.85,57.91)
  TOP w0.127: v2(210.41,61.7) 210.31,61.8 U55.D31
  L3SIG w0.102: v2(210.41,61.7) 210.41,61.7 210.27,61.85 209.56,61.85 209.19,61.48 209.19,60.59 207.57,58.97 207.57,58.19 v1(207.85,57.91)
QSG2_MDI1_N: length 11.7
  TOP w0.102: T7.6 201.54,53.71 201.9,54.07 201.9,54.96 202.46,55.52 203.23,55.52 206.63,58.93 207.5,58.93 207.9,59.32 207.9,60.09 208.41,60.59 208.41,60.99 U55.C24
QSG2_MDI1_P: length 11.7
  TOP w0.102: U55.C25 208.69,60.94 208.69,60.48 208.18,59.97 208.18,59.21 207.62,58.65 206.74,58.65 203.34,55.24 202.58,55.24 202.18,54.85 202.18,54.11 202.54,53.75 T7.5
QSG2_MDI2_N: length 13.7
  TOP w0.102: U55.C23 207.63,61.9 207.73,61.8 207.73,61.57 207.53,61.36 207.27,61.36 202.45,56.54 200.69,56.54 198.9,54.76 198.9,54.12 198.54,53.76 T7.9
QSG2_MDI2_P: length 13.8
  TOP w0.102: U55.D29 208.36,61.8 207.64,61.08 207.39,61.08 202.57,56.26 200.8,56.26 199.18,54.64 199.18,54.06 199.54,53.7 T7.8
QSG2_MDI3_N: length 18.3
  TOP w0.102: T7.12 195.71,53.48 195.71,55.13 196.48,55.91 198.15,55.91 199.92,57.68 201.85,57.68 205.74,61.57 205.74,63.12 206.27,63.65 207.11,63.65 207.49,63.27 U55.C21
QSG2_MDI3_P: length 18.3
  TOP w0.102: T7.11 196.54,53.78 195.99,54.33 195.99,55.02 196.6,55.63 198.26,55.63 200.04,57.4 201.97,57.4 206.02,61.45 206.02,63 206.39,63.37 207,63.37 207.06,63.3 207.14,63.2 207.17,63.12 207.17,62.96 207.49,62.63 U55.C22
QSG2_MDX0_N: length 39.7
  TOP w0.102: J15.B2 210.16,14.77 209.68,14.28 209.68,13.59 209.93,13.34 210.55,13.34 211.3,14.09 211.3,15.51 210.7,16.1 208.69,16.1 206.98,17.81 206.98,20.71 206.11,21.59 205.09,21.59 202.82,23.86 202.82,40.26 204.9,42.34 204.9,43.13 204.54,43.49 T7.22
QSG2_MDX0_P: length 39.7
  TOP w0.102: T7.23 205.54,43.49 205.18,43.13 205.18,42.23 203.1,40.14 203.1,23.98 205.21,21.87 206.22,21.87 207.26,20.83 207.26,17.92 208.8,16.38 210.82,16.38 211.58,15.62 211.58,14.2 211.58,13.97 210.67,13.06 209.78,13.06 J15.B1
QSG2_MDX1_N: length 45.9
  TOP w0.102: T7.19 201.54,43.31 201.78,43.08 201.78,23.13 203.3,21.6 203.3,18.3 207.49,14.11 207.49,11.57 208.42,10.64 212.33,10.64 212.88,11.19 212.88,13.11 214.54,14.77 J15.B6
QSG2_MDX1_P: length 45.8
  TOP w0.102: T7.20 202.54,43.54 202.06,43.05 202.06,23.24 203.58,21.72 203.58,18.41 205.81,16.19 205.95,16.19 206,16.24 206.14,16.24 206.28,16.09 206.28,15.95 206.24,15.9 206.24,15.76 206.4,15.6 206.54,15.6 206.72,15.77 206.86,15.77 207,15.63 207,15.48 206.83,15.31 206.83,15.17 206.99,15 207.14,15 207.31,15.18 207.45,15.18 207.6,15.03 207.6,14.89 207.42,14.72 207.42,14.57 207.77,14.22 207.77,11.68 208.53,10.92 212.22,10.92 212.6,11.3 212.6,13.21 212.34,13.46 211.96,13.46 211.49,12.98 J15.B3
QSG2_MDX2_N: length 39.9
  TOP w0.102: v1(200.02,33.91) 200.28,34.16 200.28,40.39 198.9,41.76 198.9,43.16 198.54,43.52 T7.16
  L3SIG w0.102: v1(200.02,33.91) 200.28,33.66 200.28,33.15 204.47,28.96 204.47,23.37 207.14,20.7 207.14,18.29 208.66,16.76 210.31,16.76 211.33,15.75 211.33,13.97 212.22,13.08 213.17,13.08 J15.B5
QSG2_MDX2_P: length 40
  TOP w0.102: v1(200.87,33.91) 200.56,34.22 200.56,40.5 199.18,41.88 199.18,43.22 199.54,43.58 T7.17
  L3SIG w0.102: v1(200.87,33.91) 200.56,33.6 200.56,33.26 204.75,29.07 204.75,23.48 207.42,20.82 207.42,18.4 208.78,17.04 210.43,17.04 211.61,15.86 211.61,14.09 212.33,13.36 213.13,13.36 213.36,13.59 213.36,14.16 J15.B4
QSG2_MDX3_N: length 53.2
  TOP w0.102: T7.13 195.54,43.47 195.9,43.11 195.9,42.46 198.86,39.51 198.86,32.92 v1(198.58,32.64)
  L3SIG w0.102: J15.B8 217.84,13.84 218.72,12.96 218.72,11.82 217.41,10.52 208.29,10.52 207.11,11.7 207.11,14.11 202.79,18.43 202.79,27.95 198.86,31.89 198.86,32.36 v1(198.58,32.64)
QSG2_MDX3_P: length 53.2
  TOP w0.102: T7.14 196.54,43.51 196.18,43.15 196.18,42.58 199.14,39.62 199.14,32.92 v1(199.42,32.64)
  L3SIG w0.102: J15.B7 216.57,13.11 216.92,13.46 217.82,13.46 218.44,12.84 218.44,11.94 217.3,10.79 208.41,10.79 207.39,11.81 207.39,14.22 203.07,18.54 203.07,28.07 199.14,32 199.14,32.36 v1(199.42,32.64)
QSG2_REFCLK_N: length 18.5
  TOP w0.102: 236.1,75 235.58,74.48 235.3,74.48 235.12,74.67 U67.19 ; 236.1,75 236.33,74.77 236.33,74.76 236.54,74.55 238.52,74.55 239.15,75.18 242.54,75.18 v1(242.82,75.46) ; 236.1,75 R546.2 ; C456.1 249.02,75.02 249.02,75.63 v1(248.63,76.03)
  BOTTOM w0.102: v1(248.63,76.03) 248.91,75.74 248.91,75.43 248.67,75.18 243.1,75.18 v1(242.82,75.46)
QSG2_REFCLK_P: length 18.7
  TOP w0.102: v1(242.82,74.62) 242.54,74.9 239.27,74.9 238.63,74.27 236.51,74.27 236.33,74.08 236.33,74.01 R545.2 235.69,74.2 235.3,74.2 235.12,74.02 U67.18 ; C455.1 249.3,74.8 249.3,75.86 v1(249.47,76.03)
  BOTTOM w0.102: v1(242.82,74.62) 243.1,74.9 248.78,74.9 249.19,75.31 249.19,75.74 v1(249.47,76.03)
QSG2_RST_N: length 231.6
  TOP w0.127: R313.1 256.16,67.95 R317.2 257.56,67.95 258.06,68.45 258.06,71.76 v1(257.56,72.26) ; U65.N3 v1(58.51,101.42)
  L6SIG w0.102: v1(58.51,101.42) 58.01,100.92 57.36,100.92 57.01,100.57 57.01,95.77 67.18,85.6 67.18,83.44 69.09,81.53 69.09,77.85 71.63,75.31 75.06,75.31 76.33,74.04 92.84,74.04 93.6,73.28 135.25,73.28 136.4,72.14 158.24,72.14 159.89,73.79 181.74,73.79 182.5,73.03 185.55,73.03 188.21,70.36 198.1,70.36 198.91,71.17 211.13,71.17 212.86,72.9 221.23,72.9 221.67,73.33 222.96,73.33 223.77,72.52 224.28,72.52 224.54,72.26 237.11,72.26 237.74,72.9 255.4,72.9 256.03,72.26 v1(257.56,72.26)
QSG3_LED0: length 3.9
  TOP w0.127: U55.B4 217.66,65.91 218.19,65.91 218.57,66.29 219.58,66.29 220.09,66.8 R364.1
QSG3_LED1: length 1.4
  TOP w0.102: v2(216.79,65.91) 216.8,65.92 U55.C6
  BOTTOM w0.127: v2(216.79,65.91) 216.92,66.04 R366.1
QSG3_MDI0_N: length 33.1
  TOP w0.102: U55.C36 216.89,61.34 218.82,61.34 219.58,60.58 223.15,60.58 228.09,55.64 228.09,42.67 229.62,41.15 230.5,41.15 231.3,40.36 231.3,39.78 231.16,39.64 230.84,39.64 230.58,39.38 T9.3
QSG3_MDI0_P: length 33
  TOP w0.102: T9.2 231.58,40.47 230.62,41.43 229.73,41.43 228.37,42.79 228.37,55.75 223.27,60.86 219.7,60.86 218.94,61.62 217.08,61.62 U55.C1
QSG3_MDI1_N: length 31.8
  TOP w0.102: U55.D34 215.18,61.8 215.51,61.47 215.64,61.47 215.65,61.47 215.87,61.25 215.87,60.86 216.41,60.32 218.55,60.32 219.21,59.66 222.78,59.66 226.95,55.5 226.95,42.16 227.58,41.54 T9.6
QSG3_MDI1_P: length 31.8
  TOP w0.102: T9.5 228.58,39.14 227.86,39.86 227.86,41.65 227.23,42.28 227.23,55.61 222.9,59.94 219.33,59.94 218.67,60.6 216.52,60.6 216.15,60.97 216.15,61.37 U55.D35
QSG3_MDI2_N: length 30.7
  TOP w0.102: U55.C34 214.87,61.15 215.12,60.91 215.12,60.46 216.8,58.78 222.15,58.78 225.78,55.14 225.78,41.26 224.79,40.27 224.79,39.37 224.58,39.16 T9.9
QSG3_MDI2_P: length 30.6
  TOP w0.102: T9.8 225.58,39.09 225.07,39.6 225.07,40.16 226.06,41.15 226.06,55.26 222.26,59.05 216.92,59.05 215.4,60.57 U55.C35
QSG3_MDI3_N: length 34.8
  TOP w0.102: T9.12 221.58,39.52 221.84,39.79 222.12,39.79 222.3,39.96 222.3,40.56 222.91,41.17 223.79,41.17 224.79,42.18 224.79,54.61 222.76,56.64 220.09,56.64 219.56,57.18 219.56,57.63 v1(219.15,58.04) ; v2(213.24,61.8) 213.26,61.8 213.26,61.8 U55.D32
  L3SIG w0.102: v2(213.24,61.8) 213.6,62.16 214.58,62.16 216.56,60.17 218.58,60.17 219.56,59.19 219.56,58.45 v1(219.15,58.04)
QSG3_MDI3_P: length 34.7
  TOP w0.102: v2(215.11,62.97) 215.11,62.33 214.58,61.8 U55.D33 ; T9.11 222.58,40.44 223.03,40.89 223.9,40.89 225.07,42.06 225.07,54.73 222.87,56.92 220.21,56.92 219.84,57.29 219.84,57.89 v1(219.99,58.04)
  L3SIG w0.102: v1(219.99,58.04) 219.84,58.19 219.84,59.31 218.69,60.45 216.68,60.45 214.76,62.37 214.76,62.74 214.99,62.97 v2(215.11,62.97)
QSG3_MDX0_N: length 11.9
  TOP w0.102: J15.C2 232.66,18.8 232.66,19.69 232.13,20.22 232.13,23.38 230.94,24.57 230.94,28.65 230.58,29.01 T9.22
QSG3_MDX0_P: length 11.8
  TOP w0.102: T9.23 231.58,29.01 231.22,28.65 231.22,24.69 232.41,23.49 232.41,20.33 232.81,19.94 233.17,19.94 233.59,20.35 J15.C1
QSG3_MDX1_N: length 13.3
  TOP w0.102: T9.19 227.58,28.96 227.94,28.6 227.94,27.84 229.11,26.67 229.11,24.54 v1(228.83,24.26)
  BOTTOM w0.102: J15.C6 227.88,18.46 229.62,20.19 229.62,22.23 229.11,22.73 229.11,23.98 v1(228.83,24.26)
QSG3_MDX1_P: length 13.3
  TOP w0.102: v1(229.67,24.26) 229.39,24.54 229.39,26.79 228.22,27.96 228.22,28.57 228.58,28.93 T9.20
  BOTTOM w0.102: J15.C3 231.27,20.77 231.27,19.94 230.89,19.56 230.25,19.56 229.9,19.91 229.9,22.34 229.39,22.85 229.39,23.98 v1(229.67,24.26)
QSG3_MDX2_N: length 14.3
  TOP w0.102: J15.C5 228.51,20.29 228.85,19.94 229.28,19.94 229.74,20.4 229.74,22.34 229.09,22.99 228.2,22.99 227.58,23.61 227.58,26.16 226.19,27.56 225.42,27.56 224.94,28.05 224.94,28.56 224.58,28.92 T9.16
QSG3_MDX2_P: length 14.4
  TOP w0.102: J15.C4 229.49,18.74 229.49,19.75 230.02,20.28 230.02,22.45 229.21,23.27 228.32,23.27 227.86,23.72 227.86,26.28 226.3,27.84 225.54,27.84 225.22,28.16 225.22,28.62 225.58,28.98 T9.17
QSG3_MDX3_N: length 15.6
  TOP w0.102: J15.C8 225.04,18.8 225.04,19.54 224.13,20.46 224.13,21.82 226.29,23.98 226.29,25.67 225.44,26.52 223.16,26.52 221.94,27.75 221.94,28.63 221.58,29 T9.13
QSG3_MDX3_P: length 15.6
  TOP w0.102: J15.C7 225.97,20.35 225.58,19.96 225.02,19.96 224.41,20.57 224.41,21.7 226.57,23.86 226.57,25.78 225.55,26.8 223.28,26.8 222.22,27.86 222.22,28.54 222.58,28.9 T9.14
QSG4_LED0: length 4.3
  TOP w0.127: U55.C5 216.8,65.14 217.3,64.64 220.73,64.64 R375.1
QSG4_LED1: length 5.2
  TOP w0.127: U55.D5 216.16,65.49 216.95,65.49 217.42,65.02 218.06,65.02 218.82,65.79 R376.1
QSG4_MDI0_N: length 12.9
  TOP w0.102: T11.3 221.69,53.87 221.74,53.93 221.74,54.98 221.22,55.5 219.84,55.5 218.69,56.64 217.66,56.64 214.5,59.8 214.5,60.35 214.03,60.82 213.89,60.82 213.56,61.15 U55.C32
QSG4_MDI0_P: length 12.8
  TOP w0.102: T11.2 222.69,53.67 222.02,54.33 222.02,55.09 221.34,55.78 219.95,55.78 218.81,56.92 217.78,56.92 214.78,59.92 214.78,60.46 U55.C33
QSG4_MDI1_N: length 10.1
  TOP w0.102: U55.B19 213.31,60.5 213.64,60.17 213.7,60.17 213.87,60.01 213.87,59.17 217.41,55.63 218.06,55.63 218.82,54.86 218.82,53.85 218.69,53.71 T11.6
QSG4_MDI1_P: length 10
  TOP w0.102: U55.B20 214.15,60.12 214.15,59.28 217.53,55.91 218.17,55.91 219.1,54.98 219.1,54.33 219.69,53.75 T11.5
QSG4_MDI2_N: length 8
  TOP w0.102: U55.A9 212.98,59.67 212.98,58.79 216.03,55.74 216.03,54.1 215.69,53.76 T11.9
QSG4_MDI2_P: length 8
  TOP w0.102: U55.A10 213.26,59.66 213.26,58.9 216.31,55.85 216.31,54.08 216.69,53.7 T11.8
QSG4_MDI3_N: length 11.2
  TOP w0.102: T11.12 212.69,53.81 212.85,53.98 212.85,54.75 213.61,55.51 213.61,56.26 v1(213.36,56.52)
  TOP w0.127: U55.C30 212.15,61.42 v2(212.52,61.8)
  L3SIG w0.102: v1(213.36,56.52) 213.64,56.8 213.64,57.89 211.71,59.82 211.71,60.99 212.06,61.34 212.42,61.34 212.52,61.44 v2(212.52,61.8)
QSG4_MDI3_P: length 11.2
  TOP w0.102: v1(214.2,56.52) 213.89,56.21 213.89,55.4 213.13,54.64 213.13,54.33 213.23,54.23 213.42,54.23 213.69,53.96 T11.11
  TOP w0.127: U55.C31 212.8,60.75 v2(212.52,60.48)
  L3SIG w0.102: v1(214.2,56.52) 213.92,56.8 213.92,58 211.99,59.93 211.99,60.87 212.18,61.06 212.42,61.06 212.52,60.96 v2(212.52,60.48)
QSG4_MDX0_N: length 46.4
  TOP w0.102: T11.22 221.69,44.41 222.05,44.77 222.05,45.19 v1(221.77,45.47)
  L3SIG w0.102: v1(221.77,45.47) 222.05,45.19 222.05,44.12 220.32,42.39 220.32,29.36 221.74,27.94 224.66,27.94 227.19,25.41 227.19,22.62 v1(226.85,22.28)
  BOTTOM w0.102: J15.D2 226.19,14.54 226.19,13.72 226,13.53 225.1,13.53 223.27,15.37 223.27,20.7 225.68,23.11 226.93,23.11 227.13,22.92 227.13,22.56 v1(226.85,22.28)
QSG4_MDX0_P: length 46.4
  TOP w0.102: T11.23 222.69,44.38 222.33,44.74 222.33,45.19 v1(222.61,45.47)
  L3SIG w0.102: v1(227.69,22.28) 227.47,22.5 227.47,25.53 224.78,28.22 221.86,28.22 220.6,29.48 220.6,42.28 222.33,44 222.33,45.19 v1(222.61,45.47)
  BOTTOM w0.102: v1(227.69,22.28) 227.41,22.56 227.41,23.03 227.05,23.39 225.56,23.39 222.99,20.82 222.99,15.25 224.92,13.32 224.92,12.45 J15.D1
QSG4_MDX1_N: length 52.2
  TOP w0.102: T11.19 218.69,44.41 219.05,44.77 219.05,45.19 v1(218.77,45.47)
  L3SIG w0.102: v1(218.77,45.47) 219.05,45.19 219.05,44.17 218.8,43.92 218.8,28.47 220.6,26.67 222.63,26.67 223.37,25.93 223.37,21.18 222.88,20.7 222.88,17.65 223.77,16.76 231.27,16.76 232.16,15.88 232.16,14.35 231.01,13.21 230.25,13.21 229.87,13.59 229.87,15.75 230.1,15.98 230.91,15.98 231.14,15.75 231.14,14.86 J15.D6
QSG4_MDX1_P: length 52.2
  TOP w0.102: v1(219.61,45.47) 219.33,45.19 219.33,44.74 219.69,44.38 T11.20
  L3SIG w0.102: v1(219.61,45.47) 219.33,45.2 219.33,44.05 219.07,43.8 219.07,28.59 220.71,26.95 222.75,26.95 223.65,26.05 223.65,21.07 223.16,20.59 223.16,17.77 223.89,17.04 231.38,17.04 232.44,15.99 232.44,14.24 230.89,12.69 230.89,11.81 230.25,11.18 228.29,11.18 J15.D3
QSG4_MDX2_N: length 42.9
  TOP w0.102: T11.16 215.69,44.41 216.05,44.77 216.05,45.19 v1(215.77,45.47)
  L3SIG w0.102: J15.D5 228.67,13.34 225.16,13.34 221.72,16.78 221.72,20.98 218.82,23.88 218.82,26.42 217.78,27.46 217.78,42.05 216.05,43.78 216.05,45.19 v1(215.77,45.47)
QSG4_MDX2_P: length 42.9
  TOP w0.102: v1(216.61,45.47) 216.33,45.19 216.33,44.74 216.69,44.38 T11.17
  L3SIG w0.102: v1(216.61,45.47) 216.33,45.19 216.33,43.9 218.06,42.16 218.06,27.57 219.1,26.53 219.1,23.99 222,21.1 222,16.89 225.27,13.61 229.01,13.61 229.23,13.84 229.23,14.35 228.82,14.77 J15.D4
QSG4_MDX3_N: length 58.5
  TOP w0.102: v1(212.77,45.47) 213.05,45.19 213.05,44.77 212.69,44.41 T11.13
  L3SIG w0.102: J15.D8 233.59,13.95 234.47,13.07 234.47,11.44 232.91,9.88 224.29,9.88 220.57,13.6 220.57,20.47 218.31,22.73 216.79,22.73 215.65,23.88 215.65,26.8 216.76,27.91 216.76,40.78 213.05,44.5 213.05,45.19 v1(212.77,45.47)
QSG4_MDX3_P: length 58.5
  TOP w0.102: v1(213.61,45.47) 213.33,45.19 213.33,44.74 213.69,44.38 T11.14
  L3SIG w0.102: J15.D7 232.32,13.11 232.66,13.46 233.68,13.46 234.19,12.95 234.19,11.56 232.79,10.16 224.41,10.16 220.85,13.72 220.85,20.59 218.43,23.01 216.9,23.01 215.93,23.99 215.93,26.68 217.04,27.8 217.04,40.89 213.33,44.61 213.33,45.19 v1(213.61,45.47)
QSG5_LED0: length 4.6
  TOP w0.127: U56.C3 251.09,63.68 252.03,62.74 R339.1
QSG5_LED1: length 3.8
  TOP w0.127: R341.1 254.63,63.75 254.38,63.5 252.86,63.5 252.18,64.18 U56.B2
QSG5_MDI0_N: length 24.9
  TOP w0.102: T4.3 247.72,39.19 248.13,39.6 248.34,39.6 248.44,39.7 248.44,40.34 247.89,40.89 246.63,40.89 245.62,41.91 245.62,53.72 244.6,54.74 244.6,57.53 244.88,57.81 244.88,59.56 244.98,59.65 244.98,60.02 U56.B17
QSG5_MDI0_P: length 24.8
  TOP w0.102: T4.2 248.72,40.46 248.01,41.17 246.75,41.17 245.9,42.03 245.9,53.84 244.88,54.85 244.88,57.42 245.16,57.7 245.16,59.44 245.26,59.54 245.26,59.91 245.53,60.17 245.6,60.17 245.92,60.5 U56.B18
QSG5_MDI1_N: length 25
  TOP w0.102: T4.6 244.72,39.11 245.21,39.6 245.21,40.16 244.22,41.15 244.22,53.31 v1(243.94,53.59)
  TOP w0.127: v2(245.39,61.7) 245.14,61.44 U56.C28
  L3SIG w0.102: v2(245.39,61.7) 245.39,61.38 245.11,61.1 245.11,60.32 244.22,59.44 244.22,53.87 v1(243.94,53.59)
QSG5_MDI1_P: length 25.1
  TOP w0.102: T4.5 245.72,39.14 245.49,39.37 245.49,40.27 244.5,41.26 244.5,53.31 v1(244.78,53.59)
  TOP w0.127: v2(246.1,61.7) 245.79,61.38 U56.C29
  L3SIG w0.102: v2(246.1,61.7) 245.39,60.99 245.39,60.21 244.5,59.32 244.5,53.87 v1(244.78,53.59)
QSG5_MDI2_N: length 22.8
  TOP w0.102: T4.9 241.72,39.16 242.16,39.6 242.16,40.38 243.08,41.29 243.08,54.24 243.69,54.85 243.69,58.01 244,58.32 244,59.72 244.16,59.88 U56.B15
QSG5_MDI2_P: length 22.9
  TOP w0.102: U56.B16 244.44,60.13 244.44,59.77 244.27,59.6 244.27,58.21 243.97,57.9 243.97,54.74 243.36,54.13 243.36,41.17 242.44,40.26 242.44,39.37 242.72,39.09 T4.8
QSG5_MDI3_N: length 25.2
  TOP w0.102: U56.C26 243.84,61.1 243.33,60.59 243.33,60.2 243.08,59.94 243.08,58.8 242.8,58.52 242.8,55.23 242.19,54.62 242.19,41.91 241.3,41.02 240.27,41.02 239.37,40.12 239.37,39.73 238.72,39.08 T4.12
QSG5_MDI3_P: length 25.2
  TOP w0.102: U56.C27 244.16,60.83 243.96,60.83 243.61,60.48 243.61,60.08 243.36,59.83 243.36,58.69 243.08,58.41 243.08,55.12 242.47,54.51 242.47,41.79 241.42,40.74 240.39,40.74 239.65,40 239.65,39.24 239.72,39.17 T4.11
QSG5_MDX0_N: length 11.9
  TOP w0.102: T4.22 247.72,29.01 248.08,28.65 248.08,27.1 247.27,26.29 247.27,22.99 247.9,22.35 247.9,20.19 248.28,19.81 248.28,18.67 J15.E2
QSG5_MDX0_P: length 11.9
  TOP w0.102: T4.23 248.72,29.01 248.36,28.65 248.36,26.99 247.55,26.17 247.55,23.1 248.18,22.47 248.18,20.31 248.48,20.01 248.99,20.01 249.34,20.36 J15.E1
QSG5_MDX1_N: length 12.6
  TOP w0.102: T4.19 244.72,28.96 245.08,28.6 245.08,22.76 245.36,22.48 245.36,20.07 243.75,18.46 J15.E6
QSG5_MDX1_P: length 12.6
  TOP w0.102: J15.E3 247.01,20.78 247.01,19.81 246.76,19.56 246,19.56 245.64,19.91 245.64,22.59 245.36,22.88 245.36,28.57 245.72,28.93 T4.20
QSG5_MDX2_N: length 13.5
  TOP w0.102: T4.16 241.72,28.54 241.82,28.44 241.98,28.44 242.08,28.33 242.08,27.16 243.46,25.78 243.46,23.78 v1(243.18,23.49)
  BOTTOM w0.102: J15.E5 244.22,20.96 244.22,20.19 244.47,19.94 244.98,19.94 245.36,20.32 245.36,21.59 244.6,22.35 243.84,22.35 243.46,22.73 243.46,23.21 v1(243.18,23.49)
QSG5_MDX2_P: length 13.5
  TOP w0.102: v1(244.02,23.49) 243.74,23.78 243.74,25.9 242.36,27.27 242.36,28.33 242.46,28.44 242.62,28.44 242.72,28.54 T4.17
  BOTTOM w0.102: J15.E4 245.18,18.8 245.18,19.74 245.64,20.2 245.64,21.71 244.72,22.63 243.96,22.63 243.74,22.85 243.74,23.21 v1(244.02,23.49)
QSG5_MDX3_N: length 14.2
  TOP w0.102: J15.E8 240.66,18.67 240.66,19.8 239.9,20.56 239.9,21.99 242.04,24.12 242.04,25.54 241.03,26.54 239.89,26.54 239.08,27.35 239.08,28.51 238.72,28.87 T4.13
QSG5_MDX3_P: length 14.3
  TOP w0.102: J15.E7 241.72,20.36 241.3,19.94 240.92,19.94 240.18,20.68 240.18,21.87 242.32,24 242.32,25.65 241.15,26.82 240,26.82 239.36,27.47 239.36,28.54 239.72,28.9 T4.14
QSG6_LED0: length 2.5
  TOP w0.127: U56.E2 249.25,64.39 v2(249.25,64.82)
  BOTTOM w0.127: R351.1 249.45,65.02 v2(249.25,64.82)
QSG6_LED1: length 5.2
  TOP w0.127: R353.1 254.38,61.72 253.75,62.36 251.21,62.36 250.69,62.88 U56.D1
QSG6_MDI0_N: length 12.9
  TOP w0.102: T6.3 238.83,53.66 239.19,54.03 239.19,55.17 239.93,55.91 241.07,55.91 241.55,56.39 241.55,57.66 v1(241.3,57.91)
  TOP w0.127: U56.D30 243.51,62.05 v2(243.2,62.36)
  L3SIG w0.102: v1(241.3,57.91) 241.58,58.19 241.58,59.08 243.2,60.71 243.2,61.59 243.59,61.98 243.59,62.23 243.46,62.36 v2(243.2,62.36)
QSG6_MDI0_P: length 12.9
  TOP w0.102: v1(242.14,57.91) 241.83,57.6 241.83,56.27 241.19,55.63 240.04,55.63 239.47,55.05 239.47,54.03 239.83,53.67 T6.2
  TOP w0.127: U56.D31 244.6,61.8 v2(244.7,61.7)
  L3SIG w0.102: v1(242.14,57.91) 241.86,58.19 241.86,58.97 243.48,60.59 243.48,61.48 243.85,61.85 244.56,61.85 244.7,61.7 v2(244.7,61.7)
QSG6_MDI1_N: length 11.7
  TOP w0.102: T6.6 235.83,53.71 236.19,54.07 236.19,54.96 236.75,55.52 237.52,55.52 240.92,58.93 241.79,58.93 242.19,59.32 242.19,60.09 242.7,60.59 242.7,60.99 U56.C24
QSG6_MDI1_P: length 11.7
  TOP w0.102: T6.5 236.83,53.75 236.47,54.11 236.47,54.85 236.87,55.24 237.63,55.24 241.03,58.65 241.91,58.65 242.47,59.21 242.47,59.97 242.98,60.48 242.98,60.94 U56.C25
QSG6_MDI2_N: length 14.1
  TOP w0.102: T6.9 232.83,53.76 233.19,54.12 233.19,55.39 234.34,56.54 236.74,56.54 241.56,61.36 241.82,61.36 242.02,61.57 242.02,61.8 241.92,61.9 U56.C23
QSG6_MDI2_P: length 14.2
  TOP w0.102: U56.D29 242.65,61.8 241.93,61.08 241.68,61.08 236.86,56.26 234.46,56.26 233.47,55.28 233.47,54.06 233.83,53.7 T6.8
QSG6_MDI3_N: length 18.4
  TOP w0.102: T6.12 230,53.48 230,55.26 232.29,57.56 236.02,57.56 240.03,61.57 240.03,63.12 240.56,63.65 241.4,63.65 241.78,63.27 U56.C21
QSG6_MDI3_P: length 18.4
  TOP w0.102: T6.11 230.83,53.78 230.28,54.33 230.28,55.14 232.41,57.28 236.13,57.28 240.31,61.45 240.31,63 240.68,63.37 241.29,63.37 241.35,63.3 241.43,63.2 241.46,63.12 241.46,62.96 241.78,62.63 U56.C22
QSG6_MDX0_N: length 43.6
  TOP w0.102: T6.22 238.83,44.41 239.19,44.77 239.19,45.19 v1(238.91,45.47)
  L3SIG w0.102: v1(241.65,22.48) 241.94,22.76 241.94,25.65 237.36,30.23 237.36,42.16 239.19,43.99 239.19,45.19 v1(238.91,45.47)
  BOTTOM w0.102: v1(241.65,22.48) 241.94,22.76 241.94,23.11 241.68,23.37 240.66,23.37 238.89,21.59 238.89,15.38 240.81,13.46 241.68,13.46 241.94,13.72 241.94,14.55 J15.F2
QSG6_MDX0_P: length 43.5
  TOP w0.102: T6.23 239.83,44.38 239.47,44.74 239.47,45.19 v1(239.75,45.47)
  L3SIG w0.102: v1(239.75,45.47) 239.47,45.19 239.47,43.88 237.64,42.05 237.64,30.34 242.21,25.77 242.21,22.76 v1(242.5,22.48)
  BOTTOM w0.102: v1(242.5,22.48) 242.21,22.76 242.21,23.23 241.8,23.65 240.55,23.65 238.61,21.71 238.61,15.27 240.66,13.21 240.66,12.44 J15.F1
QSG6_MDX1_N: length 50.8
  TOP w0.102: T6.19 235.83,44.41 236.19,44.77 236.19,45.19 v1(235.91,45.47)
  L3SIG w0.102: v1(235.91,45.47) 236.19,45.19 236.19,44.68 235.81,44.3 235.81,29.24 239.14,25.91 239.14,20.83 238.61,20.29 238.61,17.41 239.41,16.61 247.28,16.61 247.9,15.99 247.9,14.24 246.87,13.21 245.87,13.21 245.62,13.46 245.62,15.75 245.75,15.88 246.76,15.88 246.89,15.75 246.89,14.86 J15.F6
QSG6_MDX1_P: length 50.8
  TOP w0.102: T6.20 236.83,44.38 236.47,44.74 236.47,45.19 v1(236.75,45.47)
  L3SIG w0.102: J15.F3 244.04,11.18 246.13,11.18 246.76,11.81 246.76,12.7 248.18,14.12 248.18,16.1 247.4,16.89 239.52,16.89 238.89,17.53 238.89,20.18 239.42,20.71 239.42,26.02 236.09,29.35 236.09,44.18 236.47,44.56 236.47,45.19 v1(236.75,45.47)
QSG6_MDX2_N: length 42.7
  TOP w0.102: v1(232.91,45.47) 233.19,45.19 233.19,44.77 232.83,44.41 T6.16
  L3SIG w0.102: v1(232.91,45.47) 233.19,45.19 233.19,43.53 234.8,41.92 234.8,26.9 234.57,26.67 234.57,24 237.21,21.36 237.21,16.65 240.52,13.34 244.42,13.34 J15.F5
QSG6_MDX2_P: length 42.7
  TOP w0.102: v1(233.75,45.47) 233.47,45.19 233.47,44.74 233.83,44.38 T6.17
  L3SIG w0.102: v1(233.75,45.47) 233.47,45.19 233.47,43.64 235.08,42.04 235.08,26.78 234.85,26.55 234.85,24.12 237.49,21.48 237.49,16.76 240.64,13.61 244.84,13.61 244.98,13.75 244.98,14.22 244.44,14.77 J15.F4
QSG6_MDX3_N: length 58.2
  TOP w0.102: T6.13 229.83,44.41 230.19,44.77 230.19,45.19 v1(229.91,45.47)
  L3SIG w0.102: J15.F8 249.17,14.6 249.17,14.1 250.09,13.18 250.09,11.57 248.4,9.88 240.42,9.88 235.81,14.49 235.81,21.09 234.05,22.86 232.79,22.86 231.65,24 231.65,26.18 233.78,28.31 233.78,41.03 230.19,44.62 230.19,45.19 v1(229.91,45.47)
QSG6_MDX3_P: length 58.1
  TOP w0.102: T6.14 230.83,44.38 230.47,44.74 230.47,45.19 v1(230.75,45.47)
  L3SIG w0.102: v1(230.75,45.47) 230.47,45.19 230.47,44.74 234.06,41.15 234.06,28.19 231.93,26.06 231.93,24.12 232.91,23.14 234.16,23.14 236.09,21.21 236.09,14.61 240.54,10.16 248.28,10.16 249.81,11.68 249.81,13.07 249.29,13.59 248.67,13.59 248.07,12.99 J15.F7
QSG7_LED0: length 3.9
  TOP w0.127: U56.B4 251.95,65.91 252.6,65.91 252.98,66.29 253.75,66.29 254.25,66.8 R363.1
QSG7_LED1: length 1.4
  TOP w0.102: v2(251.08,65.91) 251.09,65.92 U56.C6
  BOTTOM w0.127: v2(251.08,65.91) 251.21,66.04 R365.1
QSG7_MDI0_N: length 33.1
  TOP w0.102: U56.C36 251.18,61.34 253.11,61.34 253.87,60.58 257.44,60.58 262.38,55.64 262.38,42.67 263.91,41.15 264.8,41.15 265.59,40.36 265.59,39.78 265.45,39.64 265.13,39.64 264.87,39.38 T8.3
QSG7_MDI0_P: length 33
  TOP w0.102: T8.2 265.87,40.47 264.91,41.43 264.02,41.43 262.66,42.79 262.66,55.75 257.56,60.86 253.99,60.86 253.23,61.62 251.37,61.62 U56.C1
QSG7_MDI1_N: length 31.8
  TOP w0.102: U56.D34 249.47,61.8 249.8,61.47 249.93,61.47 249.94,61.47 250.16,61.25 250.16,60.86 250.7,60.32 252.84,60.32 253.5,59.66 257.07,59.66 261.24,55.5 261.24,42.16 261.87,41.54 T8.6
QSG7_MDI1_P: length 31.8
  TOP w0.102: U56.D35 250.44,61.37 250.44,60.97 250.81,60.6 252.96,60.6 253.62,59.94 257.19,59.94 261.52,55.61 261.52,42.28 262.15,41.65 262.15,39.86 262.87,39.14 T8.5
QSG7_MDI2_N: length 30.7
  TOP w0.102: U56.C34 249.16,61.15 249.41,60.91 249.41,60.46 251.09,58.78 256.44,58.78 260.07,55.14 260.07,41.26 259.08,40.27 259.08,39.37 258.87,39.16 T8.9
QSG7_MDI2_P: length 30.6
  TOP w0.102: U56.C35 249.69,60.57 251.21,59.05 256.55,59.05 260.35,55.26 260.35,41.15 259.36,40.16 259.36,39.6 259.87,39.09 T8.8
QSG7_MDI3_N: length 34.8
  TOP w0.102: v2(247.53,61.8) 247.55,61.8 247.55,61.8 U56.D32 ; v1(253.44,58.04) 253.85,57.63 253.85,57.18 254.38,56.64 257.05,56.64 259.08,54.61 259.08,42.18 258.08,41.17 257.2,41.17 256.59,40.56 256.59,39.96 256.41,39.79 256.13,39.79 255.87,39.52 T8.12
  L3SIG w0.102: v2(247.53,61.8) 247.89,62.16 248.87,62.16 250.85,60.17 252.87,60.17 253.85,59.19 253.85,58.45 v1(253.44,58.04)
QSG7_MDI3_P: length 34.7
  TOP w0.102: v1(254.28,58.04) 254.13,57.89 254.13,57.29 254.5,56.92 257.16,56.92 259.36,54.73 259.36,42.06 258.19,40.89 257.32,40.89 256.87,40.44 T8.11 ; U56.D33 248.87,61.8 249.4,62.33 v2(249.4,62.97)
  L3SIG w0.102: v2(249.4,62.97) 249.28,62.97 249.05,62.74 249.05,62.37 250.97,60.45 252.98,60.45 254.13,59.31 254.13,58.19 v1(254.28,58.04)
QSG7_MDX0_N: length 12.6
  TOP w0.102: T8.22 264.87,28.88 265.23,28.52 265.23,27.61 264.54,26.92 264.03,26.92 263.27,26.16 263.27,22.86 263.65,22.48 263.65,20.31 264.08,19.88 264.08,18.72 J15.G2
QSG7_MDX0_P: length 12.6
  TOP w0.102: T8.23 265.87,28.88 265.51,28.52 265.51,27.49 264.66,26.64 264.15,26.64 263.55,26.05 263.55,22.98 263.93,22.59 263.93,20.42 264.34,20.01 264.99,20.01 265.09,20.1 J15.G1
QSG7_MDX1_N: length 13.2
  TOP w0.102: v1(261.09,23.88) 261.37,24.16 261.37,26.68 262.23,27.54 262.23,28.6 261.87,28.96 T8.19
  BOTTOM w0.102: J15.G6 259.5,18.46 261.11,20.07 261.11,22.35 261.37,22.61 261.37,23.6 v1(261.09,23.88)
QSG7_MDX1_P: length 13.2
  TOP w0.102: v1(261.93,23.88) 261.65,24.16 261.65,26.57 262.51,27.43 262.51,28.57 262.87,28.93 T8.20
  BOTTOM w0.102: J15.G3 262.76,20.78 262.76,19.81 262.51,19.56 261.75,19.56 261.39,19.91 261.39,22.24 261.65,22.49 261.65,23.6 v1(261.93,23.88)
QSG7_MDX2_N: length 12.2
  TOP w0.102: J15.G5 260.01,20.16 260.22,19.94 260.86,19.94 261.11,20.19 261.11,21.83 259.23,23.72 259.23,28.56 258.87,28.92 T8.16
QSG7_MDX2_P: length 12.2
  TOP w0.102: J15.G4 260.86,18.87 260.86,19.54 261.39,20.08 261.39,21.95 259.51,23.83 259.51,28.62 259.87,28.98 T8.17
QSG7_MDX3_N: length 12.9
  TOP w0.102: J15.G8 256.54,18.8 256.54,19.81 255.91,20.45 255.91,21.86 257.78,23.74 257.78,25.79 256.23,27.35 256.23,28.63 255.87,29 T8.13
QSG7_MDX3_P: length 13
  TOP w0.102: T8.14 256.87,28.9 256.51,28.54 256.51,27.47 258.06,25.91 258.06,23.62 256.18,21.74 256.18,20.56 256.81,19.94 257.34,19.94 257.56,20.16 257.56,20.91 J15.G7
QSG8_LED0: length 4.3
  TOP w0.127: R377.1 255.02,64.64 251.59,64.64 251.09,65.14 U56.C5
QSG8_LED1: length 5.2
  TOP w0.127: R378.1 252.98,65.79 252.22,65.02 251.71,65.02 251.24,65.49 250.45,65.49 U56.D5
QSG8_MDI0_N: length 12.9
  TOP w0.102: U56.C32 247.85,61.15 248.18,60.82 248.32,60.82 248.79,60.35 248.79,59.8 251.95,56.64 252.98,56.64 254.13,55.5 255.51,55.5 256.03,54.98 256.03,53.93 255.98,53.87 T10.3
QSG8_MDI0_P: length 12.8
  TOP w0.102: T10.2 256.98,53.67 256.31,54.33 256.31,55.09 255.63,55.78 254.24,55.78 253.1,56.92 252.07,56.92 249.07,59.92 249.07,60.46 U56.C33
QSG8_MDI1_N: length 10.1
  TOP w0.102: U56.B19 247.6,60.5 247.93,60.17 247.99,60.17 248.16,60.01 248.16,59.17 251.7,55.63 252.35,55.63 253.11,54.86 253.11,53.85 252.98,53.71 T10.6
QSG8_MDI1_P: length 10
  TOP w0.102: U56.B20 248.44,60.12 248.44,59.28 251.82,55.91 252.46,55.91 253.39,54.98 253.39,54.33 253.98,53.75 T10.5
QSG8_MDI2_N: length 8
  TOP w0.102: U56.A9 247.27,59.67 247.27,58.79 250.32,55.74 250.32,54.1 249.98,53.76 T10.9
QSG8_MDI2_P: length 8
  TOP w0.102: T10.8 250.98,53.7 250.6,54.08 250.6,55.85 247.55,58.9 247.55,59.66 U56.A10
QSG8_MDI3_N: length 11.2
  TOP w0.102: v1(247.65,56.52) 247.9,56.26 247.9,55.51 247.14,54.75 247.14,53.98 246.98,53.81 T10.12
  TOP w0.127: v2(246.81,61.8) 246.44,61.42 U56.C30
  L3SIG w0.102: v2(246.81,61.8) 246.81,61.44 246.71,61.34 246.35,61.34 246,60.99 246,59.82 247.93,57.89 247.93,56.8 v1(247.65,56.52)
QSG8_MDI3_P: length 11.2
  TOP w0.102: v1(248.49,56.52) 248.18,56.21 248.18,55.4 247.42,54.64 247.42,54.33 247.52,54.23 247.71,54.23 247.98,53.96 T10.11
  TOP w0.127: v2(246.81,60.48) 247.09,60.75 U56.C31
  L3SIG w0.102: v1(248.49,56.52) 248.21,56.8 248.21,58 246.28,59.93 246.28,60.87 246.47,61.06 246.71,61.06 246.81,60.96 v2(246.81,60.48)
QSG8_MDX0_N: length 44
  TOP w0.102: T10.22 255.98,44.41 256.34,44.77 256.34,45.19 v1(256.06,45.47)
  L3SIG w0.102: v1(256.06,45.47) 256.34,45.19 256.34,44.63 254.63,42.93 254.63,30.86 258.95,26.54 258.95,23.75 258.57,23.37 258.57,22.54 v1(258.29,22.26)
  BOTTOM w0.102: v1(258.29,22.26) 258.57,22.54 258.57,22.99 258.44,23.11 256.92,23.11 254.76,20.95 254.76,15.37 256.66,13.47 257.44,13.47 257.68,13.72 257.68,14.55 J15.H2
QSG8_MDX0_P: length 44
  TOP w0.102: v1(256.9,45.47) 256.62,45.19 256.62,44.74 256.98,44.38 T10.23
  L3SIG w0.102: v1(256.9,45.47) 256.62,45.19 256.62,44.51 254.91,42.81 254.91,30.98 259.23,26.66 259.23,23.63 258.85,23.25 258.85,22.54 v1(259.13,22.26)
  BOTTOM w0.102: v1(259.13,22.26) 258.85,22.54 258.85,23.1 258.56,23.39 256.81,23.39 254.48,21.07 254.48,15.25 256.41,13.32 256.41,12.44 J15.H1
QSG8_MDX1_N: length 52
  TOP w0.102: v1(253.06,45.47) 253.34,45.19 253.34,44.77 252.98,44.41 T10.19
  L3SIG w0.102: J15.H6 262.76,14.98 262.76,15.77 262.53,16 261.72,16 261.49,15.77 261.49,13.72 261.87,13.34 262.75,13.34 263.65,14.24 263.65,16.24 263.13,16.76 255.52,16.76 254.63,17.65 254.63,21.21 257.66,24.23 257.66,25.93 252.96,30.63 252.96,44.17 253.34,44.55 253.34,45.19 v1(253.06,45.47)
QSG8_MDX1_P: length 52.1
  TOP w0.102: T10.20 253.98,44.38 253.62,44.74 253.62,45.19 v1(253.9,45.47)
  L3SIG w0.102: J15.H3 259.79,11.18 261.75,11.18 262.51,11.94 262.51,12.7 263.93,14.12 263.93,16.36 263.25,17.04 255.64,17.04 254.91,17.77 254.91,21.09 257.94,24.12 257.94,26.05 253.24,30.75 253.24,44.05 253.62,44.43 253.62,45.19 v1(253.9,45.47)
QSG8_MDX2_N: length 43.5
  TOP w0.102: v1(250.06,45.47) 250.34,45.19 250.34,44.77 249.98,44.41 T10.16
  L3SIG w0.102: v1(250.06,45.47) 250.34,45.19 250.34,43.65 251.94,42.05 251.94,29.62 254.89,26.67 254.89,23.62 253.36,22.1 253.36,15.99 256.02,13.34 260.35,13.34 261.28,12.41 J15.H5
QSG8_MDX2_P: length 43.4
  TOP w0.102: v1(250.9,45.47) 250.62,45.19 250.62,44.74 250.98,44.38 T10.17
  L3SIG w0.102: v1(250.9,45.47) 250.62,45.19 250.62,43.77 252.22,42.16 252.22,29.73 255.17,26.79 255.17,23.51 253.64,21.98 253.64,16.1 256.13,13.61 260.5,13.61 260.72,13.83 260.72,14.36 260.32,14.77 J15.H4
QSG8_MDX3_N: length 55.6
  TOP w0.102: T10.13 246.98,44.41 247.34,44.77 247.34,45.19 v1(247.06,45.47)
  L3SIG w0.102: v1(247.06,45.47) 247.34,45.19 247.34,44.62 250.8,41.16 250.8,27.17 250.32,26.68 250.32,23.49 251.97,21.84 251.97,13.57 255.64,9.91 264.17,9.91 265.56,11.29 265.56,13.35 264.92,13.98 264.92,14.6 J15.H8
QSG8_MDX3_P: length 55.5
  TOP w0.102: v1(247.9,45.47) 247.62,45.19 247.62,44.74 247.98,44.38 T10.14
  L3SIG w0.102: J15.H7 263.82,13.12 264.29,13.59 264.92,13.59 265.28,13.23 265.28,11.4 264.06,10.19 255.75,10.19 252.25,13.69 252.25,21.96 250.6,23.61 250.6,26.57 251.08,27.05 251.08,41.27 247.62,44.74 247.62,45.19 v1(247.9,45.47)
QSGMII1_RX_N: length 12.2
  TOP w0.102: U27.19 211.05,80.57 arc(211.03,80.5) 210.99,80.44 210.98,80.43 arc(210.94,80.37) 210.92,80.3 210.92,79.97 arc(210.97,79.72) 211.12,79.51 212.57,78.05 arc(212.95,77.49) 213.08,76.82 arc(213.08,76.78) 213.07,76.73 212.91,75.83 arc(212.85,75.12) 212.91,74.41 212.92,74.37 arc(212.98,73.7) 212.92,73.03 212.92,73 arc(212.82,71.91) 212.91,70.83 arc(212.91,70.82) 212.92,70.81 arc(212.92,70.76) 212.92,70.72 arc(212.92,70.71) 212.92,70.71 212.92,70.13 arc(212.95,70.01) 213.02,69.91 U55.D13
QSGMII1_RX_P: length 12.2
  TOP w0.102: U55.D14 212.58,69.91 arc(212.65,70.01) 212.67,70.13 212.67,70.71 arc(212.67,70.71) 212.67,70.72 212.66,70.76 212.66,70.78 arc(212.57,71.91) 212.67,73.05 212.67,73.08 arc(212.73,73.7) 212.67,74.33 212.66,74.37 arc(212.6,75.12) 212.66,75.88 212.82,76.78 arc(212.83,76.8) 212.83,76.82 212.83,76.82 arc(212.71,77.39) 212.39,77.87 210.94,79.33 arc(210.74,79.63) 210.67,79.97 210.67,80.3 arc(210.65,80.37) 210.61,80.43 210.6,80.44 arc(210.56,80.5) 210.55,80.57 U27.18
QSGMII1_TX_N: length 6.9
  TOP w0.102: C405.1 211.1,74.77 arc(210.99,74.94) 210.95,75.13 210.95,77.14 arc(210.79,77.91) 210.36,78.57 arc(210.04,79.05) 209.92,79.62 209.92,80.3 arc(209.94,80.37) 209.98,80.43 209.99,80.44 arc(210.03,80.5) 210.05,80.57 U27.17
QSGMII1_TX_P: length 6.9
  TOP w0.102: C400.1 210.54,74.77 arc(210.65,74.94) 210.69,75.13 210.69,77.14 arc(210.56,77.82) 210.18,78.39 arc(209.8,78.95) 209.67,79.62 209.67,80.3 arc(209.65,80.37) 209.61,80.43 209.6,80.44 arc(209.56,80.5) 209.55,80.57 U27.16
QSGMII2_RX_N: length 81.8
  TOP w0.127: C66.1 187.11,115.77 190.91,115.77 arc(191.08,115.77) 191.26,115.75 191.26,115.75 191.38,115.73 191.38,115.73 195.55,115 arc(196.8,114.63) 197.95,114 207.58,107.26 arc(208.78,106.25) 209.78,105.05 215.19,97.33 arc(216,96.37) 216.96,95.57 229.37,86.87 arc(230.69,86.15) 232.13,85.73 237.93,84.71 arc(239.74,84.18) 241.4,83.27 243.39,81.87 arc(244.51,80.93) 245.45,79.82 245.9,79.18 arc(246.45,78.17) 246.78,77.05 247.23,74.48 247.24,74.41 arc(247.26,74.21) 247.27,74.01 247.27,69.94 U56.D13
QSGMII2_RX_P: length 81.6
  TOP w0.127: U56.D14 246.91,69.96 246.91,74.01 arc(246.91,74.18) 246.89,74.35 246.88,74.42 246.65,75.71 246.42,76.99 arc(246.12,78.03) 245.6,78.98 245.16,79.61 arc(244.26,80.68) 243.19,81.58 242.19,82.28 242.19,82.28 241.19,82.98 arc(239.61,83.85) 237.87,84.36 232.07,85.38 arc(230.55,85.82) 229.17,86.58 216.75,95.28 arc(215.75,96.12) 214.9,97.12 212.2,100.99 209.49,104.85 arc(208.53,106) 207.38,106.97 197.74,113.71 arc(196.67,114.3) 195.48,114.65 191.31,115.38 191.31,115.38 arc(191.11,115.41) 190.91,115.42 187.06,115.42 186.94,115.29 C62.1
QSGMII2_TX_N: length 87.4
  TOP w0.127: v1(245.57,76.21) 245.29,75.92 245.29,74.87 C454.1 ; U1.AE14 v2(174.92,113.25)
  BOTTOM w0.127: v2(174.92,113.25) 174.97,113.2 175.1,113.2 arc(175.16,113.2) 175.23,113.21 175.49,113.25 arc(175.59,113.32) 175.62,113.44 175.62,113.44 arc(175.65,113.56) 175.75,113.62 175.94,113.65 arc(176.06,113.63) 176.12,113.53 arc(176.19,113.42) 176.3,113.4 181.02,114.23 arc(182.49,114.36) 183.97,114.23 183.97,114.23 189.47,113.26 arc(190.83,112.87) 192.07,112.19 215.45,95.82 arc(217.26,94.82) 219.25,94.24 221.49,93.85 arc(222.73,93.48) 223.87,92.86 232.06,87.13 arc(234.06,86.03) 236.25,85.39 238.63,84.97 arc(239.9,84.6) 241.05,83.97 243.71,82.11 arc(244.05,81.82) 244.34,81.48 244.69,80.97 245.14,79.9 245.29,79.03 245.29,76.62 245.29,76.61 245.29,76.49 v1(245.57,76.21)
QSGMII2_TX_P: length 87.4
  TOP w0.127: U1.AD14 v2(174.12,113.25) ; C445.1 244.93,74.87 244.93,75.92 v1(244.65,76.21)
  BOTTOM w0.127: v2(174.12,113.25) 174.33,113.03 arc(174.54,112.89) 174.8,112.84 175.1,112.84 arc(175.2,112.84) 175.29,112.86 181.08,113.88 arc(182.5,114) 183.91,113.88 183.91,113.88 189.41,112.91 arc(190.69,112.54) 191.87,111.89 215.24,95.53 arc(217.13,94.49) 219.19,93.89 221.43,93.5 arc(222.6,93.16) 223.67,92.57 231.85,86.84 arc(233.93,85.7) 236.19,85.04 238.57,84.62 arc(239.76,84.27) 240.85,83.68 243.51,81.81 arc(243.8,81.57) 244.04,81.28 244.38,80.8 244.79,79.8 244.94,78.99 244.94,76.77 244.93,76.76 244.93,76.49 v1(244.65,76.21)
RESET_REQ_N: length 97.3
  TOP w0.127: U65.K15 v1(71.52,104.42) 73.69,104.42 86.23,116.97 111.51,116.97 112.39,117.86 135,117.86 148.46,104.39 155.66,104.39 U1.B3
  BOTTOM w0.127: R98.2 v1(71.52,104.42)
RS232_CTS1: length 22.1
  TOP w0.127: J13.A8 136.02,22.84 136.02,24.77 133.86,26.92 132.33,26.92 131.32,27.94 131.32,32.51 129.79,34.04 U43.4 C276.1 126.61,34.42 126.37,34.67 123.99,34.67 FB21.2
RS232_CTS2: length 32.4
  TOP w0.127: FB25.2 126.24,33.4 126.61,33.03 C289.1 U43.5 129.67,32.77 130.94,31.5 130.94,27.69 132.08,26.54 133.6,26.54 135.51,24.64 135.51,21.84 136.78,20.57 143.76,20.57 145.46,18.88 J13.B8
RS232_RTS1: length 32.5
  TOP w0.127: FB20.2 124.5,37.21 126.24,37.21 126.61,36.84 C277.1 U43.2 129.67,36.58 132.08,34.16 132.08,28.45 132.84,27.69 134.37,27.69 136.14,25.91 138.18,25.91 138.94,25.15 138.94,24 139.57,23.37 144,23.37 J13.A1
RS232_RTS2: length 23.9
  TOP w0.127: FB24.2 124.5,29.59 126.37,29.59 126.61,29.34 C290.1 U43.8 129.54,28.96 129.79,28.7 129.79,23.88 131.57,22.1 133.35,22.1 136.57,18.88 J13.B1
RS232_RXD1: length 25
  TOP w0.127: J13.A6 138.24,22.29 136.52,24 136.52,24.89 134.11,27.3 132.59,27.3 131.7,28.19 131.7,33.27 129.67,35.31 U43.3 C278.1 126.61,35.69 126.37,35.94 124.24,35.94 FB19.2
RS232_RXD2: length 29.5
  TOP w0.127: FB23.2 123.99,32.13 126.24,32.13 126.61,31.76 C291.1 U43.6 129.67,31.5 130.56,30.61 130.56,24.38 131.83,23.11 133.6,23.11 136.65,20.07 142.11,20.07 142.92,19.26 J13.B6
RS232_TXD1: length 30.9
  TOP w0.127: FB18.2 124.63,38.61 126.24,38.61 126.61,38.23 C279.1 U43.1 129.67,37.85 132.46,35.05 132.46,28.58 132.97,28.07 134.62,28.07 136.27,26.42 138.3,26.42 139.32,25.4 139.32,24.26 139.83,23.75 141.86,23.75 142.92,24.81 J13.A3
RS232_TXD2: length 27.1
  TOP w0.127: J13.B3 139.11,18.75 138.43,19.43 136.65,19.43 133.48,22.61 131.7,22.61 130.17,24.13 130.17,29.59 129.54,30.23 U43.7 C292.1 126.61,30.61 126.37,30.86 124.24,30.86 FB22.2
SATA_RX_N: length 14.4
  TOP w0.127: C634.1 250.11,115.61 arc(250.04,115.56) 249.95,115.54 246.71,115.54 arc(246.49,115.53) 246.27,115.51 243.56,115.03 arc(243.37,115) 243.18,114.99 236.63,114.99 236.55,115.07 U29.15
SATA_RX_P: length 14.8
  TOP w0.127: C635.1 250.2,115.06 arc(250.16,115.15) 250.07,115.19 246.71,115.19 arc(246.52,115.18) 246.33,115.16 243.62,114.68 arc(243.4,114.65) 243.18,114.64 236.63,114.64 236.55,114.57 U29.14
SATA_TX_N: length 15.8
  TOP w0.127: U29.13 236.55,114.07 236.63,113.99 236.75,113.99 237.25,113.91 arc(237.75,113.76) 238.2,113.51 242.15,110.75 arc(244.5,109.46) 247.06,108.71 247.59,108.62 arc(247.78,108.59) 247.97,108.59 249.94,108.59 C633.1
SATA_TX_P: length 15.8
  TOP w0.127: C632.1 249.99,108.04 arc(249.77,108.18) 249.52,108.23 247.97,108.23 arc(247.75,108.24) 247.53,108.27 247,108.36 arc(244.36,109.13) 241.95,110.46 238,113.22 arc(237.61,113.43) 237.19,113.56 236.72,113.64 236.63,113.64 236.55,113.57 U29.12
SD_REFCLK1_N: length 59.8
  TOP w0.102: 153.17,73.25 R543.2 ; 153.17,73.25 153.17,73.55 arc(153.2,73.62) 153.27,73.65 158.83,73.65 arc(160.62,74) 162.14,75.02 162.46,75.34 arc(163.56,76.07) 164.85,76.33 167.14,76.33 arc(168.09,76.47) 168.94,76.9 171.11,78.41 arc(173.41,80.35) 175.34,82.65 175.34,82.65 177.35,85.51 arc(178.71,87.14) 180.33,88.5 185.74,92.29 arc(186.65,93.05) 187.41,93.96 188.82,95.97 188.83,95.98 arc(188.84,95.99) 188.85,96.01 arc(188.92,96.13) 188.99,96.26 189.61,99.4 C68.1 ; 153.17,73.25 152.78,73.63 152.26,73.63 151.41,72.78 151.41,68.48 151.09,68.16 U68.4
SD_REFCLK1_P: length 60.5
  TOP w0.102: 153.17,74.3 153.17,74.03 arc(153.2,73.96) 153.27,73.93 158.83,73.93 arc(160.51,74.26) 161.95,75.22 162.26,75.54 arc(163.45,76.33) 164.85,76.61 167.14,76.61 arc(168,76.74) 168.78,77.13 168.81,77.14 171.13,78.77 arc(173.22,80.52) 174.98,82.62 177.12,85.67 arc(178.5,87.34) 180.16,88.75 180.19,88.74 182.87,90.63 182.89,90.63 185.58,92.52 arc(186.45,93.25) 187.18,94.12 188.59,96.13 188.6,96.14 arc(188.61,96.16) 188.62,96.17 arc(188.67,96.26) 188.72,96.35 189.33,99.42 189.33,100.93 arc(189.32,100.99) 189.29,101.03 189.26,101.06 arc(189.23,101.08) 189.19,101.09 188.86,101.09 arc(188.67,101.17) 188.59,101.36 C67.1 ; 153.17,74.3 R544.2 ; 153.17,74.3 152.78,73.91 152.15,73.91 151.13,72.9 151.13,71.03 151.03,70.93 151.03,70.73 151.13,70.63 151.13,70.42 151.03,70.32 151.03,70.12 151.13,70.02 151.13,69.81 151.03,69.71 151.03,69.51 151.13,69.41 151.13,69.2 151.03,69.1 151.03,68.9 151.13,68.8 151.13,68.59 150.97,68.44 150.58,68.44 150.48,68.54 150.48,68.62 150.29,68.81 U68.3
SD_REFCLK1_SEL: length 127.4
  TOP w0.127: U68.9 150.76,64.91 152.91,67.06 v1(153.67,67.06) ; U65.M1 56.44,102.93 56.01,102.49 v1(56.01,102.36)
  L6SIG w0.102: v1(56.01,102.36) 55.24,101.6 55.24,96.01 66.17,85.09 66.17,82.93 67.31,81.79 67.31,77.34 70.36,74.3 74.55,74.3 75.82,73.03 92.33,73.03 93.09,72.26 110.87,72.26 111.89,71.25 128.4,71.25 132.59,67.06 v1(153.67,67.06)
SD_REFCLK2_N: length 71.1
  TOP w0.102: U1.AA18 v2(171.72,117.25) ; R537.2 231.02,137.92 230.75,137.92 R538.2 230.37,137.8 230.12,138.05 228.12,138.05 v1(227.84,137.77)
  L3SIG w0.102: v2(171.72,117.25) 172.1,116.86 175.07,116.86 175.33,117.13 175.33,117.4 176.04,118.11 178.82,118.11 182.35,121.64 213.09,121.64 225.2,133.74 225.2,135.62 227.34,137.77 v1(227.84,137.77)
SD_REFCLK2_P: length 70.9
  TOP w0.102: R536.2 231.02,138.43 230.75,138.43 R535.2 230.37,138.55 230.15,138.33 228.12,138.33 v1(227.84,138.61) ; U1.AB18 v2(172.52,117.25)
  L3SIG w0.102: v2(172.52,117.25) 172.44,117.25 172.28,117.4 172.28,117.55 172.36,117.63 175.16,117.63 175.92,118.39 178.7,118.39 182.23,121.92 212.98,121.92 224.92,133.86 224.92,135.74 227.33,138.15 227.33,138.43 227.51,138.61 v1(227.84,138.61)
SD_RX1_N: length 40.5
  TOP w0.127: C64.1 187.09,111.73 187.58,111.73 arc(187.8,111.72) 188.02,111.7 191.02,111.17 arc(191.55,111.01) 192.04,110.75 195.46,108.34 195.46,108.34 arc(196.3,107.61) 197,106.75 198.34,104.85 198.36,104.82 arc(199.17,103.85) 200.13,103.04 arc(200.15,103.03) 200.16,103.02 200.16,103.02 200.54,102.75 203.18,100.91 arc(204.46,99.83) 205.53,98.55 206.85,96.66 arc(207.11,96.18) 207.27,95.65 207.45,94.6 arc(207.48,94.38) 207.49,94.16 207.49,93.38 v1(207.79,93.09)
  BOTTOM w0.127: v1(207.79,93.09) 207.52,92.82 207.52,92.46 arc(207.53,92.27) 207.55,92.08 207.73,91.08 arc(207.86,90.62) 208.09,90.2 208.58,89.51 arc(208.69,89.36) 208.82,89.22 209.95,88.09 arc(210.34,87.56) 210.55,86.94 210.62,86.55 arc(210.66,86.1) 210.62,85.66 210.51,85.04 arc(210.48,84.85) 210.47,84.66 210.47,84.23 210.55,84.15 U25.8
SD_RX1_P: length 40.3
  TOP w0.127: v1(206.86,93.09) 207.14,93.36 207.14,94.16 arc(207.13,94.35) 207.1,94.54 206.92,95.59 arc(206.86,95.89) 206.75,96.19 205.24,98.35 arc(204.2,99.58) 202.97,100.61 200.43,102.4 200.33,102.46 199.93,102.74 199.93,102.75 arc(198.92,103.6) 198.07,104.62 198.05,104.64 196.71,106.55 arc(196.04,107.36) 195.25,108.05 arc(195.18,108.11) 195.11,108.16 191.9,110.41 arc(191.41,110.68) 190.88,110.83 187.96,111.35 arc(187.77,111.37) 187.58,111.38 187.1,111.38 186.94,111.22 C63.1
  BOTTOM w0.127: U25.7 210.05,84.15 210.12,84.23 210.12,84.66 arc(210.13,84.88) 210.16,85.1 210.27,85.73 arc(210.3,86.1) 210.27,86.48 210.2,86.88 arc(210.02,87.39) 209.7,87.83 208.57,88.97 arc(208.42,89.13) 208.29,89.3 207.8,90 arc(207.53,90.49) 207.38,91.02 207.2,92.02 arc(207.17,92.24) 207.16,92.46 207.16,92.79 v1(206.86,93.09)
SD_RX2_N: length 40.8
  TOP w0.127: C61.1 190.14,113.77 190.74,113.77 arc(190.96,113.76) 191.18,113.73 193.81,113.26 arc(194.34,113.11) 194.83,112.84 195.34,112.49 arc(195.51,112.35) 195.68,112.2 208.87,99.01 arc(209.14,98.7) 209.35,98.35 210.33,96.39 arc(210.47,96.05) 210.56,95.69 211.06,92.89 arc(211.09,92.67) 211.1,92.45 211.1,88.73 arc(211.09,88.5) 211.06,88.28 210.48,85.03 210.47,84.78 210.47,84.23 210.55,84.15 U27.3
SD_RX2_P: length 40.6
  TOP w0.127: C65.1 189.98,113.24 190.15,113.41 190.74,113.41 arc(190.93,113.4) 191.12,113.38 191.13,113.38 193.75,112.91 arc(194.2,112.78) 194.62,112.55 195.13,112.19 arc(195.29,112.08) 195.43,111.95 208.62,98.75 arc(208.85,98.49) 209.03,98.19 210.01,96.23 arc(210.14,95.93) 210.21,95.63 210.71,92.83 arc(210.73,92.64) 210.74,92.45 210.74,88.73 arc(210.73,88.54) 210.71,88.35 210.13,85.07 210.12,84.79 210.12,84.23 210.05,84.15 U27.4
SD_RX5_N: length 64.3
  TOP w0.127: U1.AG17 176.33,116.21 arc(176.54,116.34) 176.77,116.42 177.02,116.49 arc(177.16,116.54) 177.31,116.59 177.32,116.6 177.44,116.64 arc(177.57,116.69) 177.71,116.72 179.91,117.11 arc(180.37,117.25) 180.79,117.47 180.96,117.59 arc(181.44,117.86) 181.97,118.01 188.18,119.11 arc(190.73,119.33) 193.28,119.11 199.74,117.97 arc(204.46,116.59) 208.77,114.23 214.57,110.17 arc(216.94,108.18) 218.92,105.81 219.39,105.15 arc(220.98,103.25) 222.87,101.66 222.96,101.6 arc(225.7,100.1) 228.71,99.22 231.39,98.75 arc(231.58,98.72) 231.77,98.71 232.77,98.71 232.84,98.79 U26.3
SD_RX5_P: length 64.3
  TOP w0.127: U26.4 232.84,98.29 232.77,98.36 231.77,98.36 arc(231.55,98.37) 231.33,98.4 228.65,98.87 arc(225.57,99.77) 222.75,101.31 222.67,101.37 arc(220.73,103) 219.1,104.94 218.63,105.61 arc(216.68,107.93) 214.37,109.88 208.56,113.94 arc(204.32,116.27) 199.68,117.62 193.22,118.76 arc(190.73,118.98) 188.25,118.76 185.18,118.22 arc(185.11,118.17) 185.09,118.08 arc(185.07,117.99) 184.99,117.94 184.73,117.89 arc(184.64,117.91) 184.59,117.99 arc(184.54,118.07) 184.44,118.09 184.18,118.04 arc(184.11,117.99) 184.09,117.9 arc(184.07,117.81) 183.99,117.76 183.73,117.71 arc(183.63,117.73) 183.58,117.81 arc(183.53,117.89) 183.44,117.91 183.18,117.86 arc(183.1,117.81) 183.08,117.72 183.08,117.72 arc(183.06,117.63) 182.99,117.58 182.72,117.54 arc(182.63,117.56) 182.58,117.63 182.58,117.64 arc(182.53,117.71) 182.44,117.73 182.03,117.66 arc(181.58,117.53) 181.16,117.3 180.99,117.18 arc(180.51,116.92) 179.98,116.76 177.77,116.37 arc(177.67,116.35) 177.57,116.31 177.46,116.27 177.45,116.26 U1.AH17
SD_RX6_N: length 60.9
  TOP w0.127: U1.AG19 176.36,117.84 arc(176.49,117.92) 176.63,117.98 176.66,117.99 arc(176.79,118.02) 176.93,118.03 177.8,118.03 arc(177.99,118.04) 178.18,118.07 179.29,118.26 arc(179.75,118.4) 180.17,118.63 180.81,119.07 arc(181.29,119.34) 181.82,119.49 188.73,120.71 arc(191.22,120.93) 193.71,120.71 204.26,118.85 arc(206.96,118.06) 209.44,116.71 216.73,111.6 arc(219.61,110.02) 222.77,109.1 231.05,107.64 arc(231.24,107.61) 231.43,107.6 232.77,107.6 232.84,107.68 U28.3
SD_RX6_P: length 60.8
  TOP w0.127: U28.4 232.84,107.18 232.77,107.25 231.43,107.25 arc(231.21,107.26) 230.99,107.29 222.71,108.75 arc(219.48,109.69) 216.53,111.31 209.23,116.42 arc(206.83,117.74) 204.19,118.5 193.65,120.36 arc(191.22,120.57) 188.79,120.36 184.97,119.69 arc(184.89,119.64) 184.87,119.55 arc(184.85,119.45) 184.77,119.4 184.51,119.36 arc(184.42,119.38) 184.37,119.46 arc(184.32,119.54) 184.23,119.56 183.97,119.51 arc(183.89,119.46) 183.87,119.37 arc(183.85,119.28) 183.77,119.23 183.51,119.18 arc(183.42,119.2) 183.37,119.28 arc(183.32,119.36) 183.23,119.38 182.97,119.34 arc(182.89,119.28) 182.87,119.19 arc(182.85,119.1) 182.77,119.05 182.51,119 arc(182.42,119.02) 182.37,119.1 arc(182.32,119.18) 182.23,119.2 181.88,119.14 arc(181.43,119.01) 181.01,118.78 180.37,118.34 arc(179.89,118.07) 179.36,117.91 178.24,117.72 arc(178.02,117.69) 177.8,117.68 176.95,117.68 U1.AH19
SD_RX7_N: length 58.6
  TOP w0.127: U29.3 232.84,116.57 232.77,116.49 231.6,116.49 arc(231.41,116.5) 231.22,116.53 206.54,120.88 arc(205.43,120.98) 204.32,120.88 204.28,120.88 arc(203.39,120.8) 202.5,120.88 194.57,122.28 arc(192.25,122.48) 189.92,122.28 181.64,120.82 arc(181.11,120.66) 180.63,120.4 179.5,119.61 arc(179.08,119.38) 178.62,119.24 177.42,119.03 177.14,118.92 176.72,118.79 arc(176.51,118.7) 176.32,118.59 U1.AG20
SD_RX7_P: length 58.5
  TOP w0.127: U1.AH20 177.52,118.69 178.69,118.89 arc(179.22,119.05) 179.7,119.32 180.83,120.1 arc(181.25,120.33) 181.7,120.47 182.26,120.56 arc(182.35,120.54) 182.39,120.47 182.39,120.47 arc(182.44,120.39) 182.53,120.37 182.8,120.42 arc(182.87,120.47) 182.89,120.56 arc(182.91,120.64) 182.99,120.69 183.26,120.74 arc(183.35,120.72) 183.39,120.65 arc(183.44,120.57) 183.53,120.55 183.8,120.6 arc(183.88,120.65) 183.89,120.73 arc(183.91,120.82) 183.99,120.87 184.26,120.92 arc(184.35,120.9) 184.39,120.82 arc(184.44,120.75) 184.53,120.73 184.8,120.78 arc(184.88,120.82) 184.89,120.91 arc(184.91,121) 184.99,121.05 189.99,121.93 arc(192.25,122.12) 194.51,121.93 202.44,120.53 arc(203.39,120.44) 204.35,120.53 204.35,120.53 arc(204.36,120.53) 204.38,120.53 arc(205.43,120.62) 206.48,120.53 231.16,116.18 arc(231.38,116.15) 231.6,116.14 232.77,116.14 232.84,116.07 U29.4
SD_TX1_N: length 47.9
  TOP w0.127: U1.AE11 v2(174.92,110.85)
  BOTTOM w0.127: U25.4 208.55,84.15 208.47,84.23 208.47,84.31 arc(208.47,84.38) 208.46,84.46 208.43,84.61 arc(208.37,84.84) 208.25,85.06 207.99,85.42 arc(207.71,85.76) 207.37,86.05 205.36,87.45 arc(204.03,88.57) 202.91,89.91 191.32,106.46 arc(190.48,107.46) 189.47,108.3 188.85,108.74 arc(186.22,110.19) 183.34,111.07 183.13,111.1 183.12,111.11 arc(183.12,111.11) 183.12,111.11 183.12,111.11 arc(183.11,111.11) 183.1,111.11 183.09,111.11 arc(179.52,111.22) 175.97,110.84 175.97,110.84 arc(175.78,110.82) 175.59,110.81 175.55,110.81 175.44,110.92 175.44,111.02 175.31,111.15 175.07,111.15 174.92,111 v2(174.92,110.85)
SD_TX1_P: length 47.9
  TOP w0.127: U1.AD11 v2(174.12,110.85)
  BOTTOM w0.127: v2(174.12,110.85) 174.32,110.64 arc(174.53,110.5) 174.78,110.45 175.59,110.45 arc(175.81,110.46) 176.03,110.49 176.03,110.49 arc(179.54,110.87) 183.07,110.76 arc(183.17,110.74) 183.27,110.72 arc(186.08,109.87) 188.65,108.45 189.27,108.01 arc(190.22,107.21) 191.03,106.25 202.62,89.7 arc(203.77,88.32) 205.15,87.16 207.17,85.75 arc(207.46,85.51) 207.7,85.22 207.96,84.85 arc(208.04,84.71) 208.08,84.55 208.11,84.4 arc(208.12,84.35) 208.12,84.31 208.12,84.23 208.05,84.15 U25.3
SD_TX2_N: length 51.3
  TOP w0.127: U27.7 208.55,84.15 208.47,84.23 208.47,84.77 208.33,85.56 arc(208.18,86.09) 207.91,86.58 207.84,86.69 arc(207.55,87.02) 207.21,87.31 206.75,87.64 arc(206.46,87.88) 206.21,88.17 205.56,89.1 arc(205.34,89.51) 205.2,89.97 205.1,90.67 arc(205.09,90.84) 205.08,91.02 205.08,91.1 arc(205.11,91.27) 205.21,91.42 v1(205.36,91.57) ; U1.AE13 v2(174.92,112.45)
  BOTTOM w0.127: v1(205.36,91.57) 205.08,91.85 205.08,93.03 arc(205.07,93.25) 205.04,93.47 204.82,94.7 arc(204.67,95.23) 204.4,95.71 199.24,103.08 arc(197.99,104.58) 196.49,105.84 189.04,111.05 arc(188.09,111.57) 187.05,111.88 182.31,112.71 arc(181.87,112.75) 181.43,112.71 179.82,112.43 arc(179.76,112.44) 179.72,112.5 179.72,112.5 arc(179.69,112.55) 179.63,112.57 179.29,112.51 arc(179.24,112.47) 179.22,112.41 arc(179.21,112.35) 179.15,112.31 178.82,112.25 arc(178.76,112.27) 178.72,112.32 arc(178.69,112.38) 178.62,112.39 178.29,112.33 arc(178.24,112.3) 178.22,112.23 arc(178.21,112.17) 178.15,112.14 177.47,112.01 176.33,112.01 175.92,112.42 174.94,112.42 v2(174.92,112.45)
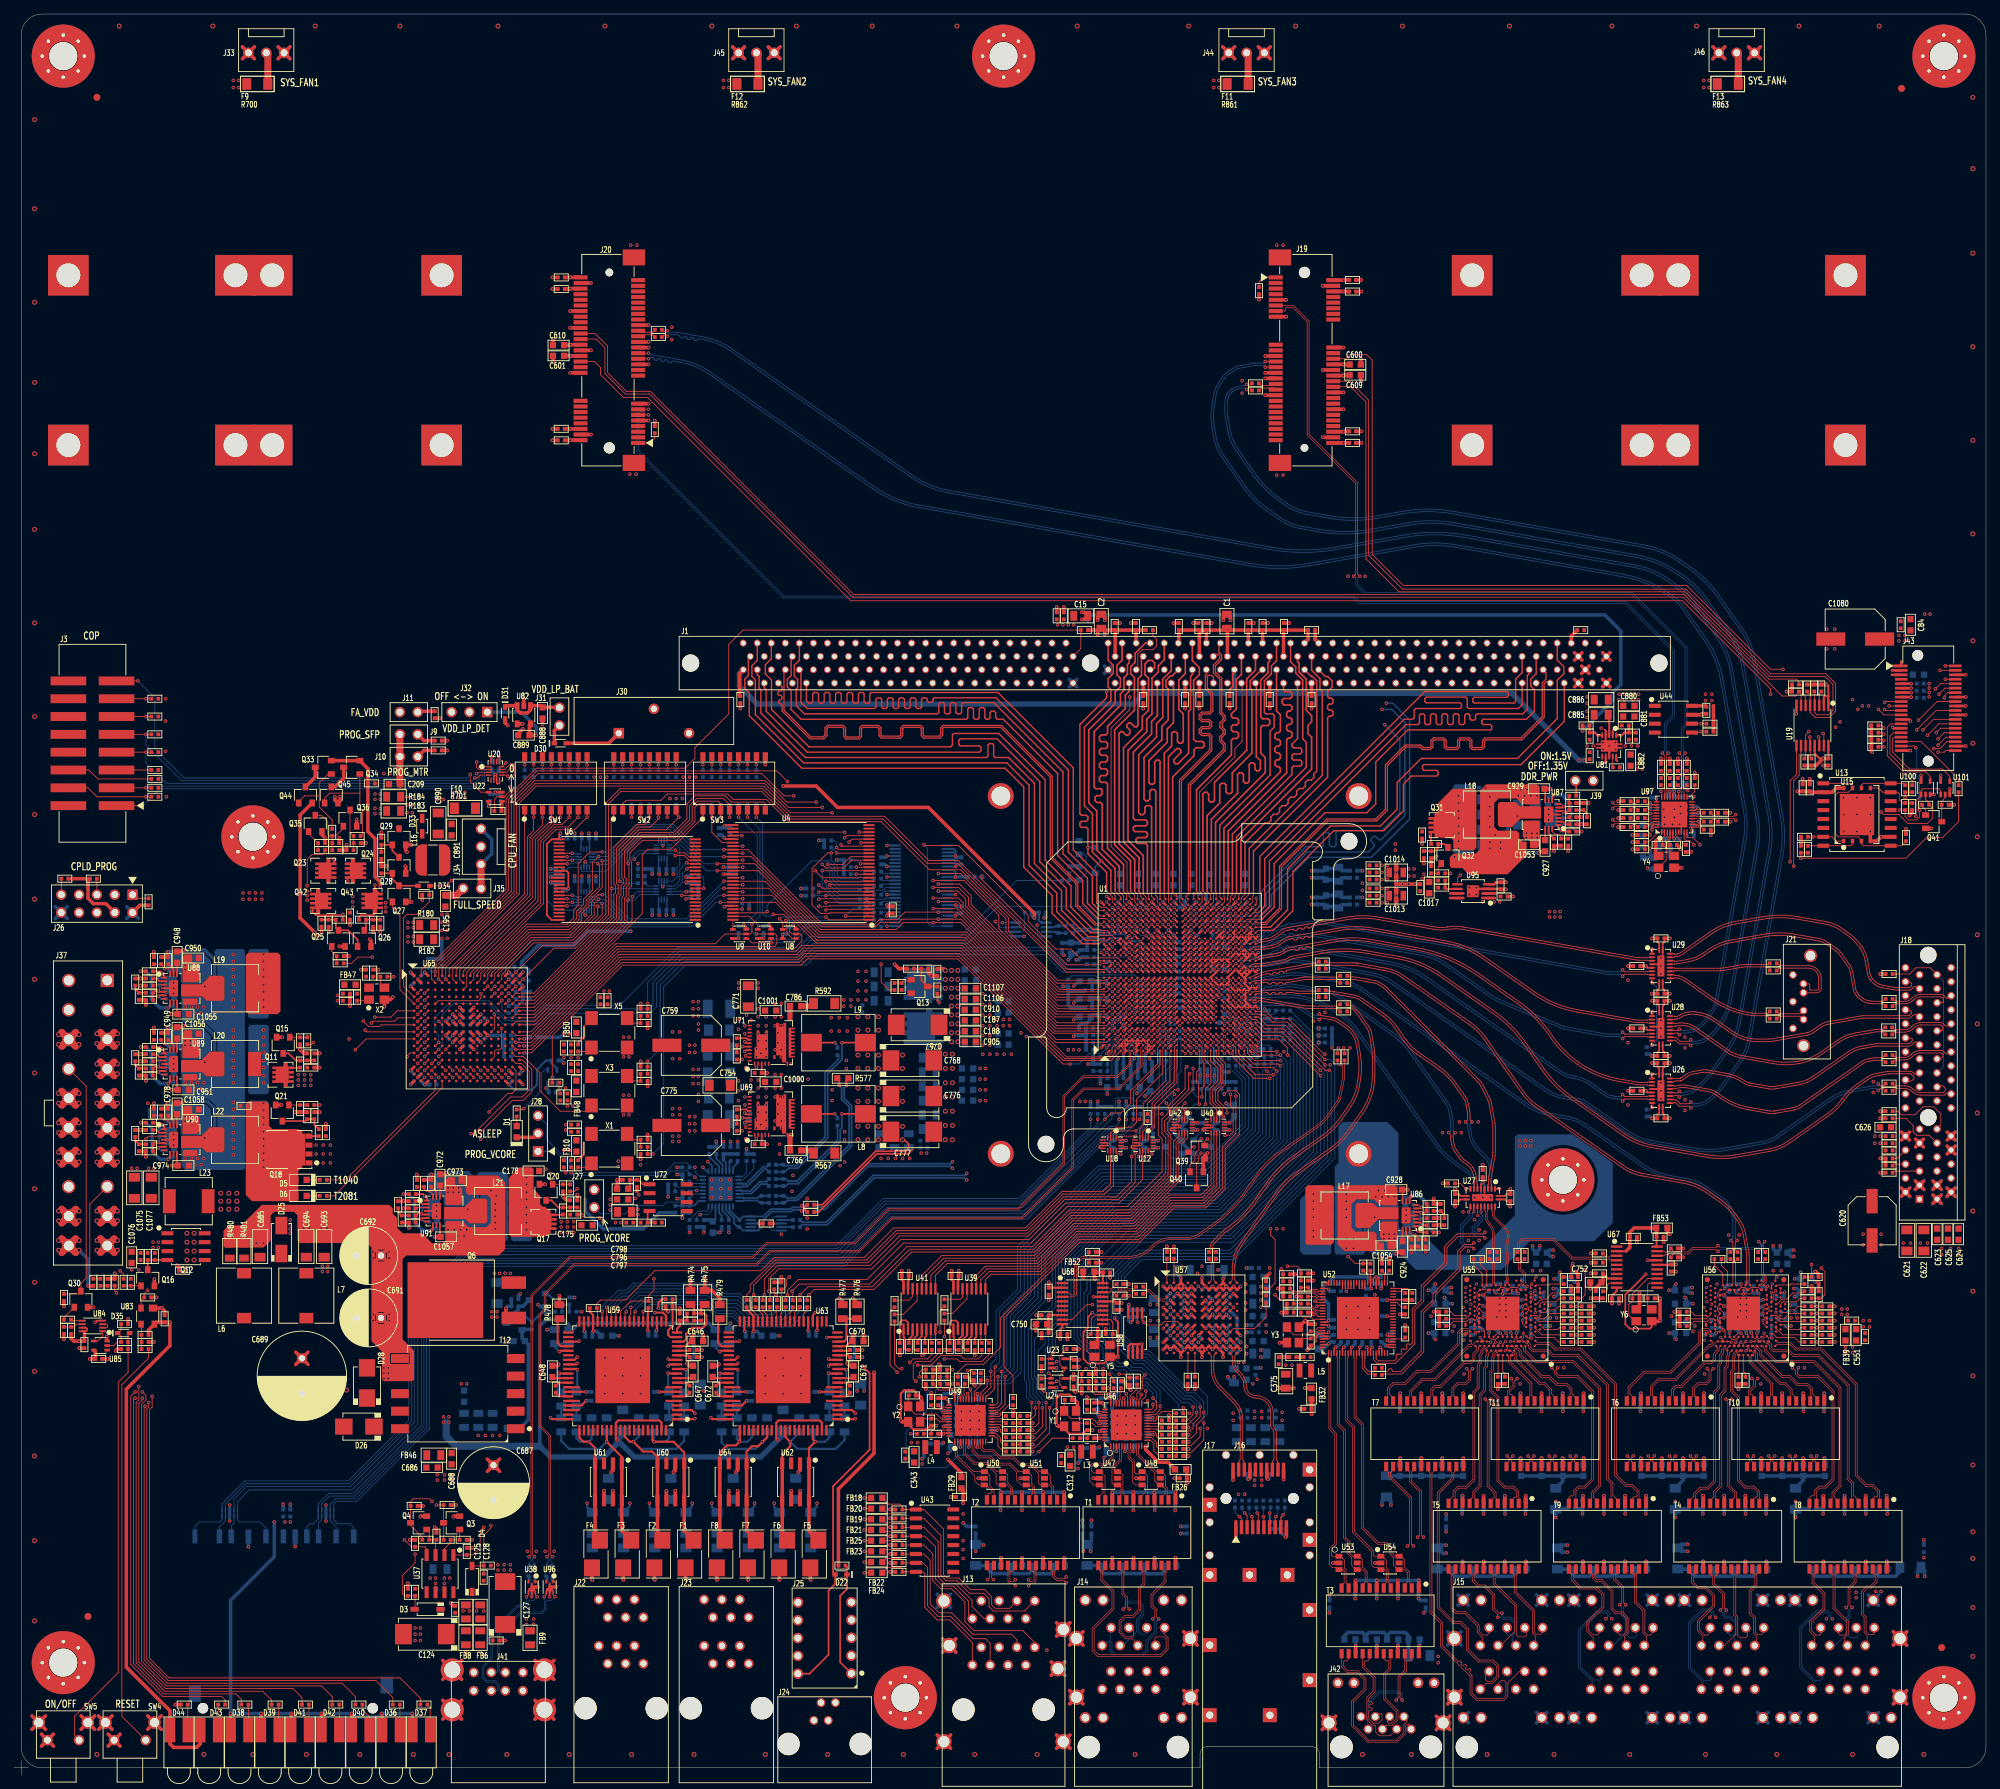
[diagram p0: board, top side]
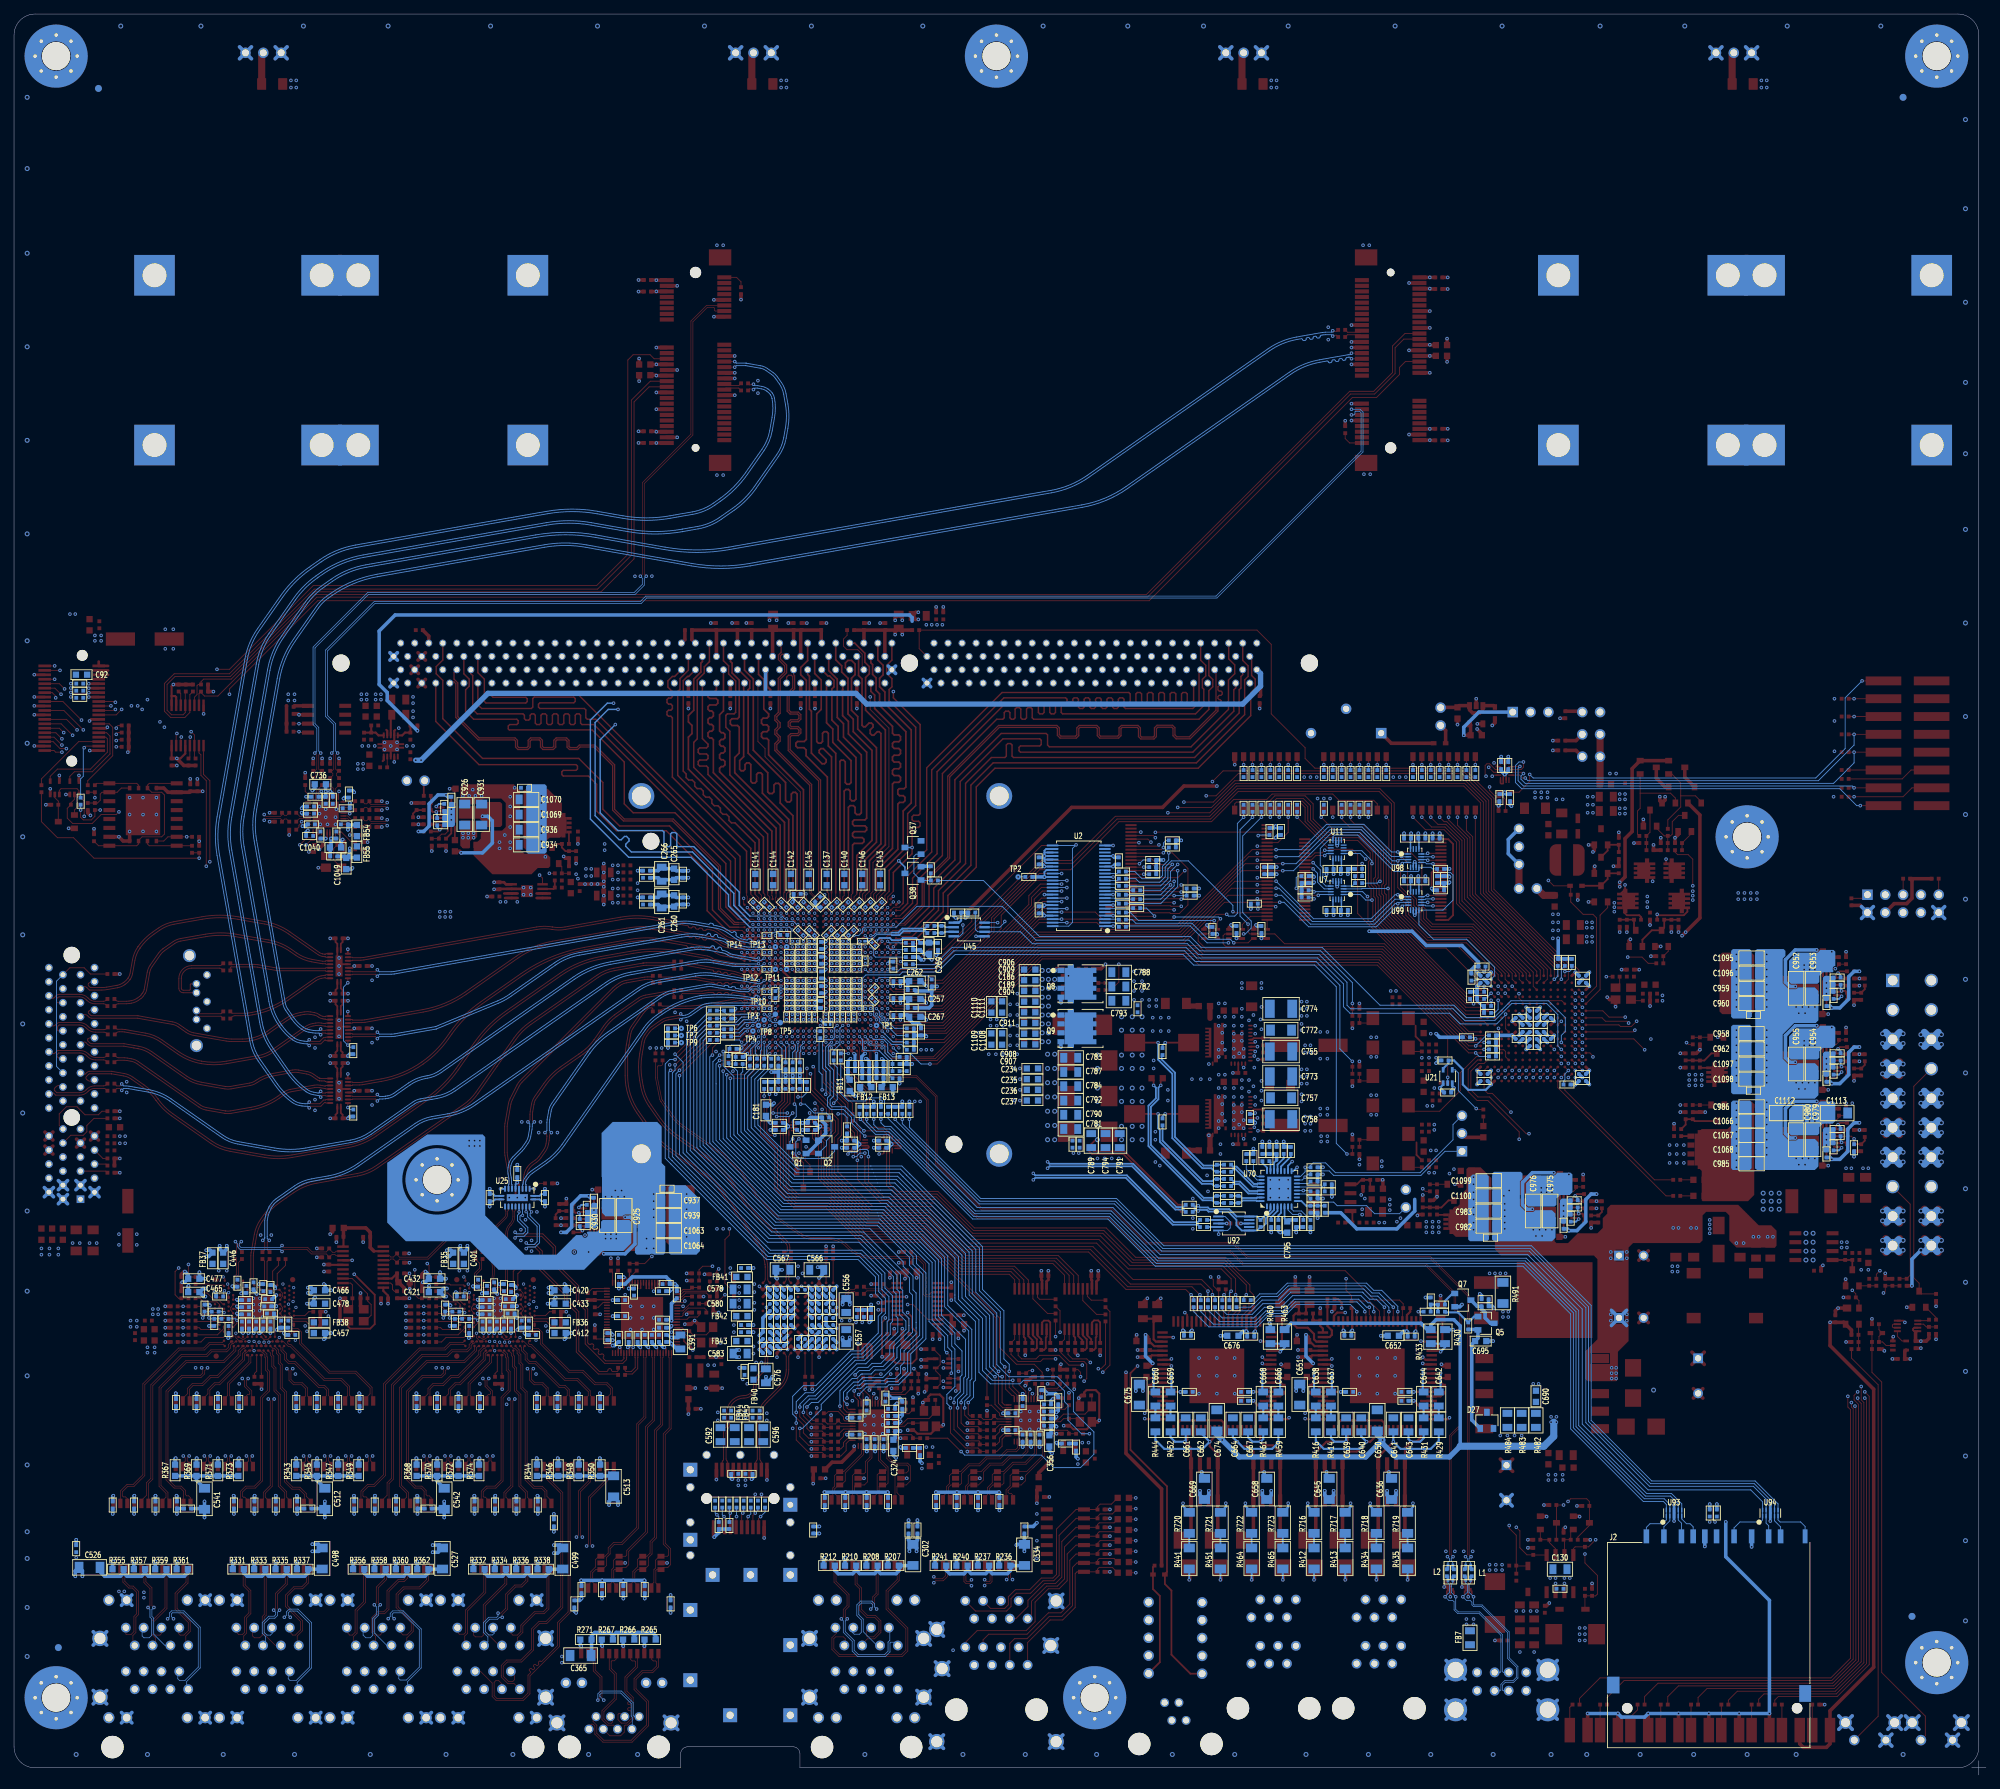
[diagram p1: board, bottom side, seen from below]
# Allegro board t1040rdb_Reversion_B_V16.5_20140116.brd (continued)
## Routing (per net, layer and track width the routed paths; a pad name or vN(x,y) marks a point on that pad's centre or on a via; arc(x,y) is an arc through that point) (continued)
SD_TX2_P: length 51.3
  TOP w0.127: U1.AD13 v2(174.12,112.45) ; U27.8 208.05,84.15 208.12,84.23 208.12,84.74 208.12,84.75 207.98,85.5 arc(207.85,85.96) 207.62,86.37 207.55,86.48 arc(207.3,86.77) 207.01,87.02 206.54,87.35 arc(206.2,87.63) 205.92,87.97 205.27,88.89 arc(205.01,89.37) 204.85,89.9 204.76,90.43 arc(204.73,90.64) 204.72,90.84 204.72,91.1 arc(204.69,91.27) 204.59,91.42 v1(204.44,91.57)
  BOTTOM w0.127: v2(174.12,112.45) 174.52,112.04 174.75,112.04 175.95,112.04 176.33,111.66 177.5,111.66 181.49,112.36 arc(181.87,112.39) 182.25,112.36 186.99,111.53 arc(187.95,111.24) 188.83,110.76 196.28,105.54 arc(197.73,104.33) 198.95,102.88 204.11,95.51 arc(204.34,95.09) 204.47,94.63 204.69,93.41 arc(204.72,93.22) 204.72,93.03 204.72,91.85 v1(204.44,91.57)
SD_TX5_N: length 66.2
  TOP w0.127: U1.AE17 v2(174.92,116.45) ; U26.7 232.84,96.79 232.77,96.71 229.52,96.71 v1(229.23,97)
  BOTTOM w0.127: v2(174.92,116.45) 174.95,116.41 175.26,116.41 arc(175.4,116.41) 175.54,116.43 178.61,116.97 arc(178.91,117.06) 179.17,117.21 179.18,117.21 arc(179.59,117.44) 180.04,117.57 180.05,117.57 arc(180.16,117.64) 180.19,117.78 arc(180.22,117.91) 180.34,117.99 180.48,118.01 arc(180.62,117.98) 180.69,117.87 arc(180.77,117.75) 180.9,117.72 181.05,117.74 arc(181.16,117.82) 181.19,117.95 arc(181.22,118.09) 181.34,118.16 181.48,118.19 arc(181.62,118.16) 181.69,118.04 181.7,118.03 arc(181.76,117.92) 181.89,117.89 182.06,117.92 arc(183.34,118.03) 184.61,117.92 196.03,115.91 arc(198.83,115.09) 201.4,113.69 220.36,100.41 arc(221.21,99.94) 222.14,99.67 222.43,99.62 arc(223.66,99.26) 224.78,98.65 226.89,97.17 arc(227.31,96.94) 227.76,96.81 228.11,96.75 228.12,96.75 arc(228.31,96.72) 228.5,96.71 228.95,96.71 v1(229.23,97)
SD_TX5_P: length 66.3
  TOP w0.127: U26.8 232.84,96.29 232.77,96.36 229.52,96.36 v1(229.23,96.08) ; U1.AD17 v2(174.12,116.45)
  BOTTOM w0.127: v2(174.12,116.45) 174.33,116.28 arc(174.45,116.19) 174.59,116.12 174.75,116.05 175.26,116.05 arc(175.43,116.06) 175.6,116.08 178.68,116.62 arc(179.04,116.73) 179.38,116.92 179.38,116.92 arc(179.73,117.11) 180.11,117.22 182.12,117.57 arc(183.34,117.68) 184.55,117.57 195.97,115.56 arc(198.7,114.76) 201.19,113.39 220.16,100.12 arc(221.07,99.61) 222.07,99.32 222.37,99.27 arc(223.52,98.93) 224.58,98.36 226.69,96.88 arc(227.17,96.61) 227.69,96.46 228.05,96.4 228.06,96.4 arc(228.28,96.37) 228.5,96.36 228.95,96.36 v1(229.23,96.08)
SD_TX6_N: length 63.6
  TOP w0.127: U1.AE19 v2(174.92,118.05) ; v1(229.23,105.89) 229.52,105.6 232.77,105.6 232.84,105.68 U28.7
  BOTTOM w0.127: v1(229.23,105.89) 228.95,105.6 227.27,105.6 arc(227.02,105.61) 226.77,105.65 220.94,106.68 220.93,106.69 220.93,106.69 220.9,106.69 212.13,110.34 arc(211.26,110.75) 210.43,111.27 204.03,115.75 arc(202.34,116.68) 200.5,117.21 185.92,119.78 arc(184.44,119.91) 182.96,119.78 182.46,119.7 arc(182.32,119.73) 182.25,119.84 arc(182.17,119.96) 182.03,119.99 181.89,119.97 arc(181.77,119.89) 181.74,119.76 arc(181.71,119.62) 181.6,119.55 181.45,119.52 arc(181.32,119.55) 181.24,119.67 arc(181.17,119.79) 181.03,119.82 180.89,119.79 arc(180.77,119.72) 180.74,119.58 arc(180.71,119.44) 180.6,119.37 180.35,119.32 arc(179.81,119.17) 179.33,118.9 179,118.67 arc(178.59,118.45) 178.13,118.31 176.59,118.04 arc(176.4,118.02) 176.21,118.01 174.95,118.01 v2(174.92,118.05)
SD_TX6_P: length 63.6
  TOP w0.127: U1.AD19 v2(174.12,118.05) ; v1(229.23,104.97) 229.52,105.25 232.77,105.25 232.84,105.18 U28.8
  BOTTOM w0.127: v1(229.23,104.97) 228.95,105.25 227.27,105.25 arc(226.99,105.26) 226.7,105.3 220.83,106.33 211.99,110.01 arc(211.09,110.44) 210.23,110.98 203.82,115.46 arc(202.21,116.35) 200.44,116.86 185.86,119.43 arc(184.44,119.56) 183.02,119.43 180.41,118.97 arc(179.95,118.84) 179.53,118.61 179.21,118.38 arc(178.72,118.12) 178.19,117.96 176.65,117.69 arc(176.43,117.66) 176.21,117.65 175.08,117.65 174.75,117.65 174.58,117.75 arc(174.47,117.81) 174.37,117.87 v2(174.12,118.05)
SD_TX7_N: length 61.5
  TOP w0.127: U29.7 232.84,114.57 232.77,114.49 229.52,114.49 v1(229.23,114.78) ; U1.AE20 v2(174.92,118.85)
  BOTTOM w0.127: v2(174.92,118.85) 174.95,118.81 175.2,118.81 arc(175.39,118.82) 175.57,118.84 175.83,118.89 arc(175.9,118.93) 175.92,119.02 arc(175.94,119.11) 176.02,119.16 176.29,119.2 arc(176.37,119.19) 176.42,119.11 arc(176.47,119.03) 176.56,119.01 177,119.09 arc(177.45,119.22) 177.87,119.45 178.08,119.6 arc(178.15,119.72) 178.12,119.85 arc(178.09,119.99) 178.17,120.11 178.28,120.19 arc(178.42,120.22) 178.54,120.15 arc(178.66,120.07) 178.79,120.1 179.08,120.3 arc(179.95,120.78) 180.9,121.06 181.3,121.13 arc(181.37,121.17) 181.38,121.25 arc(181.4,121.33) 181.47,121.38 181.76,121.43 arc(181.84,121.41) 181.88,121.34 arc(181.93,121.27) 182.01,121.25 183.96,121.59 arc(185.38,121.72) 186.81,121.59 226.89,114.53 arc(227.08,114.5) 227.27,114.49 228.95,114.49 v1(229.23,114.78)
SD_TX7_P: length 61.5
  TOP w0.127: U1.AD20 v2(174.12,118.85) ; v1(229.23,113.86) 229.52,114.14 232.77,114.14 232.84,114.07 U29.8
  BOTTOM w0.127: v2(174.12,118.85) 174.53,118.56 arc(174.7,118.48) 174.89,118.45 175.2,118.45 arc(175.42,118.46) 175.64,118.49 177.06,118.74 arc(177.59,118.9) 178.07,119.16 179.28,120.01 arc(180.09,120.45) 180.96,120.71 184.02,121.24 arc(185.38,121.36) 186.75,121.24 226.83,114.18 arc(227.05,114.15) 227.27,114.14 228.95,114.14 v1(229.23,113.86)
SDHC_CD_N: length 168.9
  TOP w0.127: U1.L5 v2(162.92,106.05)
  L3SIG w0.102: v2(162.92,106.05) 162.69,106.05 162.27,105.63 161.96,105.63 161.71,105.38 161.71,102.6 161.04,101.92 161.04,98.17 160.45,97.59 160.45,97.33 160.45,96.32 157.61,93.47 v1(157.48,93.47)
  BOTTOM w0.127: J2.10 41.73,35.38 42.16,35.81 42.67,35.81 43.35,36.49 U93.4 U93.5 43.35,38.65 44.83,40.13 48.36,40.13 58.04,49.81 58.04,66.19 65.51,73.66 117.9,73.66 124.63,80.39 144.02,80.39 156.08,92.46 156.97,92.46 157.48,92.96 v1(157.48,93.47) R66.1
SDHC_CLK: length 180
  BOTTOM w0.127: J2.5 35.9,35.22 35.05,36.07 32.13,36.07 31.83,36.36 U94.1 U94.8 31.83,38.95 33.53,40.64 48.15,40.64 57.53,50.02 57.53,66.4 65.3,74.17 117.69,74.17 124.42,80.9 143.76,80.9 156.46,93.6 R68.1 156.47,94.23 156.84,94.23 156.97,94.36 156.97,96.27 157.23,96.52 159.26,96.52 159.7,96.08 162.12,96.08 163.19,97.16 R61.2
SDHC_CMD: length 166.3
  TOP w0.127: U1.K3 v2(162.12,104.45)
  L3SIG w0.102: v1(158.5,93.47) 158.5,93.73 160.73,95.96 160.73,97.36 161.42,98.04 161.42,101.09 162.5,102.17 162.5,103.8 162.12,104.19 v2(162.12,104.45)
  BOTTOM w0.127: R67.1 v1(158.5,93.47) 158.5,92.71 157.86,92.08 156.21,92.08 144.14,80.01 124.79,80.01 118.05,73.28 65.67,73.28 58.42,66.03 58.42,49.65 48.52,39.75 44.96,39.75 43.85,38.64 U93.6 U93.3 43.85,36.36 43.4,35.9 J2.2
SDHC_DAT0: length 177.1
  TOP w0.127: U1.L2 163.32,104.01 162.94,103.63 162.94,101.35 159.13,97.54 159.13,95.76 157.73,94.36 156.34,94.36 v1(155.45,93.47)
  BOTTOM w0.127: J2.7 30.97,35.54 31.33,35.91 U94.2 U94.7 31.33,39.33 33.15,41.15 47.94,41.15 57.02,50.23 57.02,66.61 65.09,74.68 117.48,74.68 124.21,81.41 143.47,81.41 155.45,93.39 v1(155.45,93.47) R60.1
SDHC_DAT1: length 182.1
  TOP w0.127: U1.K4 v2(162.12,105.25)
  L3SIG w0.102: v2(162.12,105.25) 162.12,105.15 162.54,104.73 162.54,104.22 162.81,103.94 162.81,101.98 161.8,100.97 161.8,96.52 159,93.73 159,93.14 158.83,92.96 154.94,92.96 v1(154.43,93.47)
  BOTTOM w0.127: J2.8 29.27,35.36 30.13,36.23 U94.3 U94.6 30.13,38.64 33.02,41.53 47.78,41.53 56.64,50.39 56.64,66.77 64.93,75.06 117.32,75.06 124.05,81.79 143.38,81.79 154.43,92.84 v1(154.43,93.47) R62.1
SDHC_DAT2: length 167.5
  TOP w0.127: U1.L3 v2(162.92,104.45)
  L3SIG w0.102: v1(160.4,93.47) 162.18,95.25 162.18,100.71 163.07,101.6 163.07,104.14 162.92,104.29 v2(162.92,104.45)
  BOTTOM w0.127: J2.9 48.4,35.3 47.88,35.81 46.1,35.81 45.55,36.36 U93.1 U93.8 45.55,38.57 45.97,38.99 48.84,38.99 59.18,49.33 59.18,65.72 65.98,72.52 118.37,72.52 125.1,79.25 144.4,79.25 156.46,91.31 158.24,91.31 v1(160.4,93.47) 160.53,93.6 R63.1
SDHC_DAT3: length 164
  TOP w0.127: U1.L1 163.32,101.21 159.51,97.41 v1(159.51,93.47)
  BOTTOM w0.127: R64.1 v1(159.51,93.47) 159.51,93.09 158.11,91.69 156.34,91.69 144.27,79.63 124.94,79.63 118.21,72.9 65.82,72.9 58.8,65.88 58.8,49.49 48.68,39.37 45.85,39.37 45.05,38.57 U93.7 U93.2 45.05,36.23 45.9,35.38 J2.1
SDHC_VS: length 100.3
  TOP w0.127: U65.M16 v1(72.72,102.93) 73.72,102.93 86.61,115.82 111.89,115.82 112.78,116.71 134.62,116.71 149.48,101.85 156.32,101.85 U1.D1
  BOTTOM w0.127: v1(72.72,102.93) 72.22,102.42 R72.1
SDHC_WP: length 189.3
  TOP w0.127: U1.M5 v2(163.72,106.05)
  L3SIG w0.102: v2(163.72,106.05) 163.3,105.63 162.76,105.63 162.54,105.4 162.54,105.09 162.78,104.84 163.11,104.84 163.31,104.64 163.31,101.34 162.56,100.58 162.56,94.87 160.27,92.58 154.3,92.58 v1(153.42,93.47)
  BOTTOM w0.127: R65.1 v1(153.42,93.47) 153.42,92.33 143.26,82.17 123.89,82.17 117.16,75.44 64.77,75.44 56.26,66.93 56.26,50.55 47.62,41.91 32.89,41.91 29.63,38.65 U94.5 U94.4 29.63,36.36 29.34,36.07 26.42,36.07 25.78,35.43 J2.11
SENSEGND: length 79.1
  TOP w0.254: U1.G20 v2(159.72,118.05)
  L6SIG w0.127: v2(159.72,118.05) 159.72,117.91 160.11,117.51 160.11,117.09 160.35,116.85 160.67,116.85 160.91,116.61 160.91,104.24 160.71,104.04 160.71,103.94
  L6SIG w0.254: v1(135.76,84.83) 136.05,85.12 136.99,85.12 137.75,85.88 137.75,90.38 141.88,94.51 147.09,99.72 158.8,99.72 160.71,101.63 160.71,101.93 160.71,103.94
  BOTTOM w0.254: R554.2 112.34,78.44 115.9,78.44 122.58,85.12 135.48,85.12 v1(135.76,84.83)
SENSEGNDC: length 85.9
  TOP w0.254: U1.AB10 v2(172.52,110.05)
  L6SIG w0.127: 167.75,107.04 167.15,106.44 163.55,106.44 163.32,106.21 163.32,105.85 163.11,105.64 162.75,105.64 162.52,105.41 162.52,104.13 162.71,103.94 ; 167.9,107.04 167.88,107.04
  L6SIG w0.254: 167.88,107.04 167.75,107.04 ; v1(133.73,86.48) 133.44,86.77 132.74,86.77 131.99,86.02 131.99,84.82 133.69,83.12 140.3,83.12 143.8,86.63 143.8,91.93 149.38,97.51 154.67,97.51 155.58,98.43 159.89,98.43 162.74,101.27 162.74,103.92 162.71,103.94 ; 167.9,107.04 171.02,107.04 171.46,107.49 171.46,109.31 171.98,109.82 172.29,109.82 v2(172.52,110.05)
  BOTTOM w0.254: v1(133.73,86.48) 133.45,86.77 121.69,86.77 115.51,80.59 114.37,80.59 R555.1
SENSEVDD: length 77.2
  TOP w0.254: U1.G19 v2(159.72,117.25)
  L6SIG w0.127: 160.36,103.94 160.36,104.05 160.12,104.28 160.12,116.64 159.72,117.04 v2(159.72,117.25)
  L6SIG w0.254: 160.36,103.94 160.36,101.78 158.65,100.08 146.94,100.08 141.53,94.66 137.39,90.53 137.39,86.02 136.84,85.47 136.05,85.47 v1(135.76,85.75)
  BOTTOM w0.254: v1(135.76,85.75) 135.48,85.47 122.43,85.47 115.75,78.79 112.34,78.79 R552.2
SENSEVDD_EN: length 66.4
  TOP w0.127: U65.P7 63.02,100.92 v1(63.52,100.42)
  L6SIG w0.102: v1(109.35,77.09) 109.09,76.84 95.38,76.84 94.62,77.6 82.42,77.6 80.14,79.88 77.47,79.88 74.17,83.19 74.17,84.07 73.53,84.71 72.01,84.71 70.74,85.98 70.74,90.68 64.02,97.4 64.02,99.92 v1(63.52,100.42)
  BOTTOM w0.127: v1(109.35,77.09) 109.39,77.13 U92.5 108.06,77.61 107.7,77.98 107.7,78.87 108.44,79.61 U92.1
SENSEVDDC: length 86.7
  TOP w0.254: U1.AB9 v2(172.52,109.25)
  L6SIG w0.127: 167.9,106.69 167.77,106.69 167.31,106.22 167.31,105.88 167.26,105.83 167.07,105.64 163.55,105.64 163.32,105.41 163.32,104.15 163.11,103.94
  L6SIG w0.254: 167.9,106.69 171.16,106.69 171.37,106.89 171.82,107.34 171.82,109.16 172.13,109.47 172.29,109.47 v2(172.52,109.25) ; 163.11,103.94 163.09,103.92 163.09,101.12 160.04,98.07 155.73,98.07 154.81,97.16 149.53,97.16 144.15,91.78 144.15,86.48 140.44,82.77 133.54,82.77 131.63,84.68 131.63,86.17 132.59,87.13 133.45,87.13 v1(133.73,87.4)
  BOTTOM w0.254: v1(133.73,87.4) 133.45,87.12 121.54,87.12 115.37,80.95 114.37,80.95 R553.1
SFPP_DET_N: length 170.7
  TOP w0.127: U65.L2 58.01,103.93 v1(57.51,103.42) ; J16.6 178.12,36.76 v1(178.05,36.83)
  L6SIG w0.102: v1(57.51,103.42) 55.93,103.42 54.74,102.23 54.74,95.76 65.66,84.84 65.66,82.68 66.8,81.53 66.8,77.09 70.1,73.79 74.3,73.79 75.56,72.52 92.08,72.52 92.84,71.76 110.62,71.76 111.63,70.74 128.14,70.74 136.21,62.67 136.27,62.67 157.29,62.67 165.61,54.36 165.61,45.85 167.26,44.2 172.21,44.2 178.05,38.35 v1(178.05,36.83)
  BOTTOM w0.127: R393.1 v1(178.05,36.83)
SFPP_RX_N: length 19.6
  TOP w0.127: U57.L11 174.12,59.98 arc(174.01,59.81) 173.97,59.61 173.97,58.93 arc(174.11,58.24) 174.5,57.65 174.87,57.28 arc(175.42,56.46) 175.62,55.48 175.62,55.45 arc(176.02,54.48) 176.99,54.08 arc(178.73,53.36) 179.45,51.62 179.45,49.81 arc(179.48,49.66) 179.57,49.54 arc(179.81,49.17) 179.9,48.73 179.9,45.04 arc(179.93,44.9) 180,44.79 180.02,44.77 arc(180.09,44.66) 180.12,44.52 J16.12
SFPP_RX_P: length 19.6
  TOP w0.127: J16.13 179.32,44.52 arc(179.35,44.66) 179.42,44.77 179.44,44.79 arc(179.52,44.9) 179.54,45.04 179.54,48.73 arc(179.48,49.03) 179.31,49.29 arc(179.15,49.53) 179.1,49.81 179.1,51.62 arc(178.48,53.1) 176.99,53.72 arc(175.77,54.23) 175.26,55.45 175.26,55.48 arc(175.09,56.32) 174.62,57.03 174.25,57.4 arc(173.78,58.1) 173.61,58.93 173.61,59.61 arc(173.57,59.81) 173.46,59.98 U57.L10
SFPP_RXLOS: length 172.3
  TOP w0.127: v1(58.51,103.42) 59.01,103.93 U65.L3 ; v1(179.83,36.83) 179.72,36.72 J16.8
  L6SIG w0.102: v1(58.51,103.42) 58.01,102.92 55.93,102.92 54.99,101.98 54.99,95.89 65.91,84.96 65.91,82.8 67.06,81.66 67.06,77.22 70.23,74.04 74.42,74.04 75.69,72.77 92.2,72.77 92.96,72.01 110.74,72.01 111.76,70.99 128.27,70.99 136.36,62.9 157.44,62.9 165.86,54.48 165.86,45.97 167.39,44.45 172.34,44.45 178.94,37.85 179.32,37.85 179.83,37.34 v1(179.83,36.83)
  BOTTOM w0.127: R390.1 180.09,37.08 v1(179.83,36.83)
SFPP_TX_N: length 18.2
  TOP w0.127: U57.L7 170.46,59.98 arc(170.57,59.81) 170.61,59.61 170.61,57.79 arc(170.9,56.33) 171.73,55.09 173.73,53.09 arc(174.48,51.97) 174.74,50.65 174.74,45.04 arc(174.72,44.9) 174.64,44.79 174.62,44.77 arc(174.55,44.66) 174.52,44.52 J16.19
SFPP_TX_P: length 18.2
  TOP w0.127: J16.18 175.32,44.53 arc(175.29,44.66) 175.22,44.77 175.2,44.79 arc(175.13,44.9) 175.1,45.04 175.1,50.65 arc(174.81,52.11) 173.98,53.34 171.98,55.34 arc(171.23,56.46) 170.97,57.79 170.97,59.61 arc(171.01,59.81) 171.12,59.98 U57.L8
SFPP_TXDIS: length 170.5
  TOP w0.127: v1(175.39,37.34) 175.72,37 J16.3 ; U65.K2 58.01,104.93 v1(57.51,104.42)
  L6SIG w0.102: v1(175.39,37.34) 174.93,37.8 174.93,40.59 174.37,41.15 173.86,41.15 171.07,43.94 167.13,43.94 165.35,45.72 165.35,53.85 157.61,61.59 136.91,61.59 128.27,70.23 93.6,70.23 91.82,72.01 75.31,72.01 74.04,73.28 69.85,73.28 66.29,76.84 66.29,81.28 65.15,82.42 65.15,84.58 54.23,95.5 54.23,102.62 56.04,104.42 v1(57.51,104.42)
  BOTTOM w0.127: v1(175.39,37.34) 175.01,37.72 R396.1
SFPP_TXFAIL: length 172.3
  TOP w0.127: U65.J3 59.01,105.93 v1(58.51,105.43) ; v1(174.62,36.83) 174.92,36.53 J16.2
  L6SIG w0.102: v1(58.51,105.43) 58.01,104.92 56.16,104.92 53.98,102.74 53.98,95.38 64.9,84.46 64.9,82.3 66.04,81.15 66.04,76.71 69.72,73.03 73.91,73.03 75.18,71.76 91.69,71.76 93.47,69.98 128.14,69.98 136.78,61.34 157.54,61.34 165.1,53.78 165.1,45.59 167,43.69 170.94,43.69 173.99,40.64 173.99,39.5 174.62,38.86 v1(174.62,36.83)
  BOTTOM w0.127: v1(174.62,36.83) 173.99,37.46 R397.1
SG_INT_N: length 153.6
  TOP w0.127: R281.2 R854.2 182.36,67.44 182.12,67.69 180.47,67.69 v1(179.7,68.45) ; U65.M2 58.01,102.93 v1(57.51,102.42)
  L6SIG w0.102: v1(179.7,68.45) 176.91,71.25 173.99,71.25 172.21,73.03 166.12,73.03 164.47,71.37 136.02,71.37 134.87,72.52 93.22,72.52 92.46,73.28 75.95,73.28 74.68,74.55 70.48,74.55 67.56,77.47 67.56,81.92 66.42,83.06 66.42,85.22 55.5,96.14 55.5,101.22 56.7,102.42 v1(57.51,102.42)
SG_LED0: length 3.3
  TOP w0.127: U52.68 185.94,68.95 185.67,69.22 184.67,69.22 R279.2 R274.1
SG_LED1: length 6
  TOP w0.127: R275.1 R277.2 182.24,68.96 185.52,68.96 185.93,68.55 U52.69
SG_MDI0_N: length 35.9
  TOP w0.102: U52.2 187.72,59.56 187.66,59.5 187.66,49.47 188.49,48.63 188.49,32.92 187.73,32.16 187.73,31.34 187.9,31.18 U53.1 189.04,31.18 189.61,30.61 189.61,29.48 189.83,29.26 189.83,27.47 190.19,27.11 T3.11
SG_MDI0_P: length 36
  TOP w0.102: U52.1 187.32,59.56 187.38,59.5 187.38,49.35 188.21,48.51 188.21,33.03 187.45,32.27 187.45,29.97 187.83,29.59 188.5,29.59 U53.3 189.42,29.28 189.55,29.14 189.55,27.37 189.19,27.01 T3.12
SG_MDI1_N: length 35.8
  TOP w0.102: T3.8 193.19,27.15 192.83,27.51 192.83,28.99 192.15,29.67 192.15,30.73 191.71,31.18 U53.6 190.82,31.18 190.37,31.62 190.37,33.27 189.74,33.91 189.74,49.15 188.86,50.03 188.86,59.5 188.92,59.56 U52.5
SG_MDI1_P: length 35.9
  TOP w0.102: U52.4 188.52,59.56 188.58,59.5 188.58,49.92 189.46,49.03 189.46,33.79 190.09,33.16 190.09,31.51 190.63,30.97 190.63,29.85 191.2,29.28 U53.4 192.15,29.28 192.55,28.88 192.55,27.45 192.19,27.09 T3.9
SG_MDI2_N: length 36.7
  TOP w0.102: U52.8 190.12,59.56 190.06,59.5 190.06,50.61 191.01,49.66 191.01,34.69 193.7,31.99 193.7,31.34 193.87,31.18 U54.1 195.01,31.18 195.58,30.61 195.58,29.54 195.83,29.29 195.83,27.44 196.19,27.08 T3.5
SG_MDI2_P: length 36.9
  TOP w0.102: U52.7 189.72,59.56 189.78,59.5 189.78,50.49 190.73,49.54 190.73,34.57 193.42,31.88 193.42,29.97 193.8,29.59 194.31,29.59 194.62,29.28 U54.3 195.45,29.28 195.55,29.18 195.55,27.4 195.19,27.04 T3.6
SG_MDI3_N: length 38
  TOP w0.102: T3.2 199.19,27.12 198.83,27.48 198.83,28.96 198.15,29.64 198.15,30.7 197.68,31.18 U54.6 196.79,31.18 196.34,31.62 196.34,32.37 195.57,33.15 194.45,33.15 192.28,35.32 192.28,50.04 191.26,51.06 191.26,59.5 191.32,59.56 U52.11
SG_MDI3_P: length 38
  TOP w0.102: T3.3 198.19,27.12 198.55,27.48 198.55,28.84 198.12,29.28 U54.4 197.17,29.28 196.6,29.85 196.6,30.97 196.06,31.51 196.06,32.26 195.45,32.87 194.34,32.87 192,35.2 192,49.92 190.98,50.94 190.98,59.5 190.92,59.56 U52.10
SG_MDX0_N: length 24.9
  TOP w0.102: T3.14 190.19,16.52 189.93,16.26 189.59,16.26 189.47,16.14 189.47,15.51 190.12,14.86 191.53,14.86 192.66,13.73 192.66,12.18 190.88,10.4 190.88,7.13 193.05,4.95 196.98,4.95 197.97,5.94 197.97,7.09 198.5,7.62 198.5,8.13 198.31,8.32 J42.2
SG_MDX0_P: length 24.9
  TOP w0.102: J42.1 199.09,6.91 198.75,7.24 198.52,7.24 198.25,6.97 198.25,5.83 197.09,4.67 192.94,4.67 190.6,7.01 190.6,10.52 192.38,12.29 192.38,13.61 191.41,14.58 190,14.58 189.19,15.39 T3.13
SG_MDX1_N: length 16.5
  TOP w0.102: J42.6 194.43,8.76 194.82,8.76 194.94,8.64 194.94,7.87 194.46,7.39 193.68,7.39 193.07,8 193.07,9.08 193.17,9.18 193.45,9.18 193.55,9.29 193.55,9.49 193.45,9.59 193.17,9.59 193.07,9.69 193.07,9.92 193.17,10.02 193.45,10.02 193.55,10.12 193.55,10.33 193.45,10.43 193.17,10.43 193.07,10.53 193.07,10.95 193.95,11.84 193.95,13.96 192.47,15.44 192.47,16.15 192.57,16.26 192.93,16.26 193.19,16.52 T3.17
SG_MDX1_P: length 16.5
  TOP w0.102: J42.3 196.1,5.59 194.56,5.59 194.06,6.1 194.06,6.99 193.93,7.11 193.56,7.11 192.79,7.89 192.79,11.06 193.67,11.95 193.67,13.84 192.19,15.33 T3.16
SG_MDX2_N: length 13.2
  TOP w0.102: J42.5 195.57,7.1 196.44,7.1 197.23,7.89 197.23,9.16 195.48,10.91 195.48,14.36 196.19,15.07 T3.20
SG_MDX2_P: length 13.3
  TOP w0.102: T3.19 195.19,16.55 195.46,16.28 195.81,16.28 195.91,16.18 195.91,15.19 195.2,14.48 195.2,10.79 196.95,9.04 196.95,8.01 196.32,7.38 195.89,7.38 195.71,7.56 195.71,8 J42.4
SG_MDX3_N: length 17.2
  TOP w0.102: v1(197.82,10.67) 197.51,10.98 197.51,13.87 198.47,14.83 198.47,16.15 198.57,16.26 198.93,16.26 199.19,16.52 T3.23
  BOTTOM w0.102: J42.8 192.59,8.32 192.79,8.51 192.79,10.3 194.45,11.96 197.43,11.96 197.82,11.57 v1(197.82,10.67)
SG_MDX3_P: length 17.1
  TOP w0.102: v1(196.98,10.67) 197.23,10.92 197.23,13.98 198.19,14.94 T3.22
  BOTTOM w0.102: v1(196.98,10.67) 197.54,11.23 197.54,11.46 197.31,11.68 194.56,11.68 193.07,10.19 193.07,8.39 192.91,8.24 192.91,6.59 J42.7
SG_RST_N: length 146.4
  TOP w0.127: U65.R7 63.02,99.92 v1(63.52,99.42) ; R282.2 R280.1 191.14,72.89 v1(190.12,73.91)
  L6SIG w0.102: v1(190.12,73.91) 189.61,73.91 187.32,76.2 184.28,76.2 183.13,77.34 168.66,77.34 168.15,77.85 153.81,77.85 152.54,76.58 95.25,76.58 94.49,77.34 82.3,77.34 80.01,79.63 77.34,79.63 73.41,83.57 72.77,83.57 70.48,85.85 70.48,90.55 63.52,97.52 v1(63.52,99.42)
SGMII_RX_N: length 37.4
  TOP w0.102: U27.15 v2(209.05,80.27)
  TOP w0.127: U52.18 194.12,59.49 194.09,59.47 194.09,59.34 194.41,59.03 196.7,59.03 197.01,59.34 arc(197.06,59.48) 197.01,59.62 arc(196.95,59.76) 197.01,59.9 197.09,59.98 arc(197.23,60.03) 197.37,59.98 arc(197.51,59.92) 197.65,59.98 197.73,60.06 arc(197.78,60.2) 197.73,60.34 arc(197.67,60.48) 197.72,60.62 197.8,60.7 arc(197.94,60.75) 198.08,60.7 arc(198.22,60.64) 198.36,60.7 198.44,60.78 arc(198.5,60.92) 198.44,61.06 arc(198.39,61.19) 198.44,61.33 198.52,61.41 arc(198.66,61.47) 198.8,61.41 arc(198.94,61.36) 199.08,61.41 199.26,61.59 199.26,66.42 200.53,67.69 200.53,69.72 203.83,73.03 203.83,75.31 205.66,77.14 209.39,77.14 v1(209.62,77.37)
  BOTTOM w0.127: v1(209.62,77.37) 209.39,77.14 208.48,77.14 208.15,77.46 208.15,77.91 209.27,79.02 209.27,79.79 209.05,80.01 v2(209.05,80.27) U27.15
SGMII_RX_P: length 37.9
  TOP w0.102: U27.14 v2(208.55,79.77)
  TOP w0.127: v1(209.62,76.55) 209.39,76.78 205.81,76.78 204.19,75.16 204.19,72.88 200.89,69.58 200.89,67.54 199.62,66.27 199.62,61.45 196.84,58.67 194.26,58.67 193.74,59.2 193.74,59.47 193.72,59.49 U52.17
  BOTTOM w0.127: U27.14 v2(208.55,79.77) 208.79,79.77 208.91,79.64 208.91,79.17 207.8,78.05 207.8,77.32 208.33,76.78 209.39,76.78 v1(209.62,76.55)
SGMII_TX_N: length 35.1
  TOP w0.102: U27.13 v2(208.05,80.28)
  TOP w0.127: C367.2 194.94,57.63 195.06,57.51 195.67,57.51 arc(195.81,57.57) 195.87,57.71 arc(195.93,57.85) 196.07,57.91 196.18,57.91 arc(196.32,57.85) 196.38,57.71 arc(196.44,57.57) 196.58,57.51 197.59,57.51 200.53,60.45 200.53,66.03 202.21,67.71 202.21,68.61 205.74,72.14 205.74,74.68 206.68,75.62 207.8,75.62 v1(208.03,75.85)
  BOTTOM w0.127: U27.13 v2(208.05,80.28) 207.82,80.06 207.82,79.56 206.48,78.21 206.48,76.02 206.88,75.62 207.8,75.62 v1(208.03,75.85)
SGMII_TX_P: length 35.1
  TOP w0.102: U27.12 207.55,80.55 v2(207.26,80.26)
  TOP w0.127: v1(208.03,75.03) 207.8,75.26 206.83,75.26 206.1,74.53 206.1,71.99 202.56,68.46 202.56,67.56 200.89,65.89 200.89,60.3 197.74,57.15 195.06,57.15 C366.2
  BOTTOM w0.127: U27.12 207.55,80.55 v2(207.26,80.26) 207.47,80.06 207.47,79.71 206.12,78.36 206.12,75.87 206.74,75.26 207.8,75.26 v1(208.03,75.03)
SPI_CLK: length 202.6
  TOP w0.127: R867.2 R865.1 v1(269.49,139.31) ; U12.10 160.84,87.68 160.83,87.68 v1(160.83,87.63) 160.83,84.89 157.48,81.53 149.86,81.53 144.65,76.33 126.41,76.33 122.21,72.14 108.97,72.14 107.57,70.74 v1(107.57,68.96) 107.7,68.83 R450.1
  L6SIG w0.102: v1(269.49,139.31) 269.49,137.41 268.73,136.65 268.1,136.65 251.97,120.52 230.25,120.52 195.07,85.34 167.13,85.34 164.85,87.63 v1(160.83,87.63)
  BOTTOM w0.127: v1(107.57,68.96) 107.82,68.71 R425.1
SPI_CS3_N: length 144.8
  TOP w0.127: v1(271.02,136.65) 271.02,138.81 271.77,139.56 U100.1 271.77,140.32 272.03,140.59 274.32,140.59 274.56,140.35 U101.1 ; v1(157.73,88.52) 157.19,88.52 157.06,88.65 U18.12
  L6SIG w0.102: v1(157.73,88.52) 159.13,87.12 164.72,87.12 166.88,84.96 195.33,84.96 230.38,120.02 253.11,120.02 268.99,135.89 270.26,135.89 v1(271.02,136.65)
SPI_CS3_SEL: length 255.5
  TOP w0.127: U65.P9 65.02,100.92 v1(65.52,100.42) ; U100.2 272.42,139.06 272.92,138.56 R860.1 273.43,137.79 273.43,136.4 272.67,135.64 269.88,135.64 268.61,136.91 266.45,136.91 v1(266.06,137.29)
  L6SIG w0.102: v1(65.52,100.42) 66.02,99.92 66.02,98.07 71.98,92.1 71.98,88.52 76.2,84.3 76.2,83.06 77.6,81.66 80.65,81.66 81.15,82.17 83.31,82.17 84.07,81.41 84.07,80.26 84.84,79.5 86.87,79.5 87.76,78.61 102.74,78.61 103.18,79.04 112.6,79.04 114.05,77.6 145.05,77.6 156.48,89.03 157.92,89.03 158.2,88.75 159.11,88.75 159.51,89.15 159.89,89.15 160.02,89.03 161.16,89.03 161.42,89.28 162.43,89.28 162.81,88.9 165.35,88.9 167.64,86.61 172.08,86.61 176.78,91.31 199.33,91.31 229.81,121.79 241.3,121.79 254.89,135.38 264.16,135.38 v1(266.06,137.29)
SPI_MISO: length 214.3
  TOP w0.127: v1(162.18,88.52) 162.18,88.77 161.94,89.02 U12.12 ; R449.1 105.66,68.2 v1(105.41,68.45) 105.41,69.85 108.59,73.03 121.67,73.03 125.86,77.22 144.4,77.22 149.61,82.42 157.1,82.42 159.26,84.58 v1(159.26,88.14) ; R58.1 R54.1 v1(254.63,130.68) 269.62,130.68 272.54,133.6 274.83,133.6 277.11,135.89 R868.2
  L6SIG w0.102: v1(162.18,88.52) 162.31,88.39 165.1,88.39 167.51,85.98 194.69,85.98 230,121.29 241.55,121.29 250.95,130.68 v1(254.63,130.68)
  BOTTOM w0.127: v1(105.41,68.45) 105.79,68.07 105.79,67.82 105.78,67.81 R419.1 ; v1(162.18,88.52) 161.92,88.77 160.91,88.77 160.53,89.15 159.46,89.15 159.26,88.95 v1(159.26,88.14)
SPI_MOSI: length 205.1
  TOP w0.127: v1(161.42,88.14) 161.24,88.32 U12.11 ; v1(271.53,137.54) 271.53,136.52 271.15,136.14 270,136.14 269.49,136.65 R866.1 v1(268.74,137.55) ; R453.1 106.68,68.2 v1(106.93,68.45) 106.93,70.74 108.84,72.64 122,72.64 126.19,76.84 144.53,76.84 149.73,82.04 157.35,82.04 159.77,84.45 v1(159.77,88.65)
  L6SIG w0.102: v1(268.74,137.55) 268.36,137.55 251.84,121.03 230.07,121.03 194.76,85.73 167.39,85.73 165.1,88.01 161.54,88.01 v1(161.42,88.14)
  BOTTOM w0.127: v1(161.42,88.14) 160.98,88.14 160.47,88.65 v1(159.77,88.65) ; R423.1 106.81,68.33 v1(106.93,68.45) ; R869.2 v1(271.53,137.54)
SYS_REFCLK: length 85
  TOP w0.127: v1(90.3,101.73) 90.29,101.72 R513.2 R511.2 ; U1.G15 v2(159.72,114.85)
  BOTTOM w0.127: v1(90.3,101.73) 92.08,103.51 92.08,112.57 95.46,115.95 112.69,115.95 114.21,117.48 147.11,117.48 149.61,114.97 154.65,114.97 155.17,114.45 159.31,114.45 159.71,114.85 v2(159.72,114.85)
SYS_REFCLK_N: length 84.6
  TOP w0.102: v1(227.84,135.33) 228.12,135.61 230.12,135.61 230.37,135.36 R838.1 230.75,135.51 231.02,135.51 R837.2 ; U1.F14 v2(158.92,113.25)
  L3SIG w0.102: v2(158.92,113.25) 159.3,112.87 159.87,112.87 160.1,113.09 160.1,113.47 160.54,113.92 171.58,113.92 171.81,114.15 178.69,114.15 184.68,120.14 214.01,120.14 226.85,132.98 226.85,134.83 227.34,135.33 v1(227.84,135.33)
SYS_REFCLK_P: length 84.7
  TOP w0.102: U1.G14 v2(159.72,113.25) ; R836.2 231.02,136.02 230.75,136.02 R835.1 230.37,136.14 230.12,135.89 228.12,135.89 v1(227.84,136.17)
  L3SIG w0.102: v2(159.72,113.25) 159.47,113.25 159.36,113.35 159.36,113.69 159.47,113.79 160.02,113.79 160.43,114.2 171.46,114.2 171.69,114.43 178.57,114.43 184.57,120.42 213.89,120.42 226.57,133.1 226.57,134.95 227.33,135.71 227.33,136.07 227.43,136.17 v1(227.84,136.17)
SYSCLK_OE: length 16.6
  TOP w0.127: U65.M15 71.02,102.93 71.52,102.42 72.58,102.42 74.93,100.08 74.93,97.54 77.85,94.62 81.48,94.62 X3.1
T2081_DET_N: length 430.2
  TOP w0.127: v2(177.04,124.97) 177.04,124.17 U1.AH27 ; U65.P4 v1(59.51,100.42)
  L6SIG w0.102: v2(177.04,124.97) 179.07,124.97 184.45,130.35 199.59,130.35 200.66,129.29 214.76,129.29 215.77,130.3 239.39,130.3 243.08,133.98 243.08,137.92 259.97,154.81 267.59,154.81 269.75,152.65 272.54,152.65 276.35,148.84 276.35,145.16 278,143.51 278,82.72 274.28,78.99 228.35,78.99 226.44,77.09 214.97,77.09 210.52,72.64 192.62,72.64 191.85,71.88 188.98,71.88 186.31,74.55 183.26,74.55 182.12,75.69 167.64,75.69 167.26,76.07 154.56,76.07 153.29,74.8 94.36,74.8 93.6,75.57 77.09,75.57 75.82,76.84 72.39,76.84 70.61,78.61 70.61,83.19 68.71,85.09 68.71,89.66 60.01,98.36 60.01,99.92 v1(59.51,100.42)
  BOTTOM w0.127: R185.1 60.21,98.92 60.01,99.12 60.01,99.92 v1(59.51,100.42)
T2081_EN: length 198.8
  TOP w0.127: R141.2 206.12,84.33 v1(206.9,83.55) U27.9 ; U65.R9 65.02,99.92 v1(65.52,99.42) ; R692.1 48.13,115.7 49.02,116.59 v1(51.05,116.59)
  L6SIG w0.102: v1(51.05,116.59) 54.48,116.59 55.5,115.57 55.5,113.01 55.75,112.75 55.75,112.03 55.85,111.93 58.71,111.93 59.21,111.43 59.21,102.52 59.81,101.92 60.91,101.92 61.71,101.12 64.72,101.12 65.02,100.82 65.02,100.12 65.52,99.62 v1(65.52,99.42) 65.52,98.19 71.76,91.95 71.76,88.27 75.18,84.84 75.18,83.69 77.47,81.41 80.77,81.41 81.28,81.92 83.19,81.92 83.82,81.28 83.82,80.14 84.71,79.25 86.74,79.25 87.63,78.36 102.87,78.36 103.12,78.11 110.36,78.11 111.12,77.34 152.27,77.34 153.54,78.61 186.94,78.61 189.74,75.82 197.48,75.82 200.53,78.87 204.22,78.87 206.9,81.55 v1(206.9,83.55)
  BOTTOM w0.127: U27.9 v1(206.9,83.55)
TDMA_RCK_CLK8_12: length 149.3
  TOP w0.127: J43.21 273.92,151.74 v1(271.15,148.97) ; U1.M4 v2(163.72,105.25)
  L6SIG w0.102: v1(271.15,148.97) 268.73,148.97 267.64,150.06 265.7,150.06 264.69,149.06 264.69,148.23 263.88,147.42 263.88,146.83 263.88,146.83 263.88,144.5 256.54,137.16 254.13,137.16 240.54,123.57 229.24,123.57 198.65,92.99 174.98,92.99 173.18,94.79 168.56,94.79 167.84,95.51 167.84,95.85 167.84,95.85 167.84,96.44 164.1,100.19 164.1,104.87 v2(163.72,105.25)
TDMA_RQ: length 142.6
  TOP w0.127: U1.R2 v2(166.92,103.65) ; J43.3 v1(274.47,157.46)
  L3SIG w0.102: v1(263.4,152.4) 263.4,152.78 268.08,157.46 v1(274.47,157.46)
  L6SIG w0.102: v2(166.92,103.65) 167.3,103.27 167.3,102.58 169.54,100.33 169.54,99.57 170.43,98.68 174.62,98.68 177.16,96.14 198.12,96.14 228.35,126.37 239.65,126.37 254.25,140.97 256.67,140.97 260.73,145.03 260.73,148.34 261.75,149.35 261.75,150.11 263.4,151.76 v1(263.4,152.4)
TDMA_RSYNC: length 136.3
  TOP w0.127: U1.U1 v2(168.52,102.85) ; J43.11 275.19,154.92 v1(274.32,154.05)
  L3SIG w0.102: v1(274.32,154.05) 274.32,153.67 271.91,151.26 261.37,151.26 v1(260.22,150.11)
  L6SIG w0.102: v1(260.22,150.11) 260.22,149.35 259.59,148.72 259.59,147.45 239.27,127.13 227.96,127.13 198.12,97.28 177.55,97.28 175.06,99.77 172.77,99.77 172.08,100.46 170.9,100.46 v2(168.52,102.85)
TDMA_RXD: length 135.7
  TOP w0.127: J43.13 275.57,154.28 275.08,153.8 v1(275.08,153.54) ; U1.U2 v2(168.52,103.65)
  L3SIG w0.102: v1(259.59,149.35) 260.22,149.35 261.75,150.88 272.42,150.88 v1(275.08,153.54)
  L6SIG w0.102: v1(259.59,149.35) 259.21,148.97 259.21,147.45 239.14,127.38 227.84,127.38 198.12,97.66 177.67,97.66 174.5,100.84 171.32,100.84 v2(168.52,103.65)
TDMA_TCK_CLK9: length 146.3
  TOP w0.127: U1.P4 v2(165.32,105.25) ; J43.17 274.04,153.01 v1(271.4,150.37)
  L6SIG w0.102: v2(165.32,105.25) 165.73,104.83 165.73,102.87 165.61,102.74 165.61,100.58 169.06,97.13 170.97,97.13 171.5,96.6 173.28,96.6 175.39,94.49 198.25,94.49 228.85,125.09 240.16,125.09 253.75,138.68 256.16,138.68 262.38,144.91 262.38,147.83 263.47,148.92 263.47,149.68 265.18,151.38 268.22,151.38 268.48,151.13 270.64,151.13 v1(271.4,150.37)
TDMA_TSYNC: length 142.4
  TOP w0.127: U1.R1 v2(166.92,102.85) ; v1(273.81,154.81) 274.55,155.55 J43.9
  L3SIG w0.102: v1(264.29,152.4) 265.43,153.54 268.99,153.54 269.49,153.03 272.98,153.03 273.81,153.87 v1(273.81,154.81)
  L6SIG w0.102: v2(166.92,102.85) 166.92,102.45 168.53,100.84 168.53,99.57 169.77,98.32 174.47,98.32 177.04,95.76 198.12,95.76 228.47,126.11 239.78,126.11 253.36,139.7 255.78,139.7 261.11,145.03 261.11,148.21 262.25,149.35 262.25,150.11 264.29,152.15 v1(264.29,152.4)
TDMA_TXD: length 140.5
  TOP w0.127: J43.7 v1(275.23,156.19) ; U1.T1 v2(167.72,102.85)
  L3SIG w0.102: v1(275.23,156.19) 274.57,156.84 267.97,156.84 263.86,152.73 263.86,152.22 263.53,151.89 v1(262.76,151.89)
  L6SIG w0.102: v2(167.72,102.85) 167.72,102.67 170.56,99.82 170.56,99.44 170.94,99.06 174.75,99.06 177.29,96.52 198.12,96.52 228.22,126.62 239.52,126.62 254.13,141.22 256.41,141.22 260.35,145.16 260.35,148.46 261.24,149.35 261.24,150.37 v1(262.76,151.89)
TDMB_RCK_CLK10: length 146
  TOP w0.127: v1(273.94,148.59) 274.55,149.2 J43.29 ; U1.P3 v2(165.32,104.45)
  L6SIG w0.102: v1(273.94,148.59) 272.64,149.89 271.22,149.89 270.38,150.72 268.25,150.72 268.1,150.88 265.3,150.88 263.88,149.45 263.88,148.63 262.89,147.64 262.89,144.78 256.29,138.18 253.87,138.18 240.28,124.59 228.98,124.59 198.37,93.98 175.26,93.98 173.05,96.19 168.99,96.19 168.66,96.52 168.66,96.9 165.1,100.46 165.1,102.87 165.32,103.09 v2(165.32,104.45)
TDMB_RQ: length 136.7
  TOP w0.127: U1.R4 v2(166.92,105.25) ; v1(265.68,151.89) 266.47,151.11 J43.24
  L6SIG w0.102: v1(265.68,151.89) 265.05,151.89 263.07,149.91 263.07,149.36 263.07,149.35 263.07,149.15 261.87,147.96 261.87,145.03 256.03,139.19 253.62,139.19 240.03,125.6 228.73,125.6 198.12,95 176.78,95 174.24,97.54 169.29,97.54 166.12,100.71 166.12,104.45 v2(166.92,105.25)
TDMB_RSYNC: length 131.7
  TOP w0.127: v1(266.57,152.91) 266.68,153.01 J43.18 ; U1.T3 v2(167.72,104.45)
  L6SIG w0.102: v2(167.72,104.45) 167.72,104.19 168.14,103.77 168.14,102.63 170.64,100.13 171.91,100.13 172.59,99.44 174.88,99.44 177.42,96.9 198.12,96.9 228.09,126.87 239.39,126.87 254,141.48 256.2,141.48 259.97,145.25 259.97,148.59 260.73,149.35 260.73,150.62 263.02,152.91 v1(266.57,152.91)
TDMB_RXD: length 138
  TOP w0.127: J43.1 v1(275.23,158.09) ; U1.U4 v2(168.52,105.25)
  L3SIG w0.102: v1(275.23,158.09) 268.2,158.09 263.4,153.29 v1(262,153.29)
  L6SIG w0.102: v1(262,153.29) 258.44,149.73 258.44,147.45 238.89,127.89 227.58,127.89 197.99,98.3 178.05,98.3 174.75,101.6 171.59,101.6 168.91,104.28 168.91,104.85 v2(168.52,105.25)
TDMB_TCK_CLK11: length 151
  TOP w0.127: v1(274.19,145.8) 275.08,145.8 275.31,146.03 J43.39 ; U1.N4 v2(164.52,105.25)
  L6SIG w0.102: v1(274.19,145.8) 274.7,146.3 274.7,147.83 274.37,148.16 273.61,148.16 272.29,149.48 268.86,149.48 267.87,150.47 265.53,150.47 264.29,149.22 264.29,148.46 263.4,147.57 263.4,144.65 256.41,137.67 254,137.67 240.41,124.08 229.11,124.08 198.42,93.4 175.21,93.4 173.41,95.2 168.73,95.2 168.25,95.68 168.25,96.67 164.59,100.33 164.59,103 164.94,103.34 164.94,104.83 v2(164.52,105.25)
TDMB_TSYNC: length 135
  TOP w0.127: U1.R3 v2(166.92,104.45) ; v1(266.57,151.89) 266.72,151.74 J43.22
  L6SIG w0.102: v1(266.57,151.89) 266.06,152.4 265.05,152.4 262.64,149.99 262.64,149.22 261.47,148.06 261.47,145.01 255.91,139.45 253.49,139.45 239.9,125.86 228.6,125.86 198.12,95.38 176.91,95.38 174.37,97.92 169.67,97.92 168.15,99.44 168.15,99.92 167.56,100.51 167.56,101.3 166.5,102.36 166.5,104.03 v2(166.92,104.45)
TDMB_TXD: length 130
  TOP w0.127: J43.20 267.23,152.38 v1(267.21,152.4) ; U1.T4 v2(167.72,105.25)
  L6SIG w0.102: v2(167.72,105.25) 168.13,104.83 168.13,104.25 168.36,104.03 168.67,104.03 171.48,101.22 174.62,101.22 177.8,98.04 198.12,98.04 227.71,127.64 239.01,127.64 258.83,147.45 258.83,149.35 262.89,153.42 266.8,153.42 267.21,153.01 v1(267.21,152.4)
TDMR1_INT_N: length 260.6
  TOP w0.127: J43.31 275.06,148.57 v1(274.19,147.7) ; v1(266.45,148.34) 266.19,148.59 R850.2 ; v1(68.52,99.42) 68.02,99.92 U65.R12
  L6SIG w0.102: v1(274.19,147.7) 267.08,147.7 v1(266.45,148.34) 265.63,147.52 265.63,144.86 256.92,136.14 254.51,136.14 240.92,122.56 229.53,122.56 199.05,92.08 176.02,92.08 171.32,87.38 168.02,87.38 164.21,91.19 161.15,91.19 160.13,90.17 159.4,90.17 159.26,90.3 158.71,90.86 156.19,90.86 143.7,78.36 118.45,78.36 113.88,82.93 112.52,82.93 112.27,82.68 110.62,82.68 110.36,82.93 104.82,82.93 102.79,80.9 89.54,80.9 89.28,81.15 87.63,81.15 83.82,84.96 78.74,84.96 76.33,87.38 76.33,94.74 75.06,96.01 70.1,96.01 68.52,97.6 v1(68.52,99.42)
TDMR2_INT_N: length 263.6
  TOP w0.127: U65.P11 67.02,100.92 v1(67.52,100.42) ; J43.33 275.31,147.93 v1(274.19,146.81) ; R851.2 266.32,147.57 v1(266.45,147.45)
  L6SIG w0.102: v1(67.52,100.42) 68.02,99.92 68.02,97.72 69.98,95.76 74.87,95.76 76.07,94.56 76.07,87.25 78.61,84.71 83.57,84.71 85.98,82.3 85.98,81.66 88.27,79.38 92.71,79.38 93.98,80.65 102.89,80.65 104.95,82.7 110.21,82.7 110.49,82.42 112.4,82.42 112.65,82.68 113.77,82.68 118.34,78.11 144.82,78.11 156.63,89.92 159.89,89.92 160.32,89.48 160.86,89.48 162.31,90.93 164.08,90.93 167.89,87.12 171.58,87.12 176.28,91.82 199.16,91.82 229.64,122.3 241.05,122.3 254.64,135.89 257.94,135.89 265.94,143.89 265.94,146.94 v1(266.45,147.45) 266.57,147.32 273.69,147.32 v1(274.19,146.81)
TDMR_PRS_N: length 262.1
  TOP w0.127: U65.P12 68.02,100.92 v1(68.52,100.42) ; v1(272.67,148.21) 274.3,149.84 J43.27 ; v1(266.45,149.22) 266.45,149.35 266.19,149.61 R849.2
  L6SIG w0.102: v1(68.52,100.42) 69.02,99.92 69.02,97.48 70.23,96.27 75.18,96.27 76.58,94.87 76.58,88.65 78.87,86.36 82.93,86.36 87.86,81.43 89.51,81.43 89.79,81.15 102.68,81.15 105.2,83.67 113.5,83.67 118.55,78.61 143.59,78.61 156.06,91.08 158.81,91.08 159.49,90.4 160.04,90.4 161.08,91.44 164.34,91.44 168.15,87.63 171.07,87.63 175.77,92.33 198.95,92.33 229.43,122.81 240.79,122.81 254.38,136.4 256.79,136.4 265.33,144.93 265.33,147.7 265.56,147.93 265.56,148.34 v1(266.45,149.22) 267.59,148.08 272.54,148.08 v1(272.67,148.21)
TDMR_RST_N: length 261.5
  TOP w0.127: R852.2 v1(266.45,146.56) ; U65.R11 67.02,99.92 v1(67.52,99.42) ; v1(273.56,146.3) 274.45,146.3 275.44,147.3 J43.35
  L6SIG w0.102: v1(273.56,146.3) 272.92,146.94 266.83,146.94 v1(266.45,146.56) 266.45,144.02 258.06,135.64 254.76,135.64 241.17,122.05 229.74,122.05 199.26,91.57 176.53,91.57 171.83,86.87 167.77,86.87 164.72,89.92 161.67,89.92 161.01,89.26 160.17,89.26 160.02,89.41 159.39,89.41 158.95,88.98 158.29,88.98 157.99,89.28 156.35,89.28 144.92,77.85 118.24,77.85 114.43,81.66 110.87,81.66 110.06,82.47 105.08,82.47 103,80.39 94.23,80.39 92.96,79.12 88.01,79.12 85.6,81.53 85.6,82.17 83.31,84.45 78.49,84.45 75.82,87.12 75.82,94.36 74.68,95.5 69.85,95.5 67.52,97.84 v1(67.52,99.42)
TDMR_SLP_N: length 259.9
  TOP w0.127: U65.R13 69.02,99.92 v1(69.52,99.42) ; J43.25 273.54,150.47 v1(272.03,148.97)
  L6SIG w0.102: v1(69.52,99.42) 69.52,97.36 70.36,96.52 75.31,96.52 76.84,95 76.84,88.77 78.99,86.61 83.06,86.61 88.01,81.66 89.79,81.66 90.04,81.41 102.58,81.41 105.09,83.92 113.6,83.92 118.66,78.87 143.49,78.87 155.93,91.31 158.9,91.31 159.59,90.63 159.95,90.63 161.01,91.69 164.47,91.69 168.27,87.88 170.81,87.88 175.51,92.58 198.84,92.58 229.32,123.06 240.66,123.06 254.25,136.65 256.67,136.65 264.29,144.27 264.29,147.19 265.1,148.01 265.1,148.89 265.87,149.66 266.65,149.66 267.84,148.46 271.53,148.46 v1(272.03,148.97)
TDMR_SPI_CS0_N: length 12.1
  TOP w0.127: J43.32 267.82,148.57 267.34,148.08 267.34,145.54 269.88,143 272.42,143 273.06,142.35 U100.4
TDMR_SPI_CS1_N: length 13.5
  TOP w0.127: U101.4 275.86,142.35 274.83,143.38 270.13,143.38 267.72,145.8 267.72,147.7 267.95,147.93 J43.34
TEMP_DIODE_N: length 10.2
  TOP w0.254: U1.G21 v2(159.72,119.65)
  BOTTOM w0.127: 155.92,119.72 155.96,119.72 156.02,119.79 158.09,119.79 158.63,119.25 159.31,119.25 159.71,119.65 v2(159.72,119.65)
  BOTTOM w0.254: R206.1 151.15,120.29 154.28,120.29 154.86,119.72 155.92,119.72
TEMP_DIODE_P: length 9.2
  TOP w0.254: U1.E21 v2(158.92,119.65)
  BOTTOM w0.127: 155.92,120.08 155.96,120.08 156.02,120.01 158.18,120.01 158.55,119.65 v2(158.92,119.65)
  BOTTOM w0.254: 155.92,120.08 155,120.08 154.43,120.65 151.25,120.65 R205.1
TEST_SEL_N: length 154.9
  TOP w0.127: U1.G8 v2(159.72,108.45) ; SW3.8 107.06,138.43 106.81,138.68 102.23,138.68 101.35,139.57 97.03,139.57 95.89,138.43 95.89,136.27 93.98,134.37 89.15,134.37 86.61,131.83 86.61,127.89 86.87,127.63 86.87,127.13 86.49,126.75 86.49,125.48 86.23,125.22 86.23,122.05 74.11,109.93 73.03,109.93 v1(73.02,109.93) 73.02,109.93 U65.E16
  L6SIG w0.102: v1(73.02,109.93) 73.61,109.93 79.88,116.2 125.6,116.2 126.49,115.32 136.4,115.32 147.65,104.07 157.47,104.07 157.7,104.29 157.7,104.57 157.96,104.83 158.24,104.83 158.54,105.13 158.54,105.4 158.79,105.66 159.07,105.66 159.3,105.89 159.3,107.99 159.72,108.41 v2(159.72,108.45)
  BOTTOM w0.127: R83.1 73.52,110.43 v1(73.02,109.93)
THERM_ALERT_N: length 100.2
  TOP w0.127: U65.M4 v1(60.51,103.42)
  BOTTOM w0.127: R853.1 144.03,120.53 143.69,120.2 U45.6 137.6,120.2 135.89,118.49 113.79,118.49 112.27,116.97 95.04,116.97 91.06,112.99 91.06,109.73 90.55,109.22 75.95,109.22 74.3,107.57 69.98,107.57 67.56,109.98 62.61,109.98 61.01,108.38 61.01,103.92 v1(60.51,103.42)
THERM_FAULT_N: length 124.2
  TOP w0.127: v1(62.36,127.51) 61.59,126.75 D34.1 59.17,126.65 R204.1 59.17,124.45 57.4,122.68 56.01,122.68 55.5,122.17 55.5,112.44 57.01,110.93 U65.D1
  L3SIG w0.102: v1(62.36,127.51) 62.74,127.89 66.68,127.89 69.22,130.43 69.22,136.4 72.14,139.32 84.2,139.32 87.5,136.02 102.36,136.02 102.87,135.51 120.14,135.51 123.83,131.83 124.59,131.83 127.38,129.03 134.37,129.03 142.24,121.16 v1(145.8,121.16)
  BOTTOM w0.127: U45.4 146.26,119.55 145.8,120.02 v1(145.8,121.16)
UART1_CTS_N: length 47.9
  TOP w0.127: U40.12 171.8,83.78 169.54,81.53 164.97,81.53 160.15,76.71 151.64,76.71 146.3,71.37 139.19,71.37 138.42,70.6 U39.9
UART1_RTS_N: length 48.1
  TOP w0.127: U40.11 171.4,83.89 169.42,81.92 164.85,81.92 160.02,77.09 151.51,77.09 146.18,71.76 138.94,71.76 137.77,70.59 U39.10
UART1_RXD: length 48.4
  TOP w0.127: U40.9 170.6,84.11 169.16,82.68 164.59,82.68 159.77,77.85 151.26,77.85 145.92,72.52 138.43,72.52 136.47,70.56 U39.12
UART1_TXD: length 48.3
  TOP w0.127: U40.10 171,84 169.29,82.3 164.72,82.3 159.89,77.47 151.38,77.47 146.05,72.14 138.68,72.14 137.12,70.57 U39.11
UART2_CTS_N: length 49.6
  TOP w0.127: U42.12 167.22,90.77 166.37,89.92 166.37,84.96 159.64,78.23 151.13,78.23 145.8,72.9 132.97,72.9 131.31,71.24 U41.9
UART2_RTS_N: length 49.8
  TOP w0.127: U42.11 166.82,90.88 165.99,90.04 165.99,85.09 159.51,78.61 151,78.61 145.67,73.28 132.72,73.28 130.66,71.22 U41.10
UART2_RXD: length 50.2
  TOP w0.127: U42.9 166.02,91.09 165.23,90.3 165.23,85.34 159.26,79.38 150.75,79.38 145.41,74.04 132.21,74.04 129.36,71.19 U41.12
UART2_TXD: length 50
  TOP w0.127: U42.10 166.42,90.99 165.61,90.17 165.61,85.22 159.38,78.99 150.88,78.99 145.54,73.66 132.46,73.66 130.01,71.21 U41.11
USB1_DM: length 23.2
  TOP w0.102: v1(73.03,25.4) 73.29,25.66 U38.4
  BOTTOM w0.102: J41.6 68.8,12.01 68.9,12.11 68.9,12.82 68.51,13.21 67.31,13.21 66.7,13.82 66.7,15.46 67.95,16.71 67.95,20.39 71.79,24.23 72.92,24.23 73.03,24.33 v1(73.03,25.4) 73.67,26.05 73.67,27.15 73.44,27.38 L1.3 73.28,28.14 R168.2
USB1_DP: length 24.1
  TOP w0.102: U38.6 74.29,25.66 v1(74.55,25.4)
  BOTTOM w0.102: J41.7 69.23,12.01 69.13,12.11 69.13,12.91 68.61,13.44 67.4,13.44 66.93,13.91 66.93,15.37 68.17,16.61 68.17,20.29 71.88,24 73.02,24 73.25,24.24 73.25,24.63 73.52,24.89 74.04,24.89 v1(74.55,25.4) 73.9,26.05 73.9,27.15 74.14,27.38 L1.2 74.3,28.14 R167.2
USB1_FLG_N: length 5.3
  TOP w0.127: U37.2 61.34,32.26 62.22,33.14 R157.2 R159.1 63.51,34.99 Q3.1
USB1_PWREN: length 153.7
  TOP w0.127: U37.1 64.49,31.35 R162.2 65.41,31.38 66.42,32.38 66.42,34.8 v1(66.93,35.31) ; U1.F6 v2(158.92,106.85)
  L3SIG w0.102: v2(158.92,106.85) 158.5,106.43 158.5,105.05 158.27,104.83 157.91,104.83 157.74,104.65 157.74,102.68 158.24,102.18 158.24,98.43 155.04,95.22 152.37,95.22 151.13,93.98 151.13,89.28 143.26,81.41 132.33,81.41 123.7,72.77 123.7,45.47 113.28,35.05 67.18,35.05 v1(66.93,35.31)
USB1_VBUS: length 12.9
  TOP w0.254: U38.5 v1(73.79,25.4)
  L3SIG w0.508: v1(66.42,17.53) 66.42,19.69 70.74,24 73.03,24 73.79,24.77 v1(73.79,25.4)
USB1_VBUSCLMP: length 152.3
  TOP w0.127: D4.2 66.88,29.79 66.93,29.84 ; 66.93,29.84 R166.2 66.94,34.17 67.95,35.18 v1(67.95,35.56) ; 66.93,29.84 R164.1 ; U1.E4 v2(158.12,105.25)
  L3SIG w0.102: v2(158.12,105.25) 157.95,105.25 157.57,104.87 157.19,104.87 156.94,104.61 156.94,103.1 157.86,102.17 157.86,98.53 154.89,95.55 152.2,95.55 150.75,94.11 150.75,89.41 143.13,81.79 132.21,81.79 123.32,72.9 123.32,45.59 113.16,35.43 68.07,35.43 v1(67.95,35.56)
USB2_DM: length 20.2
  TOP w0.102: U96.4 75.83,25.66 v1(75.57,25.4)
  BOTTOM w0.102: R170.2 75.82,28.14 L2.3 75.98,27.38 76.2,27.16 76.2,26.93 76.2,26.03 v1(75.57,25.4) 75.57,23.62 75.18,23.24 72.14,23.24 68.9,20.01 68.9,14.73 68.8,14.63 J41.2
USB2_DP: length 21.1
  TOP w0.102: v1(77.09,25.4) 76.83,25.66 U96.6
  BOTTOM w0.102: R169.2 76.84,28.14 L2.2 76.68,27.38 76.43,27.13 76.43,26.06 v1(77.09,25.4) 77.06,25.4 76.56,24.89 76,24.89 75.79,24.69 75.79,23.53 75.28,23.01 72.23,23.01 69.13,19.91 69.13,14.73 69.23,14.63 J41.3
USB2_FLG_N: length 4.9
  TOP w0.127: Q4.1 59.17,34.63 R160.2 59.18,33.54 R158.1 60.07,33.41 U37.3
USB2_PWREN: length 165
  TOP w0.127: U1.J5 v2(161.32,106.05) ; U37.4 58.8,32.26 58.54,32.52 R161.2 56.63,32.52 v1(55.63,33.53)
  L3SIG w0.102: v2(161.32,106.05) 160.91,105.64 160.91,105.06 160.67,104.83 160.36,104.83 160.14,104.6 160.14,98.41 159.13,97.41 159.13,96.01 157.35,94.23 152.91,94.23 152.27,93.6 152.27,88.9 143.64,80.26 132.71,80.26 124.84,72.39 124.84,45.09 113.67,33.91 66.42,33.91 65.79,34.54 56.64,34.54 v1(55.63,33.53)
USB2_VBUS: length 18.1
  TOP w0.254: U96.5 v1(76.33,25.4)
  L3SIG w0.508: v1(64.39,17.53) 65.15,16.76 66.93,16.76 67.44,17.27 67.44,19.43 71.12,23.11 74.68,23.11 76.33,24.77 v1(76.33,25.4)
USB2_VBUSCLMP: length 169.3
  TOP w0.127: U1.J4 v2(161.32,105.25) ; v1(57.15,31.5) 57.15,30.23 55.37,28.45 55.37,25.78 55.63,25.53 56.13,25.53 R165.2 R163.1 57.15,23.69 D3.2
  L3SIG w0.102: v1(57.15,31.5) 59.82,34.16 65.66,34.16 66.29,33.53 113.79,33.53 125.22,44.96 125.22,72.26 132.84,79.88 143.76,79.88 152.65,88.77 152.65,93.47 153.09,93.9 157.53,93.9 159.51,95.89 159.51,97.28 160.59,98.36 160.59,103.92 160.94,104.26 160.94,104.6 161.32,104.99 v2(161.32,105.25)
USB_REFCLK: length 103.7
  TOP w0.127: v1(91.06,88.52) R176.2 R175.2 ; U1.F8 v2(158.92,108.45)
  BOTTOM w0.127: v1(91.06,88.52) 92.58,90.04 92.58,112.35 95.67,115.44 112.9,115.44 114.42,116.97 146.9,116.97 149.4,114.46 154.4,114.46 154.81,114.05 159.61,114.05 160.11,113.55 160.11,108.97 159.98,108.84 159.31,108.84 v2(158.92,108.45)
VBH2: length 97.2
  TOP w0.508: 40.35,53.72 C689.2 ; C689.2 40.35,55.07 ; C689.2 41.69,55.07 ; C689.2 41.69,53.72 ; v1(98.43,70.99) R475.2 99.46,69.07 100.58,67.95 R479.2 ; R478.2 v1(77.72,68.33) ; v1(117.6,67.95) 118.11,67.44 R477.2
  L3SIG w0.508: v1(117.6,67.95) 115.06,67.95 114.43,67.31 104.27,67.31 102.87,68.71 100.71,68.71 v1(98.43,70.99) 96.14,68.71 81.03,68.71 80.65,69.09 78.49,69.09 v1(77.72,68.33) 76.33,68.33 72.01,72.64 62.74,72.64 53.47,63.37 50.8,63.37 47.37,59.94 v3(47.37,54.86)
VBL2: length 94.2
  TOP w0.508: 48.12,64.48 C691.2 ; C691.2 48.12,65.82 ; C691.2 49.47,65.82 ; C691.2 49.47,64.48 ; v1(119.51,67.95) 120.14,67.31 R476.2 ; 40.14,60.27 C689.1 ; C689.1 40.14,58.52 ; C689.1 41.9,58.52 ; C689.1 41.9,60.27 ; C692.2 49.47,74.71 ; C692.2 48.12,73.37 ; C692.2 49.47,73.37 ; C692.2 48.12,74.71 ; R474.2 v1(96.39,70.99)
  L3SIG w0.508: C691.2 50.7,67.06 54.86,67.06 61.59,73.79 72.77,73.79 76.33,70.23 81.41,70.23 81.79,69.85 95.25,69.85 v1(96.39,70.99) 97.41,72.01 99.19,72.01 101.22,69.98 117.48,69.98 v1(119.51,67.95)
VCORE: length 148.1
  TOP w0.305: U1.N18 v2(164.52,117.25) ; U1.P15 v2(165.32,114.85) ; U1.M19 v2(163.72,118.05) ; U1.L18 v2(162.92,117.25) ; U1.R16 v2(166.92,115.65) ; U1.M17 v2(163.72,116.45) ; U1.V17 v2(169.32,116.45) ; U1.P17 v2(165.32,116.45) ; U1.N20 v2(164.52,118.85) ; U1.M15 v2(163.72,114.85) ; U1.R14 v2(166.92,113.25) ; U1.R18 v2(166.92,117.25) ; U1.K19 v2(162.12,118.05) ; U1.P9 v2(165.32,109.25) ; U1.M13 v2(163.72,112.45) ; U1.V15 v2(169.32,114.85) ; U1.U18 v2(168.52,117.25) ; U1.V13 v2(169.32,112.45) ; U1.L20 v2(162.92,118.85) ; U1.P11 v2(165.32,110.85) ; U1.T19 v2(167.72,118.05) ; U1.L14 v2(162.92,113.25) ; U1.U16 v2(168.52,115.65) ; U1.N16 v2(164.52,115.65) ; U1.U20 v2(168.52,118.85) ; U1.P19 v2(165.32,118.05) ; U1.T17 v2(167.72,116.45) ; U1.T9 v2(167.72,109.25) ; U1.R12 v2(166.92,111.65) ; U1.V9 v2(169.32,109.25) ; U1.Y8 v2(170.92,108.45) ; U1.V19 v2(169.32,118.05) ; U1.K15 v2(162.12,114.85) ; U1.L12 v2(162.92,111.65) ; U1.P13 v2(165.32,112.45) ; U1.R20 v2(166.92,118.85) ; U1.Y11 v2(170.92,110.85) ; U1.K17 v2(162.12,116.45) ; U1.T13 v2(167.72,112.45) ; U1.N12 v2(164.52,111.65) ; U1.U14 v2(168.52,113.25) ; U1.N14 v2(164.52,113.25) ; U1.M9 v2(163.72,109.25) ; U1.Y9 v2(170.92,109.25) ; U1.L16 v2(162.92,115.65) ; U1.W14 v2(170.12,113.25) ; U1.T15 v2(167.72,114.85)
  TOP w0.508: v3(132.72,114.68) 132.47,114.93 R654.2
  L3SIG w0.508: 155.7,115.32 154.3,115.32 153.54,116.08 153.54,118.49 141.48,130.56 137.67,130.56 133.22,135 123.83,135 112.4,146.43 71.25,146.43 68.71,148.97 58.93,148.97 57.78,150.11 56.39,150.11 J11.2
  BOTTOM w0.457: C914.1 165.32,112.44 v2(165.32,112.45) ; C915.1 165.62,114.55 v2(165.32,114.85) ; v2(165.32,116.45) 165.52,116.65 C912.1 ; C913.1 165.61,117.75 v2(165.32,118.05)
  vias: v1(140.08,107.7) v1(140.08,106.81) v1(140.97,107.7) v1(140.97,106.81) v1(141.86,107.7) v1(141.86,106.81) v3(132.72,113.41) v3(132.72,112.14) v3(133.6,114.68) v3(133.6,113.41) v3(133.6,112.14) v3(133.6,110.87) v3(133.6,109.6) v3(133.6,108.33) v3(133.6,107.06) v3(133.6,105.79) v3(133.6,104.52) v3(134.49,114.68) v3(134.49,113.41) v3(134.49,112.14) v3(134.49,110.87) v3(134.49,109.6) v3(134.49,108.33) v3(134.49,107.06) v3(134.49,105.79) v3(134.49,104.52)
VCORE_EN: length 40.6
  TOP w0.127: U65.R14 v1(70.52,99.42)
  L6SIG w0.102: v1(97.28,83.31) 89.66,83.31 87.25,85.73 84.84,85.73 83.44,87.12 79.25,87.12 77.34,89.03 77.34,95.25 75.57,97.03 71.63,97.03 71.08,97.57 71.08,98.86 v1(70.52,99.42)
  BOTTOM w0.127: U70.12 97.29,83.32 v1(97.28,83.31) 97.28,83.32 96.39,83.32 R564.2
VCORE_HOT_N: length 48
  TOP w0.127: v1(64.52,100.42) 64.02,100.92 U65.P8
  L6SIG w0.102: v1(64.52,100.42) 64.52,100.12 65.02,99.62 65.02,98.31 71.5,91.82 71.5,88.14 74.93,84.71 74.93,83.57 77.6,80.9 J27.1
  BOTTOM w0.127: J27.1 83.57,80.01 87.12,80.01 88.27,81.15 92.46,81.15 92.96,81.66 96.01,81.66 96.27,81.92 96.27,82.16 R574.2 96.91,82.82 U70.11
VCORE_IRTN1A: length 5.1
  BOTTOM w0.254: R566.1 107.3,84.23 106.45,84.23 105.11,82.89 103.84,82.89 103.77,82.82 U70.30
VCORE_IRTN1B: length 5.6
  BOTTOM w0.254: U70.28 103.75,83.82 103.83,83.89 104.46,83.89 106.93,86.36 107.2,86.36 R591.1
VCORE_ISEN1A: length 5.1
  BOTTOM w0.254: U70.29 103.76,83.32 103.83,83.24 104.97,83.24 106.3,84.58 107.2,84.58 R565.1
VCORE_ISEN1B: length 5.5
  BOTTOM w0.254: U70.27 103.77,84.32 103.84,84.24 104.31,84.24 106.79,86.72 107.3,86.72 R590.1
VCORE_PGOOD: length 49.2
  TOP w0.127: v1(66.52,99.42) 66.02,99.92 U65.R10
  L6SIG w0.102: v1(97.79,79.88) 94.11,79.88 93.09,78.87 87.88,78.87 87,79.76 84.96,79.76 84.33,80.39 84.33,81.53 83.44,82.42 81.03,82.42 80.52,81.92 77.72,81.92 76.45,83.19 76.45,84.45 72.26,88.65 72.26,92.33 66.52,98.07 v1(66.52,99.42)
  BOTTOM w0.127: R563.2 97.28,79.5 97.66,79.88 v1(97.79,79.88) 98.81,79.88 99.46,80.54 U70.7
VCORE_PWM1A: length 12.7
  TOP w0.254: U69.26 v1(103.82,93.66)
  L6SIG w0.254: v1(98.17,86.61) 98.93,86.61 99.57,87.25 99.57,90.93 102.29,93.66 v1(103.82,93.66)
  BOTTOM w0.254: v1(98.17,86.61) 98.72,86.07 U70.17
VCORE_PWM1B: length 21.3
  TOP w0.254: U71.26 v1(103.82,103.82)
  L6SIG w0.254: v1(103.82,103.82) 103.31,103.82 101.6,102.11 101.6,94.11 98.87,91.38 v1(98.87,87.44)
  BOTTOM w0.254: U70.18 99.46,86.85 v1(98.87,87.44)
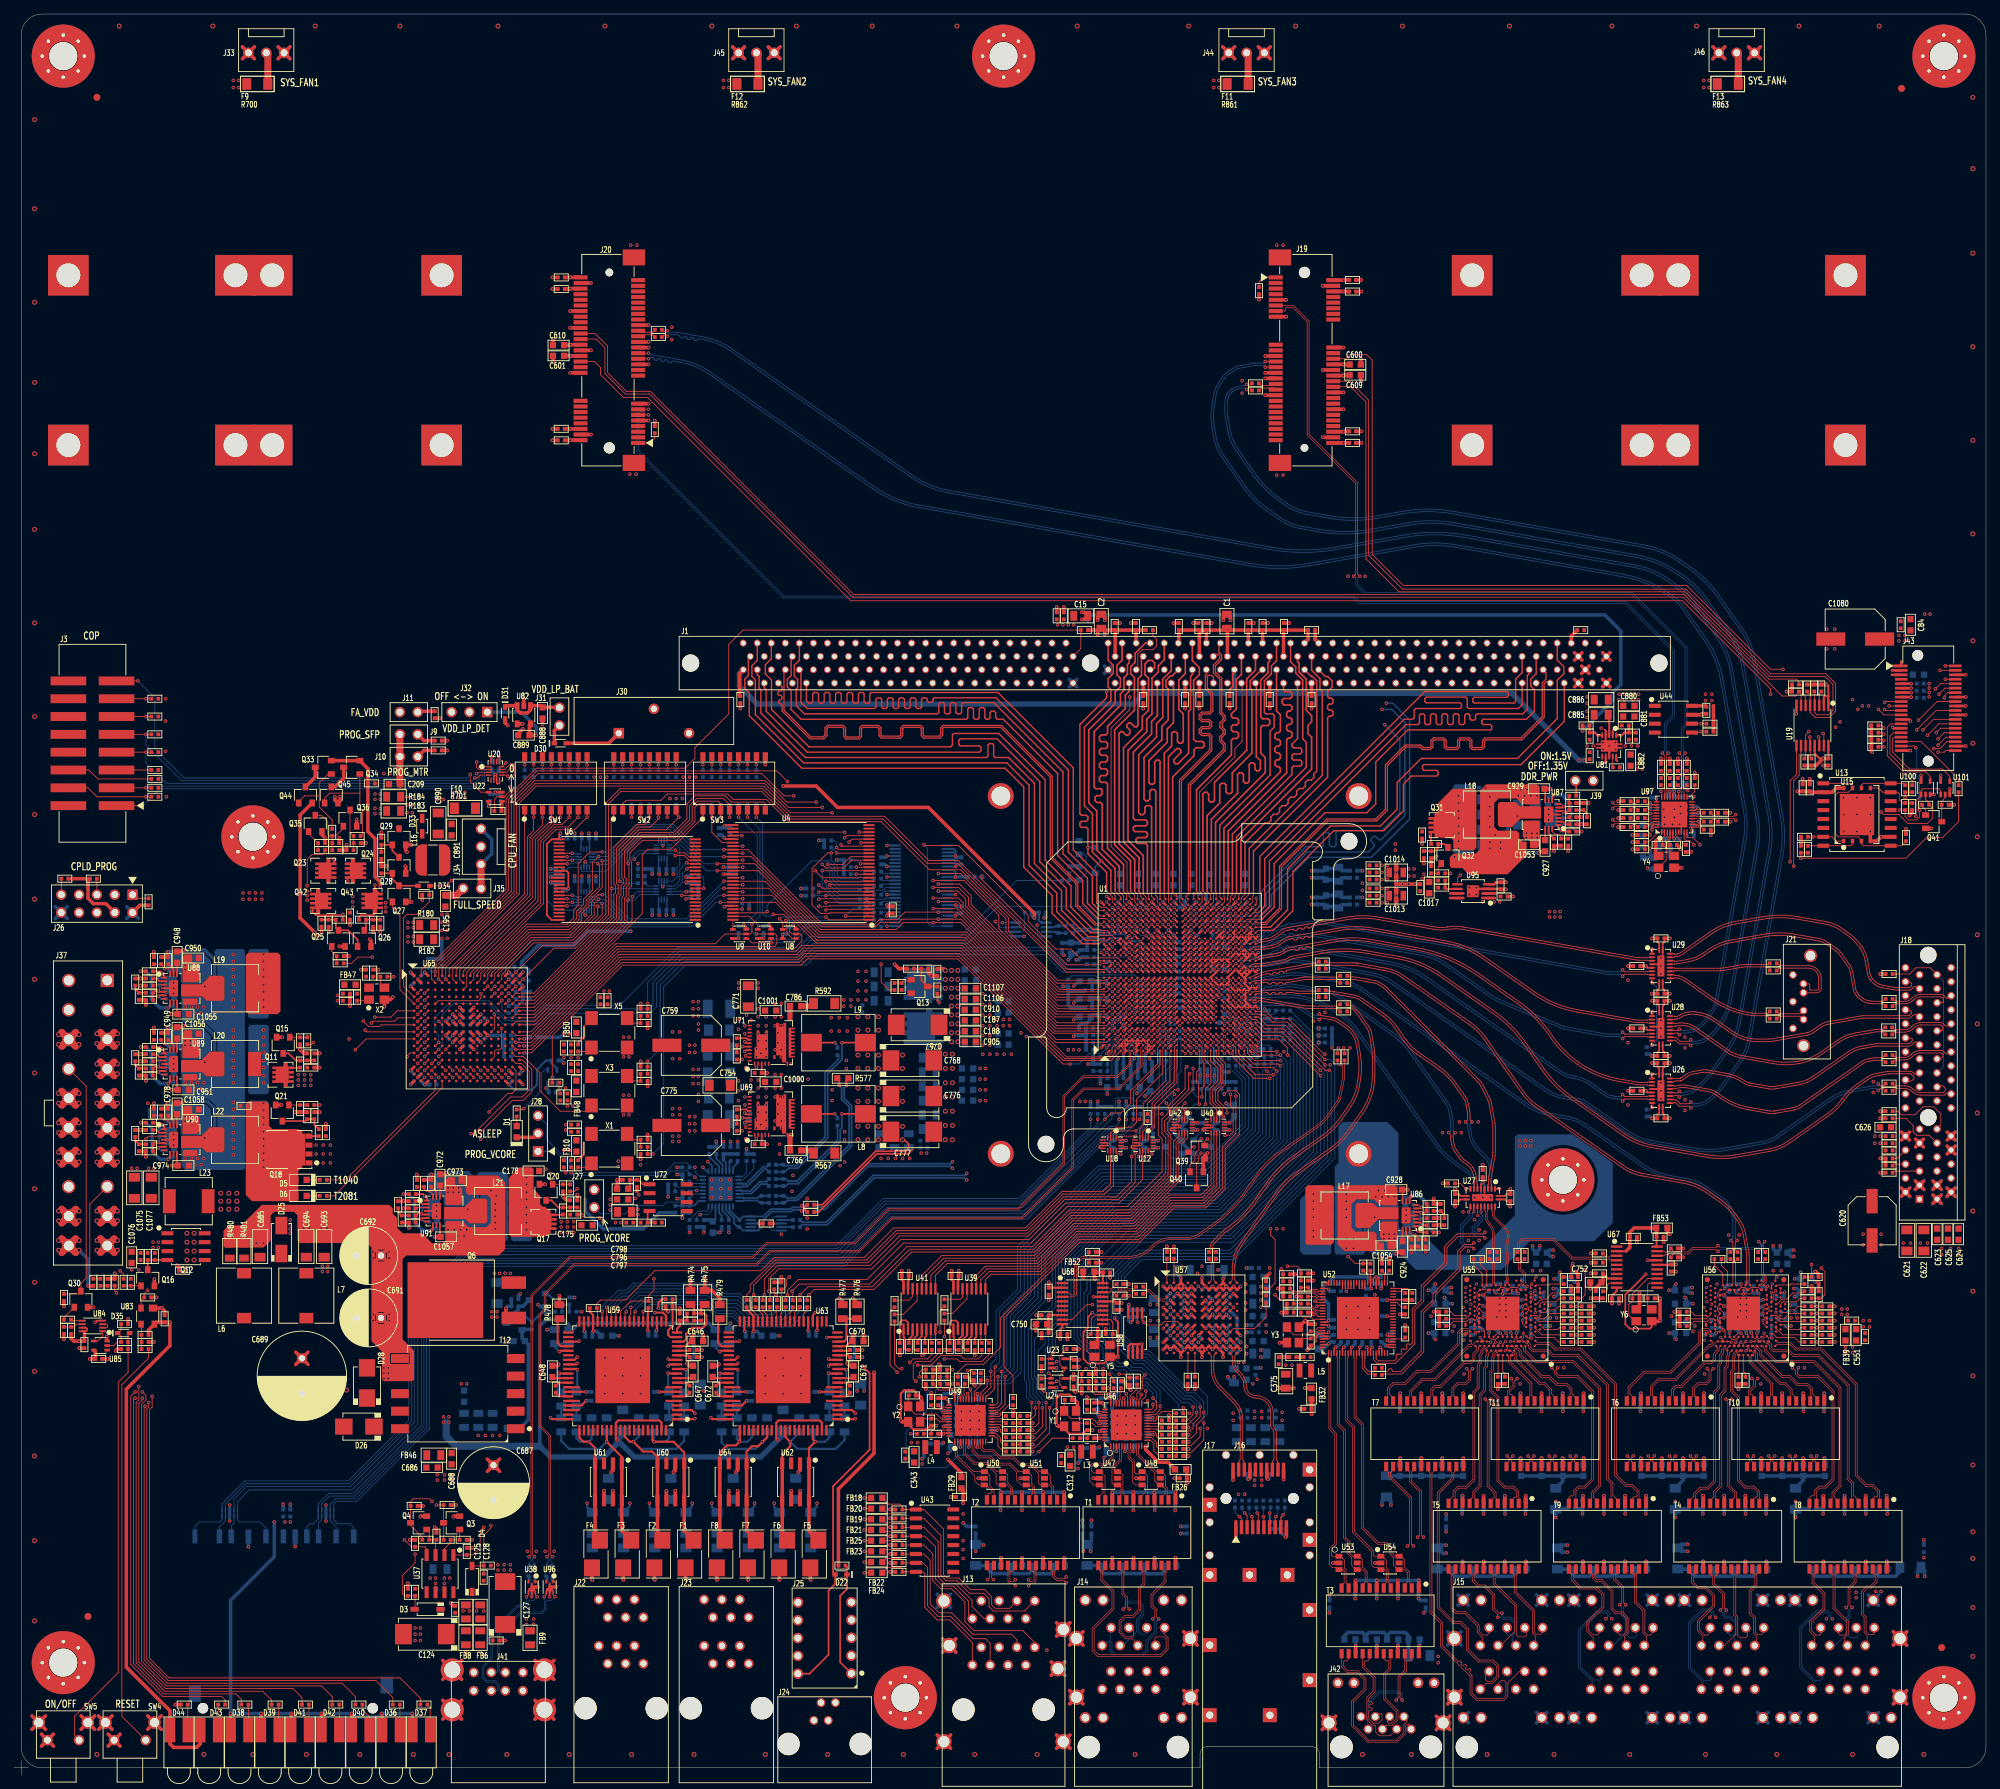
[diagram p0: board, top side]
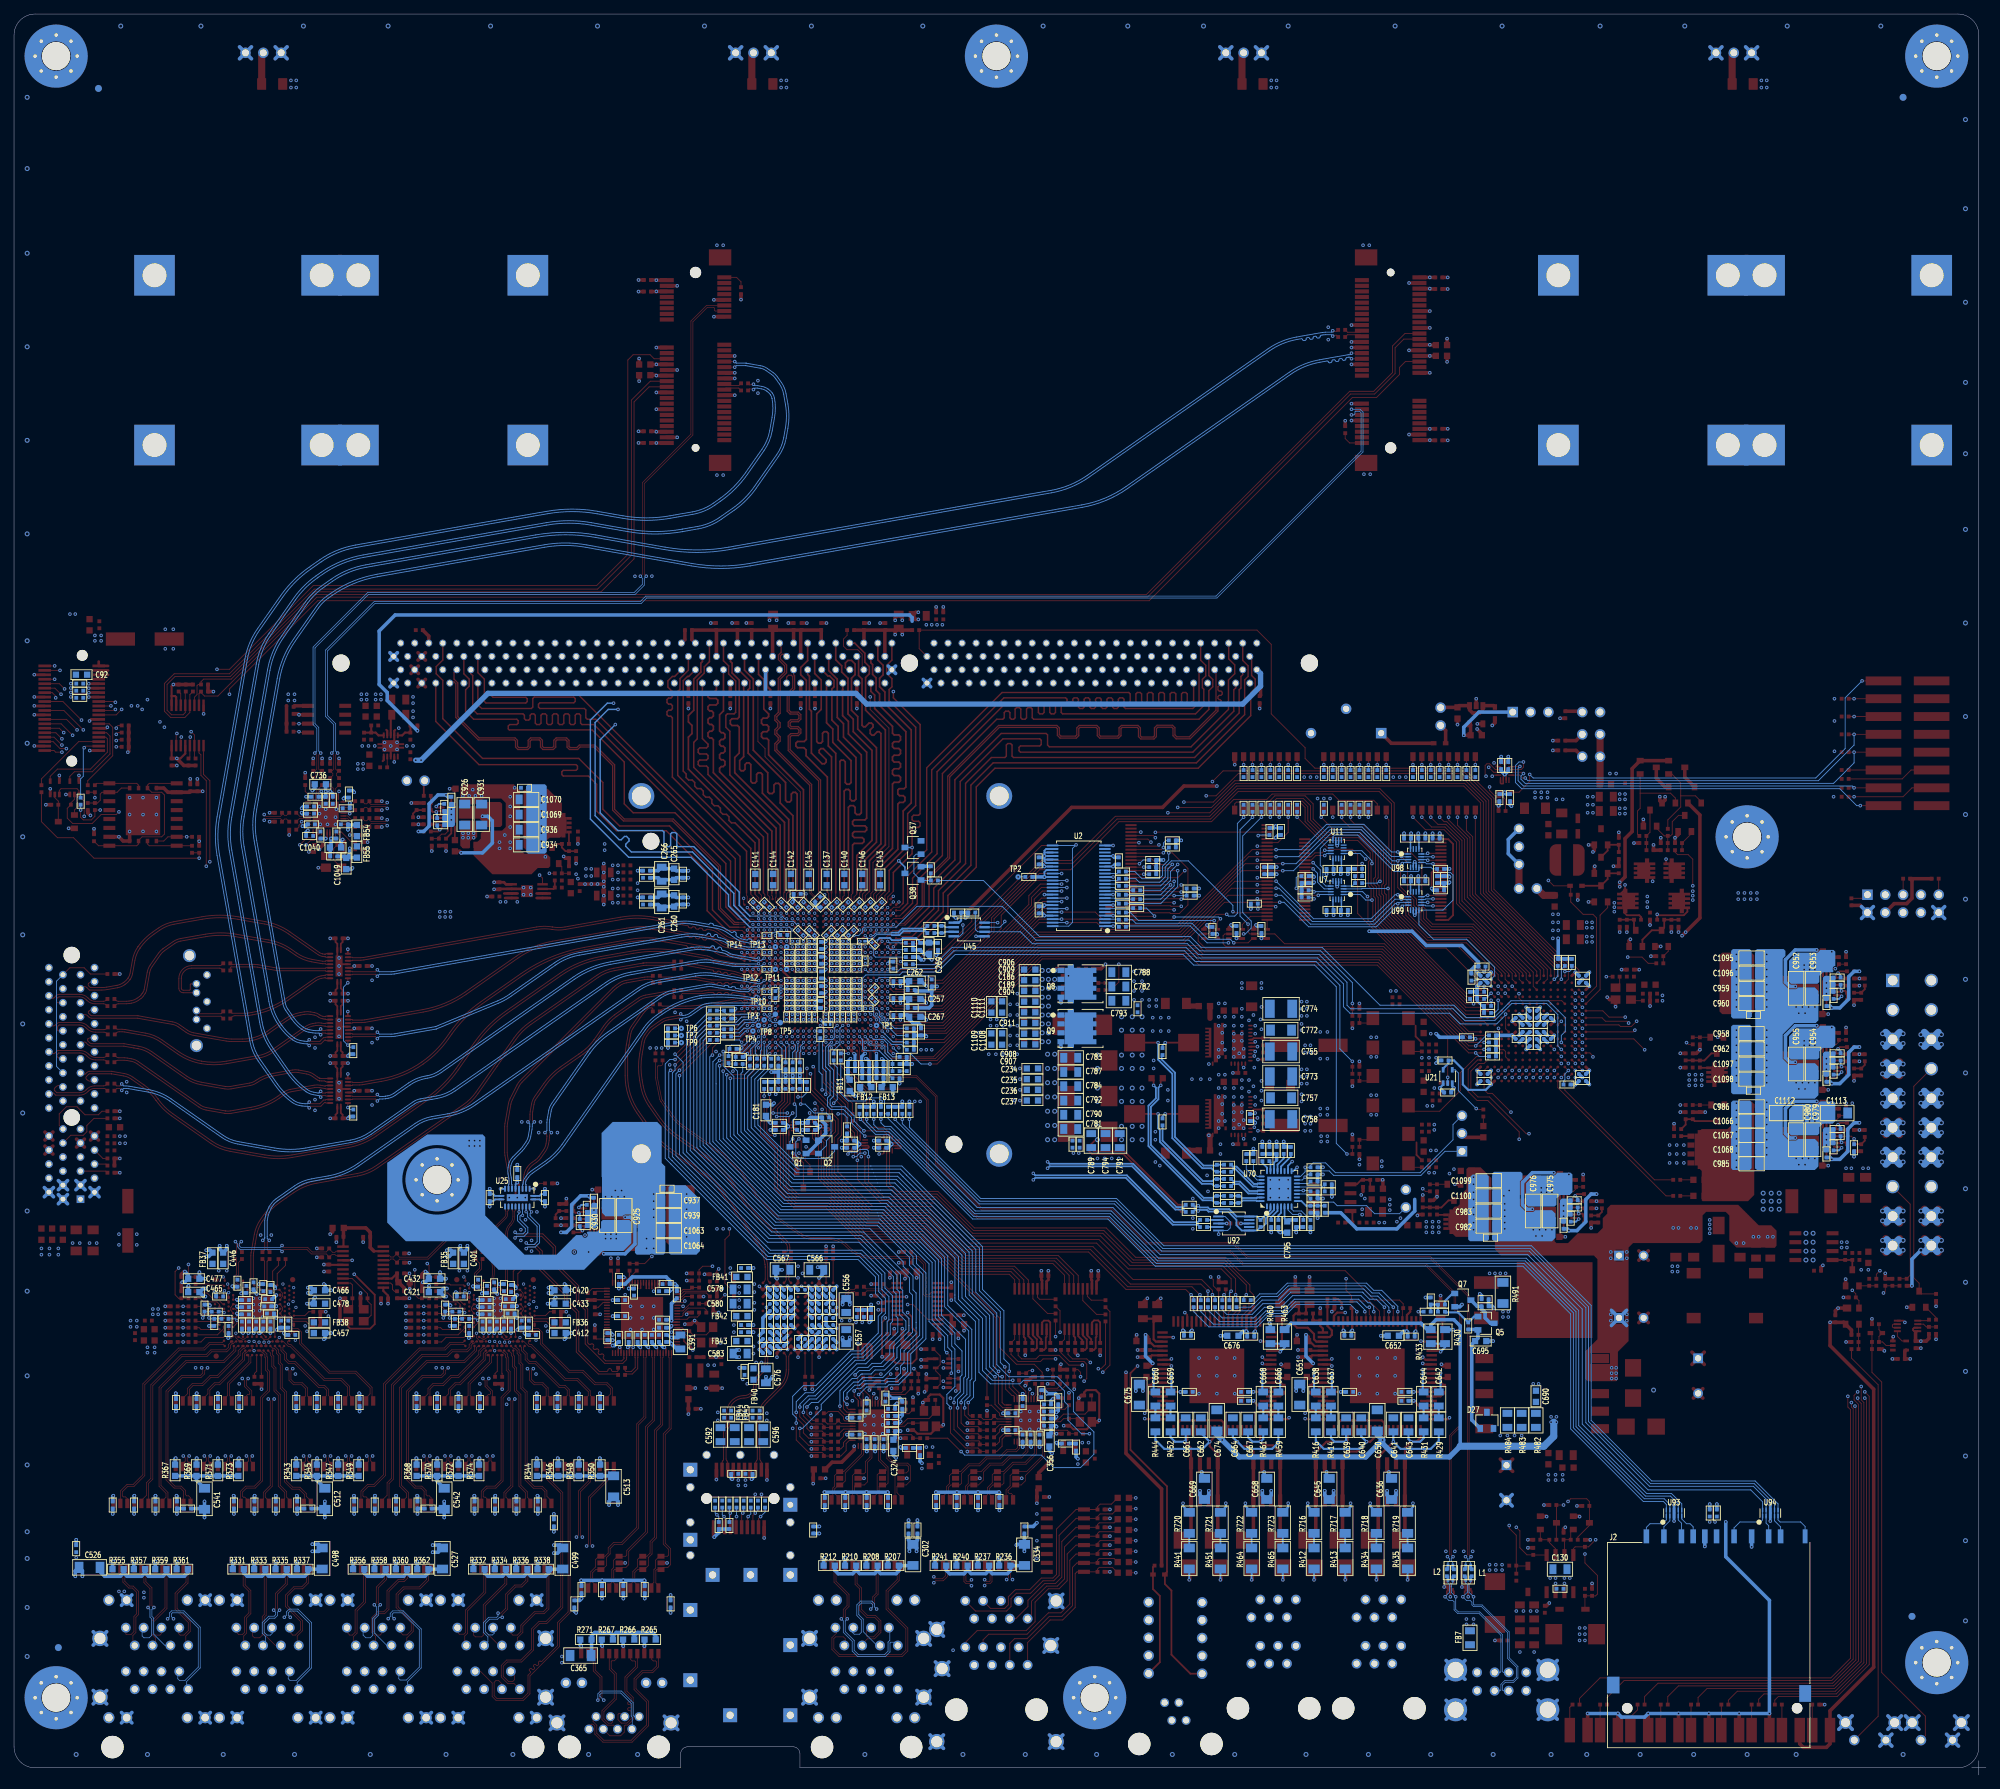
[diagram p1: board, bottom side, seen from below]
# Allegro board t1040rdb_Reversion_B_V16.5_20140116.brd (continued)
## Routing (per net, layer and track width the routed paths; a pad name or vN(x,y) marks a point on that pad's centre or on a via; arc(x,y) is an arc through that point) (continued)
VCORE_SLP: length 73.8
  TOP w0.254: L8.2 v1(117.98,94.23) ; L9.2 v1(117.98,104.39) ; v3(126.62,90.55) 126.87,90.55 127.51,89.92 127.51,89.28 127.13,88.9 122.78,88.9 115.16,81.28 R551.1
  TOP w0.305: U1.U10 v2(168.52,110.05) ; U1.V11 v2(169.32,110.85) ; U1.U12 v2(168.52,111.65) ; U1.R10 v2(166.92,110.05) ; U1.L10 v2(163.72,110.85) U1.M11 ; U1.W12 v2(170.12,111.65) ; U1.K13 v2(162.12,112.45) ; U1.K11 v2(162.12,110.85) ; U1.W10 v2(170.12,110.05) ; U1.T11 v2(167.72,110.85) ; U1.N10 v2(164.52,110.05)
  BOTTOM w0.254: v1(117.98,104.39) 117.98,101.98 115.95,99.95 115.95,90.77 111.66,86.49 110.36,86.49 109.92,86.05 109.66,86.05 C785.2 109.59,85.98 R591.2 ; R566.2 109.59,83.95 C765.2 109.99,83.95 110.31,84.27 111.73,84.27 117.73,90.27 117.73,91.95 117.98,92.2 v1(117.98,94.23)
  BOTTOM w0.457: C238.1 166.62,110.34 v2(166.92,110.05)
  BOTTOM w0.508: FB11.2 161.89,97.5 v1(161.16,96.77)
  vias: v1(137.67,100.71) v1(137.67,99.19) v1(137.67,97.66) v1(137.67,96.14) v1(138.43,100.71) v1(138.43,99.19) v1(138.43,97.66) v1(138.43,96.14) v3(120.27,108.08) v3(120.27,106.17) v3(120.27,102.62) v3(120.27,100.71) v3(120.27,97.92) v3(120.27,96.01) v3(120.27,92.46) v3(120.27,90.55) v3(121.67,108.08) v3(121.67,106.17) v3(121.67,102.62) v3(121.67,100.71) v3(121.67,97.92) v3(121.67,96.01) v3(121.67,92.46) v3(121.67,90.55) v3(123.19,108.08) v3(123.19,106.17) v3(123.19,102.62) v3(123.19,100.71) v3(123.19,97.92) v3(123.19,96.01) v3(123.19,92.46) v3(123.19,90.55) v3(126.62,102.62) v3(126.62,100.71) v3(126.62,97.92) v3(126.62,96.01) v3(126.62,92.46)
VCORE_SW1: length 14.4
  TOP w0.254: L8.1 v1(116.97,94.23) ; C763.1 v1(103.75,91.83)
  TOP w0.762: C766.1 110.58,91.02 v1(110.74,91.19)
  L6SIG w0.508: v1(110.74,91.19) 106.43,91.19 106.17,91.44 104.14,91.44 v1(103.75,91.83)
  BOTTOM w0.254: R562.1 117.35,93.85 v1(116.97,94.23)
VCORE_SW2: length 14
  TOP w0.254: C779.1 v1(103.75,101.99) ; L9.1 v1(116.97,104.39)
  TOP w0.762: C786.1 110.58,107.86
  L6SIG w0.508: v1(110.74,101.35) 106.43,101.35 106.17,101.6 104.14,101.6 v1(103.75,101.99)
  BOTTOM w0.254: v1(116.97,104.39) 117.35,104.01 R586.1
VCORE_VCC: length 4.6
  BOTTOM w0.254: 101.09,87.63 101.46,87.26 U70.22
  BOTTOM w0.508: 101.09,87.63 C762.1 C760.1 R559.1
VCORE_VRTN1: length 16.6
  TOP w0.254: v1(112.27,80.39) 112.4,80.52 112.78,80.52 R556.2
  BOTTOM w0.254: R556.2 112.78,80.52 112.4,80.52 v1(112.27,80.39) 112.12,80.54 111.02,80.54 110.79,80.31 108,80.31 106.81,79.12 106.81,78.36 106.06,77.61 U92.6 103.88,77.61 C764.2 103.12,78.11 102.62,78.61 102.62,79.37 101.46,80.53 U70.3
VCORE_VSEN1: length 14.1
  TOP w0.254: v1(112.27,81.15) 112.4,81.03 112.78,81.03 R551.2
  BOTTOM w0.254: R551.2 112.78,81.03 112.4,81.03 v1(112.27,81.15) 112.01,80.9 110.88,80.9 110.64,80.67 107.85,80.67 106.8,79.61 U92.10 103.88,79.61 C764.1 101.96,80.53 U70.2
VTT: length 115.8
  TOP w0.305: C885.1 227.33,150.99 U81.3
  TOP w0.508: J1.120 227.45,156.18 ; J1.120 227.45,155.12 ; J1.120 226.39,156.18 ; J1.120 226.39,155.12 ; J1.240 227.45,159.98 ; J1.240 226.39,158.92 ; J1.240 226.39,159.98 ; J1.240 227.45,158.92 ; R694.2 v1(223.53,148.85)
  BOTTOM w0.508: J1.240 227.45,159.98 ; J1.240 227.45,158.92 ; J1.240 226.39,159.98 ; J1.240 226.39,158.92 ; 150.39,156.18 J1.48 ; J1.48 151.45,155.12 ; J1.48 150.39,155.12 ; J1.48 151.45,156.18 ; v1(223.53,148.85) 227.84,153.16 227.84,154.3 228.98,155.45 228.98,163.07 226.69,165.35 153.42,165.35 153.03,164.97 153.03,164.47 ; J1.120 227.45,155.12 ; J1.120 227.45,156.18 ; J1.120 226.39,156.18 ; J1.120 226.39,155.12 ; 155.39,158.08 J1.49 ; J1.49 156.45,157.02 ; J1.49 156.45,158.08 ; J1.49 155.39,157.02
  vias: v1(148.72,163.96) v1(149.48,163.96) v1(150.24,163.96) v1(151,163.96)
XFI_RX_N: length 48.9
  TOP w0.127: C60.1 190.11,109.73 190.42,109.73 arc(190.68,109.68) 190.91,109.53 191.35,109.08 arc(191.5,108.92) 191.64,108.74 193.05,106.73 arc(193.31,106.24) 193.47,105.71 193.73,104.21 193.77,104.04 arc(193.89,103.22) 193.93,102.4 193.93,99.66 arc(193.5,96.89) 192.26,94.37 190.36,91.66 arc(189.15,90.21) 187.7,88.99 182.94,85.66 arc(181.35,84.33) 180.03,82.75 175.05,75.65 arc(174.44,74.54) 174.09,73.33 174,72.8 173.96,72.42 arc(173.96,72.4) 173.96,72.39 173.96,70.7 arc(174,70.49) 174.12,70.32 U57.A11
XFI_RX_P: length 48.7
  TOP w0.127: U57.A10 173.46,70.32 arc(173.57,70.49) 173.61,70.68 173.61,72.42 arc(173.62,72.64) 173.65,72.86 173.74,73.39 arc(174.12,74.68) 174.76,75.85 179.73,82.95 arc(181.1,84.58) 182.73,85.95 187.5,89.29 arc(188.89,90.46) 190.07,91.86 191.97,94.57 arc(193.16,96.99) 193.57,99.66 193.57,102.4 arc(193.53,103.19) 193.42,103.97 193.38,104.14 193.12,105.65 arc(192.98,106.11) 192.76,106.52 191.34,108.54 arc(191.23,108.69) 191.1,108.83 190.74,109.19 arc(190.57,109.31) 190.36,109.35 190.11,109.35 189.98,109.22 C59.1
XFI_TX_N: length 58.5
  TOP w0.127: v1(186.01,108.48) 186.24,108.26 186.3,108.26 arc(186.36,108.25) 186.42,108.24 186.44,108.24 187.84,107.99 arc(188.38,107.84) 188.86,107.57 190.14,106.68 arc(190.48,106.39) 190.76,106.05 191.14,105.52 arc(191.41,105.03) 191.56,104.5 191.86,102.82 arc(192.02,100.91) 191.86,99.01 191.71,98.17 arc(191.27,96.67) 190.52,95.3 189.17,93.37 arc(188.07,92.06) 186.75,90.95 182.61,88.05 arc(180.54,86.31) 178.8,84.24 176.68,81.21 arc(175.16,79.4) 173.35,77.88 172.63,77.38 171.05,75.8 arc(170.88,75.54) 170.81,75.23 170.81,74.68 170.94,74.56 C555.1 ; U1.AE10 v2(174.92,110.05)
  BOTTOM w0.127: v1(186.01,108.48) 185.78,108.26 185.65,108.26 185.32,108.31 arc(185.04,108.4) 184.78,108.54 183.34,109.55 arc(182.87,109.8) 182.37,109.95 182.02,110.01 arc(181.8,110.04) 181.58,110.05 v2(174.92,110.05)
XFI_TX_P: length 58.6
  TOP w0.127: v1(186.01,107.67) 186.24,107.9 186.3,107.9 187.78,107.64 arc(188.24,107.51) 188.66,107.28 189.94,106.38 arc(190.23,106.14) 190.47,105.85 190.85,105.31 arc(191.08,104.9) 191.21,104.44 191.51,102.75 arc(191.67,100.91) 191.51,99.07 191.36,98.23 arc(190.94,96.8) 190.23,95.5 188.88,93.58 arc(187.82,92.31) 186.55,91.24 182.4,88.34 arc(180.29,86.56) 178.51,84.45 176.39,81.42 arc(174.91,79.65) 173.15,78.18 172.4,77.65 170.8,76.06 arc(170.55,75.68) 170.46,75.23 170.46,74.85 arc(170.44,74.75) 170.38,74.67 170.29,74.57 C554.1 ; U1.AD10 v2(174.12,110.05)
  BOTTOM w0.127: v2(174.12,110.05) 174.18,110.05 174.39,109.83 arc(174.61,109.69) 174.86,109.64 175.17,109.64 175.22,109.69 181.58,109.69 arc(181.77,109.68) 181.96,109.66 182.31,109.6 arc(182.74,109.47) 183.13,109.26 184.57,108.25 arc(184.9,108.07) 185.26,107.96 185.81,107.87 185.81,107.87 v1(186.01,107.67)
XG_LED0: length 149.5
  TOP w0.127: R394.1 53.98,11.04 51.56,13.46 21.97,13.46 18.92,16.51 18.92,52.2 19.18,52.45 v1(19.18,53.09) ; v1(58.51,107.43) 59.01,107.93 U65.G3
  L6SIG w0.102: v1(19.18,53.09) 19.56,53.09 20.19,53.72 20.19,55.88 37.95,73.64 37.95,79.74 40.83,82.62 40.83,89.02 42.17,90.36 45.6,90.36 52.96,97.72 52.96,103.51 56.38,106.93 58.01,106.93 v1(58.51,107.43)
XG_LED1: length 151.9
  TOP w0.127: v1(19.69,53.98) 19.69,52.45 19.3,52.07 19.3,16.64 22.1,13.84 54.99,13.84 57.92,10.91 R395.1 ; v1(57.51,107.43) 58.01,107.93 U65.G2
  L6SIG w0.102: v1(57.51,107.43) 56.37,107.43 52.7,103.76 52.7,97.85 45.48,90.63 42.06,90.63 40.56,89.14 40.56,82.73 37.68,79.85 37.68,73.75 19.69,55.75 v1(19.69,53.98)
XG_REFCLK_N: length 5.8
  TOP w0.102: C575.1 159.47,69.01 157.4,69.01 157.23,68.83 157.23,68.45 R541.2 156.44,68.99 156.22,68.99 156.03,68.81 U68.18
XG_REFCLK_P: length 5.8
  TOP w0.102: 157.11,69.97 156.41,69.27 156.2,69.27 156.02,69.46 U68.19 ; 157.11,69.97 157.23,69.85 157.23,69.47 157.4,69.29 159.6,69.29 C574.1 ; 157.11,69.97 R542.2
XG_RST_N: length 141.4
  TOP w0.127: U65.P15 71.52,100.42 71.52,97.68 70.99,97.16 70.36,97.16 v1(67.69,94.49) ; R386.1 R388.2 178.95,69.35 179.7,70.1 179.7,76.33 179.07,76.96 v1(179.07,77.85)
  L6SIG w0.102: v1(67.69,94.49) 70.99,91.19 70.99,87.88 74.42,84.45 74.42,83.31 77.34,80.39 81.28,80.39 83.82,77.85 102.6,77.85 102.86,77.6 110.11,77.6 110.87,76.84 152.47,76.84 153.74,78.11 168.27,78.11 168.81,77.57 178.79,77.57 v1(179.07,77.85)
XVDD: length 4.6
  TOP w0.305: U1.AC15 v2(173.32,114.85) ; U1.AC9 v2(173.32,109.25) ; U1.AC18 v2(173.32,117.25) ; U1.AC12 v2(173.32,111.65) ; U1.AC21 v2(173.32,119.65)
  BOTTOM w0.127: R140.1 171.83,119.76 172.12,120.05 172.91,120.05 v2(173.32,119.65)
  vias: v1(194.94,129.67) v1(194.94,128.65) v1(194.94,127.64) v1(195.71,129.67) v1(195.71,127.64)
N16747459: length 1.5
  TOP w0.127: U1.U28 168.12,125.57 v2(168.15,125.6)
  BOTTOM w0.127: R1.2 v2(168.15,125.6)
N16747463: length 1.5
  TOP w0.127: v2(165.48,125.48) 165.72,125.24 U1.P28
  BOTTOM w0.127: v2(165.48,125.48) 165.76,125.19 R3.2
N16800565: length 2.1
  TOP w0.127: v1(103.76,123.44) 103.72,123.4 U4.53
  BOTTOM w0.127: R42.1 103.77,123.45 v1(103.76,123.44)
N16800570: length 2.6
  TOP w0.127: U4.16 120.14,129.4 120.12,129.41 v1(120.02,129.41)
  BOTTOM w0.127: R41.1 v1(120.02,129.41)
N16800621: length 2.8
  TOP w0.127: v1(120.64,129.9) 120.64,129.9 U4.17
  BOTTOM w0.127: v1(120.64,129.9) 120.11,130.43 R44.1
N16807910: length 5.9
  TOP w0.254: U6.39 78.97,126.39 v1(78.99,126.37) 78.99,128.63 78.74,128.88 U6.34
  BOTTOM w0.508: R51.1 78.74,126.11 v1(78.99,126.37)
N16808071: length 15.9
  TOP w0.254: U6.48 76.62,121.88 75.95,122.56 75.95,132.72 76.62,133.39 U6.25 77.68,134.06 v1(77.85,134.24)
  BOTTOM w0.508: R52.1 77.86,134.23 v1(77.85,134.24)
N16809639: length 3.6
  TOP w0.127: U6.10 v1(98.28,126.39)
  BOTTOM w0.127: R46.1 98.05,128.14 98.3,127.89 98.3,126.41 v1(98.28,126.39)
N16810401: length 4.6
  TOP w0.127: U6.9 v1(95.76,125.88)
  BOTTOM w0.127: U7.11 95.73,125.91 v1(95.76,125.88) 95.98,126.11 R45.1
N16811518: length 6.1
  TOP w0.127: U6.17 96.05,129.88 v1(95.89,130.05)
  BOTTOM w0.127: v1(95.89,130.05) 94.87,129.03 94.87,127.51 94.07,126.71 U7.9
N16821274: length 1.6
  TOP w0.127: v2(154.69,115.95) 154.78,116.05 U1.A17
  BOTTOM w0.127: R12.1 154.18,115.57 154.56,115.95 v2(154.69,115.95)
N16821816: length 9
  TOP w0.127: U1.E14 v2(158.12,113.25)
  BOTTOM w0.127: R5.1 150.76,113.92 154.18,113.92 154.43,113.67 157.73,113.67 158.12,113.28 v2(158.12,113.25)
N16848026: length 28.2
  TOP w0.127: U59.28 88.37,65.89 v1(88.52,66.04)
  BOTTOM w0.127: v1(88.52,66.04) 88.52,66.29 89.66,67.44 98.42,67.44 100.08,65.79 102.49,65.79 104.01,64.26 110.11,64.26 111.89,66.04 R422.2
N16848521: length 26.9
  TOP w0.127: U59.34 84.47,66.66 v1(84.45,66.68)
  BOTTOM w0.127: R423.2 104.79,66.68 103.28,68.2 100.97,68.2 99.44,69.72 88.49,69.72 87.48,68.71 86.49,68.71 v1(84.45,66.68)
N16848537: length 28
  TOP w0.127: v1(85.73,66.68) 85.77,66.63 U59.32
  BOTTOM w0.127: v1(85.73,66.68) 86.87,67.82 87.84,67.82 88.73,68.71 88.73,68.71 88.86,68.83 99.06,68.83 100.71,67.18 103.04,67.18 104.56,65.66 108.2,65.66 108.84,66.29 R426.2
N16848601: length 25.5
  TOP w0.127: v1(83.82,66.04) 83.82,66.04 U59.35
  BOTTOM w0.127: R419.2 104.39,67.69 103.5,68.58 101.09,68.58 99.57,70.1 88.27,70.1 87.25,69.09 86.11,69.09 83.82,66.8 v1(83.82,66.04)
N16849665: length 2
  TOP w0.305: U59.9 95.84,55.92 R436.2
N16849667: length 2
  TOP w0.305: U59.6 95.75,53.97 R436.1
N16849681: length 2.3
  TOP w0.305: C648.2 76.87,56.57 U59.51
N16849691: length 29.7
  TOP w0.305: C646.2 96.39,61.85 95.67,61.12 U59.17
  TOP w0.508: C647.1 96.23,58.33 v1(95.89,58.67) ; C648.1 77.38,58.33 v1(77.6,58.55) ; v1(96.9,62.74) 96.61,62.45 C646.2
  L3SIG w0.508: v1(95.89,58.67) 94.11,60.45 79.5,60.45 v1(77.6,58.55)
  BOTTOM w0.508: v1(96.9,62.74) 96.9,59.69 v1(95.89,58.67)
N16849695: length 2.3
  TOP w0.305: C647.2 96.61,56.57 U59.10
N16849815: length 2
  TOP w0.305: U59.52 77.65,55.92 R437.1
N16849817: length 2
  TOP w0.305: R437.2 77.74,53.97 U59.55
N16849836: length 1.8
  TOP w0.305: U59.16 96.17,60.47 R438.2
N16849860: length 1.9
  TOP w0.305: C649.1 96.02,59.82 U59.15
N16850380: length 24.4
  TOP w0.305: U60.1 95.5,45.97 93.98,47.5 v1(91.19,47.5) 90.97,47.72 U59.77
  TOP w0.508: F1.1 95.5,34.8 U60.8 U60.1
  BOTTOM w0.305: C639.1 v1(91.19,47.5) 92.84,47.5 93.34,48.01 R414.2
N16850382: length 30.1
  TOP w0.305: U60.4 91.69,45.34 90.93,46.1 89.66,46.1 v1(88.27,47.5) 87.76,47.5 87.07,48.19 U59.71
  TOP w0.508: F2.1 91.69,34.16 U60.5 U60.4
  BOTTOM w0.305: C640.2 89.03,48.26 v1(88.27,47.5) 89.28,46.48 94.36,46.48 95.5,47.62 R416.2
N16850384: length 24.2
  TOP w0.305: v1(93.22,58.29) 93.45,58.52 U59.13
  L3SIG w0.305: v1(93.22,58.29) 93.6,58.29 94.49,57.4 94.49,45.09 96.65,42.93 v1(96.65,38.73)
  BOTTOM w0.305: v1(96.65,38.73) 96.65,38.33 R716.1
N16850386: length 26.3
  TOP w0.305: U59.14 93.36,59.17 v1(93.22,59.31)
  L3SIG w0.305: v1(90.55,38.73) 90.55,43.43 92.08,44.96 92.08,51.69 90.68,53.09 90.68,57.66 92.33,59.31 v1(93.22,59.31)
  BOTTOM w0.305: R717.1 90.55,38.2 v1(90.55,38.73)
N16850446: length 1.7
  BOTTOM w0.305: R414.1 C637.2
N16850448: length 4
  TOP w0.305: U59.11 93.27,57.22 v1(93.22,57.28)
  BOTTOM w0.305: v1(93.22,57.28) 93.22,54.72 C637.1
N16850461: length 4.6
  TOP w0.305: U59.12 95.67,57.87 v1(95.76,57.78)
  BOTTOM w0.305: C638.1 95.76,54.85 v1(95.76,57.78)
N16850463: length 1.7
  BOTTOM w0.305: R416.1 C638.2
N16850577: length 27.2
  TOP w0.305: U59.67 84.47,47.51 v1(84.45,47.5) 86.61,45.34 U61.1
  TOP w0.508: F3.1 86.61,34.8 U61.8 U61.1
  BOTTOM w0.305: R429.2 77.98,47.62 79.12,46.48 83.44,46.48 v1(84.45,47.5) C641.1
N16850645: length 21.8
  TOP w0.305: U61.4 82.8,46.61 v1(81.92,47.5) 81.15,47.5 80.57,48.08 U59.61
  TOP w0.508: F4.1 82.8,34.16 U61.5 U61.4
  BOTTOM w0.305: R431.2 80.14,48.01 80.65,47.5 v1(81.92,47.5) 82.3,47.88 C643.2
N16850749: length 4.1
  TOP w0.305: U59.50 77.78,57.22 v1(77.72,57.28)
  BOTTOM w0.305: v1(77.72,57.28) 77.72,54.85 C642.1
N16850755: length 4.6
  TOP w0.305: v1(80.26,57.78) 80.18,57.87 U59.49
  BOTTOM w0.305: C644.1 80.26,54.72 v1(80.26,57.78)
N16850778: length 27.3
  TOP w0.305: v1(80.26,59.56) 79.87,59.17 U59.47
  L3SIG w0.305: v1(87.76,38.73) 87.76,42.29 82.8,47.24 82.8,57.4 80.65,59.56 v1(80.26,59.56)
  BOTTOM w0.305: R718.1 87.76,38.33 v1(87.76,38.73)
N16850798: length 24.5
  TOP w0.305: U59.48 80.11,58.52 v1(80.26,58.67)
  L3SIG w0.305: v1(81.66,38.73) 81.66,43.18 79.25,45.59 79.25,58.04 79.88,58.67 v1(80.26,58.67)
  BOTTOM w0.305: v1(81.66,38.73) 81.66,38.2 R719.1
N16851731: length 3.1
  BOTTOM w0.305: C696.2 R490.1 78.11,67.06 R493.2 79.13,67.06 R489.2
N16851789:
  vias: v1(63.75,55.75) v1(64.52,55.75)
N16851797: length 25.1
  TOP w0.305: v1(91.82,66.55) 91.82,67.31 92.33,67.82 R488.1
  L3SIG w0.305: v1(70.74,71.5) 74.3,67.95 75.06,67.95 75.57,67.44 89.54,67.44 90.42,66.55 v1(91.82,66.55)
  vias: v1(68.45,71.5) v1(69.22,71.5) v1(69.98,71.5)
N16859448: length 4.8
  TOP w0.305: U59.45 77.87,60.47 v1(77.72,60.32)
  BOTTOM w0.305: R433.2 R430.2 77.09,60.96 v1(77.72,60.32)
N16861709: length 27.9
  TOP w0.127: v1(87.88,66.68) 87.88,65.66 87.72,65.49 U59.29
  BOTTOM w0.127: v1(87.88,66.68) 88.27,66.68 89.41,67.82 98.55,67.82 100.2,66.17 102.62,66.17 104.14,64.64 104.83,64.64 104.83,64.64 109.22,64.64 110.87,66.29 R421.2
N16861730: length 28
  TOP w0.127: U59.26 89.67,66.04 v1(89.66,66.04)
  BOTTOM w0.127: R418.2 112.9,66.04 110.74,63.88 103.89,63.88 102.36,65.41 99.95,65.41 98.3,67.06 90.55,67.06 89.66,66.17 v1(89.66,66.04)
N16862179: length 2.3
  BOTTOM w0.305: R490.2 77.1,67.56 76.01,68.64 Q7.1
N16862407: length 5.3
  BOTTOM w0.508: Q5.3 70.61,64.39 71.37,65.15 71.37,65.91 71.87,66.41 R486.1 72.51,66.8 Q7.3
N16862426: length 5.7
  BOTTOM w0.305: Q5.1 72.96,65.34 R485.1 75.21,65.93 76.99,65.93 C696.1
N16862837: length 4.1
  TOP w0.508: 71.22,65.15 70.61,65.15 70.1,65.66 v1(70.1,66.55)
  BOTTOM w0.508: v1(70.1,66.55) 70.36,66.8 R486.2 R487.2
N16864329: length 6.9
  TOP w0.127: U15.2 262,132.72 261.75,132.46 U13.8 255.66,132.46 R58.2
N16864338: length 7.4
  TOP w0.127: R55.1 R866.2 269.12,138.55 268.73,138.94 268.73,139.83 268.48,140.08 U13.15 266.32,140.08 265.72,140.68 U15.5
N16864354: length 6.9
  TOP w0.127: R865.2 269.23,141.35 263.53,141.35 263.27,141.1 U15.6
N16864366: length 123.6
  TOP w0.127: U12.9 160.44,88.3 v1(160.27,88.14) ; 260.73,133.13 259.68,133.13 259.08,133.73 v1(256.41,133.73) R56.1
  L6SIG w0.102: v1(256.41,133.73) 253.62,133.73 241.43,121.54 229.88,121.54 194.58,86.23 167.64,86.23 165.23,88.65 162.69,88.65 162.38,88.95 161.47,88.95 160.66,88.14 v1(160.27,88.14)
N16864378: length 24.4
  TOP w0.127: R57.1 268.98,132.46 U13.9 263.53,132.46 263.27,132.72 U15.3 263.27,133.22 262.76,133.73 259.97,133.73 259.59,134.11 259.59,139.7 259.97,140.08 261.4,140.08 U15.7 262,141.1 261.75,141.35 257.84,141.35
N16869850: length 4.8
  TOP w0.127: R211.2 165.11,50.04 163.96,50.04 163.58,50.41 C300.2 163.15,50.11 U46.19
N16869910: length 3.1
  TOP w0.127: U46.14 162.08,48.11 162.81,47.38 162.81,46.86 163.19,46.48 R209.2
N16869938: length 2.9
  TOP w0.127: U46.16 162.06,48.91 162.11,48.96 162.12,48.96 162.12,48.96 162.49,48.96 162.49,48.96 162.5,48.96 162.81,48.64 162.81,48.26 163.58,47.5 R213.2
N16869959: length 2.4
  TOP w0.127: R214.2 163.58,48.51 162.78,49.31 U46.17
N16869976: length 2.2
  TOP w0.127: U46.18 163.4,49.71 R215.2
N16869978: length 3.6
  TOP w0.127: R216.2 163.19,45.47 162.43,46.23 162.43,47.24 161.97,47.71 U46.13
N16870294: length 2.2
  TOP w0.508: T1.15 v1(156.52,30.95)
  BOTTOM w0.508: v1(156.52,30.95) 156.5,30.93 R207.1
N16870296: length 15.1
  BOTTOM w0.508: 157.95,29.12 158.37,28.7 160.51,28.7 161,29.19 ; 157.95,29.12 157.53,28.7 155.32,28.7 154.9,29.12 R207.2 152.93,29.84 C302.1 ; 157.95,29.12 R208.2 ; R212.2 164.05,29.17 163.56,28.69 161.51,28.69 161,29.19 ; 161,29.19 R210.2
N16870306: length 2.2
  TOP w0.508: T1.18 v1(159.52,30.95)
  BOTTOM w0.508: R208.1 159.55,30.92 v1(159.52,30.95)
N16870310: length 2.2
  TOP w0.508: T1.21 v1(162.52,30.95)
  BOTTOM w0.508: R210.1 162.6,30.87 v1(162.52,30.95)
N16870330: length 2.2
  TOP w0.508: T1.24 v1(165.52,30.95)
  BOTTOM w0.508: v1(165.52,30.95) 165.65,30.82 R212.1
N16870380: length 16.7
  TOP w0.508: T1.1 v1(165.52,40.31) ; T1.10 v1(156.52,40.31) ; T1.4 v1(162.52,40.31) ; T1.7 v1(159.52,40.31)
  BOTTOM w0.508: v1(162.52,40.31) v1(165.52,40.31) 165.48,40.28 C301.2 ; v1(162.52,40.31) 162.56,40.28 C299.2 ; v1(162.52,40.31) v1(159.52,40.31) ; C296.2 156.46,40.26 v1(156.52,40.31) v1(159.52,40.31) ; v1(159.52,40.31) 159.51,40.31 C298.2
N16870828: length 20
  TOP w0.508: FB26.2 167.12,43.48 C297.1 167.12,41.54 v1(167.13,41.53)
  L6SIG w0.508: v1(167.13,41.53) 167.12,41.52 167.12,28.21 J14.A11
N16870844: length 53.8
  TOP w0.127: R219.2 C307.1 152.15,57.28 v1(152.78,57.91)
  L6SIG w0.102: J14.A12 165.2,23.75 163.19,23.75 162.18,24.77 156.97,24.77 155.96,23.75 152.15,23.75 151.13,24.77 151.13,42.55 153.16,44.58 153.16,49.4 153.92,50.16 153.92,56.13 153.54,56.52 153.54,57.15 v1(152.78,57.91)
N16870890: length 36.9
  TOP w0.127: R218.2 C308.1 155.19,57.9 v1(155.19,57.91)
  L6SIG w0.102: J14.A9 151.38,26.2 151.38,42.42 153.48,44.51 153.48,48.22 154.15,48.89 154.15,56.87 v1(155.19,57.91)
N16871038: length 5
  TOP w0.127: U46.20 162.06,50.51 162.11,50.47 162.61,50.47 162.81,50.67 162.81,51.05 163.58,51.82 164.97,51.82 165.23,51.56 R221.1
N16873302: length 8.4
  TOP w0.127: C304.1 149.65,53.37 Y1.1 149.65,51.78 150.62,50.8 153.68,50.8 154.5,49.97 154.87,49.97 155.01,50.11 U46.42
N16873318: length 4.5
  TOP w0.127: Y1.3 151.8,50.16 C305.1 153.67,50.16 154.11,49.71 U46.43
N16873350: length 3.1
  TOP w0.127: R220.2 160.02,54.99 159.05,54.02 159.05,53.52 159.1,53.48 U46.29
N16874872: length 4
  TOP w0.127: U46.46 154.39,48.51 154.38,48.5 153.15,48.5 152.92,48.27 C303.1 R217.1
N16877780: length 2.5
  TOP w0.127: R222.1 157.23,54.62 157.23,53.59 157.5,53.32 U46.33
N16879465: length 0.8
  BOTTOM w0.508: v1(154.69,46.74) 154.56,46.61 R224.1
N16880733: length 1.7
  TOP w0.127: U46.38 155.04,51.71 154.94,51.82 154.19,51.82 R822.2
N16880820: length 1
  BOTTOM w0.508: R224.2 151.9,46.61 C309.1
N16890207: length 2.9
  TOP w0.127: R227.2 153.49,51.5 154.87,51.5 155.06,51.31 U46.39
N16891950: length 2
  TOP w0.508: T3.15 v1(191.19,18.38)
  BOTTOM w0.508: R265.1 191.17,18.39 v1(191.19,18.38)
N16891952: length 14.8
  BOTTOM w0.508: 192.62,19.85 192.15,20.32 190.08,20.32 189.57,19.81 R265.2 ; 192.62,19.85 193.09,20.32 195.2,20.32 195.67,19.85 ; 192.62,19.85 R266.2 ; R267.2 195.67,19.85 ; 195.67,19.85 196.14,20.32 198.25,20.32 198.72,19.85 R271.2 198.72,17.08 C365.1
N16891962: length 2
  TOP w0.508: T3.18 v1(194.19,18.38)
  BOTTOM w0.508: v1(194.19,18.38) 194.22,18.41 R266.1
N16891966: length 2
  TOP w0.508: T3.21 v1(197.19,18.38)
  BOTTOM w0.508: v1(197.19,18.38) 197.27,18.45 R267.1
N16891978: length 2.1
  TOP w0.508: T3.24 v1(200.19,18.38)
  BOTTOM w0.508: v1(200.19,18.38) 200.32,18.5 R271.1
N16892036: length 16.7
  TOP w0.508: T3.1 v1(200.19,27.74) ; T3.4 v1(197.19,27.74) ; T3.10 v1(191.19,27.74) ; T3.7 v1(194.19,27.74)
  BOTTOM w0.508: v1(197.19,27.74) v1(200.19,27.74) 200.15,27.7 C363.2 ; v1(197.19,27.74) v1(194.19,27.74) ; v1(197.19,27.74) 197.23,27.7 C360.2 ; v1(194.19,27.74) v1(191.19,27.74) 191.13,27.69 C362.2 ; v1(194.19,27.74) 194.18,27.73 C364.2
N16892171: length 54.6
  TOP w0.508: v1(184.91,51.43) 184.9,51.44 C361.1 184.91,52.2 FB32.2
  L6SIG w0.508: v1(184.91,51.43) 188.66,47.69 J42.9 190.11,11.68 191.9,11.68 193.35,13.14 J42.11
N16892215: length 73
  TOP w0.127: R274.2 183.39,71.49 C370.1 183.4,72 182.88,72.52 v1(181.48,72.52)
  L6SIG w0.102: v1(181.48,72.52) 181.36,72.64 180.34,72.64 180.09,72.39 180.09,70.87 180.85,70.1 180.85,67.95 179.58,66.68 179.58,58.04 180.97,56.64 186.05,56.64 189.23,53.47 189.23,14.85 J42.10
N16892219: length 80.2
  TOP w0.127: v1(180.59,72.14) 180.86,71.87 C369.1 R275.2
  L6SIG w0.102: v1(180.59,72.14) 180.59,70.87 181.1,70.36 181.1,67.82 179.83,66.55 179.83,58.17 181.1,56.9 186.18,56.9 189.48,53.59 189.48,15.37 190.5,14.35 201.16,14.35 J42.12
N16892768: length 1.8
  TOP w0.127: R269.2 198,68.95 U52.43
N16892846: length 3
  TOP w0.127: R270.2 198.61,69.35 U52.44
N16894213: length 1.9
  TOP w0.127: R272.2 195.32,71.52 U52.46
N16894217: length 1.8
  TOP w0.127: R273.2 195.72,71.64 U52.45
N16894418: length 2.5
  TOP w0.127: U52.75 185.7,66.15 184.66,67.18 R281.1
N16899326: length 4.4
  TOP w0.127: U52.13 192.12,59.49 192.14,59.47 192.14,57.92 192.91,57.15 193.81,57.15 C366.1
N16899338: length 4.2
  TOP w0.127: C367.1 193.94,57.63 193.81,57.51 193.06,57.51 192.49,58.07 192.49,59.47 192.52,59.49 U52.14
N16900249: length 5.1
  TOP w0.127: R276.1 182.36,68.71 185.29,68.71 185.85,68.15 U52.70
N16900569: length 2.3
  TOP w0.127: U52.71 185.87,67.75 185.42,68.2 R278.1
N16900702: length 6.1
  TOP w0.127: Y3.1 181.4,63.72 182.37,62.74 184.27,62.74 C372.1 185.3,63.25 185.8,63.75 U52.81
N16900720: length 4.1
  TOP w0.127: Y3.3 183.68,62.22 C373.1 185.91,63.35 U52.82
N16900769: length 2
  TOP w0.127: R280.2 192.92,71.25 U52.52
N16902304: length 5.3
  TOP w0.127: U52.77 185.86,65.35 185.67,65.53 185.67,65.81 184.94,66.55 182.63,66.55 182.36,66.29 R827.2
N16902556: length 1.8
  TOP w0.127: U52.26 198.03,62.15 R286.2
N16903120: length 3.8
  TOP w0.127: R285.2 183.39,65.91 183.39,65.53 183.64,65.28 184.78,65.28 185.11,64.95 U52.78
N16909680: length 0.6
  TOP w0.203: 186.05,60.71 186.3,60.95 U52.88
N16909742: length 1
  TOP w0.508: R284.2 C374.1
N16927443: length 2
  TOP w0.127: R268.2 197.75,66.67 197.06,67.35 U52.39
N16930193: length 3.6
  TOP w0.127: C555.2 171.12,73.39 arc(171.01,73.22) 170.97,73.02 170.97,70.69 arc(171.01,70.49) 171.12,70.32 U57.A8
N16930196: length 3.6
  TOP w0.127: C554.2 170.46,73.39 arc(170.57,73.22) 170.61,73.02 170.61,70.69 arc(170.57,70.49) 170.46,70.32 U57.A7
N16936676: length 4.2
  TOP w0.102: U57.C1 163.98,67.84 163.17,67.84 161.8,69.22 161.28,69.22 C574.2
N16936678: length 4.3
  TOP w0.102: U57.D1 163.88,67.56 163.05,67.56 161.68,68.94 161.26,68.94 C575.2
N16941914: length 1.4
  TOP w0.127: U57.F2 v1(164.79,65.65)
  BOTTOM w0.127: R379.1 165.29,66.15 v1(164.79,65.65)
N16941931: length 1.4
  TOP w0.127: U57.E2 v1(164.79,66.65)
  BOTTOM w0.127: R380.1 164.29,66.15 v1(164.79,66.65)
N16941947: length 1.4
  TOP w0.127: U57.H2 v1(164.79,62.65)
  BOTTOM w0.127: v1(164.79,62.65) 165.29,63.15 R381.1
N16941963: length 1.4
  TOP w0.127: U57.F3 v1(165.79,65.65)
  BOTTOM w0.127: R383.1 166.29,65.15 v1(165.79,65.65)
N16943000: length 1.4
  TOP w0.127: v1(168.79,69.65) 168.79,69.65 U57.B6
  BOTTOM w0.127: R384.1 v1(168.79,69.65)
N16943224: length 1.4
  TOP w0.127: U57.E10 v1(173.79,66.65)
  BOTTOM w0.127: v1(173.79,66.65) 173.29,67.15 R387.1
N16943474: length 9.4
  TOP w0.127: U57.H3 v1(165.79,62.65) ; v1(160.15,64.52) 160.09,64.57 U58.6
  L6SIG w0.102: v1(165.79,62.65) 165.32,63.12 161.54,63.12 v1(160.15,64.52)
  BOTTOM w0.127: R382.2 159.89,64.77 v1(160.15,64.52)
N16943477: length 8.1
  TOP w0.127: U58.5 160.74,64.81 v1(161.04,64.52) 161.42,64.14 163.45,64.14 163.96,64.64 165.8,64.64 U57.G3
  BOTTOM w0.127: v1(161.04,64.52) 160.91,64.64 R385.2
N16948831: length 8.1
  TOP w0.127: R386.2 178.44,65.28 176.78,63.63 173.77,63.63 U57.H10
N16948977: length 1.4
  TOP w0.127: v1(168.79,61.65) 168.79,61.65 U57.J6
  BOTTOM w0.127: R389.1 v1(168.79,61.65)
N16949711: length 3.4
  TOP w0.127: C572.1 167.29,56.79 U57.L4
N16949714: length 3.4
  TOP w0.127: U57.L5 168.29,56.78 C573.1
N16950393: length 3.4
  TOP w0.127: U57.A1 164.29,70.15 C564.2
N16950396: length 3.4
  TOP w0.127: C565.2 165.29,70.15 U57.A2
N16956674: length 4.2
  TOP w0.127: J16.7 178.92,37.32 v1(178.94,37.34)
  BOTTOM w0.127: R846.1 179.07,37.21 v1(178.94,37.34) 179.07,37.46 R845.2
N16956686: length 4.2
  TOP w0.127: v1(180.85,37.08) 180.52,36.76 J16.9
  BOTTOM w0.127: R847.2 181.1,37.34 v1(180.85,37.08) 180.59,36.83 R848.1
N16973728: length 0.8
  BOTTOM w0.508: v1(132.46,47.37) 132.33,47.24 R253.1
N16973810: length 1.7
  TOP w0.127: R825.2 131.96,52.45 132.72,52.45 132.82,52.35 U49.38
N16973842: length 1
  BOTTOM w0.508: R253.2 129.67,47.24 C341.1
N16974061: length 4.8
  TOP w0.127: R238.2 142.88,50.67 141.73,50.67 141.36,51.05 C331.2 140.92,50.75 U49.19
N16974094: length 3.1
  TOP w0.127: U49.14 139.86,48.75 140.59,48.01 140.59,47.5 140.97,47.12 R239.2
N16974110: length 2.9
  TOP w0.127: R242.2 141.35,48.13 140.59,48.89 140.59,49.28 140.27,49.59 140.27,49.59 140.27,49.59 139.9,49.59 139.89,49.59 139.88,49.59 139.84,49.55 U49.16
N16974123: length 2.4
  TOP w0.127: R243.2 141.35,49.15 140.55,49.95 U49.17
N16974136: length 2.2
  TOP w0.127: U49.18 141.18,50.35 R244.2
N16974138: length 3.6
  TOP w0.127: R245.2 140.97,46.1 140.21,46.86 140.21,47.88 139.74,48.35 U49.13
N16974225: length 2.2
  TOP w0.508: T2.15 v1(140.64,30.95)
  BOTTOM w0.508: R236.1 140.63,30.93 v1(140.64,30.95)
N16974227: length 15
  BOTTOM w0.508: R240.2 145.12,29.19 ; 145.12,29.19 144.63,28.7 142.54,28.7 142.07,29.16 ; 145.12,29.19 145.63,28.69 147.68,28.69 148.17,29.17 R241.2 ; 142.07,29.16 R237.2 ; 142.07,29.16 141.61,28.7 139.45,28.7 139.03,29.12 R236.2 137.06,29.84 C334.1
N16974244: length 2.2
  TOP w0.508: T2.18 v1(143.64,30.95)
  BOTTOM w0.508: R237.1 143.68,30.92 v1(143.64,30.95)
N16974248: length 2.2
  TOP w0.508: T2.21 v1(146.65,30.95)
  BOTTOM w0.508: v1(146.65,30.95) 146.72,30.87 R240.1
N16974260: length 2.2
  TOP w0.508: T2.24 v1(149.65,30.95)
  BOTTOM w0.508: R241.1 149.77,30.82 v1(149.65,30.95)
N16974322: length 16.7
  TOP w0.508: T2.1 v1(149.65,40.31) ; T2.4 v1(146.65,40.31) ; T2.7 v1(143.64,40.31) ; T2.10 v1(140.64,40.31)
  BOTTOM w0.508: v1(146.65,40.31) v1(143.64,40.31) ; v1(146.65,40.31) v1(149.65,40.31) 149.61,40.28 C333.2 ; v1(146.65,40.31) 146.69,40.28 C332.2 ; v1(143.64,40.31) 143.64,40.31 C330.2 ; v1(143.64,40.31) v1(140.64,40.31) 140.59,40.26 C328.2
N16974528: length 46.3
  TOP w0.508: FB29.2 135.25,40.61 C329.1 135.25,38.74 v1(135.25,38.73)
  L6SIG w0.508: v1(135.25,38.73) 136.27,37.72 136.27,30.35 137.54,29.08 147.7,29.08 148.97,27.81 148.97,25.4 153.03,21.34 153.03,8.54 J14.B9
N16974538: length 81.1
  TOP w0.127: v1(129.03,56.77) 129.03,57.4 129.41,57.78 C337.1 R248.2
  L6SIG w0.102: v1(129.03,56.77) 129.54,57.28 132.21,57.28 133.22,58.29 133.98,58.29 134.37,57.91 134.37,53.98 135.38,52.96 143.51,52.96 144.91,51.56 146.43,51.56 147.95,50.04 147.95,45.97 150.88,43.05 150.88,24.64 153.8,21.72 153.8,10.29 154.69,9.4 162.6,9.4 J14.B11
N16974572: length 66.7
  TOP w0.127: v1(133.73,57.78) C338.1 R247.2
  L6SIG w0.102: v1(133.73,57.78) 133.3,57.35 133.3,54.03 134.62,52.7 143.38,52.7 144.75,51.33 146.34,51.33 147.7,49.97 147.7,45.85 150.62,42.93 150.62,24.51 153.54,21.59 153.54,9.82 J14.B10
N16974631: length 3.9
  TOP w0.127: R250.1 141.74,52.71 140.59,51.56 140.59,51.31 140.38,51.1 139.88,51.1 139.84,51.15 U49.20
N16974829: length 8.4
  TOP w0.127: U49.42 132.78,50.75 132.65,50.61 132.28,50.61 131.45,51.43 128.4,51.43 127.42,52.41 Y2.1 127.42,54.01 C339.1
N16974847: length 4.5
  TOP w0.127: Y2.3 129.58,50.79 C340.1 131.44,50.79 131.89,50.35 U49.43
N16974885: length 3.1
  TOP w0.127: R249.2 137.79,55.63 136.83,54.66 136.83,54.16 136.87,54.11 U49.29
N16975047: length 4
  TOP w0.127: R246.1 C335.1 130.69,48.9 130.93,49.14 132.16,49.14 132.16,49.15 U49.46
N16975158: length 2.5
  TOP w0.127: U49.33 135.27,53.96 135,54.23 135,55.25 R251.1
N16975193: length 2.9
  TOP w0.127: U49.39 132.83,51.95 132.65,52.13 131.26,52.13 R256.2
N16980127: length 10.3
  TOP w0.127: R408.1 268.48,94.62 268.99,94.11 270.89,94.11 272.03,95.25 273.56,95.25 274.57,94.23 274.57,92.6 J18.B11
N16980167: length 2.3
  TOP w0.127: R403.1 268.35,87.88 J18.A8
N16980179: length 8.3
  TOP w0.127: R400.1 269.62,93.6 270.64,92.58 270.64,91.69 271.15,91.19 272.94,91.19 J18.B9
N16980191: length 3.9
  TOP w0.127: J18.A5 267.93,86.08 R401.1
N16980203: length 1.9
  TOP w0.127: J18.A6 267.92,87.08 R402.1
N16980532: length 9.8
  TOP w0.127: C607.1 267.88,98.38 arc(268.06,98.26) 268.26,98.22 269.52,98.22 arc(270.13,98.1) 270.65,97.75 270.75,97.65 arc(271.19,97.36) 271.7,97.26 274.93,97.26 275.21,97.54 arc(275.29,97.73) 275.21,97.92 275.02,98.11 arc(274.81,98.25) 274.56,98.3 274.41,98.3 arc(274.28,98.27) 274.17,98.2 J18.B15
N16980534: length 8.9
  TOP w0.127: C606.1 267.88,97.71 arc(268.06,97.83) 268.26,97.87 269.52,97.87 arc(269.99,97.77) 270.4,97.5 270.5,97.4 arc(271.05,97.03) 271.7,96.9 275.08,96.9 275.33,97.16 arc(275.65,97.29) 275.97,97.16 J18.B14
N16981083: length 8.9
  TOP w0.127: C608.1 267.88,101.77 arc(268.06,101.89) 268.26,101.93 269.4,101.93 arc(270.02,102.05) 270.55,102.41 270.67,102.52 arc(271.11,102.82) 271.63,102.92 274.65,102.92 274.83,102.74 arc(274.91,102.55) 274.83,102.36 274.71,102.24 arc(274.52,102.12) 274.31,102.08 J18.B19
N16981085: length 9
  TOP w0.127: C615.1 267.88,102.44 arc(268.06,102.33) 268.26,102.29 269.4,102.29 arc(269.89,102.38) 270.3,102.66 270.41,102.77 arc(270.97,103.15) 271.63,103.28 274.8,103.28 275.08,103 arc(275.52,102.81) 275.97,103 J18.B20
N16981142: length 9
  TOP w0.127: J18.B23 274.7,106.08 arc(274.79,106.11) 274.83,106.2 274.83,106.54 arc(274.8,106.67) 274.73,106.79 274.66,106.85 arc(274.6,106.89) 274.53,106.91 271.73,106.91 arc(271.21,106.8) 270.76,106.51 270.65,106.39 arc(270.09,106.02) 269.43,105.89 268.2,105.89 arc(268,105.85) 267.83,105.73 C616.1
N16981144: length 9.1
  TOP w0.127: C617.1 267.83,106.39 arc(268,106.28) 268.2,106.24 269.43,106.24 arc(269.95,106.35) 270.4,106.64 270.51,106.76 arc(271.07,107.13) 271.73,107.26 274.53,107.26 arc(274.73,107.22) 274.91,107.11 275.08,106.93 arc(275.49,106.76) 275.9,106.93 J18.B24
N16981213: length 9.1
  TOP w0.127: J18.B27 274.69,110.08 arc(274.88,110.15) 274.96,110.34 274.96,110.48 arc(274.92,110.64) 274.84,110.76 274.77,110.83 arc(274.67,110.9) 274.55,110.92 271.7,110.92 arc(271.18,110.82) 270.74,110.52 270.63,110.41 arc(270.1,110.06) 269.47,109.93 268.26,109.93 arc(268.06,109.89) 267.88,109.77 C618.1
N16981215: length 9.1
  TOP w0.127: J18.B28 275.76,110.79 arc(275.54,110.7) 275.31,110.79 275.02,111.08 arc(274.81,111.23) 274.55,111.28 271.7,111.28 arc(271.05,111.15) 270.49,110.77 270.38,110.66 arc(269.96,110.38) 269.47,110.29 268.26,110.29 arc(268.06,110.33) 267.88,110.44 C619.1
N16984231: length 2.6
  TOP w0.127: J19.33 179.57,197.7 177.75,197.7 C598.1
N16984233: length 2.6
  TOP w0.127: J19.31 179.57,198.05 177.73,198.05 C599.1
N16985354: length 2.6
  TOP w0.127: C630.1 90.98,205.65 89.16,205.65 J20.33
N16985356: length 2.6
  TOP w0.127: J20.31 89.16,205.3 91,205.3 C631.1
N17013042: length 145.9
  TOP w0.102: v1(74.17,31.12) 73.89,31.4 73.89,68.3 79.25,73.66 105.28,73.66 107.32,75.69 119.83,75.69 124.68,80.54 143.15,80.54 149.71,87.1 149.71,96.68 152.47,99.44 157.3,99.44 159.13,101.28 159.13,103.06 U1.F1
  BOTTOM w0.102: v1(74.17,31.12) 73.9,30.85 73.9,30.51 74.14,30.28 L1.1 74.3,29.52 R167.1
N17013078: length 146.8
  TOP w0.102: v1(73.38,31.12) 73.66,31.4 73.66,68.4 79.15,73.89 105.19,73.89 107.22,75.92 119.74,75.92 124.59,80.77 143.06,80.77 149.48,87.19 149.48,96.77 152.37,99.67 157.2,99.67 158.9,101.37 158.9,103.63 U1.F2
  BOTTOM w0.102: R168.1 73.28,29.52 L1.4 73.44,30.28 73.67,30.51 73.67,30.82 v1(73.38,31.12)
N17013302: length 9.7
  TOP w0.127: U1.H4 v2(160.52,105.25)
  BOTTOM w0.127: R172.2 156.46,99.96 156.46,101.98 157.72,103.24 159.55,103.24 159.87,103.24 160.11,103.48 160.11,104.84 v2(160.52,105.25)
N17013307: length 6.6
  TOP w0.127: U1.F4 v2(158.92,105.25)
  BOTTOM w0.127: v2(158.92,105.25) 158.52,104.85 157.12,104.85 156.51,104.24 156.51,103.04 155.83,102.36 R173.2
N17013374: length 8.3
  TOP w0.127: U1.G4 v2(159.72,105.25)
  BOTTOM w0.127: v2(159.72,105.25) 159.31,104.84 159.31,104.24 159.11,104.04 157.11,104.04 156.91,103.84 156.91,102.94 155.82,101.85 R171.2 C1022.1
N17020476: length 146.9
  TOP w0.102: v1(76.73,31.12) 76.45,31.4 76.45,48.39 75.03,49.81 75.03,65.56 75.79,66.33 75.79,68.55 79.91,72.67 105.89,72.67 107.77,74.55 120.47,74.55 125.19,79.27 143.66,79.27 150.98,86.59 150.98,96.17 152.49,97.69 157.45,97.69 160.76,101 160.76,103.09 U1.H1
  BOTTOM w0.102: R169.1 76.84,29.52 L2.1 76.68,30.28 76.44,30.51 76.44,30.82 v1(76.73,31.12)
N17020482: length 147.7
  TOP w0.102: U1.H2 160.53,103.66 160.53,101.09 157.35,97.92 152.4,97.92 150.75,96.27 150.75,86.68 143.57,79.5 125.09,79.5 120.37,74.78 107.67,74.78 105.79,72.9 79.81,72.9 75.57,68.65 75.57,66.42 74.8,65.66 74.8,49.71 76.23,48.29 76.23,31.4 v1(75.94,31.12)
  BOTTOM w0.102: R170.1 75.82,29.52 L2.4 75.98,30.28 76.21,30.51 76.21,30.85 v1(75.94,31.12)
N17021121: length 160
  TOP w0.127: U1.F5 v2(158.92,106.05) ; R157.1 61.22,35.93 Q3.3 61.21,38.47 R156.1 v1(60.2,38.48)
  L3SIG w0.102: v2(158.92,106.05) 159.3,105.67 159.3,105.05 159.07,104.83 158.76,104.83 158.54,104.6 158.54,98.21 155.22,94.89 152.55,94.89 151.51,93.85 151.51,89.15 143.38,81.03 132.46,81.03 124.08,72.64 124.08,45.34 113.41,34.67 66.68,34.67 63.63,37.72 60.96,37.72 v1(60.2,38.48)
N17021131: length 165.7
  TOP w0.127: R160.1 58.17,33.9 56.51,35.57 Q4.3 56.51,38.34 R155.1 56.52,39 56.9,39.37 59.18,39.37 v1(59.56,38.99) ; U1.H5 v2(160.52,106.05)
  L3SIG w0.102: v1(59.56,38.99) 59.56,38.35 60.55,37.36 63.47,37.36 66.55,34.29 113.54,34.29 124.46,45.21 124.46,72.52 132.59,80.65 143.51,80.65 151.89,89.03 151.89,93.73 152.73,94.56 155.4,94.56 159.13,98.3 159.13,103.76 159.3,103.93 159.3,104.57 159.56,104.83 159.87,104.83 160.14,105.09 160.14,105.67 v2(160.52,106.05)
N17033690: length 3.3
  TOP w0.127: X1.3 88.21,90.55 C132.1 R175.1
N17033815: length 2.1
  TOP w0.127: X1.1 81.74,86.62 R174.2
N17040696: length 10.4
  TOP w0.127: U1.N1 164.72,103.05 164.72,98.93 161.54,95.75 R59.1
N17040868: length 1.7
  TOP w0.127: U1.K1 v2(162.12,102.85)
  BOTTOM w0.127: R61.1 162.13,102.86 v2(162.12,102.85)
N17055310: length 5.3
  TOP w0.254: U39.2 134.52,64.49 134.24,64.77 133.6,64.77 133.35,64.52 C273.1
N17055339: length 2
  TOP w0.254: U39.6 137.12,62.44 136.91,62.23 C275.1
N17055373: length 3.5
  TOP w0.254: C271.2 134.23,60.59 133.98,60.83 133.98,62.36 133.87,62.47 U39.1
N17055376: length 2.2
  TOP w0.254: C271.1 134.62,62.1 135.17,62.65 U39.3
N17055394: length 3.7
  TOP w0.254: C274.2 135.51,60.59 135.25,60.84 135.25,62.1 135.82,62.67 U39.4
N17055396: length 2.2
  TOP w0.254: U39.5 136.47,62.56 135.89,61.98 C274.1
N17055419: length 3.9
  TOP w0.127: U39.14 135.17,68.11 134.87,67.81 R196.1
N17055422: length 5.5
  TOP w0.127: R197.1 133.72,65.78 135.82,67.87 U39.13
N17055459: length 2.2
  TOP w0.127: U39.8 138.42,62.11 R199.1
N17055461: length 2
  TOP w0.127: R198.1 137.77,61.74 U39.7
N17055495: length 33
  TOP w0.127: v1(131.95,63.12) 131.95,66.17 R196.2 ; FB18.1 v1(121.16,39.5)
  L6SIG w0.102: v1(131.95,63.12) 128.27,59.44 128.27,58.29 124.33,54.36 124.33,44.7 121.16,41.53 v1(121.16,39.5)
N17055507: length 34
  TOP w0.127: R197.2 v1(132.59,62.48) ; FB19.1 v1(121.16,36.45)
  L6SIG w0.102: v1(132.59,62.48) 130.17,60.07 130.17,59.18 125.09,54.1 125.09,44.45 122.05,41.4 122.05,37.34 v1(121.16,36.45)
N17055527: length 35.5
  TOP w0.127: FB20.1 v1(121.16,37.97) ; v1(128.78,58.42) 130.68,58.42 132.08,59.82 134.87,59.82 135.38,59.31 137.41,59.31 137.92,59.82 R198.2
  L6SIG w0.102: v1(121.16,37.97) 121.67,38.48 121.67,41.53 124.71,44.58 124.71,54.23 128.78,58.29 v1(128.78,58.42)
N17055529: length 38.7
  TOP w0.127: R199.2 138.94,59.94 137.92,58.93 134.75,58.93 134.37,59.31 v1(132.59,59.31) ; FB21.1 v1(121.16,34.92)
  L6SIG w0.102: v1(132.59,59.31) 130.81,59.31 125.48,53.98 125.48,44.32 122.43,41.27 122.43,36.2 v1(121.16,34.92)
N17056698: length 5.3
  TOP w0.254: U41.2 127.41,64.49 127.1,64.8 126.52,64.8 126.24,64.52 C287.1
N17056714: length 2
  TOP w0.254: U41.6 130.01,62.57 129.79,62.36 C288.1
N17056740: length 3.5
  TOP w0.254: C285.2 127.13,60.59 126.87,60.84 126.87,62.36 126.76,62.47 U41.1
N17056750: length 2.2
  TOP w0.254: C285.1 127.51,62.1 128.06,62.65 U41.3
N17056764: length 3.7
  TOP w0.254: U41.4 128.71,62.67 128.14,62.1 128.14,60.83 128.39,60.59 C284.2
N17056766: length 2.2
  TOP w0.254: U41.5 129.36,62.56 128.78,61.98 C284.1
N17056776: length 3.9
  TOP w0.127: R200.1 127.5,67.68 128.06,68.24 U41.14
N17056778: length 5.7
  TOP w0.127: U41.13 128.71,67.62 126.74,65.65 R201.1
N17056796: length 2.2
  TOP w0.127: R203.1 131.31,62.11 U41.8
N17056798: length 2
  TOP w0.127: R202.1 130.66,61.74 U41.7
N17056816: length 40.7
  TOP w0.127: R200.2 124.84,66.05 124.84,58.42 v1(125.86,57.4) ; FB22.1 v1(121.16,30.35)
  L6SIG w0.102: v1(125.86,57.4) 125.86,56.9 123.57,54.61 123.57,44.96 120.27,41.66 120.27,31.24 v1(121.16,30.35)
N17056834: length 37
  TOP w0.127: v1(126.49,57.91) 126.11,57.91 125.48,58.55 R201.2 ; FB23.1 v1(121.16,31.88)
  L6SIG w0.102: v1(126.49,57.91) 126.49,57.02 123.95,54.48 123.95,44.83 120.65,41.53 120.65,32.38 v1(121.16,31.88)
N17056844: length 39.6
  TOP w0.127: R202.2 130.81,59.94 130.17,59.31 128.14,59.31 v1(127.64,58.8) ; FB24.1 v1(121.16,28.83)
  L6SIG w0.102: v1(121.16,28.83) 119.89,30.1 119.89,41.78 123.19,45.09 123.19,55.5 126.49,58.8 v1(127.64,58.8)
N17056846: length 34.3
  TOP w0.127: R203.2 131.83,60.2 130.56,58.93 128.52,58.93 128.14,58.55 128.14,56.52 v1(128.52,56.13) ; FB25.1 v1(121.16,33.4)
  L6SIG w0.102: v1(121.16,33.4) 122.81,35.05 122.81,41.15 125.86,44.2 125.86,53.85 128.14,56.13 v1(128.52,56.13)
N17059126: length 5
  TOP w0.127: U1.AE7 v2(174.92,107.65)
  BOTTOM w0.127: R117.1 177.8,106.3 176.85,107.25 175.42,107.25 175.02,107.65 v2(174.92,107.65)
N17059132: length 6.1
  TOP w0.127: U1.AF7 v2(175.72,107.65)
  BOTTOM w0.127: R118.1 180.73,106.93 177.8,106.93 177.09,107.65 v2(175.72,107.65)
N17059135: length 6.1
  TOP w0.127: U1.AF6 v2(175.72,106.85)
  BOTTOM w0.127: v2(175.72,106.85) 175.86,106.85 176.26,106.44 177.02,106.44 177.67,105.79 R120.1
N17059138: length 3.2
  TOP w0.127: U1.AG5 v2(176.52,106.05)
  BOTTOM w0.127: v2(176.52,106.05) 176.78,106.05 177.55,105.28 R122.1
N17059149: length 6
  TOP w0.127: U1.AF8 v2(175.72,108.45)
  BOTTOM w0.127: v2(175.72,108.45) 179.48,108.45 179.82,108.79 R124.1 R126.1
N17059152: length 7.3
  TOP w0.127: U1.AE8 v2(174.92,108.45)
  BOTTOM w0.127: R128.1 C56.1 179.82,107.64 179.5,107.32 178.05,107.32 177.33,108.04 175.32,108.04 v2(174.92,108.45)
N17059643: length 5.1
  TOP w0.127: U1.L6 v2(162.92,106.85)
  BOTTOM w0.127: R130.1 164.21,103.25 163.32,104.14 163.32,106.43 162.92,106.83 v2(162.92,106.85)
N17059732: length 3.4
  TOP w0.127: U1.AC3 v2(173.32,104.45)
  BOTTOM w0.127: v2(173.32,104.45) 173.32,104.24 173.74,103.82 173.74,102.62 173.22,102.1 R121.2
N17059733: length 4.2
  TOP w0.127: U1.AE4 v2(174.92,105.25)
  BOTTOM w0.127: R116.2 176.02,102.23 176.02,103.5 175.31,104.22 175.31,104.85 v2(174.92,105.25)
N17059734: length 2.9
  TOP w0.127: U1.AD3 v2(174.12,104.45)
  BOTTOM w0.127: v2(174.12,104.45) 174.12,102.1 R119.2
N17059735: length 3.2
  TOP w0.127: U1.AE3 v2(174.92,104.45)
  BOTTOM w0.127: v2(174.92,104.45) 174.92,104.2 175.39,103.73 175.39,102.87 175.13,102.62 R115.2
N17059985: length 5.9
  TOP w0.127: U1.AF4 v2(175.72,105.25)
  BOTTOM w0.127: v2(175.72,105.25) 176.92,104.04 178.79,104.04 179.07,103.76 179.07,103.51 R123.2 179.2,103.37 R125.2
N17060054: length 5.1
  TOP w0.127: U1.AF3 v2(175.72,104.45)
  BOTTOM w0.127: v2(175.72,104.45) 177.16,103 177.93,103 178.18,102.74 178.18,102.37 C55.2 R127.2
N17060498: length 4.2
  TOP w0.127: U1.AH3 v2(177.32,104.45)
  BOTTOM w0.127: R129.2 177.64,104.78 v2(177.32,104.45)
N17072443: length 24.9
  TOP w0.127: v1(137.92,128.02) 137.92,127.64 150.07,115.48 154.85,115.48 155.07,115.7 155.77,115.7 U1.B17
  BOTTOM w0.127: R106.2 v1(137.92,128.02)
N17081807: length 13.4
  TOP w0.127: C59.2 188.77,109.05 arc(188.56,109.19) 188.3,109.25 185.29,109.25 arc(183.99,109.3) 182.7,109.47 177.61,110.37 arc(177.54,110.38) 177.47,110.38 177.36,110.38 177.17,110.19 arc(177.03,110.09) 176.85,110.06 176.64,110.06 176.52,110.17 176.52,110.33 176.64,110.45 U1.AH10
N17081810: length 13.2
  TOP w0.127: C60.2 188.85,109.72 arc(188.72,109.63) 188.56,109.6 185.29,109.6 arc(184.02,109.66) 182.76,109.82 177.39,110.77 arc(177.17,110.8) 176.95,110.81 176.67,110.81 arc(176.48,110.77) 176.32,110.67 176.12,110.46 U1.AG10
N17081955: length 10.3
  TOP w0.127: U1.AH11 177,111.32 177.14,111.35 177.3,111.35 178.35,111.53 178.61,111.53 arc(178.69,111.5) 178.72,111.42 arc(178.76,111.34) 178.84,111.3 179.11,111.3 arc(179.2,111.34) 179.23,111.42 arc(179.26,111.5) 179.35,111.53 179.62,111.53 arc(179.7,111.5) 179.74,111.42 arc(179.77,111.34) 179.85,111.3 180.13,111.3 arc(180.21,111.34) 180.25,111.42 arc(180.28,111.5) 180.36,111.53 180.64,111.53 arc(180.72,111.5) 180.75,111.42 arc(180.79,111.34) 180.87,111.3 181.15,111.3 arc(181.23,111.34) 181.26,111.42 arc(181.3,111.5) 181.38,111.53 182.05,111.53 182.93,111.38 185.78,111.38 185.94,111.23 C63.2
N17081957: length 10.1
  TOP w0.127: U1.AG11 176.56,111.61 177.1,111.71 177.27,111.71 178.32,111.89 182.08,111.89 182.97,111.73 185.78,111.73 C64.2
N17082045: length 13.1
  TOP w0.127: U1.AG13 176.45,113.11 176.94,113.26 177.8,113.26 178.23,113.33 181.58,113.33 183.89,113.74 188.81,113.74 C61.2
N17082047: length 13.3
  TOP w0.127: U1.AH13 176.97,112.9 177.83,112.9 178.26,112.98 178.59,112.98 arc(178.67,112.95) 178.71,112.86 arc(178.74,112.78) 178.82,112.75 179.1,112.75 arc(179.18,112.78) 179.22,112.86 arc(179.25,112.95) 179.33,112.98 179.61,112.98 arc(179.69,112.95) 179.72,112.86 arc(179.76,112.78) 179.84,112.75 180.12,112.75 arc(180.2,112.78) 180.23,112.86 arc(180.26,112.95) 180.35,112.98 180.62,112.98 arc(180.71,112.95) 180.74,112.86 arc(180.77,112.78) 180.85,112.75 181.13,112.75 arc(181.21,112.78) 181.25,112.86 arc(181.28,112.95) 181.36,112.98 181.62,112.98 183.92,113.39 188.83,113.39 188.98,113.23 C65.2
N17082121: length 10.3
  TOP w0.127: U1.AH14 176.92,113.65 177.3,113.84 177.3,113.84 178.41,114.19 178.75,114.25 arc(178.83,114.23) 178.88,114.17 arc(178.92,114.1) 179,114.08 179.29,114.13 arc(179.36,114.18) 179.38,114.25 arc(179.39,114.33) 179.46,114.38 179.71,114.42 arc(179.79,114.41) 179.83,114.34 arc(179.87,114.28) 179.94,114.26 180.25,114.32 arc(180.31,114.36) 180.33,114.43 arc(180.34,114.5) 180.41,114.54 180.66,114.59 arc(180.73,114.57) 180.78,114.51 arc(180.82,114.44) 180.89,114.42 181.29,114.5 arc(181.33,114.55) 181.33,114.62 181.33,114.63 arc(181.34,114.69) 181.39,114.72 185.34,115.42 185.81,115.42 185.94,115.29 C62.2
N17082123: length 10.2
  TOP w0.127: C66.2 185.76,115.77 185.3,115.77 178.33,114.54 177.19,114.18 177.11,114.15 177.09,114.13 U1.AG14
N17082319: length 1.5
  TOP w0.127: U1.Y20 v2(170.92,118.85)
  BOTTOM w0.127: R140.2 170.83,118.93 v2(170.92,118.85)
N17082346: length 1.9
  TOP w0.127: U1.AA12 v2(171.72,111.65)
  BOTTOM w0.127: v2(171.72,111.65) 171.72,111.45 172.42,110.74 R139.2
N17093364: length 13.5
  TOP w0.127: U1.AE5 v2(174.92,106.05)
  L3SIG w0.102: v2(174.92,106.05) 175.33,106.47 177.51,106.47 177.8,106.17 184.15,106.17 v1(185.93,104.39)
  BOTTOM w0.127: R137.2 v1(185.93,104.39)
N17093369: length 15.8
  TOP w0.127: U1.AB6 v2(172.52,106.85)
  L3SIG w0.102: v1(185.93,105.41) 184.78,106.55 178.05,106.55 177.34,107.27 172.93,107.27 v2(172.52,106.85)
  BOTTOM w0.127: R136.2 v1(185.93,105.41)
N17093378: length 14.9
  TOP w0.127: U1.AC8 v2(173.32,108.45)
  L3SIG w0.102: v2(173.32,108.45) 173.73,108.03 177.21,108.03 178.31,106.93 185.42,106.93 v1(185.93,106.43)
  BOTTOM w0.127: R135.2 v1(185.93,106.43)
N17109189: length 9.9
  TOP w0.127: U1.V2 169.29,103.67 169.29,101.73 169.61,101.41 169.61,98.23 169.29,97.92 v1(169.29,96.65)
  BOTTOM w0.127: R92.1 168.02,97.28 168.66,96.65 v1(169.29,96.65)
N17109201: length 3.8
  TOP w0.127: U1.W3 v2(170.12,104.45)
  BOTTOM w0.127: v2(170.12,104.45) 169.67,104 169.67,103.38 170.05,103 R93.1
N17109221: length 3.7
  TOP w0.127: U1.AA3 v2(171.72,104.45)
  BOTTOM w0.127: v2(171.72,104.45) 171.07,103.8 R95.1
N17109223: length 8
  TOP w0.127: U1.AB3 v2(172.52,104.45)
  BOTTOM w0.127: v2(172.52,104.45) 172.52,104.44 171.58,103.51 171.58,97.92 171.45,97.79 171.08,97.79 R97.1
N17109289: length 14.7
  TOP w0.127: v1(169.8,95.63) 169.8,97.87 170.56,98.64 170.56,101.09 169.72,101.94 U1.W1
  BOTTOM w0.127: Q1.2 168.14,90.67 169.42,91.95 R89.1 169.68,91.96 170.05,92.33 170.05,93.34 169.54,93.85 169.54,95.38 v1(169.8,95.63)
N17109292: length 18.9
  TOP w0.127: v1(168.91,95.63) 168.78,95.76 168.78,98.57 168.53,98.83 168.53,100.2 168.92,100.59 U1.V1
  BOTTOM w0.127: v1(168.91,95.63) 168.27,95.63 167,94.36 165.23,94.36 164.85,93.99 R88.1 164.59,93.46 164.59,91.06 165.23,90.42 165.23,89.74 Q2.2
N17109295: length 120.6
  TOP w0.127: U1.V3 v2(169.32,104.45) ; U19.14 257.26,147.87 v1(257.18,147.95)
  L6SIG w0.102: v1(257.18,147.95) 257.05,147.83 257.05,146.43 238.76,128.14 227.46,128.14 197.87,98.55 178.31,98.55 174.88,101.98 172.32,101.98 170.27,104.03 169.73,104.03 v2(169.32,104.45)
  BOTTOM w0.127: R87.1 169.04,97.79 169.42,97.79 169.54,97.92 169.54,103 169.32,103.23 v2(169.32,104.45)
N17109336: length 120.7
  TOP w0.127: U1.Y3 v2(170.92,104.45) ; v1(257.81,148.46) 257.91,148.36 U19.15
  L6SIG w0.102: v2(170.92,104.45) 170.92,103.79 172.34,102.36 175.01,102.36 178.56,98.81 197.74,98.81 227.33,128.4 238.63,128.4 256.67,146.43 256.67,148.11 257.02,148.46 v1(257.81,148.46)
  BOTTOM w0.127: v2(170.92,104.45) 170.56,104.09 170.56,97.92 170.43,97.79 170.06,97.79 R86.1
N17111815: length 3.4
  TOP w0.127: J19.1 178.04,213.48 177.42,212.85 R399.1
N17112169: length 3.4
  TOP w0.127: R411.1 91.31,190.5 90.69,189.88 J20.1
N17112712: length 2.1
  TOP w0.127: R99.2 257.26,154.14 U19.3
N17112758: length 3.3
  TOP w0.127: U1.C20 v2(156.52,118.85)
  BOTTOM w0.127: v2(156.52,118.85) 156.29,118.62 R104.2
N17112821: length 3.3
  TOP w0.127: U1.B20 v2(156.52,118.05)
  BOTTOM w0.127: R105.2 153.95,117.64 156.11,117.64 v2(156.52,118.05)
N17112937: length 8.6
  TOP w0.127: U1.F9 158.92,110.04 v2(158.91,110.04)
  BOTTOM w0.127: R84.1 155.19,105.41 156.22,106.44 156.71,106.44 157.71,107.44 157.71,107.84 157.92,108.05 158.28,108.05 158.51,108.28 158.51,109.64 v2(158.91,110.04)
N17170143: length 3.2
  TOP w0.127: X3.3 88.08,98.93 C718.1 R511.1
N17232338: length 3.2
  TOP w0.127: X5.3 88.08,107.19 C728.1 R517.1
N17232433: length 2.1
  TOP w0.127: R516.2 81.74,103.13 X5.1
N17233442: length 6.6
  TOP w0.127: v2(158.11,109.24) 158.11,109.24 U1.E9
  BOTTOM w0.127: R71.1 155.52,106.43 156.34,107.24 156.68,107.24 156.91,107.47 156.91,107.9 157.06,108.05 157.48,108.05 157.71,108.28 157.71,108.84 v2(158.11,109.24)
N17233455: length 4.9
  TOP w0.127: U1.D4 v2(157.32,105.25)
  BOTTOM w0.127: R73.1 154.55,104.14 155.96,104.14 157.06,105.25 v2(157.32,105.25)
N17259940: length 1
  TOP w0.305: C682.1 97.91,64.77 R473.2
N17270978: length 4.8
  TOP w0.127: U1.D5 v2(157.32,106.05)
  BOTTOM w0.127: v2(157.32,106.05) 155.79,104.52 154.39,104.52 154.26,104.39 R74.1
N17271002: length 1.5
  TOP w0.127: U1.AB1 v2(172.52,102.85)
  BOTTOM w0.127: R77.1 172.08,102.41 v2(172.52,102.85)
N17271631: length 6.6
  TOP w0.127: U1.F19 v2(158.92,118.05)
  BOTTOM w0.127: R82.1 158.25,116.59 158.51,116.85 158.51,117.64 v2(158.92,118.05)
N17285538: length 5.9
  TOP w0.127: U97.2 235.2,133.85 234.94,133.6 C733.1 234.95,132.59 235.46,132.08 235.46,130.43 Y4.1
N17285647: length 4
  TOP w0.127: U97.3 235.6,133.87 235.33,133.6 235.33,133.23 C734.1 235.97,131.61 Y4.3
N17321001: length 8.3
  TOP w0.127: v1(72.64,95) 72.51,94.86 R103.1
  BOTTOM w0.127: U21.4 75.63,100.52 75.18,100.07 75.18,97.54 v1(72.64,95)
N17321019: length 1.4
  TOP w0.127: R103.2 D1.2
N17399246: length 3.6
  TOP w0.127: R707.2 C893.1 R705.1 18.17,64.19 U83.3
N17399288: length 58.7
  TOP w0.127: SW4.2 15.37,8.37 15.37,55.63 19.17,59.43 R707.1
N17400346: length 61.5
  TOP w0.127: D35.2 16.25,62.77 R714.1 R711.1 16.25,57.4 14.86,56.01 14.86,14.61 8.64,8.38 8.64,5.6 SW5.2
N17401317: length 2.3
  TOP w0.127: U84.1 12.63,62.54 11.95,61.86 U85.4
N17401544: length 5.1
  TOP w0.127: U85.2 14.22,61.21 14.73,61.72 R714.2 15.25,62.52 D35.1 15.25,63.47 C895.1
N17403382: length 9.8
  TOP w1.016: J34.1 J35.1
  BOTTOM w0.508: J34.1 68.07,131.32 68.07,133.35 J34.3
N17423481: length 5
  TOP w0.127: J3.5 R112.2
N17423546: length 12.3
  TOP w0.127: J3.6 10.67,143.26 11.94,141.99 R108.1
N17447445: length 1.7
  BOTTOM w0.305: R429.1 C642.2
N17447447: length 1.7
  BOTTOM w0.305: R431.1 C644.2
N17448817: length 2.4
  TOP w0.127: U63.28 111.23,65.89 R448.2
N17448821: length 2.3
  TOP w0.127: R453.2 106.68,66.22 106.86,66.04 106.87,66.04 107.33,65.59 U63.34
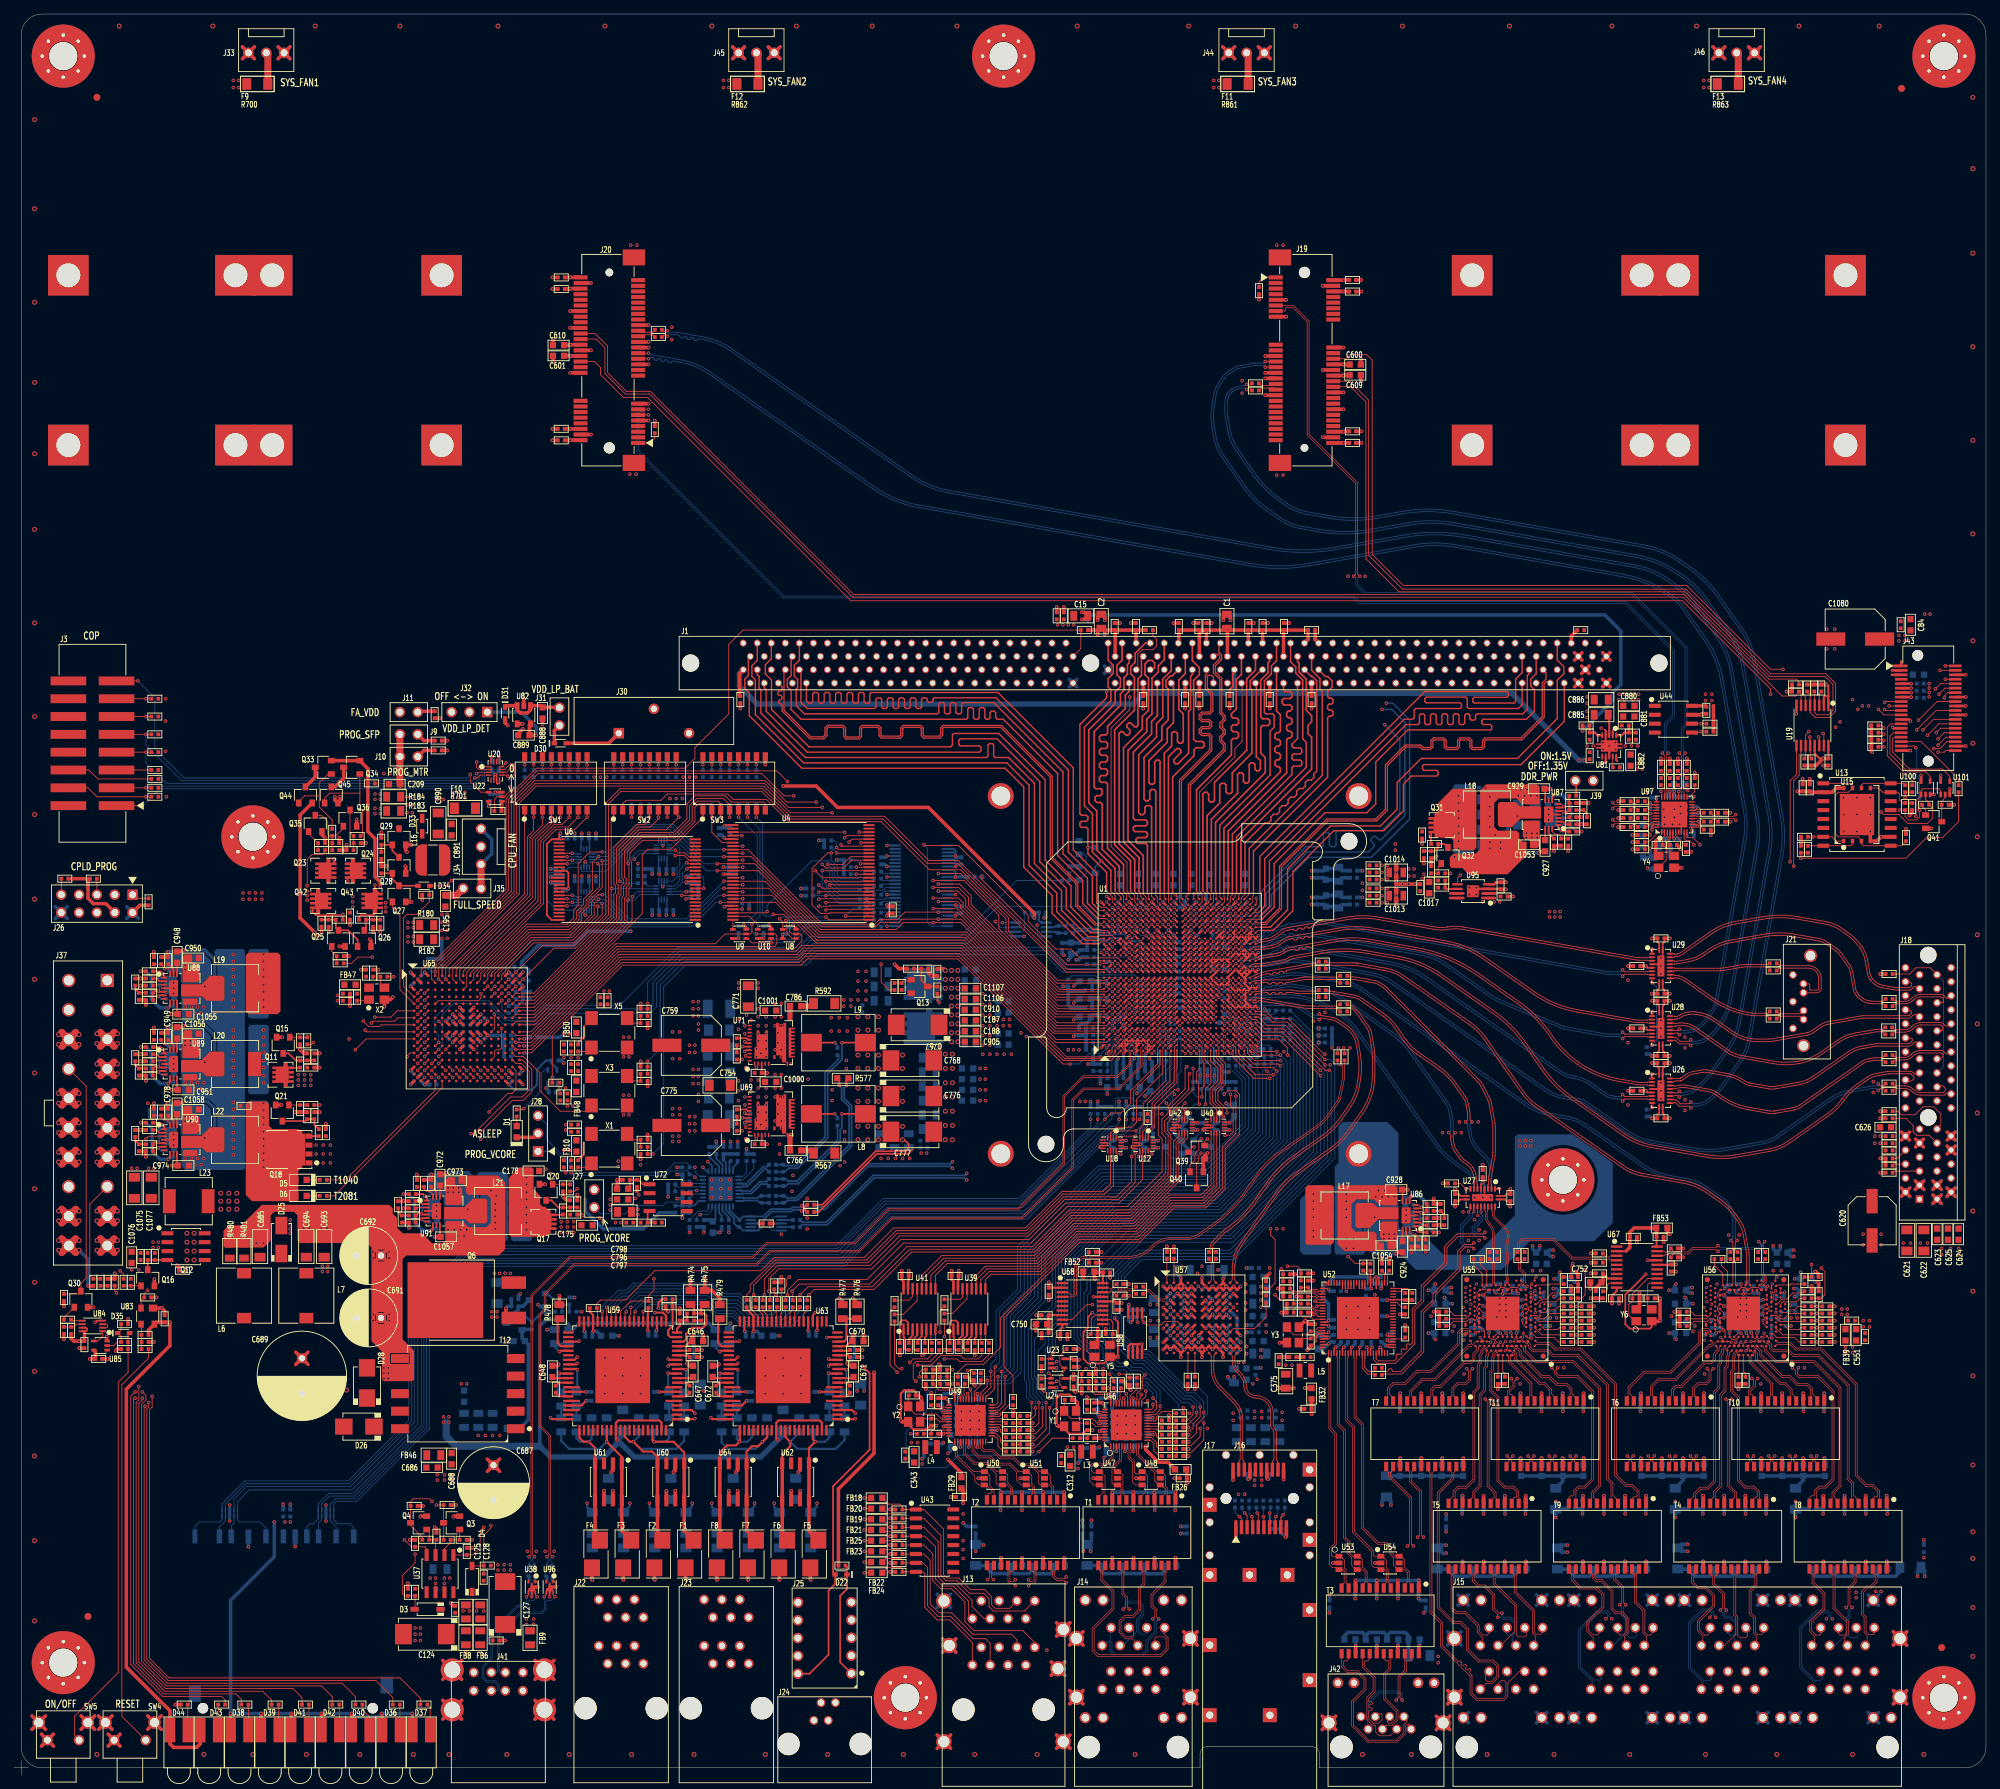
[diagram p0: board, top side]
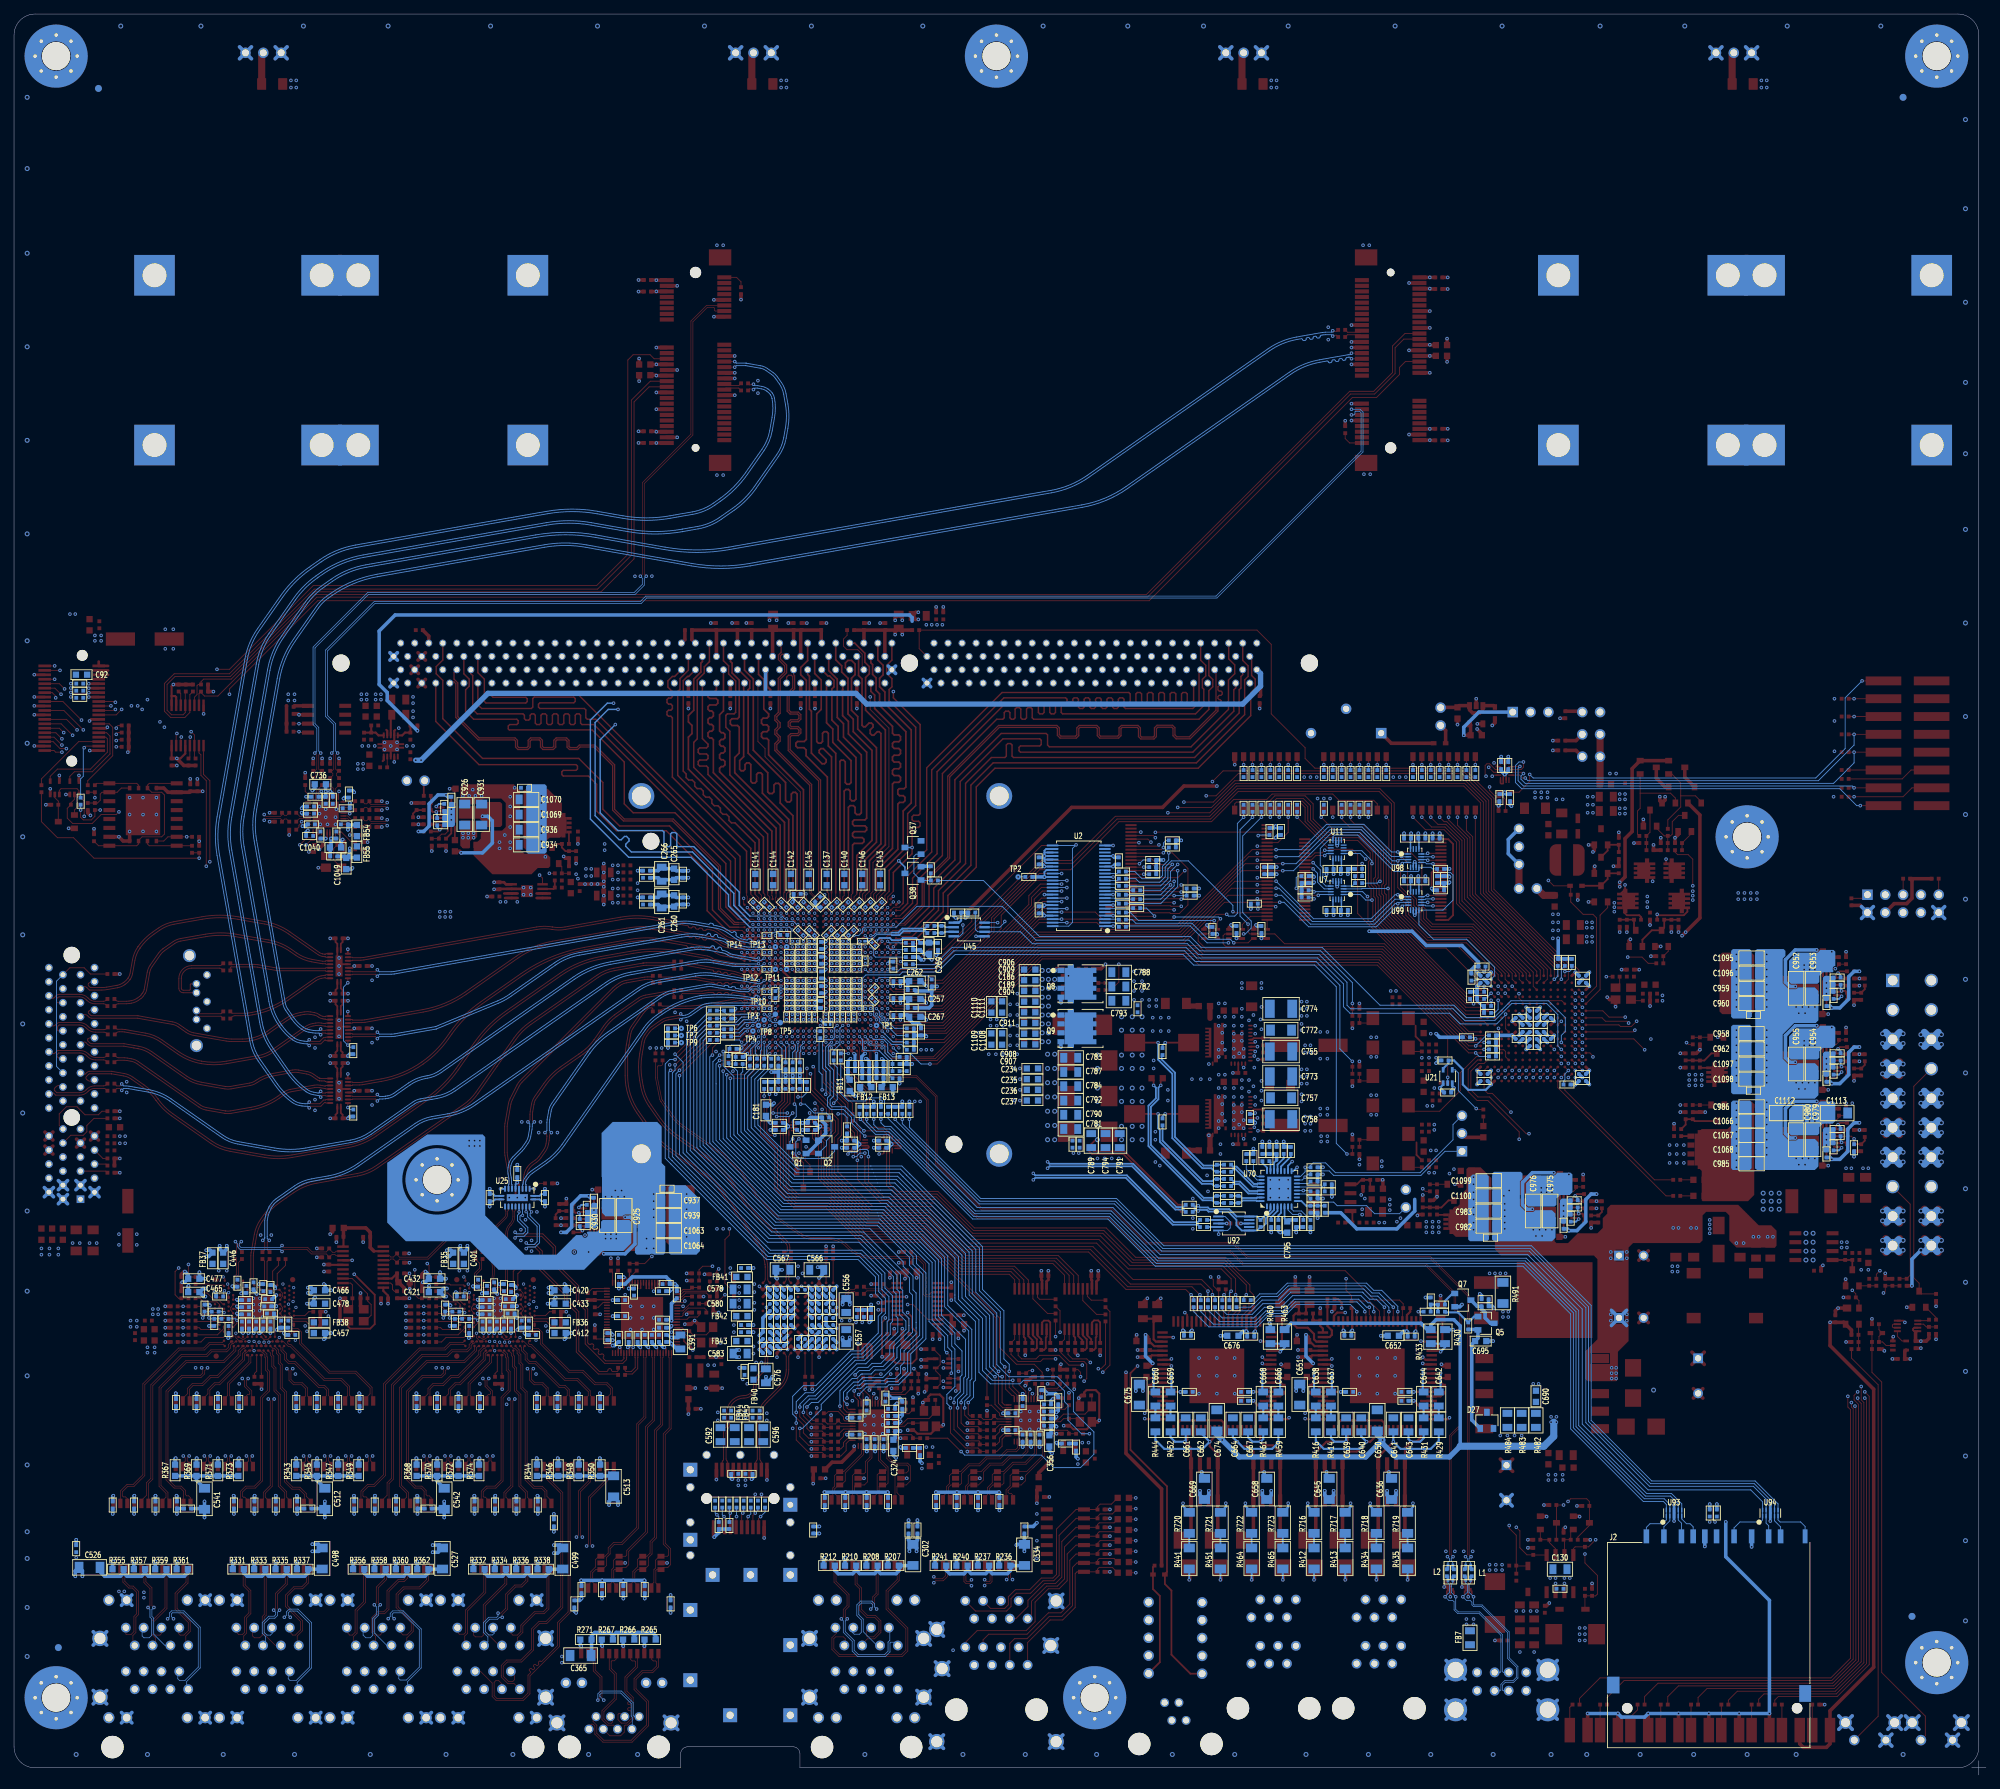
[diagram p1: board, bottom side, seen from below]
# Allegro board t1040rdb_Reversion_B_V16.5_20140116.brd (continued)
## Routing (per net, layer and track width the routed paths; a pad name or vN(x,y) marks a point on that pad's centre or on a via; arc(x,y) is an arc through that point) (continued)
N17448825: length 2.1
  TOP w0.127: U63.32 108.63,66.6 R455.2
N17448833: length 2.5
  TOP w0.127: R449.2 106.68,65.67 U63.35
N17448841: length 2
  TOP w0.305: R466.2 118.7,55.92 U63.9
N17448842: length 2
  TOP w0.305: U63.6 118.61,53.97 R466.1
N17448845: length 2.3
  TOP w0.305: C672.2 99.73,56.57 U63.51
N17448846: length 29.7
  TOP w0.305: U63.17 118.53,61.12 119.25,61.85 C670.2
  TOP w0.508: v1(119.76,62.74) 119.47,62.45 C670.2 ; v1(118.75,58.67) 119.09,58.33 C671.1 ; C672.1 100.24,58.33 v1(100.46,58.55)
  L3SIG w0.508: v1(100.46,58.55) 102.36,60.45 116.97,60.45 v1(118.75,58.67)
  BOTTOM w0.508: v1(118.75,58.67) 119.76,59.69 v1(119.76,62.74)
N17448848: length 2.3
  TOP w0.305: U63.10 119.47,56.57 C671.2
N17448854: length 2
  TOP w0.305: U63.52 100.51,55.92 R467.1
N17448855: length 2
  TOP w0.305: U63.55 100.6,53.97 R467.2
N17448859: length 1.8
  TOP w0.305: R469.2 119.03,60.47 U63.16
N17448862: length 1.9
  TOP w0.305: C673.1 118.88,59.82 U63.15
N17448864: length 21.3
  TOP w0.305: U62.1 113.28,46.61 v1(114.17,47.5) 113.83,47.84 U63.77
  TOP w0.508: F5.1 113.28,34.8 U62.8 U62.1
  BOTTOM w0.305: R452.2 116.2,48.13 115.57,47.5 v1(114.17,47.5) 114.05,47.62 C661.1
N17448865: length 28.5
  TOP w0.305: U63.71 109.93,48.19 v1(110.62,47.5) 110.62,46.86 109.47,45.72 U62.4
  TOP w0.508: F6.1 109.47,34.16 U62.5 U62.4
  BOTTOM w0.305: C662.2 111.89,48.77 v1(110.62,47.5) 111.63,46.48 117.09,46.48 118.36,47.75 R444.2
N17448866: length 24.4
  TOP w0.305: U63.13 116.31,58.52 v1(116.08,58.29)
  L3SIG w0.305: v1(116.08,58.29) 115.57,58.29 115.06,57.78 115.06,56.13 116.08,55.12 116.08,45.34 114.43,43.69 v1(114.43,38.73)
  BOTTOM w0.305: v1(114.43,38.73) 114.43,38.33 R720.1
N17448867: length 27.5
  TOP w0.305: v1(116.08,59.31) 116.22,59.17 U63.14
  L3SIG w0.305: v1(116.08,59.31) 114.81,59.31 112.9,57.4 112.9,47.37 108.33,42.8 v1(108.33,38.73)
  BOTTOM w0.305: R721.1 108.33,38.2 v1(108.33,38.73)
N17448868: length 1.7
  BOTTOM w0.305: R452.1 C659.2
N17448869: length 4
  TOP w0.305: v1(116.08,57.28) 116.13,57.22 U63.11
  BOTTOM w0.305: v1(116.08,57.28) 116.08,54.72 C659.1
N17448871: length 4.6
  TOP w0.305: U63.12 118.53,57.87 v1(118.62,57.78)
  BOTTOM w0.305: v1(118.62,57.78) 118.62,54.85 C660.1
N17448872: length 1.7
  BOTTOM w0.305: R444.1 C660.2
N17448897: length 27.8
  TOP w0.305: U63.67 107.33,48.14 v1(106.68,47.5) 106.05,46.86 105.16,46.86 104.39,46.1 U64.1
  TOP w0.508: U64.1 U64.8 104.39,34.8 F7.1
  BOTTOM w0.305: R459.2 100.84,47.37 101.73,46.48 105.66,46.48 v1(106.68,47.5) 107.32,48.13 C664.1
N17448901: length 22.3
  TOP w0.305: U63.61 103.43,47.55 v1(103.38,47.5) 102.87,46.99 101.6,46.99 100.58,45.97 U64.4
  TOP w0.508: U64.4 U64.5 100.58,34.16 F8.1
  BOTTOM w0.305: R461.2 103,47.88 v1(103.38,47.5) 104.52,47.5 105.16,48.13 C667.2
N17448912: length 4.1
  TOP w0.305: v1(100.58,57.28) 100.64,57.22 U63.50
  BOTTOM w0.305: C666.1 100.58,54.85 v1(100.58,57.28)
N17448913: length 4.6
  TOP w0.305: v1(103.12,57.78) 103.04,57.87 U63.49
  BOTTOM w0.305: C668.1 103.12,54.72 v1(103.12,57.78)
N17448914: length 25.4
  TOP w0.305: U63.47 102.73,59.17 v1(103.12,59.56)
  L3SIG w0.305: v1(105.54,38.73) 105.54,58.04 104.01,59.56 v1(103.12,59.56)
  BOTTOM w0.305: R722.1 105.54,38.33 v1(105.54,38.73)
N17448915: length 24.8
  TOP w0.305: U63.48 102.97,58.52 v1(103.12,58.67)
  L3SIG w0.305: v1(99.44,38.73) 99.44,43.05 101.85,45.47 101.85,58.04 102.49,58.67 v1(103.12,58.67)
  BOTTOM w0.305: R723.1 99.44,38.2 v1(99.44,38.73)
N17449042: length 4.8
  TOP w0.305: v1(100.58,60.32) 100.73,60.47 U63.45
  BOTTOM w0.305: R460.2 R463.2 99.95,60.96 v1(100.58,60.32)
N17449050: length 2.2
  TOP w0.127: R447.2 111,66.29 110.58,65.87 U63.29
N17449051: length 2.2
  TOP w0.127: U63.26 112.53,65.79 113.03,66.29 R446.2
N17449052: length 1.7
  BOTTOM w0.305: R459.1 C666.2
N17449053: length 1.7
  BOTTOM w0.305: R461.1 C668.2
N17451420: length 16.5
  TOP w0.254: R468.1 118.71,29.62 D22.1 118.71,26.5 117.73,25.53 117.73,16.07 J25.1
N17481068: length 1.4
  TOP w0.127: U1.R5 v2(166.92,106.05)
  BOTTOM w0.127: R100.2 166.91,106.04 v2(166.92,106.05)
N17523688: length 1.8
  TOP w0.127: U84.2 13.21,63.76 13.34,63.88 13.34,64.14 13.21,64.26 U84.3
N17523697: length 1.7
  TOP w0.127: U84.5 8.26,64.76 R713.1
N17523706: length 2.8
  TOP w0.127: C896.1 R715.2 8.5,63.87 8.89,64.26 U84.6
N17524661: length 4.8
  TOP w0.254: Q28.3 53.91,131.77 Q29.1 53.9,132.6 C892.1 R704.1
N17525004: length 6.5
  TOP w0.254: D34.2 57.56,126.75 Q27.3 53.91,127.7 Q28.1 53.9,128.53 R703.1
N17540556: length 27.7
  TOP w0.127: v1(87.25,66.04) 87.07,65.86 U59.30
  BOTTOM w0.127: R417.2 109.86,66.17 108.84,65.15 104.62,65.15 104.62,65.15 104.35,65.15 102.83,66.68 100.46,66.68 98.81,68.33 89.07,68.33 88.05,67.31 87.76,67.31 87.25,66.8 v1(87.25,66.04)
N17540577: length 27.4
  TOP w0.127: U59.33 85.12,66.01 v1(85.09,66.04)
  BOTTOM w0.127: R425.2 107.31,66.17 104.68,66.17 103.16,67.69 100.84,67.69 99.25,69.28 88.68,69.28 87.66,68.26 86.67,68.26 85.09,66.68 v1(85.09,66.04)
N17540598: length 2.1
  TOP w0.127: U63.30 109.93,66.63 R445.2
N17540619: length 2.2
  TOP w0.127: U63.33 107.98,65.89 107.7,66.17 R450.2
N17582904: length 2.2
  TOP w0.508: T5.24 v1(215.43,30.44)
  BOTTOM w0.508: v1(215.43,30.44) 215.56,30.31 R332.1
N17582906: length 14.5
  BOTTOM w0.508: 210.91,28.83 211.42,28.32 213.49,28.32 213.96,28.79 R332.2 ; 210.91,28.83 R334.2 ; 210.91,28.83 210.91,28.79 210.44,28.32 208.37,28.32 207.86,28.83 ; C499.2 202.84,29.34 R338.2 204.81,28.83 205.32,28.32 207.35,28.32 207.86,28.83 ; 207.86,28.83 R336.2
N17582916: length 2.2
  TOP w0.508: T5.21 v1(212.43,30.44)
  BOTTOM w0.508: v1(212.43,30.44) 212.51,30.36 R334.1
N17582920: length 2.2
  TOP w0.508: T5.18 v1(209.43,30.44)
  BOTTOM w0.508: R336.1 209.46,30.41 v1(209.43,30.44)
N17582932: length 2.2
  TOP w0.508: T5.15 v1(206.43,30.44)
  BOTTOM w0.508: R338.1 206.41,30.42 v1(206.43,30.44)
N17584869: length 4.2
  TOP w0.127: U55.C10 216.95,69.85 218.82,69.85 218.96,69.98 R291.1
N17602850: length 1.9
  TOP w0.508: T5.1 v1(215.43,39.81)
  BOTTOM w0.508: v1(215.43,39.81) 215.39,39.77 C490.2
N17602860: length 1.9
  TOP w0.508: T5.4 v1(212.43,39.81)
  BOTTOM w0.508: v1(212.43,39.81) 212.47,39.77 C493.2
N17602866: length 1.9
  TOP w0.508: T5.7 v1(209.43,39.81)
  BOTTOM w0.508: C495.2 209.42,39.8 v1(209.43,39.81)
N17602896: length 1.9
  TOP w0.508: T5.10 v1(206.43,39.81)
  BOTTOM w0.508: v1(206.43,39.81) 206.38,39.75 C497.2
N17604579: length 4.8
  TOP w0.127: U55.C7 216.96,67.1 217.68,67.82 218.31,67.82 219.2,68.71 220.61,68.71 R302.2
N17629033: length 3
  TOP w0.127: R294.1 204.72,66.04 205.29,65.48 U55.B12
N17629034: length 4.6
  TOP w0.127: U55.D26 207.95,65.02 207.39,65.02 207.03,64.67 205.13,64.67 204.47,64.01 R295.1
N17629035: length 3.8
  TOP w0.127: U55.C19 207.49,65.64 206.88,65.02 R293.1
N17629369: length 4.1
  TOP w0.127: U55.B5 217.45,67.08 217.81,67.44 219.71,67.44 220.22,67.95 R292.2
N17629454: length 2.7
  TOP w0.102: U55.D8 216.48,67.87 216.48,68.25 216.47,68.27 216.47,68.54 v2(216.74,69.04)
  BOTTOM w0.127: R297.2 216.92,68.85 v2(216.74,69.04)
N17629729: length 3.1
  TOP w0.127: U55.A7 211.5,57.27 211.45,57.23 C440.1
N17629871: length 3.2
  TOP w0.127: R303.2 212.47,57.23 212.15,57.55 U55.A8
N17632317: length 2.1
  TOP w0.508: T7.24 v1(206.54,45.16)
  BOTTOM w0.508: v1(206.54,45.16) 206.5,45.12 R344.1
N17632319: length 10.9
  BOTTOM w0.508: R344.2 R346.2 R348.2 R350.2 195.59,42.63 C513.2
N17632321: length 2.1
  TOP w0.508: T7.21 v1(203.54,45.16)
  BOTTOM w0.508: v1(203.54,45.16) 203.45,45.07 R346.1
N17632325: length 2.1
  TOP w0.508: T7.18 v1(200.54,45.16)
  BOTTOM w0.508: v1(200.54,45.16) 200.53,45.15 R348.1
N17632337: length 2.1
  TOP w0.508: T7.15 v1(197.54,45.16)
  BOTTOM w0.508: v1(197.54,45.16) 197.48,45.1 R350.1
N17632390: length 1.9
  TOP w0.508: T7.1 v1(206.54,54.41)
  BOTTOM w0.508: C505.2 206.5,54.37 v1(206.54,54.41)
N17632398: length 1.9
  TOP w0.508: T7.4 v1(203.54,54.41)
  BOTTOM w0.508: v1(203.54,54.41) 203.58,54.37 C507.2
N17632406: length 1.9
  TOP w0.508: T7.7 v1(200.54,54.41)
  BOTTOM w0.508: v1(200.54,54.41) 200.53,54.4 C509.2
N17632436: length 1.9
  TOP w0.508: T7.10 v1(197.54,54.41)
  BOTTOM w0.508: C511.2 197.48,54.36 v1(197.54,54.41)
N17632726: length 14.5
  BOTTOM w0.508: R358.2 228.05,28.83 ; 228.05,28.83 228.56,28.32 230.63,28.32 231.1,28.79 R356.2 ; 228.05,28.83 228.05,28.79 227.58,28.32 225.51,28.32 225.01,28.83 ; C527.2 219.99,29.34 R362.2 221.96,28.83 222.47,28.32 224.5,28.32 225.01,28.83 ; 225.01,28.83 R360.2
N17632728: length 2.2
  TOP w0.508: T9.24 v1(232.58,30.44)
  BOTTOM w0.508: v1(232.58,30.44) 232.7,30.31 R356.1
N17632740: length 2.2
  TOP w0.508: T9.18 v1(226.58,30.44)
  BOTTOM w0.508: v1(226.58,30.44) 226.61,30.41 R360.1
N17632744: length 2.2
  TOP w0.508: T9.21 v1(229.58,30.44)
  BOTTOM w0.508: R358.1 229.65,30.36 v1(229.58,30.44)
N17632760: length 2.2
  TOP w0.508: T9.15 v1(223.58,30.44)
  BOTTOM w0.508: R362.1 223.56,30.42 v1(223.58,30.44)
N17632797: length 1.9
  TOP w0.508: T9.4 v1(229.58,39.81)
  BOTTOM w0.508: v1(229.58,39.81) 229.62,39.77 C521.2
N17632805: length 1.9
  TOP w0.508: T9.1 v1(232.58,39.81)
  BOTTOM w0.508: C519.2 232.54,39.77 v1(232.58,39.81)
N17632821: length 1.9
  TOP w0.508: T9.7 v1(226.58,39.81)
  BOTTOM w0.508: C523.2 226.57,39.8 v1(226.58,39.81)
N17632853: length 1.9
  TOP w0.508: T9.10 v1(223.58,39.81)
  BOTTOM w0.508: C525.2 223.52,39.75 v1(223.58,39.81)
N17633242: length 2.1
  TOP w0.508: T11.24 v1(223.69,45.16)
  BOTTOM w0.508: v1(223.69,45.16) 223.65,45.12 R368.1
N17633244: length 11.1
  BOTTOM w0.508: R370.2 220.73,41.89 C542.2 ; R370.2 R372.2 R374.2 ; R370.2 R368.2
N17633254: length 2.1
  TOP w0.508: T11.21 v1(220.69,45.16)
  BOTTOM w0.508: v1(220.69,45.16) 220.73,45.12 R370.1
N17633258: length 2.1
  TOP w0.508: T11.18 v1(217.69,45.16)
  BOTTOM w0.508: v1(217.69,45.16) 217.68,45.15 R372.1
N17633270: length 2.1
  TOP w0.508: T11.15 v1(214.69,45.16)
  BOTTOM w0.508: R374.1 214.76,45.09 v1(214.69,45.16)
N17633303: length 1.9
  TOP w0.508: T11.4 v1(220.69,54.41)
  BOTTOM w0.508: C535.2 220.73,54.37 v1(220.69,54.41)
N17633315: length 1.9
  TOP w0.508: T11.1 v1(223.69,54.41)
  BOTTOM w0.508: C533.2 223.65,54.37 v1(223.69,54.41)
N17633335: length 1.9
  TOP w0.508: T11.7 v1(217.69,54.41)
  BOTTOM w0.508: C537.2 217.68,54.4 v1(217.69,54.41)
N17633357: length 1.9
  TOP w0.508: T11.10 v1(214.69,54.41)
  BOTTOM w0.508: C539.2 214.63,54.36 v1(214.69,54.41)
N17639917: length 3.1
  TOP w0.127: U56.A7 245.79,57.27 245.75,57.23 C485.1
N17639934: length 3.2
  TOP w0.127: U56.A8 246.44,57.55 246.76,57.23 R324.2
N17639958: length 4.2
  TOP w0.127: U56.D18 243.51,71.45 242.32,72.64 R725.2
N17639964: length 4.1
  TOP w0.127: R725.1 243.32,72.65 244.16,71.81 U56.D17
N17639984: length 4.8
  TOP w0.127: R323.2 254.9,68.71 253.49,68.71 252.6,67.82 251.97,67.82 251.25,67.1 U56.C7
N17640717: length 4.2
  TOP w0.127: R312.1 253.25,69.98 253.11,69.85 251.24,69.85 U56.C10
N17640929: length 3
  TOP w0.127: U56.B12 239.58,65.48 239.01,66.04 R315.1
N17640931: length 4.6
  TOP w0.127: R316.1 238.76,64.01 239.42,64.67 241.32,64.67 241.68,65.02 242.24,65.02 U56.D26
N17640933: length 3.8
  TOP w0.127: U56.C19 241.78,65.64 241.17,65.02 R314.1
N17640965: length 4.1
  TOP w0.127: R313.2 254.51,67.95 254,67.44 252.1,67.44 251.74,67.08 U56.B5
N17640979: length 2.7
  TOP w0.102: v2(251.03,69.04) 250.76,68.54 250.76,68.27 250.77,68.25 250.77,67.87 U56.D8
  BOTTOM w0.127: v2(251.03,69.04) 251.21,68.85 R320.2
N17694594: length 5.7
  TOP w0.127: U6.16 96.11,129.39 v1(95.89,129.16)
  BOTTOM w0.127: v1(95.89,129.16) 95.25,128.52 95.25,127.25 94.31,126.31 U7.10
N17694666: length 3.8
  TOP w0.127: U6.8 v1(95.16,125.39)
  BOTTOM w0.127: v1(95.16,125.39) 95.03,125.51 U7.12
N17694695: length 4.1
  TOP w0.127: v1(94.23,131.06) 95.5,131.06 96.18,130.39 U6.18
  BOTTOM w0.127: U11.12 93.94,131.35 v1(94.23,131.06)
N17694723: length 4.1
  TOP w0.127: U6.19 96.19,130.88 95.63,131.44 94.62,131.44 v1(94.23,131.83)
  BOTTOM w0.127: U11.11 94.16,131.75 v1(94.23,131.83)
N17736577: length 1.9
  TOP w0.127: SW1.16 v1(72.77,144.02)
  BOTTOM w0.127: R17.1 v1(72.77,144.02)
N17736598: length 1.9
  TOP w0.127: SW1.15 v1(74.04,144.02)
  BOTTOM w0.127: R19.1 v1(74.04,144.02)
N17736619: length 1.9
  TOP w0.127: SW1.14 v1(75.31,144.02)
  BOTTOM w0.127: R21.1 v1(75.31,144.02)
N17736629: length 1.9
  TOP w0.127: SW1.13 v1(76.58,144.02)
  BOTTOM w0.127: R23.1 v1(76.58,144.02)
N17736659: length 1.9
  TOP w0.127: SW1.12 v1(77.85,144.02)
  BOTTOM w0.127: R25.1 v1(77.85,144.02)
N17736669: length 1.9
  TOP w0.127: SW1.11 v1(79.12,144.02)
  BOTTOM w0.127: R27.1 v1(79.12,144.02)
N17736681: length 1.9
  TOP w0.127: SW1.10 v1(80.39,144.02)
  BOTTOM w0.127: R29.1 v1(80.39,144.02)
N17736695: length 1.9
  TOP w0.127: 81.66,145.16 v1(81.66,144.02)
  BOTTOM w0.127: R31.1 v1(81.66,144.02)
N17736739: length 1.9
  TOP w0.127: SW2.16 v1(85.47,144.02)
  BOTTOM w0.127: R33.1 v1(85.47,144.02)
N17736751: length 1.9
  TOP w0.127: 86.74,145.16 v1(86.74,144.02)
  BOTTOM w0.127: R34.1 v1(86.74,144.02)
N17736763: length 1.9
  TOP w0.127: SW2.14 v1(88.01,144.02)
  BOTTOM w0.127: R35.1 v1(88.01,144.02)
N17736781: length 1.9
  TOP w0.127: SW2.13 v1(89.28,144.02)
  BOTTOM w0.127: R36.1 v1(89.28,144.02)
N17736801: length 1.9
  TOP w0.127: SW2.11 v1(91.82,144.02)
  BOTTOM w0.127: R39.1 v1(91.82,144.02)
N17736803: length 1.9
  TOP w0.127: SW2.12 v1(90.55,144.02)
  BOTTOM w0.127: R37.1 v1(90.55,144.02)
N17736817: length 1.9
  TOP w0.127: SW2.10 v1(93.09,144.02)
  BOTTOM w0.127: R38.1 v1(93.09,144.02)
N17736835: length 1.9
  TOP w0.127: SW2.9 v1(94.36,144.02)
  BOTTOM w0.127: R40.1 v1(94.36,144.02)
N17775417: length 46.4
  TOP w0.127: R342.2 v1(222.63,63.75) C501.2
  L6SIG w0.102: J15.A12 220.25,26 218.69,27.56 218.69,39.62 221.49,42.42 223.65,42.42 225.42,44.2 225.42,56.64 223.39,58.67 223.39,63.25 222.88,63.75 v1(222.63,63.75)
N17775429: length 52.7
  TOP w0.127: R340.2 v1(222.63,62.74) C503.2
  L6SIG w0.102: v1(222.63,62.74) 222.5,62.74 221.87,62.1 221.87,59.05 224.66,56.26 224.66,44.58 223.27,43.18 221.11,43.18 217.93,40.01 217.93,26.8 216.06,24.93 J15.A10
N17779755: length 61
  TOP w0.127: C515.2 v1(222.63,61.72) R354.2
  L6SIG w0.102: v1(222.63,61.72) 222.63,59.05 225.17,56.51 225.17,44.32 223.52,42.67 221.36,42.67 218.44,39.75 218.44,26.54 219.07,25.91 219.07,24.26 220.25,23.08 J15.B12
N17779761: length 78.3
  L6SIG w0.102: v1(218.95,65.15) 219.71,64.39 221.36,64.39 222.5,63.25 222.88,63.25 223.14,62.99 223.14,62.48 222.89,62.23 222.45,62.23 222.12,61.91 222.12,59.18 224.92,56.39 224.92,44.45 223.39,42.93 221.23,42.93 218.19,39.88 218.19,26.42 218.82,25.78 218.82,24.13 219.96,22.99 219.96,9.91 219.33,9.27 216.92,9.27 215.81,8.17 J15.B10
  BOTTOM w0.127: R352.2 218.18,65.02 C517.2 218.81,65.02 v1(218.95,65.15)
N17780053: length 67.3
  L6SIG w0.102: v1(219.84,65.15) 222,67.31 222.88,67.31 224.41,65.79 224.41,59.18 226.44,57.15 226.44,43.69 224.16,41.4 222,41.4 220.47,39.88 220.47,28.07 221.74,26.8 234.13,26.8 J15.C12
  BOTTOM w0.127: R366.2 219.58,66.04 C529.2 219.58,65.41 v1(219.84,65.15)
N17780059: length 51.5
  TOP w0.127: R364.2 v1(222.63,66.8) C531.2
  L6SIG w0.102: J15.C10 223.2,26.54 221.49,26.54 220.22,27.81 220.22,40 221.87,41.66 224.03,41.66 226.19,43.81 226.19,57.02 224.16,59.05 224.16,65.28 v1(222.63,66.8)
N17780366: length 79.7
  TOP w0.127: C540.2 v1(222.63,65.79) R376.2
  L6SIG w0.102: v1(222.63,65.79) 223.9,64.52 223.9,58.93 225.93,56.9 225.93,43.94 223.9,41.91 221.74,41.91 219.2,39.37 219.2,28.07 220.98,26.29 222.88,26.29 223.65,25.53 223.65,24.26 222.76,23.37 222.76,10.67 224.16,9.27 234.9,9.27 J15.D12
N17780372: length 67.7
  TOP w0.127: C543.2 v1(222.63,64.77) R375.2
  L6SIG w0.102: J15.D10 222.5,10.48 222.5,23.49 223.39,24.38 223.39,25.4 222.76,26.03 220.85,26.03 218.95,27.94 218.95,39.5 221.61,42.16 223.77,42.16 225.68,44.07 225.68,56.77 223.65,58.8 223.65,63.75 v1(222.63,64.77)
N17787749: length 78.2
  TOP w0.127: R378.2 v1(256.92,65.79) C546.2
  L6SIG w0.102: v1(256.92,65.79) 258.19,64.52 258.19,58.67 260.35,56.52 260.35,43.81 258.32,41.78 255.79,41.78 253.36,39.36 253.36,27.43 255.14,25.65 255.14,23.75 253.75,22.35 253.75,11.3 255.65,9.4 266.27,9.4 J15.H12
N17787773: length 66.3
  TOP w0.127: R377.2 v1(256.92,64.77) C547.2
  L6SIG w0.102: v1(256.92,64.77) 257.94,63.75 257.94,58.55 260.1,56.39 260.1,43.94 258.19,42.04 255.65,42.04 253.11,39.5 253.11,27.3 254.89,25.53 254.89,23.88 253.49,22.48 253.49,10.99 J15.H10
N17787818: length 14.5
  BOTTOM w0.508: R331.2 248.25,28.79 247.78,28.32 245.71,28.32 245.2,28.83 ; C498.2 237.13,29.34 R337.2 239.1,28.83 239.61,28.32 241.66,28.32 242.15,28.81 ; 245.2,28.83 245.2,28.79 244.73,28.32 242.64,28.32 242.15,28.81 ; 245.2,28.83 R333.2 ; R335.2 242.15,28.81
N17787822: length 11.1
  BOTTOM w0.508: R349.2 R347.2 R345.2 ; R345.2 237.87,42.01 C512.2 ; R345.2 R343.2
N17787848: length 16.9
  BOTTOM w0.508: C526.2 268.76,28.98 268.1,28.32 265.86,28.32 265.39,28.79 ; 262.34,28.83 262.34,28.79 261.87,28.32 259.8,28.32 259.3,28.83 ; 262.34,28.83 262.85,28.32 264.92,28.32 265.39,28.79 ; 262.34,28.83 R357.2 ; 265.39,28.79 R355.2 ; 259.3,28.83 R359.2 ; 259.3,28.83 258.79,28.32 256.76,28.32 256.25,28.83 R361.2
N17787852: length 11.3
  BOTTOM w0.508: R369.2 255.02,42.01 C541.2 ; R369.2 R371.2 R373.2 ; R369.2 R367.2
N17787943: length 2.2
  TOP w0.508: T4.24 v1(249.72,30.44)
  BOTTOM w0.508: R331.1 249.85,30.31 v1(249.72,30.44)
N17787947: length 2.2
  TOP w0.508: T4.21 v1(246.72,30.44)
  BOTTOM w0.508: R333.1 246.8,30.36 v1(246.72,30.44)
N17787951: length 2.2
  TOP w0.508: T4.18 v1(243.72,30.44)
  BOTTOM w0.508: v1(243.72,30.44) 243.75,30.41 R335.1
N17787955: length 2.2
  TOP w0.508: T4.15 v1(240.72,30.44)
  BOTTOM w0.508: v1(240.72,30.44) 240.7,30.42 R337.1
N17787993: length 1.9
  TOP w0.508: T4.1 v1(249.72,39.81)
  BOTTOM w0.508: v1(249.72,39.81) 249.68,39.77 C491.2
N17788013: length 1.9
  TOP w0.508: T4.4 v1(246.72,39.81)
  BOTTOM w0.508: C492.2 246.76,39.77 v1(246.72,39.81)
N17788019: length 1.9
  TOP w0.508: T4.7 v1(243.72,39.81)
  BOTTOM w0.508: v1(243.72,39.81) 243.71,39.8 C494.2
N17788035: length 1.9
  TOP w0.508: T4.10 v1(240.72,39.81)
  BOTTOM w0.508: v1(240.72,39.81) 240.66,39.75 C496.2
N17788175: length 2.1
  TOP w0.508: T6.24 v1(240.83,45.16)
  BOTTOM w0.508: v1(240.83,45.16) 240.79,45.12 R343.1
N17788179: length 2.1
  TOP w0.508: T6.21 v1(237.83,45.16)
  BOTTOM w0.508: R345.1 237.87,45.12 v1(237.83,45.16)
N17788183: length 2.1
  TOP w0.508: T6.18 v1(234.83,45.16)
  BOTTOM w0.508: v1(234.83,45.16) 234.82,45.15 R347.1
N17788187: length 2.1
  TOP w0.508: T6.15 v1(231.83,45.16)
  BOTTOM w0.508: v1(231.83,45.16) 231.9,45.09 R349.1
N17788233: length 1.9
  TOP w0.508: T6.1 v1(240.83,54.41)
  BOTTOM w0.508: v1(240.83,54.41) 240.79,54.37 C504.2
N17788241: length 1.9
  TOP w0.508: T6.4 v1(237.83,54.41)
  BOTTOM w0.508: C506.2 237.87,54.37 v1(237.83,54.41)
N17788251: length 1.9
  TOP w0.508: T6.7 v1(234.83,54.41)
  BOTTOM w0.508: C508.2 234.82,54.4 v1(234.83,54.41)
N17788275: length 1.9
  TOP w0.508: T6.10 v1(231.83,54.41)
  BOTTOM w0.508: C510.2 231.77,54.36 v1(231.83,54.41)
N17788409: length 2.2
  TOP w0.508: T8.21 v1(263.87,30.44)
  BOTTOM w0.508: v1(263.87,30.44) 263.94,30.36 R357.1
N17788413: length 2.2
  TOP w0.508: T8.24 v1(266.87,30.44)
  BOTTOM w0.508: v1(266.87,30.44) 266.99,30.31 R355.1
N17788425: length 2.2
  TOP w0.508: T8.15 v1(257.87,30.44)
  BOTTOM w0.508: v1(257.87,30.44) 257.85,30.42 R361.1
N17788429: length 2.2
  TOP w0.508: T8.18 v1(260.87,30.44)
  BOTTOM w0.508: R359.1 260.9,30.41 v1(260.87,30.44)
N17788459: length 1.9
  TOP w0.508: T8.4 v1(263.87,39.81)
  BOTTOM w0.508: v1(263.87,39.81) 263.91,39.77 C520.2
N17788477: length 2
  TOP w0.508: T8.1 v1(266.87,39.81)
  BOTTOM w0.508: C518.2 266.95,39.72 v1(266.87,39.81)
N17788487: length 1.9
  TOP w0.508: T8.7 v1(260.87,39.81)
  BOTTOM w0.508: C522.2 260.86,39.8 v1(260.87,39.81)
N17788519: length 1.9
  TOP w0.508: T8.10 v1(257.87,39.81)
  BOTTOM w0.508: C524.2 257.81,39.75 v1(257.87,39.81)
N17788647: length 2.1
  TOP w0.508: T10.24 v1(257.98,45.16)
  BOTTOM w0.508: R367.1 258.06,45.07 v1(257.98,45.16)
N17788651: length 2.1
  TOP w0.508: T10.21 v1(254.98,45.16)
  BOTTOM w0.508: R369.1 255.02,45.12 v1(254.98,45.16)
N17788663: length 2.1
  TOP w0.508: T10.18 v1(251.98,45.16)
  BOTTOM w0.508: v1(251.98,45.16) 251.97,45.15 R371.1
N17788667: length 2.1
  TOP w0.508: T10.15 v1(248.98,45.16)
  BOTTOM w0.508: R373.1 249.05,45.09 v1(248.98,45.16)
N17788695: length 1.9
  TOP w0.508: T10.4 v1(254.98,54.41)
  BOTTOM w0.508: v1(254.98,54.41) 255.02,54.37 C534.2
N17788701: length 1.9
  TOP w0.508: T10.1 v1(257.98,54.41)
  BOTTOM w0.508: C532.2 257.94,54.37 v1(257.98,54.41)
N17788725: length 1.9
  TOP w0.508: T10.7 v1(251.98,54.41)
  BOTTOM w0.508: v1(251.98,54.41) 251.97,54.4 C536.2
N17788759: length 1.9
  TOP w0.508: T10.10 v1(248.98,54.41)
  BOTTOM w0.508: C538.2 248.92,54.36 v1(248.98,54.41)
N17788879: length 46.6
  TOP w0.127: C500.2 v1(256.92,63.75) R341.2
  L6SIG w0.102: v1(256.92,63.75) 257.18,63.75 257.68,63.25 257.68,58.42 259.84,56.26 259.84,44.07 258.06,42.29 255.52,42.29 252.86,39.62 252.86,26.03 J15.E12
N17788889: length 54.6
  TOP w0.127: R339.2 v1(256.92,62.74) C502.2
  L6SIG w0.102: v1(256.92,62.74) 256.79,62.74 256.16,62.1 256.16,58.8 259.08,55.88 259.08,44.45 257.68,43.05 255.14,43.05 252.09,40 252.09,28.7 249.55,26.16 241.81,26.16 J15.E10
N17788969: length 61.8
  TOP w0.127: R353.2 v1(256.92,61.72) C514.2
  L6SIG w0.102: v1(256.92,61.72) 256.92,58.8 259.59,56.13 259.59,44.2 257.94,42.55 255.4,42.55 252.6,39.75 252.6,28.32 250.7,26.42 250.7,23.75 251.75,22.7 J15.F12
N17788975: length 78.9
  L6SIG w0.102: v1(253.24,65.15) 254,64.39 255.27,64.39 256.41,63.25 257.18,63.25 257.43,62.99 257.43,62.48 257.18,62.23 256.67,62.23 256.41,61.98 256.41,58.93 259.33,56.01 259.33,44.32 257.81,42.8 255.27,42.8 252.35,39.88 252.35,28.45 250.44,26.54 250.44,23.62 251.46,22.61 251.46,10.29 250.57,9.4 248.16,9.4 246.93,8.17 J15.F10
  BOTTOM w0.127: R351.2 252.47,65.02 C516.2 253.1,65.02 v1(253.24,65.15)
N17789051: length 66.6
  L6SIG w0.102: v1(254.13,65.15) 256.29,67.31 257.18,67.31 258.7,65.79 258.7,58.93 260.86,56.77 260.86,43.56 258.57,41.27 256.03,41.27 254.63,39.88 254.63,27.05 255.4,26.29 260.48,26.29 263.14,23.62 266.19,23.62 267.5,24.93 J15.G12
  BOTTOM w0.127: R365.2 253.87,66.04 C528.2 253.87,65.41 v1(254.13,65.15)
N17789057: length 49.8
  TOP w0.127: R363.2 v1(256.92,66.8) C530.2
  L6SIG w0.102: J15.G10 254.38,26.87 254.38,40 255.91,41.53 258.44,41.53 260.6,43.69 260.6,56.64 258.44,58.8 258.44,65.28 v1(256.92,66.8)
N17823659: length 4.5
  TOP w0.102: U55.D12 214.6,69.98 214.76,69.98 215.14,70.36 215.14,71.37 214.38,72.14 214.38,73.41 C411.2
N17823662: length 4.4
  TOP w0.102: U55.D11 215.07,69.9 215.42,70.24 215.42,71.49 214.66,72.25 214.66,72.93 214.76,73.03 214.76,73.03 C410.2
N17824163: length 4.5
  TOP w0.102: C456.2 249.02,73.06 249.02,71.26 249.43,70.85 249.43,70.36 249.05,69.98 248.89,69.98 U56.D12
N17824166: length 4.2
  TOP w0.102: U56.D11 249.36,69.9 249.71,70.24 249.71,70.97 249.3,71.37 249.3,73.29 C455.2
N18271716: length 2.5
  TOP w0.127: R666.2 R669.2 40.75,105.16 Q15.1
N18271718: length 4.9
  TOP w0.254: R662.2 C873.2 41.77,101.85 R659.2 40.14,101.85 39.12,102.86 Q15.3
N18271794: length 1.3
  TOP w0.254: R659.1 40.72,100.8 Q11.4
N18272048: length 2.6
  TOP w0.127: R665.2 R667.2 126.94,113.34 Q13.1
N18272050: length 5.3
  TOP w0.254: R657.2 131.56,112.4 Q13.3 129.29,113.28 C871.2 R660.2
N18272126: length 9.3
  TOP w0.254: v1(131.83,110.11) 131.57,110.37 R657.1
  L6SIG w0.508: v1(131.83,110.11) v1(131.83,103.76)
  BOTTOM w0.508: Q8.4 v1(131.83,110.11) ; Q9.4 v1(131.83,103.76)
N18272820: length 4.9
  TOP w0.254: R678.2 C875.2 79.23,80.89 R675.2 77.6,80.89 76.59,81.91 Q20.3
N18272822: length 2.5
  TOP w0.127: R681.2 R684.2 78.22,84.21 Q20.1
N18272905: length 1.3
  TOP w0.254: R675.1 78.18,79.84 Q17.4
N18273179: length 2.6
  TOP w0.127: Q21.1 39.19,95.5 R685.2 40.77,95.5 R682.2
N18273181: length 6.4
  TOP w0.254: R676.2 42.8,92.7 R679.2 C876.2 41.51,93.21 Q21.3
N18273262: length 1.4
  TOP w0.254: R676.1 42.05,91.07 Q18.4
N18273767: length 2.5
  TOP w0.127: Q16.1 18.09,69.73 R671.2 R670.2
N18273907: length 4.2
  TOP w0.254: Q12.4 20.07,73.41 C874.2 R663.2 Q16.3
N18275087: length 4
  TOP w0.305: U81.1 229.08,148.19 229.48,148.58 C887.1 ; R695.1 230.12,148.59 C887.1 ; C887.1 R696.2
N18275123: length 3
  TOP w0.305: R694.1 224.53,148.59 C884.1 224.54,148.59 225.3,148.59 225.7,148.19 U81.5
N18275169: length 1.6
  TOP w0.127: R697.1 227.83,143.65 U81.9
N18287015: length 6.9
  TOP w0.127: R138.1 149.99,60.71 149.03,59.75 149.03,58.48 149.49,58.02 U23.4 149.67,57.59 149.03,56.96 149.03,55.69 149.49,55.23 U24.4
N18382428: length 1.9
  TOP w0.127: SW3.16 v1(98.17,144.02)
  BOTTOM w0.127: R499.1 v1(98.17,144.02)
N18382505: length 1.9
  TOP w0.127: SW3.15 v1(99.44,144.02)
  BOTTOM w0.127: R500.1 v1(99.44,144.02)
N18382570: length 1.9
  TOP w0.127: SW3.14 v1(100.71,144.02)
  BOTTOM w0.127: R501.1 v1(100.71,144.02)
N18382580: length 1.9
  TOP w0.127: SW3.13 v1(101.98,144.02)
  BOTTOM w0.127: R503.1 v1(101.98,144.02)
N18382664: length 1.9
  TOP w0.127: SW3.11 v1(104.52,144.02)
  BOTTOM w0.127: R507.1 v1(104.52,144.02)
N18382676: length 1.9
  TOP w0.127: 105.79,145.16 v1(105.79,144.02)
  BOTTOM w0.127: R509.1 v1(105.79,144.02)
N18562864: length 2.4
  TOP w0.127: R713.2 7.12,65.21 Q30.1
N18563122: length 15.4
  TOP w0.127: J37.8 10.79,81.36 10.79,71.24 R706.1 R709.2
N18564716: length 8
  TOP w0.254: Q26.1 48.96,119.06 47.62,120.4 Q25.3 45.85,120.78 R688.2 44.84,121.92 C878.2 R690.2
N18564718: length 2.7
  TOP w0.127: Q25.1 45.28,117.42 R693.2 R692.2
N18564801: length 14.9
  TOP w0.254: R688.1 v1(46.86,122.67) 46.74,122.56 43.05,122.56 42.55,123.06 Q42.4 ; Q23.4 v1(45.59,130.55)
  L6SIG w0.254: v1(46.86,122.67) 46.86,124.21 45.59,125.48 v1(45.59,130.55)
N18565254: length 9.5
  TOP w0.508: D31.1 70.17,152.43 U82.3 71.69,151.83 72.14,151.38 73.15,151.38 73.59,151.83 U82.1 75.07,152.43 C888.1 77.69,152.18 J31.2
N18565311: length 2.8
  TOP w0.508: J31.1 77,148.88 D30.1
N18565323: length 8.1
  TOP w0.508: J30.1 84.75,147.07 D30.2
N18566414: length 3.7
  TOP w0.254: Q26.3 50.16,120.65 R689.1 51.17,121.92 C879.1 R691.1
N18566880: length 12.4
  TOP w0.254: Q43.4 52.11,125.56 ; 52.11,125.56 51.9,125.56 51.56,125.22 51.56,122.93 51.18,122.56 49.41,122.56 49.16,122.3 R689.2 ; 52.11,125.56 51.43,126.24 v1(51.43,126.87) ; Q24.4 v1(47.5,127.39)
  L3SIG w0.254: v1(51.43,126.87) 50.92,127.39 v1(47.5,127.39)
N18586245: length 2.8
  BOTTOM w0.254: R205.2 148.85,121.03 C294.2 148.45,121.02 148.28,120.85 U45.2
N18586247: length 2.8
  BOTTOM w0.254: R206.2 148.85,120.02 C294.1 148.51,120.02 148.34,120.2 U45.3
N18629376: length 3.9
  TOP w0.102: C405.2 211.12,73.33 arc(211.01,73.17) 210.97,72.98 210.97,70.13 arc(211,70.01) 211.07,69.91 U55.D15
N18629379: length 4
  TOP w0.102: U55.D16 210.63,69.91 arc(210.7,70.01) 210.72,70.13 210.72,72.92 arc(210.68,73.12) 210.57,73.28 C400.2
N18629428: length 3.9
  TOP w0.127: C454.2 245.31,73.24 245.31,69.95 U56.D15
N18629431: length 3.9
  TOP w0.127: U56.D16 244.96,69.95 244.96,73.18 C445.2
N18629823: length 4.1
  TOP w0.127: J21.3 254.56,108.51 251.53,108.51 C633.2
N18629826: length 4.1
  TOP w0.127: J21.2 254.56,108.15 251.53,108.15 C632.2
N18629885: length 11.8
  TOP w0.127: J21.5 256.9,111.51 arc(257.34,111.69) 257.53,112.14 257.53,113.54 arc(257,114.83) 255.71,115.37 251.75,115.37 arc(251.55,115.41) 251.37,115.52 C634.2
N18629888: length 11.5
  TOP w0.127: J21.6 255.78,112.78 arc(255.87,112.74) 255.91,112.65 255.91,111.99 arc(255.94,111.9) 256.03,111.86 256.9,111.86 arc(257.09,111.94) 257.18,112.14 257.18,113.54 arc(256.74,114.58) 255.71,115.01 251.75,115.01 arc(251.55,114.97) 251.37,114.85 C635.2
N18635664: length 4.1
  TOP w0.127: D40.1 50.67,8.25 49.65,9.28 R470.2
N18636077: length 3.6
  TOP w0.127: D41.1 42.03,6.4 R471.2
N18636082: length 3.6
  TOP w0.127: R472.2 46.35,6.4 D42.1
N18636371: length 3.6
  TOP w0.127: R439.2 33.39,6.4 D38.1
N18636375: length 3.6
  TOP w0.127: R440.2 37.71,6.4 D39.1
N18648944: length 3.6
  TOP w0.127: D36.1 54.98,6.4 R394.2
N18648948: length 3.8
  TOP w0.127: 59.31,6.39 59.31,9.64 R395.2
N18669250: length 4.3
  BOTTOM w0.254: R557.1 R560.2 C761.1 96.89,81.15 97.56,81.82 U70.9
N18669461: length 3.7
  BOTTOM w0.127: U70.8 98.96,80.67 98.68,80.39 97.54,80.39 R568.2
N18669908: length 2.1
  BOTTOM w0.127: U70.14 96.52,84.32 R573.2
N18671161: length 5.2
  BOTTOM w0.127: R575.2 C770.2 94.61,83.82 U70.13
N18671661: length 4.5
  BOTTOM w0.254: U70.31 103.87,82.32 103.94,82.24 105.99,82.24 106.29,82.54 C778.1 107.57,82.54 R576.2
N18671664: length 4.5
  BOTTOM w0.254: R580.2 107.57,81.54 C778.2 106.29,81.54 105.95,81.89 103.99,81.89 103.91,81.82 U70.32
N18671728: length 24.5
  TOP w0.254: R577.1 118.62,99.02 v1(118.62,98.3)
  BOTTOM w0.254: R580.1 109.59,81.53 R578.1 109.86,81.54 110.24,81.92 111.63,81.92 119.35,89.64 119.35,95.4 118.29,96.47 118.29,97.97 v1(118.62,98.3)
N18671731: length 23.9
  TOP w0.254: R577.2 117.6,99.02 v1(117.6,98.3)
  BOTTOM w0.254: R576.1 109.59,82.55 R578.2 109.86,82.54 110.13,82.27 111.48,82.27 119,89.79 119,95.26 117.93,96.32 117.93,97.97 v1(117.6,98.3)
N18672102: length 2.3
  BOTTOM w0.254: U70.4 100.96,80.4 101.85,79.5 R594.2
N18672710: length 3.7
  BOTTOM w0.254: U70.6 99.96,79.3 C795.1
  BOTTOM w0.508: R595.1 99.36,79.11 C795.1
N18673934: length 3.1
  BOTTOM w0.127: R581.1 104.39,85.85 103.86,85.32 U70.25
N18674032: length 4
  BOTTOM w0.127: R582.1 105.41,86.36 103.87,84.82 U70.26
N18675394: length 1.9
  TOP w0.254: R561.1 103,94.87 104.35,94.87 104.56,94.66 U69.24
N18676216: length 1
  TOP w0.254: R561.2 C763.2
N18677032: length 13.5
  BOTTOM w0.254: R565.2 109.59,84.96 C765.1 109.96,84.96 110.26,84.65 111.58,84.65 117.35,90.42 R562.2
N18677238: length 26.3
  TOP w0.254: v1(104.14,104.52) 104.34,104.32 U71.25 ; U69.25 104.34,94.16 v1(104.14,94.36)
  L6SIG w0.102: v1(104.14,104.52) 104.7,103.96 110.16,103.96 112.01,102.11 112.01,100.71 111.25,99.95 111.25,95.38 109.68,93.8 104.7,93.8 v1(104.14,94.36)
  BOTTOM w0.254: R558.2 104.27,94.23 v1(104.14,94.36)
N18679447: length 1.9
  TOP w0.254: U71.24 104.56,104.82 104.35,105.03 103,105.03 R579.1
N18679579: length 1
  TOP w0.254: R579.2 C779.2
N18679604: length 21.3
  BOTTOM w0.254: R586.2 117.48,102.5 117.48,102.01 115.57,100.11 115.57,90.93 111.51,86.87 109.72,86.87 C785.1 109.59,87 R590.2
N18708218: length 2.8
  BOTTOM w0.254: U70.21 100.96,87 100.08,87.88 R588.1
N18708230: length 3
  BOTTOM w0.254: U70.20 100.46,86.74 99.06,88.14 R589.1
N18709569: length 2.1
  BOTTOM w0.254: R593.2 100.84,79.76 100.46,80.13 U70.5
N18711479: length 2.8
  TOP w0.254: R599.2 R598.1 90.29,80.11 U72.4
N19126530: length 1.9
  TOP w0.127: SW3.12 v1(103.25,144.02)
  BOTTOM w0.127: R505.1 v1(103.25,144.02)
N19163046: length 1.8
  TOP w0.127: R495.1 52.2,112.81 X2.3
N19163064: length 1.8
  TOP w0.127: R494.2 50.43,110.37 X2.1
N19211889: length 1.9
  TOP w0.762: R567.2 113.56,89.03 C766.2
N19212054: length 1.9
  TOP w0.762: R592.2 113.56,109.6 C786.2
N19214297: length 4.4
  TOP w0.254: U72.1 89.65,84.2 89.02,84.83 R597.2 87.76,84.83 R596.2 87.75,83.77 C798.2
N19293526: length 1.9
  TOP w0.127: D5.1 R186.2
N19295120: length 1.9
  TOP w0.127: D6.1 R187.2
N19535162: length 2.1
  BOTTOM w0.254: R720.2 R441.1
N19535165: length 2.1
  BOTTOM w0.254: R451.1 R721.2
N19535242: length 2.1
  BOTTOM w0.254: R465.1 R723.2
N19535245: length 2.1
  BOTTOM w0.254: R722.2 R464.1
N19535322: length 2.1
  BOTTOM w0.254: R412.1 R716.2
N19535325: length 2.1
  BOTTOM w0.254: R413.1 R717.2
N19535364: length 2.1
  BOTTOM w0.254: R435.1 R719.2
N19535367: length 2.1
  BOTTOM w0.254: R434.1 R718.2
N19620774: length 25.9
  TOP w0.102: C68.2 189.61,103.51 v1(189.48,103.63) ; U1.AA14 v2(171.72,113.25)
  L3SIG w0.102: v1(189.48,103.63) 189.1,104.01 189.1,108.2 186.66,110.64 181.2,110.64 178.44,113.41 175.39,113.41 175.17,113.63 172.1,113.63 v2(171.72,113.25)
N19620777: length 25.4
  TOP w0.102: U1.AB14 v2(172.52,113.25) ; C67.2 188.59,103.51 v1(188.72,103.63)
  L3SIG w0.102: v1(188.72,103.63) 188.82,103.73 188.82,108.09 186.55,110.36 181.09,110.36 178.32,113.13 175.36,113.13 175.1,112.87 172.25,112.87 172.16,112.96 172.16,113.1 172.3,113.25 v2(172.52,113.25)
N19623883: length 4.4
  TOP w0.254: R784.2 C996.2 202.43,131.69 202.94,132.2 R783.2 203.84,132.72 Q32.3
N19623885: length 2.6
  TOP w0.127: R786.2 202.95,128.53 R785.2 202.95,129.47 Q32.1
N19623968: length 1.7
  TOP w0.254: Q31.4 201.94,134.4 R783.1
N19644915: length 22
  TOP w0.508: R735.1 223.4,135.52 v1(223.39,135.51) R731.2 ; C927.2 217.51,131.66 v1(217.3,131.44)
  L3SIG w0.508: v1(223.39,135.51) 217.93,135.51 216.79,136.65 v1(214.25,136.65)
  BOTTOM w0.508: v1(214.25,136.65) 213.49,136.65 212.85,136.02 212.85,132.84 214.25,131.44 v1(217.3,131.44)
N19644936: length 2.3
  TOP w0.254: R735.2 224.16,137.04 C941.2 223.64,137.54 C943.2
N19644956: length 4.7
  TOP w0.254: U87.5 220.73,137.41 v1(220.85,137.29) 221.37,137.29 C943.1 R736.1 R787.2
  BOTTOM w0.254: v1(220.85,137.29) 220.72,137.15 R745.2
N19644972: length 1.6
  TOP w0.127: U87.3 221.5,136.41 R739.2
N19644986: length 3.3
  TOP w0.127: U87.16 219.2,134.49 219.58,134.11 220.09,134.11 220.47,133.73 R734.2 C932.2
N19645019: length 10.5
  TOP w0.254: v1(219.46,139.7) 219.2,139.44 U87.8 ; R741.1 v1(223.39,134.49)
  BOTTOM w0.508: v1(223.39,134.49) 222.63,134.49 221.87,135.25 221.87,138.43 220.6,139.7 v1(219.46,139.7) 219.19,139.44 C946.1
N19645035: length 3
  TOP w0.254: U87.1 220.05,135.04 v1(220.34,134.75) 220.6,134.49 R741.2
  BOTTOM w0.254: R743.2 220.72,135.12 v1(220.34,134.75)
N19645080: length 2.2
  TOP w0.254: U87.6 220.71,137.91 v1(220.85,138.05)
  BOTTOM w0.254: C947.1 220.48,138.42 v1(220.85,138.05)
N19645160: length 1.7
  TOP w0.254: U87.15 218.7,134.22 R728.2
N19645192: length 1.7
  TOP w0.254: U87.14 218.2,133.28 C927.1
N19645200: length 1.7
  TOP w0.254: U87.2 220.71,135.91 221.11,135.51 R731.1
N19646811: length 22
  TOP w0.508: v1(24.13,106.81) 23.91,106.59 C949.2 ; R749.2 v1(18.03,102.74) 18.03,102.74 R755.1
  L3SIG w0.508: v1(27.18,101.6) 24.64,101.6 23.49,102.74 v1(18.03,102.74)
  BOTTOM w0.508: v1(27.18,101.6) 27.94,101.6 28.58,102.23 28.58,105.41 27.18,106.81 v1(24.13,106.81)
N19646830: length 2.3
  TOP w0.254: R755.2 17.27,101.21 C965.2 17.79,100.71 C967.2
N19646848: length 3.7
  TOP w0.254: U89.5 20.69,100.85 v1(20.57,100.97) 20.06,100.97 C967.1 R757.1
  BOTTOM w0.254: R763.2 20.71,101.1 v1(20.57,100.97)
N19646866: length 1.7
  TOP w0.254: U89.2 20.72,102.35 20.32,102.74 R749.1
N19646870: length 1.6
  TOP w0.127: R756.2 19.92,101.85 U89.3
N19646891: length 3.3
  TOP w0.127: C957.2 R754.2 20.95,104.52 21.34,104.14 21.84,104.14 22.23,103.76 U89.16
N19646930: length 10.5
  TOP w0.254: v1(21.97,98.55) 22.23,98.81 U89.8 ; R759.1 v1(18.03,103.76)
  BOTTOM w0.508: C970.1 22.23,98.81 v1(21.97,98.55) 20.83,98.55 19.56,99.82 19.56,103 18.8,103.76 v1(18.03,103.76)
N19646940: length 3
  TOP w0.254: R759.2 20.83,103.76 v1(21.08,103.51) 21.38,103.21 U89.1
  BOTTOM w0.254: v1(21.08,103.51) 20.71,103.13 R761.2
N19646995: length 2.2
  TOP w0.254: U89.6 20.72,100.35 v1(20.57,100.2)
  BOTTOM w0.254: C971.1 20.95,99.83 v1(20.57,100.2)
N19647070: length 1.7
  TOP w0.254: R747.2 22.73,104.03 U89.15
N19647102: length 1.7
  TOP w0.254: C949.1 23.23,104.98 U89.14
N19648273: length 22.2
  TOP w0.508: R767.2 v1(18.03,91.95) 18.03,91.94 R775.1 ; C978.2 23.91,95.8 v1(24.13,96.01)
  L3SIG w0.508: v1(18.03,91.95) 23.49,91.95 24.64,90.81 v1(27.18,90.81)
  BOTTOM w0.508: v1(24.13,96.01) 27.56,96.01 28.58,95 28.58,91.44 27.94,90.81 v1(27.18,90.81)
N19648275: length 2.3
  TOP w0.254: R775.2 17.27,90.42 C989.2 17.79,89.92 C991.2
N19648310: length 3.7
  TOP w0.254: R772.1 C991.1 20.06,90.17 v1(20.57,90.17) 20.69,90.05 U90.5
  BOTTOM w0.254: v1(20.57,90.17) 20.71,90.3 R781.2
N19648328: length 1.7
  TOP w0.254: U90.2 20.72,91.55 20.32,91.95 R767.1
N19648366: length 3.3
  TOP w0.127: C981.2 R770.2 20.95,93.73 21.34,93.34 21.84,93.34 22.23,92.96 U90.16
N19648414: length 10.5
  TOP w0.254: v1(21.97,87.76) 22.23,88.01 U90.8 ; R777.1 v1(18.03,92.96)
  BOTTOM w0.508: C994.1 22.23,88.02 v1(21.97,87.76) 20.83,87.76 19.69,88.9 19.69,92.08 18.8,92.96 v1(18.03,92.96)
N19648420: length 3
  TOP w0.254: U90.1 21.38,92.42 v1(21.08,92.71) 20.83,92.96 R777.2
  BOTTOM w0.254: R779.2 20.71,92.34 v1(21.08,92.71)
N19648465: length 2.2
  TOP w0.254: v1(20.57,89.41) 20.72,89.55 U90.6
  BOTTOM w0.254: C995.1 20.95,89.03 v1(20.57,89.41)
N19648544: length 1.7
  TOP w0.254: R765.2 22.73,93.23 U90.15
N19648572: length 1.7
  TOP w0.254: C978.1 23.23,94.18 U90.14
N19650144: length 22.1
  TOP w0.508: R766.2 v1(55.5,81.79) 55.49,81.78 R769.1 ; v1(61.59,85.85) 61.38,85.64 C972.2
  L6SIG w0.508: v1(55.5,81.79) 55.63,81.92 60.96,81.92 62.23,80.65 v1(64.64,80.65)
  BOTTOM w0.508: v1(61.59,85.85) 64.64,85.85 66.04,84.45 66.04,81.28 65.41,80.65 v1(64.64,80.65)
N19650163: length 2.3
  TOP w0.254: R769.2 54.74,80.26 C988.2 55.25,79.76 C990.2
N19650181: length 3.7
  TOP w0.254: R774.1 C990.1 57.52,80.01 v1(58.04,80.01) 58.16,79.89 U91.5
  BOTTOM w0.254: v1(58.04,80.01) 58.17,80.14 R780.2
N19650199: length 1.7
  TOP w0.254: U91.2 58.18,81.39 57.78,81.79 R766.1
N19650212: length 1.6
  TOP w0.127: R773.2 57.39,80.89 U91.3
N19650233: length 3.3
  TOP w0.127: U91.16 59.69,82.8 59.31,83.19 58.8,83.19 58.42,83.57 R768.2 C977.2
N19650272: length 10.5
  TOP w0.254: v1(59.44,77.6) 59.69,77.85 U91.8 ; R776.1 v1(55.5,82.8)
  BOTTOM w0.508: C992.1 59.7,77.86 v1(59.44,77.6) 58.29,77.6 57.02,78.87 57.02,82.04 56.26,82.8 v1(55.5,82.8)
N19650282: length 3
  TOP w0.254: U91.1 58.84,82.26 v1(58.55,82.55) 58.29,82.8 R776.2
  BOTTOM w0.254: R778.2 58.17,82.18 v1(58.55,82.55)
N19650331: length 2.2
  TOP w0.254: U91.6 58.18,79.39 v1(58.04,79.25)
  BOTTOM w0.254: v1(58.04,79.25) 58.41,78.87 C993.1
N19650402: length 1.7
  TOP w0.254: U91.15 60.19,83.07 R764.2
N19650430: length 1.7
  TOP w0.254: C972.1 60.69,84.02 U91.14
N19651609: length 22
  TOP w0.508: v1(24.13,117.6) 23.91,117.39 C948.2 ; R751.1 18.03,113.53 v1(18.03,113.54) R748.2
  L3SIG w0.508: v1(18.03,113.54) 23.49,113.54 24.64,112.4 v1(27.18,112.4)
  BOTTOM w0.508: v1(27.18,112.4) 27.94,112.4 28.58,113.03 28.58,116.2 27.18,117.6 v1(24.13,117.6)
N19651628: length 2.3
  TOP w0.254: C966.2 17.79,111.51 C964.2 17.27,112.01 R751.2
N19651646: length 3.7
  TOP w0.254: R753.1 C966.1 20.06,111.76 v1(20.57,111.76) 20.69,111.64 U88.5
  BOTTOM w0.254: R762.2 20.71,111.89 v1(20.57,111.76)
N19651664: length 1.7
  TOP w0.254: R748.1 20.32,113.54 20.72,113.14 U88.2
N19651683: length 1.6
  TOP w0.127: R752.2 19.92,112.64 U88.3
N19651731: length 10.5
  TOP w0.254: R758.1 v1(18.03,114.55) ; U88.8 22.23,109.6 v1(21.97,109.35)
  BOTTOM w0.508: C968.1 22.23,109.61 v1(21.97,109.35) 20.83,109.35 19.56,110.62 19.56,113.79 18.8,114.55 v1(18.03,114.55)
N19651747: length 3
  TOP w0.254: R758.2 20.83,114.55 v1(21.08,114.3) 21.38,114.01 U88.1
  BOTTOM w0.254: R760.2 20.71,113.93 v1(21.08,114.3)
N19651788: length 2.2
  TOP w0.254: U88.6 20.72,111.14 v1(20.57,111)
  BOTTOM w0.254: C969.1 20.95,110.62 v1(20.57,111)
N19651863: length 1.7
  TOP w0.254: R746.2 22.73,114.82 U88.15
N19651895: length 1.7
  TOP w0.254: U88.14 23.23,115.77 C948.1
N19653096: length 22
  TOP w0.508: R733.1 203.08,78.37 v1(203.07,78.36) R729.2 ; C924.2 197.19,74.51 v1(196.98,74.3)
  L3SIG w0.508: v1(193.93,79.5) 196.47,79.5 197.61,78.36 v1(203.07,78.36)
  BOTTOM w0.508: v1(196.98,74.3) 193.93,74.3 192.53,75.69 192.53,78.87 193.17,79.5 v1(193.93,79.5)
N19653107: length 2.3
  TOP w0.254: R733.2 203.83,79.89 C935.2 203.32,80.39 C942.2
N19653133: length 3.7
  TOP w0.254: U86.5 200.41,80.26 v1(200.53,80.14) 201.05,80.14 C942.1 R738.1
  BOTTOM w0.254: v1(200.53,80.14) 200.4,80 R744.2
N19653151: length 1.7
  TOP w0.254: U86.2 200.39,78.76 200.79,78.36 R729.1
N19653170: length 1.6
  TOP w0.127: U86.3 201.18,79.26 R737.2
N19653218: length 10.5
  TOP w0.254: R740.1 v1(203.07,77.34) ; U86.8 198.88,82.29 v1(199.14,82.55)
  BOTTOM w0.508: C944.1 198.87,82.29 v1(199.14,82.55) 200.28,82.55 201.55,81.28 201.55,78.11 202.31,77.34 v1(203.07,77.34)
N19653234: length 3
  TOP w0.254: R740.2 200.28,77.34 v1(200.02,77.6) 199.73,77.89 U86.1
  BOTTOM w0.254: v1(200.02,77.6) 200.4,77.97 R742.2
N19653275: length 2.2
  TOP w0.254: v1(200.53,80.9) 200.39,80.76 U86.6
  BOTTOM w0.254: v1(200.53,80.9) 200.16,81.27 C945.1
N19653350: length 1.7
  TOP w0.254: R730.2 198.38,77.07 U86.15
N19653382: length 1.7
  TOP w0.254: U86.14 197.88,76.13 C924.1
N19673378: length 1.7
  BOTTOM w0.254: R726.1 103.12,87.24 102.46,86.59 U70.24
N19673381: length 1.5
  BOTTOM w0.254: R726.2 101.96,87.35 U70.23
N19675149: length 4.2
  TOP w0.127: U55.D18 209.22,71.45 208.03,72.64 R724.2
N19675151: length 4.1
  TOP w0.127: U55.D17 209.87,71.81 209.03,72.65 R724.1
N19825990: length 2.2
  TOP w0.254: J39.1 222.62,141.61 R787.1
N20075552: length 1.6
  BOTTOM w0.254: R552.1 111.01,79.11 U92.2
N20075564: length 1.6
  BOTTOM w0.254: U92.4 111.01,78.11 R554.1
N20366563: length 2.8
  TOP w0.254: U95.6 204.14,126.31 R806.1 R807.2
N20473911: length 1.4
  TOP w0.127: U1.C15 v2(156.52,114.85)
  BOTTOM w0.127: R811.1 156.42,114.94 v2(156.52,114.85)
N20516568: length 0.6
  TOP w0.127: U1.E6 v2(158.12,106.85)
N20517420: length 0.6
  TOP w0.127: U1.AD7 v2(174.12,107.65)
N20517422: length 0.6
  TOP w0.127: U1.AF5 v2(175.72,106.05)
N20517434: length 2.2
  TOP w0.127: U1.AC7 v2(173.32,107.65)
  BOTTOM w0.127: v2(173.32,107.65) 172.91,107.24 TP5.1
N20517436: length 0.6
  TOP w0.127: U1.AE6 v2(174.92,106.85)
N20517448: length 2.5
  TOP w0.127: U1.AD8 v2(174.12,108.45)
  BOTTOM w0.127: TP10.1 172.92,108.04 173.52,108.04 173.93,108.45 v2(174.12,108.45)
N20553507: length 7.4
  BOTTOM w0.127: Q37.1 152.46,131.26 152.78,130.94 152.78,128.52 151.83,127.57 Q38.1 151.69,127.51 R830.2 150.37,127.52 R831.2
N20559490: length 3.2
  TOP w0.127: R820.2 R821.2 41.98,134.18 Q35.1
N20559492: length 9.1
  TOP w0.127: R818.2 C1023.2 45.35,133.86 R816.2 ; Q35.3 43.81,136.79 44.7,135.89 44.7,134.11 44.95,133.87 R816.2 ; Q36.1 46.93,134.94 45.85,133.87 R816.2
N20559589: length 13
  TOP w0.127: 43.5,139.57 43.5,137.98 45.34,136.14 R816.1 ; 43.5,139.57 41.4,139.57 40.58,138.75 Q44.1 ; 43.5,139.57 43.5,141.42 44.77,142.69 Q33.1
N20559634: length 3.4
  TOP w0.508: Q44.3 42.92,142.24 Q33.3
N20559669: length 5.9
  TOP w0.127: R819.1 48.38,132.83 C1024.1 R817.1 47.88,134.37 Q36.3
N20559724: length 15.1
  TOP w0.127: Q34.1 49.28,139.95 ; 49.28,139.95 49.28,137.79 49.66,137.41 49.66,134.12 R817.2 ; 49.28,139.95 44.96,139.95 44.26,139.26 Q45.1
N20562248: length 0.6
  TOP w0.127: U1.Y15 v2(170.92,114.85)
N20562257: length 0.6
  TOP w0.127: U1.AB15 v2(172.52,114.85)
N20562271: length 0.6
  TOP w0.127: U1.Y19 v2(170.92,118.05)
N20562273: length 0.6
  TOP w0.127: U1.AB19 v2(172.52,118.05)
N20562350: length 1
  BOTTOM w0.127: C1022.2 153.8,100.33 R814.2
N20977401: length 8.1
  TOP w0.127: Y5.1 153.76,59.6 152.91,60.45 152.91,62.36 153.42,62.86 C739.1 153.54,62.98 153.54,65.02 154.08,65.56 U68.13
N20977407: length 5
  TOP w0.127: U68.12 156.2,64.91 156.58,64.52 C738.1 156.58,61.72 Y5.3
N20978279: length 9.1
  TOP w0.127: U67.13 232.82,70.76 230.64,68.59 C740.1 230.64,67.57 230.12,67.06 230.12,65.53 230.97,64.68 Y6.1
N20978303: length 5.2
  TOP w0.127: U67.12 233.06,70.11 232.8,69.86 C741.1 232.8,66.97 Y6.3
N20978493: length 2.8
  TOP w0.127: U67.9 227.34,70.11 227.08,69.85 227.08,69.22 226.81,68.95 R540.2
N20980151: length 4
  TOP w0.127: R842.2 R829.2 232.92,132.97 234.35,134.41 U97.1
N20982998: length 2.5
  TOP w0.127: R834.2 238.13,132.58 236.8,133.91 U97.6
N21105612: length 1.9
  TOP w0.102: U97.22 238,139.95 237.95,140 237.95,140.67 R525.1
N21105614: length 2
  TOP w0.102: R526.1 237.67,140.55 237.67,140 237.6,139.94 U97.23
N21105620: length 1.9
  TOP w0.102: U97.28 235.6,139.94 235.53,140.01 235.53,140.67 R530.1
N21105622: length 1.9
  TOP w0.102: R532.1 235.25,140.55 235.25,140 235.2,139.95 U97.29
N21105628: length 2.1
  TOP w0.102: U97.33 233.19,137.91 232.4,138.69 R536.1
N21105630: length 1.9
  TOP w0.102: R537.1 232.66,137.79 232.88,137.79 233.17,137.51 U97.34
N21105856: length 2.3
  TOP w0.102: U97.37 233.46,136.31 232.4,135.25 R837.1
N21105862: length 2
  TOP w0.102: U97.36 233.47,136.71 232.92,136.16 232.64,136.16 R836.1
N21754633: length 11.9
  TOP w0.127: J43.28 267.44,149.84 266.95,149.35 266.95,145.29 270.51,141.73 R867.1
N21754692: length 11.3
  TOP w0.127: J43.36 271.8,147.3 277.11,141.99 R868.1
N21754708: length 9.5
  TOP w0.127: v1(271.02,146.43) 270.79,146.66 J43.38
  BOTTOM w0.127: v1(271.02,146.43) 271.15,146.3 271.15,142.37 271.53,141.99 R869.1
N21824193: length 1.7
  TOP w0.127: Q41.1 272.41,137.55 271.91,138.04 R860.2
N21824406: length 4.1
  TOP w0.127: U101.2 275.21,139.32 274.7,138.81 274.7,138.31 R859.2 Q41.3
N22254280: length 1.9
  TOP w0.102: R520.1 240.32,136.37 239.75,136.37 239.69,136.31 U97.14
N22254282: length 1.9
  TOP w0.102: R521.1 240.29,136.65 239.75,136.65 239.69,136.71 U97.15
N22255501: length 2.3
  TOP w0.127: U97.21 238.72,139.41 239.52,140.21 R533.2
N22257590: length 2.2
  BOTTOM w0.127: R14.1 124.16,121.5 U2.2
N22257592: length 2
  BOTTOM w0.127: R15.1 123.64,122 U2.3
N22257594: length 2
  BOTTOM w0.127: R16.1 123.62,123 U2.5
N22258098: length 2.1
  BOTTOM w0.127: R20.1 123.85,124.5 U2.8
N22258100: length 4.1
  BOTTOM w0.127: R22.1 124.08,124.84 124.23,125 U2.9
N22258102: length 2.2
  BOTTOM w0.127: R24.1 124.08,126 U2.11
N22258104: length 4.2
  BOTTOM w0.127: U2.12 124.22,126.5 123.84,126.11 R26.1
N22258216: length 4.1
  BOTTOM w0.127: R18.1 124.08,123.57 124.15,123.5 U2.6
N22258634: length 2.1
  BOTTOM w0.127: R28.1 123.81,127 U2.13
N22258636: length 2.1
  BOTTOM w0.127: U2.14 123.83,127.5 R30.1
N22258638: length 2.1
  BOTTOM w0.127: U2.16 123.85,128.5 R32.1
N22360230: length 4.5
  TOP w1.016: F9.2 36.17,245.26 J33.2
N22360382: length 4.5
  TOP w1.016: J44.2 175.87,245.26 F11.2
N22360534: length 4.5
  TOP w1.016: J45.2 106.02,245.26 R862.2
N22361017: length 4.5
  TOP w1.016: J46.2 245.72,245.26 F13.2
N22361656: length 3.6
  TOP w0.127: D43.1 29.08,10.03 R702.2
N22361689: length 3.6
  TOP w0.127: R699.2 24.76,6.4 D44.1
N22440478: length 3.8
  TOP w0.508: Q34.3 46.98,142.11 45.73,140.85 Q45.3
N22476599: length 2.8
  BOTTOM w0.127: R50.2 R49.2 90.32,126.71 U7.4

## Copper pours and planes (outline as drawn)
1V0 on TOP (solid shape): 188.09,83.82 188.09,75.95 187.71,75.57 184.28,75.57 184.02,75.82 184.02,83.69 184.4,84.07 187.83,84.07
1V0 on BOTTOM (solid shape): 187.71,83.82 187.71,74.42 187.45,74.17 183.77,74.17 183.26,74.68 183.26,82.04 185.29,84.07 187.45,84.07
1V0 on BOTTOM: 161.67,66.29 161.67,63.12 161.8,62.99 163.07,62.99 163.32,63.25 163.32,66.17 163.07,66.42 161.8,66.42
1V0 on BOTTOM: 177.67,65.91 178.82,65.91 179.07,65.66 179.07,61.59 178.82,61.34 177.67,61.34 177.42,61.59 177.42,62.36 177.16,62.61 177.16,64.64 177.42,64.9 177.42,65.66
1V0 on L4PWR: 163.17,59.69 161.29,61.57 161.29,72.41 165.71,76.84 181.46,76.84 182.12,77.49 182.12,86.11 182.37,86.36 200.68,86.36 208.56,78.49 227.86,78.49 234.84,71.5 243.95,71.5 247.76,75.31 254.15,75.31 254.76,74.7 254.76,65.13 253.64,64.01 232.64,64.01 227.69,68.96 222.53,68.96 217.45,63.88 206.23,63.88 198.73,71.37 180.74,71.37 178.94,69.57 178.94,61.83 176.81,59.69
1V0_FA_VL on L3SIG: 159.89,116.97 160.02,116.84 160.02,116.2 159.77,115.95 158.37,115.95 158.24,116.08 158.24,116.84 158.37,116.97
1V0_LP on L6SIG: 155.81,118.65 161.21,118.65 161.61,118.25 166.12,118.25 166.32,118.45 166.32,119.35 166.12,119.55 156.11,119.55 155.81,119.25
1V0_USB_SVDD on L5PWR: 161.8,110.11 161.8,108.97 161.92,108.84 162.31,108.84 162.43,108.71 162.43,107.82 160.66,106.05 160.66,101.98 160.91,101.73 162.56,101.73 162.81,101.98 162.81,106.05 164.21,107.44 164.21,109.6 163.45,110.36 162.05,110.36
1V0_XG_RX on BOTTOM: 176.91,62.36 177.04,62.23 177.04,59.44 176.91,59.31 175.77,59.31 175.26,59.82 175.26,62.1 175.51,62.36
1V0_XG_RX on L3SIG: 176.28,59.56 176.53,59.82 176.53,68.83 176.15,69.22 167.51,69.22 167.26,68.96 167.26,59.94 167.64,59.56
1V0_XG_TX on BOTTOM: 176.91,67.95 177.04,67.82 177.04,65.02 176.91,64.9 175.26,64.9 175.13,65.02 175.13,67.82 175.26,67.95
1V0_XG_TX on L6SIG: 170.31,67.69 175.77,67.69 176.02,67.44 176.02,63.12 175.64,62.74 171.83,62.74 171.2,62.1 171.2,61.34 171.07,61.21 169.93,61.21 169.67,61.47 169.67,67.06
1V0A_QSG1 on BOTTOM: 216.15,71.5 218.69,71.5 218.95,71.76 218.95,73.15 218.82,73.28 216.15,73.28 215.9,73.03 215.9,71.76
1V0A_QSG1 on L3SIG: 208.15,62.61 208.41,62.61 208.53,62.74 209.3,62.74 209.55,62.48 214.25,62.48 214.5,62.74 214.5,62.99 214.88,63.37 215.26,63.37 215.52,63.12 215.52,62.48 216.03,61.98 217.3,61.98 218.31,62.99 218.31,72.01 217.8,72.52 209.55,72.52 207.9,70.87 207.9,62.86
1V0A_QSG2 on BOTTOM: 250.44,71.5 252.98,71.5 253.24,71.76 253.24,73.15 253.11,73.28 250.44,73.28 250.19,73.03 250.19,71.76
1V0A_QSG2 on L3SIG: 242.44,62.61 242.7,62.61 242.82,62.74 243.59,62.74 243.84,62.48 248.54,62.48 248.79,62.74 248.79,62.99 249.17,63.37 249.55,63.37 249.81,63.12 249.81,62.48 250.32,61.98 251.97,61.98 252.6,62.61 252.6,72.01 252.09,72.52 244.09,72.52 242.19,70.61 242.19,62.86
1V0S on TOP: 197.87,124.08 197.61,124.33 197.61,126.24 197.87,126.49 199.64,126.49 199.9,126.24 202.18,126.24 202.69,126.75 203.07,126.75 203.2,126.62 203.2,126.11 203.45,125.86 204.85,125.86 204.85,125.09 206.5,125.09 206.5,125.86 206.76,125.86 206.76,124.59 206.25,124.08
1V5 on TOP (solid shape): 37.97,116.84 37.97,108.84 37.59,108.46 33.4,108.46 33.02,108.84 33.02,116.84 33.4,117.22 37.59,117.22
1V5 on BOTTOM (solid shape): 36.32,117.48 36.32,108.08 36.07,107.82 33.66,107.82 33.4,108.08 33.4,117.48 33.66,117.73 36.07,117.73
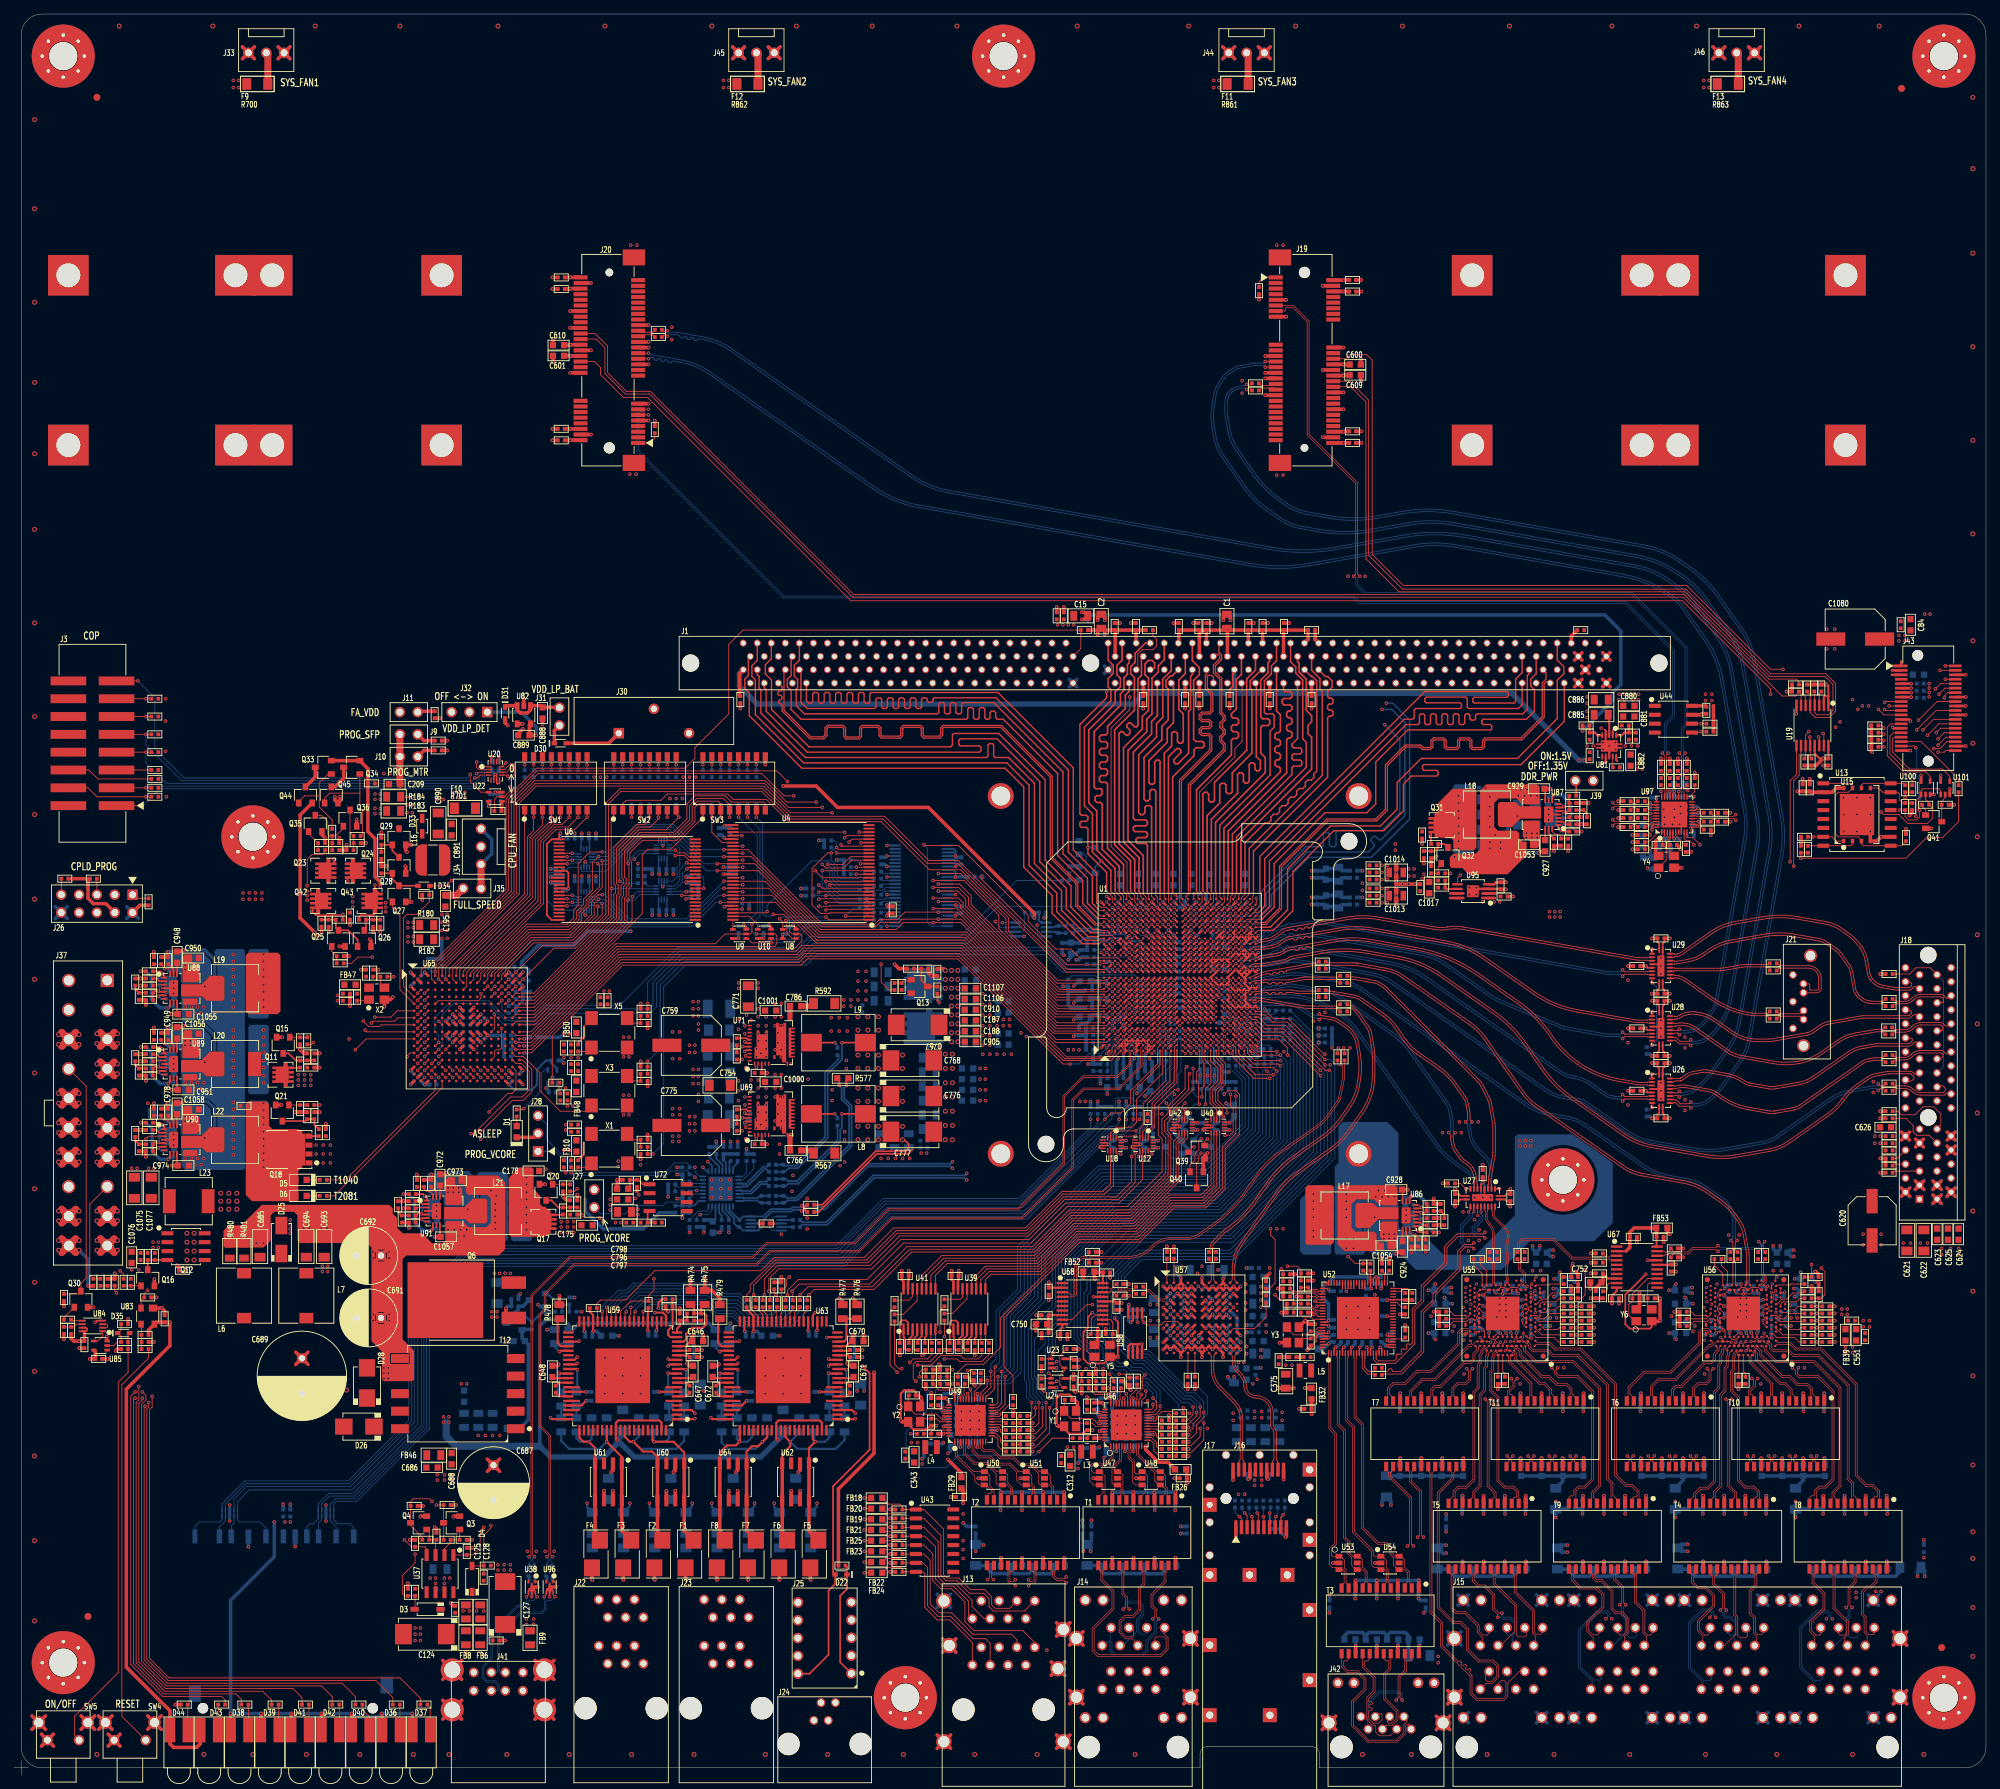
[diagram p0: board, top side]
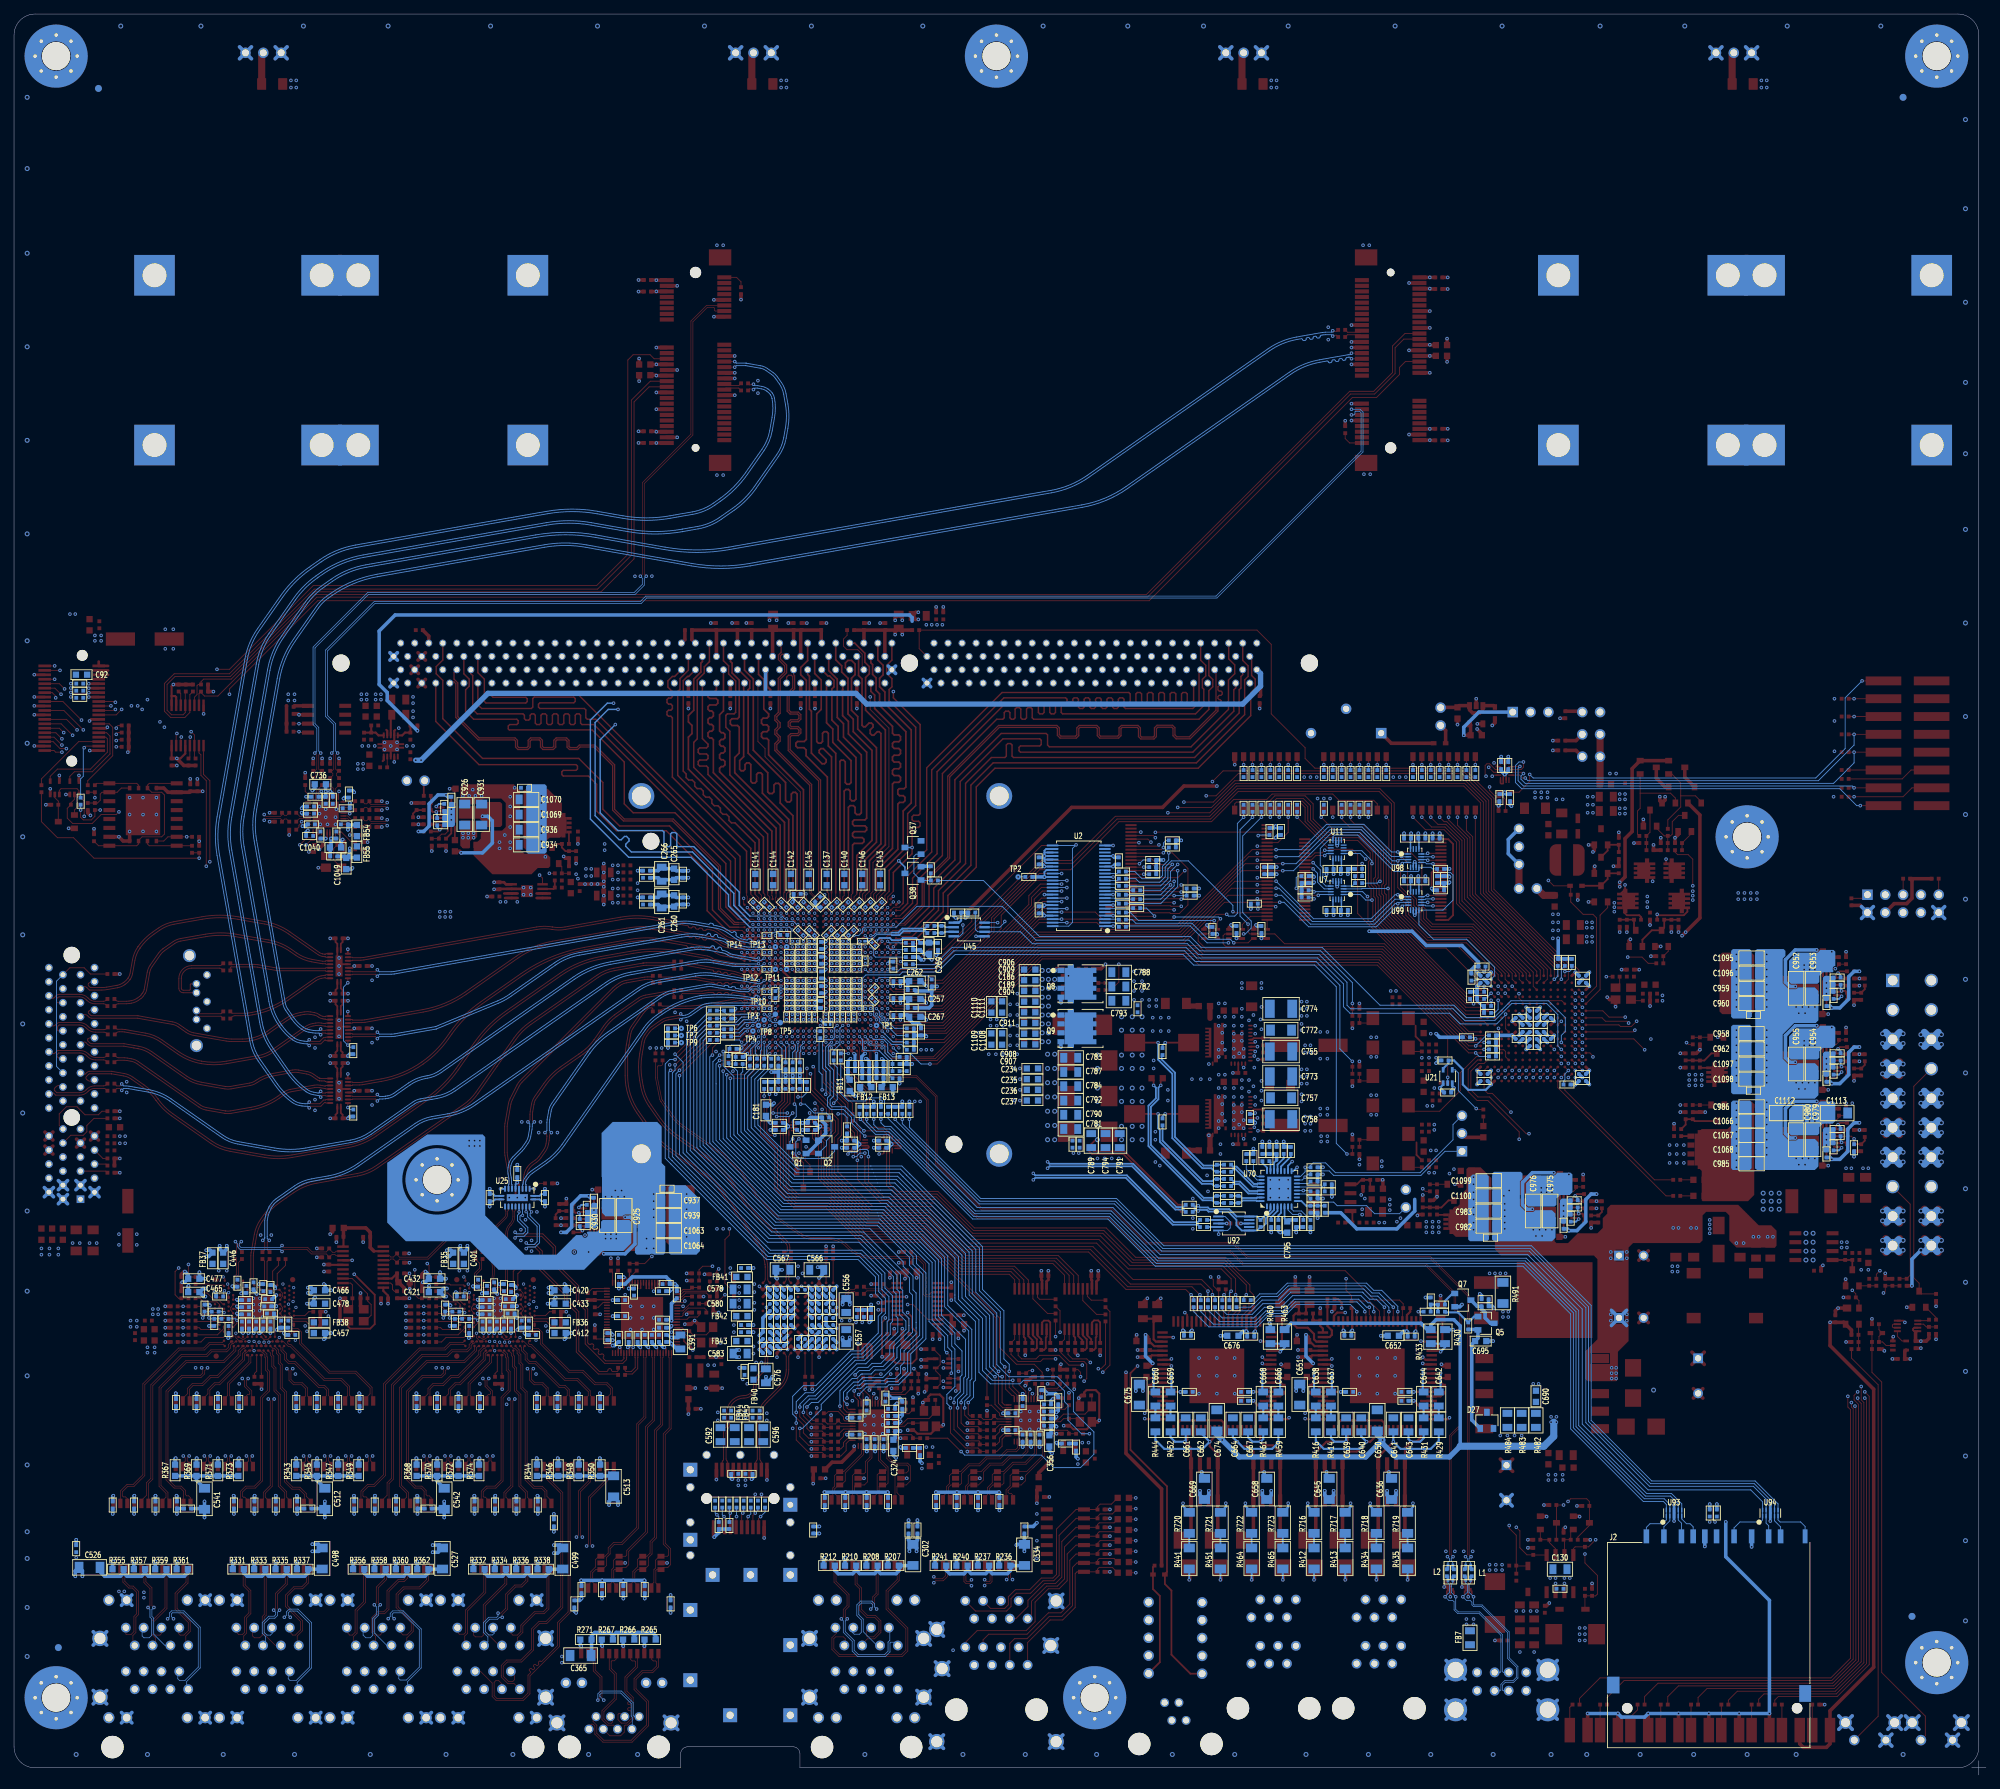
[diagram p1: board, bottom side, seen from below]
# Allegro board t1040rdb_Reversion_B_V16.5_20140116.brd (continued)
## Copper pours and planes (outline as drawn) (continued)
1V5 on L5PWR: 191.52,220.73 32.26,220.73 19.43,207.9 19.43,111.12 21.59,108.97 36.2,108.97 36.83,109.6 36.83,156.46 67.18,186.82 191.9,186.82 193.55,188.47 193.55,218.69
1V05_EC1_AVDD on TOP: 126.87,47.75 130.05,47.75 130.17,47.62 130.17,45.85 130.05,45.72 127.64,45.72 127.51,45.85 126.75,45.85 126.62,45.97 126.62,47.5
1V05_EC1_AVDD on L3SIG: 127.76,48.13 131.06,48.13 131.7,48.77 131.7,51.94 131.95,52.2 137.29,52.2 137.79,51.69 137.79,46.23 137.54,45.97 127.76,45.97 127.51,46.23 127.51,47.88
1V05_EC2_AVDD on TOP: 149.1,47.12 152.27,47.12 152.4,46.99 152.4,45.21 152.27,45.09 149.86,45.09 149.73,45.21 148.97,45.21 148.84,45.34 148.84,46.86
1V05_EC2_AVDD on L3SIG: 149.99,47.5 153.29,47.5 153.92,48.13 153.92,51.31 154.18,51.56 159.51,51.56 160.02,51.05 160.02,45.59 159.77,45.34 149.99,45.34 149.73,45.59 149.73,47.24
1V05_SG_AVDD on TOP: 179.83,56.64 180.34,56.13 183.39,56.13 183.64,56.39 183.64,58.55 183.39,58.8 179.96,58.8 179.83,58.67
1V05_SG_AVDD on L6SIG: 183.01,65.53 188.72,65.53 189.61,64.64 194.82,64.64 196.34,63.12 196.34,60.45 195.33,59.44 185.17,59.44 183.51,57.78 180.97,57.78 180.72,58.04 180.72,63.25
1V8 on TOP: 39.12,100.33 39.12,98.04 39.5,97.66 42.93,97.66 43.31,98.04 43.31,100.08 43.05,100.33 42.16,100.33 42.04,100.46 42.04,100.97 41.91,101.09 41.66,101.09 41.53,100.97 41.53,100.46 41.4,100.33
1V8 on TOP: 58.42,118.36 58.42,119.89 58.29,120.02 56.01,120.02 55.88,119.89 55.88,118.36 56.01,118.24 58.29,118.24
1V8 on BOTTOM: 178.94,70.48 179.2,70.74 179.2,72.39 178.94,72.64 177.29,72.64 177.16,72.52 177.16,71.88 177.55,71.5 177.55,70.61 177.67,70.48
1V8 on BOTTOM: 167,72.64 167,71.37 167.13,71.25 170.81,71.25 170.94,71.37 170.94,72.64 170.81,72.77 167.13,72.77
1V8 on BOTTOM: 176.53,57.28 177.42,57.28 177.55,57.15 177.55,56.13 176.91,55.5 175.26,55.5 175.13,55.63 175.13,56.77 175.26,56.9 176.15,56.9
1V8 on L5PWR: 156.97,56.01 156.97,69.22 175.77,88.01 175.77,117.86 195.71,137.79 214.76,137.79 228.35,151.38 228.35,162.69 226.57,164.47 104.14,164.47 102.23,162.56 102.23,149.73 99.82,147.32 67.44,147.32 66.42,146.3 66.42,137.79 59.44,130.81 59.44,126.49 58.17,125.22 52.7,125.22 52.2,124.71 52.2,122.94 54.74,120.4 57.15,120.4 57.4,120.14 57.4,118.24 60.96,114.68 72.14,114.68 73.91,112.9 73.91,98.68 71.25,96.01 40.39,96.01 39.62,96.77 39.62,100.97 40.13,101.47 52.83,101.47 55.63,104.27 66.17,104.27 67.44,105.54 67.44,109.47 66.55,110.36 54.99,110.36 46.86,118.49 46.86,132.21 53.34,138.68 53.34,154.81 73.28,174.75 228.98,174.75 239.27,164.47 239.27,144.91 222,127.64 208.15,127.64 207.52,127 207.52,79.63 207.14,79.25 179.96,79.25 179.07,78.36 179.07,75.69 179.83,74.93 179.83,56.64 178.56,55.37 157.61,55.37
1V8 on L6SIG: 55.88,118.36 57.15,118.36 57.28,118.49 57.28,119.76 57.15,119.89 55.88,119.89 55.75,119.76 55.75,118.49
1V8_0641_VDD on L3SIG: 236.22,131.7 238.25,133.73 240.28,133.73 240.66,134.11 240.66,137.29 240.41,137.54 240.03,137.54 239.78,137.79 239.78,139.57 239.52,139.83 232.92,139.83 232.41,139.32 232.41,131.95 232.66,131.7
1V8_0641_VDDIO on L6SIG: 236.6,140.46 237.74,139.32 239.78,139.32 240.28,138.81 240.28,133.73 239.52,132.97 235.2,132.97 234.19,133.98 233.43,133.98 232.92,134.49 232.92,138.94 233.81,139.83 234.7,139.83 235.33,140.46
1V8_MTR on L3SIG: 158.62,111.12 159.13,111.12 159.26,111 159.26,110.36 159,110.11 155.19,110.11 155.07,110.24 155.07,111.25 155.19,111.38 158.37,111.38
1V8_SFP on L3SIG: 158.37,113.16 159.26,112.27 159.26,111.51 159.13,111.38 158.75,111.38 158.5,111.63 155.19,111.63 155.07,111.76 155.07,113.03 155.19,113.16
1V8_SLP on BOTTOM (solid shape): 36.32,106.68 36.32,97.28 36.07,97.03 33.66,97.03 33.4,97.28 33.4,106.68 33.66,106.93 36.07,106.93
1V8_SLP on TOP: 53.59,138.68 53.72,138.81 53.72,140.21 53.59,140.33 51.18,140.33 51.05,140.21 51.05,138.81 51.18,138.68
1V8_SLP on TOP: 33.4,97.66 33.02,98.04 33.02,106.05 33.4,106.43 36.2,106.43 36.58,106.05 36.58,104.46 37.53,103.51 37.53,102.3 37.85,101.98 38.23,101.98 38.48,101.73 38.48,98.04 38.1,97.66
1V8_SLP on TOP: 212.09,125.48 211.96,125.6 211.45,125.6 211.2,125.86 210.95,125.86 210.95,125.09 209.3,125.09 209.3,125.86 209.04,125.86 209.04,124.21 209.17,124.08 211.84,124.08 212.09,124.33
1V8_SLP on BOTTOM: 230.25,134.11 230.25,132.72 230.5,132.46 230.76,132.46 231.39,131.83 232.54,131.83 232.66,131.95 232.66,134.24 232.54,134.37 230.5,134.37
1V8_SLP on L5PWR: 33.66,98.04 33.66,107.57 34.42,108.33 36.45,108.33 37.46,109.35 37.46,156.46 67.31,186.31 240.54,186.31 251.59,175.26 251.59,135.38 240.03,123.83 208.28,123.83 208.03,124.08 208.03,126.62 208.41,127 222.25,127 239.9,144.65 239.9,165.1 229.49,175.51 73.03,175.51 52.7,155.19 52.7,139.06 46.23,132.59 46.23,118.24 54.61,109.86 66.29,109.86 66.93,109.22 66.93,105.79 65.91,104.78 55.37,104.78 52.58,101.98 39.75,101.98 38.99,101.22 38.99,98.3 38.1,97.41 34.29,97.41
1V8_USB_OVDD on L5PWR: 161.04,108.84 161.54,108.84 161.67,108.97 161.67,110.24 161.54,110.36 160.66,110.36 156.72,106.43 156.72,101.98 156.97,101.73 158.62,101.73 158.88,101.98 158.88,106.68
1V8_XG_AV on BOTTOM: 172.97,59.05 175.51,59.05 175.64,58.93 175.89,58.93 176.15,58.67 176.15,57.53 176.02,57.4 172.97,57.4 172.85,57.53 172.85,58.93
1V8_XG_AV on L6SIG: 175.77,58.29 176.15,58.67 176.15,61.98 175.77,62.36 171.96,62.36 171.45,61.85 171.45,58.55 171.7,58.29
1V8_XG_RX on BOTTOM: 177.04,68.58 177.04,71.37 176.78,71.63 175.39,71.63 175.13,71.37 175.13,68.58 175.39,68.33 176.78,68.33
1V8_XG_RX on L6SIG: 171.2,70.61 175.64,70.61 176.02,70.23 176.02,68.33 175.77,68.07 171.32,68.07 171.07,68.33 171.07,70.48
1V35 on TOP: 199.9,127.89 199.9,133.86 200.41,134.37 200.79,134.37 201.29,134.87 202.31,134.87 202.44,135 202.44,136.52 202.31,136.65 199.26,136.65 197.61,135 197.61,127.89 197.87,127.64 199.64,127.64
1V35 on BOTTOM: 199.9,129.41 199.52,129.79 192.79,129.79 192.53,129.54 192.53,128.52 192.15,128.14 191.26,128.14 191.13,128.02 191.13,123.57 191.39,123.32 197.99,123.32 199.9,125.22
1V35_SLP on TOP (solid shape): 208.41,140.21 208.41,132.21 208.03,131.83 205.49,131.83 205.1,132.21 205.1,133.22 204.72,133.6 203.2,133.6 202.95,133.86 202.95,138.56 204.98,140.59 208.03,140.59
1V35_SLP on BOTTOM (solid shape): 208.03,140.97 208.03,131.57 207.77,131.32 205.36,131.32 205.1,131.57 205.1,140.97 205.36,141.22 207.77,141.22
1V35_SLP on TOP: 228.35,149.61 227.71,148.97 227.71,148.72 227.97,148.72 228.09,148.84 228.98,148.84 229.36,149.22 229.36,149.99 229.87,150.5 229.87,154.18 229.74,154.3 228.47,154.3 228.35,154.18
1V35_SLP on BOTTOM: 176.02,127.38 176.4,127 176.4,124.46 176.02,124.08 175.64,124.08 175.26,124.46 174.88,124.46 174.5,124.08 174.12,124.08 173.74,124.46 173.35,124.46 172.97,124.08 171.7,124.08 171.32,124.46 170.94,124.46 170.56,124.08 170.05,124.08 169.67,124.46 169.29,124.46 168.91,124.08 168.53,124.08 168.15,124.46 167.77,124.46 166.5,125.73 165.73,125.73 165.61,125.6 165.61,125.09 165.86,124.84 165.86,124.59 165.35,124.08 164.97,124.08 164.59,124.46 164.08,124.46 163.7,124.08 163.32,124.08 162.94,124.46 162.56,124.46 162.18,124.08 161.67,124.08 161.29,124.46 160.91,124.46 160.53,124.08 160.15,124.08 159.77,124.46 159.38,124.46 159,124.08 158.5,124.08 158.11,124.46 157.73,124.46 157.35,124.08 156.72,124.08 156.46,124.33 156.46,127.13 156.72,127.38 ; 1 cut-out
1V35_SLP on L4PWR: 161.8,119.38 161.8,119.49 161.4,119.89 150.98,119.89 136.38,134.49 125.33,134.49 104.78,155.05 104.78,157.97 102.87,159.87 102.87,162.07 104.25,163.45 227.61,163.45 230.12,160.93 230.12,149.46 225.04,144.38 225.04,138.15 217.57,130.68 187.73,130.68 177.44,120.4 170.2,120.4 169.19,119.38
1V35_SLP on L5PWR: 169.16,119.38 169.67,119.89 172.21,119.89 172.47,120.14 177.16,120.14 195.33,138.3 214.63,138.3 227.84,151.51 227.84,162.43 226.82,163.45 104.39,163.45 103,162.05 103,156.84 125.35,134.49 136.4,134.49 151.51,119.38
2V5 on TOP: 76.58,79.25 76.58,77.09 76.96,76.71 81.03,76.71 81.28,76.96 81.28,79.12 81.03,79.38 79.63,79.38 79.5,79.5 79.5,80.01 79.38,80.14 79.12,80.14 78.99,80.01 78.99,79.5 78.87,79.38 76.71,79.38
2V5 on TOP: 53.21,124.97 53.21,123.06 52.96,122.81 52.07,122.81 51.82,123.06 51.82,125.09 51.94,125.22 52.96,125.22
2V5 on TOP: 260.1,63.37 260.35,63.12 261.49,63.12 261.62,63.25 261.62,66.55 261.49,66.68 260.22,66.68 260.1,66.55
2V5 on BOTTOM: 235.84,67.44 235.84,64.14 235.97,64.01 237.11,64.01 237.24,64.14 237.24,67.56 237.11,67.69 236.09,67.69
2V5 on BOTTOM: 201.55,67.44 201.55,64.14 201.68,64.01 202.82,64.01 202.95,64.14 202.95,67.56 202.82,67.69 201.8,67.69
2V5 on L4PWR: 174.5,77.6 174.5,101.96 169.9,106.55 169.72,106.55 169.04,107.24 169.04,108.59 169.16,108.71 170.13,108.71 170.31,108.53 170.31,108.15 170.64,107.82 171.85,107.82 171.98,107.7 181.25,107.7 181.61,107.34 181.61,77.7 181.25,77.34 174.75,77.34
2V5 on L5PWR: 156.46,55.75 156.46,61.47 155.57,62.36 151.51,62.36 151.26,62.1 151.26,60.45 151.38,60.32 152.02,60.32 152.78,59.56 152.78,52.32 147.7,47.24 113.16,47.24 81.03,79.38 77.22,79.38 77.22,77.6 76.33,76.71 71.88,76.71 71.37,77.22 71.37,85.73 77.34,91.69 77.34,114.05 73.53,117.86 61.09,117.86 59.82,119.13 59.82,121.54 56.64,124.71 52.96,124.71 52.7,124.46 52.7,122.94 53.85,121.79 57.02,121.79 57.91,120.9 57.91,118.36 61.09,115.19 72.26,115.19 74.42,113.03 74.42,98.3 64.64,88.52 64.64,44.58 73.03,36.2 130.56,36.2 134.37,40 158.11,40 162.94,44.83 169.93,44.83 171.83,46.74 187.71,46.74 194.56,53.59 205.49,53.59 210.19,58.29 261.37,58.29 262.64,59.56 262.64,77.72 261.62,78.74 180.21,78.74 179.58,78.11 179.58,75.95 180.47,75.06 180.47,56.39 178.94,54.86 157.35,54.86
2V5_LED on TOP: 260.22,62.23 260.22,60.2 260.48,59.94 263.91,59.94 264.16,60.2 264.16,61.98 263.91,62.23 263.27,62.23 263.02,62.48 260.48,62.48
2V5_LED on BOTTOM: 208.41,6.73 208.03,7.11 206.38,7.11 205.74,7.75 205.74,8.51 207.26,10.03 218.06,10.03 219.46,11.43 219.46,22.99 218.69,23.75 205.49,23.75 205.23,24 205.23,26.54 205.61,26.92 265.81,26.92 266.32,26.42 266.32,24.13 265.94,23.75 263.02,23.75 262.25,24.51 256.29,24.51 253.49,21.72 253.49,11.56 255.02,10.03 265.18,10.03 265.81,9.4 265.81,7.24 265.3,6.73 ; 2 cut-outs
2V5_LED on L3SIG: 260.6,61.21 260.6,47.5 268.99,39.12 268.99,30.48 267.02,28.51 262.95,28.51 262.13,27.69 262.13,24.89 263.27,23.75 266.06,23.75 266.45,24.13 266.45,25.53 267.08,26.16 267.84,26.16 271.27,29.59 271.27,40.26 262.89,48.64 262.89,61.21 262.64,61.47 260.86,61.47
2V5_SLP on TOP (solid shape): 74.04,86.36 74.04,83.5 74.99,82.55 74.99,81.34 75.31,81.03 75.69,81.03 75.95,80.77 75.95,77.09 75.57,76.71 70.87,76.71 70.48,77.09 70.48,85.09 72.01,86.61 73.79,86.61
2V5_SLP on BOTTOM (solid shape): 73.79,84.96 73.79,76.33 73.53,76.07 71.12,76.07 70.87,76.33 70.87,85.34 71.12,85.6 73.15,85.6
2V5_SLP on L4PWR: 173.33,99.44 167.13,105.64 167.13,107.9 167.39,108.15 167.39,108.71 168.66,108.71 168.78,108.59 168.78,107.14 169.54,106.37 169.54,106.19 173.99,101.75 173.99,99.57 173.86,99.44
2V5_SLP on L5PWR: 81.28,79.76 77.09,79.76 76.84,79.5 76.84,77.85 76.2,77.22 72.39,77.22 71.88,77.72 71.88,85.47 77.98,91.57 77.98,100.46 78.61,101.09 116.84,101.09 117.48,100.46 117.48,90.81 119.76,88.52 164.21,88.52 171.2,95.5 171.2,100.97 171.7,101.47 174.12,101.47 175.01,100.58 175.01,88.39 150.75,64.14 150.75,60.32 151.26,59.82 151.89,59.82 152.27,59.44 152.27,52.58 147.45,47.75 113.28,47.75
2V5A_QSG1 on BOTTOM: 203.45,65.02 203.45,62.61 203.71,62.36 205.36,62.36 205.61,62.61 205.61,65.02 205.36,65.28 203.71,65.28
2V5A_QSG1 on L6SIG: 204.72,64.64 212.98,64.64 213.74,63.88 213.74,62.61 213.49,62.36 209.68,62.36 209.17,62.86 208.03,62.86 207.9,62.74 204.72,62.74 204.47,62.99 204.47,64.39
2V5A_QSG2 on BOTTOM: 237.74,65.02 237.74,62.61 238,62.36 239.65,62.36 239.9,62.61 239.9,65.02 239.65,65.28 238,65.28
2V5A_QSG2 on L6SIG: 239.01,64.64 247.27,64.64 248.03,63.88 248.03,62.61 247.78,62.36 243.97,62.36 243.46,62.86 242.32,62.86 242.19,62.74 239.01,62.74 238.76,62.99 238.76,64.39
3V3 on TOP: 20.32,153.8 20.32,139.06 20.57,138.81 22.1,138.81 22.35,139.06 22.35,153.8 22.1,154.05 20.57,154.05
3V3 on TOP: 267.21,92.84 267.21,91.82 267.46,91.57 267.46,88.9 267.59,88.77 268.35,88.77 269.24,89.66 269.88,89.66 270.64,88.9 274.45,88.9 275.34,88.01 276.73,88.01 277.11,88.39 277.11,91.82 276.61,92.33 275.21,92.33 274.96,92.08 274.96,91.57 274.57,91.19 274.57,90.42 274.45,90.3 273.94,90.3 273.3,90.93 271.02,90.93 270.38,91.57 270.38,92.46 269.88,92.96 267.34,92.96
3V3 on TOP: 41.4,90.17 41.4,86.61 41.78,86.23 47.24,86.23 50.93,89.92 50.93,100.46 48.26,103.12 48.26,106.93 45.09,110.11 45.09,116.71 35.31,126.49 30.1,126.49 29.34,125.73 29.34,119.76 29.97,119.13 36.83,119.13 38.73,117.22 38.73,109.35 44.2,103.89 44.2,95.12 45.21,94.11 45.21,91.57 44.96,91.31 44.32,91.31 44.2,91.19 44.2,90.81 43.81,90.42 41.66,90.42
3V3 on TOP: 43.05,126.24 41.66,126.24 41.4,125.98 41.4,124.21 41.66,123.95 43.05,123.95 43.31,124.21 43.31,125.98
3V3 on TOP: 58.29,120.4 58.42,120.52 58.42,121.92 58.29,122.05 56.01,122.05 55.88,121.92 55.88,120.52 56.01,120.4
3V3 on TOP: 221.87,160.27 221.87,158.75 222.76,157.86 222.76,157.23 223.14,156.84 224.66,156.84 225.17,157.35 225.17,158.37 224.92,158.62 224.66,158.62 224.28,159 224.28,159.89 225.17,160.78 225.17,161.67 225.55,162.05 226.44,162.05 227.46,161.04 235.08,161.04 236.47,159.64 236.47,153.29 237.62,152.15 242.44,152.15 243.2,152.91 243.2,160.66 239.14,164.72 224.54,164.72 223.52,163.7 223.52,162.94 222.63,162.05 222.63,161.04
3V3 on BOTTOM: 37.72,36.83 37.72,33.15 37.97,32.89 38.86,32.89 39.12,33.15 39.12,35.18 40,36.07 40,36.83 39.75,37.08 37.97,37.08
3V3 on BOTTOM: 270,153.03 271.27,153.03 271.4,153.16 271.4,157.48 271.27,157.61 270,157.61 269.88,157.48 269.88,153.16
3V3 on BOTTOM: 173.74,40.26 173.74,38.99 173.86,38.86 181.1,38.86 181.36,39.12 181.36,40.26 181.1,40.51 173.99,40.51
3V3 on BOTTOM: 62.36,140.33 64.64,140.33 65.28,139.7 65.28,130.56 58.8,124.08 58.8,120.4 58.42,120.02 54.61,120.02 54.23,120.4 54.23,124.84 62.1,132.72 62.1,140.08
3V3 on BOTTOM: 175.51,52.2 175.51,49.02 175.77,48.77 178.82,48.77 179.07,49.02 179.07,52.2 178.82,52.45 175.77,52.45
3V3 on L4PWR: outline of 98 points within 12.7,35.05 277.5,216.79
3V3_OSC_CPLD on TOP: 49.66,111.63 51.31,111.63 51.43,111.76 51.43,113.92 51.31,114.05 48.51,114.05 48.13,113.67 48.13,112.27 48.64,111.76 48.64,111.25 48.77,111.12 49.15,111.12
3V3_SFPP_VDDR on TOP: 177.98,44.45 177.98,42.24 178.18,42.04 178.18,40.89 178.05,40.77 177.6,40.77 177.47,40.89 177.47,44.45
3V3_SFPP_VDDR on BOTTOM: 178.05,42.67 178.05,43.31 178.44,43.69 180.09,43.69 180.85,44.45 180.85,46.48 181.23,46.86 181.23,48.01 180.97,48.26 177.8,48.26 177.55,48.01 177.55,43.94 177.42,43.81 177.42,41.02 177.55,40.89 178.05,40.89 178.18,41.02 178.18,42.55
3V3_SFPP_VDDT on TOP: 176.66,44.45 177.16,44.45 177.16,40.89 177.04,40.77 176.53,40.77 176.4,40.89 176.4,42.04 176.66,42.29
3V3_SFPP_VDDT on BOTTOM: 176.53,43.31 176.53,42.67 176.4,42.55 176.4,41.02 176.53,40.89 177.04,40.89 177.16,41.02 177.16,43.81 177.04,43.94 177.04,48.01 176.78,48.26 173.74,48.26 173.48,48.01 173.48,46.99 174.12,46.35 174.12,44.58 175.01,43.69 176.15,43.69
3V3_SLP on TOP (solid shape): 36.32,95.63 36.32,92.58 36.83,92.08 40.51,92.08 40.77,91.82 40.77,86.36 40.51,86.11 40.51,81.92 40.39,81.79 33.91,81.79 33.02,82.68 33.02,95.63 33.4,96.01 35.94,96.01
3V3_SLP on BOTTOM (solid shape): 36.32,95.89 36.32,86.49 36.07,86.23 33.66,86.23 33.4,86.49 33.4,95.89 33.66,96.14 36.07,96.14
3V3_SLP on TOP: 228.22,144.4 228.6,144.02 228.6,143.26 228.85,143 232.16,143 232.41,143.26 232.41,144.27 232.16,144.53 229.36,144.53 228.47,145.41 228.22,145.41
3V3_SLP on TOP: 45.59,110.24 45.72,110.11 47.12,110.11 47.12,111.76 47.5,112.14 47.5,113.16 47.24,113.41 45.97,113.41 45.59,113.03
3V3_SLP on TOP: 53.59,136.52 53.72,136.65 53.72,138.18 53.59,138.3 51.18,138.3 51.05,138.18 51.05,136.65 51.18,136.52
3V3_SLP on L4PWR: outline of 94 points within 12.7,27.69 238.76,174.75
3V3_USB_HVDD on L5PWR: 162.18,108.71 161.16,108.71 159.13,106.68 159.13,101.98 159.38,101.73 160.15,101.73 160.4,101.98 160.4,106.05 162.31,107.95 162.31,108.59
5V0_SB on TOP: 11.18,80.77 11.18,78.49 11.56,78.11 14.99,78.11 15.37,78.49 15.37,80.77 14.99,81.15 11.56,81.15
5V0_SB on BOTTOM: 5.71,59.05 6.35,58.42 18.16,58.42 18.92,59.18 18.92,78.49 16.26,81.15 11.56,81.15 11.18,80.77 11.18,78.49 11.56,78.11 15.37,78.11 16.38,77.09 16.38,73.91 15.37,72.9 6.86,72.9 5.71,71.76
5V0_SLP on TOP (solid shape): 25.4,116.84 25.4,115.95 25.65,115.7 26.03,115.7 26.42,115.32 26.42,113.28 26.16,113.03 24.13,113.03 24,113.16 24,116.59 24.38,116.97 25.27,116.97
5V0_SLP on TOP (solid shape): 25.4,106.05 25.4,105.16 25.65,104.9 26.03,104.9 26.42,104.52 26.42,102.49 26.16,102.23 24.13,102.23 24,102.36 24,105.79 24.38,106.17 25.27,106.17
5V0_SLP on TOP (solid shape): 25.4,95.25 25.4,94.36 25.65,94.11 26.03,94.11 26.42,93.73 26.42,91.69 26.16,91.44 24.13,91.44 24,91.57 24,95 24.38,95.38 25.27,95.38
5V0_SLP on TOP (solid shape): 62.86,85.09 62.86,84.2 63.12,83.95 63.5,83.95 63.88,83.57 63.88,81.53 63.63,81.28 61.59,81.28 61.47,81.41 61.47,84.84 61.85,85.22 62.74,85.22
5V0_SLP on TOP (solid shape): 197.1,78.74 197.1,75.31 196.72,74.93 195.83,74.93 195.71,75.06 195.71,75.95 195.45,76.2 195.07,76.2 194.69,76.58 194.69,78.61 194.94,78.87 196.98,78.87
5V0_SLP on TOP (solid shape): 217.42,135.89 217.42,132.46 217.04,132.08 216.15,132.08 216.03,132.21 216.03,133.1 215.77,133.35 215.39,133.35 215.01,133.73 215.01,135.76 215.26,136.02 217.3,136.02
5V0_SLP on BOTTOM (solid shape): 23.79,106.64 23.79,106.64 23.86,106.54 23.96,106.47 23.97,106.46 24,106.43 24.13,106.43 26.92,106.43 28.07,105.28 28.07,102.27 27.78,101.98 27.18,101.98 27.16,101.98 24,101.98 23.75,102.23 23.75,103.12 23.24,103.63 21.84,103.63 21.46,104.01 21.46,106.55 21.72,106.81 23.62,106.81
5V0_SLP on BOTTOM (solid shape): 23.79,95.85 23.79,95.84 23.86,95.74 23.96,95.67 23.97,95.67 24,95.63 24.13,95.63 27.31,95.63 28.07,94.87 28.07,91.47 27.78,91.19 27.18,91.19 27.16,91.19 24,91.19 23.75,91.44 23.75,92.33 23.24,92.84 21.84,92.84 21.46,93.22 21.46,95.76 21.72,96.01 23.62,96.01
5V0_SLP on BOTTOM (solid shape): 61.25,85.69 61.25,85.68 61.33,85.58 61.42,85.51 61.43,85.51 61.47,85.47 61.59,85.47 64.39,85.47 65.53,84.33 65.53,81.31 65.25,81.03 64.64,81.03 64.63,81.03 61.47,81.03 61.21,81.28 61.21,82.17 60.71,82.68 59.31,82.68 58.93,83.06 58.93,85.6 59.18,85.85 61.09,85.85
5V0_SLP on BOTTOM (solid shape): 23.79,117.44 23.79,117.43 23.86,117.33 23.96,117.26 23.97,117.26 24,117.22 24.13,117.22 26.92,117.22 28.07,116.08 28.07,113.06 27.78,112.78 27.18,112.78 27.16,112.78 24,112.78 23.75,113.03 23.75,113.92 23.24,114.43 21.84,114.43 21.74,114.53 21.71,114.6 21.74,114.67 21.82,115.06 21.51,115.31 21.46,115.32 21.46,117.35 21.72,117.6 23.62,117.6
5V0_SLP on BOTTOM (solid shape): outline of 268 points within 193.04,72.01 227.84,91.31
5V0_SLP on TOP: 87.38,78.11 87.5,78.23 87.5,78.99 85.47,78.99 85.34,78.87 85.34,78.23 85.47,78.11
5V0_SLP on TOP: 61.09,25.15 61.59,25.15 61.72,25.27 61.72,27.05 62.48,27.81 62.48,28.32 62.36,28.45 61.09,28.45 60.96,28.32 60.96,25.27
5V0_SLP on TOP, BOTTOM: 6.1,73.91 5.71,74.3 5.71,80.77 6.1,81.15 9.53,81.15 9.91,80.77 9.91,74.3 9.53,73.91
5V0_SLP on TOP, BOTTOM: 11.18,101.73 11.18,99.44 11.56,99.06 14.99,99.06 15.37,99.44 15.37,101.73 14.99,102.11 11.56,102.11
5V0_SLP on TOP, BOTTOM: 11.18,93.34 11.18,91.06 11.56,90.68 14.99,90.68 15.37,91.06 15.37,93.34 14.99,93.73 11.56,93.73
5V0_SLP on BOTTOM: 61.09,26.16 62.74,26.16 62.99,26.42 62.99,30.1 62.74,30.35 61.21,30.35 60.96,30.1 60.96,26.29
5V0_SLP on BOTTOM: 218.06,131.44 217.68,131.83 214.5,131.83 213.36,132.97 213.36,136.02 213.61,136.27 217.42,136.27 217.68,136.02 217.68,135.13 218.19,134.62 219.58,134.62 219.96,134.24 221.23,134.24 224.03,131.44 224.03,122.3 223.65,121.92 218.44,121.92 218.06,122.3
5V0_SLP on L4PWR: 55.1,75.82 54.74,76.18 54.74,87.52 54.84,87.63 85.37,87.63 88.27,84.73 88.27,75.82
5V0_SLP on L5PWR: 224.16,123.06 223.9,123.32 208.28,123.32 208.03,123.06 208.03,79.63 208.41,79.25 223.9,79.25 224.16,79.5
5V0_SLP on L5PWR: 64.14,94.23 63.12,95.25 40,95.25 38.35,96.9 33.91,96.9 33.02,97.79 33.02,107.19 32.13,108.08 7.49,108.08 4.7,105.28 4.7,68.2 6.48,66.42 62.99,66.42 64.14,67.56
5V0_SLP on L6SIG: 239.9,147.83 239.9,172.08 231.77,180.21 13.84,180.21 3.94,170.31 3.94,29.21 8.13,25.02 61.98,25.02 63.25,26.29 63.25,38.1 50.55,50.8 15.75,50.8 13.97,52.58 13.97,72.01 30.1,88.14 30.1,124.33 17.27,137.16 17.27,156.46 25.78,164.97 226.57,164.97 229.87,161.67 229.87,152.91 225.42,148.46 218.95,148.46 212.34,141.86 212.34,132.08 213.49,130.94 223.01,130.94
5V0_SLP on L6SIG: 203.58,82.55 203.58,79.38 203.33,79.12 200.41,79.12 197.36,76.07 193.55,76.07 193.04,76.58 193.04,83.19 194.18,84.33 201.8,84.33
5V0_USB1 on TOP: 62.23,26.92 62.23,25.27 62.36,25.15 67.31,25.15 67.69,24.77 67.69,23.11 67.44,22.86 65.79,22.86 65.66,22.73 65.66,20.07 65.79,19.94 67.18,19.94 67.69,19.43 67.69,19.05 67.82,18.92 68.33,18.92 68.45,19.05 68.45,19.56 69.6,20.7 70.99,20.7 71.37,21.08 71.37,24.77 70.48,25.65 68.58,25.65 67.44,26.8 67.44,27.69 67.18,27.94 63.25,27.94
5V0_USB2 on TOP: 57.15,27.05 59.05,27.05 59.18,26.92 59.18,25.15 59.69,24.64 61.34,24.64 62.61,23.37 63.12,23.37 63.63,22.86 65.02,22.86 65.15,22.73 65.15,20.07 65.02,19.94 63.75,19.94 62.61,18.8 59.94,18.8 59.05,19.69 59.05,23.11 58.04,24.13 58.04,25.78 57.53,26.29 57.02,26.29 56.9,26.42 56.9,26.8
7V0_DRV on TOP: 88.77,81.15 89.66,82.04 91.31,82.04 91.44,81.92 91.44,81.28 91.31,81.15 89.79,81.15 89.41,80.77 89.41,78.49 89.28,78.36 88.14,78.36 88.01,78.49 88.01,79.12 87.63,79.5 87.12,79.5 87,79.63 87,81.03 87.12,81.15
7V0_DRV on L3SIG: 103,78.87 88.14,78.87 87.76,79.25 87.76,80.77 88.65,81.66 92.33,81.66 104.14,93.47 107.44,93.47 107.95,93.98 107.95,99.31 107.44,99.82 104.52,99.82 103.76,100.58 103.76,103.25 104.27,103.76 111,103.76 112.4,102.36 112.4,88.27
12V on TOP: 173.35,240.03 173.61,240.28 173.61,241.81 173.35,242.06 170.81,242.06 170.56,241.81 170.56,240.28 170.81,240.03
12V on TOP: 264.03,163.7 263.65,163.32 263.65,157.73 264.8,156.59 267.72,156.59 267.84,156.72 267.84,158.37 267.97,158.5 269.62,158.5 270.26,159.13 270.26,160.15 271.27,161.16 271.27,163.32 270.89,163.7
12V on TOP: 103.51,240.03 103.76,240.28 103.76,241.81 103.51,242.06 100.97,242.06 100.71,241.81 100.71,240.28 100.97,240.03
12V on TOP: 243.2,240.03 243.46,240.28 243.46,241.81 243.2,242.06 240.66,242.06 240.41,241.81 240.41,240.28 240.66,240.03
12V on TOP: 33.53,46.74 59.05,46.74 59.31,46.48 59.31,42.93 59.05,42.67 31.88,42.67 24.26,50.29 24.26,77.47 24.64,77.85 27.81,77.85 28.07,77.6 28.07,52.2
12V on TOP: 33.66,240.03 33.91,240.28 33.91,241.81 33.66,242.06 31.12,242.06 30.86,241.81 30.86,240.28 31.12,240.03
12V on TOP: 273.56,77.47 273.18,77.09 268.73,77.09 266.45,79.38 260.99,79.38 260.73,79.63 260.73,83.82 261.11,84.2 270,84.2 270.76,84.96 274.83,84.96 275.59,84.2 276.99,84.2 278,83.19 278,77.72 277.75,77.47
12V on BOTTOM: 277.75,81.66 277.75,121.67 271.15,128.27 271.15,137.79 271.02,137.92 271.02,139.83 271.15,139.95 271.15,151 269.37,152.78 269.37,157.61 269.88,158.11 269.88,159.77 271.15,161.04 271.15,228.35 257.56,241.94 145.67,241.94 143.51,239.78 138.68,239.78 136.52,241.94 22.61,241.94 12.7,232.03 12.7,164.47 9.4,161.16 9.4,136.65 27.69,118.36 36.07,118.36 36.83,117.6 36.83,84.71 32,79.88 25.4,79.88 23.37,77.85 23.37,73.66 24.13,72.9 34.54,72.9 42.55,80.9 42.55,123.19 41.02,124.71 41.02,125.79 38.23,128.59 32.07,128.59 23.37,137.29 17.78,137.29 16.89,138.18 16.89,156.46 20.83,160.4 20.83,226.95 27.81,233.93 254.76,233.93 265.68,223.01 265.68,183.51 262.76,180.59 262.76,123.57 266.7,119.63 266.7,82.04 268.22,80.52 276.61,80.52
12V_POTS on TOP: 59.94,46.86 59.94,45.09 60.2,44.83 61.34,44.83 61.72,45.21 63.63,45.21 66.04,42.8 72.77,42.8 73.15,43.18 73.15,49.78 72.77,50.16 63.25,50.16
12V_POTS on BOTTOM: 72.64,49.91 72.39,50.16 63.5,50.16 63.25,49.91 63.25,48.26 63.5,48.01 72.39,48.01 72.64,48.26
12V_SLP on TOP: 61.85,137.79 61.85,137.29 62.1,137.03 63.37,137.03 63.88,137.54 63.88,138.68 63.63,138.94 62.23,138.94 62.1,139.06 62.1,139.57 61.85,139.83 60.07,139.83 59.82,139.57 59.82,138.68 60.07,138.43 61.21,138.43
12V_SLP on TOP: 16.13,83.19 16.51,83.57 23.11,83.57 23.49,83.19 23.49,74.8 22.86,74.17 16.13,74.17 15.88,73.91 11.56,73.91 11.18,74.3 11.18,76.58 11.94,77.34 15.24,77.34 16.13,78.23
12V_SLP on TOP: 87,82.55 87,81.66 87.12,81.53 88.65,81.53 89.66,82.55 91.31,82.55 91.44,82.68 91.44,83.19 91.31,83.31 88.77,83.31 88.14,82.68 87.12,82.68
12V_SLP on BOTTOM: 11.18,76.58 11.18,74.3 11.56,73.91 14.99,73.91 15.37,74.3 15.37,76.58 14.99,76.96 11.56,76.96
12V_SLP on BOTTOM: 89.66,81.92 89.28,81.53 77.98,81.53 73.41,86.11 70.61,86.11 70.23,86.49 56.9,86.49 39.88,69.47 21.84,69.47 19.43,71.88 19.43,76.33 19.69,76.58 22.1,76.58 22.61,76.07 22.61,73.53 24,72.14 35.05,72.14 43.31,80.39 43.31,127.25 43.37,127.32 43.37,128.08 43.43,128.14 43.43,138.18 44.2,138.94 57.91,138.94 58.55,139.57 61.21,139.57 61.59,139.19 61.59,133.1 53.21,124.71 53.21,96.9 54.61,95.5 65.91,95.5 73.66,87.76 77.6,87.76 80.39,84.96 89.28,84.96 89.66,84.58
12VF_SLP on TOP: 26.8,84.71 32.13,84.71 32.51,84.33 32.51,79.38 32,78.87 26.8,78.87 26.42,79.25 26.42,84.33
12VF_SLP on TOP: 105.03,104.14 107.44,104.14 107.44,109.73 106.3,110.87 100.84,110.87 100.58,110.62 100.58,107.82 97.92,105.16 97.92,102.11 100.46,99.57 100.46,96.9 97.92,94.36 97.92,91.69 98.17,91.44 102.11,91.44 102.49,91.82 102.49,95.38 102.62,95.5 103.51,95.5 105.03,93.98 107.44,93.98 107.44,99.31 107.32,99.44 104.27,99.44 102.49,101.22 102.49,105.54 102.62,105.66 103.51,105.66
12VF_SLP on BOTTOM: 100.84,91.82 103,91.82 103.51,92.33 103.51,93.73 103.76,93.98 107.19,93.98 107.44,94.23 107.44,99.19 107.19,99.44 104.39,99.44 103.38,100.46 103.38,102.87 104.65,104.14 107.19,104.14 107.44,104.39 107.44,109.73 106.3,110.87 100.84,110.87 100.58,110.62 100.58,92.08
12VF_SLP on L3SIG: 106.17,111 107.44,109.73 107.44,104.39 107.19,104.14 104.14,104.14 103.38,103.38 103.38,100.46 104.39,99.44 107.19,99.44 107.44,99.19 107.44,94.23 107.19,93.98 103.89,93.98 92.2,82.3 88.65,82.3 84.71,78.36 27.81,78.36 27.18,78.99 27.18,83.31 29.59,85.73 36.32,85.73 38.48,87.88 81.66,87.88 86.36,92.58 86.36,109.35 88.01,111
AGND_SD1_PLL1 on L6SIG: 185.17,125.48 185.29,125.35 185.29,124.84 185.17,124.71 183.26,124.71 179.96,121.41 179.96,117.6 178.18,115.82 172.21,115.82 171.96,115.57 171.96,115.44 171.83,115.32 171.45,115.32 171.32,115.44 171.32,115.95 171.83,116.46 177.8,116.46 179.32,117.98 179.32,121.67 183.13,125.48
AGND_SD1_PLL2 on L6SIG: 171.45,119.13 171.45,118.75 171.58,118.62 171.96,118.62 172.08,118.75 172.08,118.87 172.21,119 175.39,119 175.77,118.62 177.8,118.62 178.31,119.13 178.31,122.56 184.28,128.52 185.17,128.52 185.29,128.65 185.29,129.16 185.17,129.29 184.15,129.29 177.67,122.81 177.67,119.63 177.55,119.51 171.83,119.51
AVDD_CGA1 on L5PWR: 159.26,111.12 159.89,111.12 160.02,111 160.02,110.62 159.89,110.49 159.38,110.49 159,110.11 157.99,110.11 157.23,109.35 154.56,109.35 154.3,109.6 154.3,111.12 154.56,111.38 159,111.38
AVDD_CGA2 on L5PWR: 160.02,112.78 160.02,111.51 159.89,111.38 159.38,111.38 159.13,111.63 154.56,111.63 154.3,111.89 154.3,112.9 154.43,113.03 159.77,113.03
AVDD_PLAT on L5PWR: 159,109.86 159.51,110.36 159.89,110.36 160.02,110.24 160.02,109.98 156.97,106.93 154.69,106.93 154.3,107.32 154.3,108.84 154.56,109.09 157.23,109.09 157.99,109.86
AVDD_SD1_PLL1 on L6SIG: 185.17,124.46 185.29,124.33 185.29,123.83 185.17,123.7 183.39,123.7 180.72,121.03 180.72,117.09 178.69,115.06 172.47,115.06 172.21,115.32 172.21,115.7 172.34,115.82 172.72,115.82 172.97,115.57 175.26,115.57 175.39,115.7 178.31,115.7 180.09,117.48 180.09,121.29 183.26,124.46
AVDD_SD1_PLL2 on L6SIG: 175.64,118.49 177.93,118.49 178.44,119 178.44,122.43 184.28,128.27 185.17,128.27 185.29,128.14 185.29,127.64 185.17,127.51 184.4,127.51 179.07,122.17 179.07,118.36 178.44,117.73 175.51,117.73 175.01,118.24 172.47,118.24 172.21,118.49 172.21,118.87 172.34,119 172.72,119 172.97,118.75 175.39,118.75
DVDD on TOP: 48.13,129.92 47.88,130.17 46.74,130.17 46.1,129.54 45.09,129.54 44.96,129.41 44.96,127.89 46.48,126.37 46.48,123.7 47.5,122.68 48.26,122.68 48.51,122.94 48.51,126.37 48.13,126.75
DVDD on L4PWR: 105.13,90.3 92.94,102.49 72.88,102.49 52.3,123.06 48.37,123.06 48.01,123.42 48.01,125.37 48.37,125.73 54.5,125.73 74.7,105.54 95.4,105.54 106.83,94.11 162.92,94.11 164.47,95.65 164.47,103.99 163.96,104.5 163.96,107.95 164.01,107.95 164.21,108.15 164.21,108.71 167.13,108.71 167.13,108.26 166.88,108 166.88,105.64 166.75,105.52 166.75,105.3 173.99,98.07 173.99,92.96 173.74,92.71 167.66,92.71 165.25,90.3
GND on TOP (solid shape): 197.1,83.69 197.1,81.41 196.98,81.28 194.56,81.28 193.8,82.04 191.26,82.04 190.63,81.41 190.63,77.98 191.13,77.47 193.8,77.47 194.18,77.09 194.18,76.33 194.69,75.82 195.07,75.82 195.2,75.69 195.2,74.8 195.07,74.68 189.61,74.68 188.59,75.69 188.59,83.82 188.85,84.07 196.72,84.07
GND on TOP (solid shape): 217.42,140.84 217.42,138.56 217.3,138.43 214.88,138.43 214.12,139.19 211.58,139.19 210.95,138.56 210.95,135.13 211.45,134.62 214.12,134.62 214.5,134.24 214.5,133.48 215.01,132.97 215.39,132.97 215.52,132.84 215.52,131.06 212.85,128.4 207.26,128.4 206.38,129.29 204.85,129.29 204.6,129.54 204.6,130.81 205.1,131.32 208.28,131.32 208.91,131.95 208.91,140.33 209.8,141.22 217.04,141.22
GND on TOP (solid shape): 69.98,84.45 69.98,74.93 69.09,74.04 55.88,74.04 55.37,73.53 55.37,62.1 57.02,60.45 57.02,56.39 56.77,56.13 52.7,56.13 52.45,56.39 52.45,58.58 56.39,58.58 56.39,60.13 53.6,60.13 53.6,58.58 52.45,58.58 52.45,60.32 50.93,61.85 50.93,64.32 53.12,64.32 53.12,65.98 51.47,65.98 51.47,64.32 50.93,64.32 50.93,73.21 53.12,73.21 53.12,74.87 51.47,74.87 51.47,73.21 50.93,73.21 50.93,75.18 50.29,75.82 40.77,75.82 40.39,76.2 40.39,79.76 39.88,80.26 37.08,80.26 36.58,79.76 36.58,76.2 35.56,75.18 30.1,75.18 29.84,75.44 29.84,77.6 30.61,78.36 32.38,78.36 35.31,81.28 53.47,81.28 53.98,80.77 53.98,80.01 54.61,79.38 54.61,77.98 55.37,77.22 58.17,77.22 59.56,75.82 61.21,75.82 61.47,76.07 61.47,78.74 61.59,78.87 64.01,78.87 64.77,78.11 67.31,78.11 67.95,78.74 67.95,82.17 67.44,82.68 64.77,82.68 64.39,83.06 64.39,83.82 63.88,84.33 63.5,84.33 63.37,84.45 63.37,85.34 63.5,85.47 68.96,85.47
GND on TOP (solid shape): outline of 254 points within 2.52,240.52 11.52,249.52
GND on TOP (solid shape): outline of 254 points within 2.52,11.52 11.52,20.52
GND on TOP (solid shape): outline of 254 points within 29.54,129.23 38.54,138.23
GND on TOP (solid shape): outline of 254 points within 136.52,240.52 145.52,249.52
GND on TOP (solid shape): outline of 254 points within 216.23,80.34 225.23,89.34
GND on TOP (solid shape): outline of 254 points within 270.52,240.52 279.52,249.52
GND on BOTTOM (solid shape): 23.24,113.67 23.24,110.49 23.11,110.36 22.48,110.36 22.35,110.49 22.35,111.12 22.1,111.38 21.59,111.38 21.46,111.51 21.46,113.79 21.59,113.92 22.99,113.92
GND on BOTTOM (solid shape): 23.24,102.87 23.24,99.7 23.11,99.57 22.48,99.57 22.35,99.7 22.35,100.33 22.1,100.58 21.59,100.58 21.46,100.71 21.46,103 21.59,103.12 22.99,103.12
GND on BOTTOM (solid shape): 23.24,92.08 23.24,88.9 23.11,88.77 22.48,88.77 22.35,88.9 22.35,89.54 22.1,89.79 21.59,89.79 21.46,89.92 21.46,92.2 21.59,92.33 22.99,92.33
GND on BOTTOM (solid shape): 60.71,81.92 60.71,78.74 60.58,78.61 59.94,78.61 59.82,78.74 59.82,79.38 59.56,79.63 59.05,79.63 58.93,79.76 58.93,82.04 59.05,82.17 60.45,82.17
GND on BOTTOM (solid shape): 198.75,81.41 198.75,80.77 199.01,80.52 199.52,80.52 199.64,80.39 199.64,78.11 199.52,77.98 198.12,77.98 197.87,78.23 197.87,81.41 197.99,81.53 198.63,81.53
GND on BOTTOM (solid shape): 219.07,138.56 219.07,137.92 219.33,137.67 219.84,137.67 219.96,137.54 219.96,135.25 219.84,135.13 218.44,135.13 218.19,135.38 218.19,138.56 218.31,138.68 218.95,138.68
GND on BOTTOM (solid shape): 70.36,85.73 70.36,76.33 70.1,76.07 61.85,76.07 61.34,76.58 61.34,80.01 61.85,80.52 64.28,80.52 64.3,80.49 64.44,80.32 64.64,80.26 65.56,80.26 66.42,81.12 66.42,84.61 66.04,84.99 66.04,85.73 66.29,85.98 70.1,85.98
GND on BOTTOM (solid shape): 197.29,91.5 197.29,85.28 197.23,85.22 197.23,80.14 196.72,79.63 194.29,79.63 194.28,79.66 194.14,79.82 193.93,79.88 193.01,79.88 192.15,79.02 192.15,75.53 192.53,75.15 192.53,74.42 192.28,74.17 190.4,74.17 190.12,74.3 189.83,74.17 188.47,74.17 188.21,74.42 188.21,86.74 188.72,87.25 188.72,92.46 189.36,93.09 195.71,93.09
GND on BOTTOM (solid shape): 32.89,117.48 32.89,86.49 32.64,86.23 24.38,86.23 23.88,86.74 23.88,90.17 24.38,90.68 26.82,90.68 26.83,90.65 26.97,90.48 27.18,90.42 28.1,90.42 28.96,91.28 28.96,95.15 27.72,96.39 24.38,96.39 23.88,96.9 23.88,100.97 24.38,101.47 26.82,101.47 26.83,101.44 26.97,101.28 27.18,101.22 28.1,101.22 28.96,102.08 28.96,105.57 27.34,107.19 24.26,107.19 23.88,107.57 23.88,111.76 24.38,112.27 26.82,112.27 26.83,112.24 26.97,112.07 27.18,112.01 28.1,112.01 28.96,112.87 28.96,116.36 28.58,116.74 28.58,117.48 28.83,117.73 32.64,117.73
GND on BOTTOM (solid shape): outline of 254 points within 2.52,240.52 11.52,249.52
GND on BOTTOM (solid shape): outline of 254 points within 2.52,11.52 11.52,20.52
GND on BOTTOM (solid shape): outline of 254 points within 29.54,129.23 38.54,138.23
GND on BOTTOM (solid shape): outline of 254 points within 136.52,240.52 145.52,249.52
GND on BOTTOM (solid shape): outline of 254 points within 216.23,80.34 225.23,89.34
GND on BOTTOM (solid shape): outline of 254 points within 270.52,240.52 279.52,249.52
GND on TOP: 232.41,128.27 232.92,127.76 237.36,127.76 238.12,128.52 238.12,130.94 237.87,131.19 237.87,131.95 237.62,132.21 237.36,132.21 237.24,132.08 237.24,131.95 237.49,131.7 237.49,130.05 237.11,129.67 236.85,129.67 235.58,128.4 233.55,128.4 233.3,128.65 233.3,130.17 233.68,130.56 234.82,130.56 234.95,130.68 234.95,131.32 234.19,132.08 234.19,133.1 234.06,133.22 233.81,133.22 233.43,132.84 233.43,131.83 232.41,130.81
GND on TOP: 16.26,73.53 16.26,70.61 16.38,70.48 17.65,70.48 18.29,71.12 18.29,73.53 18.16,73.66 16.38,73.66
GND on TOP: 53.85,140.72 53.98,140.84 53.98,142.88 53.85,143 51.31,143 51.18,142.88 51.18,140.84 51.31,140.72
GND on TOP: 126.62,45.21 126.62,44.07 126.87,43.81 129.67,43.81 129.92,44.07 129.92,45.09 129.67,45.34 126.75,45.34
GND on TOP: 225.81,150.5 225.81,154.18 225.3,154.69 224.41,154.69 223.9,155.19 223.9,156.34 223.77,156.46 222.12,156.46 222,156.34 222,146.81 223.27,145.54 225.55,145.54 225.93,145.92 228.6,145.92 229.49,145.03 232.79,145.03 234.95,147.19 234.95,153.8 234.44,154.3 230.5,154.3 230.38,154.18 230.38,150.5 231.77,149.1 231.77,148.08 231.52,147.83 229.36,147.83 228.98,147.45 225.68,147.45 225.3,147.83 223.39,147.83 222.76,148.46 222.76,149.99 223.01,150.24 224.92,150.24 225.17,149.99 225.17,149.48 225.81,148.84 226.57,148.84 226.69,148.72 226.95,148.72 226.95,148.97 226.44,149.48 226.44,149.86
GND on TOP: 59.69,27.05 59.69,25.27 59.82,25.15 60.32,25.15 60.45,25.27 60.45,28.32 60.32,28.45 59.05,28.45 58.93,28.32 58.93,27.81
GND on TOP: 202.06,126.75 202.56,127.25 203.07,127.25 203.2,127.38 203.2,127.76 203.07,127.89 201.55,127.89 201.29,128.14 201.29,128.52 201.17,128.65 200.41,128.65 200.28,128.52 200.28,127.76 199.9,127.38 199.9,126.87 200.02,126.75
GND on TOP: 196.6,123.83 196.6,130.05 196.34,130.3 193.67,130.3 193.42,130.05 193.42,124.08 192.02,124.08 191.64,124.46 191.64,130.68 194.18,133.22 197.1,133.22 197.36,132.97 197.36,123.83
GND on TOP: 148.84,44.58 148.84,43.43 149.1,43.18 151.89,43.18 152.15,43.43 152.15,44.45 151.89,44.7 148.97,44.7
GND on TOP: 80.26,60.32 80.77,59.82 80.77,57.4 80.26,56.9 80.26,51.82 92.08,51.82 93.22,52.96 93.22,56.52 92.71,57.02 92.71,59.56 93.22,60.07 93.22,61.85 92.58,62.48 92.58,62.86 91.95,63.5 81.03,63.5 80.26,62.74
GND on TOP: 84.2,80.39 83.57,79.76 82.42,79.76 81.92,79.25 81.92,77.72 82.17,77.47 83.31,77.47 85.34,79.5 86.23,79.5 86.49,79.76 86.49,83.82 86.36,83.95 84.58,83.95 84.2,83.57
GND on TOP: 68.71,26.16 67.95,26.92 67.95,29.21 67.69,29.46 67.69,34.42 68.33,35.05 68.33,35.31 64.9,35.31 64.52,35.69 64.52,37.72 63.12,39.12 60.2,39.12 59.82,39.5 59.82,44.2 59.94,44.32 61.47,44.32 61.85,44.7 63.5,44.7 65.91,42.29 72.77,42.29 73.15,41.91 73.15,33.15 72.14,32.13 72.14,26.42 71.88,26.16
GND on TOP: 187.2,69.47 187.2,61.09 187.45,60.83 195.83,60.83 195.83,69.09 195.45,69.47
GND on TOP: outline of 217 points within 1.78,1.78 280.25,250.25 ; 10 cut-outs
GND on TOP: 19.94,16.89 22.35,14.48 56.77,14.48 58.29,16 58.29,21.34 57.28,22.35 55.75,22.35 54.48,23.62 54.48,39.62 52.32,41.78 20.83,41.78 19.94,40.89
GND on TOP: 78.23,91.44 79.5,91.44 79.63,91.57 79.63,93.09 79.5,93.22 78.23,93.22 78.11,93.09 78.11,91.57
GND on TOP: 79.88,96.01 79.5,96.01 79.12,96.39 77.47,96.39 77.34,96.27 77.34,95.63 77.98,95 80.01,95 80.14,95.12 80.14,95.76
GND on TOP: 77.6,103.12 77.6,101.47 77.98,101.09 80.77,101.09 81.15,101.47 81.15,102.11 80.77,102.49 79.88,102.49 79.76,102.62 79.76,103.25 79.63,103.38 77.85,103.38
GND on TOP: 67.06,24.77 67.31,24.51 67.31,23.37 67.06,23.11 63.88,23.11 63.12,23.88 62.61,23.88 62.1,24.38 62.1,24.64 62.23,24.77
GND on TOP: 108.08,77.34 107.44,77.98 107.44,79.25 107.32,79.38 105.41,79.38 102.87,76.84 92.96,76.84 92.08,77.72 92.08,84.96 91.69,85.34 91.69,114.3 92.33,114.94 112.27,114.94 113.16,115.82 122.43,115.82 122.87,115.38 122.87,112.46 124.21,111.12 125.86,111.12 126.11,111.38 126.11,111.89 126.37,112.14 128.65,112.14 129.92,110.87 129.92,105.41 130.56,104.78 132.08,104.78 133.35,103.51 136.14,103.51 136.52,103.89 136.52,112.52 136.65,112.65 137.41,112.65 143.13,106.93 143.13,86.11 140.21,83.19 123.95,83.19 118.11,77.34 ; 5 cut-outs
GND on TOP: 266.57,91.82 266.95,91.44 266.95,88.9 266.83,88.77 265.05,88.77 264.67,89.15 264.67,93.47 265.05,93.85 266.7,93.85 266.83,93.73 266.83,93.22 266.57,92.96
GND on TOP: 79.5,85.34 79.63,85.47 79.63,86.74 79.5,86.87 74.68,86.87 74.42,86.61 74.42,85.6 74.68,85.34
GND on TOP: 103.12,60.32 103.63,59.82 103.63,57.4 103.12,56.9 103.12,51.82 115.06,51.82 116.08,52.83 116.08,56.52 115.57,57.02 115.57,59.56 116.08,60.07 116.08,62.61 115.19,63.5 103.89,63.5 103.12,62.74
GND on TOP: 133.1,38.23 135.51,38.23 136.02,37.72 136.02,28.7 135.76,28.45 133.22,28.45 132.84,28.83 132.84,37.97
GND on TOP: 84.07,112.27 83.06,111.25 83.06,110.74 83.19,110.62 85.22,110.62 85.47,110.36 85.47,106.68 83.69,104.9 83.69,101.22 83.95,100.97 83.95,86.36 84.33,85.98 89.15,85.98 89.54,86.36 89.54,88.65 89.41,88.77 87,88.77 85.98,89.79 85.98,92.46 86.36,92.84 88.52,92.84 88.77,93.09 88.77,97.54 88.52,97.79 86.61,97.79 85.85,98.55 85.85,100.58 86.61,101.35 87.88,101.35 88.52,101.98 88.52,105.28 87.63,106.17 86.61,106.17 86.11,106.68 86.11,108.97 86.36,109.22 89.28,109.22 89.54,109.47 89.54,112.01 89.28,112.27
GND on TOP: 180.21,65.15 184.53,65.15 185.04,64.64 185.55,64.64 185.67,64.52 185.67,64.14 185.55,64.01 184.4,64.01 183.64,63.25 182.75,63.25 182.5,63.5 182.5,64.52 182.25,64.77 180.72,64.77 180.59,64.64 180.59,62.48 180.85,62.23 181.86,62.23 181.99,62.1 181.99,60.96 182.25,60.71 183.9,60.71 184.28,61.09 184.28,61.21 184.53,61.47 185.04,61.47 185.17,61.34 185.17,60.71 184.78,60.32 180.72,60.32 179.96,61.09 179.96,64.9
GND on TOP, BOTTOM: 72.64,20.07 72.77,19.94 74.3,19.94 74.42,20.07 74.42,22.35 74.3,22.48 72.77,22.48 72.64,22.35
GND on BOTTOM: outline of 107 points within 1.78,1.78 280.25,250.25 ; 2 cut-outs
GND on BOTTOM: 200.53,128.4 202.56,130.43 207.77,130.43 208.53,131.19 208.53,140.97 208.79,141.22 217.04,141.22 217.55,140.72 217.55,137.29 217.04,136.78 213.36,136.78 212.47,135.89 212.47,132.33 214.38,130.43 215.52,130.43 216.15,129.79 216.15,123.06 215.26,122.17 201.17,122.17 200.53,122.81
GND on BOTTOM: 209.93,69.09 210.44,69.09 210.57,69.22 212.34,69.22 213.49,68.07 213.49,65.41 213.74,65.15 217.17,65.15 217.55,64.77 217.55,64.01 217.3,63.75 215.14,63.75 214.5,64.39 209.04,64.39 208.91,64.52 207.39,64.52 206.88,64.01 206.88,61.85 206.76,61.72 206.25,61.72 206.12,61.85 206.12,70.74 206.88,71.5 215.26,71.5 215.52,71.25 215.52,70.61 215.26,70.36 214.63,70.36 213.74,69.47 213.36,69.47 212.85,69.98 212.34,69.98 211.71,70.61 209.17,70.61 208.79,70.23 208.79,65.79 209.3,65.28 210.19,65.28 210.44,65.53 210.44,66.17 210.82,66.55 210.82,67.44 210.69,67.56 210.69,68.07 210.19,68.58 209.93,68.58
GND on BOTTOM: 234.19,137.16 234.19,134.49 234.44,134.24 237.74,134.24 237.87,134.11 237.87,133.73 238,133.6 238.38,133.6 238.63,133.86 238.63,134.87 238.38,135.13 238.38,136.27 238.51,136.4 238.51,138.43 238.25,138.68 234.19,138.68 233.93,138.43 233.93,137.41
GND on BOTTOM: 133.98,49.4 134.37,49.02 134.37,48.39 134.49,48.26 138.3,48.26 138.56,48.51 138.56,52.2 137.92,52.83 136.65,52.83 135.38,54.1 134.37,54.1 133.98,53.72
GND on BOTTOM: 18.29,96.01 18.29,93.73 18.54,93.47 20.32,93.47 20.57,93.73 20.57,96.01 20.32,96.27 18.54,96.27
GND on BOTTOM: 173.35,52.2 173.35,49.02 173.61,48.77 174.75,48.77 175.01,49.02 175.01,52.2 174.75,52.45 173.61,52.45
GND on BOTTOM: outline of 135 points within 93.34,76.71 148.84,115.44 ; 2 cut-outs
GND on BOTTOM: 244.22,69.09 244.73,69.09 244.86,69.22 246.63,69.22 247.78,68.07 247.78,65.41 248.03,65.15 251.46,65.15 251.84,64.77 251.84,64.01 251.59,63.75 249.43,63.75 248.79,64.39 243.33,64.39 243.2,64.52 241.68,64.52 241.17,64.01 241.17,61.85 241.05,61.72 240.54,61.72 240.41,61.85 240.41,70.74 241.17,71.5 249.55,71.5 249.81,71.25 249.81,70.61 249.55,70.36 248.92,70.36 248.03,69.47 247.65,69.47 247.14,69.98 246.63,69.98 246,70.61 243.46,70.61 243.08,70.23 243.08,65.79 243.59,65.28 244.47,65.28 244.73,65.53 244.73,66.17 245.11,66.55 245.11,67.44 244.98,67.56 244.98,68.07 244.47,68.58 244.22,68.58
GND on BOTTOM: 90.81,53.72 90.42,54.1 90.42,55.12 90.81,55.5 91.95,55.5 92.58,56.13 92.58,62.99 92.08,63.5 91.44,63.5 91.19,63.25 91.19,62.23 90.93,61.98 89.79,61.98 89.54,62.23 89.54,62.86 89.03,63.37 85.22,63.37 84.84,62.99 84.84,62.23 84.33,61.72 82.04,61.72 81.66,62.1 81.66,63.12 81.41,63.37 81.03,63.37 80.26,62.61 80.26,60.71 80.9,60.07 80.9,56.39 81.79,55.5 82.68,55.5 83.06,55.12 83.06,52.83 82.68,52.45 82.04,52.45 81.66,52.07 81.66,50.67 81.92,50.42 85.22,50.42 85.98,51.18 87.5,51.18 88.27,50.42 91.57,50.42 91.82,50.67 91.82,53.34 91.44,53.72
GND on BOTTOM: 177.55,66.42 179.07,66.42 179.2,66.55 179.2,69.72 178.94,69.98 177.67,69.98 177.42,69.72 177.42,66.55
GND on BOTTOM: 80.26,107.7 90.55,107.7 91.19,107.06 91.19,103.76 89.79,102.36 89.79,101.09 91.95,98.93 91.95,90.68 90.3,89.03 90.3,87.12 89.66,86.49 83.19,86.49 79.76,89.92 77.98,89.92 76.96,90.93 76.96,95 79.25,97.28 79.25,98.3 78.11,99.44 78.11,103.63 79.76,105.28 79.76,107.19
GND on BOTTOM: 264.92,184.02 263.14,182.25 188.34,182.25 180.34,190.25 180.34,202.95 179.2,204.09 173.61,204.09 157.35,187.83 129.41,187.83 108.59,208.66 90.17,208.66 86.87,205.36 86.87,162.43 83.19,158.75 23.24,158.75 21.59,160.4 21.59,226.31 28.45,233.17 254.51,233.17 264.92,222.76
GND on BOTTOM: 156.21,48.77 156.59,48.39 156.59,47.75 156.72,47.62 160.53,47.62 160.78,47.88 160.78,51.56 160.15,52.2 158.88,52.2 157.61,53.47 156.59,53.47 156.21,53.09
GND on BOTTOM: 113.67,53.72 113.28,54.1 113.28,55.12 113.67,55.5 114.81,55.5 115.44,56.13 115.44,62.99 114.94,63.5 114.3,63.5 114.05,63.25 114.05,62.23 113.79,61.98 112.65,61.98 112.4,62.23 112.4,62.86 111.89,63.37 108.08,63.37 107.7,62.99 107.7,62.23 107.19,61.72 104.9,61.72 104.52,62.1 104.52,63.12 104.27,63.37 103.89,63.37 103.12,62.61 103.12,60.71 103.76,60.07 103.76,56.39 104.65,55.5 105.54,55.5 105.92,55.12 105.92,52.83 105.54,52.45 104.9,52.45 104.52,52.07 104.52,50.67 104.78,50.42 108.08,50.42 108.84,51.18 110.36,51.18 111.12,50.42 114.43,50.42 114.68,50.67 114.68,53.34 114.3,53.72
GND on BOTTOM: 179.58,52.2 179.58,49.02 179.83,48.77 180.97,48.77 181.23,49.02 181.23,52.2 180.97,52.45 179.83,52.45
GND on BOTTOM: 155.7,127.89 155.19,128.4 155.19,132.33 154.69,132.84 151.38,132.84 150.75,132.21 150.75,129.54 150.5,129.29 139.19,129.29 134.49,133.98 112.4,133.98 106.43,139.95 72.52,139.95 71.88,140.59 71.88,142.11 72.26,142.49 106.3,142.49 106.68,142.88 106.68,149.48 108.71,151.51 159.77,151.51 161.29,153.03 193.93,153.03 194.31,152.65 194.31,149.73 196.6,147.45 196.6,137.29 194.56,135.25 193.04,135.25 192.15,135 191.13,135 190.12,135.25 185.93,135.25 178.56,127.89
GND on BOTTOM: 67.56,65.15 67.82,64.9 69.22,64.9 69.47,65.15 69.85,65.15 70.1,65.41 70.1,68.45 69.85,68.71 67.82,68.71 67.56,68.45
GND on BOTTOM: 188.34,70.23 188.34,69.72 188.85,69.22 188.85,62.48 195.83,62.48 196.09,62.74 196.47,62.74 196.72,62.99 196.72,64.01 195.96,64.77 194.44,64.77 194.18,65.02 194.18,68.33 193.93,68.58 192.15,68.58 191.9,68.83 191.9,69.72 191.13,70.48 188.59,70.48
GND on L2GND: outline of 145 points within 1.78,1.78 280.25,250.25 ; 60 cut-outs
GND on L3SIG: 3.3,128.02 1.78,129.54 1.78,248.02 2.43,249.6 4.02,250.25 278.02,250.25 279.6,249.6 280.25,248.02 280.25,126.08 278.89,124.71 266.45,124.71 240.28,150.88 231.65,150.88 230.25,152.27 230.25,161.42 228.22,163.45 62.99,163.45 50.67,151.13 50.67,132.59 46.1,128.02 ; 1 cut-out
GND on L4PWR: outline of 144 points within 1.78,1.78 280.25,250.25 ; 1 cut-out
GND on L5PWR: outline of 148 points within 1.78,1.78 280.29,250.25 ; 1 cut-out
GND on L6SIG: 94.74,88.01 99.06,88.01 100.71,86.36 118.49,86.36 119.51,87.38 119.51,111.89 118.75,112.65 80.9,112.65 77.98,109.73 77.98,90.93 81.15,87.76 83.95,87.76 85.34,86.36 93.09,86.36
GND on L6SIG: 1.78,182.37 1.78,248.02 2.43,249.6 4.02,250.25 278.02,250.25 279.6,249.6 280.25,248.02 280.25,161.64 279.65,161.04 270.51,161.04 269.24,159.77 244.86,159.77 240.92,163.7 240.92,172.21 232.16,180.97 3.18,180.97
GND on L7GND: outline of 145 points within 1.78,1.78 280.25,250.25 ; 4 cut-outs
SVDD on TOP: 193.93,126.62 193.93,124.08 196.09,124.08 196.34,124.33 196.34,126.37 196.09,126.62
SVDD on L4PWR: 170.87,112.14 170.69,112.32 170.69,113.72 169.93,114.48 169.93,118.92 169.92,118.94 169.92,119.39 170.41,119.89 171.96,119.89 172.21,119.63 172.21,112.25 172.11,112.14
SVDD on L5PWR: 170.05,114.55 171.2,114.55 171.45,114.81 171.45,119.38 171.2,119.63 170.18,119.63 169.93,119.38 169.93,114.68
SVDD on L6SIG: 188.09,111.12 196.09,119.13 196.09,126.49 195.83,126.75 187.07,126.75 186.31,125.98 186.31,123.57 185.8,123.06 184.15,123.06 181.48,120.4 181.48,116.71 179.32,114.55 171.07,114.55 170.81,114.81 170.81,119.25 170.69,119.38 168.91,119.38 168.66,119.13 168.66,111.63 169.16,111.12
VBATH on TOP: 37.08,79.5 37.08,77.09 37.34,76.84 39.62,76.84 39.88,77.09 39.88,79.5 39.62,79.76 37.34,79.76
VBATH on BOTTOM: 96.77,50.67 96.9,50.55 99.44,50.55 99.57,50.67 99.57,53.21 99.44,53.34 96.9,53.34 96.77,53.21
VBATH on BOTTOM: 119.76,50.55 121.41,50.55 121.54,50.67 121.54,53.21 121.41,53.34 119.76,53.34 119.63,53.21 119.63,50.67
VBATH on L6SIG: 120.52,47.12 115.7,42.29 64.14,42.29 38.73,67.69 38.73,79.12 39.12,79.5 45.97,79.5 60.58,64.9 118.36,64.9 120.52,62.74
VBATL on TOP: 44.83,70.61 45.21,70.99 45.21,74.3 44.96,74.55 40.77,74.55 40.51,74.3 40.51,70.87 40.77,70.61
VBATL on BOTTOM, L3SIG: 62.23,51.43 60.96,51.43 60.83,51.31 60.83,50.04 60.96,49.91 62.23,49.91 62.36,50.04 62.36,51.31
VBATL on L3SIG: 44.96,72.9 43.69,72.9 43.56,72.77 43.56,71.5 43.69,71.37 44.96,71.37 45.09,71.5 45.09,72.77
(no net) on TOP: 24.13,91.44 26.16,91.44 26.42,91.69 26.42,93.73 26.03,94.11 25.65,94.11 25.4,94.36 25.4,95.25 25.27,95.38 24.38,95.38 24,95 24,91.57
(no net) on TOP: 194.56,81.28 196.98,81.28 197.1,81.41 197.1,83.69 196.72,84.07 188.85,84.07 188.59,83.82 188.59,75.69 189.61,74.68 195.07,74.68 195.2,74.8 195.2,75.69 195.07,75.82 194.69,75.82 194.18,76.33 194.18,77.09 193.8,77.47 191.13,77.47 190.63,77.98 190.63,81.41 191.26,82.04 193.8,82.04
(no net) on TOP: 29.72,88.77 27.43,88.77 26.8,89.41 24,89.41 23.88,89.54 23.88,90.93 24,91.06 26.67,91.06 27.94,92.33 29.72,92.33 29.97,92.08 29.97,89.03
(no net) on TOP: 33.02,82.68 33.91,81.79 40.39,81.79 40.51,81.92 40.51,86.11 40.77,86.36 40.77,91.82 40.51,92.08 36.83,92.08 36.32,92.58 36.32,95.63 35.94,96.01 33.4,96.01 33.02,95.63
(no net) on TOP: 24.13,102.23 26.16,102.23 26.42,102.49 26.42,104.52 26.03,104.9 25.65,104.9 25.4,105.16 25.4,106.05 25.27,106.17 24.38,106.17 24,105.79 24,102.36
(no net) on TOP: 61.59,81.28 63.63,81.28 63.88,81.53 63.88,83.57 63.5,83.95 63.12,83.95 62.86,84.2 62.86,85.09 62.74,85.22 61.85,85.22 61.47,84.84 61.47,81.41
(no net) on TOP: 217.3,136.02 215.26,136.02 215.01,135.76 215.01,133.73 215.39,133.35 215.77,133.35 216.03,133.1 216.03,132.21 216.15,132.08 217.04,132.08 217.42,132.46 217.42,135.89
(no net) on TOP: 196.98,78.87 194.94,78.87 194.69,78.61 194.69,76.58 195.07,76.2 195.45,76.2 195.71,75.95 195.71,75.06 195.83,74.93 196.72,74.93 197.1,75.31 197.1,78.74
(no net) on TOP: 67.18,78.61 64.9,78.61 64.26,79.25 61.47,79.25 61.34,79.38 61.34,80.77 61.47,80.9 64.14,80.9 65.41,82.17 67.18,82.17 67.44,81.92 67.44,78.87
(no net) on TOP: 29.72,99.57 27.43,99.57 26.8,100.2 24,100.2 23.88,100.33 23.88,101.73 24,101.85 26.67,101.85 27.94,103.12 29.72,103.12 29.97,102.87 29.97,99.82
(no net) on TOP: 24.13,113.03 26.16,113.03 26.42,113.28 26.42,115.32 26.03,115.7 25.65,115.7 25.4,115.95 25.4,116.84 25.27,116.97 24.38,116.97 24,116.59 24,113.16
(no net) on TOP: 214.88,138.43 217.3,138.43 217.42,138.56 217.42,140.84 217.04,141.22 209.8,141.22 208.91,140.33 208.91,131.95 208.28,131.32 205.1,131.32 204.6,130.81 204.6,129.54 204.85,129.29 206.38,129.29 207.26,128.4 212.85,128.4 215.52,131.06 215.52,132.84 215.39,132.97 215.01,132.97 214.5,133.48 214.5,134.24 214.12,134.62 211.45,134.62 210.95,135.13 210.95,138.56 211.58,139.19 214.12,139.19
(no net) on TOP: 211.71,138.68 214,138.68 214.63,138.05 217.42,138.05 217.55,137.92 217.55,136.52 217.42,136.4 214.76,136.4 213.49,135.13 211.71,135.13 211.45,135.38 211.45,138.43
(no net) on TOP: 188.09,83.82 187.83,84.07 184.4,84.07 184.02,83.69 184.02,75.82 184.28,75.57 187.71,75.57 188.09,75.95
(no net) on TOP: 191.39,81.53 193.67,81.53 194.31,80.9 197.1,80.9 197.23,80.77 197.23,79.38 197.1,79.25 194.44,79.25 193.17,77.98 191.39,77.98 191.13,78.23 191.13,81.28
(no net) on TOP: 33.4,117.22 33.02,116.84 33.02,108.84 33.4,108.46 37.59,108.46 37.97,108.84 37.97,116.84 37.59,117.22
